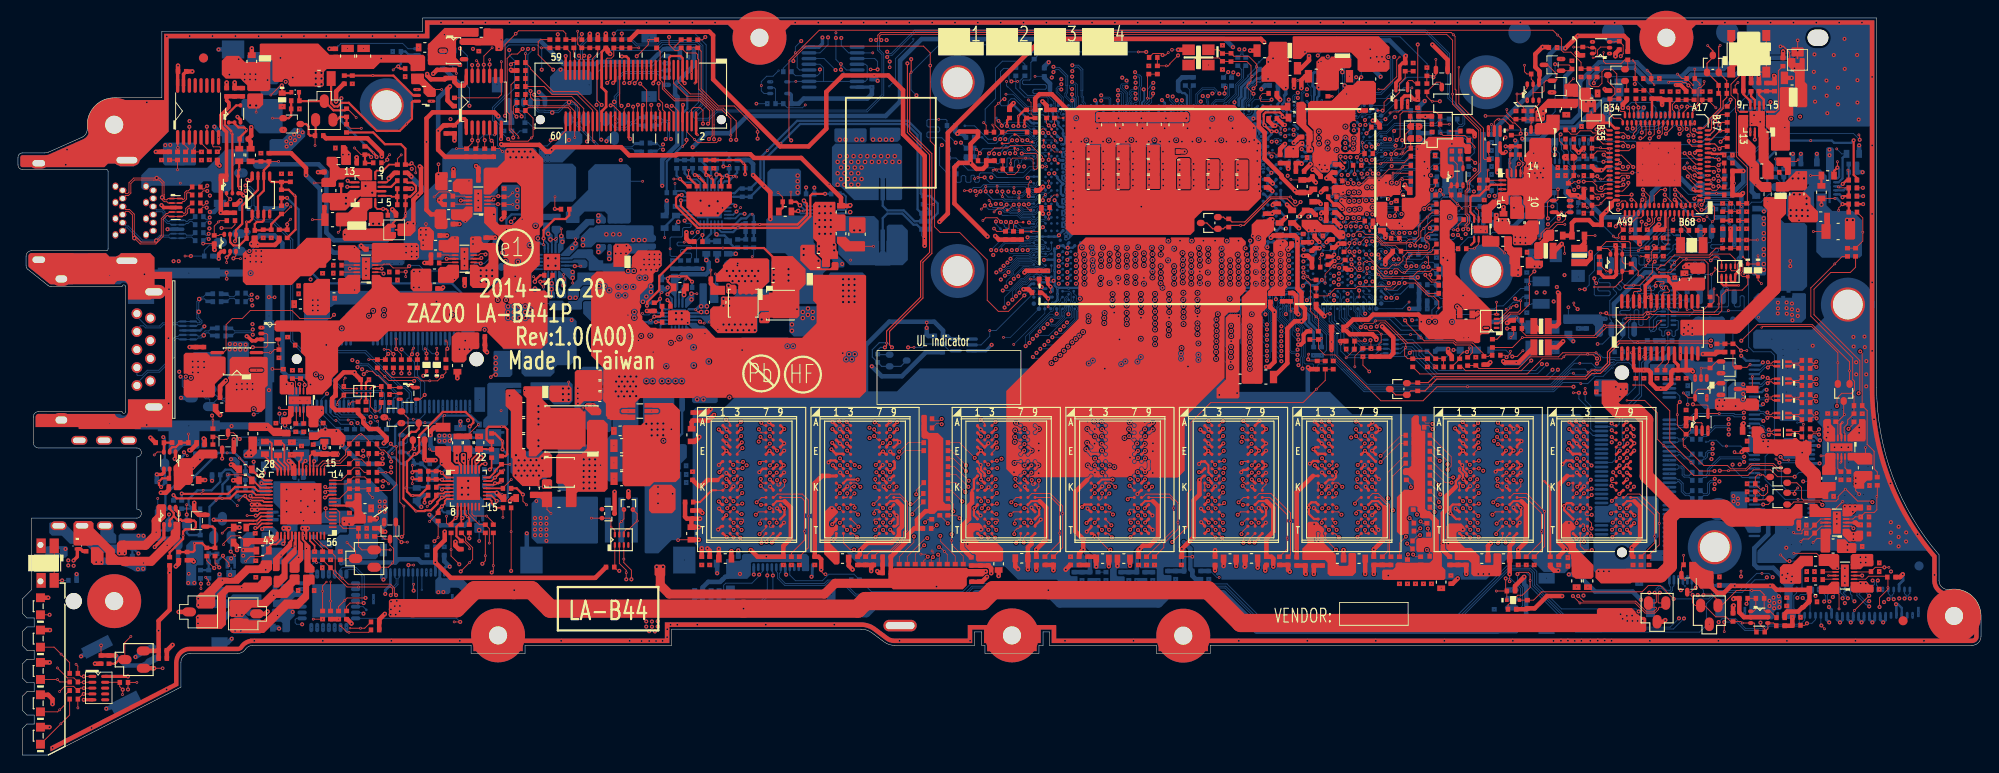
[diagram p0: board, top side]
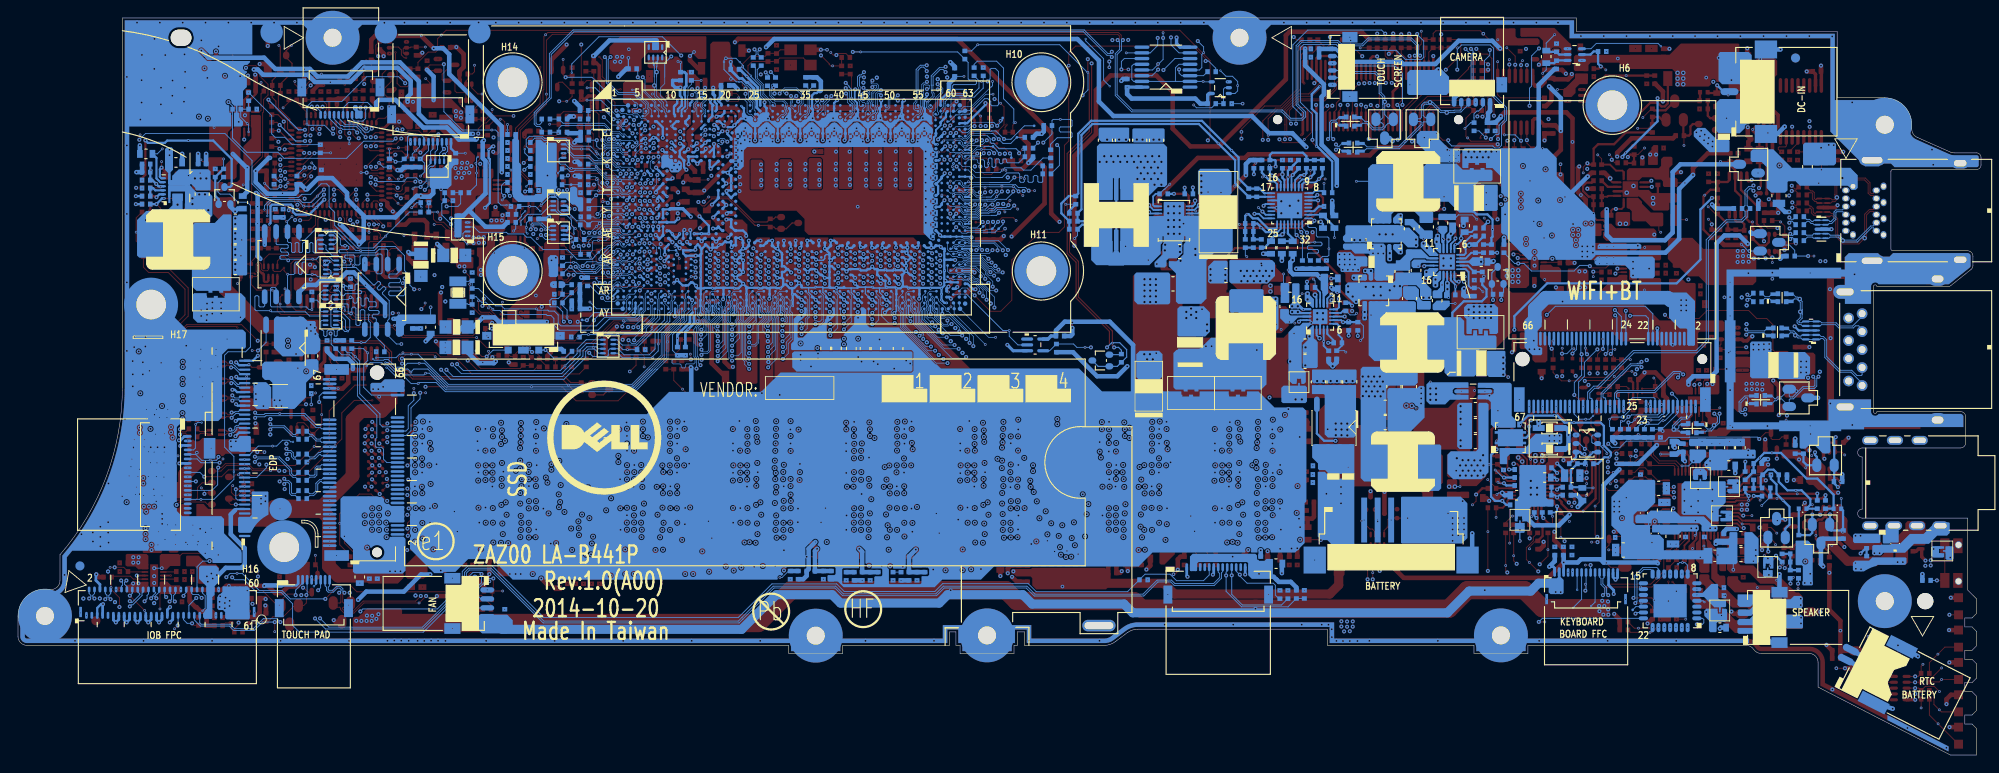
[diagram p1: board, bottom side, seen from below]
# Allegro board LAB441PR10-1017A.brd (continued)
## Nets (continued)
+1.05V_M: C219.1 CH1222.1 CH1223.1 PR319.2 R307.2 R309.2 RH39.1 RH40.1 RH445.1 UCPU1.AE9 UCPU1.AF9 UCPU1.AG8 UCPU1.AG13 UCPU1.AG14
+1.05V_PCH: C1224.1 C1228.1 C1243.1 L63.2 PJP500.2 Q360.5 R309.1 R1332.1 RH405.1 RH407.2 RH408.1 U34.1 U34.2 U673.4 U673.5 U673.9 U673.10 U673.11 U673.12 U673.13 U673.14 U673.18 U673.19
+1.05VDX_MODPHY: C1209.1 LH10.1 LH11.1 R300.1 R1240.1 R1330.2
+1.05VDX_MODPHY_D: Q39.1 R300.2
+1.05VS: C1240.1 CE50.1 CH1.1 CH39.1 CH1215.1 CH1216.1 CH1217.1 CH1233.1 CH1234.1 CH1235.1 JXDP.43 JXDP.44 LH12.1 R1331.1 R1332.2 RE70.1 RH340.1 RH355.1 RH356.1 UCPU1.AE8 UCPU1.AF22 UCPU1.AG16 UCPU1.AG17 UCPU1.H11 UCPU1.H15 UCPU1.J11 UCPU1.J17 UCPU1.N8 UCPU1.P9 UCPU1.R21 UCPU1.T21 UE5.B51
+1.5VS: PJP400.2 UCPU1.J15
+1.05VS_VCCST: CH1204.1 CH1205.1 PC717.1 PR723.1 PR726.1 PR727.1 R1132.1 R1179.1 R1371.1 RC43.1 RC48.1 RC93.2 RC149.2 RH4.1 RH340.2 UCPU1.AC22 UCPU1.AE22 UCPU1.AE23
+1.5VSP: PC402.1 PC403.1 PJP400.1 PL401.2 PR401.1 PR412.2 PU400.14
+1.05VSP: PC509.1 PC510.1 PC511.1 PC512.1 PC515.1 PJP500.1 PL501.2 PR505.1
+1.8VS: C1169.1 PJP401.2 RH350.2 U664.6 U664.7
+1.8VS_AUDIO: C1217.1 R1125.2 RA83.1
+1.8VSP: PC410.1 PC411.1 PJP401.1 PL403.2 PR406.1 PR413.2 PU401.14
+1.35V_DDR: CC160.1 CC161.1 CC162.1 CC163.1 CC164.1 CC165.1 CC233.1 CC234.1 CC238.1 CC239.1 CC240.1 CD40.1 CD41.1 CD42.1 CD44.1 CD45.1 CD46.1 CD47.1 CD50.1 CD54.1 CD55.1 CD56.1 CD57.1 CD58.1 CD59.1 CD60.1 CD61.1 CD66.1 CD67.1 CD68.1 CD69.1 CD70.1 CD71.1 CD72.1 CD73.1 CD79.1 CD80.1 CD81.1 CD82.1 CD83.1 CD84.1 CD86.1 CD92.1 PC609.1 PJP600.2 PJP601.2 RD13.1 RD14.1 RD24.2 RD34.1 RD92.2 RD95.2 UC1.5 UCPU1.AH26 UCPU1.AJ31 UCPU1.AJ33 UCPU1.AJ37 UCPU1.AN33 UCPU1.AP43 UCPU1.AR48 UCPU1.AY35 UCPU1.AY40 UCPU1.AY44 UCPU1.AY50 UD1.A1 UD1.A8 UD1.B2 UD1.C1 UD1.C9 UD1.D2 UD1.D9 UD1.E9 UD1.F1 UD1.G7 UD1.H2 UD1.H9 UD1.K2 UD1.K8 UD1.N1 UD1.N9 UD1.R1 UD1.R9 UD3.A1 UD3.A8 UD3.B2 UD3.C1 UD3.C9 UD3.D2 UD3.D9 UD3.E9 UD3.F1 UD3.G7 UD3.H2 UD3.H9 UD3.K2 UD3.K8 UD3.N1 UD3.N9 UD3.R1 UD3.R9 UD4.A1 UD4.A8 UD4.B2 UD4.C1 UD4.C9 UD4.D2 UD4.D9 UD4.E9 UD4.F1 UD4.G7 UD4.H2 UD4.H9 UD4.K2 UD4.K8 UD4.N1 UD4.N9 UD4.R1 UD4.R9 UD7.A1 UD7.A8 UD7.B2 UD7.C1 UD7.C9 UD7.D2 UD7.D9 UD7.E9 UD7.F1 UD7.G7 UD7.H2 UD7.H9 UD7.K2 UD7.K8 UD7.N1 UD7.N9 UD7.R1 UD7.R9 UD28.A1 UD28.A8 UD28.B2 UD28.C1 UD28.C9 UD28.D2 UD28.D9 UD28.E9 UD28.F1 UD28.G7 UD28.H2 UD28.H9 UD28.K2 UD28.K8 UD28.N1 UD28.N9 UD28.R1 UD28.R9 UD29.A1 UD29.A8 UD29.B2 UD29.C1 UD29.C9 UD29.D2 UD29.D9 UD29.E9 UD29.F1 UD29.G7 UD29.H2 UD29.H9 UD29.K2 UD29.K8 UD29.N1 UD29.N9 UD29.R1 UD29.R9 UD31.A1 UD31.A8 UD31.B2 UD31.C1 UD31.C9 UD31.D2 UD31.D9 UD31.E9 UD31.F1 UD31.G7 UD31.H2 UD31.H9 UD31.K2 UD31.K8 UD31.N1 UD31.N9 UD31.R1 UD31.R9 UD32.A1 UD32.A8 UD32.B2 UD32.C1 UD32.C9 UD32.D2 UD32.D9 UD32.E9 UD32.F1 UD32.G7 UD32.H2 UD32.H9 UD32.K2 UD32.K8 UD32.N1 UD32.N9 UD32.R1 UD32.R9
+1.35VP: PC617.1 PJP600.1 PJP601.1 PL601.2 PR605.2 PU600.5 PU600.19
+3.3V_ALW_DEG: JDEG1.1 RE76.2
+3.3V_M: C1219.1 CH47.1 R1322.2 R1393.1 RH55.1 RH57.1 RH3527.1 UCPU1.Y8
+3.3VDX_SSD: C719.1 C720.1 C721.1 C722.1 C1164.1 C1304.1 JNGFF3.2 JNGFF3.4 JNGFF3.12 JNGFF3.14 JNGFF3.16 JNGFF3.18 JNGFF3.62 JNGFF3.64 JNGFF3.66 R1326.2 R1376.1 R1377.2
+3V_NFC: C1134.1 JNFC1.2 JNFC1.3 JNFC1.15 R973.1 R1242.2
+3V_PCH: C1161.1 CH1220.1 CH1236.1 JAPS.1 PR510.1 R1242.1 R1312.1 R1324.1 R1342.2 RH70.2 RH72.2 RH154.2 RH197.2 RH270.2 RH294.2 RH302.2 RH341.1 RH382.2 RH465.2 RH3533.2 RH3535.2 RH3536.2 RH3537.2 RH3538.2 RH3541.2 RH3542.2 RH3546.2 RP2.5 RP2.6 RP2.7 RP2.8 RP16.5 RP16.6 RP16.7 RP21.5 RP21.6 RP21.7 RP21.8 U663.16 U697.5 UCPU1.AA9 UCPU1.AC9 UCPU1.AE20 UCPU1.AE21
+3V_PCH_DSW: C1.2 CH1224.1 RH12.1 RH146.2 RH348.2 RP20.5 RP20.6 UCPU1.AH10
+3V_ROM: CH6.1 CH7.1 CH1245.1 CH1249.1 RH3527.2 U48.8 U727.8
+3VALW: C375.1 C1158.1 C1160.1 C1162.1 C1165.1 C1166.1 C1203.1 C1204.1 C1213.1 C1231.1 C1254.1 C1256.1 C1289.1 C1322.1 CE4.1 CE42.1 JAPS.3 JAPS.7 JIO1.49 JKB1.3 PC428.1 PC429.1 PC433.1 PC434.1 PC514.1 PJP14.1 PJP15.1 PJP301.2 PR100.1 PR102.2 PR111.1 PR448.1 PR450.1 PR455.1 PR460.1 PR504.1 PR506.1 PU404.8 PU405.5 PU406.5 PU500.7 RC161.1 RE84.1 RH348.1 U664.1 U664.2 U672.5 U699.5 U715.1 U715.2 U715.6 U715.7 U716.1 U716.2 U716.6 U716.7 U717.1 U717.2 U717.6 U717.7 U718.1 U718.2 U718.6 U718.7 U720.1 U720.2 U720.6 U720.7
+3VALW_5085: CE14.1 CE17.1 CE38.1 CE40.1 CE41.1 CE43.1 CE44.1 CE46.1 CE63.1 CE64.1 PJP15.2 RE25.1 RE52.1 RE53.1 RE55.2 RE56.2 RE65.1 RE67.2 RE69.1 RE71.2 RE72.1 RE73.2 RE74.1 RE75.1 RE76.1 RE79.2 RE81.1 RE86.2 RPE5.7 RPE5.8 RPE7.5 RPE7.6 RPE7.7 RPE7.8 UE5.A11 UE5.A22 UE5.A26 UE5.A41 UE5.A52 UE5.A58 UE5.B3 UE5.B35
+3VALW_23017: CE3.1 CE10.1 PJP14.2 RE13.1 RE14.1 RE24.1 RE27.1 UE4.5
+3VALWP: PC307.1 PJP301.1 PL301.2 PR300.1 PR311.1
+3VLP: D122.2 PC300.1 PU300.3 RE57.2 UC6.5
+3VS: C377.1 C1216.1 C1283.1 C1285.1 C1300.1 C1324.1 CH1225.1 CH1226.1 CS44.1 JEDP.40 JIO1.50 JKB1.4 JLPDE1.1 JLPDE1.2 PR404.2 PR409.2 PR604.1 PR713.2 PR715.2 PU700.20 QH6.2 QH6.5 QH7.2 QH7.5 R3.1 R220.1 R884.2 R1103.2 R1141.2 R1178.2 R1185.2 R1311.1 R1329.2 R1396.2 RE83.1 RE87.2 RE88.2 RH3.2 RH5.2 RH29.2 RH35.1 RH37.1 RH91.1 RH95.1 RH100.1 RH103.1 RH107.1 RH110.1 RH180.2 RH196.2 RH198.2 RH199.2 RH200.2 RH248.1 RH271.2 RH303.2 RH354.2 RH367.1 RH383.2 RH392.1 RH393.2 RH397.1 RH424.2 RH425.2 RH440.2 RH441.2 RH457.2 RH458.2 RH459.2 RH460.2 RH466.2 RH467.2 RH3532.1 RH3534.2 RH3539.2 RH3540.2 RH3543.2 RH3545.1 RH3547.1 RH3548.2 RP4.1 RP4.2 RP4.3 RP4.4 RP14.2 RP14.3 RP20.8 RV2.2 U671.14 U675.5 U679.B2 U682.5 U683.5 U726.1 UCPU1.K14 UCPU1.K16 UCPU1.V8 UCPU1.W9 UH5.5
+3VS_AUDIO: C1218.1 CH85.1 LA14.1 R1318.2 RA14.1 RA18.1 RA19.1 RA37.1 RA38.1 RA80.2 RC9.1 RH42.1 UCPU1.AH14
+3VS_CAM: C4.1 C1220.1 C1221.1 JCAM.1 R2670.2
+3VS_CR: C1264.1 C1325.1 JEDP.7 JIO1.45 JIO1.46 JIO1.47 JIO1.48 R1343.2
+3VS_NGFF: C712.1 C713.1 C715.1 C716.1 C1215.1 C1297.1 C1298.1 JNGFF1.2 JNGFF1.4 JNGFF1.64 JNGFF1.66 R1344.2
+3VS_TP: C7.1 C1159.1 C1225.1 JTP1.1 Q40.2 R1104.2 R1105.2 R1299.1 R1323.2 RE6.1 RE7.1
+3VS_TPM: C723.1 C1137.1 C1138.1 C1139.1 C1140.1 C1141.1 C1142.1 R1393.2 U652.3 U652.10 U652.12 U652.19 U652.24
+3VS_TS: C8.1 C1208.1 R2671.2 RH357.1 U728.1 U728.3
+3VS_TSLDO: C5.1 C1222.1 C1223.1 JTS.6 RH357.2 U728.5
+5V_USB_P1: C3.1 C265.1 C303.1 JUSB1.1 US2.6 US2.7 US2.8
+5VALW: C2.1 C376.1 C962.1 C963.1 C1199.1 C1201.1 C1241.1 C1321.1 JIO1.52 JIO1.53 JIO1.54 JIO1.55 JIO1.56 JIO1.57 JIO1.58 JIO1.59 JIO1.60 JIO1.61 JKB1.1 LED10.2 LED11.2 LED12.2 LED13.2 LED14.2 PC607.2 PJP300.2 PR105.2 PR603.1 PR721.1 PU600.12 RA81.1 RP13.5 RP13.10 U34.4 U664.4 U673.2 U715.4 U716.4 U717.4 U718.4 U719.1 U719.2 U719.4 U719.6 U719.7 U720.4 US2.2 US2.3
+5VALWP: PC308.1 PJP300.1 PL304.2 PR301.1 PU300.14
+5VS: C352.1 C1102.2 CV13.1 JFAN1.4 JKB1.2 PC710.2 PU701.2 QC5.2 QV2.2 R886.2 R2669.2 UV1.16
+5VS_AUDIO: C1200.1 CA4.1 CA5.1 CA97.1 CA98.1 LA1.2 LA2.2 LA3.1 R1320.2
+AVDD1: CA101.1 CA102.1 CA103.1 LA3.2 UA2.45
+AVDD2: CA78.1 CA80.1 CA82.1 CA83.1 RA83.2 RA84.2 UA2.23 UA2.24
+DVDD: CA31.1 CA42.1 LA14.2 RA76.1 RA85.1 RA87.1 UA2.7
+DVDDIO: CA104.1 CA105.1 RA80.1 UA2.19
+PVDD1: CA2.1 CA3.1 LA1.1 UA2.46
+PVDD2: CA99.1 CA100.1 LA2.1 UA2.51
+V1.05A_AOSCSUS: CH61.1 CH1232.1 L63.1 UCPU1.AB8
+V1.05A_DCPSUS1: CH1219.1 RH407.1 UCPU1.AD8 UCPU1.AD10
+V1.05A_DCPSUS2: CH1221.1 RH408.2 UCPU1.AH13
+V1.05A_DCPSUS3: CH1214.1 CH1239.1 RH405.2 UCPU1.J13
+V1.05S_APLLOPI: CH36.1 CH1213.1 LH12.2 UCPU1.AA21 UCPU1.W21
+V1.05S_ASATA3PLL: C1314.1 C1315.1 CH1248.1 LH11.2 RH43.2 UCPU1.A12 UCPU1.B11
+V1.05S_AUSB3PLL: C1312.1 C1313.1 CH1247.1 LH10.2 RH338.1 UCPU1.B18 UCPU1.B27
+V1.05S_AXCK_DCB: CH62.1 CH1229.1 L61.2 UCPU1.J18 UCPU1.K19
+V1.05S_AXCK_DCB_L: L61.1 RH355.2
+V1.05S_AXCK_LCPLL: CH65.1 CH1231.1 L62.2 RH113.2 UCPU1.A20
+V1.05S_AXCK_LCPLL_L: L62.1 RH356.2
+V1.05VS_VCCHSIO: CH40.1 CH41.1 R1240.2 UCPU1.K9 UCPU1.L10 UCPU1.M9
+VCC_CORE: PC800.1 PC801.1 PC802.1 PC803.1 PC804.1 PC805.1 PC806.1 PC807.1 PC808.1 PC809.1 PC810.1 PC811.1 PC812.1 PC813.1 PC814.1 PC815.1 PC816.1 PC817.1 PC818.1 PC819.1 PC820.1 PC821.1 PC822.1 PC823.1 PL701.4 RC97.1 UCPU1.AB57 UCPU1.AD57 UCPU1.AG57 UCPU1.C24 UCPU1.C28 UCPU1.C32 UCPU1.C36 UCPU1.C40 UCPU1.C44 UCPU1.C48 UCPU1.C52 UCPU1.C56 UCPU1.E23 UCPU1.E25 UCPU1.E27 UCPU1.E29 UCPU1.E31 UCPU1.E33 UCPU1.E35 UCPU1.E37 UCPU1.E39 UCPU1.E41 UCPU1.E43 UCPU1.E45 UCPU1.E47 UCPU1.E49 UCPU1.E51 UCPU1.E53 UCPU1.E55 UCPU1.E57 UCPU1.F24 UCPU1.F28 UCPU1.F32 UCPU1.F36 UCPU1.F40 UCPU1.F44 UCPU1.F48 UCPU1.F52 UCPU1.F56 UCPU1.F59 UCPU1.G23 UCPU1.G25 UCPU1.G27 UCPU1.G29 UCPU1.G31 UCPU1.G33 UCPU1.G35 UCPU1.G37 UCPU1.G39 UCPU1.G41 UCPU1.G43 UCPU1.G45 UCPU1.G47 UCPU1.G49 UCPU1.G51 UCPU1.G53 UCPU1.G55 UCPU1.G57 UCPU1.H23 UCPU1.J23 UCPU1.K23 UCPU1.K57 UCPU1.L22 UCPU1.M23 UCPU1.M57 UCPU1.P57 UCPU1.U57 UCPU1.W57
+VCCIO_OUT: CH1241.1 UCPU1.A59
+VCCIOA_OUT: RC36.2 UCPU1.E20
AGND: CA40.2 CA74.2 CA78.2 CA80.2 CA82.2 CA83.2 CA84.2 CA85.2 CA86.2 CA87.2 CA88.2 CA90.2 CA91.2 CA92.2 CA93.2 CA94.2 CA101.2 CA102.2 CA103.2 JPA1.1 JPA2.1 JPA3.1 JPA4.1 JPA5.1 QA1.1 QA1.4 QA3.1 QA3.4 QA6.3 QA9.3 RA20.2 RA35.2 RA60.2 RA61.2 UA2.20 UA2.30 UA2.42
GND: C2.2 C3.2 C4.2 C5.2 C6.2 C7.2 C8.2 C218.2 C219.2 C265.2 C303.2 C352.2 C355.2 C375.2 C376.2 C377.2 C612.2 C712.2 C713.2 C715.2 C716.2 C719.2 C720.2 C721.2 C722.2 C723.2 C962.2 C963.2 C1102.1 C1134.2 C1137.2 C1138.2 C1139.2 C1140.2 C1141.2 C1142.2 C1143.2 C1145.2 C1158.2 C1159.2 C1160.2 C1161.2 C1162.2 C1163.2 C1164.2 C1165.2 C1166.2 C1167.2 C1169.2 C1199.2 C1200.2 C1201.2 C1202.2 C1203.2 C1204.2 C1208.2 C1209.2 C1211.2 C1212.2 C1213.2 C1214.2 C1215.2 C1216.2 C1217.2 C1218.2 C1219.2 C1220.2 C1221.2 C1222.2 C1223.2 C1224.2 C1225.2 C1227.2 C1228.2 C1230.2 C1231.2 C1237.2 C1240.2 C1241.2 C1242.2 C1243.2 C1247.2 C1254.2 C1256.2 C1257.2 C1258.2 C1264.2 C1273.2 C1274.2 C1275.2 C1278.2 C1281.2 C1282.2 C1283.2 C1284.2 C1285.2 C1286.2 C1289.2 C1292.2 C1293.2 C1297.2 C1298.2 C1299.2 C1300.2 C1301.2 C1302.2 C1304.2 C1309.2 C1312.2 C1313.2 C1314.2 C1315.2 C1321.2 C1322.2 C1324.2 C1325.2 C2973.2 C2982.2 C2983.2 C2985.2 CA2.2 CA3.2 CA4.2 CA5.2 CA23.1 CA24.1 CA25.1 CA26.1 CA27.1 CA28.2 CA29.1 CA31.2 CA33.2 CA42.2 CA48.2 CA49.2 CA53.1 CA54.1 CA55.1 CA56.1 CA57.2 CA68.1 CA69.2 CA97.2 CA98.2 CA99.2 CA100.2 CA104.2 CA105.2 CA106.2 CC160.2 CC161.2 CC162.2 CC163.2 CC164.2 CC165.2 CC233.2 CC234.2 CC238.2 CC239.2 CC240.2 CC243.2 CD5.2 CD35.2 CD37.2 CD40.2 CD41.2 CD42.2 CD44.2 CD45.2 CD46.2 CD47.2 CD50.2 CD51.2 CD52.2 CD54.2 CD55.2 CD56.2 CD57.2 CD58.2 CD59.2 CD60.2 CD61.2 CD66.2 CD67.2 CD68.2 CD69.2 CD70.2 CD71.2 CD72.2 CD73.2 CD77.2 CD78.2 CD79.2 CD80.2 CD81.2 CD82.2 CD83.2 CD84.2 CD85.2 CD86.2 CD87.2 CD88.2 CD89.2 CD90.2 CD91.2 CD92.2 CD93.2 CD94.2 CD95.2 CD96.2 CD101.2 CD129.2 CD132.2 CD133.2 CD135.2 CD136.2 CD139.2 CD140.2 CD142.2 CD143.2 CD144.2 CE3.2 CE4.2 CE10.2 CE13.2 CE14.2 CE17.2 CE21.2 CE22.2 CE38.2 CE40.2 CE41.2 CE42.2 CE43.2 CE44.2 CE45.2 CE46.2 CE49.2 CE50.2 CE52.2 CE53.2 CE54.2 CE55.2 CE56.2 CE59.2 CE61.2 CE62.2 CE63.2 CE64.2 CE65.2 CE68.2 CH1.2 CH2.2 CH3.2 CH4.2 CH5.2 CH6.2 CH7.2 CH23.2 CH24.2 CH36.2 CH39.2 CH40.2 CH41.2 CH47.2 CH61.2 CH62.2 CH65.2 CH82.2 CH83.2 CH84.2 CH85.2 CH95.2 CH102.1 CH1204.2 CH1205.2 CH1206.2 CH1207.2 CH1213.2 CH1214.2 CH1215.2 CH1216.2 CH1217.2 CH1218.2 CH1219.2 CH1220.2 CH1221.2 CH1222.2 CH1223.2 CH1224.2 CH1225.2 CH1226.2 CH1227.2 CH1229.2 CH1231.2 CH1232.2 CH1233.2 CH1234.2 CH1235.2 CH1236.2 CH1239.2 CH1241.2 CH1242.2 CH1243.2 CH1244.2 CH1245.2 CH1246.2 CH1247.2 CH1248.2 CH1249.2 CLRP1.2 CS44.2 CV1.2 CV2.2 CV13.2 CV14.2 CV15.2 CV798.2 DA1.1 DA2.1 DA3.1 DA4.1 DA5.2 DA7.2 DI1.3 DI1.8 DI2.1 DI3.1 DI4.1 H1.1(TP-1) H4.1(TP-1) H6.1(TP-1) H7.1(TP-1) H9.1(TP-1) H10.1(TP-1) H11.1(TP-1) H12.1(TP-1) H13.1(TP-1) H14.1(TP-1) H15.1(TP-1) H16.1(TP-1) H17.1(TP-1) H18.1(TP-1) H19.1(TP-1) H20.1 H21.1 H22.1 H24.1 H25.1 JAPS.8 JAPS.10 JAPS.12 JAPS.14 JAPS.19 JAPS.20 JBATT1.6 JBATT1.7 JBATT1.8 JBATT1.9 JBATT1.10 JBATT1.11 JCAM.3 JCAM.6 JCAM.7 JCAM.8 JDEG1.10 JDEG1.11 JDEG1.12 JEDP.10 JEDP.11 JEDP.12 JEDP.13 JEDP.15 JEDP.16 JEDP.17 JEDP.18 JEDP.24 JEDP.27 JEDP.30 JEDP.33 JEDP.36 JEDP.39 JEDP.41 JEDP.42 JEDP.43 JEDP.44 JEDP.45 JFAN1.1 JFAN1.5 JFAN1.6 JHP1.7 JIO1.1 JIO1.5 JIO1.6 JIO1.7 JIO1.11 JIO1.12 JIO1.13 JIO1.15 JIO1.17 JIO1.19 JIO1.21 JIO1.23 JIO1.25 JIO1.27 JIO1.29 JIO1.31 JIO1.33 JIO1.62 JIO1.63 JKB1.13 JKB1.14 JKB1.15 JKB1.16 JKB1.17 JLPDE1.9 JLPDE1.11 JLPDE1.12 JMDP.1 JMDP.7 JMDP.8 JMDP.13 JMDP.14 JMDP.19 JMDP.21 JMDP.22 JMDP.23 JMDP.24 JNFC1.1 JNFC1.7 JNFC1.14 JNFC1.16 JNFC1.17 JNGFF1.1 JNGFF1.7 JNGFF1.18 JNGFF1.25 JNGFF1.31 JNGFF1.37 JNGFF1.43 JNGFF1.49 JNGFF1.55 JNGFF1.61 JNGFF1.67 JNGFF1.68 JNGFF1.69 JNGFF3.1 JNGFF3.3 JNGFF3.9 JNGFF3.15 JNGFF3.21 JNGFF3.27 JNGFF3.33 JNGFF3.39 JNGFF3.45 JNGFF3.51 JNGFF3.57 JNGFF3.63 JNGFF3.65 JNGFF3.67 JNGFF3.68 JNGFF3.69 JP100.6 JP100.7 JPA1.2 JPA2.2 JPA3.2 JPA4.2 JPA5.2 JRTC1.2 JRTC1.3 JRTC1.4 JSPK1.5 JSPK1.6 JTAG1.2 JTP1.4 JTP1.9 JTP1.10 JTS.1 JTS.4 JTS.7 JTS.8 JUSB1.4 JUSB1.7 JUSB1.10 JUSB1.11 JUSB1.12 JUSB1.13 JXDP.1 JXDP.2 JXDP.7 JXDP.8 JXDP.13 JXDP.14 JXDP.19 JXDP.20 JXDP.25 JXDP.26 JXDP.31 JXDP.32 JXDP.37 JXDP.38 JXDP.49 JXDP.50 JXDP.59 MC3.2 MC29.1 MC30.2 MC31.2 MC32.2 MC33.2 MD5.3 MD9.1 MD10.1 MD16.3 PC100.2 PC101.2 PC102.1 PC103.2 PC106.2 PC107.2 PC108.2 PC110.2 PC205.2 PC206.2 PC208.2 PC209.2 PC211.2 PC212.2 PC213.2 PC214.2 PC215.2 PC219.2 PC220.2 PC221.2 PC222.2 PC224.2 PC228.2 PC229.2 PC230.2 PC231.2 PC232.2 PC233.2 PC234.2 PC235.2 PC236.2 PC237.2 PC300.2 PC302.2 PC303.2 PC307.2 PC308.2 PC309.2 PC310.2 PC311.2 PC312.2 PC313.2 PC314.2 PC315.2 PC323.2 PC324.1 PC400.2 PC401.2 PC403.2 PC404.2 PC405.2 PC406.2 PC407.2 PC408.2 PC409.2 PC411.2 PC412.2 PC413.2 PC414.2 PC415.2 PC428.2 PC429.2 PC433.2 PC434.2 PC500.2 PC502.2 PC503.2 PC504.2 PC506.2 PC507.2 PC509.2 PC510.2 PC511.2 PC512.2 PC513.2 PC514.2 PC600.2 PC601.2 PC602.2 PC603.2 PC605.2 PC606.2 PC607.1 PC609.2 PC610.2 PC611.2 PC612.2 PC613.2 PC614.2 PC617.2 PC700.2 PC701.2 PC702.2 PC703.2 PC704.2 PC705.2 PC706.2 PC708.2 PC710.1 PC711.2 PC713.2 PC714.2 PC717.2 PC718.2 PC800.2 PC801.2 PC802.2 PC803.2 PC804.2 PC805.2 PC806.2 PC807.2 PC808.2 PC809.2 PC810.2 PC811.2 PC812.2 PC813.2 PC814.2 PC815.2 PC816.2 PC817.2 PC818.2 PC819.2 PC820.2 PC821.2 PC822.2 PC823.2 PD100.1 PD101.1 PD102.2 PJP200.2 PL104.2 PQ101.3 PQ102.1 PQ102.4 PQ103.1 PQ103.4 PQ202.6 PQ205.1 PQ205.2 PQ205.3 PQ300.8 PQ301.8 PQ409.1 PQ500.3 PQ601.1 PQ601.2 PQ601.3 PR106.1 PR107.2 PR112.2 PR113.2 PR116.2 PR302.1 PR303.2 PR304.1 PR305.1 PR306.2 PR403.2 PR408.2 PR451.2 PR452.2 PR456.2 PR458.2 PR501.2 PR507.2 PR508.2 PR607.2 PR705.2 PR706.2 PR707.2 PR708.2 PR709.2 PR710.2 PR731.2 PU200.22 PU300.21 PU400.6 PU400.8 PU400.15 PU400.16 PU400.17 PU401.6 PU401.8 PU401.15 PU401.16 PU401.17 PU404.4 PU405.3 PU406.3 PU500.9 PU600.1 PU600.3 PU600.14 PU600.21 PU700.19 PU700.29 PU700.33 PU701.3 PU701.9 Q39.3 Q71.3 Q305.3 Q361.1 Q362.3 QA8.3 QE12.1 QE12.4 R7.2 R8.1 R9.1 R290.1 R540.2 R545.2 R974.2 R1026.1 R1100.1 R1140.2 R1142.2 R1161.2 R1162.2 R1163.2 R1169.2 R1175.1 R1176.2 R1177.2 R1181.2 R1186.1 R1187.1 R1203.2 R1216.2 R1228.2 R1325.2 R1395.1 RA30.2 RA41.2 RA82.1 RC44.1 RC52.1 RC54.1 RC55.1 RC58.1 RC60.1 RC81.2 RC100.2 RC153.2 RC154.2 RC155.2 RC156.2 RC158.1 RC160.2 RD11.2 RD12.2 RD16.2 RD17.2 RD18.2 RD19.2 RD29.2 RD30.2 RD31.2 RD32.2 RD39.2 RD40.2 RD41.2 RD42.2 RD51.2 RD52.2 RD53.2 RD54.2 RD55.2 RD56.2 RD119.2 RD120.2 RE2.1 RE22.1 RE23.1 RE54.1 RE58.1 RE59.2 RE60.2 RE63.2 RE66.2 RE68.2 RE77.2 RE78.2 RE82.1 RE85.2 RH34.2 RH36.1 RH41.1 RH44.1 RH45.1 RH159.1 RH163.2 RH171.2 RH183.1 RH300.1 RH314.1 RH315.1 RH316.1 RH394.1 RH395.1 RH400.2 RH401.2 RH423.2 RH435.2 RH442.2 RH443.2 RH3530.2 RH3531.2 RH3544.1 RH3549.2 RV3.2 RV4.2 RV9.2 RV10.2 SW2.1 SW2.3 SW3.3 SW3.4 SW4.4 SW4.5 U34.5 U34.9 U48.4 U652.1 U652.2 U652.4 U652.11 U652.17 U652.18 U652.25 U663.8 U664.11 U664.15 U671.7 U672.3 U673.3 U675.3 U679.B1 U682.3 U683.3 U697.3 U699.3 U708.3 U715.11 U715.15 U716.11 U716.15 U717.11 U717.15 U718.11 U718.15 U719.11 U719.15 U720.11 U720.15 U726.2 U727.4 U728.2 UA2.10 UA2.57 UC1.3 UC6.3 UCPU1.A11 UCPU1.A14 UCPU1.A18 UCPU1.A24 UCPU1.A28 UCPU1.A32 UCPU1.A36 UCPU1.A40 UCPU1.A44 UCPU1.A48 UCPU1.A52 UCPU1.A56 UCPU1.AA1 UCPU1.AA58 UCPU1.AB7 UCPU1.AB10 UCPU1.AB20 UCPU1.AB22 UCPU1.AC61 UCPU1.AD3 UCPU1.AD21 UCPU1.AD63 UCPU1.AE5 UCPU1.AE10 UCPU1.AE58 UCPU1.AF11 UCPU1.AF12 UCPU1.AF14 UCPU1.AF15 UCPU1.AF17 UCPU1.AF18 UCPU1.AG1 UCPU1.AG11 UCPU1.AG21 UCPU1.AG23 UCPU1.AG60 UCPU1.AG61 UCPU1.AG62 UCPU1.AG63 UCPU1.AH16 UCPU1.AH17 UCPU1.AH19 UCPU1.AH20 UCPU1.AH22 UCPU1.AH24 UCPU1.AH28 UCPU1.AH30 UCPU1.AH32 UCPU1.AH34 UCPU1.AH36 UCPU1.AH38 UCPU1.AH40 UCPU1.AH42 UCPU1.AH44 UCPU1.AH46 UCPU1.AH49 UCPU1.AH51 UCPU1.AH53 UCPU1.AH55 UCPU1.AH57 UCPU1.AJ13 UCPU1.AJ14 UCPU1.AJ23 UCPU1.AJ25 UCPU1.AJ27 UCPU1.AJ29 UCPU1.AJ35 UCPU1.AJ39 UCPU1.AJ41 UCPU1.AJ43 UCPU1.AJ45 UCPU1.AJ47 UCPU1.AJ50 UCPU1.AJ52 UCPU1.AJ54 UCPU1.AJ56 UCPU1.AJ58 UCPU1.AJ60 UCPU1.AJ63 UCPU1.AK3 UCPU1.AK23 UCPU1.AK52 UCPU1.AL10 UCPU1.AL13 UCPU1.AL17 UCPU1.AL20 UCPU1.AL22 UCPU1.AL23 UCPU1.AL26 UCPU1.AL29 UCPU1.AL31 UCPU1.AL33 UCPU1.AL36 UCPU1.AL39 UCPU1.AL40 UCPU1.AL45 UCPU1.AL46 UCPU1.AL51 UCPU1.AL52 UCPU1.AL54 UCPU1.AL57 UCPU1.AL60 UCPU1.AL61 UCPU1.AM1 UCPU1.AM17 UCPU1.AM23 UCPU1.AM31 UCPU1.AM52 UCPU1.AN7 UCPU1.AN17 UCPU1.AN23 UCPU1.AN31 UCPU1.AN32 UCPU1.AN35 UCPU1.AN36 UCPU1.AN39 UCPU1.AN40 UCPU1.AN42 UCPU1.AN43 UCPU1.AN45 UCPU1.AN46 UCPU1.AN48 UCPU1.AN49 UCPU1.AN51 UCPU1.AN52 UCPU1.AN60 UCPU1.AN63 UCPU1.AP3 UCPU1.AP10 UCPU1.AP17 UCPU1.AP20 UCPU1.AP22 UCPU1.AP23 UCPU1.AP26 UCPU1.AP29 UCPU1.AP31 UCPU1.AP38 UCPU1.AP39 UCPU1.AP48 UCPU1.AP52 UCPU1.AP54 UCPU1.AP57 UCPU1.AR5 UCPU1.AR11 UCPU1.AR15 UCPU1.AR17 UCPU1.AR23 UCPU1.AR31 UCPU1.AR33 UCPU1.AR39 UCPU1.AR43 UCPU1.AR49 UCPU1.AR52 UCPU1.AT13 UCPU1.AT35 UCPU1.AT37 UCPU1.AT40 UCPU1.AT42 UCPU1.AT43 UCPU1.AT46 UCPU1.AT49 UCPU1.AT61 UCPU1.AT62 UCPU1.AT63 UCPU1.AU1 UCPU1.AU16 UCPU1.AU18 UCPU1.AU20 UCPU1.AU22 UCPU1.AU24 UCPU1.AU26 UCPU1.AU28 UCPU1.AU30 UCPU1.AU33 UCPU1.AU51 UCPU1.AU53 UCPU1.AU55 UCPU1.AU57 UCPU1.AU59 UCPU1.AV8 UCPU1.AV14 UCPU1.AV16 UCPU1.AV20 UCPU1.AV24 UCPU1.AV28 UCPU1.AV33 UCPU1.AV34 UCPU1.AV36 UCPU1.AV39 UCPU1.AV41 UCPU1.AV43 UCPU1.AV46 UCPU1.AV49 UCPU1.AV51 UCPU1.AV55 UCPU1.AV59 UCPU1.AW4 UCPU1.AW16 UCPU1.AW24 UCPU1.AW33 UCPU1.AW35 UCPU1.AW37 UCPU1.AW40 UCPU1.AW42 UCPU1.AW44 UCPU1.AW47 UCPU1.AW50 UCPU1.AW51 UCPU1.AW59 UCPU1.AW60 UCPU1.AY4 UCPU1.AY6 UCPU1.AY11 UCPU1.AY16 UCPU1.AY18 UCPU1.AY22 UCPU1.AY24 UCPU1.AY26 UCPU1.AY30 UCPU1.AY33 UCPU1.AY51 UCPU1.AY53 UCPU1.AY57 UCPU1.AY59 UCPU1.B4 UCPU1.B20 UCPU1.B24 UCPU1.B26 UCPU1.B28 UCPU1.B32 UCPU1.B36 UCPU1.B40 UCPU1.B44 UCPU1.B48 UCPU1.B52 UCPU1.B56 UCPU1.B60 UCPU1.C11 UCPU1.C14 UCPU1.C18 UCPU1.C20 UCPU1.C25 UCPU1.C27 UCPU1.C38 UCPU1.C39 UCPU1.C57 UCPU1.D2 UCPU1.D5 UCPU1.D8 UCPU1.D12 UCPU1.D14 UCPU1.D18 UCPU1.D21 UCPU1.D23 UCPU1.D25 UCPU1.D26 UCPU1.D27 UCPU1.D29 UCPU1.D30 UCPU1.D31 UCPU1.D33 UCPU1.D34 UCPU1.D35 UCPU1.D37 UCPU1.D38 UCPU1.D39 UCPU1.D41 UCPU1.D42 UCPU1.D43 UCPU1.D45 UCPU1.D46 UCPU1.D47 UCPU1.D49 UCPU1.D50 UCPU1.D51 UCPU1.D53 UCPU1.D54 UCPU1.D55 UCPU1.D57 UCPU1.D59 UCPU1.D62 UCPU1.D63 UCPU1.E11 UCPU1.E17 UCPU1.F20 UCPU1.F26 UCPU1.F30 UCPU1.F34 UCPU1.F38 UCPU1.F42 UCPU1.F46 UCPU1.F50 UCPU1.F54 UCPU1.F58 UCPU1.F61 UCPU1.G3 UCPU1.G5 UCPU1.G6 UCPU1.G8 UCPU1.G18 UCPU1.G22 UCPU1.H13 UCPU1.H17 UCPU1.H57 UCPU1.J10 UCPU1.J22 UCPU1.J59 UCPU1.J63 UCPU1.K1 UCPU1.K12 UCPU1.L7 UCPU1.L13 UCPU1.L15 UCPU1.L17 UCPU1.L18 UCPU1.L20 UCPU1.L58 UCPU1.L61 UCPU1.M22 UCPU1.N3 UCPU1.N10 UCPU1.N21 UCPU1.P22 UCPU1.P59 UCPU1.P62 UCPU1.P63 UCPU1.R8 UCPU1.R10 UCPU1.R22 UCPU1.T1 UCPU1.T58 UCPU1.U9 UCPU1.U20 UCPU1.U22 UCPU1.U61 UCPU1.V3 UCPU1.V7 UCPU1.V10 UCPU1.V23 UCPU1.V58 UCPU1.W20 UCPU1.W22 UCPU1.Y10 UCPU1.Y59 UCPU1.Y63 UD1.A9 UD1.B1 UD1.B3 UD1.B9 UD1.D1 UD1.D3 UD1.D8 UD1.E1 UD1.E2 UD1.E7 UD1.E8 UD1.F9 UD1.G1 UD1.G8 UD1.G9 UD1.J2 UD1.J8 UD1.M1 UD1.M9 UD1.P1 UD1.P9 UD1.T1 UD1.T9 UD3.A9 UD3.B1 UD3.B3 UD3.B9 UD3.D1 UD3.D3 UD3.D8 UD3.E1 UD3.E2 UD3.E7 UD3.E8 UD3.F9 UD3.G1 UD3.G8 UD3.G9 UD3.J2 UD3.J8 UD3.M1 UD3.M9 UD3.P1 UD3.P9 UD3.T1 UD3.T9 UD4.A9 UD4.B1 UD4.B3 UD4.B9 UD4.D1 UD4.D3 UD4.D8 UD4.E1 UD4.E2 UD4.E7 UD4.E8 UD4.F9 UD4.G1 UD4.G8 UD4.G9 UD4.J2 UD4.J8 UD4.M1 UD4.M9 UD4.P1 UD4.P9 UD4.T1 UD4.T9 UD7.A9 UD7.B1 UD7.B3 UD7.B9 UD7.D1 UD7.D3 UD7.D8 UD7.E1 UD7.E2 UD7.E7 UD7.E8 UD7.F9 UD7.G1 UD7.G8 UD7.G9 UD7.J2 UD7.J8 UD7.M1 UD7.M9 UD7.P1 UD7.P9 UD7.T1 UD7.T9 UD28.A9 UD28.B1 UD28.B3 UD28.B9 UD28.D1 UD28.D3 UD28.D8 UD28.E1 UD28.E2 UD28.E7 UD28.E8 UD28.F9 UD28.G1 UD28.G8 UD28.G9 UD28.J2 UD28.J8 UD28.M1 UD28.M9 UD28.P1 UD28.P9 UD28.T1 UD28.T9 UD29.A9 UD29.B1 UD29.B3 UD29.B9 UD29.D1 UD29.D3 UD29.D8 UD29.E1 UD29.E2 UD29.E7 UD29.E8 UD29.F9 UD29.G1 UD29.G8 UD29.G9 UD29.J2 UD29.J8 UD29.M1 UD29.M9 UD29.P1 UD29.P9 UD29.T1 UD29.T9 UD31.A9 UD31.B1 UD31.B3 UD31.B9 UD31.D1 UD31.D3 UD31.D8 UD31.E1 UD31.E2 UD31.E7 UD31.E8 UD31.F9 UD31.G1 UD31.G8 UD31.G9 UD31.J2 UD31.J8 UD31.M1 UD31.M9 UD31.P1 UD31.P9 UD31.T1 UD31.T9 UD32.A9 UD32.B1 UD32.B3 UD32.B9 UD32.D1 UD32.D3 UD32.D8 UD32.E1 UD32.E2 UD32.E7 UD32.E8 UD32.F9 UD32.G1 UD32.G8 UD32.G9 UD32.J2 UD32.J8 UD32.M1 UD32.M9 UD32.P1 UD32.P9 UD32.T1 UD32.T9 UE4.6 UE5.B11 UE5.B18 UE5.B54 UE5.B60 UE5.B66 UE5.C1 UH5.3 US2.1 UV1.8 UV1.15 YH2.2 YH2.4
GNDA_CHG: PC202.1 PC204.2 PC207.1 PC216.1 PC217.1 PC218.1 PC223.2 PC225.1 PC227.2 PJP200.1 PQ206.3 PR210.2 PR215.2 PR225.2 PR229.2 PU200.29
VCCSENSE: PU700.24 RC98.1
VCCSENSE_R: RC97.2 RC98.2 UCPU1.E63
VDD_1.35V: PC611.1 PR601.1 PR603.2 PU600.11
VSSSENSE: PU700.23 RC100.1 UCPU1.E62
+DC_IN: PC106.1 PC107.1 PC108.1 PC200.1 PD201.2 PL103.2 PQ201.1 PR107.1 PR108.1 PR109.1 PR110.1 PR114.1 PR209.2
+DCIN: PC206.1 PR207.2 PU200.28
+DCIN_JACK: JP100.4 JP100.5 PC103.1 PC104.1 PC105.1 PL103.1
+DP_PWR: CV1.1 CV2.1 CV14.1 CV15.1 JMDP.20 U726.3
+INV_PWR_SRC: C612.1 C2982.1 C2985.1 JEDP.2 JEDP.3 JEDP.4 JEDP.5 Q70.5 Q70.6 Q70.7 Q70.8 R531.2 R541.1
+LCDVDD: C6.1 C1143.1 C1145.1 C1211.1 JEDP.20 JEDP.21 JEDP.22 JEDP.23 R1321.2 U708.5
+LDO2: CA88.1 CA90.1 RA84.1 UA2.22
+MD_VREF_CA: CD85.1 CD87.1 CD88.1 CD89.1 CD90.1 CD91.1 CD95.1 CD96.1 RD13.2 RD15.1 RD16.1 UD1.M8 UD3.M8 UD4.M8 UD7.M8 UD28.M8 UD29.M8 UD31.M8 UD32.M8
+MD_VREF_DQA: CD77.1 CD78.1 CD93.1 CD94.1 RD34.2 RD119.1 RD121.1 UD28.H1 UD29.H1 UD31.H1 UD32.H1
+MD_VREF_DQB: CD35.1 CD37.1 CD51.1 CD52.1 RD14.2 RD18.1 RD20.1 UD1.H1 UD3.H1 UD4.H1 UD7.H1
+PBATT: PC100.1 PD200.2 PL100.1 PL101.1 PQ204.5 PQ204.6 PQ204.7 PQ204.8 PR222.2
+PCH_VCCDSW: C1.1 RH346.1 UCPU1.AG19 UCPU1.AG20
+PWR_SRC_AC: PL200.1 PR202.1
+RTC_CELL_VBAT: CE65.1 RE32.2 UE5.B64
+RTC_VCCSUS: CH1207.1 RH341.2 UCPU1.AH11
+RTCBATT: C2973.1 JRTC1.1 RTCR1.2
+RTCVCC: C1309.1 CH82.1 CH83.1 CH84.1 CH95.1 D122.3 RA16.1 RE31.1 RE32.1 RE36.1 RH11.1 RH23.1 RH25.1 RH31.1 RH147.1 RPE5.5 RPE5.6 UCPU1.AG10
+SDC_IN: PQ201.3 PR202.4
+VCHGR: PC219.1 PC220.1 PC221.1 PC222.1 PC235.1 PC236.1 PC237.1 PQ204.1 PQ204.2 PQ204.3 PR219.1
+VR_CAP: CE45.1 UE5.B12
+VS_LPSS_SDIO: C1284.1 C1286.1 C1299.1 CH1227.1 R1131.2 R1188.2 R1327.1 R1328.1 R1360.1 R1361.1 R1362.1 R1363.1 R1364.1 R1365.1 R1372.1 R1373.1 R1374.1 R1375.1 RH350.1 RH354.1 RH434.1 U671.1 U679.C1 UCPU1.T9 UCPU1.U8
-DCIN_JACK: JP100.1 JP100.2 PC104.2 PC105.2 PL104.1
A_ON: R270.1 UE5.A4
AC_DIS: PQ202.5 PQ206.2 UE5.A10
AC_PRESENT: RH12.2 RH137.2 UE5.A54
AC_PRESENT_R: RH137.1 UCPU1.AJ8
ACAV_IN: PR213.1 R268.1 UE5.A64
ACAV_IN_NB: R268.2 UE5.B20
ALS_INT#: JIO1.37 R3.2 UE5.B48
ALS_SMLCLK: JIO1.40 QH6.1 RE87.1 RH453.2
ALS_SMLDATA: JIO1.43 QH6.4 RE88.1 RH454.2
ALW_PWRGD_3V_5V: PR312.1 UE5.A1
ALWON: PR314.1 UE5.A60
AUD_HP_NB_SENSE: RA29.2 UE5.B2
AUDIO_VREF: CA86.1 CA87.1 UA2.43
AUX_EN_WOWL: D116.3 UE5.B53
B+: C613.1 C1273.1 C1274.1 C1275.1 PC214.1 PC215.1 PC228.1 PC229.1 PC230.1 PC233.1 PC234.1 PL201.2 PL300.1 PL303.1 PL400.1 PL402.1 PL500.1 PL600.1 PR219.4 PR732.1 Q70.1 Q70.2 Q70.3 Q361.4 R531.1 R535.1 R1381.1
B+_1.05V: PC503.1 PC504.1 PC506.1 PC507.1 PL500.2 PU500.8
B-RAMP: PR702.2 PR707.1 PU700.11
BAT1_LED#: JKB1.10 UE5.B1
BAT2_LED#: JKB1.9 UE5.A55
BAT_LED#_LV1: LED12.1 R910.2
BAT_LED#_LV2: LED14.1 R911.2
BAT_LED#_LV3: LED10.1 R912.2
BAT_LED#_LV4: LED11.1 R913.2
BAT_LED#_LV5: LED13.1 R916.2
BATBTN#: C2983.1 RPE5.4 SW3.1 SW3.2 UE5.A63
BATDRV#: PQ204.4 PR220.2
BATT_LED#_LV1: R910.1 RP13.9 UE4.25
BATT_LED#_LV2: R911.1 RP13.1 UE4.26
BATT_LED#_LV3: R912.1 RP13.2 UE4.27
BATT_LED#_LV4: R913.1 RP13.3 UE4.28
BATT_LED#_LV5: R916.1 RP13.4 UE4.1
BATT_PRS: JBATT1.5 PD100.3 PRP100.8
BATT_VREF: PC324.2 PR458.1 PR460.2 PU404.2 PU404.6
BBS_BIT: T284.1(TP-1) UCPU1.L8
BC_CLK_ECE1117: JKB1.8 UE5.A20
BC_DAT_ECE1117: JKB1.7 RPE5.1 UE5.B21
BC_INT#_ECE1117: JKB1.6 UE5.A19
BEEP: RA24.1 UE5.B24
BIA_PWM_EC: D73.3 UE5.B25
BOARD_ID: CE54.1 RE79.1 UE5.B10
BOOT_1.35V: PR600.2 PU600.18
BQ24777_REGN: PC205.1 PR212.1 PR223.1 PR228.2 PU200.24
BST_1.05V: PR503.1 PU500.6
BST_1.35V: PC604.1 PR600.1
BST_3V: PR307.2 PU300.9
BST_5V: PR308.1 PU300.17
BT_CS_NOTICE: R1208.2 R1209.2 UCPU1.AD5
BT_RADIO_DIS#: DZ2.1 RE13.2 UE4.23
BT_RADIO_DIS#_R: DZ2.2 JNGFF1.46
CAB_DET_SINK: JMDP.4 RV8.2 RV9.1
CAM_CBL_DET#: RH438.1 RH3541.1 UCPU1.AK4
CAM_CBL_DET#_R: JCAM.2 RH438.2
CFG0: JXDP.9 UCPU1.AC60
CFG1: JXDP.11 UCPU1.AC62
CFG2: JXDP.15 UCPU1.AC63
CFG3: JXDP.17 R1198.2 T293.1(TP-1) UCPU1.AA63
CFG4: JXDP.27 RC81.1 UCPU1.AA60
CFG5: JXDP.29 UCPU1.Y62
CFG6: JXDP.33 UCPU1.Y61
CFG7: JXDP.35 UCPU1.Y60
CFG8: JXDP.10 UCPU1.V62
CFG9: JXDP.12 UCPU1.V61
CFG10: JXDP.16 UCPU1.V60
CFG11: JXDP.18 UCPU1.U60
CFG12: JXDP.28 UCPU1.T63
CFG13: JXDP.30 UCPU1.T62
CFG14: JXDP.34 UCPU1.T61
CFG15: JXDP.36 UCPU1.T60
CFG16: JXDP.6 UCPU1.AA62
CFG17: JXDP.4 UCPU1.AA61
CFG18: JXDP.24 UCPU1.U63
CFG19: JXDP.22 UCPU1.U62
CFG_RCOMP: RC153.1 UCPU1.V63
CHAGER_SRC: PC208.1 PC209.1 PC211.1 PC212.1 PC213.1 PC231.1 PC232.1 PL200.2 PQ203.5
CHARGER_SMBCLK: PR227.1 QH6.6 RE56.1 RH453.1 UE5.B50
CHARGER_SMBDAT: PR226.1 QH6.3 RE55.1 RH454.1 UE5.A47
CHG_BTS: PR211.1 PU200.25
CHG_BTS_C: PC210.1 PR211.2
CHG_LGATE: PQ205.4 PU200.23
CHG_SW: PC210.2 PL201.1 PQ203.1 PQ203.2 PQ203.3 PQ205.5 PR221.1 PU200.27
CHG_UGATE: PQ203.4 PU200.26
CL_CK: R1212.2 UCPU1.AF2
CL_DAT: R1210.2 UCPU1.AD2
CL_RST#: R1200.2 UCPU1.AF4
CLK_LPC_DEBUG: CH1244.1 JLPDE1.10 RH428.2
CLK_PCI_MEC: CH1243.1 RE80.1 RH360.2 UE5.A29
CLK_PCIE_MMI: JIO1.20 UCPU1.C42
CLK_PCIE_MMI#: JIO1.22 UCPU1.C43
CLK_PCIE_MSATA: JNGFF3.55 UCPU1.A37
CLK_PCIE_MSATA#: JNGFF3.53 UCPU1.B37
CLK_PCIE_WLAN: C1302.1 JNGFF1.39 UCPU1.C37
CLK_PCIE_WLAN#: C1301.1 JNGFF1.41 UCPU1.B38
CLK_SMB: JBATT1.3 PD101.3 PRP100.6
CLK_TP_SIO: JTP1.8 MD9.3 RE6.2 UE5.A37
CLKOUT_LPC0: RH360.1 UCPU1.AN15
CLKOUT_LPC1: RH428.1 UCPU1.AP15
CLKRUN#: RH248.2 UCPU1.V5 UE5.A32
CODEC_GPIO6: RA32.1 UA2.3
CODEC_IRQ: RA86.1 RH3532.2 UCPU1.L4
CONFIG_BID: RH3542.1 RH3549.1 UCPU1.AG3
CPU_B+: PC702.1 PC703.1 PC704.1 PC705.1 PC706.1 PR711.1 PR729.1 PR732.2 PU701.5
CPU_EDP_HPD: QC5.3 RC148.2 RC160.1 UCPU1.D6
CPU_PATH_EN: U663.2 U663.5 U663.12 U663.15 U697.4
CPU_XDP_TCK: RC52.2 RH446.2 T265.1(TP-1) UCPU1.E60
CPU_XDP_TDI: T268.1(TP-1) U663.11 UCPU1.F63
CPU_XDP_TDO: RC48.2 T269.1(TP-1) U663.14 UCPU1.F62
CPU_XDP_TMS: T266.1(TP-1) U663.6 UCPU1.E61
CPU_XDP_TRST#: RC54.2 RH370.1 T267.1(TP-1) U663.3 UCPU1.E59
CS1: PR305.2 PU300.1
CS2: PR304.2 PU300.5
CS_1.35V: PR601.2 PU600.13
CSN1: PC715.2 PC716.2 PL701.3 PR724.2 PR725.2 PU700.18
CSP: PL701.2 PR722.1
CSP1: PC715.1 PC716.1 PH701.1 PR722.2 PR724.1 PU700.17
CSSN_1: PR202.2 PR206.2
CSSP_1: PR202.3 PR205.2
DAT_SMB: JBATT1.4 PD101.2 PRP100.7
DAT_TP_SIO: JTP1.7 MD9.2 RE7.2 UE5.B40
DC_TEST_A3_B3: UCPU1.A3 UCPU1.B3
DC_TEST_A61_B61: UCPU1.A61 UCPU1.B61
DC_TEST_AY2_AW2: UCPU1.AW2 UCPU1.AY2
DC_TEST_AY3_AW3: UCPU1.AW3 UCPU1.AY3
DC_TEST_AY61_AW61: UCPU1.AW61 UCPU1.AY61
DC_TEST_AY62_AW62: UCPU1.AW62 UCPU1.AY62
DC_TEST_B62_B63: UCPU1.B62 UCPU1.B63
DC_TEST_C1_C2: UCPU1.C1 UCPU1.C2
DDR3_DRAMRST#: CD5.1 RD28.2 UD1.T2 UD3.T2 UD4.T2 UD7.T2 UD28.T2 UD29.T2 UD31.T2 UD32.T2
DDR_A_BA0: RD67.1 UCPU1.AU35 UD28.M2 UD29.M2 UD31.M2 UD32.M2
DDR_A_BA1: RD99.1 UCPU1.AV35 UD28.N8 UD29.N8 UD31.N8 UD32.N8
DDR_A_BA2: RD82.1 UCPU1.AY41 UD28.M3 UD29.M3 UD31.M3 UD32.M3
DDR_A_CAS#: RD97.1 UCPU1.AU34 UD28.K3 UD29.K3 UD31.K3 UD32.K3
DDR_A_CKE0: RD69.1 UCPU1.AU43 UD28.K9 UD29.K9 UD31.K9 UD32.K9
DDR_A_CKE1: RD87.1 UCPU1.AW43 UD28.J9 UD29.J9 UD31.J9 UD32.J9
DDR_A_CS0#: RD61.1 UCPU1.AP33 UD28.L2 UD29.L2 UD31.L2 UD32.L2
DDR_A_CS1#: RD88.1 UCPU1.AR32 UD28.L1 UD29.L1 UD31.L1 UD32.L1
DDR_A_D0: UCPU1.AH63 UD28.G2
DDR_A_D1: UCPU1.AH62 UD28.F2
DDR_A_D2: UCPU1.AK63 UD28.F8
DDR_A_D3: UCPU1.AK62 UD28.H7
DDR_A_D4: UCPU1.AH61 UD28.E3
DDR_A_D5: UCPU1.AH60 UD28.H3
DDR_A_D6: UCPU1.AK61 UD28.H8
DDR_A_D7: UCPU1.AK60 UD28.F7
DDR_A_D8: UCPU1.AM63 UD28.A3
DDR_A_D9: UCPU1.AM62 UD28.C2
DDR_A_D10: UCPU1.AP63 UD28.D7
DDR_A_D11: UCPU1.AP62 UD28.B8
DDR_A_D12: UCPU1.AM61 UD28.A2
DDR_A_D13: UCPU1.AM60 UD28.C3
DDR_A_D14: UCPU1.AP61 UD28.A7
DDR_A_D15: UCPU1.AP60 UD28.C8
DDR_A_D16: UCPU1.AP58 UD29.H7
DDR_A_D17: UCPU1.AR58 UD29.H8
DDR_A_D18: UCPU1.AM57 UD29.F2
DDR_A_D19: UCPU1.AK57 UD29.G2
DDR_A_D20: UCPU1.AL58 UD29.E3
DDR_A_D21: UCPU1.AK58 UD29.H3
DDR_A_D22: UCPU1.AR57 UD29.F8
DDR_A_D23: UCPU1.AN57 UD29.F7
DDR_A_D24: UCPU1.AP55 UD29.A3
DDR_A_D25: UCPU1.AR55 UD29.C3
DDR_A_D26: UCPU1.AM54 UD29.C8
DDR_A_D27: UCPU1.AK54 UD29.B8
DDR_A_D28: UCPU1.AL55 UD29.C2
DDR_A_D29: UCPU1.AK55 UD29.A2
DDR_A_D30: UCPU1.AR54 UD29.A7
DDR_A_D31: UCPU1.AN54 UD29.D7
DDR_A_D32: UCPU1.AY58 UD31.H3
DDR_A_D33: UCPU1.AW58 UD31.E3
DDR_A_D34: UCPU1.AY56 UD31.F8
DDR_A_D35: UCPU1.AW56 UD31.H7
DDR_A_D36: UCPU1.AV58 UD31.F2
DDR_A_D37: UCPU1.AU58 UD31.G2
DDR_A_D38: UCPU1.AV56 UD31.H8
DDR_A_D39: UCPU1.AU56 UD31.F7
DDR_A_D40: UCPU1.AY54 UD31.A2
DDR_A_D41: UCPU1.AW54 UD31.C2
DDR_A_D42: UCPU1.AY52 UD31.B8
DDR_A_D43: UCPU1.AW52 UD31.D7
DDR_A_D44: UCPU1.AV54 UD31.C3
DDR_A_D45: UCPU1.AU54 UD31.A3
DDR_A_D46: UCPU1.AV52 UD31.C8
DDR_A_D47: UCPU1.AU52 UD31.A7
DDR_A_D48: UCPU1.AK40 UD32.G2
DDR_A_D49: UCPU1.AK42 UD32.H3
DDR_A_D50: UCPU1.AM43 UD32.F2
DDR_A_D51: UCPU1.AM45 UD32.F7
DDR_A_D52: UCPU1.AK45 UD32.E3
DDR_A_D53: UCPU1.AK43 UD32.F8
DDR_A_D54: UCPU1.AM40 UD32.H7
DDR_A_D55: UCPU1.AM42 UD32.H8
DDR_A_D56: UCPU1.AM46 UD32.B8
DDR_A_D57: UCPU1.AK46 UD32.C8
DDR_A_D58: UCPU1.AM49 UD32.A3
DDR_A_D59: UCPU1.AK49 UD32.A2
DDR_A_D60: UCPU1.AM48 UD32.A7
DDR_A_D61: UCPU1.AK48 UD32.D7
DDR_A_D62: UCPU1.AM51 UD32.C3
DDR_A_D63: UCPU1.AK51 UD32.C2
DDR_A_DQS0: UCPU1.AJ62 UD28.F3
DDR_A_DQS1: UCPU1.AN61 UD28.C7
DDR_A_DQS2: UCPU1.AN58 UD29.F3
DDR_A_DQS3: UCPU1.AN55 UD29.C7
DDR_A_DQS4: UCPU1.AW57 UD31.F3
DDR_A_DQS5: UCPU1.AW53 UD31.C7
DDR_A_DQS6: UCPU1.AL42 UD32.F3
DDR_A_DQS7: UCPU1.AL49 UD32.C7
DDR_A_DQS#0: UCPU1.AJ61 UD28.G3
DDR_A_DQS#1: UCPU1.AN62 UD28.B7
DDR_A_DQS#2: UCPU1.AM58 UD29.G3
DDR_A_DQS#3: UCPU1.AM55 UD29.B7
DDR_A_DQS#4: UCPU1.AV57 UD31.G3
DDR_A_DQS#5: UCPU1.AV53 UD31.B7
DDR_A_DQS#6: UCPU1.AL43 UD32.G3
DDR_A_DQS#7: UCPU1.AL48 UD32.B7
DDR_A_MA0: RD63.1 UCPU1.AU36 UD28.N3 UD29.N3 UD31.N3 UD32.N3
DDR_A_MA1: RD37.1 UCPU1.AY37 UD28.P7 UD29.P7 UD31.P7 UD32.P7
DDR_A_MA2: RD66.1 UCPU1.AR38 UD28.P3 UD29.P3 UD31.P3 UD32.P3
DDR_A_MA3: RD45.1 UCPU1.AP36 UD28.N2 UD29.N2 UD31.N2 UD32.N2
DDR_A_MA4: RD33.1 UCPU1.AU39 UD28.P8 UD29.P8 UD31.P8 UD32.P8
DDR_A_MA5: RD47.1 UCPU1.AR36 UD28.P2 UD29.P2 UD31.P2 UD32.P2
DDR_A_MA6: RD86.1 UCPU1.AV40 UD28.R8 UD29.R8 UD31.R8 UD32.R8
DDR_A_MA7: RD85.1 UCPU1.AW39 UD28.R2 UD29.R2 UD31.R2 UD32.R2
DDR_A_MA8: RD98.1 UCPU1.AY39 UD28.T8 UD29.T8 UD31.T8 UD32.T8
DDR_A_MA9: RD83.1 UCPU1.AU40 UD28.R3 UD29.R3 UD31.R3 UD32.R3
DDR_A_MA10: RD36.1 UCPU1.AP35 UD28.L7 UD29.L7 UD31.L7 UD32.L7
DDR_A_MA11: RD59.1 UCPU1.AW41 UD28.R7 UD29.R7 UD31.R7 UD32.R7
DDR_A_MA12: RD25.1 UCPU1.AU41 UD28.N7 UD29.N7 UD31.N7 UD32.N7
DDR_A_MA13: RD72.1 UCPU1.AR35 UD28.T3 UD29.T3 UD31.T3 UD32.T3
DDR_A_MA14: RD50.1 UCPU1.AV42 UD28.T7 UD29.T7 UD31.T7 UD32.T7
DDR_A_MA15: RD27.1 UCPU1.AU42 UD28.M7 UD29.M7 UD31.M7 UD32.M7
DDR_A_RAS#: RD79.1 UCPU1.AY34 UD28.J3 UD29.J3 UD31.J3 UD32.J3
DDR_A_WE#: RD65.1 UCPU1.AW34 UD28.L3 UD29.L3 UD31.L3 UD32.L3
DDR_B_BA0: RD70.1 UCPU1.AL35 UD1.M2 UD3.M2 UD4.M2 UD7.M2
DDR_B_BA1: RD80.1 UCPU1.AM36 UD1.N8 UD3.N8 UD4.N8 UD7.N8
DDR_B_BA2: RD68.1 UCPU1.AU49 UD1.M3 UD3.M3 UD4.M3 UD7.M3
DDR_B_CAS#: RD62.1 UCPU1.AM33 UD1.K3 UD3.K3 UD4.K3 UD7.K3
DDR_B_CKE0: RD58.1 UCPU1.AY49 UD1.K9 UD3.K9 UD4.K9 UD7.K9
DDR_B_CKE1: RD89.1 UCPU1.AU50 UD1.J9 UD3.J9 UD4.J9 UD7.J9
DDR_B_CS0#: RD60.1 UCPU1.AM32 UD1.L2 UD3.L2 UD4.L2 UD7.L2
DDR_B_CS1#: RD90.1 UCPU1.AK32 UD1.L1 UD3.L1 UD4.L1 UD7.L1
DDR_B_D0: UCPU1.AY31 UD7.F2
DDR_B_D1: UCPU1.AW31 UD7.G2
DDR_B_D2: UCPU1.AY29 UD7.H7
DDR_B_D3: UCPU1.AW29 UD7.F8
DDR_B_D4: UCPU1.AV31 UD7.H3
DDR_B_D5: UCPU1.AU31 UD7.E3
DDR_B_D6: UCPU1.AV29 UD7.F7
DDR_B_D7: UCPU1.AU29 UD7.H8
DDR_B_D8: UCPU1.AY27 UD7.A2
DDR_B_D9: UCPU1.AW27 UD7.C2
DDR_B_D10: UCPU1.AY25 UD7.B8
DDR_B_D11: UCPU1.AW25 UD7.A7
DDR_B_D12: UCPU1.AV27 UD7.C3
DDR_B_D13: UCPU1.AU27 UD7.D7
DDR_B_D14: UCPU1.AV25 UD7.A3
DDR_B_D15: UCPU1.AU25 UD7.C8
DDR_B_D16: UCPU1.AM29 UD1.G2
DDR_B_D17: UCPU1.AK29 UD1.H3
DDR_B_D18: UCPU1.AL28 UD1.F8
DDR_B_D19: UCPU1.AK28 UD1.H8
DDR_B_D20: UCPU1.AR29 UD1.E3
DDR_B_D21: UCPU1.AN29 UD1.F2
DDR_B_D22: UCPU1.AR28 UD1.F7
DDR_B_D23: UCPU1.AP28 UD1.H7
DDR_B_D24: UCPU1.AN26 UD1.A3
DDR_B_D25: UCPU1.AR26 UD1.A2
DDR_B_D26: UCPU1.AR25 UD1.A7
DDR_B_D27: UCPU1.AP25 UD1.D7
DDR_B_D28: UCPU1.AK26 UD1.C3
DDR_B_D29: UCPU1.AM26 UD1.C2
DDR_B_D30: UCPU1.AK25 UD1.C8
DDR_B_D31: UCPU1.AL25 UD1.B8
DDR_B_D32: UCPU1.AY23 UD3.E3
DDR_B_D33: UCPU1.AW23 UD3.F2
DDR_B_D34: UCPU1.AY21 UD3.H8
DDR_B_D35: UCPU1.AW21 UD3.F7
DDR_B_D36: UCPU1.AV23 UD3.G2
DDR_B_D37: UCPU1.AU23 UD3.H3
DDR_B_D38: UCPU1.AV21 UD3.H7
DDR_B_D39: UCPU1.AU21 UD3.F8
DDR_B_D40: UCPU1.AY19 UD3.C2
DDR_B_D41: UCPU1.AW19 UD3.C3
DDR_B_D42: UCPU1.AY17 UD3.B8
DDR_B_D43: UCPU1.AW17 UD3.D7
DDR_B_D44: UCPU1.AV19 UD3.A2
DDR_B_D45: UCPU1.AU19 UD3.A3
DDR_B_D46: UCPU1.AV17 UD3.C8
DDR_B_D47: UCPU1.AU17 UD3.A7
DDR_B_D48: UCPU1.AR21 UD4.E3
DDR_B_D49: UCPU1.AR22 UD4.G2
DDR_B_D50: UCPU1.AL21 UD4.H7
DDR_B_D51: UCPU1.AM22 UD4.F7
DDR_B_D52: UCPU1.AN22 UD4.H3
DDR_B_D53: UCPU1.AP21 UD4.F2
DDR_B_D54: UCPU1.AK21 UD4.H8
DDR_B_D55: UCPU1.AK22 UD4.F8
DDR_B_D56: UCPU1.AN20 UD4.A3
DDR_B_D57: UCPU1.AR20 UD4.A2
DDR_B_D58: UCPU1.AK18 UD4.B8
DDR_B_D59: UCPU1.AL18 UD4.C8
DDR_B_D60: UCPU1.AK20 UD4.C3
DDR_B_D61: UCPU1.AM20 UD4.C2
DDR_B_D62: UCPU1.AR18 UD4.A7
DDR_B_D63: UCPU1.AP18 UD4.D7
DDR_B_DQS0: UCPU1.AV30 UD7.F3
DDR_B_DQS1: UCPU1.AW26 UD7.C7
DDR_B_DQS2: UCPU1.AM28 UD1.F3
DDR_B_DQS3: UCPU1.AM25 UD1.C7
DDR_B_DQS4: UCPU1.AV22 UD3.F3
DDR_B_DQS5: UCPU1.AW18 UD3.C7
DDR_B_DQS6: UCPU1.AM21 UD4.F3
DDR_B_DQS7: UCPU1.AM18 UD4.C7
DDR_B_DQS#0: UCPU1.AW30 UD7.G3
DDR_B_DQS#1: UCPU1.AV26 UD7.B7
DDR_B_DQS#2: UCPU1.AN28 UD1.G3
DDR_B_DQS#3: UCPU1.AN25 UD1.B7
DDR_B_DQS#4: UCPU1.AW22 UD3.G3
DDR_B_DQS#5: UCPU1.AV18 UD3.B7
DDR_B_DQS#6: UCPU1.AN21 UD4.G3
DDR_B_DQS#7: UCPU1.AN18 UD4.B7
DDR_B_MA0: RD94.1 UCPU1.AP40 UD1.N3 UD3.N3 UD4.N3 UD7.N3
DDR_B_MA1: RD91.1 UCPU1.AR40 UD1.P7 UD3.P7 UD4.P7 UD7.P7
DDR_B_MA2: RD49.1 UCPU1.AP42 UD1.P3 UD3.P3 UD4.P3 UD7.P3
DDR_B_MA3: RD96.1 UCPU1.AR42 UD1.N2 UD3.N2 UD4.N2 UD7.N2
DDR_B_MA4: RD38.1 UCPU1.AR45 UD1.P8 UD3.P8 UD4.P8 UD7.P8
DDR_B_MA5: RD93.1 UCPU1.AP45 UD1.P2 UD3.P2 UD4.P2 UD7.P2
DDR_B_MA6: RD73.1 UCPU1.AW46 UD1.R8 UD3.R8 UD4.R8 UD7.R8
DDR_B_MA7: RD48.1 UCPU1.AY46 UD1.R2 UD3.R2 UD4.R2 UD7.R2
DDR_B_MA8: RD84.1 UCPU1.AY47 UD1.T8 UD3.T8 UD4.T8 UD7.T8
DDR_B_MA9: RD57.1 UCPU1.AU46 UD1.R3 UD3.R3 UD4.R3 UD7.R3
DDR_B_MA10: RD100.1 UCPU1.AK36 UD1.L7 UD3.L7 UD4.L7 UD7.L7
DDR_B_MA11: RD71.1 UCPU1.AV47 UD1.R7 UD3.R7 UD4.R7 UD7.R7
DDR_B_MA12: RD26.1 UCPU1.AU47 UD1.N7 UD3.N7 UD4.N7 UD7.N7
DDR_B_MA13: RD46.1 UCPU1.AK33 UD1.T3 UD3.T3 UD4.T3 UD7.T3
DDR_B_MA14: RD35.1 UCPU1.AR46 UD1.T7 UD3.T7 UD4.T7 UD7.T7
DDR_B_MA15: RD74.1 UCPU1.AP46 UD1.M7 UD3.M7 UD4.M7 UD7.M7
DDR_B_RAS#: RD64.1 UCPU1.AM35 UD1.J3 UD3.J3 UD4.J3 UD7.J3
DDR_B_WE#: RD81.1 UCPU1.AK35 UD1.L3 UD3.L3 UD4.L3 UD7.L3
DDR_CHA_EN: RH440.1 RH442.1 UCPU1.J1
DDR_CHB_EN: RH441.1 RH443.1 UCPU1.K3
DH_1.35V: PQ600.4 PU600.17
DISP_CEC: JMDP.6 RV4.1
DISP_CLK_AUXP_CONN: CV798.1 JMDP.16 RV3.1 UV1.4
DISP_DAT_AUXN_CONN: JMDP.18 RV2.1 UV1.7
DISP_HPD_SINK: JMDP.2 QV2.1 RV10.1
DISPOFF#: D72.1 JEDP.9 R540.1
DL_1.35V: PQ601.4 PU600.15
DMIC_CLK_CODEC: CA23.2 JKB1.12 RA45.2
DMIC_DAT_CODEC: CA25.2 JKB1.11 UA2.54
DP_CBL_DET: RV8.1 UV1.1
DSWODVREN: RH147.2 UCPU1.AW7
EC_WAKE#: RP20.3 UCPU1.AN5 UE5.B27
EDP_AUXN: C1065.1 UCPU1.A45
EDP_AUXN_C: C1065.2 L58.1
EDP_AUXN_CONN: JEDP.25 L58.2
EDP_AUXP: C1064.1 UCPU1.B45
EDP_AUXP_C: C1064.2 L58.4
EDP_AUXP_CONN: JEDP.26 L58.3
EDP_BIA_PWM: D73.2 RC146.2 RC147.1
EDP_BKLCTL: RC147.2 UCPU1.B8
EDP_COM: RC36.1 UCPU1.D20
EDP_DISP: RC146.1 RC158.2 UCPU1.A43
EDP_HPD: JEDP.14 QC5.1 RC148.1
EDP_TXN_P0: C1062.1 UCPU1.C45
EDP_TXN_P0_C: C1062.2 L57.4
EDP_TXN_P0_CONN: JEDP.29 L57.3
EDP_TXN_P1: C1063.1 UCPU1.A47
EDP_TXN_P1_C: C1063.2 L56.4
EDP_TXN_P1_CONN: JEDP.32 L56.3
EDP_TXN_P2: C1066.1 UCPU1.C47
EDP_TXN_P2_C: C1066.2 L59.4
EDP_TXN_P2_CONN: JEDP.35 L59.3
EDP_TXN_P3: C1068.1 UCPU1.A49
EDP_TXN_P3_C: C1068.2 L60.4
EDP_TXN_P3_CONN: JEDP.38 L60.3
EDP_TXP_P0: C1060.1 UCPU1.B46
EDP_TXP_P0_C: C1060.2 L57.1
EDP_TXP_P0_CONN: JEDP.28 L57.2
EDP_TXP_P1: C1061.1 UCPU1.B47
EDP_TXP_P1_C: C1061.2 L56.1
EDP_TXP_P1_CONN: JEDP.31 L56.2
EDP_TXP_P2: C1067.1 UCPU1.C46
EDP_TXP_P2_C: C1067.2 L59.1
EDP_TXP_P2_CONN: JEDP.34 L59.2
EDP_TXP_P3: C1069.1 UCPU1.B49
EDP_TXP_P3_C: C1069.2 L60.1
EDP_TXP_P3_CONN: JEDP.37 L60.2
EN_0.675VSP: PC614.1 PR609.2 PR610.1 PU600.7
EN_1.5V: PC400.1 PR400.2 PR410.2 PU400.13
EN_1.8V: PC408.1 PR405.2 PR411.2 PU401.13
EN_1.35V: PC613.1 PR608.2 PU600.8
EN_+1.05SP: PR500.2 R271.2 R272.2
EN_CAM: R1177.1 U718.3 UCPU1.AM4
EN_INVPWR: Q71.2 R1161.1 U708.2 UE5.A25
EN_MPOWER: R269.2 R270.2 R272.1 R1163.1 U34.3 U715.3
ENVDD: D93.1 R1026.2 U715.5
ENVDD_PCH: D93.3 UCPU1.C6 UE5.A7
F-IMAX: PR703.2 PR708.1 PU700.10
FAN1_PWM: JFAN1.3 R1103.1 UE5.A24
FAN1_TACH: D81.2 R884.1 UE5.B22
FB_1.5V: PC402.2 PR401.2 PR403.1 PU400.5
FB_1.8V: PC410.2 PR406.2 PR408.1 PU401.5
FB_1.35V: PR605.1 PR607.1 PU600.6
FB_3V: PR300.2 PR302.2 PU300.4
FB_5V: PR301.2 PR303.1 PU300.2
FWP#: RE81.2 RE82.2 UE5.B65
GPIO88_SLP_S0#: R253.2 RH198.1 UCPU1.L5
H_CATERR#: T2.1(TP-1) UCPU1.K61
H_CPU_SVIDALRT#: RC94.2 UCPU1.L62
H_CPU_SVIDCLK: CC243.1 RC92.2 UCPU1.N63
H_CPU_SVIDDAT: R1371.2 RC96.2 UCPU1.L63
H_CPUPWRGD_R: RC44.2 UCPU1.C61
H_DRAMRST#: RD24.1 RD28.1 UCPU1.AV15
H_PROCHOT#: PC718.1 PQ102.3 PR216.1 PR461.2 PR723.2 PU700.30 RC41.1 RC43.2 UE5.A46
H_PROCHOT#_R: RC41.2 UCPU1.K63
H_THERMTRIP#: QE9.3 RC149.1 UCPU1.D60
H_VR_READY: PR713.1 PU700.3 RC152.1 RC201.1 RH4.2
HD_SOC_SEL: QA7.3 RA82.2 RA86.2 UA2.6
HDA#_I2S_SEL: QA8.2 UE5.B41
HDD_DET#: RH466.1 UCPU1.U1
HOST_ALERT1_R_N: RH270.1 UCPU1.AD6
HOST_DEBUG_TX: JDEG1.8 RE74.2 UE5.B44
HP2_D_L: RA17.1 UA2.32
HP2_D_L_C: CA29.2 DA2.3 JHP1.1 LA7.2
HP2_D_L_R1: LA7.1 RA17.2 RA48.2 RA50.2 RA61.1
HP2_D_R: RA15.1 UA2.33
HP2_D_R_C: CA69.1 DA2.2 JHP1.2 LA6.2
HP2_D_R_R2: LA6.1 RA15.2 RA49.2 RA51.2 RA60.1
I2C0_SCK: RA8.2 RH425.1 UCPU1.F3
I2C0_SCK_DSP: RA8.1 UA2.12
I2C0_SDA: RA7.2 RH424.1 UCPU1.F2
I2C0_SDA_DSP: RA7.1 UA2.11
I2C1_SCK: QH7.4 RH5.1 RH456.1 UCPU1.F1
I2C1_SCK_TP: JTP1.3 MD10.3 QH7.3 R1105.1 RH456.2
I2C1_SDA: QH7.1 RH3.1 RH461.1 UCPU1.G4
I2C1_SDA_TP: JTP1.2 MD10.2 QH7.6 R1104.1 RH461.2
I2S_BIT_CLK: CH1242.1 RP15.7 UCPU1.AW8
I2S_BITCLK_AUDIO: RA52.1 RP15.2
I2S_BITCLK_AUDIO_R: CA57.1 RA52.2 UA2.13
I2S_RST#: RP15.8 UCPU1.AU8
I2S_RST_AUDIO#: RA54.1 RP15.1
I2S_RST_AUDIO#_R: CA26.2 RA14.2 RA54.2 UA2.15
I2S_SDIN0: RA62.1 UCPU1.AY10
I2S_SDIN0_AUDIO: RA62.2 UA2.16
I2S_SDOUT: MC31.1 RH24.2 RH42.2 RP15.6 UCPU1.AU11
I2S_SDOUT_AUDIO: RA36.2 RP15.3
I2S_SDOUT_AUDIO_R: CA27.2 RA36.1 UA2.17
I2S_SYNC: RP15.5 UCPU1.AV11
I2S_SYNC_AUDIO: RA53.1 RP15.4
I2S_SYNC_AUDIO_R: CA24.2 RA53.2 UA2.14
I_ADP: PR214.1 UE5.A12
I_BATT: PR217.1 RE64.2
I_SYS: PR218.1 UE5.A57
ILMT_1.05V: PR504.2 PR507.1 PU500.3
IMON: PC700.1 PR701.1 PU700.13
INV_PWM_R: D73.1 JEDP.8 MC3.1 R545.1
IRQ_SERIRQ: RH29.1 UCPU1.T4 UE5.A28
JACK_PLUG: DA1.3 JHP1.6 QA3.5 RA26.1 RA35.1
JACK_PLUG_DL: CA74.1 QA3.6 QA6.2 RA20.1 RA26.2 RA31.1 RA38.2
JACK_PLUG_DL#: QA6.1 RA29.1 RA31.2 RA75.1
JTAG_CLK: JDEG1.4 RPE7.3 UE5.B56
JTAG_RST#: CE59.1 JTAG1.1 RE65.2 RE66.1 UE5.B47
JTAG_TDI: JDEG1.2 RPE7.1 UE5.A51
JTAG_TDO: JDEG1.5 RPE7.4 UE5.B55
JTAG_TMS: JDEG1.3 RPE7.2 UE5.A53
KB_DET#: JKB1.5 RH302.1 T282.1(TP-1) UCPU1.AT3
LANCLK_REQ#: RH91.2 UCPU1.AD1
LCD_TST: JEDP.19 RE58.2 UE5.A38
LCD_VCC_TEST_EN: D93.2 UE5.A39
LG_3V: PQ300.4 PU300.11
LG_5V: PQ301.4 PU300.15
LID_CL_SIO#: CE13.1 RE25.2 RE26.2 UE5.A21
LID_SW_IN#: JIO1.44 RE26.1
LINE1-VREFO: DA6.1 UA2.39
LINE1_L: CA70.1 UA2.35
LINE1_L_C: CA71.2 RA51.1
LINE1_R: CA71.1 UA2.34
LINE1_R_C: CA70.2 RA50.1
LPC_AD0: JLPDE1.3 UCPU1.AU14 UE5.A30
LPC_AD1: JLPDE1.4 UCPU1.AW12 UE5.B32
LPC_AD2: JLPDE1.5 UCPU1.AY12 UE5.A31
LPC_AD3: JLPDE1.6 UCPU1.AW11 UE5.B33
LPC_FRAME#: JLPDE1.7 UCPU1.AV12 UE5.B31
LX_1.05V: PC505.2 PL501.1 PR502.1 PU500.10
LX_3V: PC305.1 PQ300.3 PU300.8
LX_5V: PC306.2 PQ301.3 PU300.18
LX_CORE: PL701.1 PR717.1 PU701.4
M_CLK_A_DDR0: RD75.1 UCPU1.AV37 UD28.J7 UD29.J7 UD31.J7 UD32.J7
M_CLK_A_DDR#0: RD77.1 UCPU1.AU37 UD28.K7 UD29.K7 UD31.K7 UD32.K7
M_CLK_B_DDR0: RD76.1 UCPU1.AN38 UD1.J7 UD3.J7 UD4.J7 UD7.J7
M_CLK_B_DDR#0: RD78.1 UCPU1.AM38 UD1.K7 UD3.K7 UD4.K7 UD7.K7
M_ODT0: RD92.1 UD28.J1 UD28.K1 UD29.J1 UD29.K1 UD31.J1 UD31.K1 UD32.J1 UD32.K1
M_ODT2: RD95.1 UD1.J1 UD1.K1 UD3.J1 UD3.K1 UD4.J1 UD4.K1 UD7.J1 UD7.K1
MCARD_PCIE#_SATA: R1020.2 R1021.2 U683.4
MCARD_PCIE#_SATA_R: R1020.1 RH392.2 RH395.2 UCPU1.AC1
MCARD_PCIE_SATA#: JNGFF3.61 R220.2 U683.2
MCP23017_I2CCLK: RE73.1 UE4.8 UE5.B4
MCP23017_I2CDATA: RE71.1 UE4.9 UE5.A3
ME_EN: R1191.1 RH24.1 SW4.2
ME_FWP_EC: R1191.2 SW4.3 UE5.B46
ME_SUS_PWR_ACK: RH297.2 UE5.A8
MEC_XTAL1: CE62.1 UE5.A61 YE1.1
MEC_XTAL2: CE53.1 RE62.2 YE1.2
MEC_XTAL2_R: RE62.1 UE5.A62
MEDIACARD_IRQ#: JIO1.42 RH3533.1 UCPU1.AB6
MEDIACARD_PWREN: R1176.1 R1178.1 U716.5 UCPU1.AP1
MEDIACARD_RST#: RH3535.1 UCPU1.AG6
MEM_CONFIG0: RH303.1 RH316.2 T286.1(TP-1) UCPU1.C4
MEM_CONFIG1: RH180.1 RH315.2 T287.1(TP-1) UCPU1.J2
MEM_CONFIG2: RH271.1 RH314.2 UCPU1.G1
MIC1-VREFO: RA27.1 RA28.1 UA2.38
MIC1_L: LA4.1 RA28.2 UA2.36
MIC1_L_L: CA68.2 DA7.1 JHP1.4 LA4.2 QA1.6
MIC1_R: LA5.1 RA27.2 UA2.37
MIC1_R_L: CA28.1 DA5.1 JHP1.3 LA5.2 QA1.3
MMICLK_REQ#: JIO1.30 RH100.2 UCPU1.U2
MONO_IN: CA34.2 UA2.41
MPCIE_RST#: R1314.1 RH393.1 U675.1 UCPU1.V1
MPHY_PWREN#: Q39.2 Q361.2 Q361.5 Q362.1 R1381.2
MPHYP_PWR_EN: Q362.2 R1169.1 R1185.1 UCPU1.Y2
MSATA_DEVSLP: JNGFF3.38 R1376.2 UCPU1.P2
MSATACLK_REQ#: JNGFF3.52 RH110.2 UCPU1.T2
MSCLK: JDEG1.6 RE72.2 UE5.B43
MSDATA: JDEG1.7 RE75.2 RE85.1 UE5.A40
NB_MUTE#: RA57.1 RA85.2 UA2.52 UE4.20
NB_PSID: JP100.3 PD102.1 PL102.2
NC: U728.4
NFC_DET#: JNFC1.12 R1228.1 RH465.1 UCPU1.AT5
NFC_IRQ: JNFC1.11 R1100.2 RH294.1 UCPU1.AN3
NFC_VDD_SIM: JNFC1.10 R973.2 R974.1
NGFF_ON: D116.1 R1186.2 U720.3
NGFF_PWREN: D116.2 R1396.1 UCPU1.R6
NGFF_RST#: JNGFF1.44 JNGFF3.50 R1203.1 U675.4
O-USR: PR704.2 PR709.1 PU700.9
OCP-I: PR701.2 PR706.1 PR730.2 PU700.12
PANEL_BKEN_EC: D72.3 UE4.4
PANEL_BKLEN: D72.2 UCPU1.A9
PBAT_PRES#: PR100.2 PR224.1 PRP100.1 UE5.A49
PBAT_SMBCLK: PRP100.3 RE53.2 UE5.A56
PBAT_SMBDAT: PRP100.2 RE52.2 UE5.B59
PBATT+_C: JBATT1.1 JBATT1.2 PC101.1 PC102.2 PL100.2 PL101.2
PBTN_SW#: CE21.1 JAPS.11 JIO1.35 RE33.2 RH21.2 SW2.2 SW2.4
PCH_ALW_ON: R271.1 R1187.2 U717.3 UE5.A34
PCH_AUDIO_PWR: R1140.1 R1141.1 T279.1(TP-1) U664.3 U664.5 U719.5 UCPU1.P1
PCH_BATLOW#: RP20.4 UCPU1.AN4
PCH_DP_AUXN: CV10.2 UCPU1.C5
PCH_DP_AUXN_C: CV10.1 UV1.5
PCH_DP_AUXP: CV8.2 UCPU1.B5
PCH_DP_AUXP_C: CV8.1 UV1.2
PCH_DP_CLK: RP14.7 UCPU1.B9 UV1.3
PCH_DP_DAT: RP14.6 UCPU1.C9 UV1.6
PCH_DP_HPD: QV2.3 RH300.2 UCPU1.C8
PCH_DP_N0: CV4.2 UCPU1.C54
PCH_DP_N0_C: CV4.1 JMDP.5 MD16.4 MD16.7
PCH_DP_N1: CV7.2 UCPU1.B58
PCH_DP_N1_C: CV7.1 JMDP.11 MD5.4 MD5.7
PCH_DP_N2: CV12.2 UCPU1.B55
PCH_DP_N2_C: CV12.1 JMDP.17 MD5.1 MD5.9
PCH_DP_N3: CV9.2 UCPU1.A57
PCH_DP_N3_C: CV9.1 JMDP.12 MD16.1 MD16.9
PCH_DP_P0: CV3.2 UCPU1.C55
PCH_DP_P0_C: CV3.1 JMDP.3 MD16.5 MD16.6
PCH_DP_P1: CV5.2 UCPU1.C58
PCH_DP_P1_C: CV5.1 JMDP.9 MD5.5 MD5.6
PCH_DP_P2: CV11.2 UCPU1.A55
PCH_DP_P2_C: CV11.1 JMDP.15 MD5.2 MD5.8
PCH_DP_P3: CV6.2 UCPU1.B57
PCH_DP_P3_C: CV6.1 JMDP.10 MD16.2 MD16.8
PCH_DPWROK: RH309.1 UE5.A36
PCH_DPWROK_R: RH309.2 RH401.1 UCPU1.AV5
PCH_GPIO12: RH3538.1 UCPU1.AM7
PCH_GPIO14: T288.1(TP-1) UCPU1.AH4
PCH_GPIO16: RH3539.1 UCPU1.Y1
PCH_GPIO38: RH3540.1 UCPU1.L2
PCH_GPIO48: RH3530.1 UCPU1.U4
PCH_GPIO49: RH3543.1 UCPU1.Y3
PCH_GPIO51: RH3544.2 UCPU1.R5
PCH_GPIO58: RH3546.1 UCPU1.AL4
PCH_GPIO73: RP16.4 UCPU1.AU4
PCH_GPIO77: RH3547.2 UCPU1.U6
PCH_GPIO78: RP4.5 UCPU1.P4
PCH_GPIO79: RP4.8 UCPU1.N4
PCH_GPIO80: RP4.7 UCPU1.N2
PCH_GPIO84: RH199.1 UCPU1.L6
PCH_GPIO87: RH3531.1 UCPU1.R7
PCH_GPIO90: RH200.1 UCPU1.K2
PCH_INTVRMEN: RH31.2 RH34.1 UCPU1.AV7
PCH_JTAG_JTAGX: RH374.2 RH412.2 T273.1(TP-1) UCPU1.AE63
PCH_JTAG_TCK: RH373.2 RH411.2 T277.1(TP-1) UCPU1.AE62
PCH_JTAG_TDI: RH40.2 RH371.2 T278.1(TP-1) UCPU1.AD61
PCH_JTAG_TDO: RH369.2 RH413.2 RH445.2 T275.1(TP-1) UCPU1.AE61
PCH_JTAG_TMS: RH39.2 RH372.2 T276.1(TP-1) UCPU1.AD62
PCH_JTAG_TRST#: RH370.2 UCPU1.AU62
PCH_NFC_RST#: JNFC1.6 R1142.1 UCPU1.AD7
PCH_OPIRCOMP: RC156.1 UCPU1.AW15
PCH_PCIE_WAKE#: RH146.1 UCPU1.AJ5 UE5.A44
PCH_PLTRST#: RH168.2 RH183.2 UCPU1.AG7 UH5.1 UH5.2
PCH_PLTRST#_EC: JIO1.38 JLPDE1.8 R1313.1 RE54.2 RH168.1 RH171.1 RH363.1 RH474.2 U675.2 UE5.B30 UH5.4
PCH_RSMRST#: RH133.2 RH159.2 UE5.A45
PCH_RSMRST#_R: RH133.1 UCPU1.AW6
PCH_RTCRST#: CH4.1 CLRP1.1 JAPS.9 RH25.2 UCPU1.AU7
PCH_RTCX1: CH2.1 RH2.1 UCPU1.AW5 YH1.1
PCH_RTCX2: CH3.1 RH2.2 UCPU1.AY5 YH1.2
PCH_SATALED#: RH35.2 UCPU1.U3
PCH_SMB_ALERT#: RP16.2 UCPU1.AN2
PCH_SMBCLK: JXDP.53 RP2.1 UCPU1.AP2
PCH_SMBDATA: JXDP.51 RP2.2 UCPU1.AH1
PCH_SML0ALERT: RP16.3 UCPU1.AL2
PCH_SPI_CLK: MC29.2 RP5.6 RP5.7 RP5.8 UCPU1.AA3
PCH_SPI_CLK_TPM: MC33.1 RP5.3 U652.21
PCH_SPI_CS0#: U48.1 UCPU1.Y7
PCH_SPI_CS1#: U727.1 UCPU1.Y4
PCH_SPI_CS2#: U652.22 UCPU1.AC2
PCH_SPI_IO2: RH57.2 RP8.5 RP8.6 UCPU1.Y6
PCH_SPI_IO3: RH55.2 RP8.7 RP8.8 UCPU1.AF1
PCH_SPI_SI: RP6.6 RP6.7 RP6.8 UCPU1.AA2
PCH_SPI_SI_TPM: RP6.3 U652.23
PCH_SPI_SO: RP7.6 RP7.7 RP7.8 UCPU1.AA4
PCH_SPI_SO_TPM: RP7.3 U652.26
PCH_SRTCRST#: CH5.1 RH23.2 UCPU1.AV6
PCH_SYS_PWROK_XDP: C1282.1 JXDP.47 R1309.1 R1311.2
PCIE_PRX_CARDTX_N1: JIO1.28 UCPU1.G17
PCIE_PRX_CARDTX_P1: JIO1.26 UCPU1.F17
PCIE_PRX_WLANTX_N4: JNGFF1.35 UCPU1.F13
PCIE_PRX_WLANTX_P4: JNGFF1.33 UCPU1.G13
PCIE_PTX_C_CARDRX_N1: CH25.2 UCPU1.C30
PCIE_PTX_C_CARDRX_P1: CH26.2 UCPU1.C31
PCIE_PTX_CARDRX_N1: CH25.1 JIO1.16
PCIE_PTX_CARDRX_P1: CH26.1 JIO1.14
PCIE_PTX_WLANRX_N4: CH11.1 JNGFF1.29
PCIE_PTX_WLANRX_N4_C: CH11.2 UCPU1.B29
PCIE_PTX_WLANRX_P4: CH16.1 JNGFF1.27
PCIE_PTX_WLANRX_P4_C: CH16.2 UCPU1.A29
PCIE_RCOMP: RH338.2 UCPU1.A27
PCIE_WAKE#: JNGFF1.47 RE86.1 UE5.B8
PECI_EC: RE61.2 UCPU1.N62
PECI_EC_R: CE68.1 RE61.1 UE5.A48
PEG_WIGIGCLK_REQ#: RH107.2 UCPU1.U5
PLTRST#_XDP: JXDP.46 RH363.2
PM_APWROK: RH134.2 UE5.A9
PM_APWROK_R: UC6.4 UCPU1.AB5
PM_SLP_S0#: JAPS.15 PR511.1 RH463.2
PM_SYS_RESET#: JAPS.13 RH450.2 RH451.2
POWER_SW_IN#: CE49.1 RE31.2 RE33.1 UE5.B67
PROC_OPI_COMP: RC154.1 UCPU1.AY15
PS_ID: PR102.1 PR103.2 UE5.B19
PTP_DIS#: JTP1.6 UE4.21
PTP_INT#: DZ3.1 DZ4.1 Q40.1
PTP_INT#_EC: DZ4.2 RPE5.2 UE5.B37
PTP_INT#_R: JTP1.5 Q40.3 R1299.2
PWM1: PU700.6 PU701.8
PWR_DEBUG#_XDP: JXDP.45 R1179.2 UCPU1.H59
PWR_SRC_ON: C613.2 Q70.4 R535.2 R536.1
PWRBTN#_XDP: JXDP.41 R1312.2 RH21.1 RH444.1
PWRBTN_LED#: JIO1.41 UE5.B57
REM_DIODE1_N: CE47.1 CE58.1 QE3.3 UE5.B13
REM_DIODE1_P: CE47.2 CE58.2 QE3.1 QE3.2 UE5.A13
REM_DIODE2_N: CE48.2 CE57.2 CE67.1 QE4.3 QE11.1 QE11.2 UE5.B14
REM_DIODE2_P: CE48.1 CE57.1 CE67.2 QE4.1 QE4.2 QE11.3 UE5.A14
REM_DIODE3_N: CE39.1 CE66.2 QE10.3 UE5.A15
REM_DIODE3_P: CE39.2 CE66.1 QE10.1 QE10.2 UE5.B16
REM_DIODE4_N: CE51.1 CE60.1 QE8.3 UE5.A16
REM_DIODE4_P: CE51.2 CE60.2 QE8.1 QE8.2 UE5.B17
RESET_OUT#: R1353.1 RE2.2 RH452.2 UE5.B39
RESET_OUT#_L: R1353.2 U672.2
RESET_OUT#_R: RH394.2 RH452.1 UCPU1.AY7
RUN_ON: R250.2 UE5.B9
RUN_ON#: QE12.5 QE12.6 RE84.2
RUN_ON_EC: PR410.1 PR411.1 QE12.2 R249.1 R250.1 R269.1 R290.2 R1189.2 U673.16 U719.3 U720.5
RUNPWROK: QE12.3 RE83.2 U697.1 UE5.B26
SATA2_PCIE6_L1: R1021.1 RH467.1 UCPU1.V6
SATA_RCOMP: RH43.1 UCPU1.C12
SATA_RN2/PERN6_L1: CS60.1 UCPU1.J6
SATA_RN2/PERN6_L1_C: CS60.2 JNGFF3.29
SATA_RN3/PERN6_L0: CS61.1 UCPU1.F5
SATA_RN3/PERN6_L0_C: CS61.2 JNGFF3.43
SATA_RP2/PERP6_L1: CS59.1 UCPU1.H6
SATA_RP2/PERP6_L1_C: CS59.2 JNGFF3.31
SATA_RP3/PERP6_L0: CS62.1 UCPU1.E5
SATA_RP3/PERP6_L0_C: CS62.2 JNGFF3.41
SATA_TN2/PETN6_L1: CS58.1 UCPU1.B14
SATA_TN2/PETN6_L1_C: CS58.2 JNGFF3.35
SATA_TN3/PETN6_L0: CS43.1 UCPU1.C17
SATA_TN3/PETN6_L0_C: CS43.2 JNGFF3.47
SATA_TP2/PETP6_L1: CS57.1 UCPU1.C15
SATA_TP2/PETP6_L1_C: CS57.2 JNGFF3.37
SATA_TP3/PETP6_L0: CS42.1 UCPU1.D17
SATA_TP3/PETP6_L0_C: CS42.2 JNGFF3.49
SDIO_CLK: CH1246.1 JNGFF1.9 R1360.2 R1395.2 UCPU1.E3
SDIO_CMD: JNGFF1.11 R1361.2 UCPU1.F4
SDIO_D0: JNGFF1.13 R1362.2 RH434.2 RH435.1 UCPU1.D3
SDIO_D1: JNGFF1.15 R1363.2 UCPU1.E4
SDIO_D2: JNGFF1.17 R1364.2 UCPU1.C3
SDIO_D3: JNGFF1.19 R1365.2 UCPU1.E2
SDIO_RST#: JNGFF1.23 R1328.2 U679.D1
SDIO_RST#_R: R1313.2 R1314.2 U679.A1
SDIO_WAKE#: R1199.1 RH397.2 UCPU1.L3
SDIO_WAKE#_Q: JNGFF1.21 R1327.2 U679.D2
SDIO_WAKE#_R: R1199.2 U679.A2
SIO_EXT_SCI#: RH383.1 UCPU1.N5 UE5.A33
SIO_EXT_SMI#: RH3536.1 UCPU1.AG5 UE5.A6
SIO_EXT_WAKE#: RH3537.1 UCPU1.AU2 UE5.B5
SIO_PWRBTN#: RH444.2 T281.1(TP-1) UCPU1.AL7 UE5.B58
SIO_RCIN#: RH196.1 UCPU1.V4 UE5.A27
SIO_SLP_A#: JAPS.6 UC6.1 UCPU1.AL5 UE5.B28
SIO_SLP_S3#: JAPS.2 PR400.1 PR405.1 PR610.2 R249.2 UCPU1.AT4 UE5.A35
SIO_SLP_S4#: JAPS.5 R252.2 UCPU1.AJ6 UE5.B36
SIO_SLP_S5#: JAPS.4 UCPU1.AP5 UE5.A18
SIO_SLP_SUS#: UCPU1.AP4 UE5.B52
SIO_SLP_WLAN#: UCPU1.AM5 UE5.B45
SKIP#: PR728.2 PU700.7
SKIP#-1: PR728.1 PU701.1
SLEWA: PR700.2 PR710.1 PU700.15
SLP_S0#: RH463.1 UCPU1.AF3
SM_INTRUDER#: RH11.2 UCPU1.AU6
SM_PG_CTRL: PR609.1 RC161.2 UC1.4
SM_RCOMP0: RC55.2 UCPU1.AU60
SM_RCOMP1: RC58.2 UCPU1.AV60
SM_RCOMP2: RC60.2 UCPU1.AU61
SML0CLK: JNFC1.8 RH70.1 UCPU1.AN1
SML0DATA: JNFC1.9 RH72.1 UCPU1.AK1
SML1_SMBCLK: RP2.3 UCPU1.AU3 UE5.B6
SML1_SMBDAT: RP2.4 UCPU1.AH3 UE5.A5
SNB_1.05V: PC502.1 PR502.2
SNUB_1.5V: PC407.1 PR402.2
SNUB_1.8V: PC415.1 PR407.2
SPI_CLK_ROM: MC30.1 RP5.1 U48.6
SPI_CLK_VROM: MC32.1 RP5.2 U727.6
SPI_IO2_ROM: RP8.3 U48.3
SPI_IO2_VROM: RP8.4 U727.3
SPI_IO3_ROM: RP8.2 U48.7
SPI_IO3_VROM: RP8.1 U727.7
SPI_SI_ROM: RP6.1 U48.5
SPI_SI_VROM: RP6.2 U727.5
SPI_SO_ROM: RP7.1 U48.2
SPI_SO_VROM: RP7.2 U727.2
SPK_L+_C: CA55.2 DA3.3 JSPK1.4 L2.2
SPK_L-_C: CA53.2 DA3.2 JSPK1.3 L3.2
SPK_OUT_L+: L2.1 UA2.47
SPK_OUT_L-: L3.1 UA2.48
SPK_OUT_R+: L5.1 UA2.50
SPK_OUT_R-: L4.1 UA2.49
SPK_R+_C: CA56.2 DA4.3 JSPK1.1 L5.2
SPK_R-_C: CA54.2 DA4.2 JSPK1.2 L4.2
SPKR: RA25.1 RH37.2 UCPU1.V2
SS_1.5V: PC406.1 PU400.9
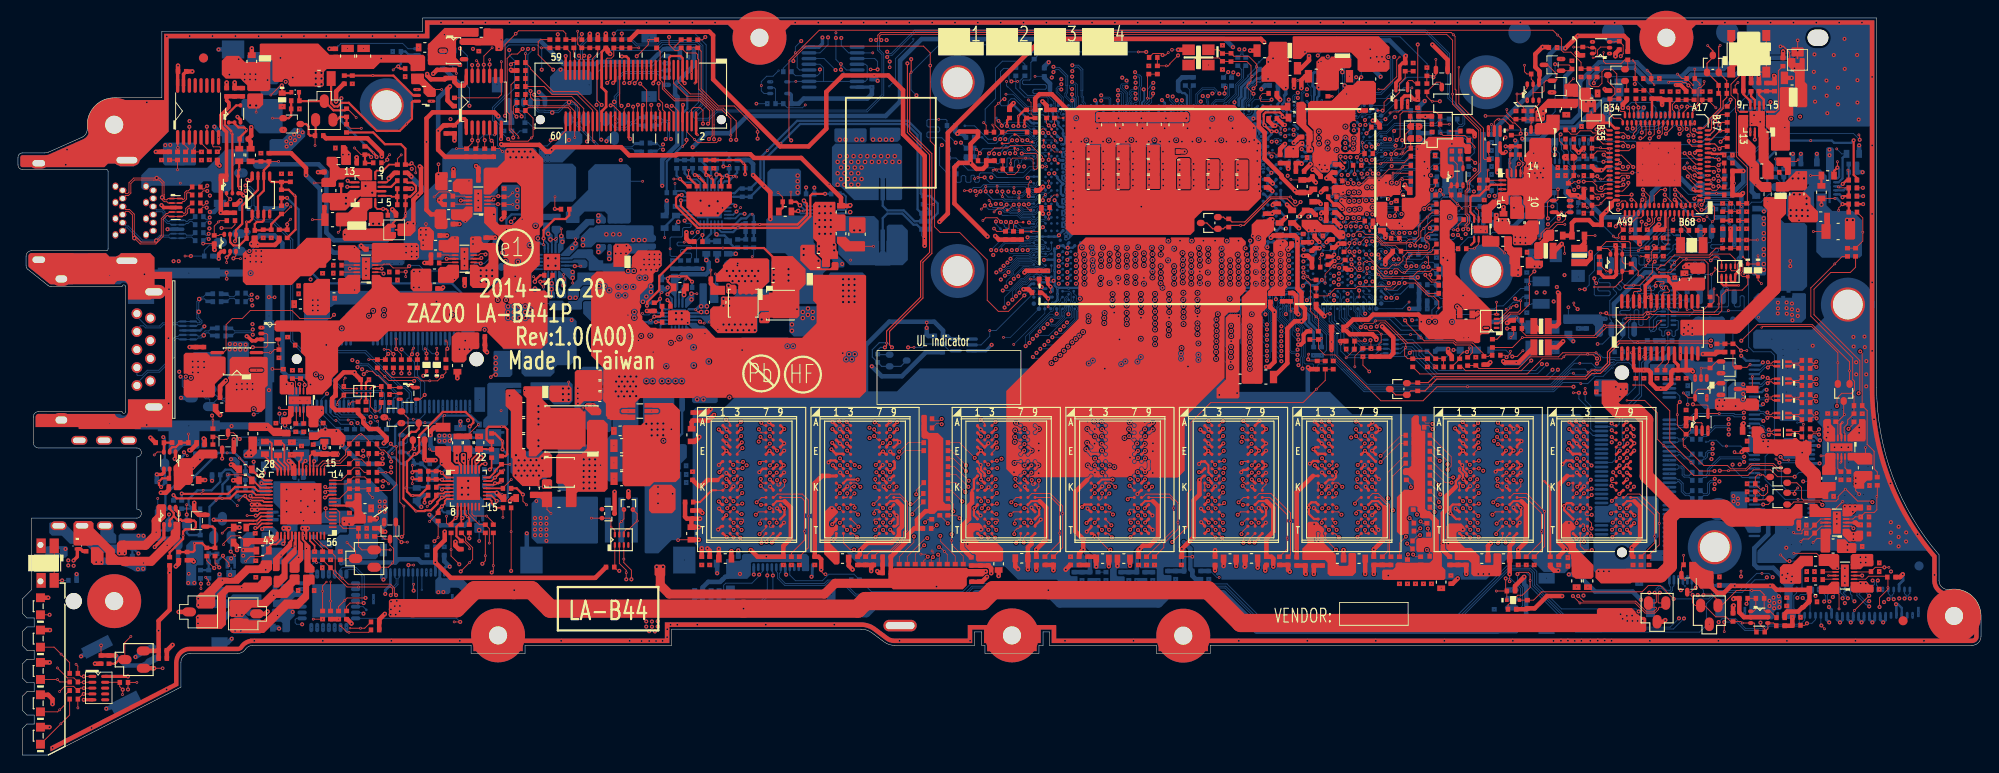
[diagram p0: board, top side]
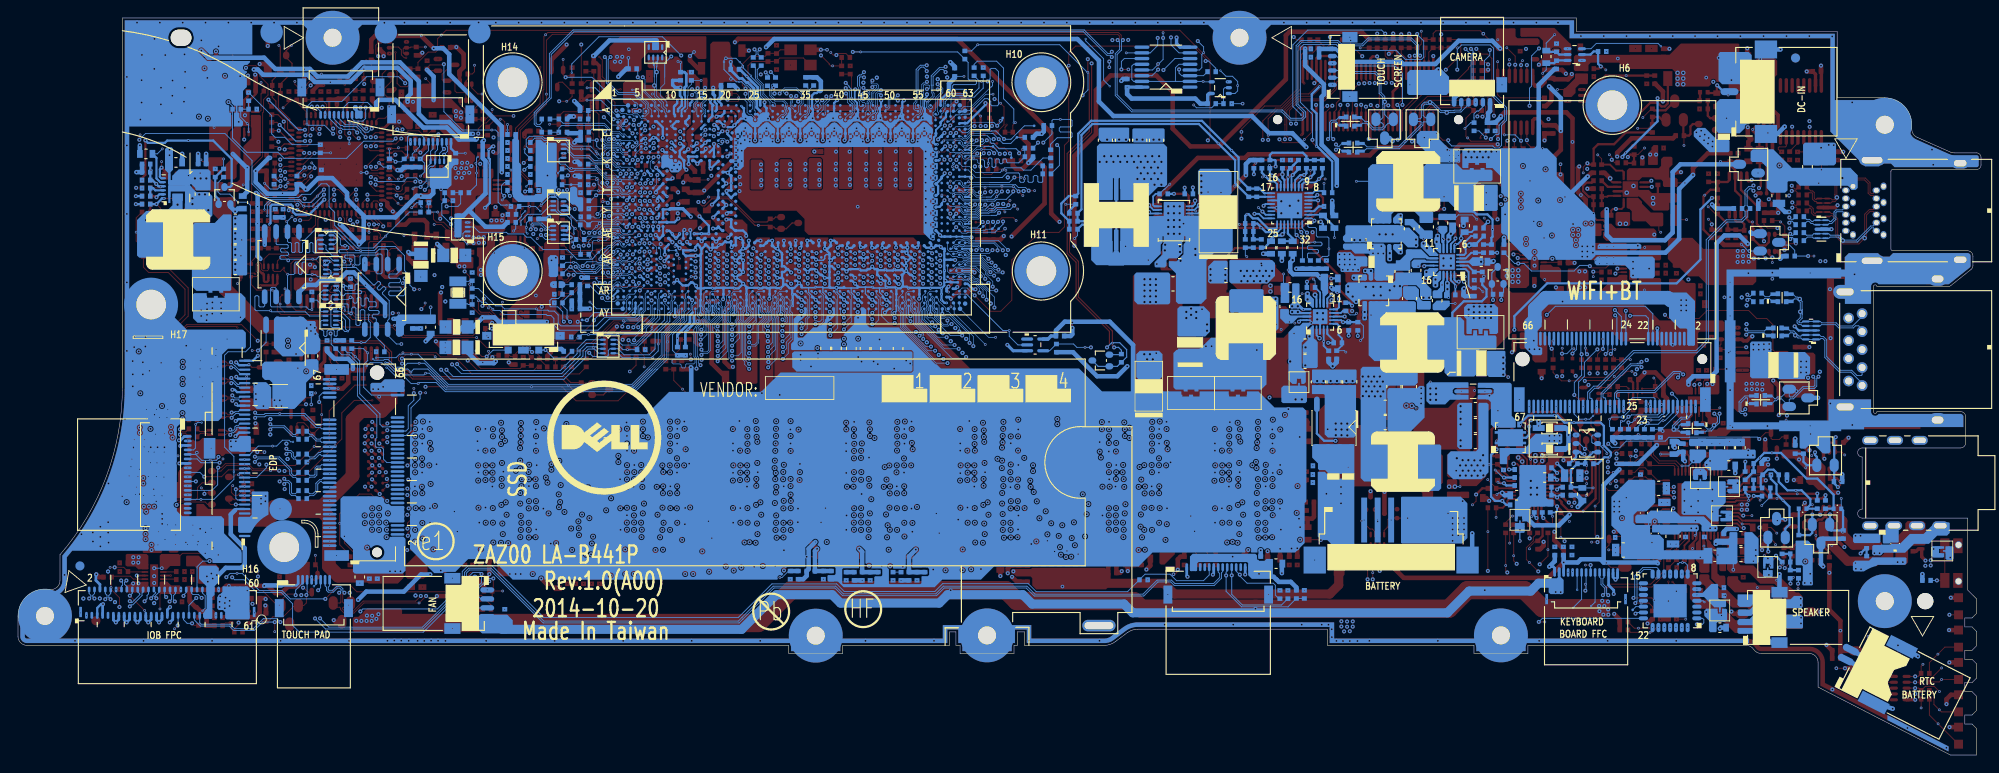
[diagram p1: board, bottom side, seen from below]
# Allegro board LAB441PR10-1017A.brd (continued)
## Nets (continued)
SS_1.8V: PC414.1 PU401.9
SSD_PCIE_WAKE#: JNGFF3.54 R1377.1
SSD_PWREN: R1181.1 R1189.1 RH431.1 U682.4 U717.5
SUS_ON: R251.2 UE5.B23
SUS_ON_EC: PR608.1 R251.1 R252.1 RE68.1
SUS_PWR_DN: RH154.1 RH297.1 UCPU1.AV4
SUS_STAT#/LPCPD#: RH197.1 UCPU1.AG4
SUSACK#: RH430.2 UE5.A23
SUSACK#_R: RH430.1 UCPU1.AK2
SUSCLK: CH102.2 RH132.2 UCPU1.AE6
SUSCLK_R: R1255.2 R2662.2 RH132.1
SW_1.5V: PL401.1 PR402.1 PU400.1 PU400.2 PU400.3
SW_1.8V: PL403.1 PR407.1 PU401.1 PU401.2 PU401.3
SW_1.35V: PC604.2 PL601.1 PQ600.1 PQ600.2 PQ600.3 PQ601.5 PR602.1 PU600.16
SYS_PWROK: R1309.2 RH455.2 UE5.B7
SYS_RESET#: RH450.1 RP20.1 UCPU1.AC3
SYS_RESET#_XDP: C1237.1 JXDP.48 RH367.2 RH451.1
TD_IREF: RC155.1 UCPU1.B12
TESTLOW1: RH36.2 UCPU1.C35
TESTLOW2: RH41.2 UCPU1.C34
TESTLOW3: RH44.2 UCPU1.AK8
TESTLOW4: RH45.2 UCPU1.AL8
THERMATRIP2#: CE61.1 QE9.1 RE69.2 UE5.B34
THERMATRIP3#: RE67.1 UE5.A2
THSEL_STRAP: RE78.1 UE5.B29
TON_1.35V: PR606.2 PU600.9
TOUCH_PANEL_INTR#: JTS.5 RH3548.1 UCPU1.P3
TOUCH_RST_N_GYRO_INT1: RH3545.2 UCPU1.L1
TOUCHPAD_INTR#: DZ3.2 RP4.6 UCPU1.U7
TP_PW_EN: R1175.2 U716.3 UE4.24
TPM_PIRQ#: RH3534.1 U652.20 UCPU1.T3
TPM_RESET#_TPM: RH474.1 U652.16
UART1_CTS#: RH460.1 U671.10 UCPU1.J4
UART1_CTS#_NGFF: JNGFF1.26 R1372.2 U671.5
UART1_RTS#: RH459.1 U671.11 UCPU1.J3
UART1_RTS#_NGFF: JNGFF1.28 R1375.2 U671.4
UART1_RXD: RH457.1 U671.12 UCPU1.K4
UART1_RXD_NGFF: JNGFF1.22 R1374.2 U671.3
UART1_TXD: RH458.1 U671.13 UCPU1.G2
UART1_TXD_NGFF: JNGFF1.24 R1373.2 U671.2
UART_WAKE#: JNGFF1.20 RH382.1 UCPU1.AM3
UG_3V: PQ300.2 PU300.10
UG_5V: PQ301.2 PU300.16
USB0_DET#: CE22.1 JIO1.36 RE34.2
USB0_DET_EC#: CE56.1 RE34.1 RE36.2 UE5.B63
USB0_PWR_EN: RH400.1 UCPU1.AM2
USB0_PWR_EN_EC: JIO1.39 RE60.1 UE5.A50
USB1_EN: R1216.1 U699.4 US2.4
USB1_PWR_EN: RH95.2 U699.1 UCPU1.Y5
USB1_PWR_EN_EC: RE59.1 U699.2 UE5.A43
USB3RN0: JIO1.2 UCPU1.G20
USB3RN1: ML13.1 R560.1 UCPU1.E18
USB3RN1_RC_CON: DI1.1 DI1.10 JUSB1.5 ML13.2 R560.2
USB3RP0: JIO1.4 UCPU1.H20
USB3RP1: ML13.4 R565.1 UCPU1.F18
USB3RP1_RC_CON: DI1.2 DI1.9 JUSB1.6 ML13.3 R565.2
USB3TN0: JIO1.8 UCPU1.C33
USB3TN1: C621.1 UCPU1.B33
USB3TN1_C: C621.2 ML12.1 R555.1
USB3TN1_RC_CON: DI1.4 DI1.7 JUSB1.8 ML12.2 R555.2
USB3TP0: JIO1.10 UCPU1.B34
USB3TP1: C623.1 UCPU1.A33
USB3TP1_C: C623.2 ML12.4 R556.1
USB3TP1_RC_CON: DI1.5 DI1.6 JUSB1.9 ML12.3 R556.2
USB20_N0: JIO1.34 UCPU1.AN8
USB20_N1: ML11.4 R222.1 UCPU1.AR7
USB20_N1_CONN: DI2.2 JUSB1.2 ML11.3 R222.2
USB20_N2: ML10.4 R742.1 UCPU1.AR8
USB20_N2_R: JNGFF1.5 ML10.3 R742.2
USB20_N3: ML9.1 R1012.1 UCPU1.AR10
USB20_N3_CONN: DI4.2 JTS.3 ML9.2 R1012.2
USB20_N4: L55.1 R1005.1 UCPU1.AM15
USB20_N4_CONN: DI3.2 JCAM.4 L55.2 R1005.2
USB20_P0: JIO1.32 UCPU1.AM8
USB20_P1: ML11.1 R262.1 UCPU1.AT7
USB20_P1_CONN: DI2.3 JUSB1.3 ML11.2 R262.2
USB20_P2: ML10.1 R741.1 UCPU1.AP8
USB20_P2_R: JNGFF1.3 ML10.2 R741.2
USB20_P3: ML9.4 R1013.1 UCPU1.AT10
USB20_P3_CONN: DI4.3 JTS.2 ML9.3 R1013.2
USB20_P4: L55.4 R1004.1 UCPU1.AL15
USB20_P4_CONN: DI3.3 JCAM.5 L55.3 R1004.2
USB_OC0#: JIO1.24 RP21.1 T289.1(TP-1) UCPU1.AL3
USB_OC1#: RP21.2 T290.1(TP-1) UCPU1.AT1 US2.5
USB_OC2#: RP21.3 T291.1(TP-1) UCPU1.AH2
USB_OC3#: RP21.4 T292.1(TP-1) UCPU1.AV3
USB_PWR_SHR_EN#: JIO1.18 UE5.B38
USBRBIAS: RH163.1 UCPU1.AJ10 UCPU1.AJ11
V_DDR_REF_CA: CD43.1 RD15.2 UCPU1.AP49
V_DDR_REF_DQA: CD76.1 RD121.2 UCPU1.AR51
V_DDR_REF_DQB: CD39.1 RD20.2 UCPU1.AP51
VCI_IN3#: RPE5.3 UE5.B68
VR_ON: PR716.2 RC151.1 RC201.2
VR_ON_MCP: RC151.2 UCPU1.F60
VR_SVID_ALRT#: PU700.32 RC93.1 RC94.1
VR_SVID_CLK: PR726.2 PU700.31 RC92.1
VR_SVID_DAT: PR727.2 PU700.1 RC96.1
VREF: PC713.1 PH700.1 PR700.1 PR702.1 PR703.1 PR704.1 PR718.2 PU700.27
VRPG_MCP: RC152.2 UCPU1.C59
VSET_5085: CE55.1 RE77.1 UE5.A17
VTTREF_1.35V: PC610.1 PU600.4
WLAN_WIGIG60GHZ_DIS#: DZ1.1 RE14.2 UE4.22
WLAN_WIGIG60GHZ_DIS#_R: DZ1.2 JNGFF1.48
WLANCLK_REQ#: JNGFF1.45 RH103.2 UCPU1.N1
XCLK_BIASREF: RH113.1 UCPU1.C26
XDP_BPM0#: JXDP.21 UCPU1.J60
XDP_BPM1#: JXDP.23 UCPU1.H60
XDP_PIN60: JXDP.60 R1198.1
XDP_PRDY#: JXDP.5 T263.1(TP-1) UCPU1.J62
XDP_PREQ#: JXDP.3 T264.1(TP-1) UCPU1.K62
XDP_PWRGD: JXDP.39 R1180.1
XDP_TCK0: JXDP.57 RH374.1 RH411.1 RH446.1
XDP_TCK1: JXDP.55 RH373.1
XDP_TDI: JXDP.56 RH371.1 RH414.1
XDP_TDI_SWITCH: RH413.1 RH414.2 U663.10
XDP_TDO: JXDP.52 RH369.1 RH412.1 U663.13
XDP_TMS: JXDP.58 RH372.1 U663.7
XDP_TRST#: JXDP.54 U663.4
XTAL24_IN: CH23.1 RH117.2 UCPU1.A25 YH2.3
XTAL24_OUT: CH24.1 RH117.1 UCPU1.B25 YH2.1
N15438178: PD200.1 PD201.1 PR207.1
N15438615: PR208.2 PU200.3
N15438635: PC207.2 PQ206.1 PR209.1 PR210.1 PU200.6
N15438982: PR212.2 PR213.2 PR215.1 PU200.5
N15439291: PC216.2 PR214.2 PU200.7
N15439295: PC217.2 PR217.2 PU200.8
N15439512: PC218.2 PR218.2 PR229.1 PU200.9
N15440461: PR216.2 PU200.10
N15440728: PR223.2 PR225.1 PU200.16
N15440949: PR224.2 PU200.15
N15441413: PR220.1 PU200.18
N15442134: PC225.2 PC226.1 PR219.3 PU200.20
N15442185: PC226.2 PC227.1 PR219.2 PU200.19
N17209367: PR204.2 PU200.4
N17617073: PC201.1 PQ201.4 PQ202.4 PR208.1
N17617210: PQ201.2 PR203.1
N17617229: PC200.2 PC201.2 PQ202.3 PR203.2 PR204.1
N17617792: PQ202.1 PQ202.2
N18244124: PC224.1 PR221.2
N18292747: PQ100.2 PQ101.1 PR105.1
N20931556: PC223.1 PR222.1 PU200.17
N22878624: PL102.1 PQ100.1 PR101.1 PR104.2
N22878630: PQ100.3 PR101.2 PR103.1
N22878645: PQ101.2 PR104.1 PR106.2
N35032609: CH1206.1 UCPU1.AE7
N36180324: CH1218.1 RH346.2
N40621945: Q71.1 R536.2
N41482702: R1188.1 U671.8
N42993790: R1131.1 U679.C2
N45882743: CD76.2 RD120.1
N45903736: CD39.2 RD39.1
N45904045: CD43.2 RD40.1
N45914047: RD29.1 UD28.L8
N45914636: RD31.1 UD28.L9
N45918085: RD30.1 UD29.L8
N45918691: RD32.1 UD29.L9
N45921974: RD51.1 UD31.L8
N45922752: RD53.1 UD31.L9
N45924822: RD52.1 UD32.L8
N45925462: RD55.1 UD32.L9
N45927684: RD11.1 UD1.L8
N45928611: RD17.1 UD1.L9
N45930311: RD12.1 UD7.L8
N45931155: RD19.1 UD7.L9
N45933314: RD41.1 UD3.L8
N45934478: RD42.1 UD3.L9
N45936647: RD54.1 UD4.L8
N45937458: RD56.1 UD4.L9
N48029100: PC612.1 PR602.2
N48038074: PC409.1 PC412.1 PC413.1 PL402.2 PU401.10 PU401.11 PU401.12
N48057312: PC701.1 PH700.2 PR705.1 PU700.14
N48058030: PC709.2 PC712.2 PR718.1 PR719.2 PU700.26
N48058050: PC711.1 PR717.2
N48058064: PC707.1 PR714.1
N48058078: PC709.1 PR719.1 PR720.1 PU700.25
N48058128: PC708.1 PR715.1 PU700.2
N48058201: PR714.2 PU701.6
N48058203: PC707.2 PU701.7
N48058249: PC714.1 PR721.2 PU700.28
N48058265: PH701.2 PR725.1
N48058354: PR711.2 PU700.16
N48095930: PL301.1 PQ300.5 PQ300.6 PQ300.7 PR309.1
N48096052: PR306.1 PU300.19
N48096170: PL304.1 PQ301.5 PQ301.6 PQ301.7 PR310.1
N48096331: PC305.2 PR307.1
N48096357: PC309.1 PR309.2
N48096365: PC310.1 PR310.2
N48096405: PC311.1 PU300.13
N48096452: PC306.1 PR308.2
N48756972: D122.1 RTCR1.1
N49522242: PC203.2 PC204.1 PR206.1 PU200.1
N49522275: PC202.2 PC203.1 PR205.1 PU200.2
N49570867: PC500.1 PR500.1 PR501.1 PU500.1
N49570895: PC515.2 PR505.2 PR508.1 PR509.1 PU500.4
N49571010: PC513.1 PU500.5
N49571039: PC505.1 PR503.2
N49753304: QA1.2 QA1.5 QA9.1 RA16.2
N49753333: QA9.2 RA18.2 RA32.2 RA41.1 RA57.2
N49753452: QA3.3 RA37.2 RA39.1
N49753456: CA40.1 QA3.2 RA39.2
N49755927: CA33.1 CA34.1 R7.1 RA24.2 RA25.2
N49756069: CA91.1 CA92.1 UA2.21
N49756116: CA93.1 UA2.44
N49756130: CA94.1 UA2.40
N49756142: CA95.1 UA2.25
N49756144: CA95.2 UA2.26
N49756158: CA96.2 UA2.28
N49756160: CA96.1 UA2.27
N49756189: RA45.1 UA2.53
N49756342: CA106.1 RA75.2 RA76.2 UA2.9
N49757206: CA48.1 CA49.1 UA2.18
N49757319: CA84.1 UA2.29
N49757329: CA85.1 UA2.31
N49981925: DA6.3 RA48.1
N49981929: DA6.2 RA49.1
N49981946: DA1.2 JHP1.5 RA19.2 RA30.1
N50106861: PR311.2 PR312.2 PU300.7
N50165058: PQ409.4 PR447.2 PR448.2 PU404.7
N50165456: PC323.1 PR449.1 PR456.1 PR457.2 PU404.3
N50165462: PQ409.5 PR449.2 PR455.2 PU404.1
N50170477: PC51.1 PQ409.2 PU405.4
N50170488: PC51.2 PR452.1 PU406.1 PU406.2
N50183034: PC109.2 PQ102.5 PR113.1
N50183040: PC109.1 PQ102.6 PR111.2
N50183045: PQ102.2 PR110.2 PR112.1
N50183053: PQ103.6 PR109.2
N50183055: PQ103.2 PQ103.3 PR108.2 PR116.1
N50183068: PC110.1 PQ103.5 PR114.2
N50196545: PU405.2 PU406.4
N50196918: PQ409.3 PR450.2 PU405.1
N50197891: PC302.1 PR445.2 PR447.1 PR451.1 PU404.5
N50203343: PQ409.6 PR319.1 PR461.1
N50357872: PR716.1 PU700.8
N51562919: QA7.2 QA8.1 RA81.2
N51667837: UC1.2 UCPU1.AV61
N51667853: T226.1(TP-1) UCPU1.H61
N51667855: T227.1(TP-1) UCPU1.H62
N51667857: T228.1(TP-1) UCPU1.K59
N51667859: T229.1(TP-1) UCPU1.H63
N51667861: T231.1(TP-1) UCPU1.J61
N51667863: T230.1(TP-1) UCPU1.K60
N51669561: T123.1(TP-1) UCPU1.AD4
N51988520: R1324.2 R1325.1 U697.2
N52012553: RE57.1 RE63.1 UE5.A59
N52091760: QE9.2 RE70.2
N52092863: CE52.1 RE80.2
N52116668: RE64.1 UE5.B61
N52142235: C1242.1 U673.1
N52142257: C1244.2 R1190.2 R1331.2 U673.6 U673.7 U673.8
N52142406: C1244.1 U673.17
N52362332: T124.1(TP-1) UE5.A42
N52475187: JNGFF1.30 R1200.1 R1208.1
N52475198: JNGFF1.32 R1210.1
N52475202: JNGFF1.34 R1212.1
N52475209: JNGFF1.58 R1209.1
N52475257: JNGFF1.42 R1255.1
N52558730: RE22.2 UE4.13
N52558748: RE23.2 UE4.12
N52558768: RE27.2 UE4.11
N52571191: RE24.2 UE4.14
N52708219: D81.1 JFAN1.2 R886.1
N52717341: RH134.1 RH135.1 UC6.2
N52717591: RH455.1 UCPU1.AG2
N52759096: QA7.1 RA87.2
N52893126: T125.1(TP-1) UE4.19
N52893865: R1343.1 U716.8 U716.9
N52893895: R1323.1 U716.13 U716.14
N52893916: C1258.1 U716.10
N52894141: C1257.1 U716.12
N52895521: C1202.1 U718.12
N52895617: R2671.1 U718.8 U718.9
N52895619: C1281.1 U718.10
N52895657: R2670.1 U718.13 U718.14
N52922903: R1326.1 U717.8 U717.9
N52922958: R1342.1 U717.13 U717.14
N52922960: C1292.1 U717.10
N52923110: C1163.1 U717.12
N52925836: R1320.1 U719.8 U719.9
N52925896: R2669.1 U719.13 U719.14
N52925901: C1278.1 U719.10
N52926051: C355.1 U719.12
N52930519: R1329.1 U720.8 U720.9
N52930575: R1344.1 U720.13 U720.14
N52930580: C1293.1 U720.10
N52930730: C1167.1 U720.12
N52934489: R1125.1 U664.8 U664.9
N52934545: R1318.1 U664.13 U664.14
N52934547: C1214.1 U664.10
N52934693: C1212.1 U664.12
N52950077: C1227.1 Q360.4 R1379.2 R1380.2
N52950154: Q361.6 R1380.1
N52950156: Q361.3 R1379.1
N52950610: R1190.1 U673.15
N53211236: PR729.2 PR730.1 PR731.1
N53261040: R8.2 U652.9
N53261043: R9.2 U652.8
N53262018: PC712.1 PR720.2
N53314393: PR226.2 PU200.11
N53314401: PR227.2 PU200.12
N53579675: R1321.1 U715.8 U715.9
N53579693: R1322.1 U715.13 U715.14
N53579718: C1247.1 U715.10
N53579746: C1230.1 U715.12
N54037762: PR228.1 PU200.21
N54037942: Q360.1 Q360.2 Q360.3 R1330.1
N54049002: PQ500.2 PR510.2 PR511.2
N54049152: PQ500.1 PR509.2
N54084321: PR315.1 PU300.20
N54220793: R253.1 UE5.B49
N54285564: C218.1 U34.6
N54285570: R307.1 U34.7 U34.8
N54529025: JNGFF3.60 R2662.1
N55276904: RC9.2 SW4.1
N55667469: PR413.1 PU401.7
N55667799: PR412.1 PU400.7
N93297419: Q305.2 U708.4
N93297423: Q305.1 R541.2

Pads without a net: FD1 1; FD2 1; FD3 1; FD4 1; H26 1; JAPS 16 17 18; JDEG1 9; JEDP 1 6; JIO1 3 9 51; JNFC1 4 5 13; JNGFF1 6 8 10 12 14 16 36 38 40 50 51 52 53 54 56 57 59 60 62 63 65; JNGFF3 5 6 7 8 10 11 13 17 19 20 22 23 24 25 26 28 30 32 34 36 40 42 44 46 48 56 58 59; JXDP 40 42; PD100 2; PRP100 4 5; PU200 13 14; PU700 4 5 21 22; RP5 4 5; RP6 4 5; RP7 4 5; RP13 6 7 8; RP14 1 4 5 8; RP16 1 8; RP20 2 7; U652 5 6 7 13 14 15 27 28; U663 1 9; U671 6 9; U672 1; U682 1; U683 1; U708 1; UA2 1 2 4 5 8 55 56; UC1 1; UCPU1 A4 A5 A6 A8 A15 A17 A21 A23 A31 A35 A39 A41 A51 A53 A60 A62 AA23 AA59 AB21 AB23 AC4 AC20 AC58 AC59 AD23 AD59 AD60 AE59 AE60 AF20 AG58 AJ7 AK38 AL1 AL11 AL32 AL38 AM10 AM11 AM13 AN10 AN11 AN13 AP7 AP11 AP13 AP32 AR13 AT2 AU10 AU12 AU15 AU44 AU63 AV1 AV2 AV10 AV44 AV50 AV62 AV63 AW1 AW10 AW14 AW36 AW49 AW63 AY8 AY14 AY36 AY42 AY43 AY60 B2 B6 B15 B17 B21 B22 B23 B30 B31 B35 B39 B41 B42 B43 B50 B51 B53 B54 C21 C22 C23 C29 C41 C49 C50 C51 C53 C62 C63 D1 D9 D11 D15 D58 D61 E1 E6 E8 E10 E13 E15 F6 F8 F10 F11 F15 F22 G10 G11 G15 H5 H8 H10 H18 H22 J5 J8 J20 J21 J58 K10 K18 K21 L11 L59 L60 M20 M21 N23 N58 N59 N60 N61 P20 P60 P61 R20 R23 T23 T59 U10 U59 V21 V59 W23 Y20 Y22; UE4 2 3 7 10 15 16 17 18 29; UE5 B15 B42 B62; UV1 9 10 11 12 13 14

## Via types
v1: diameter 0.457, hole 0.203, TOP to BOTTOM, 3118 vias
v2: diameter 0.305, hole 0.152, TOP to BOTTOM, 635 vias
v3: diameter 0.254, hole 0.102, TOP to GND1, 418 vias
v4: diameter 0.406, hole 0.203, GND1 to GND3, 723 vias
v5: diameter 0.254, hole 0.102, GND3 to BOTTOM, 446 vias
v6: diameter 0.406, hole 0.203, TOP to BOTTOM, 112 vias
v7: diameter 0.508, hole 0.254, TOP to BOTTOM, 436 vias

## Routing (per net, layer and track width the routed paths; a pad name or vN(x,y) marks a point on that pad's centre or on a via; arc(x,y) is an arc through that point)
1.2V_DDR_PWROK: length 3.2
  TOP w0.102: v1(71.4,50.75) 71.4,51.27 v2(71.59,51.46)
  TOP w0.203: PR604.2 70.97,50.32 v1(71.4,50.75)
  BOTTOM w0.203: PU600.10 72.01,49.58 71.62,49.58 71.4,49.8 v1(71.4,50.75)
1.05V_M_PWRGD: length 50.6
  TOP w0.102: PR512.1 v1(205.17,63.1) ; v1(204.82,68.45) 204.82,68.91 v2(204.73,69)
  IN4 w0.102: v1(204.82,68.45) 204.31,67.94 204.31,64.16 205.17,63.29 v1(205.17,63.1)
  BOTTOM w0.102: RH135.2 174.78,60.41 178.78,56.41 180.56,56.41 183.09,58.94 183.09,60.38 183.71,61 183.71,63.28 183.97,63.55 184.6,63.55 185.77,62.38 186.75,62.38 187.1,62.02 190.75,62.02 192.28,63.56 192.28,66.14 195.29,69.15 204.12,69.15 v1(204.82,68.45)
1.05VA_PG: length 3.8
  TOP w0.102: PR512.2 202.54,63.1 v2(202.44,63.2)
  TOP w0.254: v1(202.91,62.05) 203.04,62.18 PR506.2 203.6,62.18 PR512.2
  BOTTOM w0.254: v1(202.91,62.05) 202.59,62.38 PU500.2
1.5VS_PWROK: length 6
  TOP w0.102: PU400.4 195.1,71.56 195.1,71.56 195.47,71.56 195.78,71.87 195.78,76.13 PR404.1
1.05VS_VCCST_PG: length 79.7
  TOP w0.102: v3(160.24,76.52) 160.24,72.47 162.97,69.74 162.97,66.4 163.12,66.24 R1132.2 163.59,66.83 163.53,66.89 163.53,67.52 163.53,67.52 U672.4 ; v1(125.47,78.22) v2(124.6,78.22)
  GND1 w0.102: v3(160.24,76.52) 160.24,76.82 v4(160.35,76.94)
  IN2 w0.076: 135.98,75.43 135.86,75.31 128.6,75.31 128.48,75.43
  IN2 w0.086: v4(160.35,76.94) 159.57,77.72 155.34,77.72 154.39,78.67 153.26,78.67 153.16,78.57 150.95,78.57 148.44,76.06 136.61,76.06 135.98,75.43 ; 128.48,75.43 127.72,76.2 127.72,78.09 127.36,78.45 125.7,78.45 v1(125.47,78.22)
  BOTTOM w0.076: UCPU1.B59 115.7,71.81 115.37,72.14 115.37,72.83 115.21,72.99
  BOTTOM w0.102: v1(125.47,78.22) 113.81,78.22 R1180.2 112.64,77.05 112.64,75.22 112.51,75.1 111.84,75.1 111.71,74.97 111.71,74.72 111.84,74.59 114.24,74.59 114.37,74.46 114.37,74.19 114.24,74.07 113,74.07 112.87,73.94 112.87,73.7 113,73.57 114.63,73.57 115.21,72.99
1.8VS_PWROK: length 2.6
  TOP w0.203: PR409.1 41.12,60.57 40.95,60.75 v1(40.61,60.75) 39.97,60.75 39.74,60.98 PU401.4
1.35V_B+: length 19.2
  TOP w0.254: 84.04,55.32 82.96,56.4 v2(78.4,56.4) 74.45,56.4 71.32,53.27 71.32,51.74 69.98,50.41 69.98,50.23 69.94,50.19 v1(69.94,49.99)
  BOTTOM w0.254: PR606.1 70.27,50.32 v1(69.94,49.99)
  vias: v7(84.04,54.05) v7(84.04,53.42) v7(84.04,52.78) v7(85.69,54.05) v7(85.69,53.42) v7(85.69,52.78)
3.3V_MSATA_EN: length 21
  TOP w0.076: 153.27,71.55 152.7,71.55 v2(152.58,71.43)
  TOP w0.102: U682.2 153.89,71.9 153.54,71.55 153.27,71.55
  TOP w0.381: U682.2 153.89,73.02 154.2,73.33 154.87,73.33 155.27,72.92 v3(155.67,72.92)
  TOP w0.508: RH431.2 v3(155.67,72.92)
  GND1 w0.254: v4(155.11,72.81) 155.23,72.92 v3(155.67,72.92)
  IN2 w0.508: 145.89,66.84 145.89,66.12 146.62,65.39 146.62,64.2 146.87,63.95 147.43,63.95 147.91,64.43 v1(147.91,64.53)
  IN3 w0.508: v4(155.11,72.81) 154.58,72.28 148.52,72.28 147.63,71.39 v1(147.63,69.92)
  BOTTOM w0.254: UCPU1.N6 148.32,64.94 v1(147.91,64.53)
3.3V_TS_EN: length 122.6
  TOP w0.102: U718.5 52.56,62.09 52.65,62.18 v1(53.41,62.18) 53.99,62.18 R1162.1 54.57,62.1 v2(55.02,62.56)
  IN1 w0.071: v4(48.73,62.84) 52.75,62.84 v1(53.41,62.18)
  IN3 w0.086: v1(147.63,66.51) 147.63,66.73 147.03,67.33 147.03,69.16 146.65,69.54 146.65,70.34 145.8,71.19 141.64,71.19 141.41,71.41 132.48,71.41 131.98,70.92 130.48,70.92 130.18,71.22 108.11,71.22 106.67,69.78 102.13,69.78 100.23,71.69 80.7,71.69 78.98,73.41 59.13,73.41 58.23,72.51 54,72.51 52.51,71.02 51.56,71.02 51.07,70.52 50.59,70.52 48.92,68.86 48.92,63.03 v4(48.73,62.84)
  BOTTOM w0.076: UCPU1.N7 148,65.32 148,66 147.63,66.37 v1(147.63,66.51)
3/5V_B+: length 73.4
  TOP w0.254: PR457.1 PR445.1 v1(29.93,61.98)
  IN4 w0.254: v1(67.67,56.66) 67.71,56.7 71.66,56.7 72.18,56.19 72.18,53.65 71.72,53.19 71.72,51.74 70.93,50.95 70.93,49.63 69.83,48.53 69.83,44.59 68.75,43.51 66.23,43.51 65.65,42.93 58.64,42.93 58.31,43.26 58.31,46.54 57.92,46.94 52.27,46.94 v1(51.9,47.31)
  BOTTOM w0.254: v1(29.93,61.98) 31.21,60.69 31.21,55.12 33.85,52.48 48.25,52.48 51.9,48.83 v1(51.9,47.31)
  vias: v1(66.47,55.79) v1(67.05,55.81) v1(67.62,55.81) v1(67.62,55.21) v1(68.02,56.21) v6(66.69,56.61)
3V/5VALW_EN: length 10.8
  TOP w0.102: v2(57.33,53.22) 57.49,53.07 57.49,52.79
  TOP w0.254: PR315.2 58.07,53.37 57.49,52.79 v7(57.49,52.66)
  IN3 w0.254: v7(57.49,52.66) 57.5,52.68 57.5,53.22 57.88,53.6 57.88,57.42 v7(57.81,57.48)
  BOTTOM w0.203: PR314.2 56.24,58.6 56.66,58.18 56.68,58.18 56.68,58.18 PC312.1 57.81,57.8 v7(57.81,57.48) 57.81,57.23 58.2,56.85 58.45,56.85 58.57,56.73 58.57,56.34 PU300.6
+0.675VS: length 102.7
  TOP w0.508: 99.98,25.21 99.67,25.21 99.04,24.58 99.04,24 97.08,22.05 CD139.1 CD136.1 CD140.1 ; 99.98,25.21 RD86.2 ; 99.98,25.21 99.98,26.18 100.93,27.13 101.6,27.13
  TOP w1.016: 71.43,20.09 71.43,18.91 72.43,17.91 89.68,17.91 90.87,19.1 97.27,19.1
  IN2 w0.508: v1(152.39,19.97) 151.6,19.17 125.77,19.17 125.66,19.06 114.72,19.06 113.84,19.95 110.41,19.95 109.53,20.82 108,20.82 v1(107.61,20.44)
  IN4 w1.016: 71.48,21.85 74.86,25.22 74.86,35.89 75.89,36.92 75.89,38.74
  vias: v6(102.15,18.74) v7(71.04,20.93) v7(71.73,20.93) v7(75.53,39.56) v7(76.23,39.56)
+0.675VSP: length 6.1
  IN2 w0.254: v7(76.83,43.79) 76.82,43.79 76.82,44.95 75.68,46.09 73.84,46.09 v7(73.56,46.37)
  BOTTOM w0.203: v7(73.56,46.37) 73.89,46.7 73.89,47.29 PU600.2
  vias: v2(76.4,46.9)
+1.5V_B+:
  vias: v2(193.26,63.43)
+1.05V_M: length 181.2
  TOP w0.102: v6(20.59,56.9) 20.59,56.89 PR319.2
  TOP w0.508: v1(108.68,57.74) 109.08,57.34 RH39.1 RH40.1 RH445.1 ; v1(21.86,56.21) 21.82,56.24 PR319.2
  IN1 w0.508: v4(75.65,55.01) 75.65,55.13 76.26,55.74 v4(78.22,55.74)
  IN2 w0.508: v1(71.65,63.34) 71.51,63.2 71.51,58.74 75.23,55.01 v4(75.65,55.01) ; v1(143.55,58.4) 143.55,58.24 143.18,57.88 140.42,57.88 139.91,58.38 136.99,58.38 136.47,57.86 127.61,57.86 126.92,57.16 114.9,57.16 114.64,56.89 110.05,56.89 109.2,57.74 v1(108.68,57.74) 107.71,58.71 102.03,58.71 97.08,53.77 88.02,53.77 86.64,55.14 78.82,55.14 v4(78.22,55.74)
  IN3 w0.508: v4(74.7,79.07) 74.2,79.07 72.81,80.46 69.37,80.46 68.48,79.57 47.13,79.57 43.43,75.87 37.58,75.87 31.86,70.14 27.4,70.14 25.53,68.28 24.08,68.28 v4(21.65,65.85)
  IN4 w0.508: v4(21.65,65.85) 21.65,65.41 20.14,63.91 20.14,57.33 21.27,56.21 v1(21.86,56.21)
  GND3 w0.508: v5(75.16,78.61) v4(74.7,79.07)
  BOTTOM w0.203: UCPU1.AG14 143.51,58.36 v1(143.55,58.4) ; UCPU1.AE9 UCPU1.AF9 ; UCPU1.AG13 144.33,58.29 v1(144.2,58.42)
  BOTTOM w0.254: v1(147.39,57.87) 147.39,57.88 147.02,57.51 UCPU1.AG8 146.57,57.81 UCPU1.AF9
  BOTTOM w0.508: v1(71.65,63.34) 71.65,66.22 73.33,67.91 73.33,73.23 73.08,73.48 73.08,74.62 75.16,76.7 v5(75.16,78.61)
  vias: v1(166.83,53.97) v1(166.82,53.4)
+1.05V_PCH: length 52.1
  TOP w0.508: v1(171.26,51.46) 171.37,51.35 171.37,48.01 171.06,47.71 L63.2 ; RH405.1 141.09,72.02 138.51,72.02 137.99,71.5 137.99,69.91 138.64,69.26 138.64,66.34 140.52,64.46 140.52,64.28 v1(141.99,62.81) 142.22,62.58 RH407.2 143.68,62.58 RH408.1
  IN1 w0.508: v1(141.99,62.81) 144.3,62.81 144.96,63.47 145.98,63.47 146.32,63.81 146.32,65.24 147.02,65.93 147.74,65.93 148.04,65.64 v4(148.04,65.39)
  IN2 w0.508: v1(168.34,65.89) 168.34,65.96 167.82,66.48 165.04,66.48 163.85,67.67 163.2,67.67 162.4,66.87 162.15,66.87 161.8,66.53 159.36,66.53 159.12,66.77 155.77,66.77 153.89,64.89 152.31,64.89 151.95,65.26 148.66,65.26 148.53,65.39 v4(148.04,65.39)
  vias: v1(167.89,65.52) v1(168.13,64.78) v1(168.44,65.29) v1(168.7,64.75) v1(168.66,54.36) v1(168.93,65.88) v1(169.02,65.29) v1(168.95,64.21) v1(169.22,54.36) v1(169.33,64.78) v1(169.59,64.24) v1(169.65,65.29) v1(195.72,50.33) v1(195.72,49.7) v1(195.71,49.13) v1(196.69,50.36) v1(196.69,49.72) v1(196.7,49.1) v1(197.29,50.23) v1(197.29,49.6) v1(197.29,48.97) v1(197.34,48.38) v1(197.93,49.48) v1(197.93,48.85) v2(193.57,48.7)
+1.05VDX_MODPHY:
  vias: v1(151.11,77.68) v1(151.33,77.12) v1(151.69,77.68) v1(151.92,77.13) v1(169.04,71.5) v1(169.05,70.89) v1(169.61,71.64) v1(169.61,71.08) v6(150.37,78.52)
+1.05VDX_MODPHY_D: length 1.1
  TOP w0.102: Q39.1 172.49,74.77 v2(172.97,75.24)
+1.05VS: length 209.4
  TOP w0.279: JXDP.43 64.91,78.22 CH1.1
  TOP w0.305: UE5.B51 177.54,61.74 177.23,61.43 ; JXDP.44 64.91,71.62 65.41,72.11 65.41,73.79 64.91,74.28 JXDP.43
  TOP w0.508: RH340.1 141.16,43.59 141.16,47.44 141.99,48.26 v6(142.73,48.26) 142.8,48.26 143.12,48.58 143.12,49.65 142.74,50.03 142.74,51.44 142.3,51.88 142.3,57.15 v1(142.28,57.16) 142.28,57.52 141.99,57.81 CH1233.1 141.62,57.8 CH1217.1 139.59,57.8 v1(139.34,57.55) ; v1(65.85,78) 65.59,78.27 65.59,78.46 CH1.1 ; v1(171.84,46.03) 171.16,45.35 LH12.1 ; v1(178.48,72.01) 178.48,72.4 178.91,72.83 RE70.1 ; v1(139.54,63.59) 139.07,64.06 CH1235.1 ; v1(147.35,65.36) 146.99,65.72 CH39.1 ; RH356.1 RH355.1 172.81,59.18 173.14,59.51 174.72,59.51 175.23,59.01 CE50.1 176.1,59.96 v1(176.62,60.48) 177.23,61.09 177.23,61.43 ; CH1216.1 146.44,59.46 v1(147.11,58.79)
  IN2 w0.508: v1(167.29,68.57) 167.29,68 167.03,67.75 166.26,67.75 165.42,68.59 v1(165.42,68.71)
  IN3 w0.508: v1(167.06,56.99) 167.06,55.97 167.58,55.44 167.58,55.01 168.05,54.54 168.05,47.66 167.04,46.64 167.04,45.55 167.67,44.91 170.94,44.91 171.84,45.8 v1(171.84,46.03) ; v1(178.48,72.01) 178.48,70.04 177.63,69.19 177.63,62.16 176.62,61.14 v1(176.62,60.48) ; v1(165.42,68.71) 165.38,68.67 164.15,68.67 159.77,73.05 159.77,75.27 158.67,76.37 152.42,76.37 152.24,76.2 151.12,76.2 149.95,77.36 148.06,77.36 147.53,76.83 143.01,76.83 142.07,77.77 135.06,77.77 133.46,79.36 102.5,79.36 99.37,76.23 96.75,76.23 96.14,75.63 92.92,75.63 92.67,75.38 81.64,75.38 79.41,77.61 70.55,77.61 70.22,77.29 69.46,77.29 69.31,77.14 66.72,77.14 v1(65.85,78)
  BOTTOM w0.254: v1(147.35,65.36) 147.35,65.32 UCPU1.N8 146.57,64.54 UCPU1.P9 ; v1(147.11,58.79) 147.02,58.7 UCPU1.AE8 ; v1(141.83,67.45) 141.83,67.32 142.09,67.06 UCPU1.J17 ; UCPU1.T21 139.9,63.23 v1(139.54,63.59) 139.92,63.97 UCPU1.R21 ; UCPU1.H15 143.16,67.71 142.82,68.05 v1(142.82,68.07) ; v1(139.34,57.55) 139,57.88 UCPU1.AF22 ; UCPU1.H11 v1(145.64,68.15) ; v1(145.64,67.48) 145.22,67.06 UCPU1.J11 ; UCPU1.AG16 142.6,57.49 v1(142.28,57.16) 141.96,57.49 UCPU1.AG17
  BOTTOM w0.508: v1(167.29,68.57) 167.38,68.48 169.28,68.48 170.61,69.81 173.24,69.81 176.32,72.89 178.17,72.89 178.48,72.58 v1(178.48,72.01)
  vias: v1(164.43,60.05) v1(164.5,59.47) v1(165.08,59.47) v1(165.66,59.47) v1(166.51,57.62) v1(166.48,56.98) v1(167.07,57.59) v1(167.65,57.57) v1(167.65,56.96)
+1.5VS: length 69
  TOP w0.102: v1(197.92,78.37) v6(197.92,79.51)
  IN4 w0.508: v1(142.77,67.41) 143.35,66.82 146,66.82 146.9,65.92 148.86,65.92 149.16,65.62 151.5,65.62 152.16,66.28 154.05,66.28 155.14,67.38 159.07,67.38 159.35,67.1 162.63,67.1 163.17,67.64 163.94,67.64 165.09,66.49 167.21,66.49 167.94,67.22 167.94,68.89 v1(167.72,69.1)
  BOTTOM w0.254: UCPU1.J15 143.12,67.06 v1(142.77,67.41)
  BOTTOM w0.508: v1(197.92,78.37) 197.13,77.58 190.94,77.58 189.68,76.33 185.86,76.33 185.02,75.49 181.62,75.49 180.04,77.07 175.84,77.07 173.73,74.96 173.73,71.32 172.83,70.42 170.36,70.42 169.04,69.1 v1(167.72,69.1)
+1.05VS_VCCST: length 190.5
  TOP w0.508: v1(105.94,65.88) 105.94,67.98 106.76,68.8 RH4.1 106.68,69.37 104.72,69.37 v1(104.48,69.12) ; v1(105.94,65.88) 106.6,65.21 107.32,65.21 107.67,65.57 R1179.1 RC43.1 ; v1(105.94,65.88) 104.64,65.88 104.14,65.38 104.14,61.36 v1(107.81,57.68) ; v1(172.08,78.63) v2(173.46,80.01) 178.58,80.01 179.02,79.57 RC149.2 ; R1132.1 v1(164.51,64.85)
  IN1 w0.508: v1(137.33,57.76) 137.24,57.85 120.55,57.85 119.78,57.09 115.33,57.09 115.22,56.98 108.24,56.98 107.81,57.41 v1(107.81,57.68) 107.6,57.9 101.15,57.9 97.05,53.79 88.02,53.79 86.68,55.13 78.99,55.13 77.96,54.1 v1(76.15,54.1)
  IN3 w0.508: v1(164.51,64.85) 164.51,64.01 162.93,62.44 162.93,61.17 163.24,60.87 163.24,59.81 164.76,58.29 164.76,57.3 166.96,55.1 166.96,54.72 167.44,54.24 167.44,49.65 166.95,49.16 165.75,49.16 165.48,49.43 162.76,49.43 162.24,48.91 162.24,47.76 161.11,46.63 160.22,46.63 159.52,45.93 158.39,45.93 157.97,45.51 157.97,42.3 157.68,42.01 146.44,42.01 143.02,45.42 143.02,49.45 142.12,50.35 142.12,56.35 141.37,57.1 141.37,57.32 140.33,58.36 137.93,58.36 v1(137.33,57.76)
  BOTTOM w0.254: v1(137.33,57.76) 137.33,58 137.67,58.35 138.49,58.35 UCPU1.AE23 138.59,58.35 UCPU1.AE22 UCPU1.AC22 v1(139.53,59.57)
  BOTTOM w0.508: v1(76.15,54.1) PR723.1 PR726.1 PR727.1 PC717.1 ; RC48.1 105.02,69.12 v1(104.48,69.12) 104.23,69.37 RC93.2 ; v1(172.08,78.63) 171.02,78.63 170.35,77.95 170.35,75.77 164.51,69.93 v1(164.51,64.85) ; R1371.1 105.43,66.38 v1(105.94,65.88)
+1.5VSP: length 19.5
  TOP w0.127: v6(196,78.84) 196.35,78.84 197.03,78.15 197.03,77.22
  TOP w0.254: v1(193.15,68.47) 193.15,69.02 PU400.14
  TOP w0.508: PR401.1 PC402.1 195.34,75.51 v1(195.29,75.56) ; PR412.2 v1(192.74,75.59)
  IN3 w0.508: v1(197.57,76.4) 196.12,76.4 195.29,75.57 v1(195.29,75.56) 195.29,73.1 195.48,72.91 195.48,70.81 193.15,68.48 v1(193.15,68.47)
  IN4 w0.508: v1(195.29,75.56) 194.59,74.86 193.44,74.86 192.74,75.56 v1(192.74,75.59)
+1.05VSP: length 21.8
  TOP w0.102: v1(197.1,54.39) v6(197.1,54.96)
  IN1 w0.254: v1(205.13,64.85) 204.61,64.33 204.61,60.59 205.3,59.91 205.3,54.6 204.31,53.61 197.89,53.61 197.11,54.39 v1(197.1,54.39)
  BOTTOM w0.508: v1(205.13,64.85) PR505.1 204.51,64.85 PC515.1
+1.8VS: length 211.7
  TOP w0.508: RH350.2 154.25,63.28 v1(154.25,63.45) ; v1(43.97,59.13) 43.97,61.77 v6(44.5,62.3) 44.82,62.63 44.82,65.34 v1(44.68,65.48)
  IN1 w1.016: 43.69,59.94 43.69,61.39 45.61,63.31 45.61,64.98 46.55,65.92 ; 18.64,54.43 18.48,54.28 18.48,47.3 22.99,42.8 28.15,42.8 29.11,41.83
  IN3 w0.508: v1(48.1,70.75) 47.2,71.65 47.2,74.43 48.12,75.36 64.22,75.36 64.94,76.07 72.24,76.07 73.18,77 79.16,77 81.74,74.42 96.13,74.42 97.17,75.46 99.46,75.46 102.49,78.49 123.72,78.49 125.8,76.41 127.81,76.41 128.91,75.31 132.95,75.31 134.42,76.78 137.18,76.78 137.84,76.12 147.72,76.12 148.33,76.73 149.73,76.73 150.92,75.54 150.92,75.28 151.34,74.86 151.82,74.86 152.72,75.77 155.6,75.77 157.17,74.2 157.17,72.13 158.69,70.61 158.69,66.9 158.84,66.75 158.84,64.71 v4(158.82,64.68)
  IN3 w1.016: 17.62,55.83 17.71,55.92 17.71,62.78 19.59,64.66 22.69,64.66 24.66,66.63 33.49,66.63 34.83,65.29 41.75,65.29 42.42,64.63 42.42,62.29 43.4,61.31 43.4,59.96
  IN4 w0.508: v1(154.25,63.45) 154.3,63.5 157.37,63.5 158.55,64.68 v4(158.82,64.68)
  vias: v1(17.3,54.94) v1(17.87,54.94) v1(29.86,41.26) v1(30.45,41.29) v1(43.34,59.13)
+1.8VS_AUDIO:
  vias: v2(27.63,36.46)
+1.8VSP: length 16.2
  TOP w0.203: 41.67,58.93 41.67,59.16 42.02,59.52 42.73,59.52 43.1,59.88 v2(43.1,60.26) PR406.1 PC410.1 ; PU401.14 v1(36.61,63.21)
  TOP w0.254: PC410.1 43.63,62.12 44.26,62.75 44.26,63.29 43.87,63.69 43.3,63.69 PR413.2
  IN3 w0.508: v1(36.61,63.21) 35.79,63.21 34.79,62.21 34.79,58.61 35.5,57.9 v1(36.34,57.9)
+1.35V_DDR: length 148.1
  TOP w0.076: UD31.N1 106.71,27.05 ; UD29.D2 91.8,34.27 ; UD29.C1 91.01,35.05
  TOP w0.229: UD31.F1 106.71,32.62 v1(107.06,32.27) 107.1,32.23 107.1,31.71 107.13,31.69 107.51,31.3 UD31.H2 ; UD7.F1 132.38,32.25 132.38,31.45 UD7.H2 ; 160.3,32.56 v1(160.62,32.24) 160.72,32.15 160.72,31.69 161.1,31.3 161.1,31.05
  TOP w0.254: v1(111.96,29.87) 111.96,29.78 112.29,29.45 112.29,29.45 UD31.K8 ; v1(178.91,37.07) 178.54,36.69 UD4.A8 ; v1(84.42,27.45) 84.79,27.08 UD28.N9 ; UD1.D2 161.1,34.28 v1(160.72,34.66) 160.33,35.05 UD1.C1 ; UD31.K2 107.6,29.45 107.6,29.45 v1(107.94,29.79) ; UD4.C9 179.38,35.05 v1(179.75,34.68) 179.34,34.27 UD4.D9 ; v1(131.58,25.9) 131.98,25.51 UD7.R1 ; UD29.F1 91,32.66 90.88,32.77 90.35,32.77 v1(90.14,32.56) ; UD7.D9 138.38,34.25 v1(138.79,34.66) 138.41,35.05 UD7.C9 ; v1(171.76,32.35) 172.18,32.77 172.82,32.77 172.94,32.66 UD4.F1 ; v1(143.67,32.42) 143.75,32.42 144.05,32.72 144.53,32.72 UD3.F1 ; UD4.G7 v1(178.11,32.23) ; UD7.B2 v1(132.41,36.22) UD7.A1 ; 106.71,27.05 106.71,26.99 v1(107.05,26.65) ; 125.86,33.45 125.86,33.45 UD32.E9 ; 125.86,33.45 v1(126.21,33.8) ; 125.86,33.45 125.75,33.45 ; v1(167.15,33.9) 166.89,33.64 UD1.E9 ; 144.59,25.45 UD3.R1 144.59,25.45 ; 144.59,25.45 144.37,25.45 v1(144.14,25.68) ; UD7.N1 131.93,27.05 131.93,27.05 v1(131.56,27.42) ; UD3.E9 150.98,33.45 v1(150.58,33.85) 150.98,34.25 UD3.D9 ; UD28.H2 78.86,31.38 v1(78.77,31.38) ; UD1.C9 167.08,35.05 v1(167.21,34.92) 166.7,34.41 UD1.D9 ; v1(149.86,29.85) 150.19,29.52 UD3.K8 ; UD31.D9 v1(113.52,34.66) 113.13,35.05 UD31.C9 ; UD1.N1 160.3,27.05 160.14,27.22 160.08,27.22 v1(159.88,27.42) ; UD3.A1 144.59,36.71 v1(144.21,37.1) ; v1(133.15,29.89) 132.96,29.7 132.96,29.63 132.78,29.45 UD7.K2 ; UD32.K2 120.15,29.46 v1(120.58,29.89) ; UD32.C1 119.35,35.03 v1(119.73,34.65) 120.12,34.25 UD32.D2 ; v1(77.86,25.08) 78.24,25.45 UD28.R1 ; UD28.C9 84.81,35.05 v1(85.2,34.66) 84.79,34.25 UD28.D9 ; 125.75,31.05 125.87,31.05 ; 125.87,31.05 v1(126.2,31.38) ; 125.87,31.05 125.87,31.05 UD32.H9 ; v1(91.4,36.27) 91.8,35.87 UD29.B2 ; UD1.R1 160.33,25.45 v1(160.68,25.1) ; UD1.H2 161.1,31.05 ; UD1.B2 v1(160.74,36.22) UD1.A1 ; UD1.R9 166.7,25.55 167.01,25.86 v1(167.01,25.86) ; UD3.H2 v1(145.02,31.43) ; v1(79.56,29.89) 79.37,29.7 79.37,29.63 79.19,29.45 UD28.K2 ; UD31.G7 111.38,31.73 110.98,31.73 110.76,31.5 v1(110.76,31.46) ; v1(125.32,37.07) 124.95,36.69 ; 124.95,36.69 UD32.A8 124.95,36.69 124.95,36.69 ; UD1.A8 165.96,36.65 v1(166.33,36.29) ; UD29.N9 97.4,26.96 v1(97.71,26.65) 97.83,26.53 97.83,25.68 97.61,25.45 UD29.R9 ; UD28.R9 v1(85.18,25.85) ; v1(178.08,29.04) 178.5,29.45 UD4.K8 ; UD29.D9 97.45,34.25 v1(98.02,34.82) 97.78,35.05 UD29.C9 ; UD4.K2 173.74,29.45 173.91,29.62 173.91,29.63 174.17,29.89 v1(174.17,29.89) ; UD3.B2 145.39,35.89 v1(144.99,36.29) ; v1(119.77,31.43) 119.98,31.22 120.04,31.16 120.04,31.15 UD32.H2 120.15,31.05 ; v1(179.74,33.86) 179.54,33.67 179.54,33.66 179.34,33.45 UD4.E9 ; UD31.R9 113.11,25.55 v1(113.75,26.19) ; v1(96.17,32.26) 95.8,31.89 UD29.G7 ; UD4.B2 173.74,35.87 v1(173.34,36.27) ; v1(90.52,27.45) 90.92,27.06 91,27.06 91,27.05 ; UD29.A1 90.99,36.65 v1(90.58,37.07) ; UD32.F1 119.23,32.77 118.71,32.77 118.21,32.27 ; v1(126.19,25.05) 125.79,25.45 UD32.R9 ; UD7.G7 136.78,31.85 136.66,31.73 136.26,31.73 136.04,31.5 v1(136.04,31.46) ; v1(167.11,31.43) 167.09,31.43 166.7,31.05 UD1.H9 ; UD1.F1 160.3,32.56 ; 125.85,35.05 125.75,35.05 ; 125.85,35.05 v1(126.22,34.68) 125.79,34.25 ; 125.85,35.05 125.85,35.05 125.95,34.95 ; v1(164.33,31.52) 164.34,31.54 164.36,31.54 164.54,31.73 164.98,31.73 UD1.G7 ; UD31.A1 106.71,36.58 v1(107.07,36.22) 107.44,35.85 UD31.B2 ; v1(118.94,37.1) 118.94,37.06 119.34,36.65 UD32.A1 ; v1(96.96,30.67) 97.34,31.05 UD29.H9 ; 91.01,35.05 v1(91.41,34.65) 91.8,34.27 ; v1(77.94,32.27) 78.33,32.65 UD28.F1 ; UD7.A8 137.58,36.67 v1(138.08,37.16) ; v1(137.98,27.47) 138.38,27.07 138.38,27.07 UD7.N9 ; v1(118.94,27.41) 119.3,27.05 UD32.N1 ; UD31.C1 UD31.D2 107.9,34.65 v1(107.9,34.69) ; UD4.N1 172.89,27.05 v1(172.5,27.45) ; v1(179.73,25.8) 179.39,25.45 UD4.R9 ; v1(82.44,31.46) 82.83,31.85 UD28.G7 ; UD7.D2 132.78,34.27 v1(132.39,34.66) 132,35.05 UD7.C1 ; UD3.A8 150.28,36.65 v1(150.63,37) ; UD28.K8 83.99,29.52 v1(83.64,29.87) ; UD32.B2 120.15,35.87 v1(119.74,36.27) ; v1(161.49,29.92) 161.1,29.53 UD1.K2 ; UD7.K8 137.56,29.45 137.56,29.45 137.24,29.78 v1(137.24,29.87) ; v1(96.97,37.07) 96.6,36.69 UD29.A8 ; UD4.H9 179.13,31.27 179.08,31.27 v1(178.93,31.42) ; UD4.A1 172.94,36.65 v1(172.52,37.07) ; UD28.N1 78.33,27.05 v1(77.97,27.42) ; v1(85.19,31.43) 84.81,31.05 UD28.H9 ; UD3.C9 150.99,35.09 150.99,35.09 v1(150.59,35.5) ; UD28.E9 84.79,33.45 v1(85.2,33.86) ; UD32.K8 124.9,29.45 v1(124.49,29.04) ; v1(112.52,37.16) 112.31,36.95 UD31.A8 ; UD3.D2 145.39,34.27 v1(145.01,34.65) 144.61,35.05 UD3.C1 ; 125.75,34.25 125.79,34.25 ; 125.79,34.25 125.84,34.25 125.93,34.34 ; v1(118.85,24.84) 119.35,25.34 UD32.R1 ; UD32.N9 125.77,27.05 v1(126.17,26.65) ; v1(96.26,29.87) 96.26,29.8 UD29.K8 ; UD3.H9 150.99,31.04 v1(151.35,30.68) ; v1(96.99,33.77) 97.31,33.45 UD29.E9 ; UD3.G7 149.39,31.89 v1(149.77,32.26) ; UD32.G7 123.66,32.34 v1(123.66,33.1) ; v1(83.53,37.03) 83.91,36.65 UD28.A8 ; v1(112.72,27.54) 112.72,27.44 112.91,27.25 UD31.N9 ; v1(150.59,26.68) 150.96,27.05 UD3.N9 ; UD7.R9 v1(138.78,25.85) ; UD1.N9 166.32,27.44 v1(166.32,27.54) ; UD4.C1 172.95,35.05 v1(173.35,34.65) 173.74,34.27 UD4.D2 ; UD29.H2 v1(91.43,31.43) ; v1(138.79,33.86) 138.57,33.64 138.57,33.64 138.38,33.45 UD7.E9 ; v1(107.09,25.1) 106.73,25.45 UD31.R1 ; UD4.R1 172.85,25.45 v1(172.49,25.82) ; v1(131.35,32.39) 131.61,32.65 UD7.F1 ; v1(113.51,31.36) 113.43,31.36 113.12,31.05 113.11,31.05 ; v1(145.76,29.89) 145.76,29.89 145.39,29.52 UD3.K2 ; UD31.E9 113.29,33.64 113.29,33.64 v1(113.52,33.86) ; v1(151.3,25.05) 150.99,25.36 UD3.R9 ; UD4.H2 173.64,31.15 173.64,31.16 173.58,31.22 v1(173.37,31.43) ; UD28.B2 v1(78.82,36.22) UD28.A1 ; UD29.K2 91.8,29.46 v1(92.23,29.89) ; v1(165.56,29.87) 165.56,29.78 165.88,29.45 165.88,29.45 UD1.K8 ; v1(138.79,31.4) 138.76,31.4 138.42,31.05 138.42,31.05 UD7.H9 ; UD3.N1 144.55,27.05 v1(144.11,27.49) ; UD4.N9 179.36,27.05 v1(179.76,26.65) ; UD28.D2 79.05,34.39 79.05,34.41 v1(78.8,34.66) 78.56,34.9 78.55,34.9 UD28.C1
  TOP w0.508: v1(77.03,38.48) 76.65,38.1 CD68.1 ; CD66.1 v1(75.85,26.29) ; CD66.1 74.9,26.16 CD67.1 v1(75.72,25.35) ; CD66.1 75.01,26.3 74.39,26.3 74.19,26.51 RD92.2 ; CD83.1 v1(122.27,21.03) ; CD47.1 136.47,21 v1(136.43,20.96) ; v1(116.53,20.64) 116.53,20.65 117.02,21.15 CD92.1 ; CD69.1 75.29,34.9 v1(75.77,35.38) ; v1(119.92,20.97) CD86.1 119.71,22.06 CD84.1 ; CD50.1 v1(134.08,21.03) ; CD73.1 v1(77.94,22.94) ; v1(143.48,43.13) 143.68,42.93 RD24.2 ; CD72.1 v1(76.04,23) ; CD46.1 v1(133.13,22.79) ; v1(171.29,20.52) 170.83,20.52 170.4,20.95 RD95.2 ; v1(111.22,20.69) 110.91,20.99 CD80.1 ; v1(76.67,22.98) 76.93,22.72 CD70.1
  IN2 w0.508: v1(179.75,34.68) 180.27,35.2 180.27,36.59 179.79,37.07 v1(178.91,37.07)
  BOTTOM w0.178: UCPU1.AN33 131.7,54.06 v1(131.44,53.8)
  BOTTOM w0.203: v1(124.88,48.65) 124.65,48.65 124.46,48.84 UCPU1.AY44 ; UCPU1.AY35 130.73,49.62 130.73,49.25 v1(131.17,48.8) ; UCPU1.AR48 122.42,52.43 v1(122.36,52.43) ; UCPU1.AY40 127.57,49.61 127.57,49.11 v1(128.02,48.66)
  BOTTOM w0.229: v1(121.9,49.22) 121.47,49.65 UCPU1.AY50
  BOTTOM w0.254: UCPU1.AH26 136.15,57.22 v1(135.73,57.22) ; v1(125.22,53.08) 125.54,53.41 UCPU1.AP43 ; UCPU1.AJ33 v1(131.83,57.22) ; UCPU1.AJ31 v1(133.13,57.22) ; UCPU1.AJ37 v1(129.23,57.22)
  BOTTOM w0.381: UC1.5 103.76,46.28 103.42,46.62 CC240.1
  BOTTOM w0.508: 143.44,40.11 143.44,43.09 v1(143.48,43.13) ; CC240.1 102.88,47.23 101.89,48.21 96.89,48.21 94.3,45.62 94.3,40.16
  vias: v1(105.62,23.47) v1(159.06,23.52) v1(162.4,20.14) v1(162.97,20.14) v1(163.61,20.14) v6(122.5,46.24)
+1.35VP: length 36.4
  TOP w0.102: v1(75.85,48.21) 76.01,48.05 v2(76.32,48.05)
  IN4 w0.254: v1(86.2,45.48) 86.2,43.45 85.18,42.43 79.02,42.43 75.57,45.89 72.64,45.89 v1(72.61,45.86)
  IN4 w0.508: v1(85.56,45.48) 85.56,43.64 84.88,42.95 79.27,42.95 75.85,46.37 v1(75.85,48.21)
  BOTTOM w0.203: PU600.5 72.7,46.84 71.99,46.13 PR605.2 v1(72.61,45.86) ; PU600.19 74.99,48.38 75.68,48.38 v1(75.85,48.21)
+3.3V_ALW_DEG: length 2.6
  BOTTOM w0.102: RE76.2 v2(168.57,66.96)
  BOTTOM w0.254: RE76.2 170.16,67.47 JDEG1.1
+3.3V_M: length 93.6
  TOP w0.102: v6(204.75,29.03) 204.38,29.41 v1(204.38,30.21)
  TOP w0.305: RH57.1 145.71,61.93 CH47.1
  TOP w0.508: v1(147.26,60.77) 146.8,61.24 CH47.1
  GND1 w0.508: v4(152.44,56.85) 152.71,57.12 v3(152.71,57.49)
  IN1 w0.508: v1(185.3,54.28) 185.13,54.12 185.13,51.42 184.9,51.19 182.85,51.19 182.57,51.47 180.37,51.47 179.92,51.02 178.48,51.02 178.25,50.79 176.5,50.79 175.98,50.27 175.98,49.62 175.64,49.28 174.78,49.28 173.42,47.92 v4(173.37,47.92)
  IN2 w0.508: v4(173.37,47.92) 173.37,48 172.41,48.95 166.27,48.95 165.81,49.4 161.66,49.4 158.53,52.54 155.16,52.54 154.58,53.12 151.07,53.12 v1(150.64,52.68)
  IN2 w1.016: 203.51,30.55 203.46,30.6 203.37,30.51 199.98,30.51 197.85,32.65 197.85,36.37 196.84,37.37 196.84,44.64 195.23,46.25 193.58,46.25 189.63,50.2 188.08,50.2 187.39,50.9 187.39,54.03 187.28,54.14 187.28,54.14
  IN3 w0.508: 150.35,59.48 150.75,59.48 151.2,59.02 151.2,57.63 151.97,56.85 v4(152.44,56.85) 152.75,56.55 152.75,55.75 152.23,55.22 151.74,55.22 151.34,54.81 151.34,53.38 v1(150.64,52.68) ; v1(172.97,46.03) 173.37,46.43 v4(173.37,47.92)
  BOTTOM w0.254: UCPU1.Y8 147.02,61.04 147.26,60.79 v1(147.26,60.77)
  BOTTOM w0.508: v1(172.97,46.03) 172.42,46.58 RH3527.1
  vias: v1(185.83,54.55) v1(204.38,30.81)
+3.3VDX_SSD: length 46.2
  TOP w1.524: 178.91,19.95 182.68,19.95 183.74,21 183.74,26.37 184.75,27.39 181.11,31.04 181.11,37.3 180.15,38.26 177.89,38.26 176.99,39.16
  TOP w2.032: 193.53,26.44 193.51,26.42 190.67,26.42 189.7,27.39 184.75,27.39
  IN1 w0.508: v1(178.82,40.71) 179.65,40.71 180.26,41.32 180.26,43.71 182.19,45.64 182.33,45.64 v4(182.43,45.74)
  GND3 w0.508: v5(182.97,46.13) 182.81,46.13 v4(182.43,45.74)
  BOTTOM w0.508: v5(182.97,46.13) R1377.2
  vias: v1(175.77,20.44) v1(176.36,20.44) v1(176.94,20.44) v1(177.7,40.96) v1(178.24,40.71) v6(178.15,39.86)
+3V_NFC: length 3.6
  BOTTOM w0.508: R973.1 76.14,18.65 76.76,19.26 78.09,19.26 78.34,19.51 78.35,19.51 78.66,19.83 78.9,19.83
  vias: v1(80.29,20.15)
+3V_PCH: length 385
  TOP w0.508: RH154.2 163.48,43.44 v1(163.73,43.69) ; R1312.1 68.91,80.47 76.9,80.47 77.31,80.06 77.31,75.17 84.77,67.71 87.92,67.71 89.89,69.69 89.89,73.78 91.72,75.6 v3(95.22,75.6) 96.79,75.6 98.43,73.97 98.43,69.07 100.83,66.67 v1(100.83,56.66) ; v1(156.06,48.2) 156.06,48.67 155.74,49 150.69,49 150.14,48.45 148.47,48.45 RH341.1 148.11,46.81 150.63,46.81 151.06,46.38 v1(151.06,46.2) ; v3(161.99,68.82) 161.99,69.15 161.73,69.42 RH465.2 ; CH1220.1 141.88,59.2 v1(142.46,58.61)
  GND1 w0.254: v3(161.99,68.82) 161.14,68.82 161.07,68.74 v4(161.07,68.74)
  GND1 w0.508: v4(94.95,75.06) 94.95,75.34 v3(95.22,75.6)
  IN1 w0.381: v1(143.49,59.89) 142.79,59.2 141.27,59.2 141.01,58.94 v1(141.01,58.57)
  IN1 w1.016: 195.36,23.34 194.95,23.75 194.95,31.84 192.8,33.98 192.8,41.52 192.2,42.12 190.67,42.12 189.19,43.6 189.19,46.63 186.63,49.2 182.8,49.2 179.93,46.32 178.67,46.32 177.55,45.2 177,45.2 176.5,44.69 176.5,43.12 175.39,42.01 165.32,42.01 164.39,42.94 164.38,42.94
  IN2 w0.508: v4(195.14,65.21) 195.14,68.08 191.41,71.81 189.64,71.81 188.94,72.51 188.94,74.73 188.33,75.34 181.38,75.34 180.48,76.24 v4(173.45,76.24) ; v1(166.5,68.38) 166.5,68.86 165.97,69.39 ; v4(171.46,72.86) 171.46,71.33 169.88,69.76 166.34,69.76 165.97,69.39 ; 165.97,69.39 165.18,69.39 164.54,68.74 161.07,68.74 v4(161.07,68.74)
  IN3 w0.508: v1(157,58.62) 156.59,59.03 156.42,59.03 155.8,59.65 155.8,61.08 156.53,61.81 158.63,61.81 v4(159.64,62.82) 160.25,63.44 160.25,65.58 160.53,65.86 160.53,68.37 160.91,68.74 161.06,68.74 v4(161.07,68.74) ; v1(151.06,46.2) 151.06,45.37 149.23,43.54 145.73,43.54 143.93,45.34 143.93,51.18 143.73,51.38 143.73,56.28 143.13,56.89 143.13,57.67 142.46,58.33 v1(142.46,58.61) 141.05,58.61 v1(141.01,58.57) 140.63,58.95 136.95,58.95 135.83,57.84 127.5,57.84 126.75,57.09 113.15,57.09 113.03,56.97 105.6,56.97 105.55,57.02 101.19,57.02 v1(100.83,56.66)
  IN4 w0.508: v1(200.4,35.02) 200.47,35.02 201.13,34.35 201.13,29.15 200.08,28.1 200.08,25.05 201.74,23.39 v1(203.46,23.39) ; v1(100.83,56.66) 101.29,56.21 101.29,50.7 101.68,50.31 101.68,46.5 93.65,38.47 79.04,38.47 77.26,36.69 77.26,20.73 v1(77.75,20.23)
  GND3 w0.254: v5(160.42,62.82) 159.64,62.82 v4(159.64,62.82)
  GND3 w0.508: v4(94.95,75.06) 94.95,74.31 v5(94.96,74.3) ; v4(173.45,76.24) v5(172.83,76.24) ; v4(171.46,72.86) v5(172.09,72.86) ; v5(196.37,65.21) v4(195.14,65.21)
  BOTTOM w0.254: RP2.7 157.26,58.37 157.26,58.37 v1(157,58.62) 157.24,58.87 RP2.8 ; UCPU1.AC9 UCPU1.AA9 146.56,60.71 145.83,60.71 ; RP2.6 157.12,57.87 v1(156.84,57.58) 157.05,57.37 157.63,57.37 RP2.5 ; v1(141.01,58.57) 140.61,58.57 UCPU1.AE20 140.02,58.35 UCPU1.AE21
  BOTTOM w0.305: v1(200.4,35.02) 200.24,35.02 199.81,35.44 JAPS.1
  BOTTOM w0.381: v5(94.96,74.3) 94.95,74.31 U663.16 ; U697.5 85.84,73.6 86,73.44 86,72.49 R1324.1 ; v1(143.49,59.89) 144.37,60.78 145.77,60.78 145.83,60.71
  BOTTOM w0.508: 168.17,60.62 166.32,58.77 164.36,58.77 RH270.2 ; 168.17,60.62 166.32,62.47 166.32,66.1 166.63,66.4 166.63,68.25 v1(166.5,68.38) ; 168.17,60.62 168.79,60.01 169.4,60.01 ; RH3537.2 155.62,53.11 v1(155.66,53.15) ; v5(172.83,76.24) 172.09,75.5 v5(172.09,72.86) ; R1242.1 77.75,21.23 v1(77.75,20.23) ; v5(94.96,74.3) 94.96,73.53 94.46,73.03 87.39,73.03 86.82,72.47 R1324.1
  vias: v1(158.5,55.33) v1(158.98,55.04) v1(203.46,22.81) v3(160.8,46.41) v3(161.31,46.44) v4(160.8,46.01) v4(161.33,46.03) v4(195.13,23.06) v4(195.66,23.06) v6(160.71,51.13)
+3V_PCH_DSW: length 83.5
  TOP w0.381: v1(146.38,55.68) 146.16,55.46 CH1224.1
  TOP w0.508: v1(160.06,49.87) 160.34,49.6 RH348.2 ; v1(165.59,48.08) 165.65,48.08 165.94,48.37 RH12.1 ; v1(138.8,43.18) 139.16,43.18 139.73,43.75 v6(139.73,49.27) 139.73,49.35 139.29,49.8 C1.2
  IN2 w0.508: v4(163.83,48.24) 163.6,48.01 161.93,48.01 v1(160.06,49.87) 158.26,51.68 150.61,51.68 150.04,51.11 148.91,51.11 147.68,52.34 147.68,55.41 147.22,55.87 146.59,55.87 146.4,55.68 v1(146.38,55.68)
  IN3 w0.508: v1(156.98,60.78) 158.31,60.78 v1(159.25,59.84) 159.25,59.12 159.01,58.89 159.01,57.4 159.85,56.56 159.85,50.48 160.06,50.27 v1(160.06,49.87) ; v1(138.8,43.18) 138.96,43.18 141.62,40.52 158.03,40.52 163.83,46.33 v4(163.83,48.24) 164.09,48.5 165.17,48.5 v1(165.59,48.08)
  BOTTOM w0.254: v1(146.38,55.68) 146.38,56.37 UCPU1.AH10 ; RP20.6 157.3,61.1 v1(156.98,60.78) 157.15,60.61 157.63,60.61 RP20.5
  BOTTOM w0.508: RH146.2 159.45,59.64 v1(159.25,59.84)
+3V_ROM: length 31.4
  IN2 w0.508: v4(188.31,59.32) 188.53,59.1 188.53,55.82 187.95,55.24 185.06,55.24 184.64,54.83 184.64,52.92 185.39,52.17 185.97,52.17 186.43,52.62 v4(186.43,52.82)
  GND3 w0.508: v5(186.43,52.12) v4(186.43,52.82) ; v5(177.49,48.84) 177.18,48.54 v5(176.56,48.54) ; v5(188.82,59.82) 188.81,59.82 v4(188.31,59.32)
  BOTTOM w0.102: RH3527.2 v6(172.42,49.82)
  BOTTOM w0.508: 176.13,48.54 v5(176.56,48.54) ; v5(177.49,48.84) 177.49,50.21 180.97,53.69 181.75,53.69 182.69,52.75 184.69,52.75 185.15,52.29 186.25,52.29 v5(186.43,52.12) 187.06,51.48 U727.8 ; CH7.1 v5(188.82,59.82)
+3VALW: length 727.7
  TOP w0.356: U672.5 164.83,67.15 165.05,66.93 165.28,66.93 v1(165.46,67.11) ; v1(25.51,63.99) 25.61,63.89 25.86,63.89 26.04,64.07 PU404.8
  TOP w0.406: PC429.1 23.21,72.82 23.45,72.58 PU406.5 23.45,72.06 22.57,71.19 22.57,69.94 23.19,69.32 PU405.5
  TOP w0.508: v1(47.45,24.84) 47.45,23.9 46.41,22.86 v1(46.41,21.43) 46.42,21.43 48.13,19.71 64.21,19.71 PR100.1 ; 26.55,56.74 28.58,56.74 29.05,57.22 PR448.1 ; PR102.2 43.33,64.77 v1(43.74,64.36) ; 22.56,64.16 v1(22.56,60.33) PR450.1 PC428.1 ; PC434.1 PC433.1 PC429.1 ; v1(173.35,78.13) 173.63,77.85 RE84.1 ; v1(32.03,64.53) 32.03,65.29 30.37,66.96 PR460.1 ; v3(162.39,49.23) 162.18,49.03 RH348.1
  GND1 w0.508: v3(162.39,49.23) 162.77,48.85 v4(162.97,48.85) ; v4(197.24,16.07) 196.88,16.43 196.87,16.43 v3(196.7,16.6) ; v3(204.51,62.18) 204.51,62.61 204.13,62.99 v4(204.13,63.01)
  IN1 w0.508: v4(35.37,21.32) 35.97,20.73 35.97,18.28 33.61,15.91 v1(30.55,15.91) ; v4(172.18,48.33) 172.18,47.81 171.85,47.48 171.01,47.48 170.74,47.75 170.1,47.75 169.33,48.52 166.07,48.52 165.73,48.85 v4(162.97,48.85) ; v1(71.14,14.88) 71.14,15.02 71.49,15.38 94.33,15.38 95.27,16.32 103.45,16.32 104.39,15.38 109.08,15.38 109.34,15.55 109.8,15.74 110.4,15.86 110.68,15.86 111.28,15.74 111.74,15.55 112,15.38 128.17,15.38 128.62,15.82 130.69,15.82 132.85,13.66 167.42,13.66 167.59,13.48 175.05,13.48
  IN2 w0.508: v1(25.94,56.87) 25.94,59.68 25.29,60.33 v1(22.56,60.33) 22.75,60.52 22.75,63.59 23.15,63.99 v1(25.51,63.99) ; v1(71.14,14.88) 72.88,16.63 104.27,16.63 105,15.9 113.21,15.9 113.48,15.64 127.59,15.64 127.77,15.81 170.77,15.81 172.66,13.92 174.82,13.92
  IN3 w0.508: v1(32.53,41.22) 34.26,39.49 34.27,39.49 36.25,37.52 38,37.52 38.35,37.17 38.35,34.82 39.63,33.54 v4(39.63,32.36) ; 195.07,61.06 195.07,53.74 194.02,52.68 193.29,53.4 193.29,60.85 193.57,61.12 195.01,61.12 195.07,61.06 ; 195.07,61.06 196,62 ; v1(165.46,67.11) 167.49,67.11 168.46,68.07 168.46,72.05 167.11,73.39 167.11,76.67 168.44,77.99 173.21,77.99 v1(173.35,78.13) 174.38,77.1 v1(174.38,72.67) 174.38,71.31 172.65,69.59 172.65,67.72 171.99,67.06 171.99,62.72 172.29,62.42 172.29,59.75 172.99,59.05 172.99,52.7 172.26,51.96 172.26,48.41 v4(172.18,48.33) ; v1(32.03,64.53) 26.05,64.53 v1(25.51,63.99) ; v1(47.45,24.84) 50.41,24.84 52.74,22.51 71.62,22.51 75.11,26 75.11,37.5 76.74,39.13 90.83,39.13 v1(94.95,43.25)
  IN3 w1.016: 201.08,37.76 201.08,45.62 199.23,47.47 195.75,47.47 194.02,49.2 194.02,52.68 ; 196,62 196,67.38 196.81,68.18 201,68.18
  IN4 w0.508: v1(71.14,14.88) 71.14,15.19 71.95,16 95.57,16 95.94,16.37 100.61,16.37 100.98,16 168.6,16 170.6,13.99 174.88,13.99 ; v1(192.08,76.27) 192.08,76.4 192.71,77.03 194.68,77.03 196.35,75.37 196.35,74.85 201.46,69.74 v1(201.46,67.35) ; v1(201.46,66.73) 202.83,66.73 203.55,66.01 203.55,63.57 204.11,63.01 v4(204.13,63.01)
  GND3 w0.508: v4(204.13,63.01) 204.19,63.07 v5(204.51,63.07) ; v4(197.24,16.07) 196.72,16.07 196.3,15.66 v5(196.3,15.54) ; v4(39.63,32.36) 40.2,31.79 v5(40.21,31.79) ; v5(35.95,21.32) v4(35.37,21.32)
  BOTTOM w0.305: v1(200.26,34.39) 200.2,34.44 JAPS.3 ; v1(46.41,21.43) 46.42,21.42 JKB1.3 ; JAPS.7 v1(200.36,32.44)
  BOTTOM w0.508: 41.97,21.42 42.32,21.78 44.5,21.78 44.85,21.43 v1(46.41,21.43) 46.41,22.21 C375.1 ; 41.97,21.42 41.97,30.03 v5(40.21,31.79) ; 41.97,21.42 36.04,21.42 v5(35.95,21.32) ; v1(43.16,55.89) 35.09,55.89 33.57,57.42 33.57,62.99 32.03,64.53 v1(32.03,64.53) ; RC161.1 100.97,44.81 98.3,42.14 96.05,42.14 v1(94.95,43.25) ; v1(32.53,41.22) 32.53,41.61 32.01,42.13 29.98,42.13 29.41,42.71 29.41,56.93 28.53,57.81 26.87,57.81 v1(25.94,56.87) ; v1(174.98,72.68) 174.98,73.22 174.64,73.56 174.64,75.01 176.09,76.46 179.79,76.46 181.36,74.88 185.28,74.88 186.08,75.68 191.06,75.68 191.65,76.27 v1(192.08,76.27) ; 49.7,67.12 49.71,67.13 49.19,67.65 49.19,74.56 47.42,76.33 PR111.1 ; v1(43.74,64.36) 45.75,62.35 45.75,61.92
  vias: v1(43.16,56.58) v1(43.78,56.59) v1(43.78,56.02) v1(43.78,55.45) v1(44.35,56.59) v1(44.35,56.02) v1(44.35,55.45) v1(52.93,60.15) v1(69.87,14.87) v1(69.87,14.28) v1(70.2,13.78) v1(70.5,14.86) v1(70.5,14.27) v1(70.83,13.75) v1(71.14,14.3) v1(201.12,35.31) v1(201.29,36.49) v1(201.29,35.89) v1(203.17,27.64) v1(203.74,27.64) v1(204.06,27.07) v1(204.12,24.59) v1(204.12,24.02) v1(204.31,27.64) v1(204.77,36.44) v1(204.75,35.84) v1(204.89,22.01) v1(204.93,21.41) v1(204.92,19.1) v1(205.49,22.01) v1(205.49,21.41) v1(205.5,19.08) v4(175.42,13.97) v4(175.75,13.61) v4(175.94,14.17) v4(176.23,13.7) v4(176.47,14.16) v4(176.75,13.7) v4(176.95,14.16) v4(177.26,13.69) v6(34.28,45.63) v6(46.54,50.45) v6(55.29,53.25) v7(54.45,67.13) v7(54.77,66.5) v7(55.08,67.13) v7(55.4,66.5) v7(55.72,67.13) v7(56.04,66.5) v7(56.35,67.13) v7(56.67,66.5) v7(56.99,67.13) v7(57.31,66.5)
+3VALW_5085: length 109.9
  TOP w0.254: UE5.A11 187.92,66.99 ; v3(191.54,54.48) 191.54,54.49 191.52,54.47 191.52,53.92 191.19,53.6 191.09,53.6 190.96,53.47 190.96,53.37 RPE5.8 190.96,52.74 190.86,52.64 190.61,52.64 190.46,52.78 RPE5.7
  TOP w0.279: UE5.A26 181.72,73.01 CE46.1 ; CE14.1 183.71,72.88 183.71,71.19 UE5.A22 ; CE64.1 183.22,58.69 183.22,60.29 UE5.A58 ; 187.92,66.99 188.29,66.99 188.4,66.88 189.63,66.88 v3(189.76,66.75) ; v1(176.1,65.08) 176.27,65.08 176.68,65.49 UE5.A41
  TOP w0.305: UE5.B35 177.59,69.74 176.99,70.33 176.37,70.33 ; UE5.B3 186.54,62.74 v1(186.32,62.95)
  TOP w0.457: v3(184.36,74.54) 184.9,74.54 185.51,73.93 RE25.1
  TOP w0.508: RE52.1 180.31,56.9 v1(180.38,56.83) ; RE52.1 RE53.1 ; RE52.1 CE40.1 ; RE69.1 176.62,73.92 v3(176.45,74.09) ; v1(182.5,59.03) 182.5,59.02 182.08,58.6 CE17.1 CE64.1 ; CE63.1 182.72,73.03 CE46.1 ; CE63.1 v3(182.85,72.33) ; CE63.1 CE14.1 ; v1(191.88,64.97) RE79.2 RE73.2 RE71.2 RE67.2 191.63,62.31 v1(191.83,62.51) ; CE41.1 175.45,65.08 v1(176.1,65.08) ; RE55.2 RE56.2 173.66,62.05 v1(173.51,62.21) 173.44,62.28 172.7,62.28 172.42,62.56 RE65.1
  GND1 w0.254: v3(189.76,66.75) 189.98,66.75 v4(190.21,66.98) ; v4(191.83,58.78) 191.83,58.75 192.03,58.55 v3(192.24,58.55) ; v4(191.28,54.69) 191.34,54.69 v3(191.54,54.48) ; v4(180.26,60.84) 180.21,60.8 v3(180.21,60.29) ; v3(182.85,72.33) 183.2,72.33 v4(183.27,72.26)
  GND1 w0.508: v4(176.55,74.6) 176.45,74.5 v3(176.45,74.09) ; v4(184.88,74.55) 184.87,74.54 v3(184.36,74.54)
  IN2 w0.508: v4(190.21,66.98) 190.21,68.21 189.59,68.83 188.16,68.83 187.29,69.69 187.29,71.99 186.52,72.76 183.58,72.76 183.27,72.45 v4(183.27,72.26)
  IN3 w0.508: v4(183.27,72.26) 183.27,72.95 184.87,74.55 v4(184.88,74.55) ; v4(176.55,74.6) 176.55,71.1 v1(175.92,70.47)
  IN4 w0.508: v1(175.92,70.47) 176.36,70.47 177.07,69.76 177.07,65.74 176.4,65.08 v1(176.1,65.08)
  GND3 w0.254: v4(191.28,54.69) 191.28,55.04 191.36,55.12 v5(191.36,55.2) ; v5(191.66,59.12) 191.83,58.95 v4(191.83,58.78) ; v5(190.28,66.44) 190.28,66.92 v4(190.21,66.98) ; v5(180.69,60.84) v4(180.26,60.84)
  BOTTOM w0.508: v1(176.1,65.08) 175.68,65.08 RE75.1 RE74.1 RE72.1 ; 179.86,59.82 179.86,57.34 v1(180.38,56.83) 180.38,56.96 182.45,59.03 v1(182.5,59.03) ; 179.86,59.82 179.86,60.01 v5(180.69,60.84) 181.72,61.87 181.72,62.54 183.36,64.18 CE44.1 184.91,64.18 186.15,62.95 v1(186.32,62.95) 186.88,63.5 RE86.2 187.29,62.67 187.52,62.44 190.59,62.44 191.88,63.73 v1(191.88,64.97) 190.41,66.44 v5(190.28,66.44) ; 179.86,59.82 176.35,59.82 173.96,62.21 173.54,62.21 ; 172.13,63.18 172.13,62.5 172.51,62.12 173.45,62.12 173.54,62.21 ; v5(191.36,55.2) 191.66,55.5 v5(191.66,59.12) v2(191.66,61.02) 191.66,62.35 191.83,62.52 v1(191.83,62.51) ; 173.54,62.21 v1(173.51,62.21)
+3VALW_23017: length 16
  TOP w0.102: v3(33.88,15.11) v2(32.84,15.11)
  TOP w0.508: v1(40.8,15.7) 40.17,15.08 RE14.1 RE13.1 ; v1(37.09,14.63) 36.61,15.11 RE24.1
  GND1 w0.508: v3(33.88,15.11) 34.14,15.11 34.51,14.75 v4(34.51,14.68)
  IN3 w0.508: v1(40.8,15.7) 39.73,14.63 v1(37.09,14.63) 34.56,14.63 v4(34.51,14.68) 34.51,15.13 32.43,17.21 v4(31.92,17.21)
  GND3 w0.508: v4(31.92,17.21) 31.6,17.53 v5(31.6,17.81)
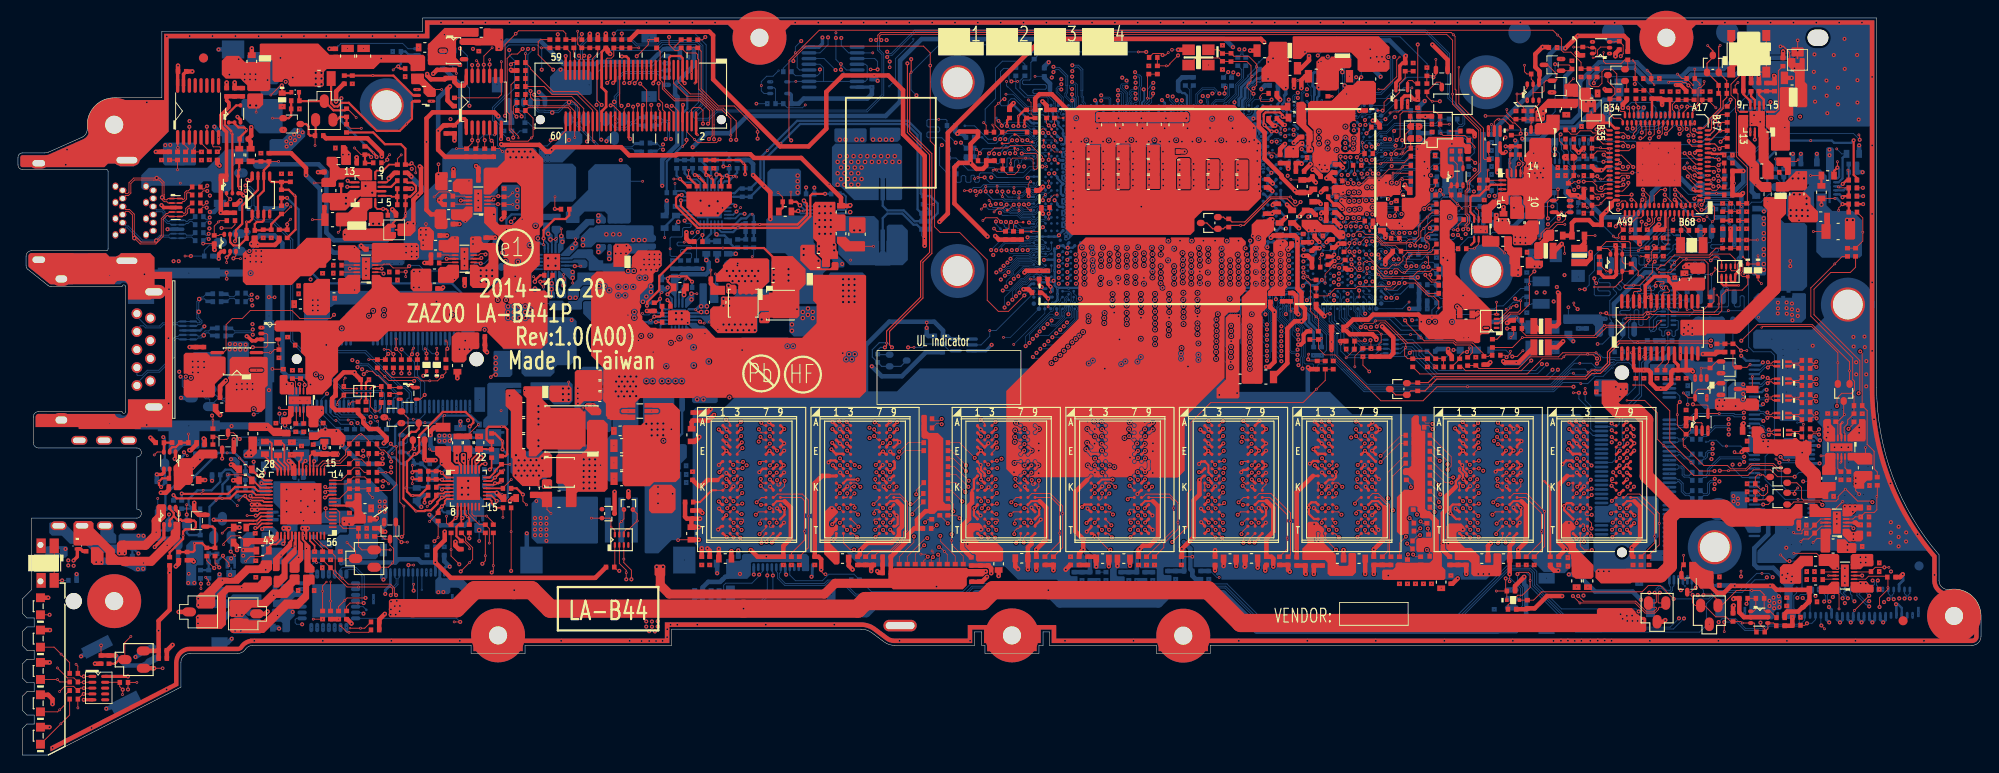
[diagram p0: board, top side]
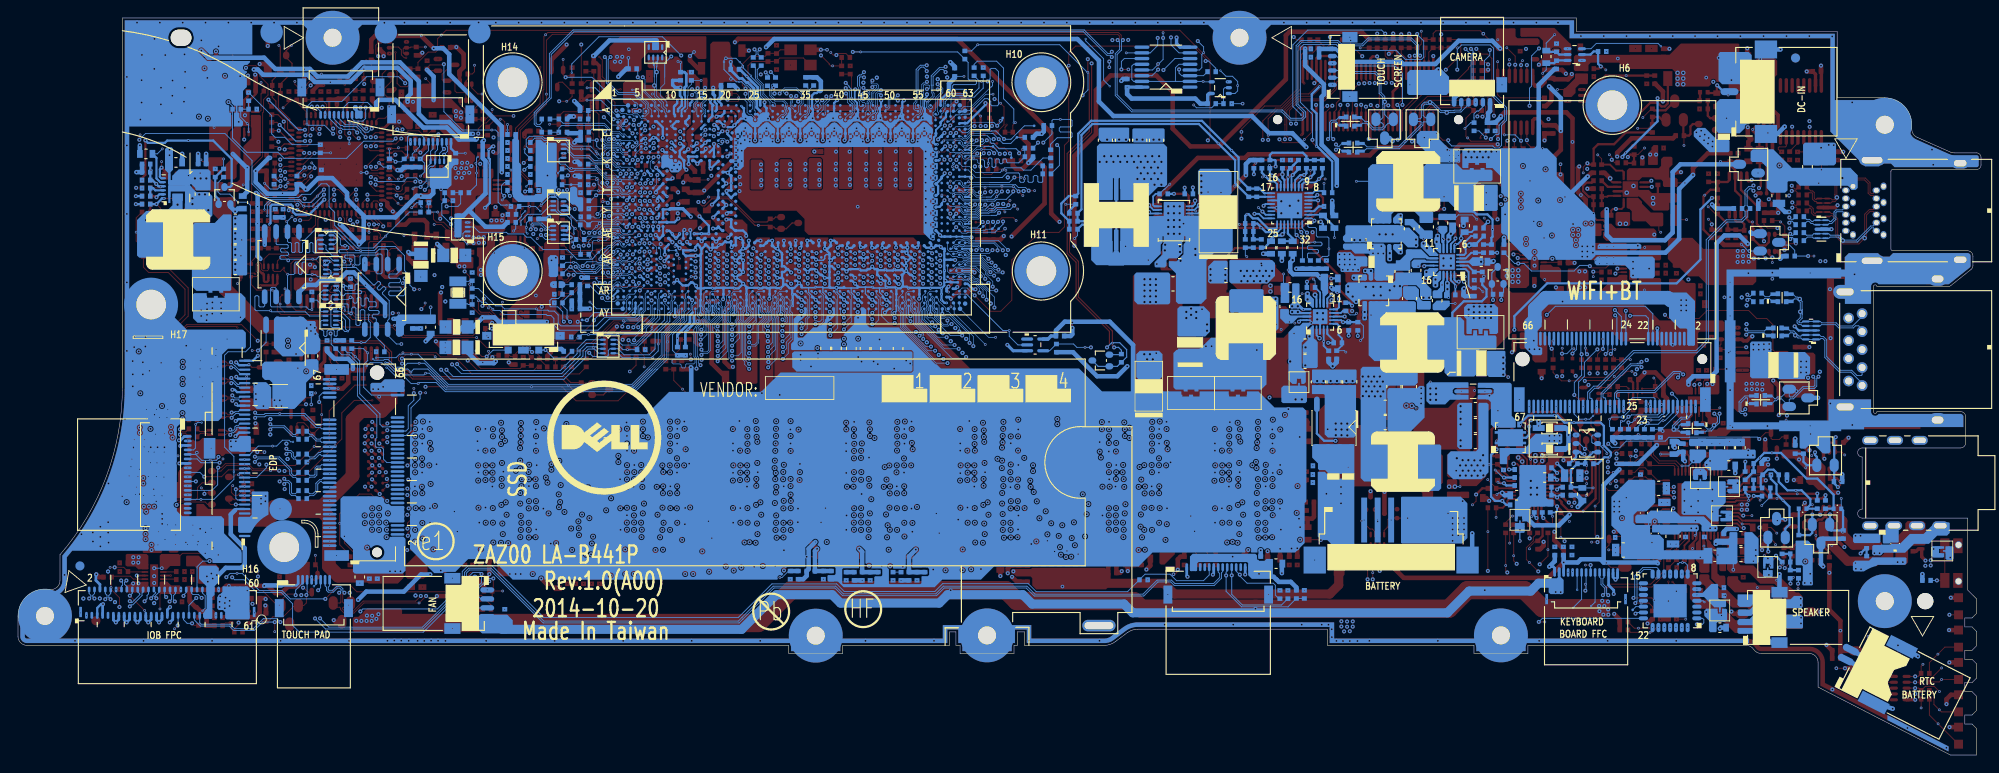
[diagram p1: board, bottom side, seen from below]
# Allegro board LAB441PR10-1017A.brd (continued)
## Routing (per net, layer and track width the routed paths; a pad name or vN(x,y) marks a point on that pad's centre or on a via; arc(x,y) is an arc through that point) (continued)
+3VALWP: length 6.3
  BOTTOM w0.254: PR300.1 PR311.1 54.45,57.55 54.32,57.67 v2(54.32,58.47) 54.32,59.58 54.89,60.15 56.1,60.15 56.48,60.53
+3VLP: length 241.6
  TOP w0.102: v1(15.13,9.65) v6(16.09,9.65)
  TOP w0.406: v1(171.35,59.66) 171.35,60.15 171.11,60.39 UC6.5
  TOP w0.508: v1(15.13,9.65) D122.2
  GND1 w0.254: v4(181.55,56) 181.55,55.99 182.04,55.5 v3(182.08,55.5)
  IN1 w0.508: v4(173.9,56.58) 173.93,56.54 176.38,56.54 176.85,56.06 181.49,56.06 v4(181.55,56) ; v1(15.13,9.65) 15.13,12.33 18.7,15.9 22.55,15.9 23.26,16.61 28.49,16.61 32.87,20.99 34.18,20.99 35.63,22.44 40.72,22.44 41.61,23.33 41.61,25.42 v4(42.6,26.41)
  IN2 w0.508: v4(45.69,42.69) 46.02,43.02 46.02,47.51 46.87,48.36 49.07,48.36 v7(55.59,54.88) 56.27,55.55 56.27,64.13 59.76,67.62 66.87,67.62 67.94,66.56 73.96,66.56 v1(75.04,67.63) ; v4(168.03,76.43) 167.95,76.43 165.24,79.14 158.97,79.14 v4(158.82,79)
  IN3 w0.508: v1(171.35,59.66) 171.35,61.2 170.24,62.32 170.24,74.22 168.03,76.42 v4(168.03,76.43) ; v4(42.6,26.41) 42.6,36.47 45.84,39.71 45.84,42.53 v4(45.69,42.69)
  IN4 w0.508: v1(135.12,78.75) 135.12,78.19 135.65,77.66 138.3,77.66 139.21,78.57 153.18,78.57 153.64,79.03 154.46,79.03 155.33,78.16 157.99,78.16 158.82,78.99 v4(158.82,79) ; v1(171.35,59.66) 171.35,59.12 v4(173.9,56.58)
  BOTTOM w0.508: v1(135.12,78.75) 134.22,79.66 100.49,79.66 98.1,77.27 98.1,72.7 96.49,71.1 81.08,71.1 79.16,69.18 76.59,69.18 v1(75.04,67.63)
+3VS: length 265.4
  TOP w0.254: v3(38.7,39.29) 38.69,39.3 U679.B2
  TOP w0.381: U671.14 49.85,74.74 49.58,74.47 ; CS44.1 186.06,37.47 186.15,37.38 186.41,37.38 186.64,37.61 U683.5 ; U675.5 43.94,40.88 v1(43.65,41.17) ; RH303.2 153.98,76.99 153.67,76.68 153.67,75.24 153.24,74.8 U682.5
  TOP w0.406: 177.75,55.72 QH6.2 177.75,53.45 177.46,53.16 176.38,53.16 RE87.2 ; 177.75,55.72 QH6.5 ; 177.75,55.72 177.75,56.59 v3(177.67,56.68)
  TOP w0.508: R1103.2 167.76,16.21 R884.2 168.67,16.32 170.05,17.69 v1(171.72,17.69) ; v1(22.41,65.59) 22.17,65.83 RV2.2 ; QH7.5 QH7.2 191.95,15.34 191.43,15.86 RH3.2 190.85,17.43 v1(190.77,17.36) ; RH5.2 197.27,14.39 R3.1 v3(197.32,15.33) ; RH271.2 156.53,71.07 v1(156.51,71.05) 156.48,71.07 RH441.2 ; v1(177.65,77.75) 177.66,77.76 177.66,78.07 RE83.1 ; v1(54.82,76.24) 54.9,76.15 RH367.1 ; v3(185.51,36.6) CS44.1 ; v1(154.34,77.78) 154.27,77.72 RH303.2 ; v1(45.51,75.76) 45.51,75.59 45.93,75.17 47.45,75.17 C1285.1 C1300.1 48.54,74.87 48.94,74.47 49.58,74.47 ; v1(196.3,78.28) 196.3,77.57 PR404.2 ; v1(143.73,65.75) 143.73,65.72 143.03,65.02 CH1226.1 ; R1311.1 v1(64.48,80.18) ; PR604.1 v1(69.94,49.4) ; v1(41.62,60.71) 42.04,60.29 PR409.2
  GND1 w0.381: v4(177.03,57.18) 177.06,57.16 177.03,57.13 177.03,56.98 177.37,56.64 177.63,56.64 v3(177.67,56.68)
  GND1 w0.508: v3(185.51,36.6) 186.52,36.6 v4(186.71,36.79) ; v3(197.32,15.33) 197.05,15.33 v4(196.91,15.46) ; v4(30.09,43.14) 30.43,42.8 v3(30.52,42.8) ; v3(38.7,39.29) 38.41,39.59 v4(38.41,39.71)
  IN1 w0.508: v1(196.3,78.28) 197.32,77.25 201,77.25 203.56,74.68 203.56,62.5 v4(203.52,62.46) ; v4(186.71,36.79) 186.71,36.3 184.31,33.9 184.31,30.82 184.92,30.21 186.38,30.21 186.88,29.71 186.88,28.13 185.36,26.61 185.36,21.68 189.53,17.51 190.62,17.51 v1(190.77,17.36)
  IN2 w0.508: v1(190.77,17.36) 189.9,17.36 188.55,16.01 183.72,16.01 183.14,16.6 172.6,16.6 171.72,17.47 v1(171.72,17.69)
  IN3 w0.508: v1(190.77,17.36) 190.78,17.36 191.6,18.17 v4(195.38,18.17) 195.48,18.27 196.09,18.27 196.61,17.75 196.61,15.76 v4(196.91,15.46) ; v1(41.62,60.71) 41.62,58.24 39.46,56.08 v1(27.06,56.08) ; v1(143.73,65.75) 143.73,66.06 144.15,66.47 145.31,66.47 146.27,65.51 146.27,64.52 146.79,64 146.79,62.06 v1(147.19,61.65) ; v1(43.65,41.17) 42.71,40.23 41.25,40.23 40.73,39.71 v4(38.41,39.71) 38.41,40.02 34.74,43.68 32.43,43.68 31.7,42.96 30.27,42.96 v4(30.09,43.14)
  IN4 w0.381: v1(180.81,72.02) 180.81,71.55
  IN4 w0.508: v4(30.09,43.14) 29.75,43.48 29.75,52.17 v1(27.07,54.85) ; v1(43.65,41.17) 43.49,41.01 43.49,34.62 43.18,34.31 43.18,27.27 43.39,27.06 43.39,24.8 44.84,23.35 44.84,22.4 v4(44.8,22.36) 44.84,22.32 44.84,22.13 45.92,21.05 v4(45.92,20.76) ; 180.81,71.55 180.12,70.85 178.95,70.85 177.72,69.62 177.72,65.26 177.3,64.84 177.3,60.11 177.03,59.84 v4(177.03,57.18)
  GND3 w0.254: v4(45.92,20.76) 45.92,20.76 v5(45.92,20.31)
  GND3 w0.508: v5(196,18.41) 195.63,18.41 v4(195.38,18.17) ; v4(44.8,22.36) 45.38,22.36 v5(45.5,22.25)
  BOTTOM w0.203: PU700.20 79.58,61.3 v1(79.79,61.1)
  BOTTOM w0.254: v1(191.64,44.42) 192.19,43.87 JEDP.40 ; UCPU1.W9 146.57,61.69 UCPU1.V8 147.19,61.95 v1(147.19,61.65) ; UCPU1.K16 UCPU1.K14 143.73,66.54 v1(143.73,65.75)
  BOTTOM w0.508: U726.1 33.43,65.72 34.3,64.86 34.3,58.12 35.15,57.27 41.03,57.27 41.62,57.87 v1(41.62,60.71) ; v1(156.42,66) 156.07,66 RH103.1 ; RH107.1 RH3532.1 ; v1(72.15,61.67) PR713.2 72.15,60.26 PR715.2 ; v1(156.39,64.44) 155.91,64.44 RH466.2 ; RH425.2 156.95,71.05 v1(156.51,71.05) ; RH424.2 157.13,69.18 155.86,69.18 RH458.2 RH459.2 156.18,68.4 v1(156.43,68.15) ; 147.45,79.5 152.53,79.5 154.25,77.78 v1(154.34,77.78) ; RH457.2 RH460.2 RH200.2
  vias: v1(25.27,55.24) v1(25.84,55.51) v1(25.84,54.88) v1(26.47,56.08) v1(26.47,55.51) v1(26.47,54.88) v1(27.06,55.48) v1(159.43,64.47) v1(159.47,67.98) v4(153.98,73.71) v4(154.58,73.72) v4(155.15,73.72) v6(153.62,59.15)
+3VS_AUDIO: length 248.9
  TOP w0.508: v1(159.05,45.17) 159.05,44.8 159.45,44.4 RH42.1 ; LA14.1 39.8,26.24 v1(39.92,26.36) ; RA37.1 15.29,34.75 v1(14.73,35.3) ; RA18.1 19.39,21.67 v1(19.54,21.53) ; RA38.1 20.76,35.1 v1(20.66,35.2) ; RA14.1 v1(40.54,32.4) ; CH85.1 143.87,57.05 v1(143.91,57.09)
  IN1 w0.508: 158.5,46.24 157.12,47.62 154.16,47.62 153.45,48.33 152.77,48.33 152.23,48.88 150.91,48.88 150.11,49.68 148.85,49.68 148.35,49.18 146.94,49.18 144.16,51.96 144.16,56.83 v1(143.91,57.09)
  IN2 w0.508: v1(19.54,21.53) 19.65,21.53 21.75,19.44 29.68,19.44 34.14,23.9 37.46,23.9 v1(39.92,26.36)
  IN3 w0.508: v1(159.05,45.17) 159.05,44.4 159.11,44.33 159.11,42.58 157.87,41.34 141.91,41.34 139.6,43.65 139.6,49.12 139.03,49.69 138.28,49.69 137.9,49.31 137.9,40.74 134.84,37.68 134.84,23.18 132.2,20.54 126.04,20.54 124.63,19.12 119.85,19.12 117.55,21.43 110.3,21.43 109.59,22.14 103.13,22.14 102.29,21.3 98.89,21.3 98.52,21.67 88.54,21.67 88.52,21.64 88.07,21.64 88.05,21.67 73.17,21.67 72.95,21.89 52.5,21.89 51.29,23.1 46.04,23.1 43.41,25.73 40.54,25.73 39.92,26.35 v1(39.92,26.36) 39.21,27.06 39.21,31.07 v1(40.54,32.4) ; v1(36.05,34.48) 34.73,35.79 21.26,35.79 v1(20.66,35.2) 20.19,34.73 15.31,34.73 v1(14.73,35.3)
  BOTTOM w0.254: v1(143.91,57.09) 143.62,56.8 UCPU1.AH14
  BOTTOM w0.508: v1(159.05,45.17) 157.87,45.17 RC9.1 ; v1(40.54,32.4) 38.13,32.4 v1(36.05,34.48) ; RA19.1 v1(20.66,35.2)
  vias: v6(35.4,36.04)
+3VS_CAM: length 24.9
  TOP w0.508: R2670.2 45.94,60.15 45.43,60.66 v6(45.43,68.21) 45.43,70.82 46.11,71.5 52.98,71.5 v1(53.41,71.07)
  BOTTOM w0.508: JCAM.1 54.6,71.64 54.82,71.42 54.82,70.81 54.92,70.71 C1221.1 C4.1 54.03,70.35 53.41,70.96 v1(53.41,71.07)
+3VS_CR: length 11.8
  BOTTOM w0.254: 194.18,27.23 194.03,27.37 JEDP.7
  BOTTOM w0.508: 194.18,27.23 194.65,26.76 194.65,24.56 193.1,23.01 193.1,21.19 193.46,20.82 195.21,20.82 196.32,19.71
  vias: v1(196.19,20.02) v1(196.65,19.63) v1(197.2,19.29) v1(197.3,19.87) v6(196.8,20.19)
+3VS_NGFF: length 17.1
  BOTTOM w1.524: 34.51,50.55 34.84,50.88 48.42,50.88 49.62,49.67 49.62,48.33
  vias: v1(32.78,50.61) v1(32.78,50.03) v1(32.78,49.46) v1(33.35,50.61) v1(33.35,50.03) v1(33.35,49.46) v1(49.1,45.15) v1(49.66,45.15) v1(50.22,45.15) v6(49.74,46.1)
+3VS_TP: length 107.7
  TOP w0.381: RE6.1 174.06,67.51 v1(173.56,67.01) 173.02,67.56 RE7.1
  TOP w0.508: R1105.2 190.73,16.57 v1(190.8,16.63) ; C7.1 188.31,18.7 188.99,18.02 189.71,18.02 190.51,18.82 v1(190.92,18.82) v6(194.85,18.82) 195.13,18.82 195.57,18.38 R1323.2 199.23,17.12 C1159.1 198.55,16.44 198.45,16.44 197.97,15.96 196.74,15.96 196.47,15.69 R1104.2
  IN2 w0.508: v1(180.48,17.27) 180.48,18.26 181.04,18.82 182.76,18.82 183.46,18.12 183.46,17.19 183.98,16.67 188.27,16.67 190.42,18.82 v1(190.92,18.82) 191.42,18.32 191.42,17.1 190.95,16.63 v1(190.8,16.63)
  IN3 w0.508: v1(173.56,67.01) 173,66.45 173,65.67 173.95,64.73 174.02,64.73 174.74,64 174.74,56.63 173.61,55.5 173.61,52.41 172.86,51.66 172.86,49.28 174.07,48.08 174.07,43.1 177.86,39.32 178.72,39.32 180.73,37.31 180.73,29.18 179.67,28.13 177.91,28.13 177.44,27.66 177,27.66 176.1,26.76 176.1,22.23 173.96,20.09 v1(172.47,20.09)
  BOTTOM w0.254: 187.78,18.87 187.33,18.87 187.15,19.04 JTP1.1
  BOTTOM w0.305: 187.78,18.87 188.99,18.87
  BOTTOM w0.508: 188.99,18.87 190.87,18.87 v1(190.92,18.82) ; v1(180.48,17.27) 179.57,18.18 175.39,18.18 173.49,20.09 v1(172.47,20.09)
+3VS_TPM: length 39.4
  TOP w0.356: U652.24 180.97,50.48
  TOP w0.381: U652.19 184.22,52.17 ; C1139.1 179.67,43.08 U652.3 ; C1142.1 184.62,43.38 184.22,43.79 U652.10 ; 184.1,52.23 183.6,52.74 183.6,53.11 183.47,53.23 181.97,53.23 180.97,52.23 180.97,50.48 ; C1137.1 185.52,42.83 U652.12
  TOP w0.508: C1139.1 v3(180.81,42.83) 181.31,42.83 181.58,42.56 181.58,41.42 182.23,40.76 v2(182.71,40.76) 183.27,40.76 183.86,41.36 183.86,42.62 184.07,42.83 C1142.1 C1137.1 186.12,42.83 v1(186.26,42.69)
  GND1 w0.254: v3(180.81,42.83) 180.81,42.62 v4(181.03,42.41)
  IN4 w0.508: v1(186.26,42.69) 186.26,45.79 187.04,46.57 187.04,48.32 185.75,49.6 v1(185.75,52.9)
  GND3 w0.305: v5(181.07,42.94) 181.07,42.45 v4(181.03,42.41)
  BOTTOM w0.508: v5(181.07,42.94) 181.07,43.57 181.58,44.08 183.1,44.08 183.94,44.92 C1141.1
+3VS_TS: length 15.3
  TOP w0.102: v1(46.77,64.59) v6(46.77,65.73)
  IN3 w0.508: v1(46.77,64.59) 46.77,68.39 45.98,69.17 45.98,74.09 48.7,76.81 v1(49.17,76.81)
+3VS_TSLDO: length 23.2
  BOTTOM w0.381: 71.18,77.97 71.77,78.56 JTS.6
  BOTTOM w0.508: v1(53.48,78.6) 54.35,79.46 58.09,79.46 60.67,76.88 64.28,76.88 64.51,77.11 70.32,77.11 71.18,77.97 ; C1222.1 C5.1 72.14,78.56 JTS.6
  vias: v2(53.74,79.57)
+5V_USB_P1:
  vias: v1(19.42,43.79) v1(19.44,43.16) v1(19.44,42.56) v1(20.02,43.79) v1(20.03,43.16) v1(20.03,42.56) v1(20.69,43.75) v1(20.69,43.13) v6(20.53,40.48)
+5VALW: length 316.7
  TOP w0.203: U718.4 52.2,61.69 52.79,61.69 v1(52.9,61.8) ; v1(31.29,41.26) 31.29,41.2 31.36,41.13 31.36,40.7 31.35,40.7 U664.4 ; v1(40.44,54.12) 40.15,54.12 40.15,54.12 U720.4 ; v1(51.53,55.3) 51.44,55.21 U719.4 ; U715.4 202.79,35.27 202.79,35.63 202.68,35.73 202.68,36.8 202.89,37 v3(202.9,37) ; v1(205.09,19.97) 204.19,19.97 U716.4 ; U717.4 203.3,25.86 204.25,25.86
  TOP w0.254: U34.4 161.94,59.99 161.52,60.41 161.52,62.02 161.74,62.24 162.53,62.24 163.36,63.07 v3(163.42,63.07) 163.79,63.45 U673.2
  TOP w0.356: v1(12.22,8.74) RP13.10 ; RP13.5 v1(7.32,6.14)
  TOP w0.508: v1(3.52,10.3) LED10.2 ; PR105.2 34.25,68.61 38.85,68.61 40.47,67 v1(40.47,66.58) ; v1(3.5,3.1) LED13.2 ; LED11.2 3.35,6.7 3.84,6.21 v1(3.84,5.67) ; v1(3.55,13.9) LED14.2 ; 204.25,25.86 204.37,25.86 204.63,25.6 v3(204.93,25.6) ; RA81.1 40.16,25.24 40.55,24.84 v1(40.83,24.84) ; LED12.2 v1(3.36,17.5)
  TOP w2.032: 176.05,14.69 135.98,14.69 132.33,18.34 v6(114.58,18.34) 108.44,18.34 107.23,17.13 94.24,17.13 93.4,16.29 v6(80.69,16.29) 59.17,16.29 57.11,18.34 v6(55.19,18.34) 50.78,18.34 48.77,16.33 43.89,16.33 43.88,16.33
  GND1 w0.254: v3(163.42,63.07) 163.34,63.07 v4(163,63.41)
  GND1 w0.508: v3(202.9,37) 202.9,37.38 v4(203.04,37.52) ; v3(204.93,25.6) v4(204.93,25.05)
  IN1 w0.508: v1(26.09,41.3) 28.18,41.3 28.99,40.5 30.55,40.5 31.29,41.23 v1(31.29,41.26) ; 179.33,16.05 179.33,16.96 181.18,18.82 182.17,18.82 184.75,21.4 184.75,28.55 185.67,29.47 v4(186.19,29.47) ; v1(48.01,20.96) 48.01,18 47.2,17.18 42.17,17.18 42.14,17.15 v1(42.13,17.15)
  IN2 w0.508: v1(51.53,55.3) 51.35,55.3 51.02,55.63 51.02,56.06 52.32,57.35 52.32,61.22 v1(52.9,61.8) ; v4(204.93,25.05) 204.93,23.86 204.28,23.21 204.28,20.79 205.09,19.98 v1(205.09,19.97) 204.87,19.97 203.26,18.35 196.51,18.35 v1(195.83,17.66) ; v7(76.55,55.07) 72.76,58.85 72.76,65.41 72.23,65.93 67.29,65.93 v1(67.04,66.19)
  IN3 w0.508: v4(203.04,37.52) 203.3,37.52 204.17,36.65 204.17,35.52 205.24,34.45 205.24,25.36 v4(204.93,25.05)
  IN4 w0.508: v4(163,63.41) 164.73,63.41 165.76,62.39 167.9,62.39 169.41,60.87 169.41,58.92 169.86,58.47 170.9,58.47 172.27,57.1 172.27,55.93 173.27,54.92 178.21,54.92 180.27,52.86 180.27,49.05 180.54,48.78 180.94,48.78 182.67,47.06 182.67,46.54 184.69,44.52 184.69,41.81 185.68,40.82 185.68,38.79 186.11,38.35 186.11,29.54 v4(186.19,29.47)
  BOTTOM w0.305: JKB1.1 47.42,20.79 47.58,20.96 v1(48.01,20.96)
  BOTTOM w0.508: v1(48.01,20.96) 47.4,21.57 C376.1 ; PR721.1 v7(76.55,55.07) 76.81,54.8 76.81,53.81 76.49,53.49 73.87,53.49 73.42,53.04 PR603.1
  vias: v1(24.32,41.25) v1(24.33,40.65) v1(24.9,41.29) v1(24.91,40.69) v1(25.48,41.31) v1(25.49,40.7) v1(26.09,40.68) v1(41.45,15.62) v1(41.48,17.08) v1(41.47,16.2) v1(41.9,16.57) v1(42,15.62) v1(42.44,16) v1(42.47,16.58) v1(50.6,57.41) v1(50.6,56.85) v1(178.22,15.67) v1(178.45,15.15) v1(178.92,15.49) v1(178.97,14.92) v1(179.51,15.52) v1(179.54,14.92) v1(180.12,14.92) v1(180.69,14.93) v1(194.77,17.15) v1(194.78,16.58) v1(195.23,17.51) v1(195.31,16.91) v1(195.31,16.33) v1(195.89,17.05) v1(195.89,16.47) v7(51.46,53.93) v7(51.46,53.29) v7(51.46,52.66) v7(52.1,53.93) v7(52.1,53.29) v7(52.1,52.66) v7(52.73,53.93) v7(52.73,53.29) v7(54.5,49.9) v7(54.5,49.26) v7(54.5,48.63) v7(55.14,49.9) v7(55.14,49.26) v7(55.14,48.63) v7(55.77,49.9) v7(55.77,49.26) v7(55.77,48.63) v7(56.41,49.9) v7(56.41,49.26) v7(56.42,48.61) v7(56.98,49.56) v7(56.99,48.9)
+5VALWP: length 16.5
  TOP w0.102: v1(61.93,54.39) v2(62.6,54.39)
  IN1 w0.508: v1(61.93,54.39) 61.93,54.38 62.17,54.38 62.55,54 62.55,52.94 60.72,51.11 60.72,49.24 v1(61.57,48.39)
  BOTTOM w0.203: v1(61.93,54.39) 61.86,54.45 60.85,54.45 PU300.14
  BOTTOM w0.254: PR301.1 55.47,52.29 55,51.82 55,51 55.52,50.48 57.52,50.48 58.79,49.21 58.79,48.56
+5VS: length 365.5
  TOP w0.381: UV1.16 17.76,76.01 CV13.1
  TOP w0.508: v1(167.51,19.82) 166.49,18.8 R886.2 ; v1(17.8,76.7) CV13.1 ; v1(53.75,67.95) 53.81,67.88 57.98,67.88 58.73,67.13 59.15,67.13 v6(59.35,67.33) 59.64,67.62 67.07,67.62 67.98,66.72 73.16,66.72 73.27,66.84 81.45,66.84 81.86,66.43 87.11,66.43 91.53,62 PC710.2 92.49,61.1 v7(92.55,61.16) ; v1(138.58,79.3) 138.2,79.68 113.87,79.68 103.41,69.22 103.41,60.24 v1(102.48,59.32) ; v1(157.3,79.03) 158.99,77.35 QC5.2
  IN1 w0.508: v1(53.75,67.95) 53.65,67.84 53.65,65.71 52.48,64.54 47.73,64.54 v4(47.15,63.96) ; v1(157.3,79.03) 156.69,79.64 138.92,79.64 v1(138.58,79.3)
  IN2 w0.508: v4(25.05,58) 25.03,58 23.59,59.44 22.55,59.44 21.94,60.05 21.94,63.98 23.13,65.17 23.13,72.35 21.67,73.81 19.77,73.81 17.8,75.78 v1(17.8,76.7)
  IN3 w0.508: v4(47.15,63.96) 46.19,63.01 46.19,54.5 45.5,53.8 v1(44.67,53.8) ; v4(25.05,58) 25.05,56.09 24.66,55.7 24.66,52.18 24.56,52.08
  IN3 w1.016: 26.32,52.08 24.56,52.08 22.08,49.6 22.08,41.2 23.47,39.81 27.02,39.81 27.95,38.88 33.11,38.88 33.99,38.01 34,38.01 37.1,34.91 37.1,26.52 37.36,26.26 37.36,23.52 40.35,20.52 41.92,20.52 42.99,19.44 44.8,19.44 45.53,18.7 46.11,18.7
  IN4 w0.508: v7(92.55,61.16) 97.22,61.16 99.07,59.32 v1(102.48,59.32)
  GND3 w0.508: v5(25.65,58.18) 25.47,58 v4(25.05,58)
  BOTTOM w0.203: PU701.2 92.03,60.65 v7(92.55,61.16)
  BOTTOM w0.508: QV2.2 25.47,58 v5(25.65,58.18) ; 166.71,14.59 167.72,15.6 167.72,18.78 167.51,18.99 v1(167.51,19.82)
  BOTTOM w1.016: 47.86,19.11 49.21,19.11 50.08,18.24 56.93,18.24 59.34,15.83 94.33,15.83 95.31,16.8 105.52,16.8 106.56,17.83 114.93,17.83 115.86,16.91 126.84,16.91 127.77,17.83 133.98,17.83 137.83,13.98 164.48,13.98
  vias: v1(44.04,53.8) v1(44.01,52.02) v1(44.61,52.02) v1(46.74,18.12) v1(47.3,18.13)
+5VS_AUDIO: length 6.1
  TOP w0.102: v1(45.37,58.43) v6(45.37,59.08)
  BOTTOM w1.016: 35.83,22.28 30.47,22.28 LA3.1
  vias: v1(40.23,28.21) v1(40.23,27.64) v1(40.23,27.07) v1(40.8,28.21) v1(40.8,27.64) v1(40.8,27.07) v1(44.8,58.43) v1(44.8,57.86) v1(45.05,57.29) v1(45.05,56.72) v1(45.37,57.86)
+AVDD1: length 2.7
  TOP w0.203: v1(29.49,23.51) 29.66,23.68 UA2.45
  BOTTOM w0.102: CA102.1 v6(27.55,20.61)
+AVDD2:
  vias: v1(25.37,33.35) v1(25.94,33.35) v1(30.13,32.72) v1(30.51,32.3) v6(25.89,33.91)
+DVDD: length 8.9
  TOP w0.203: UA2.7 35.35,27.75 35.35,27.75 35.58,27.75
  TOP w0.254: 35.58,27.75 36.77,27.75 CA31.1
  GND1 w0.508: v4(33.98,21.72) v3(32.99,21.72) ; v4(35.97,23.03) 35.84,22.9 v3(35.84,22.63)
  IN4 w0.508: v4(33.98,21.72) 34.66,21.72 v4(35.97,23.03) 36.29,23.34 v1(36.29,25.99)
  vias: v6(36.82,25.7)
+DVDDIO: length 4.8
  TOP w0.203: CA104.1 32.46,33.25 32.46,31.5 UA2.19
  TOP w0.508: CA104.1 32.98,33.48 CA105.1 RA80.1
+PVDD1:
  vias: v1(29.56,25.23) v1(30.13,25.22) v2(31.76,26.07)
+PVDD2: length 0.8
  BOTTOM w0.102: v2(31.79,24.44) 31.65,24.58 v1(31.65,25.22)
  vias: v1(32.22,25.22)
+V1.05A_AOSCSUS: length 35.4
  TOP w0.508: L63.1 168.75,47.71 v1(169.33,47.13) ; v1(147.22,59.78) 146.65,60.35 CH1232.1
  IN1 w0.508: v1(147.22,59.78) 147.13,59.78 146.42,59.06 146.42,58 146.89,57.53 146.93,57.53 147.15,57.31 147.18,57.31 147.49,56.99 147.49,52.51 148.91,51.09 150.61,51.09 151.62,50.08 153.9,50.08 154.13,50.32 155.15,50.32 156.06,49.41 158.27,49.41 v1(159.49,48.19)
  BOTTOM w0.254: UCPU1.AB8 147.02,59.98 v1(147.22,59.78)
  BOTTOM w0.508: v1(169.33,47.13) 168.84,47.62 CH61.1 167.68,47.62 v2(166.67,48.64) 166.62,48.69 165.32,48.69 164.83,48.19 v1(159.49,48.19)
+V1.05A_DCPSUS1: length 10.1
  TOP w0.076: v2(141.56,64.05) 141.64,63.98 RH407.1
  TOP w0.508: RH407.1 143.58,63.98 CH1219.1 143.95,64.08 v1(144.33,63.7)
  IN3 w0.508: v1(144.33,63.7) 144.33,60 144.65,59.69 v1(144.87,59.69)
  BOTTOM w0.254: v1(144.87,59.69) 145.29,59.27 UCPU1.AD10 UCPU1.AD8
+V1.05A_DCPSUS2: length 8
  TOP w0.076: v2(145.24,56.57) 144.73,57.08 v1(144.72,57.08)
  TOP w0.457: v1(144.72,57.08) 144.2,57.6 CH1221.1
  TOP w0.508: RH408.2 144.65,61.55 v1(144.89,61.31)
  IN1 w0.508: v1(144.89,61.31) 144.15,60.58 144.15,59.32 144.95,58.52 144.95,57.31 v1(144.72,57.08)
  BOTTOM w0.254: UCPU1.AH13 144.44,56.8 v1(144.72,57.08)
+V1.05A_DCPSUS3: length 0.6
  BOTTOM w0.254: v1(143.77,67.4) 144.11,67.06 UCPU1.J13
  vias: v2(143.44,67.78)
+V1.05S_APLLOPI: length 50.6
  TOP w0.508: CH1213.1 139.68,61.33 v1(139.54,61.19) ; LH12.2 168.55,45.35 166.88,43.68 v2(166.62,43.68) 165.31,43.68 v1(165.18,43.81)
  IN1 w0.508: v1(139.54,61.19) 140.12,61.19 141.06,62.14 144.52,62.14 144.65,62 145.43,62 145.68,61.75 145.68,57.72 146.26,57.14 146.26,56.84 145.78,56.36 145.78,52.32 146.18,51.91 146.44,51.91 147.03,51.32 147.03,50.26 147.36,49.93 148.05,49.93 148.4,50.29 150.43,50.29 151.23,49.49 152.66,49.49 153.18,48.97 155.32,48.97 155.48,48.8 157.92,48.8 160.01,46.71 162.07,46.71 164.97,43.81 v1(165.18,43.81)
  BOTTOM w0.254: UCPU1.AA21 139.92,60.82 v1(139.54,61.19) 139.92,61.57 UCPU1.W21
  BOTTOM w0.508: v1(165.18,43.81) 165.39,43.6 167.1,43.6 168.32,44.81 CH36.1
+V1.05S_ASATA3PLL: length 5.3
  BOTTOM w0.254: 144.68,73.35 144.49,73.15 UCPU1.A12 144.91,71.86 UCPU1.B11
  BOTTOM w0.305: 144.68,73.35 144.68,74.26
  BOTTOM w0.381: RH43.2 145.51,75.06 145.51,74.55 145.22,74.26 v1(144.64,74.26)
  vias: v2(144.91,77.16)
+V1.05S_AUSB3PLL: length 10
  BOTTOM w0.254: UCPU1.B18 140.61,71.76 140.61,72.43 140.83,72.66 140.83,73.37
  BOTTOM w0.305: v1(139.04,77.11) RH338.1 139.04,76.21 138.1,75.27 137.76,75.27 137.32,74.82 137.14,74.82 136.52,74.21 136.47,74.15 136.47,73.11 136.15,72.8 136.15,72.12 136.15,72.11 136.15,72.01 UCPU1.B27
  BOTTOM w0.381: v1(141,74.25) 141,73.53 140.83,73.37
  vias: v6(139.02,75.22)
+V1.05S_AXCK_DCB: length 44.1
  TOP w0.076: v2(139.12,66.99) 139.71,66.99 139.93,66.77 CH1229.1
  TOP w0.508: L61.2 174.45,54.78 174.9,55.23 v1(174.9,55.96) ; CH1229.1 140.36,67.44 v1(140.91,67.98)
  IN4 w0.508: v1(140.91,67.98) 140.91,67.4 141.99,66.32 141.99,65.57 143.02,64.55 144.58,64.55 ; 151.99,64.85 153.52,64.85 155.44,66.77 158.82,66.77 159.1,66.49 162.32,66.49 162.59,66.22 164.07,66.22 165.44,64.86 167.11,64.86 168.35,63.62 169.8,63.62 170.54,62.89 170.54,62.24 172.01,60.77 172.01,59.32 174.9,56.44 v1(174.9,55.96)
  BOTTOM w0.254: UCPU1.J18 140.91,67.54 ; 140.91,67.54 UCPU1.K19 ; 140.91,67.54 v1(140.91,67.98)
  BOTTOM w0.508: v1(174.9,55.96) 174.69,55.76 CH62.1
+V1.05S_AXCK_DCB_L: length 2.8
  TOP w0.102: v2(175.39,57.79) RH355.2
  TOP w0.508: RH355.2 174.21,56.95 L61.1
+V1.05S_AXCK_LCPLL: length 50.3
  TOP w0.102: v1(171.68,56.86) 172,56.54 v2(172,55.8)
  TOP w0.508: v1(140.36,72.91) 140,73.28 RH113.2 ; v1(171.68,56.86) 170.91,56.09 L62.2
  IN3 w0.508: v4(158.27,74.88) 158.27,73.69 164.46,67.5 164.46,66.37 170.73,60.09 170.73,57.81 v1(171.68,56.86) ; v1(140.36,72.91) 140.94,72.34 141.8,72.34 142.03,72.11 147.45,72.11 148.23,72.89 152.37,72.89 154.02,74.55 v4(154.88,74.55)
  IN4 w0.508: v4(158.27,74.88) 158.27,74.88 157.99,74.59 154.94,74.59 154.9,74.55 v4(154.88,74.55)
  BOTTOM w0.254: UCPU1.A20 140.08,72.43 140.36,72.71 v1(140.36,72.91)
  BOTTOM w0.508: v1(140.36,72.91) 140.12,73.15 CH1231.1 ; v1(171.68,56.86) 171.02,56.19 CH65.1
+V1.05S_AXCK_LCPLL_L: length 2.4
  TOP w0.102: RH356.2 170.4,58.21 171.21,59.03 v2(172.03,59.03)
+V1.05VS_VCCHSIO:
  vias: v1(144.74,65.67) v1(144.99,65.15) v1(145.35,65.61) v1(145.58,65.12) v2(147.76,73.54)
+VCC_CORE: length 71.4
  TOP w0.508: RC97.1 113.12,73.04 113.61,73.52 114.98,73.52 116.86,71.64 116.86,69.32
  BOTTOM w0.102: 133.35,68.44 133.35,68.73 UCPU1.G31 ; 116.77,61.3 116.77,61.38 UCPU1.W57 ; 125.53,69.17 125.53,69.03 UCPU1.G43 ; 118.37,68.49 118.37,68.67 UCPU1.G55 ; 116.33,65.78 116.33,65.71 UCPU1.M57 ; UCPU1.G27 135.93,68.99 135.93,69.14 ; UCPU1.G27 135.91,68.68 135.91,68.44 ; UCPU1.G27 135.64,68.95 135.64,69.18 ; UCPU1.G27 135.56,68.62 135.56,68.51 ; UCPU1.G53 119.18,68.98 119.18,69.17 ; UCPU1.G53 119.22,68.71 119.22,68.45 ; UCPU1.G53 119.54,69.02 119.54,69.14 ; UCPU1.G53 119.55,68.61 119.55,68.52 ; 134.56,69.19 134.56,69 UCPU1.G29 ; 124.79,69.43 124.79,69.4 UCPU1.F44 ; UCPU1.F52 119.78,69.4 119.78,69.42 ; UCPU1.F52 119.77,68.89 119.77,68.87 ; UCPU1.F52 120.25,68.93 120.25,68.85 ; UCPU1.F52 120.29,69.41 120.3,69.41 ; 116.73,64.52 116.73,64.38 UCPU1.P57 ; 138.6,67.77 138.6,67.99 UCPU1.H23 ; UCPU1.G49 122.1,68.57 122.13,68.57 ; UCPU1.G49 121.72,68.95 121.72,69.2 ; UCPU1.G49 122.01,68.99 122.01,69.18 ; UCPU1.G49 121.76,68.74 121.76,68.44 ; UCPU1.AD57 116.35,59.2 116.35,59.3 ; UCPU1.AD57 116.8,59.26 ; UCPU1.AD57 116.28,58.73 ; UCPU1.AD57 116.74,58.8 116.74,58.68 ; UCPU1.G23 138.47,69.03 138.47,69.18 ; UCPU1.G23 138.49,68.61 138.55,68.61 ; UCPU1.G23 138.03,68.58 138.03,68.53 ; UCPU1.G23 138.07,69.03 138.07,69.15 ; UCPU1.K23 138.23,66.74 138.23,66.78 ; UCPU1.K23 138.22,66.21 138.18,66.21 ; UCPU1.K23 138.71,66.25 138.71,66.18 ; UCPU1.K23 138.65,66.64 138.65,66.83 ; 137.34,68.91 UCPU1.F24 ; UCPU1.F24 137.39,69.34 137.39,69.46 ; UCPU1.F24 137.76,69.33 137.76,69.46 ; UCPU1.F24 137.75,68.98 137.75,68.84 ; 129.25,68.44 129.25,68.71 UCPU1.G37 ; 131.79,68.44 131.79,68.74 UCPU1.G33 ; 122.31,69.46 122.31,69.38 UCPU1.F48 ; 124.79,68.86 124.79,68.9 UCPU1.F44 ; UCPU1.G45 124.55,68.62 124.55,68.49 ; UCPU1.G45 124.3,68.77 124.3,68.44 ; UCPU1.G45 124.52,68.99 124.52,69.18 ; UCPU1.G45 124.18,68.99 124.18,69.18 ; 120.86,68.48 120.86,68.69 UCPU1.G51 ; 131.7,69.18 131.7,69 UCPU1.G33 ; 130.26,68.84 130.26,68.95 UCPU1.F36 ; UCPU1.G43 125.92,69.02 125.92,69.19 ; UCPU1.G43 125.86,68.7 125.86,68.49 ; UCPU1.G43 125.48,68.57 125.48,68.54 ; 126.84,68.44 126.84,68.81 UCPU1.G41 ; 117.29,69.42 117.29,69.38 UCPU1.F56 ; UCPU1.G35 130.89,68.68 130.89,68.48 ; UCPU1.G35 130.94,69.02 130.94,69.15 ; UCPU1.G35 130.59,68.99 130.59,69.17 ; UCPU1.G35 130.48,68.56 130.48,68.53 ; 120.5,68.52 120.5,68.61 UCPU1.G51 ; UCPU1.G57 117.05,68.61 117.05,68.54 ; UCPU1.G57 116.7,68.95 116.7,69.15 ; UCPU1.G57 117.02,69.02 117.02,69.15 ; UCPU1.G57 116.83,68.82 116.72,68.71 116.72,68.54 116.83,68.43 ; UCPU1.F40 127.36,69.34 127.36,69.43 ; UCPU1.F40 127.78,69.38 127.78,69.45 ; UCPU1.F40 127.72,68.99 127.72,68.82 ; UCPU1.F40 127.35,68.95 127.35,68.81 ; UCPU1.U57 116.39,62.74 116.39,62.57 ; UCPU1.U57 116.82,62.63 ; UCPU1.U57 116.44,63.01 116.44,63.24 ; UCPU1.U57 116.69,63.04 116.69,63.25 ; 123.38,68.49 123.38,68.67 UCPU1.G47 ; UCPU1.J23 138.28,67.08 138.19,67.08 ; UCPU1.J23 138.61,67.17 138.61,66.98 ; UCPU1.J23 138.64,67.44 138.64,67.62 ; UCPU1.J23 138.28,67.5 138.28,67.6 ; UCPU1.G47 123.42,69.02 123.42,69.18 ; UCPU1.G47 123.03,69.02 123.03,69.15 ; UCPU1.G47 122.97,68.56 122.97,68.49 ; UCPU1.AG57 116.78,57.46 ; UCPU1.AG57 116.54,57.7 116.33,57.91 116.33,58.03 ; UCPU1.AG57 116.7,57.85 116.7,58.08 ; UCPU1.AG57 116.41,57.56 116.41,57.35 ; UCPU1.F44 125.3,69.41 125.3,69.42 ; UCPU1.F44 125.23,68.97 125.23,68.86 ; UCPU1.F36 129.83,69.38 129.79,69.38 ; UCPU1.F36 129.84,68.93 129.84,68.86 ; UCPU1.F36 130.06,69.15 130.32,69.41 ; 137.09,68.52 137.09,68.63 UCPU1.G25 ; 126.67,69.17 126.67,69.01 UCPU1.G41 ; 117.77,69.42 117.77,69.4 UCPU1.F56 ; UCPU1.G39 128.03,68.62 128.03,68.52 ; UCPU1.G39 128.4,68.67 128.4,68.48 ; UCPU1.G39 128.43,69.01 128.43,69.17 ; UCPU1.G39 128.06,69.01 128.06,69.15 ; UCPU1.M57 116.77,65.72 116.77,65.77 ; UCPU1.M57 116.77,65.28 116.77,65.2 ; UCPU1.M57 116.35,65.3 116.35,65.18 ; UCPU1.G25 136.72,69 136.72,69.17 ; UCPU1.G25 137.06,69 137.06,69.17 ; UCPU1.G25 136.75,68.68 136.75,68.45 ; UCPU1.W57 116.35,61.8 116.35,61.93 ; UCPU1.W57 116.3,61.35 ; UCPU1.W57 116.77,61.82 116.77,61.89 ; 138.15,65.3 138.15,65.33 UCPU1.M23 ; UCPU1.G55 118.43,69.05 118.43,69.19 ; UCPU1.G55 117.99,68.6 117.99,68.48 ; UCPU1.G55 118.03,69.01 118.03,69.19 ; 129.53,69.15 129.53,68.99 UCPU1.G37 ; UCPU1.F48 122.79,69.4 122.79,69.45 ; UCPU1.F48 122.71,68.98 122.71,68.82 ; UCPU1.F48 122.29,68.91 122.29,68.85 ; 132.34,68.85 132.34,68.92 UCPU1.F32 ; 132.12,68.58 132.12,68.58 UCPU1.G33 ; UCPU1.H23 138.22,68.38 138.22,68.39 ; UCPU1.H23 138.6,68.21 138.6,68.47 ; UCPU1.H23 138.24,67.86 138.23,67.86 ; UCPU1.G51 120.54,69 120.54,69.18 ; UCPU1.G51 120.87,68.98 120.87,69.17 ; UCPU1.F28 135.27,69.35 135.27,69.45 ; UCPU1.F28 134.83,68.9 134.83,68.89 ; UCPU1.F28 135.28,68.94 135.28,68.87 ; UCPU1.F28 134.9,69.32 134.9,69.45 ; 138.71,65.97 138.71,65.89 UCPU1.M23 ; 117.26,68.87 117.26,68.89 UCPU1.F56 ; UCPU1.K57 116.77,67.02 116.77,67.1 ; UCPU1.K57 116.3,66.55 ; UCPU1.K57 116.7,66.65 116.7,66.5 ; UCPU1.K57 116.36,66.99 116.36,67.11 ; UCPU1.G31 133,68.57 133,68.54 ; UCPU1.G31 133.13,68.95 133.13,69.19 ; UCPU1.G31 133.44,69.01 133.44,69.14 ; UCPU1.G37 129.24,68.95 129.24,69.17 ; UCPU1.G37 129.58,68.61 129.58,68.54 ; UCPU1.G33 132.01,68.96 132.01,69.19 ; 127.04,68.52 127.04,68.64 UCPU1.G41 ; UCPU1.F32 132.78,68.93 132.78,68.86 ; UCPU1.F32 132.77,69.35 132.77,69.45 ; UCPU1.F32 132.38,69.34 132.38,69.46 ; UCPU1.AB57 116.36,60.49 116.36,60.65 ; UCPU1.AB57 116.73,60.12 116.73,59.99 ; UCPU1.AB57 116.77,60.52 116.77,60.62 ; UCPU1.AB57 116.32,60.07 ; UCPU1.M23 138.22,65.94 138.22,65.98 ; UCPU1.M23 138.68,65.48 138.68,65.32 ; UCPU1.G29 134.57,68.63 134.57,68.51 ; UCPU1.G29 134.22,68.99 134.22,69.18 ; UCPU1.G29 134.22,68.66 134.22,68.45 ; UCPU1.F56 117.75,68.92 117.75,68.87 ; UCPU1.G41 127.03,69 127.03,69.15 ; 116.37,64.54 116.37,64.37 UCPU1.P57 ; UCPU1.P57 116.31,63.96 ; UCPU1.P57 116.78,63.97
  BOTTOM w0.254: UCPU1.F59 115.58,68.81 ; 115.58,68.81 115.58,68.92 v1(115.28,69.22) ; 115.58,68.81 115.69,68.81 115.99,68.51 v1(115.99,68.48)
  vias: v1(110.14,62.69) v1(114.65,64.69) v1(117.11,68.2) v1(117.37,67.15) v1(117.37,66.34) v1(117.37,65.45) v1(117.37,64.57) v1(117.37,63.68) v1(117.35,62.76) v1(117.35,61.88) v1(117.35,60.99) v1(117.35,60.1) v1(117.35,59.21) v1(117.52,69.75) v1(118.26,68.25) v1(119.4,68.25) v1(120.02,69.72) v1(120.67,68.25) v1(120.68,67.15) v1(120.69,65.79) v1(120.71,65.15) v1(120.71,64.01) v1(120.7,63.36) v1(121.94,68.25) v1(122.54,69.72) v1(123.21,68.25) v1(123.97,67.12) v1(123.98,65.77) v1(124,65.13) v1(124,64) v1(123.99,63.35) v1(124.36,68.25) v1(125.05,69.73) v1(125.75,68.25) v1(127.02,68.25) v1(127.34,67.13) v1(127.35,65.79) v1(127.36,65.15) v1(127.37,64.01) v1(127.36,63.36) v1(127.52,69.73) v1(128.04,68.25) v1(129.44,68.25) v1(130.06,69.73) v1(130.61,68.25) v1(130.74,65.76) v1(130.75,63.34) v1(130.75,65.12) v1(130.76,63.99) v1(132.01,68.26) v1(132.57,69.76) v1(133.18,68.26) v1(133.94,65.76) v1(133.96,65.1) v1(133.96,63.98) v1(133.95,63.35) v1(134.39,68.25) v1(135.07,69.74) v1(135.66,68.25) v1(136.93,68.25) v1(137.43,69.76) v1(137.48,68.42) v1(137.82,67.23) v1(137.82,66.09) v1(137.93,68.04) v1(137.99,63.5) v1(138.05,64.32) v1(138.07,62.74) v6(124.92,61.01) v7(91.15,65.99) v7(91.15,64.72) v7(91.15,63.45) v7(91.41,66.63) v7(91.53,65.36) v7(91.53,64.09) v7(91.91,65.99) v7(91.91,64.72) v7(91.91,63.45) v7(92.17,66.63) v7(92.3,65.36) v7(92.3,64.09) v7(92.68,65.99) v7(92.68,64.72) v7(92.68,63.45) v7(92.93,66.63) v7(93.06,65.36) v7(93.06,64.09) v7(93.44,65.99) v7(93.44,64.72) v7(93.44,63.45) v7(93.69,66.63) v7(93.82,65.36) v7(93.82,64.09) v7(94.2,65.99) v7(94.45,66.63) v7(94.96,65.99) v7(95.22,66.63) v7(95.72,65.99) v7(95.98,66.63) v7(96.49,65.99) v7(96.74,66.63) v7(97.25,65.99) v7(97.5,66.63) v7(98.01,65.99)
+VCCIO_OUT: length 4.9
  BOTTOM w0.102: CH1241.1 v2(113.1,75.5)
  BOTTOM w0.254: UCPU1.A59 115.7,72.87 114.77,73.8 114.77,73.98
  BOTTOM w0.508: CH1241.1 114.14,75.34 114.77,74.7 114.77,73.98
+VCCIOA_OUT: length 1.9
  TOP w0.457: v1(140.89,70.11) 140.72,70.11 140.01,70.82 RC36.2
  BOTTOM w0.254: v1(140.89,70.11) 140.75,70.11 140.43,69.79 UCPU1.E20
AGND: length 25.8
  TOP w0.102: v2(22.71,24.68) 23.33,25.31 CA94.2
  TOP w0.203: v1(27.08,30.24) 27.17,30.15 UA2.30 ; v1(27.16,25.15) 27.36,25.35 27.84,25.35 27.85,25.35 UA2.42 ; UA2.20 32.06,32.14 v3(32.06,32.15)
  TOP w0.381: QA3.4 16.22,31.42 16.01,31.22 v1(15.44,31.22) ; QA1.4 17.53,27.54 17.53,27.32 17.89,26.97 v1(17.89,26.73) ; v1(17.41,32.96) 17.52,33.06 QA3.1 ; v1(15.2,23.14) 15.2,23.13 16.23,24.16 QA1.1
  TOP w0.508: CA84.2 24.39,31.78 23.86,32.31 v1(23.68,32.31) ; RA20.2 16.78,29.51 16.45,29.19 v1(15.89,29.19) ; CA85.2 24.6,30.56 v1(23.94,30.56) ; CA87.2 24.35,23.25 v1(24.35,22.8) ; v1(19.6,28.06) 19.6,27.22 20.1,26.72 QA9.3 ; v1(25.05,22.81) 26.45,22.81 CA93.2 ; CA74.2 v1(20.81,30.59) ; CA40.2 19.87,34.57 19.22,33.92 v1(19.07,33.92) ; QA6.3 v1(24.01,35.12) ; v1(24.64,25.31) CA94.2
  BOTTOM w0.508: CA103.2 28.6,24.84 28.3,25.15 v1(27.16,25.15) ; RA60.2 24.38,32.61 24.07,32.91 v1(23.69,32.91) ; RA35.2 v1(15.44,31.22) ; RA61.2 v1(21.58,30.51)
  vias: v1(5.28,22.92) v1(23.7,21.87) v1(25.05,22.18) v3(26.38,24.66) v3(30.46,34.8) v3(31.53,34.38) v4(27.4,34.88) v4(29.49,34.62) v4(30.76,34.62) v4(31.91,34.3) v5(26.76,34.88) v5(27.91,26.68) v5(27.97,34.88) v5(29.05,34.63) v5(29.94,34.63) v5(31.02,34.88) v5(31.21,31.66)
GND: length 1700.3
  TOP w0.076: 97.4,24.66 UD29.T9 ; UD29.D3 92.59,34.25 ; v6(117.23,72.82) 117.22,72.82 v1(117.22,73.5) ; v1(134.18,73.6) 134.18,74.14 v6(134.28,74.24) ; 97.38,27.85 97.38,27.85 UD29.M9
  TOP w0.102: v3(149.57,44.32) 149.57,43.37 v6(150.27,42.67) ; v6(73.41,23.91) 73.45,23.95 CD67.2 ; v1(165.89,20.12) 165.89,19.34 v6(165.88,19.33) ; v6(101.06,48.13) 101.06,47.51 v1(101.06,47.51) ; v6(52.58,42.05) 52.86,42.32 v7(53.13,42.32) ; v1(23.21,53.67) v6(23.21,52.98) ; v3(29.51,42.93) 28.32,42.93 v6(28.29,42.96) ; v1(27.91,50.95) 27.93,50.92 v6(28.54,50.92) ; v6(145.9,49.09) 145.55,49.09 v1(145.28,48.82) ; v1(191.7,33.71) 191.56,33.57 191.03,33.57 v6(190.9,33.7)
  TOP w0.203: U664.11 31.36,38.44 v3(31.36,37.76) ; U718.11 50.15,61.69 v1(49.24,61.69) ; v1(47.67,55.21) 48.63,55.21 U719.11 ; UA2.10 35.01,28.95 34.56,28.95 34.26,28.65 v1(34.13,28.65) ; PU200.22 51.29,32.09 51.59,32.4 v7(51.97,32.4) ; U720.11 37.52,54.12 37.52,54.12 v1(36.91,54.12) ; v7(41.24,64.15) 41.24,63.96 40.99,63.71 PU401.8 ; v3(201.33,19.97) 202.14,19.97 U716.11 ; U717.11 201.25,25.86 v3(200.51,25.86) ; v3(202.7,32.54) 202.78,32.63 U715.11
  TOP w0.229: v1(121.72,30.65) 121.72,30.64 120.53,30.64 UD32.J2 ; UD31.G1 106.79,31.77 106.79,31.53 107.12,31.21 107.12,30.69 v1(107.08,30.65) ; UD3.J2 145.78,30.64 146.31,30.64 146.59,30.92 146.59,31.45 v1(146.55,31.48) ; v1(93.39,30.65) 93.38,30.64 92.19,30.64 UD29.J2 ; 173.74,30.19 v1(173.4,29.85)
  TOP w0.254: v1(166.3,32.23) 166.28,32.23 UD1.G8 ; v1(80.42,36.29) 79.99,35.86 UD28.B3 ; UD29.E7 96.12,33.77 v1(96.21,33.77) 96.52,33.45 UD29.E8 ; UD1.G9 166.77,31.85 v1(167.14,32.23) 166.71,32.65 UD1.F9 ; UD7.E7 136.8,33.45 v1(137.17,33.83) ; UD3.P1 144.13,26.25 143.56,26.83 v1(143.56,27.54) 143.56,27.82 143.85,28.11 144.33,28.11 144.59,27.85 UD3.M1 ; v1(78.8,30.72) 79.06,30.46 79.06,30.39 UD28.J2 ; v1(132.39,30.72) 132.65,30.46 132.65,30.39 UD7.J2 ; v1(119.73,24.31) 119.73,24.46 119.53,24.65 UD32.T1 ; UD7.E8 137.6,33.45 v1(138.01,33.86) 138.01,33.88 137.63,34.25 UD7.D8 ; UD31.B3 108.31,35.86 v1(108.74,36.29) ; UD32.M9 125.72,27.85 v1(125.32,27.45) ; UD32.D1 119.35,34.28 v1(118.9,34.73) ; UD29.B3 92.6,35.87 v1(92.22,36.26) ; UD32.B1 119.34,35.85 v1(118.92,36.27) ; v1(162.4,36.21) 162.04,35.85 UD1.B3 ; v1(178.91,27.45) 179.32,27.85 UD4.M9 ; UD7.T1 131.98,24.65 v1(132.36,25.03) ; UD32.E2 120.08,33.52 119.41,33.52 UD32.E1 119.07,33.73 119.07,33.75 v1(118.81,34.02) ; UD29.J8 96.6,30.3 v1(96.21,30.69) ; 97.38,27.85 v1(96.99,27.46) ; UD4.P1 171.95,27.25 v1(171.95,27.71) 172.26,28.03 172.77,28.03 UD4.M1 ; v1(78.79,33.85) 78.39,33.45 UD28.E1 ; v1(78.79,33.85) UD28.D1 ; v1(78.79,33.85) UD28.E2 ; UD29.G9 97.5,31.95 97.5,31.96 ; UD29.G9 97.5,31.96 ; UD29.G9 97.38,31.85 v1(96.99,31.46) 96.6,31.85 UD29.G8 ; UD4.A9 179.34,36.65 179.66,36.34 v1(179.66,36.27) ; UD3.B1 144.59,35.87 v1(144.17,36.29) ; UD1.D8 165.95,34.25 166.33,33.88 v1(166.33,33.86) 165.92,33.45 UD1.E8 ; UD31.D3 108.31,34.27 v1(108.82,34.78) ; JXDP.13 72.41,77.59 72.6,77.77 73.68,77.77 73.91,77.53 JXDP.7 ; v1(160.71,33.85) 160.31,33.45 UD1.E1 ; v1(160.71,33.85) UD1.E2 ; v1(160.71,33.85) UD1.D1 ; v1(96.99,34.71) 96.96,34.71 96.6,34.35 UD29.D8 ; UD28.A9 84.83,36.65 v1(85.21,36.27) 84.8,35.85 UD28.B9 ; v1(107.08,30.65) 107.49,30.25 107.49,30.25 UD31.J2 ; UD1.A9 166.77,36.65 v1(167.16,36.27) 166.75,35.85 UD1.B9 ; UD31.G8 112.68,32.23 v1(112.7,32.23) ; UD32.E7 124.38,33.68 124.39,33.68 v1(124.55,33.84) ; UD29.P9 97.4,26.25 v1(97,25.86) ; v1(173.32,24.08) 173.32,24.27 UD4.T1 ; v1(125.34,30.67) 125.19,30.51 125.19,30.49 124.95,30.25 UD32.J8 ; UD7.P1 132.03,26.25 v1(132.43,25.86) ; UD32.G8 124.97,31.85 v1(125.34,31.48) 125.71,31.85 UD32.G9 125.75,31.85 125.75,32.65 UD32.F9 ; UD29.A9 97.4,36.67 v1(97.77,37.04) ; UD32.T9 125.75,24.66 v1(125.34,25.07) ; UD3.T1 144.59,24.08 v1(144.45,23.94) ; UD4.T9 179.34,24.66 v1(178.93,25.07) ; UD4.B1 172.93,35.85 v1(172.52,36.27) ; JXDP.19 70.91,75.13 70.64,74.86 v1(70.64,74.73) ; UD28.E8 83.99,33.45 v1(83.58,33.86) 83.19,33.48 UD28.E7 ; v1(131.5,36.21) 131.86,35.85 UD7.B1 ; UD3.T9 150.99,24.66 v1(150.59,25.07) ; v1(178.99,34.66) 178.99,34.66 178.99,34.66 178.58,34.25 UD4.D8 ; v1(132.38,33.83) 132.01,33.45 UD7.E1 ; v1(132.38,33.83) 132.76,33.45 UD7.E2 ; v1(132.38,33.83) 131.98,34.23 UD7.D1 ; UD28.J8 83.99,30.29 v1(83.62,30.65) ; UD29.B1 90.99,35.85 v1(90.58,36.27) ; v1(131.35,31.47) 131.6,31.47 UD7.G1 ; UD1.J8 165.55,30.61 v1(165.55,30.65) ; UD4.E7 177.97,33.68 177.97,33.69 v1(178.14,33.86) ; v1(159.82,36.34) UD1.B1 ; UD3.B3 146.19,35.91 v1(145.81,36.29) ; UD31.E2 v1(107.09,33.87) ; v1(107.09,33.87) UD31.D1 ; v1(107.09,33.87) 106.71,33.49 UD31.E1 ; v1(126.21,36.98) 125.89,36.65 UD32.A9 ; v1(107.09,35.45) 106.71,35.83 UD31.B1 ; UD4.F9 179.34,32.65 v1(178.91,32.23) ; v1(132.36,28.27) 131.98,27.89 UD7.M1 ; UD3.D8 150.19,34.28 150.58,34.67 150.58,34.66 v1(150.58,34.66) ; UD7.G9 138.38,31.85 v1(138.76,32.23) 138.38,32.6 UD7.F9 ; v1(165.49,33.86) 165.36,33.73 165.36,33.71 UD1.E7 ; v1(178.99,33.85) 178.59,33.45 UD4.E8 ; UD32.P9 125.75,26.25 125.75,26.25 v1(125.35,25.86) ; 97.5,31.96 97.5,32.55 UD29.F9 ; UD7.D3 133.64,34.25 v1(134.05,34.67) ; UD3.A9 151.02,36.65 v1(151.44,36.23) 151.07,35.85 UD3.B9 ; UD31.T1 106.74,24.65 107.15,24.24 v1(107.15,24.23) ; v1(84.41,33.86) 84.02,34.25 UD28.D8 ; UD28.D3 79.99,34.27 v1(80.5,34.78) ; U679.B1 38.69,41.42 v3(39.03,41.76) ; v1(160.75,24.23) 160.75,24.24 160.33,24.65 UD1.T1 ; 97.4,24.66 v1(96.99,25.07) ; v1(178.93,30.67) 178.78,30.51 178.78,30.49 178.54,30.25 UD4.J8 ; PC413.2 35.94,62.45 35.7,62.21 ; v1(139.97,69.4) 139.95,69.38 v1(139.41,69.38) 139.33,69.38 v1(138.64,70.07) 138.54,70.17 138.54,71.29 138.75,71.5 140.34,71.5 140.63,71.21 v1(140.63,71.01) 140.74,70.91 CH1239.2 ; UD3.J8 150.19,30.3 v1(149.8,30.69) ; v1(134.01,36.29) 133.58,35.86 UD7.B3 ; v1(174.13,34.65) 174.53,34.25 UD4.D3 ; v1(178.91,32.23) UD4.G8 ; v1(178.91,32.23) 179.29,31.85 UD4.G9 ; v1(90.55,34.73) 91,34.28 UD29.D1 ; v1(145.78,34.65) 146.18,34.25 UD3.D3 ; UD29.G1 v1(90.63,32.23) ; v1(83.84,23.64) 84.4,24.2 84.4,24.26 UD28.T9 ; UD32.M1 119.33,27.87 118.6,27.87 v1(118.33,27.6) ; v1(78.83,24.23) 78.83,24.24 78.42,24.65 UD28.T1 ; UD31.T9 112.72,24.26 112.72,23.68 ; v1(172.4,34.02) 172.67,33.75 172.67,33.73 UD4.E1 173,33.52 173.68,33.52 UD4.E2 ; UD31.E8 112.32,33.45 v1(112.73,33.86) 112.73,33.88 112.36,34.25 UD31.D8 ; UD3.G8 150.19,31.84 v1(150.57,31.46) 150.66,31.46 150.99,31.8 150.99,31.8 UD3.G9 ; v1(111.9,33.86) 111.76,33.73 111.76,33.71 UD31.E7 ; UD32.P1 119.27,26.25 119.27,26.25 v1(118.84,25.82) ; UD1.D3 161.9,34.27 v1(162.41,34.78) ; UD7.T9 137.99,24.26 137.99,24.12 v1(137.51,23.64) ; v1(125.33,33.83) 124.96,33.45 UD32.E8 ; v1(150.6,25.86) 150.99,26.25 UD3.P9 ; UD28.G8 84.01,31.85 v1(84.38,32.23) ; UD4.P9 179.34,26.25 179.34,26.25 v1(178.94,25.86) ; UD4.B3 174.54,35.88 174.17,36.26 v1(174.16,36.26) ; UD4.D1 172.94,34.28 v1(172.49,34.73) ; 92.59,34.25 v1(92.19,34.65) ; UD28.P1 78.39,26.3 v1(78.77,26.68) ; UD4.B9 179.34,35.85 179.7,35.5 v1(179.7,35.46) ; UD1.P9 167.16,26.71 167.16,27.45 v1(167.1,27.51) 166.75,27.85 UD1.M9 ; UD28.B1 78.3,35.85 v1(77.93,36.22) ; UD31.A9 113.15,36.65 v1(113.53,36.27) 113.13,35.85 UD31.B9 ; PU400.8 192.65,72.75 191.88,73.52 PC406.2 ; UD31.M9 113.16,27.85 v1(113.5,27.51) 113.57,27.45 113.57,26.71 UD31.P9 ; v1(126.2,36.23) 125.83,35.85 UD32.B9 ; UD7.B9 138.4,35.85 v1(138.81,36.27) 138.42,36.65 UD7.A9 ; UD1.M1 160.28,27.87 159.57,27.87 159.3,27.61 v1(159.3,26.88) 159.93,26.25 UD1.P1 ; UD3.D1 144.29,34.25 v1(144.06,34.02) 144.32,33.75 144.32,33.73 UD3.E1 144.66,33.52 145.33,33.52 UD3.E2 ; UD7.J8 137.22,30.62 v1(137.22,30.65) ; UD3.M9 151.32,27.52 v1(151.32,27.45) ; UD28.M9 84.79,27.84 v1(85.18,27.45) 85.25,27.38 85.25,26.71 UD28.P9 ; UD31.M1 106.71,27.81 v1(106.37,27.47) 106.31,27.41 106.31,26.66 UD31.P1 ; UD29.E2 91.74,33.52 91.06,33.52 UD29.E1 90.73,33.73 90.73,33.75 v1(90.46,34.02) ; UD32.G1 v1(118.97,32.23) ; UD4.G1 v1(172.57,32.23) ; UD4.J2 173.74,30.19 ; UD3.E7 v1(149.79,33.85) 149.8,33.85 UD3.E8 UD3.F9 ; v1(90.69,23.94) 91,24.24 UD29.T1 ; v3(160.3,31.85) 160.3,31.6 160.69,31.21 160.69,30.74 v1(160.75,30.68) 161.1,30.33 161.1,30.33 UD1.J2 ; v1(97.77,36.25) 97.4,35.88 UD29.B9 ; v1(111.94,30.65) 111.94,30.62 UD31.J8 ; UD28.G9 84.79,31.85 v1(85.16,32.23) 84.79,32.6 UD28.F9 ; v1(120.51,34.63) 120.51,34.67 120.93,34.25 UD32.D3 ; UD32.D8 124.95,34.27 125.31,34.63 125.31,34.62 v1(125.31,34.62) ; v1(90.55,25.68) 91,26.13 UD29.P1 ; UD31.G9 v1(113.48,32.23) 113.11,32.6 UD31.F9 ; 166.31,23.68 166.31,24.26 UD1.T9 ; UD28.M1 78.3,27.85 78.3,27.85 v1(77.94,28.21) ; v3(161.6,56.74) 161.94,57.08 U34.5 ; UD7.G8 137.58,31.85 137.96,32.23 v1(137.98,32.23) ; UD7.M9 138.42,27.85 v1(138.79,27.48) 138.79,26.66 UD7.P9 ; CH1248.2 v3(146.18,73.28) ; v1(120.56,36.26) 120.57,36.26 120.95,35.88 UD32.B3 ; v1(205.2,61.29) PC500.2 ; UD28.G1 v1(78.01,31.47) ; JXDP.37 66.42,76.22 ; UD3.G1 v1(144.22,32.23)
  TOP w0.279: JXDP.49 63.42,76.22 63.42,77.64 v1(63.56,77.78) ; JXDP.32 67.91,68.71 v1(68.09,68.54) ; JXDP.50 63.42,70.49 63.42,68.4 v1(63.28,68.26) ; v1(69.5,72.31) 69.41,72.22 JXDP.26 ; JXDP.7 73.91,74.98 v1(74.15,74.75) ; JXDP.59 v1(60.91,77.76) ; v3(75.57,68.99) 75.41,69.14 JXDP.2 ; v1(66.19,74.77) 66.42,75 66.42,76.22 ; v3(75.28,74.74) 75.41,74.88 JXDP.1 ; JXDP.31 67.91,77.46 67.66,77.72 v1(67.16,77.72) ; JXDP.8 73.91,70.5 73.91,72.29 v1(73.95,72.33)
  TOP w0.381: v1(24.41,71) 24.75,70.66 PU406.3 ; UV1.15 18.41,74.49 18.41,75.74 CV13.2 ; CH1224.2 145.87,54.55 146.28,54.96 v1(146.42,54.96) ; U671.7 53.75,69.78 53.75,68.57 v1(53.71,68.53) ; v1(6.18,21.64) 6.6,22.06 DA5.2 6.95,22.94 7.22,22.67 CA28.2
  TOP w0.406: U699.3 26.58,46.25 26.42,46.08 26.03,46.08 25.53,46.58 v1(25.43,46.58) ; MD5.3 17.54,60.91 16.22,60.91 v1(15.96,61.17) ; v1(25.07,62.24) 24.82,62.5 PU405.3 ; PQ409.1 22.6,56.02 22.33,55.75 v1(22.33,55.22)
  TOP w0.457: CH1244.2 143.35,47.14 142.97,46.76 142.97,45.95 142.68,45.66 v1(142.38,45.66) ; RH45.1 147.78,53.99 v1(148.28,53.99)
  TOP w0.508: C1300.2 C1285.2 46.6,76.23 v1(46.17,75.8) ; RD53.2 RD51.2 v1(115.16,20.55) ; CH1226.2 142.12,65.83 CH1215.2 142.67,65.85 v1(142.75,65.77) ; RD19.2 RD12.2 141.25,20.59 v1(141.44,20.4) ; v1(49.67,52.19) C1201.2 ; RH44.1 146.88,56.9 v1(146.83,56.85) 146.43,56.45 CH82.2 ; v1(191.9,36.9) 191.8,36.79 C1143.2 ; v1(108.23,20.23) 108.23,20.77 CD79.2 CD82.2 CD93.2 ; RC54.1 RC52.1 114.39,72.26 v1(113.94,72.72) ; CD86.2 v1(121.31,21.01) ; C1240.2 v1(165.21,60.96) ; RV9.2 RV4.2 v1(15.33,67.11) ; RD41.2 RD42.2 CD95.2 v1(150.78,20.14) ; C962.2 21.98,38.32 v1(22.48,37.82) ; v1(191.93,75.69) 191.88,75.64 PC406.2 ; CD50.2 v1(135.48,21.03) ; v1(48.54,68.38) C1286.2 C1299.2 ; v1(209.61,20.1) 209.3,19.8 R1175.1 ; C1204.2 C1203.2 51.2,65.27 v1(50.94,65.53) ; v1(24.73,61.69) 24.29,61.24 PC428.2 ; v1(129.02,78.46) YH2.2 ; v1(8.56,10.16) C2973.2 ; v1(183.19,15.01) 183.01,14.83 MD9.1 ; CH1227.2 145.27,62.99 v1(144.9,62.61) ; C1282.2 v1(63.59,80.24) ; v1(113.98,60.22) 113.81,60.39 RC81.2 ; RE23.1 v3(35.65,15.11) ; PC103.2 v1(26,78.62) ; RC100.2 110.27,72.08 v1(110.72,72.53) ; CD91.2 138.71,21.02 v1(138.71,20.52) ; CH39.2 146.15,64.8 v1(145.52,64.17) 146.08,64.17 RH3531.2 ; PC434.2 PC433.2 v1(24.1,74.82) ; v1(143.98,65.12) 144.19,65.12 144.86,64.45 CH1219.2 ; v1(144.11,20.14) CD44.2 CD54.2 ; CD69.2 74.92,37.05 CD68.2 75.09,37.21 76.79,37.21 v1(77.41,37.83) ; v1(43.78,63.01) PR408.2 ; C1313.2 142.7,76.4 143.58,77.28 v1(143.58,77.76) ; v1(142.94,55.55) 143.44,55.55 143.48,55.51 143.48,55.51 143.8,55.18 CH1207.2 143.9,54.29 RH163.2 ; CD84.2 v3(118.01,21.15) ; v1(163.8,23.57) 163.48,23.26 CD45.2 ; v1(144.94,60.27) 145.01,60.35 CH1232.2 ; v1(94.89,20.47) 94.89,20.88 RD30.2 RD32.2 CD87.2 ; C1220.2 v1(49.09,59.07) ; PD100.1 v1(66.34,29.28) ; DA3.1 v1(17.87,15.92) ; DA4.1 27.5,15.71 v1(27.75,15.96) ; v1(92.82,20.64) 92.38,21.07 CD71.2 ; PC823.2 v1(129.75,67.14) ; CD47.2 v1(137.87,20.85) ; C963.2 C2.2 22.47,41.03 v1(23.11,41.66) ; v1(17.19,12.25) 16.57,11.63 C1309.2 CH95.2 ; v1(141.9,74.25) CH1247.2 ; v1(17.56,20.99) 17.88,21.31 RA41.2 ; v1(143.22,20.14) 143.16,20.21 CD56.2 CD51.2 ; PC403.2 v1(197.25,75.33) ; v1(142.39,49.03) 142.14,49.28 142.14,51.09 141.84,51.4 CH1218.2 ; C1166.2 38.56,56.28 v1(38.17,56.67) ; PR403.2 v1(193.61,75.52) ; PC408.2 37.67,66.47 v1(37.66,66.48) ; v1(111.93,53.69) 112.11,53.87 v3(113.57,53.87) v3(114.52,53.87) ; PC412.2 34.07,64.86 34.05,64.85 v1(33.37,64.85) ; 112.72,23.68 112.72,23.5 112.31,23.1 CD80.2 v1(112.31,20.66) ; v1(141.88,68.11) 142.52,68.75 CH1214.2 ; v1(53.78,59.6) 54.07,59.89 R1177.2 ; v1(95.56,20.46) 95.74,20.28 96.15,20.28 CD140.2 CD136.2 CD139.2 ; v1(150.61,58.74) 150.69,58.82 CH1206.2 ; v1(107.76,19.82) 107.22,19.28 CD142.2 CD144.2 ; v1(141.27,65.23) 141.25,65.24 CH1234.2 CH1229.2 ; CH1232.2 145.5,59.48 CH1216.2 ; CH1232.2 CH47.2 ; v1(25.94,69.85) 25.94,68.9 PR452.2 25.87,68.23 PC324.1 ; CD73.2 v1(79.34,22.67) ; v1(141.27,56.25) 141.63,56.62 CH1233.2 ; v1(52.16,44.81) 51.94,45.04 C1298.2 51.92,45.62 C713.2 ; v7(74.07,51.2) 74.07,51.8 PC611.2 ; SW2.3 v1(190.53,78.89) ; C1164.2 v1(198.05,25.17) ; PC414.2 41.86,64.77 v7(41.24,64.15) ; 166.31,23.68 165.89,23.26 CD41.2 v1(165.89,20.12) ; C1278.2 C355.2 v1(45.2,54.75) ; C1314.2 143.15,75.52 142.73,75.09 v1(142.73,74.19) ; v1(19.09,45.39) C3.2 C265.2 ; v1(191.43,76.88) 190.92,76.88 190.53,76.49 SW2.1 ; v1(75.72,23.95) CD67.2 ; v1(152.07,57.56) 152.07,57.96 CH1225.2 ; CD35.2 CD42.2 CD40.2 v1(161.07,20.14) ; v1(139.5,62.75) 139.11,63.14 CH1235.2 ; C716.2 v1(48.86,41.92) ; v1(191.7,33.71) 191.96,33.97 C6.2 ; v1(142.52,59.93) 143.18,60.59 CH1223.2 143.81,60.59 CH1222.2 ; C1281.2 47.27,62.18 v1(46.83,61.74) 46.83,61.67 47.27,61.23 C1202.2 ; v1(53.05,57.56) C1199.2 ; v1(150.67,70.58) 150.98,70.58 151.43,70.13 CH1246.2 ; v1(145.28,48.82) 144.37,49.73 CH1243.2 ; CD66.2 75.84,27.2 v1(76.1,26.94) ; PC429.2 v1(23.21,74.82) ; v1(48.43,65.17) C1208.2 ; CD88.2 v1(113.25,20.56) ; RC58.1 112.38,51.82 v1(111.83,51.82) ; CH1.2 v1(65.37,80.27) ; v1(19.38,76.05) CV13.2 ; v1(113.98,63.22) 113.57,62.82 RC153.2 ; v1(47.72,57.8) C1200.2 ; RH394.1 v3(147.02,46.05) ; RH3549.2 152.89,55.94 152.07,55.12 v1(152.07,54.59) ; CD46.2 v1(133.13,20.54) ; CH1220.2 141.7,60.66 v1(141.13,61.23) ; v1(149.18,71.67) 149.22,71.71 CH41.2 ; CD81.2 v1(109.06,19.92) ; CH1213.2 139.66,60.41 v1(139.48,60.24) 139.47,60.22 CH1205.2 ; C352.2 47.15,51.89 v1(47.27,52.02) ; CD55.2 v1(149.83,20.14) ; PC718.2 74.66,57.12 74.34,57.44 v1(74.34,58.16) ; v1(141,59.81) 140.39,59.2 CH1217.2 ; C1312.2 v1(137.02,78.37) ; PD101.1 v1(67.89,29.35) ; CD57.2 v1(147.41,22.81) ; CD83.2 v1(123.66,21.06) ; CA105.2 v1(34.07,34.2) ; PC107.2 v1(34.65,78.57)
  GND1 w0.203: JUSB1.11 16.6,37.8 ; JUSB1.11 13.63,38.73 ; JUSB1.11 13.63,37.8 ; JUSB1.11 15.11,39.66 ; JUSB1.11 16.6,38.73 ; JUSB1.11 13.63,39.66 ; JUSB1.11 16.6,39.66 ; JUSB1.11 15.11,37.8 ; 104.5,51.79 H11.1 ; H11.1 102.99,55.36 ; H11.1 106.01,55.36 ; H11.1 106.56,53.85 ; H11.1 102.99,52.34 ; H11.1 106.01,52.34 ; H11.1 104.5,55.91 ; H11.1 102.44,53.85 ; 39.49,70.79 H6.1 ; H6.1 41,74.36 ; H6.1 38.94,72.3 ; H6.1 42.51,70.79 ; H6.1 39.49,73.81 ; H6.1 41,70.24 ; H6.1 43.06,72.3 ; H6.1 42.51,73.81 ; JMDP.23 3.42,55.1 ; JMDP.23 2.31,54.35 ; JMDP.23 3.42,54.35 ; 201.99,51.63 H17.1 ; H17.1 205.56,50.12 ; H17.1 203.5,48.06 ; H17.1 205.01,51.63 ; H17.1 201.44,50.12 ; H17.1 201.99,48.61 ; H17.1 205.01,48.61 ; H17.1 203.5,52.18 ; H19.1 184.73,79.8 ; H19.1 182.27,80.85 ; H19.1 184.37,80.85 ; H19.1 182.27,78.75 ; H19.1 183.32,78.39 ; H19.1 181.91,79.8 ; H19.1 184.37,78.75 ; H19.1 183.32,81.21 ; JMDP.1 10.84,58.45 ; JMDP.1 10.84,57.3 ; JMDP.1 11.32,57.3 ; 1.97,19.85 SW3.4 ; SW3.4 1.97,18.8 ; SW3.4 2.5,20 ; SW3.4 3.03,18.8 ; SW3.4 2.5,18.65 ; SW3.4 3.17,19.33 ; SW3.4 3.03,19.85 ; 104.5,72.79 H10.1 ; H10.1 106.01,73.34 ; H10.1 104.5,76.91 ; H10.1 102.44,74.85 ; H10.1 106.56,74.85 ; H10.1 106.01,76.36 ; H10.1 102.99,76.36 ; H10.1 102.99,73.34 ; 161.79,73.34 H14.1 ; H14.1 161.24,74.85 ; H14.1 164.8,73.34 ; H14.1 164.8,76.36 ; H14.1 161.79,76.36 ; H14.1 165.36,74.85 ; H14.1 163.3,72.79 ; H14.1 163.3,76.91 ; H15.1 164.8,55.36 ; H15.1 163.3,55.91 ; H15.1 165.36,53.85 ; H15.1 161.24,53.85 ; H15.1 161.79,52.34 ; H15.1 164.8,52.34 ; H15.1 161.79,55.36 ; H15.1 163.3,51.79 ; JMDP.19 11.32,63.85 ; JMDP.19 10.84,63.85 ; JMDP.19 10.84,62.7 ; JUSB1.10 16.6,52.46 ; JUSB1.10 15.11,50.6 ; JUSB1.10 15.11,52.46 ; JUSB1.10 16.6,51.53 ; JUSB1.10 13.63,52.46 ; JUSB1.10 16.6,50.6 ; JUSB1.10 13.63,50.6 ; JUSB1.10 13.63,51.53 ; 9.29,70.12 H1.1 ; H1.1 10.7,68.71 ; H1.1 11.75,71.17 ; H1.1 11.75,69.07 ; H1.1 10.7,71.53 ; H1.1 9.65,69.07 ; H1.1 9.65,71.17 ; H1.1 12.11,70.12 ; JUSB1.4 15.47,41.61 ; JUSB1.4 14.72,40.86 ; JUSB1.4 14.14,41.03 ; JUSB1.4 15.31,42.19 ; JUSB1.4 14.72,42.36 ; JUSB1.4 15.31,41.03 ; JUSB1.4 13.98,41.61 ; JUSB1.4 14.14,42.19 ; JMDP.21 13.69,65.43 ; JMDP.21 10.54,66.18 ; JMDP.21 10.54,66.93 ; JMDP.21 10.54,65.43 ; JMDP.21 12.12,66.93 ; JMDP.21 13.69,66.93 ; JMDP.21 13.69,66.18 ; JMDP.21 12.12,65.43 ; 9.29,17.12 H4.1 ; H4.1 11.75,18.17 ; H4.1 10.7,15.71 ; H4.1 12.11,17.12 ; H4.1 9.65,18.17 ; H4.1 9.65,16.07 ; H4.1 10.7,18.53 ; H4.1 11.75,16.07 ; 13.76,59.1 JMDP.8 ; JMDP.8 13.76,60.25 ; JMDP.8 13.76,59.67 ; JMDP.8 14.24,60.25 ; JMDP.8 14.24,59.1 ; 12.12,54.23 JMDP.22 ; JMDP.22 13.69,54.98 ; JMDP.22 10.54,55.73 ; JMDP.22 10.54,54.23 ; JMDP.22 12.12,55.73 ; JMDP.22 13.69,54.23 ; JMDP.22 10.54,54.98 ; JMDP.22 13.69,55.73 ; 10.84,62.18 10.84,62.17 JMDP.13 10.84,61.44 ; H9.1 83.87,79.8 ; H9.1 82.46,78.39 ; H9.1 81.05,79.8 ; H9.1 83.51,78.75 ; H9.1 82.46,81.21 ; H9.1 83.51,80.85 ; H9.1 81.41,80.85 ; H9.1 81.41,78.75 ; SW3.3 3.17,23.38 ; SW3.3 2.5,22.7 ; SW3.3 3.03,22.85 ; SW3.3 1.97,22.85 ; SW3.3 1.97,23.9 ; JMDP.24 3.42,65.84 ; JMDP.24 3.42,66.59 ; JMDP.24 1.21,65.84 ; JMDP.24 1.21,66.59 ; JMDP.24 2.31,66.59 ; 13.76,62.05 JMDP.14 ; JMDP.14 13.76,60.9 ; JMDP.14 14.24,60.9 ; JMDP.14 14.24,62.05 ; JMDP.14 13.76,61.47 ; JUSB1.7 13.81,44.53 ; JUSB1.7 12.47,45.11 ; JUSB1.7 13.81,45.69 ; JUSB1.7 13.22,45.86 ; JUSB1.7 12.64,45.69 ; JUSB1.7 13.97,45.11 ; JUSB1.7 12.64,44.53 ; JUSB1.7 13.22,44.36 ; 10.84,60.79 10.84,61.44 ; 10.84,61.44 10.39,60.99 ; 186.64,23.12 H16.1 ; H16.1 190.21,24.63 ; H16.1 188.7,25.18 ; H16.1 187.19,24.63 ; H16.1 190.76,23.12 ; H16.1 190.21,21.61 ; H16.1 187.19,21.61 ; H16.1 188.7,21.06 ; 10.84,58.99 10.84,58.99 10.84,59.66 ; 10.84,59.66 JMDP.7 10.84,60.29 ; 10.84,59.66 10.41,59.23 ; 214.26,14.42 H18.1 ; H18.1 216.72,15.47 ; H18.1 214.26,16.52 ; H18.1 216.36,16.52 ; H18.1 216.36,14.42 ; H18.1 215.31,14.06 ; H18.1 213.9,15.47 ; H18.1 215.31,16.88 ; JUSB1.12 6.01,53.9 ; JUSB1.12 3.64,52.97 ; JUSB1.12 6.01,52.97 ; JUSB1.12 3.64,53.9 ; JUSB1.12 4.82,53.9
  GND1 w0.254: 6.46,37.26 6.44,37.27 JUSB1.13 3.17,37.27 3.15,37.28
  GND2 w0.203: H6.1 43.06,72.3 ; H6.1 38.94,72.3 ; H6.1 42.51,73.81 ; H6.1 39.49,70.79 ; H6.1 41,70.24 ; H6.1 41,74.36 ; H6.1 39.49,73.81 ; H6.1 42.51,70.79 ; JMDP.19 10.84,63.85 ; JMDP.19 11.32,63.85 ; JMDP.19 10.84,62.7 ; SW3.4 3.17,19.33 ; SW3.4 1.97,18.8 ; SW3.4 3.03,18.8 ; SW3.4 2.5,20 ; SW3.4 2.5,18.65 ; SW3.4 3.03,19.85 ; SW3.4 1.97,19.85 ; H14.1 164.8,73.34 ; H14.1 161.24,74.85 ; H14.1 161.79,76.36 ; H14.1 164.8,76.36 ; H14.1 161.79,73.34 ; H14.1 165.36,74.85 ; H14.1 163.3,72.79 ; H14.1 163.3,76.91 ; H19.1 184.37,78.75 ; H19.1 182.27,80.85 ; H19.1 184.37,80.85 ; H19.1 183.32,78.39 ; H19.1 182.27,78.75 ; H19.1 184.73,79.8 ; H19.1 181.91,79.8 ; H19.1 183.32,81.21 ; JMDP.1 11.32,57.3 ; JMDP.1 10.84,57.3 ; JMDP.1 10.84,58.45 ; H18.1 216.36,14.42 ; H18.1 213.9,15.47 ; H18.1 215.31,16.88 ; H18.1 214.26,16.52 ; H18.1 214.26,14.42 ; H18.1 216.72,15.47 ; H18.1 216.36,16.52 ; H18.1 215.31,14.06 ; 12.64,44.53 JUSB1.7 ; JUSB1.7 12.47,45.11 ; JUSB1.7 13.81,45.69 ; JUSB1.7 13.81,44.53 ; JUSB1.7 13.22,44.36 ; JUSB1.7 13.22,45.86 ; JUSB1.7 12.64,45.69 ; JUSB1.7 13.97,45.11 ; H16.1 190.76,23.12 ; H16.1 190.21,21.61 ; H16.1 186.64,23.12 ; H16.1 188.7,25.18 ; H16.1 188.7,21.06 ; H16.1 187.19,21.61 ; H16.1 190.21,24.63 ; H16.1 187.19,24.63 ; JUSB1.11 15.11,39.66 ; JUSB1.11 13.63,38.73 ; JUSB1.11 16.6,37.8 ; JUSB1.11 13.63,37.8 ; JUSB1.11 15.11,37.8 ; JUSB1.11 13.63,39.66 ; JUSB1.11 16.6,38.73 ; JUSB1.11 16.6,39.66 ; JUSB1.12 6.01,53.9 ; JUSB1.12 3.64,52.97 ; JUSB1.12 3.64,53.9 ; JUSB1.12 6.01,52.97 ; JUSB1.12 4.82,53.9 ; H15.1 165.36,53.85 ; H15.1 164.8,55.36 ; H15.1 163.3,55.91 ; H15.1 161.79,55.36 ; H15.1 161.79,52.34 ; H15.1 163.3,51.79 ; H15.1 164.8,52.34 ; H15.1 161.24,53.85 ; 9.65,69.07 H1.1 ; H1.1 12.11,70.12 ; H1.1 11.75,69.07 ; H1.1 11.75,71.17 ; H1.1 10.7,68.71 ; H1.1 9.65,71.17 ; H1.1 10.7,71.53 ; H1.1 9.29,70.12 ; 10.54,65.43 JMDP.21 ; JMDP.21 12.12,65.43 ; JMDP.21 13.69,66.18 ; JMDP.21 12.12,66.93 ; JMDP.21 10.54,66.18 ; JMDP.21 13.69,66.93 ; JMDP.21 13.69,65.43 ; JMDP.21 10.54,66.93 ; 2.5,22.7 SW3.3 ; SW3.3 1.97,22.85 ; SW3.3 1.97,23.9 ; SW3.3 3.03,22.85 ; SW3.3 3.17,23.38 ; H10.1 106.56,74.85 ; H10.1 106.01,73.34 ; H10.1 106.01,76.36 ; H10.1 104.5,76.91 ; H10.1 102.44,74.85 ; H10.1 104.5,72.79 ; H10.1 102.99,73.34 ; H10.1 102.99,76.36 ; 3.22,37.28 3.23,37.27 JUSB1.13 6.25,37.27 6.25,37.27 ; H12.1 111.59,14.36 ; H12.1 110.54,11.9 ; H12.1 111.95,13.31 ; H12.1 109.49,12.26 ; H12.1 111.59,12.26 ; H12.1 109.49,14.36 ; H12.1 109.13,13.31 ; H12.1 110.54,14.72 ; H7.1 54.8,13.31 ; H7.1 54.44,14.36 ; H7.1 52.34,12.26 ; H7.1 53.39,14.72 ; H7.1 52.34,14.36 ; H7.1 53.39,11.9 ; H7.1 54.44,12.26 ; H7.1 51.98,13.31 ; 14.14,42.19 JUSB1.4 ; JUSB1.4 14.72,42.36 ; JUSB1.4 15.47,41.61 ; JUSB1.4 13.98,41.61 ; JUSB1.4 15.31,42.19 ; JUSB1.4 14.72,40.86 ; JUSB1.4 15.31,41.03 ; JUSB1.4 14.14,41.03 ; 13.63,51.53 JUSB1.10 ; JUSB1.10 16.6,52.46 ; JUSB1.10 15.11,50.6 ; JUSB1.10 16.6,50.6 ; JUSB1.10 13.63,52.46 ; JUSB1.10 15.11,52.46 ; JUSB1.10 13.63,50.6 ; JUSB1.10 16.6,51.53 ; 9.29,17.12 H4.1 ; H4.1 9.65,18.17 ; H4.1 9.65,16.07 ; H4.1 11.75,16.07 ; H4.1 10.7,15.71 ; H4.1 11.75,18.17 ; H4.1 10.7,18.53 ; H4.1 12.11,17.12 ; JMDP.23 3.42,54.35 ; JMDP.23 3.42,55.1 ; JMDP.23 2.31,54.35 ; 203.5,48.06 H17.1 ; H17.1 201.99,51.63 ; H17.1 205.01,48.61 ; H17.1 203.5,52.18 ; H17.1 201.99,48.61 ; H17.1 205.01,51.63 ; H17.1 205.56,50.12 ; H17.1 201.44,50.12 ; 14.24,60.9 JMDP.14 ; JMDP.14 14.24,62.05 ; JMDP.14 13.76,61.47 ; JMDP.14 13.76,62.05 ; JMDP.14 13.76,60.9 ; 81.05,79.8 H9.1 ; H9.1 81.41,78.75 ; H9.1 82.46,78.39 ; H9.1 81.41,80.85 ; H9.1 83.51,80.85 ; H9.1 83.51,78.75 ; H9.1 82.46,81.21 ; H9.1 83.87,79.8 ; JMDP.22 13.69,54.98 ; JMDP.22 10.54,55.73 ; JMDP.22 10.54,54.23 ; JMDP.22 13.69,55.73 ; JMDP.22 13.69,54.23 ; JMDP.22 10.54,54.98 ; JMDP.22 12.12,55.73 ; JMDP.22 12.12,54.23 ; 14.24,59.1 JMDP.8 ; JMDP.8 13.76,60.25 ; JMDP.8 13.76,59.1 ; JMDP.8 13.76,59.67 ; JMDP.8 14.24,60.25 ; H11.1 104.5,55.91 ; H11.1 102.99,55.36 ; H11.1 106.56,53.85 ; H11.1 102.44,53.85 ; H11.1 102.99,52.34 ; H11.1 106.01,52.34 ; H11.1 106.01,55.36 ; H11.1 104.5,51.79 ; JMDP.24 3.42,66.59 ; JMDP.24 2.31,66.59 ; JMDP.24 1.21,66.59 ; JMDP.24 1.21,65.84 ; JMDP.24 3.42,65.84 ; H13.1 130.64,14.33 ; H13.1 129.59,14.69 ; H13.1 128.18,13.28 ; H13.1 128.54,12.23 ; H13.1 130.64,12.23 ; H13.1 131,13.28 ; H13.1 129.59,11.87 ; H13.1 128.54,14.33 ; 10.84,61.47 JMDP.13 10.84,62.12 ; 10.84,61.47 10.84,60.8 ; 10.84,61.47 10.41,61.03 ; 10.84,59 10.84,59.65 ; 10.84,59.65 10.39,59.2 ; 10.84,59.65 JMDP.7 10.84,60.34
  GND3 w0.102: 184.93,37.75 184.93,38.1 185.06,38.22
  GND3 w0.203: 14.24,60.9 JMDP.14 ; JMDP.14 13.76,61.47 ; JMDP.14 13.76,62.05 ; JMDP.14 13.76,60.9 ; JMDP.14 14.24,62.05 ; H17.1 203.5,52.18 ; H17.1 205.56,50.12 ; H17.1 201.44,50.12 ; H17.1 205.01,51.63 ; H17.1 205.01,48.61 ; H17.1 201.99,51.63 ; H17.1 201.99,48.61 ; H17.1 203.5,48.06 ; 9.65,16.07 H4.1 ; H4.1 9.65,18.17 ; H4.1 10.7,15.71 ; H4.1 9.29,17.12 ; H4.1 11.75,18.17 ; H4.1 10.7,18.53 ; H4.1 12.11,17.12 ; H4.1 11.75,16.07 ; 10.84,61.38 10.42,60.96 ; 10.84,61.38 10.84,60.79 ; 10.84,61.38 JMDP.13 10.84,62.11 ; H14.1 164.8,76.36 ; H14.1 164.8,73.34 ; H14.1 165.36,74.85 ; H14.1 163.3,76.91 ; H14.1 161.79,76.36 ; H14.1 163.3,72.79 ; H14.1 161.24,74.85 ; H14.1 161.79,73.34 ; 1.97,18.8 SW3.4 ; SW3.4 1.97,19.85 ; SW3.4 3.03,18.8 ; SW3.4 2.5,20 ; SW3.4 3.17,19.33 ; SW3.4 2.5,18.65 ; SW3.4 3.03,19.85 ; 10.84,60.36 JMDP.7 10.84,59.6 ; JMDP.23 3.42,54.35 ; JMDP.23 2.31,54.35 ; JMDP.23 3.42,55.1 ; 161.79,52.34 H15.1 ; H15.1 164.8,55.36 ; H15.1 163.3,51.79 ; H15.1 163.3,55.91 ; H15.1 161.24,53.85 ; H15.1 165.36,53.85 ; H15.1 164.8,52.34 ; H15.1 161.79,55.36 ; JUSB1.7 13.97,45.11 ; JUSB1.7 13.81,44.53 ; JUSB1.7 12.47,45.11 ; JUSB1.7 13.22,44.36 ; JUSB1.7 13.81,45.69 ; JUSB1.7 12.64,45.69 ; JUSB1.7 12.64,44.53 ; JUSB1.7 13.22,45.86 ; 102.99,73.34 H10.1 ; H10.1 104.5,76.91 ; H10.1 106.01,76.36 ; H10.1 106.56,74.85 ; H10.1 102.99,76.36 ; H10.1 106.01,73.34 ; H10.1 104.5,72.79 ; H10.1 102.44,74.85 ; 183.32,78.39 H19.1 ; H19.1 182.27,78.75 ; H19.1 184.37,80.85 ; H19.1 183.32,81.21 ; H19.1 182.27,80.85 ; H19.1 184.37,78.75 ; H19.1 181.91,79.8 ; H19.1 184.73,79.8 ; 14.72,40.86 JUSB1.4 ; JUSB1.4 14.14,42.19 ; JUSB1.4 14.14,41.03 ; JUSB1.4 15.47,41.61 ; JUSB1.4 13.98,41.61 ; JUSB1.4 14.72,42.36 ; JUSB1.4 15.31,42.19 ; JUSB1.4 15.31,41.03 ; 14.24,59.1 JMDP.8 ; JMDP.8 13.76,59.1 ; JMDP.8 13.76,60.25 ; JMDP.8 14.24,60.25 ; JMDP.8 13.76,59.67 ; 13.63,51.53 JUSB1.10 ; JUSB1.10 13.63,52.46 ; JUSB1.10 15.11,50.6 ; JUSB1.10 16.6,52.46 ; JUSB1.10 16.6,51.53 ; JUSB1.10 15.11,52.46 ; JUSB1.10 13.63,50.6 ; JUSB1.10 16.6,50.6 ; JMDP.22 13.69,54.23 ; JMDP.22 12.12,55.73 ; JMDP.22 12.12,54.23 ; JMDP.22 10.54,54.23 ; JMDP.22 13.69,55.73 ; JMDP.22 10.54,55.73 ; JMDP.22 10.54,54.98 ; JMDP.22 13.69,54.98 ; 39.49,70.79 H6.1 ; H6.1 41,70.24 ; H6.1 43.06,72.3 ; H6.1 42.51,70.79 ; H6.1 38.94,72.3 ; H6.1 42.51,73.81 ; H6.1 41,74.36 ; H6.1 39.49,73.81 ; 1.97,22.85 SW3.3 ; SW3.3 1.97,23.9 ; SW3.3 3.17,23.38 ; SW3.3 3.03,22.85 ; SW3.3 2.5,22.7 ; 10.84,59.6 10.43,59.19 ; 10.84,59.6 10.84,59.01 ; 102.99,52.34 H11.1 ; H11.1 102.44,53.85 ; H11.1 106.01,55.36 ; H11.1 106.01,52.34 ; H11.1 106.56,53.85 ; H11.1 104.5,55.91 ; H11.1 102.99,55.36 ; H11.1 104.5,51.79 ; H12.1 110.54,14.72 ; H12.1 111.59,14.36 ; H12.1 111.95,13.31 ; H12.1 109.13,13.31 ; H12.1 110.54,11.9 ; H12.1 109.49,12.26 ; H12.1 111.59,12.26 ; H12.1 109.49,14.36 ; 81.05,79.8 H9.1 ; H9.1 82.46,81.21 ; H9.1 83.51,78.75 ; H9.1 81.41,78.75 ; H9.1 83.51,80.85 ; H9.1 83.87,79.8 ; H9.1 82.46,78.39 ; H9.1 81.41,80.85 ; JUSB1.11 15.11,39.66 ; JUSB1.11 13.63,37.8 ; JUSB1.11 16.6,38.73 ; JUSB1.11 16.6,37.8 ; JUSB1.11 16.6,39.66 ; JUSB1.11 13.63,39.66 ; JUSB1.11 15.11,37.8 ; JUSB1.11 13.63,38.73 ; 52.34,12.26 H7.1 ; H7.1 54.44,12.26 ; H7.1 54.8,13.31 ; H7.1 54.44,14.36 ; H7.1 52.34,14.36 ; H7.1 53.39,14.72 ; H7.1 51.98,13.31 ; H7.1 53.39,11.9 ; 12.12,65.43 JMDP.21 ; JMDP.21 10.54,66.93 ; JMDP.21 12.12,66.93 ; JMDP.21 10.54,66.18 ; JMDP.21 13.69,66.18 ; JMDP.21 13.69,66.93 ; JMDP.21 10.54,65.43 ; JMDP.21 13.69,65.43 ; JUSB1.12 6.01,52.97 ; JUSB1.12 3.64,53.9 ; JUSB1.12 6.01,53.9 ; JUSB1.12 3.64,52.97 ; JUSB1.12 4.82,53.9 ; 214.26,16.52 H18.1 ; H18.1 216.36,14.42 ; H18.1 213.9,15.47 ; H18.1 216.36,16.52 ; H18.1 215.31,14.06 ; H18.1 216.72,15.47 ; H18.1 215.31,16.88 ; H18.1 214.26,14.42 ; JMDP.24 3.42,66.59 ; JMDP.24 1.21,65.84 ; JMDP.24 2.31,66.59 ; JMDP.24 3.42,65.84 ; JMDP.24 1.21,66.59 ; 3.31,37.27 JUSB1.13 6.27,37.27 ; H1.1 11.75,71.17 ; H1.1 11.75,69.07 ; H1.1 9.29,70.12 ; H1.1 9.65,69.07 ; H1.1 10.7,71.53 ; H1.1 9.65,71.17 ; H1.1 10.7,68.71 ; H1.1 12.11,70.12 ; 187.19,24.63 H16.1 ; H16.1 186.64,23.12 ; H16.1 190.76,23.12 ; H16.1 190.21,21.61 ; H16.1 188.7,21.06 ; H16.1 188.7,25.18 ; H16.1 190.21,24.63 ; H16.1 187.19,21.61 ; H13.1 130.64,14.33 ; H13.1 129.59,11.87 ; H13.1 128.54,14.33 ; H13.1 131,13.28 ; H13.1 129.59,14.69 ; H13.1 128.18,13.28 ; H13.1 130.64,12.23 ; H13.1 128.54,12.23 ; JMDP.1 11.32,57.3 ; JMDP.1 10.84,58.45 ; JMDP.1 10.84,57.3 ; JMDP.19 11.32,63.85 ; JMDP.19 10.84,63.85 ; JMDP.19 10.84,62.7
  GND3 w0.254: 55.78,38.98 55.78,38.62 ; 55.78,36.36 55.78,36.72
  BOTTOM w0.076: UCPU1.B26 136.33,71.65 136.44,71.76 136.44,72.67 136.81,73.03
  BOTTOM w0.089: 143.93,48.34 143.93,49.05 143.45,49.53 143.45,50.17 143.34,50.28 v1(143.34,50.61)
  BOTTOM w0.102: v5(144.97,44.47) 145.51,45.01 145.51,46.76 143.93,48.34 ; v5(83.33,72.47) v6(82.12,72.47) ; v6(178.16,65.88) 177.68,65.41 v5(177,65.41) ; v5(185.69,40.21) v6(185.69,39) ; v1(135.28,72.62) 135.28,72.92 135.74,73.38 135.74,74.43 136.8,75.48 v5(136.8,75.57) 136.8,75.59 137.65,76.44 137.65,76.7 v5(138.04,77.09) 138.46,77.52 v6(139.58,77.52) 139.79,77.3 v5(139.79,77.1) 139.79,76.26 138.44,74.9 v5(138.1,74.9) 137.84,74.9 137.47,74.53 137.25,74.53 136.81,74.09 136.81,73.03 ; v1(129.02,78.46) v6(128.33,78.46) ; v1(203.17,20.79) v6(202.32,20.79) ; v1(96.94,77.15) v6(96.94,76.51)
  BOTTOM w0.127: UCPU1.AV36 130.01,51.1 130.37,51.47 130.37,52 ; UCPU1.AV46 124.07,51.31 124.07,52.04 124.06,52.06 ; 125.65,51.96 125.65,51.47 125.28,51.1 UCPU1.AV43 ; UCPU1.AV41 126.86,51.1 127.22,51.47 127.22,51.92 v1(127.28,51.98) ; UCPU1.AV49 122.13,51.1 122.5,51.47 122.5,51.96 ; UCPU1.AV39 128.43,51.11 128.8,51.48 128.8,52.02 ; v6(143.13,78.22) v1(143.58,77.76) ; v7(51.29,25.02) v6(51.29,23.81) ; v6(150.42,77.56) RH300.1
  BOTTOM w0.152: UCPU1.AY53 119.27,49.03 v1(119.05,48.81) ; UCPU1.AL39 128.42,55.69 128.59,55.51 128.59,55.22 128.77,55.04 129.48,55.04 v1(129.56,55.12) ; UCPU1.AY24 137.29,49.11 v1(137.21,49.04)
  BOTTOM w0.178: UCPU1.AT40 128.09,51.99 128.76,51.99 128.83,52.06 v5(129.59,52.06) 129.66,52 131.1,52 UCPU1.AT35 ; UCPU1.AY18 141.07,49.12 v1(141,49.05) ; v1(112.43,59.24) 112.57,59.1 UCPU1.AD63 ; v1(120.84,49.17) 120.62,49.39 UCPU1.AY51 UCPU1.AW51 UCPU1.AV51 ; UCPU1.P63 112.43,64.35 v1(112.3,64.21) ; v1(112.41,61.29) 112.47,61.35 UCPU1.Y63 ; UCPU1.AT42 126.34,51.96 124.97,51.96 UCPU1.AT43 124.87,52.06 123.3,52.06 v5(123.29,52.06) 123.19,51.96 121.76,51.96 v5(121.69,52.03) ; UCPU1.AN63 113.3,53.89 112.13,53.89 v1(111.93,53.69) ; v1(116.82,49.04) 116.84,49.06 UCPU1.AY57 ; UCPU1.AY16 142.39,49.95 142.39,49.89 142.42,49.87 142.42,49.06 v1(142.39,49.03) ; v1(135.74,48.81) 135.93,49.01 UCPU1.AY26 ; 115.58,61.31 115.58,61.42 v1(115.28,61.72) ; UCPU1.AY30 133.5,49.12 v1(133.43,49.05) ; v1(112.27,57.59) 112.35,57.67 UCPU1.AG63 UCPU1.AG62 UCPU1.AG61 ; v1(117.22,73.5) 117.22,73.29 117.52,72.99 UCPU1.A56 ; UCPU1.AY22 138.64,49.13 v1(138.74,49.03) ; UCPU1.AJ63 112.45,56.32 v1(112.3,56.17)
  BOTTOM w0.203: v1(115.52,49.09) 115.52,49.65 UCPU1.AY59 ; v7(77.82,61.61) 77.91,61.7 PU700.19 ; UCPU1.P62 UCPU1.P63 ; v1(125.19,74.06) 125.25,73.99 125.25,72.84 124.99,72.57 124.99,72.01 UCPU1.A44 ; v1(152.07,66.88) 152.07,66.87 151.76,66.55 UCPU1.K1 ; v1(149.32,58.76) 149.32,58.67 UCPU1.AE5 ; UCPU1.AG1 v1(152.07,57.56) ; 116.23,69.15 116.23,69.54 115.7,70.06 UCPU1.D59 ; v1(113.98,63.22) 114.28,62.92 UCPU1.U61 ; UCPU1.AU1 151.6,51.59 152.18,51.01 152.18,50.9 152.17,50.89 v1(152.17,50.87) ; PU700.29 76.68,60.9 PU700.33 ; UCPU1.AV16 UCPU1.AW16 ; v1(112.4,67.42) 112.47,67.34 UCPU1.J63 ; PU701.3 92.4,60.25 v7(92.55,60.4) ; v1(113.98,60.22) 114.28,59.93 UCPU1.AC61 ; UCPU1.AR49 121.85,52.18 v5(121.69,52.03) ; v1(113.98,69.22) 114.28,68.92 UCPU1.F61
  BOTTOM w0.254: 119.97,52.11 119.91,52.17 119.91,52.64 UCPU1.AR52 119.97,52.81 119.97,53.36 UCPU1.AP52 119.97,53.41 v1(119.53,53.85) ; 119.97,52.11 119.45,52.11 v5(119.27,51.92) 119.21,51.98 118.12,51.98 UCPU1.AU55 ; 119.97,52.11 120.15,51.92 v5(120.62,51.92) ; v1(150.61,58.74) 150.61,58.79 UCPU1.AD3 ; UCPU1.AJ41 126.92,56.66 v1(127.14,56.44) ; UCPU1.AH36 130.12,57.22 v1(130.53,57.22) UCPU1.AJ35 ; 133.21,52.35 133.21,52.95 UCPU1.AR31 ; 133.21,52.35 132.9,52.35 132.49,51.95 UCPU1.AU33 ; 133.21,52.35 133.21,52.22 v5(133.5,51.92) 133.52,51.94 133.94,51.94 133.99,52 134.65,52 UCPU1.AU28 ; UCPU1.AM31 v1(133.85,55.04) 134.18,55.36 UCPU1.AL29 ; UCPU1.AM31 UCPU1.AL31 133.34,55.83 v1(133.85,56.34) ; UCPU1.AM31 UCPU1.AN31 133.11,54.39 UCPU1.AN32 ; UCPU1.AN48 123.04,54.06 v1(123.31,54.33) 123.59,54.06 UCPU1.AN46 123.95,53.91 124.58,53.91 v5(124.73,54.06) UCPU1.AN43 125.89,54.06 v1(126.17,53.79) 126.44,54.06 UCPU1.AN42 ; UCPU1.AN48 UCPU1.AP48 122.68,53.41 v1(122.36,53.08) 122.03,52.76 UCPU1.AR49 ; UCPU1.AN48 122.63,53.94 121.97,53.94 v5(121.85,54.06) 121.69,53.9 121,53.9 v5(120.84,54.06) 120.72,53.94 120.14,53.94 UCPU1.AN52 119.81,53.85 v1(119.53,53.85) ; v5(144.73,57.99) 144.73,57.89 v5(145.14,57.49) 145.55,57.89 v5(145.55,57.99) 145.87,58.32 v5(146.13,58.32) ; v1(127.9,55.04) 128.06,54.88 UCPU1.AN39 ; v1(127.9,55.04) 128.06,55.2 UCPU1.AL39 128.06,55.82 v1(128.58,56.34) ; v1(127.9,55.04) 127.58,55.36 UCPU1.AL40 ; UCPU1.AJ47 122.96,56.43 v1(123.31,56.43) 123.38,56.5 UCPU1.AH46 ; UCPU1.D42 UCPU1.F42 126.3,68.49 v1(126.39,68.4) ; v1(114.09,55.07) 114.13,55.11 UCPU1.AL61 UCPU1.AL60 ; v1(141.13,61.23) 140.43,61.93 UCPU1.W20 UCPU1.U20 ; UCPU1.AU33 131.99,51.95 v1(131.44,52.5) ; UCPU1.AU33 132.2,51.92 v5(132.2,51.27) ; UCPU1.AU16 v5(142.38,53.09) UCPU1.AP17 v5(142.38,54.39) UCPU1.AM17 UCPU1.AL17 ; UCPU1.AU16 142,51.92 141.96,51.97 141.11,51.97 v5(141.07,51.92) 140.75,51.92 140.69,51.98 139.91,51.98 UCPU1.AU20 ; UCPU1.AU16 142.76,51.92 142.9,52.07 v1(142.9,52.21) 143.27,52.57 UCPU1.AR15 143.79,52.25 UCPU1.AT13 144.4,52.25 v1(145.01,52.86) 145.29,52.57 UCPU1.AR11 ; UCPU1.AU16 UCPU1.AV16 ; v5(121.69,52.03) 120.73,52.03 v5(120.62,51.92) ; v5(132.2,51.27) 131.91,51.27 UCPU1.AV34 131.47,50.95 v1(131.17,50.65) 131.11,50.65 UCPU1.AW35 ; v5(132.2,51.27) 132.15,51.22 v5(132.15,50.62) v5(132.15,49.97) ; UCPU1.AR39 UCPU1.AP39 UCPU1.AN39 ; UCPU1.AR39 128.06,52.1 UCPU1.AT40 127.94,51.98 v1(127.28,51.98) 126.52,51.98 UCPU1.AT42 ; UCPU1.AR39 v1(128.58,53.08) 128.9,53.41 UCPU1.AP38 129.05,53.41 v1(129.53,53.89) 129.7,54.06 UCPU1.AN36 130.16,54.06 v1(130.48,53.74) 130.81,54.06 UCPU1.AN35 ; UCPU1.A56 117.45,71.89 117.45,71.37 UCPU1.B56 ; UCPU1.AL60 115.29,55.06 115.29,53.94 v5(115.25,53.89) 115.29,53.85 115.29,52.9 v1(115.17,52.77) ; UCPU1.AL60 115.29,55.15 115.29,56.03 115.25,56.07 UCPU1.AJ60 115.49,56.32 v1(115.68,56.52) 115.83,56.66 UCPU1.AJ58 116.45,56.44 v1(116.74,56.44) ; v5(115.6,51.92) 115.66,51.98 116.78,51.98 v5(116.84,51.92) 116.89,51.97 118.01,51.97 UCPU1.AU55 ; v5(115.6,51.92) v5(115.6,51.27) v5(115.6,50.62) 115.28,50.3 v5(115.04,50.3) ; v5(115.6,51.92) 115.29,52.23 115.29,52.64 v1(115.17,52.77) ; v1(135.28,72.62) 135.28,72.19 135.07,71.98 UCPU1.A28 UCPU1.B28 ; v1(138.51,55.04) 138.4,55.04 UCPU1.AL23 ; v1(138.51,55.04) 138.18,54.71 UCPU1.AM23 ; v1(138.51,55.04) 138.83,55.36 UCPU1.AL22 ; JEDP.27 193.82,37.37 194.02,37.17 v1(194.1,37.17) ; 142.31,56.26 142.31,56.32 142.47,56.49 142.47,56.57 UCPU1.AH16 142.98,56.52 v1(142.98,56.22) 143.05,56.15 UCPU1.AJ14 UCPU1.AJ13 144.33,55.8 UCPU1.AL13 143.98,55.55 v1(142.94,55.55) 142.52,55.55 UCPU1.AL17 ; 142.31,56.26 141.89,56.68 UCPU1.AH17 141.82,56.8 v1(141.27,56.25) 141.08,56.45 ; 142.31,56.26 142.31,55.76 UCPU1.AL17 ; UCPU1.AN23 137.75,53.74 v1(137.66,53.74) ; UCPU1.AU55 UCPU1.AV55 118.06,50.8 v1(118.09,50.77) ; UCPU1.AW4 149.63,49.7 UCPU1.AY4 149.68,49.25 v1(149.83,49.1) ; UCPU1.AL51 120.78,55.36 v1(120.45,55.04) ; UCPU1.AV41 126.75,50.95 v1(126.45,50.65) 126.09,50.3 UCPU1.AW42 ; UCPU1.AR5 148.7,52.9 149.06,53.26 v1(149.15,53.26) ; v1(141,59.81) 141,59.81 UCPU1.AB20 ; UCPU1.V58 116.18,62.25 115.98,62.45 115.98,63.3 UCPU1.T58 116.22,63.56 116.19,63.56 115.58,64.17 UCPU1.P59 115.58,64.32 115.26,64.64 v1(115.26,64.73) ; v1(119.53,53.85) 119.09,53.41 UCPU1.AP54 118.93,53.41 v1(118.6,53.08) ; v1(119.53,53.85) 119.53,54.42 v1(119.54,54.44) ; UCPU1.B20 139.75,71.42 UCPU1.C20 140.57,71.08 v1(140.63,71.01) ; v1(118.82,68.38) 118.77,68.42 UCPU1.F54 UCPU1.D54 ; 137.75,55.69 UCPU1.AL23 ; 137.75,55.69 UCPU1.AK23 137.75,56.34 v1(137.66,56.34) ; 137.75,55.69 v1(137.66,55.69) ; UCPU1.AL23 137.99,55.36 v1(137.66,55.04) v1(137.66,53.74) ; UCPU1.AG61 UCPU1.AG60 115.61,57.67 v1(115.76,57.82) 115.76,57.89 UCPU1.AE58 ; v1(119.54,54.44) 119.75,54.44 UCPU1.AM52 ; v1(119.54,54.44) 119.54,55 v1(119.5,55.04) ; UCPU1.AP26 136.08,53.41 v1(135.76,53.08) ; UCPU1.B4 149.21,71.63 v1(149.18,71.67) ; UCPU1.AH44 124.68,56.61 v1(124.57,56.49) 124.2,56.49 UCPU1.AJ45 ; v1(137.66,56.34) 137.69,56.36 UCPU1.AH24 137.69,57.23 v1(137.95,57.5) 137.99,57.54 UCPU1.AG23 UCPU1.AJ23 138.71,56.72 v1(138.94,56.49) 139,56.55 UCPU1.AH22 139.09,57.04 139.53,57.04 UCPU1.AG21 140,56.8 v5(140.26,56.8) 140.62,56.45 141.08,56.45 ; v1(137.66,56.34) 137.36,56.34 UCPU1.AJ25 v1(137.03,57.22) ; UCPU1.AH53 119.4,56.91 v1(119.4,56.47) ; UCPU1.AV46 123.41,50.65 v1(123.3,50.65) 123.23,50.65 UCPU1.AW47 ; UCPU1.G22 139,68.66 139.41,69.08 v1(139.41,69.38) ; v1(194.47,40.63) 194.2,40.63 193.94,40.37 JEDP.33 ; v1(129.56,55.12) 129.8,55.36 UCPU1.AL36 ; v1(133.85,56.34) 133.78,56.4 UCPU1.AH30 ; v1(133.85,56.34) 134.04,56.34 134.37,56.66 UCPU1.AJ29 v1(134.43,57.22) 134.85,57.22 UCPU1.AH28 135.41,56.66 UCPU1.AJ27 ; UCPU1.AL46 124,55.36 v1(124.26,55.09) 124.53,55.36 UCPU1.AL45 ; UCPU1.J10 146.39,67.06 v1(146.64,67.31) ; UCPU1.B32 132.45,71.42 132.45,71.84 UCPU1.A32 ; v1(115.17,52.77) 115.04,52.64 UCPU1.AT61 114.55,52.59 UCPU1.AT62 ; UCPU1.AV51 v5(120.62,51.92) ; UCPU1.AW40 127.96,50.65 v1(128.02,50.65) 128.13,50.65 UCPU1.AV39 ; UCPU1.D8 147.27,70.49 146.6,69.82 v1(146.6,68.67) ; UCPU1.AV8 146.74,50.95 146.51,51.17 v1(146.36,51.17) ; UCPU1.V23 138.59,62.41 UCPU1.W22 139.5,62.51 v1(139.5,62.75) 139.43,62.82 UCPU1.U22 v5(139,63.63) UCPU1.P22 139.06,64.45 v1(139.39,64.78) ; v1(150.59,61.72) 150.58,61.72 150.3,62 UCPU1.V3 ; UCPU1.A44 124.88,71.79 124.88,71.46 UCPU1.B44 ; UCPU1.B26 136.09,71.3 UCPU1.C27 ; UCPU1.G18 141.63,68.36 v1(141.88,68.11) 142.28,67.71 UCPU1.H17 ; UCPU1.AL33 131.7,55.36 v1(131.44,55.1) ; UCPU1.L20 140.43,66.07 v1(141.27,65.23) 141.38,65.35 UCPU1.L18 ; 115.58,61.31 UCPU1.Y59 115.58,61.22 115.81,60.99 116.18,60.99 UCPU1.AA58 ; v1(150.55,67.68) 150.49,67.74 150.49,67.91 UCPU1.G3 ; UCPU1.D5 148.93,70.4 149.22,70.11 v1(149.26,70.11) ; v1(119.4,56.47) 119.4,55.95 v1(119.5,55.85) ; v1(119.4,56.47) 119.93,56.47 UCPU1.AJ52 ; v5(141.88,70.11) 141.96,70.11 142.34,69.73 UCPU1.E17 ; UCPU1.AP20 140.74,53.41 v1(140.41,53.08) ; UCPU1.AH49 122.19,56.88 v1(122.19,56.43) 121.66,56.43 UCPU1.AJ50 ; UCPU1.AB7 147.67,60.28 v1(148.05,60.66) ; 141.08,56.45 UCPU1.AH19 ; v1(137.39,70.81) 137.91,70.81 UCPU1.D23 138.23,70.48 v1(138.64,70.07) 138.85,69.85 UCPU1.D21 ; v1(141.32,72.91) 141.32,72.6 UCPU1.A18 141.1,72.18 UCPU1.C18 141.51,70.67 UCPU1.D18 ; UCPU1.AP29 134.19,53.41 v1(133.86,53.08) UCPU1.AR31 ; UCPU1.AL54 119.32,55.04 v1(119.5,55.04) ; UCPU1.AL54 118.93,55.36 v1(118.6,55.04) ; UCPU1.AL54 119.01,55.36 v1(119.5,55.85) ; UCPU1.AH51 120.65,56.86 v1(120.65,56.47) ; UCPU1.AL52 119.83,55.36 v1(119.5,55.04) ; v1(131.34,56.4) 131.18,56.56 UCPU1.AH34 ; v1(137.66,52.43) 138.17,51.92 v5(138.64,51.92) 138.7,51.98 139.8,51.98 UCPU1.AU20 ; v1(137.66,52.43) 137.29,52.06 UCPU1.AU24 ; v1(137.66,52.43) 137.99,52.76 UCPU1.AR23 138.4,53.08 v1(138.51,53.08) ; v5(116.04,67.94) 116.31,67.94 UCPU1.H57 116.54,68.18 116.44,68.28 116.44,68.71 116.23,68.93 UCPU1.F58 116.23,69.15 ; UCPU1.J59 115.58,67.34 v1(115.2,67.72) ; UCPU1.L17 142.39,66.13 v1(142.75,65.77) 143.11,66.13 UCPU1.L15 ; PR302.1 55.31,57.71 PR304.1 ; v1(122.32,72.83) 122.32,72.17 UCPU1.A48 122.46,71.87 122.46,71.38 UCPU1.B48 ; v1(116.74,56.44) 117.3,56.44 UCPU1.AJ56 ; v1(116.74,56.44) 116.74,56.85 UCPU1.AH57 ; v1(116.7,53.08) 117.02,53.41 UCPU1.AP57 ; v1(119.5,55.85) 119.66,56.01 UCPU1.AK52 ; UCPU1.AH55 118.18,56.63 v1(118.33,56.48) 118.64,56.48 UCPU1.AJ54 ; UCPU1.AN7 147.92,54.2 148.13,53.98 148.26,53.98 148.27,53.98 v1(148.28,53.99) ; v1(148.55,68.58) 148.78,68.58 UCPU1.G5 ; UCPU1.AL20 140.8,55.36 v1(140.42,54.98) ; v1(131.44,52.5) 131.7,52.76 UCPU1.AR33 ; v1(131.44,52.5) 131.17,52.23 UCPU1.AT35 ; UCPU1.N21 139.46,64.85 v1(139.39,64.78) ; UCPU1.AY11 145.23,48.87 145.27,48.83 v1(145.28,48.82) ; UCPU1.AW16 142.42,50.59 UCPU1.AY16 ; PC708.2 73.18,59.07 v7(73.44,59.32) ; v1(128.58,56.34) 128.26,56.34 UCPU1.AJ39 v1(127.93,57.22) 127.51,57.22 UCPU1.AH40 ; v1(128.58,56.34) 128.58,56.34 UCPU1.AH38 ; UCPU1.B24 UCPU1.A24 137.58,71.95 137.62,71.95 v5(137.87,72.21) ; UCPU1.G8 147.1,68.42 147.36,68.68 v1(147.63,68.68) 147.73,68.68 UCPU1.G6 ; v1(139.39,64.78) 139,65.17 UCPU1.M22 ; DI1.3 DI1.8 20.27,47.24 v1(20.73,47.69) ; JEDP.39 193.73,43.37 v1(194.05,43.69) ; UCPU1.A14 143.57,72.49 v5(143.32,72.74) ; UCPU1.AL57 116.96,55.36 v1(116.7,55.1) ; UCPU1.AM1 151.62,54.55 152.04,54.55 v1(152.07,54.59) ; UCPU1.D30 UCPU1.F30 v1(133.82,68.4) ; v1(144.7,68.02) 144.56,68.02 UCPU1.H13 144.72,67.23 UCPU1.K12 144.69,66.58 UCPU1.L13 144.24,65.38 143.98,65.13 v1(143.98,65.12) ; UCPU1.AW50 121.66,50.65 v1(121.72,50.65) 121.83,50.65 UCPU1.AV49 ; UCPU1.AV14 143.68,50.95 v1(143.34,50.61) ; UCPU1.AU28 134.99,51.92 135.08,52.01 135.48,52.01 135.56,51.92 v5(135.93,51.92) 135.99,51.98 137.23,51.98 UCPU1.AU24 ; UCPU1.AU28 UCPU1.AV28 134.72,50.8 v1(134.75,50.77) ; 129.11,73.86 129.25,73.86 129.47,73.65 129.73,73.65 130,73.38 130,72.01 UCPU1.A36 130.04,71.95 129.91,71.83 129.91,71.43 130.04,71.3 UCPU1.B36 ; v1(137.66,53.74) 137.99,53.41 UCPU1.AP23 138.18,53.41 v1(138.51,53.08) ; UCPU1.AU20 UCPU1.AV20 139.85,50.75 v1(139.89,50.71) ; v1(139.41,66.59) 139.12,66.88 UCPU1.J22 ; v1(138.51,53.08) 138.83,53.41 UCPU1.AP22 ; v1(123.82,68.44) 123.79,68.47 UCPU1.F46 UCPU1.D46 ; UCPU1.F20 140.43,69.02 140.05,69.4 v1(139.97,69.4) ; UCPU1.AV43 124.98,50.65 v1(124.87,50.65) 124.81,50.65 UCPU1.AW44 ; v1(194.12,35.47) 193.72,35.87 JEDP.24 ; JEDP.36 193.83,41.87 v1(194.04,42.07) ; v1(205.2,61.29) PC500.2 ; UCPU1.AT43 124.87,52.09 v1(125.22,52.43) 125.54,52.76 UCPU1.AR43 ; UCPU1.AN32 133.11,53.74 UCPU1.AP31 UCPU1.AR31 ; UCPU1.AN32 132.7,54.06 v1(132.33,53.68) ; UCPU1.AU24 v5(137.29,51.27) UCPU1.AW24 UCPU1.AY24 ; UCPU1.D2 150.95,70.29 v1(150.67,70.58) ; v1(146.42,54.96) 145.95,55.43 UCPU1.AL10 ; v1(136.33,68.38) 136.33,68.39 UCPU1.F26 UCPU1.D26 ; UCPU1.B52 UCPU1.A52 119.96,72.02 119.96,72.66 v1(119.78,72.84) ; v5(146.13,62.13) 146.57,62.57 UCPU1.U9 ; v5(145,72.85) 145,72.52 UCPU1.A11 145.36,72.16 145.36,71.32 145.25,71.22 UCPU1.C11 ; v1(139.48,60.24) 139.34,60.38 UCPU1.AB22 ; UCPU1.R10 145.66,64.03 v1(145.52,64.17) ; UCPU1.D12 145.1,70.49 v5(145.62,69.97) 145.31,69.66 UCPU1.E11 ; JEDP.30 193.9,38.87 v1(194.06,39.04) ; UCPU1.C14 143.67,70.9 UCPU1.D14 144.08,70.28 v5(143.82,70.02) ; v1(121.31,68.38) 121.28,68.41 UCPU1.F50 UCPU1.D50 ; UCPU1.D57 UCPU1.C57 ; JIO1.5 209.5,16.36 209.07,16.79 v1(208.86,16.79) ; v1(128.8,68.4) 128.81,68.4 UCPU1.F38 UCPU1.D38 ; UCPU1.AN39 127.81,54.39 127.48,54.06 UCPU1.AN40 ; UCPU1.D62 113.57,70.3 UCPU1.D63 112.75,70.3 110.72,72.34 v1(110.72,72.53) ; UCPU1.B60 114.98,71.58 114.98,71.56 115.1,71.44 115.1,71 115.7,70.4 UCPU1.D59 ; UCPU1.AT63 112.71,52.43 112.1,51.82 v1(111.83,51.82) ; v1(127.22,72.86) 127.55,72.53 v5(127.55,72.34) UCPU1.A40 UCPU1.B40 ; v1(142.52,59.93) 141.48,58.89 v5(141.48,57.99) v5(142.3,57.99) v5(143.11,57.99) ; v1(132.37,56.34) 132.37,56.87 UCPU1.AH32 ; UCPU1.AL26 136.08,55.36 v1(135.73,55.01) ; v1(205.2,62.18) PR507.2 ; UCPU1.AJ43 125.57,56.43 v1(126.1,56.43) 126.1,56.87 UCPU1.AH42 ; UCPU1.AV36 129.89,50.95 v1(129.6,50.65) 129.24,50.3 UCPU1.AW37 ; v1(131.31,68.43) UCPU1.F34 UCPU1.D34 ; UCPU1.L58 115.91,66.15 v5(115.78,66.27)
  BOTTOM w0.305: JKB1.15 40.42,19.74 v1(40.65,19.52) 40.92,19.79 JKB1.14 ; JIO1.21 204.7,15.08 v1(205.03,14.75) 205.3,15.02 JIO1.19 ; JIO1.15 206.5,15.02 v1(206.23,14.75) 205.9,15.08 JIO1.17 ; JIO1.11 207.7,15.02 v1(207.43,14.75) 207.1,15.08 JIO1.13 ; JIO1.6 209.2,18.98 209.64,19.43 209.64,20.06 v1(209.61,20.1) ; v1(36,47.47) 36,46.32 JNGFF1.18 ; v1(201.43,14.75) 201.1,15.08 JIO1.33 ; JKB1.13 41.42,18.91 40.85,18.33 v1(40.85,17.92) ; v1(85.42,20.07) 85.33,20.16 JNFC1.7 ; JIO1.23 204.1,15.02 v1(203.83,14.75) 203.5,15.08 JIO1.25 ; v1(81.83,20.08) 81.83,20.9 JNFC1.14 ; JIO1.7 208.9,16.74 v1(208.86,16.79) ; v1(201.4,16.47) 201.4,16.46 201.7,16.16 JIO1.31 ; JIO1.29 202.3,15.08 v1(202.63,14.75) 202.9,15.02 JIO1.27 ; JNFC1.1 88.33,19.92 v1(88.24,19.83)
  BOTTOM w0.356: v1(108.28,45.63) 107.63,44.98 UC1.3
  BOTTOM w0.381: v1(89.46,79.83) 89.46,79.14 89.08,78.75 U663.8
  BOTTOM w0.406: v1(16.63,58.5) 17.74,58.5 MD16.3
  BOTTOM w0.508: v1(200.05,66.88) PC514.2 ; v5(156.72,49.64) CH83.2 ; PQ500.3 194.69,61.02 v1(194.16,60.49) 193.86,60.79 CE45.2 ; DI4.1 65.79,68.64 v1(65.45,68.3) ; v1(24.73,61.69) 24.77,61.65 C1302.2 ; 129.11,73.86 129.02,73.95 129.02,74.96 129.47,75.4 RH36.1 RH41.1 ; PC312.2 57.56,59.47 v7(57.56,58.88) ; JRTC1.3 v1(9.82,5.15) ; v1(60.34,76.25) 60.34,76.23 59.9,75.79 JCAM.7 ; v1(22.33,55.22) 22.04,55.51 RV10.2 ; DI3.1 61.49,68.64 v1(61.27,68.42) ; v1(196.65,23.06) 195.56,21.97 JEDP.41 ; v5(144.09,44.47) v5(144.97,44.47) ; JSPK1.6 23.34,12.51 v1(23.77,12.94) ; PR305.1 57.41,51.06 PR306.2 57.55,51.84 v7(57.5,51.89) ; JBATT1.10 56.58,22.21 v1(56.58,24.66) ; CH1241.2 114.14,76.6 v1(114.62,77.08) ; JRTC1.2 v1(13.07,10.91) ; v1(197.39,66.88) PC503.2 ; PC610.2 72.55,43.7 v7(72.1,43.26) 71.66,43.7 PR607.2 ; PR302.1 56.85,56.8 v7(56.93,56.72) ; C1301.2 29.47,60.8 v1(29.91,61.25) ; CH1236.2 95.41,75.21 v1(95.61,75.01) ; PC300.2 54.3,54.88 v7(54.22,54.95) ; PC713.2 v7(79.82,55.77) ; DI2.1 v1(18.13,39.73) ; R290.1 v1(53.05,57.56) ; CH6.2 v5(173.53,47.46) ; JCAM.6 58.6,73.09 v1(57.93,73.76) ; v1(151.54,75.46) 150.66,76.35 RH300.1 ; PC714.2 v7(77.75,55.01) ; v5(195.05,46.27) 198.87,46.27 v1(199.6,45.54) ; CE4.2 28.93,14.17 v1(29.04,14.07) ; v1(17.56,20.99) 17.8,21.23 DA2.1 17.8,23.82 17.56,24.07 CA69.2 ; v1(21.34,60.42) 21.8,60.42 22.47,61.1 CV15.2 ; JP100.6 v1(22.31,78.5) ; v1(22.41,20.11) 22.41,18.11 JSPK1.5 ; JRTC1.4 v1(7.02,10.98) ; CA49.2 33.48,34.63 33.72,34.88 CA48.2 34.19,34.32 v1(34.07,34.2) ; C1134.2 v1(80.1,22.77) ; CC240.2 101.25,46.62 101.06,46.81 v1(101.06,47.51) ; v1(21.84,69.9) 21.85,69.9 22.65,69.1 JP100.7 ; v1(138.27,74.08) 138.69,74.5 CH1231.2 ; U727.4 v5(190.87,56.77) ; v1(198.28,66.88) PC504.2 ; PC607.1 72.06,51.83 v1(72.25,52.02) ; C2983.2 v1(6.52,20.13) ; v1(204.75,67.83) PC513.2
  vias: v1(3.42,21.97) v1(3.85,0.8) v1(5.31,65.67) v1(5.45,67.36) v1(5.59,21.66) v1(5.59,21.09) v1(6.19,21.05) v1(8.18,3.01) v1(14.06,53.48) v1(14.33,72.61) v1(14.32,36.72) v1(16.38,67.85) v1(16.53,7.29) v1(16.55,79.95) v1(16.73,46.38) v1(16.79,51.83) v1(16.76,39.11) v1(16.93,67.88) v1(17.92,42.64) v1(18.93,19.14) v1(19.09,79.99) v1(19.08,70.52) v1(19.23,41.97) v1(19.6,19.14) v1(21.34,62.24) v1(21.29,58.58) v1(21.63,79.99) v1(23.54,45.12) v1(23.56,45.73) v1(23.59,20.04) v1(23.75,36.6) v1(24.15,45.71) v1(24.15,45.11) v1(24.19,79.99) v1(24.72,45.67) v1(24.72,45.09) v1(25.32,45.67) v1(25.32,45.09) v1(25.87,53.61) v1(26.07,50.02) v1(26.08,47.94) v1(26.28,12.7) v1(26.61,50.91) v1(26.76,79.97) v1(27.91,40.6) v1(29.3,79.97) v1(29.77,74.9) v1(29.85,68.26) v1(29.87,67.69) v1(29.87,29.54) v1(29.87,28.27) v1(29.87,27.07) v1(30.29,68.65) v1(30.36,68.03) v1(30.73,69.02) v1(30.8,68.4) v1(31.12,69.46) v1(31.26,68.84) v1(31.46,29.54) v1(31.46,28.27) v1(31.46,27) v1(31.66,69.28) v1(31.81,79.99) v1(32.54,52.91) v1(32.99,29.54) v1(32.99,28.27) v1(32.99,27) v1(33.9,12.7) v1(34.28,79.99) v1(36.82,79.99) v1(37.18,43.94) v1(38.27,42.92) v1(38.38,33.86) v1(38.7,54.88) v1(38.7,54.12) v1(38.7,53.35) v1(39.43,79.99) v1(40.54,32.98) v1(40.56,29.88) v1(41.5,32.02) v1(41.52,12.7) v1(41.95,79.99) v1(43.79,65.21) v1(44.49,79.99) v1(47.05,81.48) v1(49.14,12.7) v1(49.45,81.48) v1(49.65,55.98) v1(49.65,55.21) v1(49.65,54.45) v1(50.06,37.25) v1(51.18,62.45) v1(51.18,61.69) v1(51.18,60.93) v1(51.99,81.48) v1(54.67,81.48) v1(57.28,81.48) v1(57.5,26.37) v1(57.5,25.73) v1(57.5,25.1) v1(57.5,24.46) v1(58.13,26.37) v1(58.13,25.73) v1(58.13,25.1) v1(58.13,24.46) v1(58.77,26.37) v1(58.77,25.73) v1(58.77,25.1) v1(58.77,24.46) v1(58.77,23.83) v1(59.82,81.48) v1(60.41,12.7) v1(62.29,81.48) v1(62.26,40.8) v1(62.26,40.23) v1(62.26,39.67) v1(62.27,39.11) v1(64.91,81.5) v1(67.45,81.5) v1(68.03,12.7) v1(69.35,12.68) v1(69.91,81.48) v1(70.2,12.68) v1(70.96,12.68) v1(71.68,12.7) v1(72.2,13.99) v1(72.19,13.12) v1(72.46,81.48) v1(72.57,14.5) v1(73.32,14.5) v1(75,81.48) v1(75.54,14.5) v1(77.53,81.48) v1(79.13,39.78) v1(81.03,32.23) v1(82.38,34.88) v1(83.16,14.5) v1(86.43,81.48) v1(89.01,81.48) v1(90.78,14.5) v1(91.55,81.48) v1(91.66,54.62) v1(93.58,32.04) v1(94.05,81.48) v1(94.7,36.41) v1(94.71,35.27) v1(94.85,79.55) v1(96.59,81.48) v1(96.6,79.54) v1(98.04,12.71) v1(99.13,81.48) v1(101.67,81.48) v1(104.21,81.48) v1(105.88,12.71) v1(106.47,62.74) v1(106.75,81.48) v1(108.23,64.26) v1(108.23,62.7) v1(108.45,55.63) v1(108.56,66.91) v1(108.74,61.31) v1(109.29,81.48) v1(109.31,52.9) v1(109.38,32.96) v1(109.61,54.42) v1(109.8,68.52) v1(109.88,59.31) v1(110.13,50.23) v1(110.32,66.93) v1(110.39,52.52) v1(110.52,56.18) v1(110.69,69.98) v1(110.85,34.84) v1(111.11,68.39) v1(111.83,81.48) v1(111.89,65.48) v1(112.86,46.3) v1(113.27,44.75) v1(114.07,47.5) v1(114.37,81.48) v1(114.58,46.04) v1(114.97,75.38) v1(115.91,47.31) v1(115.91,44.52) v1(116.03,75.19) v1(116.44,12.7) v1(116.91,81.48) v1(117.23,75.48) v1(117.24,45.91) v1(117.68,70.85) v1(118.45,47.06) v1(119.09,67.12) v1(119.12,65.74) v1(119.12,65.13) v1(119.1,64.04) v1(119.12,63.4) v1(119.08,43.56) v1(119.45,81.48) v1(119.54,43.89) v1(120.21,70.84) v1(121.92,32.03) v1(121.99,81.48) v1(122.39,70.84) v1(122.44,67.13) v1(122.43,64.04) v1(122.47,65.78) v1(122.47,65.14) v1(122.46,63.44) v1(122.69,43.48) v1(122.8,75.36) v1(123.05,35.27) v1(123.16,43.79) v1(124.06,12.7) v1(124.29,74.81) v1(124.29,73.03) v1(124.53,81.48) v1(124.49,43.77) v1(124.93,70.84) v1(124.93,49.28) v1(124.87,46.32) v1(124.87,44.28) v1(125.83,67.12) v1(125.82,65.77) v1(125.82,65.13) v1(125.8,64.07) v1(125.78,63.43) v1(126.45,49.34) v1(126.46,46.32) v1(126.46,45.69) v1(127.07,81.48) v1(127.66,70.84) v1(127.97,47.95) v1(129.2,65.73) v1(129.2,65.09) v1(129.18,63.99) v1(129.18,63.41) v1(129.34,44.67) v1(129.34,44.1) v1(129.4,45.28) v1(129.61,81.48) v1(129.63,49.28) v1(129.94,70.84) v1(131.17,48.02) v1(131.28,45.79) v1(131.28,44.53) v1(131.28,43.96) v1(131.54,72.71) v1(132.15,81.48) v1(132.44,64.01) v1(132.43,63.43) v1(132.45,65.74) v1(132.45,65.1) v1(132.8,70.79) v1(133.25,45.41) v1(133.31,47.18) v1(134.04,31.38) v1(134.69,81.48) v1(134.9,70.81) v1(134.92,46.04) v1(134.87,43.73) v1(135.7,75.72) v1(135.68,65.7) v1(135.68,65.06) v1(135.66,63.97) v1(135.66,63.39) v1(135.77,12.7) v1(136.08,34.85) v1(136.99,46.49) v1(136.99,44.71) v1(137.23,81.48) v1(138.9,46.74) v1(138.9,44.96) v1(139.77,81.48) v1(140.48,46.04) v1(142.31,81.48) v1(142.29,43.97) v1(143.39,12.7) v1(144.85,81.48) v1(147.39,81.48) v1(148.26,35.33) v1(149.93,81.48) v1(150.46,47.61) v1(151.01,12.7) v1(152.47,81.48) v1(155.01,81.48) v1(157.55,81.48) v1(158.63,12.7) v1(160.09,81.48) v1(161,57.96) v1(162.63,81.48) v1(162.95,31.62) v1(164.15,34.95) v1(165.17,81.48) v1(166.25,12.7) v1(167.09,81.5) v1(168.89,51.45) v1(169.78,51.47) v1(170.25,81.48) v1(170.78,50.46) v1(170.77,12.7) v1(171.14,52.07) v1(171.59,12.71) v1(172.37,12.72) v1(172.79,81.48) v1(173.13,12.7) v1(173.87,12.7) v1(174.13,32.95) v1(174.1,17.74) v1(174.86,12.71) v1(175.33,81.48) v1(175.68,12.72) v1(176.46,12.73) v1(177.25,34.8) v1(177.22,12.71) v1(177.56,81.47) v1(181.42,18.05) v1(181.49,12.7) v1(185.78,68.93) v1(186.81,17.79) v1(187.29,81.48) v1(188.33,32.93) v1(188.46,34.64) v1(188.65,29.59) v1(189.11,12.7) v1(189.21,30.44) v1(189.83,81.48) v1(190.24,37.37) v1(190.25,35.66) v1(191.47,32.33) v1(191.84,39.57) v1(191.86,41.24) v1(191.86,40.17) v1(192.37,81.48) v1(193.07,71.18) v1(193.76,70.44) v1(194.91,81.48) v1(196.73,12.7) v1(197.45,81.48) v1(199.73,76.01) v1(199.79,77.95) v1(199.75,74.24) v1(199.85,72.69) v1(199.99,81.48) v1(201.12,75.04) v1(201.15,73.35) v1(201.21,71.41) v1(201.94,77.87) v1(202.02,34.24) v1(202.28,26.83) v1(202.28,26.27) v1(202.28,25.71) v1(202.4,74.24) v1(202.42,72.39) v1(202.53,81.48) v1(202.79,34.24) v1(203.13,79.68) v1(203.15,76.34) v1(203.17,19.9) v1(203.17,19.14) v1(203.17,16.9) v1(203.55,34.24) v1(204.12,46.52) v1(204.14,45.45) v1(204.35,12.7) v1(204.42,43.7) v1(204.42,42.35) v1(204.53,77.89) v1(204.56,75.08) v1(204.56,72.59) v1(204.7,70.7) v1(205.07,81.48) v1(205.35,46.55) v1(205.39,45.39) v1(205.54,42.35) v1(205.54,41.02) v1(205.55,43.82) v1(206.2,75.44) v1(206.2,67.82) v1(206.2,60.2) v1(206.2,52.58) v1(206.2,44.96) v1(206.42,37.35) v1(207.52,17.01) v1(208.25,30.21) v1(208.23,23.63) v1(208.29,25.9) v1(208.29,24.75) v1(208.3,20.42) v1(209.15,25.4) v1(209.15,24.27) v1(209.15,23.21) v1(209.21,17.42) v1(209.99,24.76) v1(209.97,23.76) v1(211.04,17.41) v1(211.26,24.56) v1(211.97,12.7) v1(213.14,20.04) v3(10.2,53.36) v3(10.2,36.86) v3(19.52,66.19) v3(20.4,66.19) v3(22.31,68.72) v3(26.45,21.62) v3(26.45,19.78) v3(26.52,42.82) v3(27.02,66.96) v3(27.27,57.53) v3(27.99,60.19) v3(28.16,57.53) v3(28.68,36.92) v3(29.02,44.19) v3(29.3,64.67) v3(29.38,72.14) v3(29.5,69.55) v3(29.99,46.49) v3(30.29,64.68) v3(30.57,39.47) v3(30.71,50.17) v3(30.83,45.6) v3(30.89,35.97) v3(31.21,52.2) v3(31.21,51.31) v3(31.16,18.3) v3(31.3,71.88) v3(31.41,42.8) v3(31.36,39.46) v3(31.78,35.97) v3(32.16,39.47) v3(32.83,34.54) v3(32.94,18.3) v3(33.84,20.84) v3(33.88,53.6) v3(33.94,36.93) v3(34.76,21.72) v3(35.07,54.5) v3(35.07,53.61) v3(35.22,50.81) v3(35.3,67.53) v3(36.66,78.61) v3(36.86,28.7) v3(36.86,26.93) v3(37.18,74.68) v3(37.76,34.62) v3(37.76,32.4) v3(37.76,31.45) v3(37.76,30.49) v3(38.44,78.61) v3(38.7,38.38) v3(38.78,25.22) v3(39.27,27.45) v3(40.72,25.92) v3(41.29,53.74) v3(42.21,52.85) v3(42.45,39.58) v3(43.06,75.47) v3(44.38,74.04) v3(44.42,43.08) v3(44.56,78.72) v3(45.98,72.74) v3(47.26,78.36) v3(51.25,78.3) v3(51.27,35.45) v3(54.07,63.02) v3(55.52,74.37) v3(66.27,36.06) v3(66.27,34.41) v3(66.27,32.51) v3(66.29,30.74) v3(66.42,70.49) v3(69.41,76.22) v3(70.91,70.49) v3(72.41,70.49) v3(75.02,31.52) v3(76.04,21.15) v3(76.93,21.15) v3(77.37,65.28) v3(85.12,21.15) v3(86.01,21.15) v3(86.9,21.15) v3(88.61,21.15) v3(91,27.85) v3(117.06,22.06) v3(124.62,21.15) v3(125.51,21.15) v3(125.76,76.67) v3(126.39,21.15) v3(129.38,21.15) v3(132.38,76.76) v3(133.95,78.96) v3(133.95,76.27) v3(142.93,57.96) v3(143.36,66.47) v3(145.12,57.76) v3(146.27,43.84) v3(148.07,75.52) v3(149.39,65.61) v3(153.64,19.05) v3(154.54,72.41) v3(154.53,19.05) v3(155.16,76.99) v3(155.41,19.05) v3(155.67,72.01) v3(155.83,69.93) v3(155.83,68.59) v3(156.3,19.05) v3(156.68,76.48) v3(156.75,43.18) v3(157.24,70.18) v3(157.19,19.05) v3(157.66,43.18) v3(158.27,18.56) v3(159.35,19.97) v3(159.47,67.2) v3(160.15,56.27) v3(160.32,62.31) v3(160.7,63.38) v3(162.12,44.26) v3(162.51,63.96) v3(162.5,63.07) v3(162.69,58.48) v3(163.06,61.74) v3(163.53,69.42) v3(165.07,62.95) v3(166.59,71.65) v3(166.84,21.15) v3(167.73,21.15) v3(167.84,72.84) v3(167.82,55.94) v3(168.62,21.15) v3(170.59,73.72) v3(171.16,78.71) v3(171.24,65.36) v3(171.24,64.47) v3(171.35,21.15) v3(171.6,77.44) v3(172.1,68.53) v3(172.08,66.5) v3(172.1,65.36) v3(172.1,64.47) v3(172.19,71.23) v3(172.36,21.96) v3(172.36,21) v3(172.62,61.69) v3(172.81,77.24) v3(173.02,69.55) v3(173.33,18.68) v3(173.83,75.44) v3(173.88,69.93) v3(174.13,66.63) v3(174.13,65.48) v3(174.13,64.47) v3(174.13,61.16) v3(174.6,18.68) v3(175.1,79.34) v3(175.53,41.35) v3(175.53,40.4) v3(175.67,73.61) v3(177,78.04) v3(177.02,59.01) v3(178.02,73.94) v3(178.37,44.87) v3(178.53,57.53) v3(179.02,44.87) v3(179.42,58.45) v3(179.47,61.14) v3(179.61,21.15) v3(179.93,41.91) v3(180.32,50.48) v3(180.32,44.68) v3(180.5,21.15) v3(180.69,67.51) v3(180.69,65.74) v3(180.69,63.96) v3(180.76,75.26) v3(180.81,73.03) v3(180.81,41.91) v3(181.39,21.15) v3(181.7,73.94) v3(182.08,57.53) v3(182.27,41.91) v3(182.54,75.26) v3(182.47,67.51) v3(182.47,65.74) v3(182.47,63.96) v3(182.47,61.14) v3(182.85,73.81) v3(182.97,57.53) v3(182.97,55.5) v3(183.16,41.91) v3(183.74,73.81) v3(184.04,58.37) v3(184.24,67.51) v3(184.24,65.74) v3(184.24,63.96) v3(184.24,53.11) v3(184.62,73.81) v3(184.62,41.91) v3(184.87,50.48) v3(184.87,44.68) v3(185.32,53.61) v3(185.46,61.14) v3(185.52,50.48) v3(185.51,41.91) v3(185.51,38.38) v3(186.47,70.34) v3(186.51,41.94) v3(187.07,66.74) v3(187.29,73.81) v3(187.94,36.08) v3(188.09,14.55) v3(188.18,73.81) v3(188.18,43.97) v3(188.51,58.37) v3(189.22,19.82) v3(189.22,18.88) v3(189.39,42.48) v3(189.39,40.07) v3(189.58,61.37) v3(189.58,58.55) v3(189.58,57.3) v3(190.67,66.75) v3(190.67,65.86) v3(191.36,58.55) v3(192.24,60.45) v3(192.24,56.39) v3(192.3,34.93) v3(192.3,30.18) v3(192.3,29.29) v3(192.3,28.4) v3(195.88,64.83) v3(196.7,17.51) v3(198.24,15.33) v3(198.89,25.58) v3(198.89,24.69) v3(198.93,20.41) v3(198.93,19.52) v3(199.79,20.41) v3(199.79,19.52) v3(200.07,17.05) v3(201.26,38) v3(201.91,28.78) v3(202.15,38) v3(202.72,30.61) v3(203.61,30.61) v3(205.1,37.97) v3(205.1,23.2) v3(205.85,27.51) v3(205.85,26.49) v3(205.85,25.6) v3(205.85,24.59) v3(205.91,29.99) v3(207,21.38) v3(206.99,20.41) v3(207,18.44) v4(51.3,78.72) v4(51.41,72.48) v4(51.43,71.94) v4(51.96,78.72) v4(51.97,72.45) v4(51.97,71.93) v4(54.23,76.87) v4(55.4,76.87) v4(60.6,80.2) v4(63.78,72.32) v4(69.51,77.86) v4(72.64,74.72) v4(85.23,29.24) v4(86.01,24.23) v4(86.11,25.71) v4(86.62,31.19) v4(86.63,22.93) v4(86.77,27.31) v4(87.05,78.32) v4(87.39,76.32) v4(87.64,79.5) v4(87.62,31.31) v4(87.61,22.32) v4(87.75,28.42) v4(87.82,29.71) v4(87.84,25.19) v4(88.41,76.34) v4(88.59,34.76) v4(88.66,32.64) v4(88.82,33.77) v4(88.76,26.67) v4(88.82,24.16) v4(88.87,79.84) v4(89.2,22.76) v4(89.63,28.79) v4(89.84,33.05) v4(92.23,76.27) v4(94.12,79.56) v4(94.12,78.39) v4(97.38,77.76) v4(98.48,33.17) v4(99.09,26.39) v4(99.1,24.44) v4(99.89,28.46) v4(100.19,23.37) v4(100.41,25.6) v4(100.64,21.96) v4(101.54,23.79) v4(101.79,22.76) v4(101.97,25.06) v4(103.03,24.66) v4(103.1,36.4) v4(103.81,26.61) v4(104.97,31.93) v4(105.26,30.18) v4(105.26,26.33) v4(105.53,28.36) v4(105.83,33.17) v4(114.05,29.47) v4(115.28,29.15) v4(115.31,24.94) v4(115.26,22.09) v4(115.49,24.04) v4(115.6,27.15) v4(115.82,29.62) v4(115.94,31.32) v4(116.25,22.95) v4(116.84,28.03) v4(116.95,34.61) v4(116.95,24.77) v4(117.09,33.69) v4(117.2,26.7) v4(117.35,32.41) v4(117.49,25.64) v4(117.52,22.51) v4(117.76,28.91) v4(138.03,72.72) v4(138.5,29.28) v4(139.04,73.9) v4(139.68,29.08) v4(139.67,27.78) v4(139.89,25.6) v4(140.16,24.49) v4(140.57,77.1) v4(140.67,32.16) v4(140.68,27.14) v4(141,22.19) v4(141.2,33.83) v4(141.44,70.07) v4(141.55,29.55) v4(141.71,77.1) v4(141.84,30.98) v4(142,25.13) v4(142.33,23.47) v4(142.74,70.04) v4(142.83,69.01) v4(142.75,28.78) v4(142.84,26.18) v4(143.12,33.12) v4(143.44,70.09) v4(143.77,69.01) v4(144.99,73.25) v4(145.31,73.88) v4(145.59,73.31) v4(145.65,69.44) v4(146.11,73.71) v4(147.66,61.22) v4(149.26,68.87) v4(149.71,51.67) v4(149.75,55.09) v4(149.98,62.59) v4(150.06,60.92) v4(150.36,68.73) v4(151.11,66.34) v4(151.53,61.43) v4(151.58,56.13) v4(151.83,52.49) v4(151.96,32.95) v4(152.28,68.02) v4(152.3,28.03) v4(152.49,26.84) v4(153.32,65.52) v4(153.37,61.4) v4(153.46,62.48) v4(153.9,66.94) v4(153.89,23.93) v4(154.23,56.63) v4(154.6,61.45) v4(154.59,25.85) v4(154.95,68.39) v4(154.98,21.78) v4(155.15,29.31) v4(155.45,25.95) v4(155.83,65.96) v4(155.83,64.44) v4(155.76,23.94) v4(155.92,57.96) v4(156.61,62.89) v4(156.56,23.36) v4(157.31,25.05) v4(157.54,26.49) v4(157.83,37.01) v4(158.4,29.73) v4(158.51,31.5) v4(158.54,27.95) v4(158.58,33.07) v4(159.94,29.92) v4(167.06,80.08) v4(167.43,29.44) v4(167.87,80.1) v4(168.15,32.02) v4(168.74,27.14) v4(168.71,24.42) v4(168.89,43.47) v4(169.09,42.91) v4(169.6,34.74) v4(169.57,22.79) v4(170.03,25.08) v4(170.13,23.28) v4(170.16,27.84) v4(170.26,30.85) v4(170.82,29.59) v4(170.97,22.57) v4(171.18,40.88) v4(171.16,26.56) v4(171.25,46.06) v4(171.65,40.05) v4(171.81,33.35) v4(172.19,40.92) v4(172.56,40.14) v4(176.81,80.82) v4(176.75,47.27) v4(178.06,80.81) v4(179.25,74.65) v4(180.92,74.59) v4(181.03,43.42) v4(181.09,66.16) v4(181.09,65.24) v4(181.12,63.93) v4(181.35,72.28) v4(181.4,19.59) v4(181.92,19.76) v4(182.36,43.81) v4(182.53,74.54) v4(183,21.26) v4(183.42,65.99) v4(183.43,65.37) v4(183.74,74.5) v4(183.9,72.12) v4(184.84,40.84) v4(184.83,40.32) v4(184.94,35.71) v4(184.97,37.35) v4(185.03,30.97) v4(185.06,33.04) v4(185.77,41.55) v4(187.93,28.14) v4(187.94,27.53) v4(188.26,74.54) v4(188.69,26.62) v4(188.8,27.75) v4(189.48,79.96) v4(189.7,80.86) v4(191.31,27.26) v4(192.3,29.75) v4(192.28,28.88) v4(192.3,27.95) v4(192.33,27.31) v4(192.36,26.72) v4(194.04,30.3) v4(194.09,28.66) v4(195.79,30.08) v4(195.79,29.43) v4(195.78,28.74) v4(195.83,27.31) v4(196.74,80.48) v4(198.29,80.5) v4(198.43,38.52) v4(198.65,39.92) v4(199.22,36.01) v4(199.32,43.02) v4(199.41,41.58) v4(199.36,37.75) v4(199.46,39.67) v4(199.51,28.43) v4(199.51,27.67) v4(200,44.51) v4(200.04,16.54) v4(200.12,36.86) v4(200.07,29.57) v4(200.07,29) v4(200.23,31.92) v4(200.26,31.39) v4(201.68,26.79) v4(201.69,26.18) v4(202.04,35.12) v4(202.04,33.19) v4(202.01,31.86) v4(202.66,29.69) v4(202.72,29.12) v4(202.82,33.19) v4(202.89,31.85) v4(202.86,26.59) v4(203.08,35.07) v4(203.59,33.21) v4(203.69,31.89) v4(203.76,29.41) v4(204.34,33.69) v4(204.34,32.52) v4(206.18,29.36) v4(206.39,27.5) v4(206.44,26.44) v4(206.44,25.59) v4(206.43,24.58) v4(207.55,20.34) v4(207.59,21.42) v5(19,53.62) v5(19,36.62) v5(24.8,64.75) v5(27.91,52.59) v5(27.91,48.85) v5(27.9,44.92) v5(27.91,36.65) v5(28.59,18.62) v5(28.59,17.73) v5(30.65,39.55) v5(30.76,24.26) v5(31.6,18.46) v5(31.75,38.77) v5(32.86,24.26) v5(33.25,38.77) v5(33.91,23.46) v5(34.52,23.47) v5(34.89,28.08) v5(34.95,29.99) v5(34.95,29.41) v5(35.53,28.08) v5(35.65,35.33) v5(37.88,31.21) v5(39.54,17.31) v5(39.75,38.77) v5(40.64,23.08) v5(40.63,22.51) v5(40.68,24.21) v5(40.85,56.56) v5(40.85,55.36) v5(40.85,54.66) v5(41.25,38.77) v5(41.6,56.55) v5(41.61,55.36) v5(41.6,54.68) v5(41.67,78.27) v5(42.42,56.56) v5(42.41,55.36) v5(42.44,54.66) v5(42.75,38.77) v5(42.84,55.05) v5(44.25,38.77) v5(44.38,77.28) v5(44.61,31.09) v5(45.03,35.6) v5(45.5,23.16) v5(45.75,38.77) v5(45.98,78.58) v5(46.45,23.16) v5(47.21,79.15) v5(47.25,38.77) v5(47.4,23.16) v5(48.3,17.35) v5(48.75,38.77) v5(50.25,38.77) v5(51.35,39.55) v5(53.1,31.72) v5(53.27,74.57) v5(54.03,69.43) v5(54.92,69.43) v5(56.2,72.62) v5(56.35,52.83) v5(58.11,67.27) v5(58.11,66.71) v5(58.11,66.05) v5(58.4,66.35) v5(58.64,67.26) v5(58.67,66.71) v5(58.67,66.05) v5(59.11,67.27) v5(59.11,66.71) v5(59.11,66.05) v5(60.57,69.13) v5(63.52,74.57) v5(70.19,79.86) v5(70.19,73.26) v5(72.14,76.96) v5(72.14,74.56) v5(72.8,55.02) v5(74.1,21.69) v5(74.3,32.18) v5(74.31,31.21) v5(74.31,30.32) v5(74.53,78.56) v5(74.53,77.64) v5(75.25,18.33) v5(76.8,66.19) v5(77.08,18.31) v5(77.69,66.19) v5(77.97,18.31) v5(79.23,17.85) v5(83.8,74.9) v5(90.43,17.85) v5(92.68,19.5) v5(103.43,65.55) v5(110.96,76.48) v5(114.28,65.81) v5(118.33,19.43) v5(120.03,71.95) v5(120.03,71.3) v5(121,19.43) v5(123.54,19.43) v5(126.2,19.43) v5(128.74,19.56) v5(132.43,19.56) v5(139.92,59.16) v5(143.41,75.97) v5(143.92,57.99) v5(145.95,53.55) v5(146.13,64.99) v5(146.13,61.18) v5(146.13,60.22) v5(147.02,64.03) v5(147.67,65.94) v5(147.67,62.13) v5(148.23,49.65) v5(148.54,45.1) v5(149.45,69.17) v5(150.3,65.09) v5(150.3,56.1) v5(150.3,53.11) v5(151.6,63.56) v5(151.6,60.56) v5(154.89,63.45) v5(155.74,62.56) v5(155.73,59.88) v5(155.81,70.75) v5(157.75,55.35) v5(158.02,46.64) v5(158.67,51.26) v5(158.67,50.31) v5(158.77,52.34) v5(163.83,60.15) v5(164.18,16.21) v5(166.12,18.37) v5(166.17,46.64) v5(167.8,53.68) v5(167.8,49.21) v5(168.06,71.27) v5(168.52,55.61) v5(169.94,61.67) v5(170,19.67) v5(170,14.07) v5(170.77,47.62) v5(170.79,45.86) v5(170.8,45.35) v5(170.79,44.82) v5(173.53,53.18) v5(174.66,68.22) v5(176.76,71.27) v5(178.05,74.31) v5(178.35,19.62) v5(178.48,44.87) v5(179.24,19.62) v5(179.74,54.74) v5(180.29,19.13) v5(181.34,53.01) v5(181.55,16.67) v5(182.88,42.89) v5(182.88,22.19) v5(183.65,41.8) v5(183.65,41.3) v5(183.65,40.8) v5(183.65,37.29) v5(183.65,35.79) v5(183.65,34.29) v5(183.65,32.79) v5(183.65,31.29) v5(183.65,29.79) v5(183.65,28.29) v5(183.65,26.79) v5(183.65,25.29) v5(183.65,23.79) v5(183.65,23.29) v5(183.94,46.12) v5(184.15,71.26) v5(184.57,65.1) v5(185.63,51.52) v5(185.65,19.72) v5(185.69,41.1) v5(186.75,74.31) v5(188.82,60.73) v5(189.17,27.39) v5(189.25,16.67) v5(189.7,60.73) v5(189.83,63.5) v5(191.76,71.85) v5(192,15.82) v5(193.1,32.87) v5(193.1,32.37) v5(193.1,31.87) v5(193.1,31.37) v5(193.1,30.37) v5(193.1,29.87) v5(193.1,29.37) v5(193.1,28.87) v5(196.09,43.19) v5(196.28,45.11) v5(196.31,44.46) v5(196.63,41.54) v5(196.66,40.38) v5(196.68,39.38) v5(196.82,43.02) v5(196.82,34.12) v5(196.82,25.22) v5(197.25,23.4) v5(197.81,40.99) v5(197.77,39.85) v5(197.97,45.14) v5(198.04,43.86) v5(198.06,42.96) v5(198.09,42.05) v5(198.37,23.39) v5(198.85,24.46) v5(198.86,25.57) v5(199.43,31.94) v5(199.43,30.94) v5(199.43,29.94) v5(199.43,28.94) v5(199.45,23.43) v5(200.77,25.6) v5(200.77,24.49) v5(200.79,23.43) v5(201.66,38.43) v5(201.74,37.54) v5(201.69,25.61) v5(202.02,35.75) v5(202.05,33.7) v5(201.96,23.99) v5(202.07,32.48) v5(202.07,30.92) v5(202.29,28.84) v5(202.58,37.54) v5(202.68,24.84) v5(202.75,23.38) v5(202.85,32.51) v5(202.9,38.45) v5(202.93,30.97) v5(203.03,35.7) v5(203.17,33.7) v5(203.17,28.86) v5(203.57,32.52) v5(203.79,33.74) v5(203.81,30.98) v5(204.02,38.44) v5(204.02,37.45) v5(204.22,35.09) v5(204.28,34.29) v5(204.36,28.89) v5(204.51,63.96) v5(204.81,31.8) v5(204.97,31) v5(205.12,29.8) v5(205.24,28.98) v5(205.38,35.09) v5(205.48,34.27) v5(205.64,32.91) v5(205.75,32.08) v5(205.95,31.05) v5(207.4,18.41) v5(210.7,15.54) v5(211.4,15.82) v6(17.79,67.56) v6(18.99,20.16) v6(32.24,27.66) v6(54.67,39.98) v6(57.65,28.25) v6(58.36,31.63) v6(74.48,48.08) v6(78.35,60.87) v6(80.04,54.7) v6(80,54.47) v6(86.63,49.6) v6(88.69,59.11) v6(91.72,44.71) v6(120.87,42.99) v6(130.12,43.23) v6(133.6,40.06) v6(135.58,40.27) v6(198.07,59.48) v7(36.48,61.98) v7(36.47,61.35) v7(38.65,63.31) v7(39.4,62.56) v7(39.5,59.11) v7(40.16,59.11) v7(53.13,44.22) v7(53.13,43.59) v7(53.13,42.95) v7(55.34,32.21) v7(55.34,31.11) v7(55.38,33.36) v7(55.53,62.88) v7(55.53,62.24) v7(55.53,61.61) v7(55.53,60.97) v7(55.68,32.78) v7(55.67,31.64) v7(56,32.22) v7(55.99,31.08) v7(56.34,32.78) v7(56.33,31.64) v7(56.65,31.08) v7(56.66,32.22) v7(57.01,32.81) v7(57,31.64) v7(57.29,32.22) v7(57.31,31.09) v7(57.65,32.81) v7(57.64,31.64) v7(57.93,32.22) v7(57.94,31.09) v7(58.3,33.02) v7(58.96,55.26) v7(58.96,54.43) v7(59.78,55.26) v7(59.78,54.43) v7(61.37,50.88) v7(62.01,50.88) v7(62.83,57.35) v7(62.83,56.72) v7(64.62,52.17) v7(65.24,52.16) v7(65.43,57.93) v7(65.75,51.7) v7(66.2,57.93) v7(66.77,52.08) v7(66.76,51.13) v7(66.9,57.93) v7(67.53,51.13) v7(67.59,52.08) v7(68.42,57.29) v7(68.42,52.08) v7(69.05,57.29) v7(69.5,50.43) v7(69.69,57.29) v7(69.88,51) v7(69.88,41.61) v7(70.39,52.15) v7(70.39,51.51) v7(70.58,41.61) v7(71.63,41.61) v7(72.33,41.61) v7(73.13,41.61) v7(73.18,49.16) v7(73.18,48.46) v7(73.82,49.16) v7(73.82,48.46) v7(73.83,41.61) v7(74.68,46.57) v7(75.12,45.35) v7(75.15,43.35) v7(75.91,61.67) v7(75.98,60.28) v7(76.87,61.1) v7(77.82,60.28) v7(78.83,53.86) v7(79.15,53.29) v7(79.53,53.86) v7(79.47,52.72) v7(79.85,53.29) v7(80.23,53.86) v7(80.17,52.72) v7(80.55,53.29) v7(80.93,53.86) v7(80.87,52.72) v7(81.25,53.29) v7(81.63,53.86) v7(81.56,52.72) v7(81.94,53.29) v7(82.33,53.86) v7(82.26,52.72) v7(86.07,47.9) v7(86.07,47.2) v7(86.71,64.47) v7(86.71,63.83) v7(86.71,63.2) v7(86.71,62.56) v7(87.28,49.29) v7(87.28,48.62) v7(87.85,49.67) v7(87.85,48.97) v7(88.38,49.3) v7(88.38,48.62) v7(89.12,61.04) v7(89.12,60.28) v7(89.12,59.51) v7(89.12,58.75) v7(89.12,57.99) v7(89.08,56.61) v7(89.08,55.97) v7(89.76,61.04) v7(89.76,60.28) v7(89.76,59.51) v7(89.76,58.75) v7(89.76,57.99) v7(90.39,61.04) v7(90.39,60.28) v7(90.39,59.51) v7(90.39,58.75) v7(90.39,57.99) v7(90.73,56.77) v7(90.77,56.14) v7(91.39,68.46) v7(92.02,68.46) v7(92.1,44.02) v7(92.42,44.59) v7(92.74,44.02) v7(93.06,44.59) v7(93.25,68.47) v7(93.88,68.47) v7(95.09,68.47) v7(95.85,68.47) v7(96.52,68.47) v7(97.19,68.46) v7(194.15,59.7) v7(194.15,59.07) v7(194.15,58.05) v7(194.15,57.42) v7(194.15,56.28) v7(194.15,55.64) v7(194.15,54.62) v7(194.15,53.99) v7(197.15,60.62) v7(197.15,59.98) v7(197.51,62.37) v7(197.78,60.62) v7(197.78,59.98) v7(198.15,62.37) v7(198.42,60.62) v7(198.42,59.98) v7(198.91,61.93) v7(198.91,61.29) v7(199.04,60.59) v7(199.04,59.96)
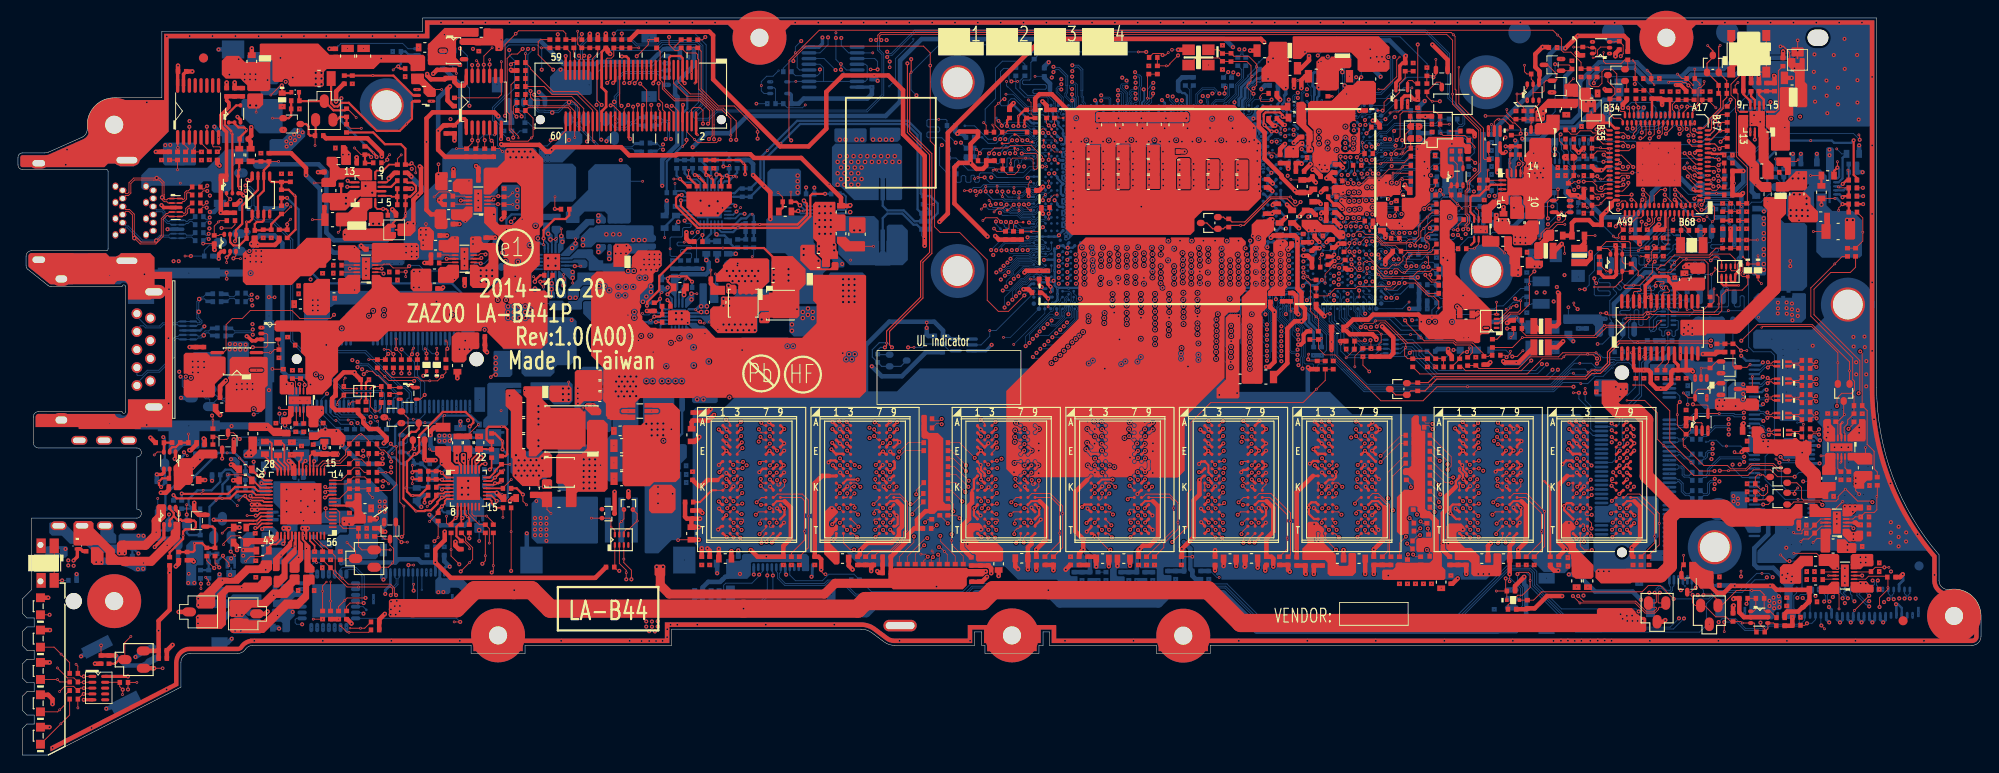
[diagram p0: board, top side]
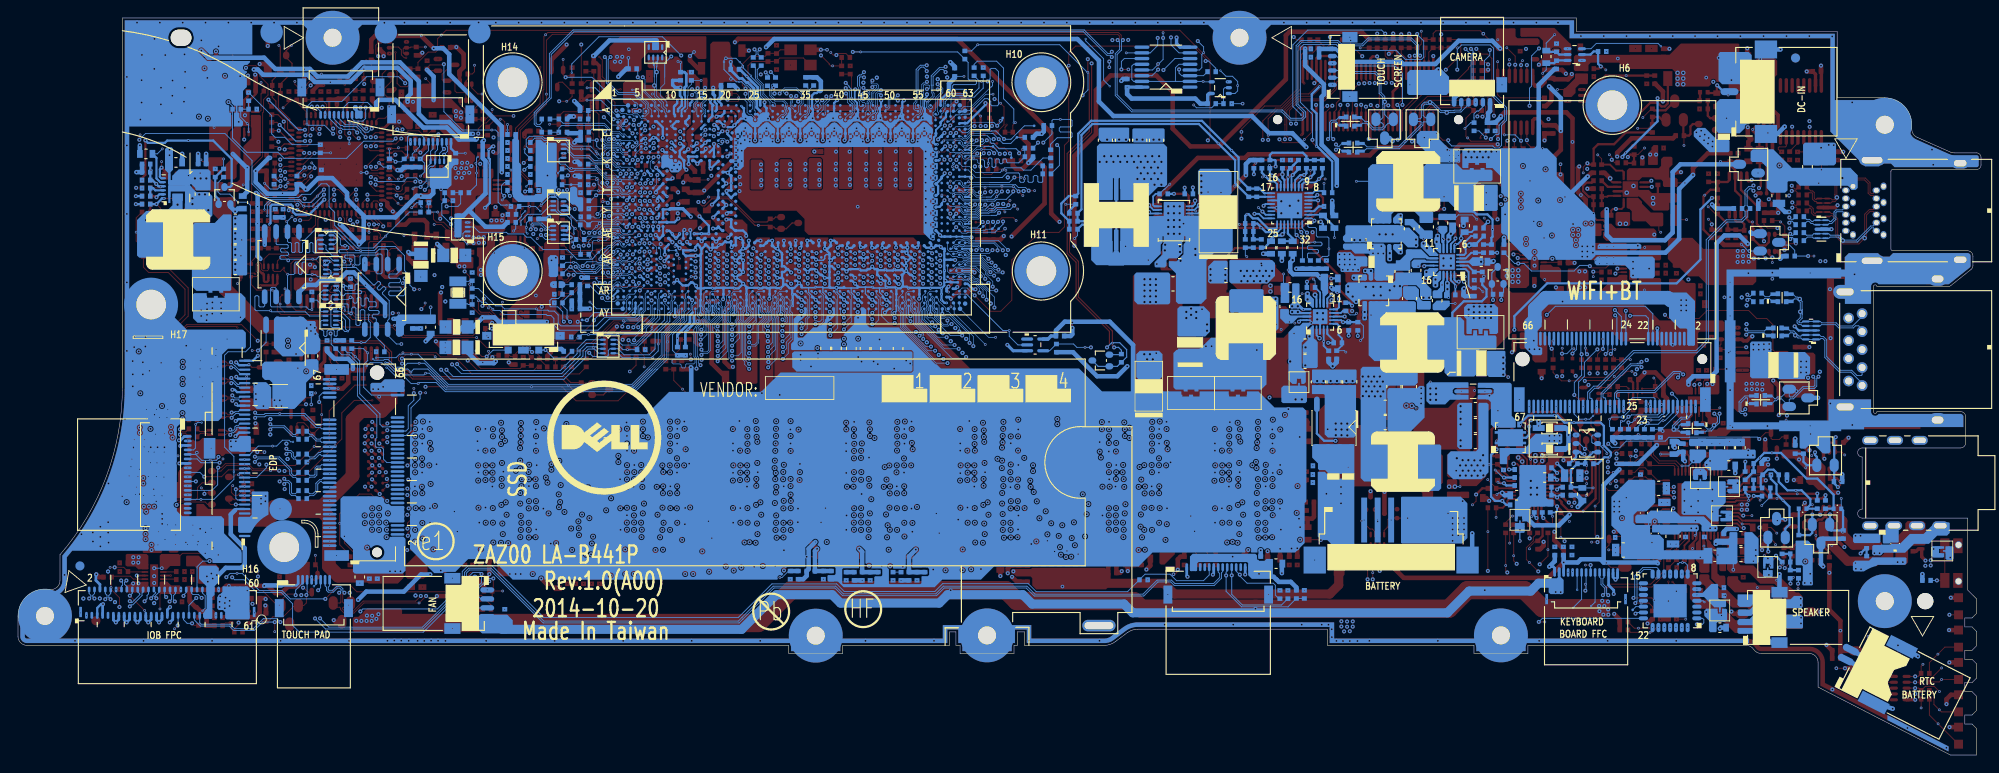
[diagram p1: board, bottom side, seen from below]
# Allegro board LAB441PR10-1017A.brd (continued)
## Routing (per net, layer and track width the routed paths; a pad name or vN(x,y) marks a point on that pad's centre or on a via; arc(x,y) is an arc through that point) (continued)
GNDA_CHG: length 21.4
  TOP w0.508: PR229.2 49.03,22.91 48.65,23.29 v1(48.65,23.72) ; v1(46.44,32.81) v2(45.32,32.81) 45.21,32.91 PQ206.3
  IN3 w0.508: v1(45.76,26.73) 45.76,25.46 47.5,23.72 v1(48.65,23.72)
  IN4 w0.508: v1(45.76,26.73) 46.52,27.49 46.52,32.72 v1(46.44,32.81)
  BOTTOM w0.508: 50.31,26.37 50.31,26.19 49.67,25.55 46.94,25.55 v1(45.76,26.73)
  vias: v7(49.37,29.73) v7(49.37,28.97) v7(50.07,30.49) v7(50.07,29.73) v7(50.07,28.97)
VCCSENSE: length 39.6
  TOP w0.254: RC98.1 111.95,71.78 v2(111.26,71.08) v1(111.26,69.98)
  IN2 w0.254: v1(80.8,60.21) 80.8,61.01 86.9,67.11 98.44,67.11 98.69,66.85 105.36,66.85 107.17,68.67 108.09,68.67 108.42,68.99 110.34,68.99 111.26,69.9 v1(111.26,69.98)
  BOTTOM w0.203: v1(80.8,60.21) 80.29,60.21 79.79,59.7 PU700.24
VCCSENSE_R: length 5.5
  TOP w0.076: v2(112.37,72.88) 112.67,72.59 112.67,71.33 113.12,70.88 RC97.2
  TOP w0.254: RC97.2 RC98.2 111.93,70.63 v1(111.93,69.97)
  BOTTOM w0.102: v1(111.93,69.97) 112.25,69.97 112.59,69.63 UCPU1.E63
VDD_1.35V: length 7.9
  TOP w0.254: v1(74.96,52.66) 74.37,53.25 v2(73.53,53.25) 72.5,53.25 v1(72.26,53.01) 72.26,52.67 PC611.1 72.9,51.93 v1(72.23,51.26)
  BOTTOM w0.203: PU600.11 72.7,50.27 72.7,50.79 v1(72.23,51.26)
  BOTTOM w0.254: PR601.1 74.97,52.64 v1(74.96,52.66) ; PR603.2 72.24,53.04 v1(72.26,53.01)
VSSSENSE: length 41.2
  TOP w0.254: RC100.1 110.26,70.87 109.99,70.6 v1(109.99,69.99)
  IN2 w0.254: v1(109.99,69.99) 109.99,69.94 109.4,69.34 108.27,69.34 107.95,69.02 107.02,69.02 105.21,67.21 98.84,67.21 98.56,67.49 86.78,67.49 80.45,61.16 80.45,61 v1(79.91,60.47)
  BOTTOM w0.102: UCPU1.E62 113.27,69.24 112.72,69.24 112.35,69.6 110.38,69.6 v1(109.99,69.99) ; v2(80.36,60.91) 79.92,60.47 v1(79.91,60.47)
  BOTTOM w0.203: v1(79.91,60.47) 79.55,60.1 PU700.23
+DC_IN: length 32.8
  TOP w0.508: PR114.1 36.23,74.68 35.37,73.82 v1(35.37,72.72)
  IN1 w0.508: v1(46.87,34.95) 46.18,34.95 45.76,34.53 45.76,31.29 44.62,30.15 44.62,27.83 v1(44.85,27.6)
  IN2 w3.048: 31.78,73.17 27.97,69.35 27.97,57.99 29.67,56.28
  BOTTOM w0.508: v1(44.85,27.6) 44.34,28.11 PC200.1 44.93,28.91 PR209.2
  vias: v1(46.86,35.53) v1(47.44,35.54) v1(47.45,34.96) v1(48,35.52) v1(48.01,34.95) v6(29.19,77.56) v6(30.56,75.37) v6(40.39,77.49) v7(33.11,75.9) v7(33.11,75.26) v7(33.11,74.63) v7(33.75,75.9) v7(33.75,75.26) v7(33.75,74.63)
+DCIN: length 3.3
  TOP w0.102: PR207.2 46.01,33.8 v2(45.76,34.04)
  BOTTOM w0.254: PC206.1 46.31,31.61 v1(47.13,32.43)
+DCIN_JACK:
  vias: v1(25.23,75.75) v1(25.2,75.14) v1(25.81,75.76) v1(25.8,75.15) v1(26.42,75.75) v1(26.41,75.14) v6(23.51,75.7) v6(24.54,77.42) v6(27.75,75.09)
+DP_PWR:
  vias: v2(18.05,63.62)
+INV_PWR_SRC:
  vias: v1(189.01,38.81) v1(189.2,39.46) v1(189.59,38.81) v1(189.78,39.47) v1(190.77,28.81) v1(190.8,28.23) v1(191.28,28.53) v1(191.28,27.94) v6(191.01,38.82)
+LCDVDD: length 16.5
  TOP w1.524: 199.74,29.72 199.74,31.22 198.42,32.54 v6(198.42,33.64)
  GND1 w0.508: v3(187.81,39.74) v4(188.17,39.74)
  IN3 w0.508: v4(188.17,39.74) 188.17,39.91 188.77,40.51 189.83,40.51 191.47,38.87 192.94,38.87 193.22,38.59 193.22,34.77 193.68,34.31 v1(194.61,34.31)
  vias: v1(194.09,34.91) v1(194.65,34.92)
+LDO2: length 9
  TOP w0.203: CA88.1 31.53,32.91 31.26,32.64 UA2.22
  TOP w0.508: CA88.1 30.52,33.47 v3(30.46,33.4)
  GND1 w0.508: v4(30.45,34.05) 30.46,34.04 v3(30.46,33.4)
  IN1 w0.508: v4(30.45,34.05) 29.87,34.05 27.33,31.51 v1(27.33,31.37)
  BOTTOM w0.508: RA84.1 v1(27.33,31.37)
+MD_VREF_CA: length 193.1
  TOP w0.229: UD7.M8 137.98,28.25 138.86,28.25 ; UD3.M8 150.59,28.25 151.28,28.25 151.97,27.56 ; UD4.M8 178.94,28.25 179.74,28.25 ; 126.22,28.25 125.34,28.25 UD32.M8 ; UD31.M8 112.71,28.25 113.61,28.25 ; 85.25,28.24 84.38,28.24 UD28.M8 ; 97.76,28.24 96.99,28.24 UD29.M8 ; 167.18,28.25 166.3,28.25 UD1.M8
  TOP w0.508: v1(81.5,22.81) 82.25,22.06 83.24,22.06 ; 179.74,28.25 180.4,27.6 180.4,23.99 v1(179.48,23.08) 179.48,22.19 CD96.1 ; v1(139.6,20.97) 139.6,21.86 139.4,22.06 CD91.1 138.84,24.08 139.6,24.84 139.6,27.51 138.86,28.25 ; 167.18,28.25 167.7,27.74 167.7,23.73 v1(166.84,22.87) CD90.1 ; 97.76,28.24 98.3,27.7 98.3,25.41 97.97,25.08 97.97,24.42 97.15,23.6 94.48,23.6 v1(93.69,22.81) 93.63,22.75 93.63,22.32 CD87.1 ; 113.61,28.25 114.34,27.52 114.34,23.97 v1(113.25,22.87) CD88.1 ; 85.25,28.24 85.94,27.54 85.95,27.54 85.95,24.08 85.12,23.26 CD85.1 83.24,22.06 ; CD95.1 v1(150.78,22.87) 151.97,24.07 151.97,27.56 ; 83.24,22.06 v6(83.23,22.07) ; CD89.1 124.62,22.81 v1(124.74,22.94) 125.1,23.29 125.85,23.29 126.78,24.21 126.78,27.7 126.22,28.25
  IN2 w0.508: v1(81.5,22.81) 82.18,22.13 85.22,22.13 86.92,20.42 88.58,20.42 89.03,19.98 91.65,19.98 92.07,20.4 92.07,21.1 93.69,22.72 v1(93.69,22.81) 96.07,22.81 98.51,20.37 106.24,20.37 108.18,22.32 112.69,22.32 v1(113.25,22.87) 113.48,22.87 113.89,22.47 113.89,20.8 114.83,19.85 117.97,19.85 119.97,21.85 122.17,21.85 123.26,22.94 v1(124.74,22.94) 125.48,22.2 133.41,22.2 134.01,22.81 135.16,22.81 136.36,21.6 138.97,21.6 v1(139.6,20.97) 148.87,20.97 v1(150.78,22.87) 152.3,22.87 154.3,20.88 164.85,20.88 v1(166.84,22.87) 168.86,20.85 170.37,20.85 170.69,21.17 172.93,21.17 173.61,21.86 176.89,21.86 177.35,21.4 178.73,21.4 179.48,22.15 v1(179.48,23.08)
  BOTTOM w0.508: RD13.2 RD16.1 RD15.1 124.43,22.62 v1(124.74,22.94)
+MD_VREF_DQA: length 99.7
  TOP w0.102: v1(89.32,20.63) 89.32,20.43 89.64,20.11 v6(89.81,20.11)
  TOP w0.254: 77.8,30.59 78.26,31.05 78.39,31.05 UD28.H1 ; 106.1,29.14 106.1,29.45 106.3,29.66 106.3,30.65 UD31.H1 ; UD32.H1 119.35,31.05 118.9,30.61
  TOP w0.356: UD29.H1 91,31.05 90.21,31.05
  TOP w0.508: CD77.1 75.71,29.92 v1(76.01,29.92) 76.67,30.59 77.8,30.59 ; CD93.1 105.01,23 105.01,23.71 v1(105.06,23.76) 105.06,25.55 105.77,26.27 105.77,27.75 106.1,28.08 106.1,29.14 ; 90.21,31.05 89.41,31.05 88.61,30.25 CD78.1 89.03,22.06 89.32,21.77 v1(89.32,20.63) ; 118.9,30.61 117.59,29.3 117.59,24.88 118.46,24.01 v1(118.46,22.85) 118.01,22.4 CD94.1
  IN2 w0.508: v1(76.01,29.92) 76.01,28.3 77.28,27.03 77.28,24.56 78.39,23.45 81.94,23.45 82.65,22.74 85.49,22.74 87.15,21.08 88.87,21.08 v1(89.32,20.63) 90.57,20.63 92.12,22.18 92.12,22.91 92.71,23.51 96.19,23.51 98.72,20.98 104.2,20.98 104.92,21.71 104.92,23.62 v1(105.06,23.76) 105.39,24.09 106.4,24.09 107.57,22.93 112.29,22.93 112.84,23.48 113.85,23.48 114.49,22.84 114.49,21.87 114.98,21.39 117.52,21.39 118.46,22.33 v1(118.46,22.85)
  BOTTOM w0.508: RD34.2 RD119.1 RD121.1 119.22,22.1 v1(118.46,22.85)
+MD_VREF_DQB: length 94.6
  TOP w0.102: 129.44,22.06 v6(130.6,22.06)
  TOP w0.254: UD3.H1 144.59,31.05 144.02,31.05 ; 159.9,29.86 159.9,30.47 160.3,30.88 UD1.H1 ; 172.29,31.05 172.94,31.05 UD4.H1 ; UD7.H1 131.85,31.05 v1(131.39,30.59)
  TOP w0.508: CD51.1 v1(142.21,22.66) 142.21,29.24 144.02,31.05 ; 172.29,31.05 171.29,30.05 171.29,23.71 v1(172.11,22.89) 171.35,22.12 CD52.1 ; 159.9,29.86 158.84,28.81 158.84,27.28 158.46,26.9 v1(158.46,23.57) 158.46,22.81 159.21,22.06 CD35.1 ; CD37.1 129.44,22.06 v1(129.44,22.94) 130.75,24.25 130.75,28.33 131.39,28.97 v1(131.39,30.59)
  IN2 w0.508: v1(158.46,23.57) 158.46,23.23 ; 158.46,23.23 157.47,22.24 156.11,22.24 155.4,22.95 153.43,22.95 152.81,23.57 146.48,23.57 146.26,23.35 143.65,23.35 142.96,22.66 v1(142.21,22.66) 142.21,22.8 141.42,23.59 140.61,23.59 139.98,22.96 136.08,22.96 135.54,23.51 131.67,23.51 131.09,22.94 v1(129.44,22.94) ; 158.46,23.23 158.46,23.13 158.97,22.62 165.57,22.62 166.46,23.51 167.04,23.51 169.07,21.48 170.17,21.48 170.45,21.76 170.98,21.76 v1(172.11,22.89)
  BOTTOM w0.508: RD14.2 RD18.1 129.67,20.47 RD20.1 129.68,22.7 v1(129.44,22.94)
+PBATT: length 35.9
  TOP w0.102: v1(49.2,37.12) v2(49.2,36.61)
  TOP w0.508: PR222.2 55.02,28.59 v1(54.7,28.27)
  IN3 w0.508: v4(70.86,30.95) 68.18,28.27 v1(54.7,28.27) 54.7,36.84 53.66,37.89 51.25,37.89 50.74,38.39 50.38,38.39 49.2,37.22 v1(49.2,37.12)
  GND3 w0.508: v5(70.38,32.01) 70.38,31.42 70.84,30.95 v4(70.86,30.95)
  BOTTOM w0.508: v1(49.2,37.12) 49.19,37.1 PD200.2
+PCH_VCCDSW: length 1.1
  BOTTOM w0.254: UCPU1.AG19 141.04,57.49 v1(140.67,57.11) 140.3,57.49 UCPU1.AG20
  vias: v2(140.38,56.7)
+PWR_SRC_AC: length 0.7
  TOP w0.102: v7(61.24,40.78) v2(61.24,41.5)
  vias: v7(60.61,40.78) v7(60.61,40.15) v7(60.61,39.51) v7(61.24,40.15) v7(61.24,39.51)
+RTC_CELL_VBAT: length 12.4
  TOP w0.254: v3(190.47,59.46) CE65.1 ; UE5.B64 184.47,61.14 184.47,61.56 v1(184.24,61.79)
  GND1 w0.254: v3(190.47,59.46) 190.47,59.34 v4(190.85,58.95)
  GND3 w0.254: v4(190.85,58.95) 190.45,58.95 v5(190.36,59.04)
  BOTTOM w0.254: v1(184.24,61.79) 184.26,61.79 v2(185.15,60.89) 185.92,60.12 187.41,60.12 187.74,60.45 187.74,61.04 187.93,61.24 190.06,61.24 190.23,61.07 190.23,59.18 v5(190.36,59.04)
+RTC_VCCSUS: length 17.1
  TOP w0.508: v1(144.73,56.39) 144.19,56.39 CH1207.1 ; v3(146.08,45.05) v2(146.08,45.96) RH341.2
  GND1 w0.508: v3(146.08,45.05) 146.08,44.85 v4(145.76,44.53)
  IN3 w0.508: v1(144.73,56.39) 144.44,56.09 144.44,51.51 144.58,51.36 144.58,45.71 v4(145.76,44.53)
  BOTTOM w0.254: UCPU1.AH11 145.14,56.8 v1(144.73,56.39)
+RTCBATT: length 7.5
  TOP w0.102: v6(9.24,12.2) C2973.1
  TOP w0.508: C2973.1 RTCR1.2 v1(10.83,11.08)
  BOTTOM w0.508: JRTC1.1 13.8,9.97 11.94,9.97 v1(10.83,11.08)
+RTCVCC: length 343.8
  TOP w0.254: 189.96,52.25 189.96,53.22 RPE5.6 ; 189.96,52.25 v3(191.37,52.25) ; 189.96,52.25 189.65,52.25 189.46,52.44 RPE5.5
  TOP w0.508: v1(151.71,47.66) 151.74,47.66 152.95,46.45 152.95,44.7 152.58,44.32 RH11.1 RH31.1 ; RE36.1 v3(190.47,58.55) ; CH82.1 145.83,57.36 v1(145.53,57.06) ; C1309.1 15.59,11.58 D122.3 ; C1309.1 v6(15.64,13.84) 15.64,14.93 16.87,16.16 v1(16.87,20.28) RA16.1 ; C1309.1 CH95.1
  GND1 w0.254: v4(191.69,52.08) 191.52,52.25 v3(191.37,52.25) ; v4(190.86,61.13) 190.62,61.37 v3(190.47,61.37) ; v3(190.47,58.55) 190.47,58.27 190.69,58.05 v4(190.79,58.05)
  IN1 w0.508: v4(172.65,47.03) 173.39,47.03 174.94,48.58 177.17,48.58 178.83,50.23 180.24,50.23 180.68,50.67 182.25,50.67 182.51,50.41 187.62,50.41 188.34,49.68 188.34,49.13 191,46.47 191,43.19 v4(191.19,43)
  IN2 w0.508: v1(145.53,57.06) 145.58,57.01 145.58,52.22 146.06,51.75 146.59,51.75 146.96,51.38 146.96,50.48 147.43,50 148.37,50 148.62,50.26 154.11,50.26 v1(154.72,49.65) 155.65,50.59 157.58,50.59 158.37,49.8 158.37,48.46 159.39,47.44 160.73,47.44 v4(160.89,47.28) 161.31,46.86 168.03,46.86 168.49,46.39 170.32,46.39 170.95,47.03 172.63,47.03 172.63,47.03 v4(172.65,47.03) ; v4(191.19,43) 192.56,41.63 192.56,34.71 193.31,33.96 193.31,21.84 192.88,21.41 192.88,16.39 192.23,15.74 189.2,15.74 187.76,14.31 178.41,14.31 176.78,15.95 172.37,15.95 171.51,16.81 171.33,16.98 127.28,16.98 127.23,16.94 113.84,16.94 113.7,17.07 105.49,17.07 104.76,17.8 72.19,17.8 69.5,20.49 67.72,20.49 65.87,18.63 49.36,18.63 45.37,14.64 37.99,14.64 37.39,15.24 26.41,15.24 25.17,16.48 22.09,16.48 20.51,18.07 19.05,18.07 16.87,20.26 v1(16.87,20.28)
  IN3 w0.508: v4(190.86,61.13) 190.29,60.56 190.29,58.45 190.69,58.05 v4(190.79,58.05) 190.79,57.38 190.5,57.1 190.5,53.27 v4(191.69,52.08) 191.69,47.05 192.24,46.49 192.24,44.05 v4(191.19,43) ; v4(157.37,46.57) 159.28,46.57 159.98,47.28 v4(160.89,47.28) ; v1(145.53,57.06) 145.53,56.47 145.58,56.41 145.58,49.44 146.69,48.33 151.44,48.33 151.71,48.07 v1(151.71,47.66)
  GND3 w0.508: v5(156.77,46.5) 156.84,46.57 v4(157.37,46.57)
  BOTTOM w0.254: v1(145.53,57.06) 145.95,57.48 UCPU1.AG10
  BOTTOM w0.508: RH25.1 RH23.1 155.81,51.42 CH83.1 CH84.1 154.73,49.64 v1(154.72,49.65)
+SDC_IN:
  vias: v2(53.73,38.31)
+VCHGR:
  vias: v6(72.66,36.24) v7(69.88,36.85) v7(70.49,36.87) v7(70.47,36.2) v7(70.47,35.56) v7(71.13,36.88) v7(71.12,36.22) v7(71.12,35.58) v7(71.77,36.88) v7(71.76,36.22) v7(71.76,35.58)
+VR_CAP: length 15.6
  TOP w0.305: v1(186.49,66.99) 186.49,67 186.73,67.24 UE5.B12
  IN2 w0.508: v1(186.49,66.99) 186.75,66.73 188.8,66.73 188.92,66.85 189.43,66.85 189.93,66.34 193.31,66.34 v4(194.4,67.43)
  GND3 w0.508: v4(194.4,67.43) 194.42,67.42 v5(194.42,66.87)
  BOTTOM w0.508: CE45.1 192.82,62.68 v2(192.82,65.35) 192.89,65.35 v5(194.42,66.87)
+VS_LPSS_SDIO: length 232.2
  TOP w0.254: U679.C1 38.19,41.68 C1284.1
  TOP w0.381: U671.1 49.85,70.59 49.65,70.8 49.27,70.8 C1286.1
  TOP w0.508: v1(40.68,34.69) 40.99,35 40.99,35.29 40,36.28 39.07,36.28 38.41,36.94 38.41,37.45 37.81,38.05 R1131.2 35.35,38.38 34.93,38.79 34.93,39.65 R1327.1 R1328.1 35.32,41.66 36.22,42.56 v1(37.42,42.56) 37.42,42.46 C1284.1 ; v1(48.04,74.38) 47.77,74.11 47.77,72.82 48.39,72.2 R1188.2 ; C1286.1 C1299.1 47.36,70.07 v1(46.73,69.44) 46.73,67.33 47.51,66.55 R1373.1 R1374.1 R1375.1 52.88,66.55 R1372.1
  IN3 w0.254: v1(152.14,63.67) 152.14,66.17 151.56,66.75 151.56,70.86 152.35,71.65 155.34,71.65 v1(156.44,72.76)
  IN3 w0.508: v4(28.72,43.65) 28.72,43.76 30.43,45.47 34.49,45.47 37.4,42.56 v1(37.42,42.56) ; v1(48.04,74.38) 48.4,74.75 64.47,74.75 65.11,75.38 72.74,75.38 73.05,75.7 74.58,75.7 75.24,75.04 79.94,75.04 81.17,73.8 97.62,73.8 98.23,74.41 99.95,74.41 102.84,71.52 105.86,71.52 108.42,74.08 114.14,74.08 115.5,72.72 118.5,72.72 122.48,76.7 124.37,76.7 125.71,75.36 127.48,75.36 128.5,74.35 135.91,74.35 136.96,75.39 147.89,75.39 148.61,76.11 149.48,76.11 150.24,75.35 150.24,75.11 151.14,74.21 152.04,74.21 152.98,75.16 155.35,75.16 156.44,74.06 v1(156.44,72.76)
  IN4 w0.508: v4(28.72,43.65) 28.69,43.65 28.12,44.22 28.12,49.06 27.27,49.91 27.27,51.18 24.55,53.89 24.55,56.64 25.96,58.05 25.96,60.33 33.31,67.68 44.97,67.68 v1(46.73,69.44)
  BOTTOM w0.254: UCPU1.T9 147.02,63.11 UCPU1.U8 147.36,62.74 v1(147.36,62.59)
  BOTTOM w0.508: R1360.1 R1361.1 R1362.1 R1363.1 R1364.1 R1365.1 40.99,35 v1(40.68,34.69) ; RH434.1 155.8,71.72 155.8,72.11 v1(156.44,72.76) ; v1(46.73,69.44) 46.73,73.07 v1(48.04,74.38)
  vias: v6(151.36,63.94)
-DCIN_JACK: length 0.7
  TOP w0.102: v7(26.49,72.25) v2(26.49,71.51)
  vias: v7(25.81,72.28)
A_ON: length 37.7
  TOP w0.102: v1(188.55,63.25) 188.32,63.49 UE5.A4 ; R270.1 204.18,36.9 v1(203.57,36.29)
  IN2 w0.086: v1(188.55,63.25) 189.34,62.47 189.34,61.29 189.54,61.08 189.54,54.7 189.69,54.55 189.69,51.6 193.67,47.62 195.19,47.62 197.97,44.83 197.97,39.61 198.97,38.62 201.24,38.62 v1(203.57,36.29)
  BOTTOM w0.102: v1(188.55,63.25) 188.55,63.42 v2(188.28,63.69)
AC_DIS: length 214.9
  TOP w0.102: UE5.A10 188.54,66.49 188.68,66.36 189.05,66.36 v1(189.15,66.26) ; v1(44.05,34.06) 43.83,34.06 v2(43.39,33.61)
  TOP w0.254: v1(44.05,34.06) 43.91,34.2 PQ206.2
  IN1 w0.071: v1(44.05,34.06) 43.47,33.48 43.47,27.63 43.72,27.38 43.72,25.18 44.49,24.41 46.58,24.41 48.12,22.87 49.27,22.87 50.22,21.92 50.22,20.48 55.43,15.27 v4(55.88,15.27)
  IN3 w0.086: v1(189.15,66.26) 189.25,66.26 189.69,65.82 189.69,62.86 189.58,62.76 189.58,58.21 189.91,57.89 189.91,52.82 190.45,52.27 190.45,43.52 186.88,39.95 186.88,38.52 186.24,37.88 186.24,30.02 185.54,29.32 185.54,20.46 183.51,18.43 181.09,18.43 179.09,16.43 176.85,16.43 174.17,13.75 140.92,13.75 138.68,15.99 128.24,15.99 126.65,14.4 117.88,14.4 116.24,16.04 103.44,16.04 103,16.49 94.93,16.49 94.48,16.04 69.61,16.04 68.52,14.96 56.19,14.96 v4(55.88,15.27)
  BOTTOM w0.102: PQ202.5 44.65,34.65 v1(44.05,34.06)
AC_PRESENT: length 29.2
  TOP w0.102: UE5.A54 181.22,59.86 181.35,59.72 v1(181.35,59.52) ; RH12.2 RH137.2 167.25,47.13 167.73,46.65 175.27,46.65 v2(176.43,47.81) 178.54,47.81 179.18,48.45 181.12,48.45 v3(181.43,48.76)
  GND1 w0.102: v4(181.62,49.17) 181.44,48.99 181.44,48.77 v3(181.43,48.76)
  IN4 w0.071: v4(181.62,49.17) 181.23,49.56 181.23,51.19 181.46,51.42 181.46,55.05 181.91,55.5 181.91,56.56 182.02,56.67 182.02,57.19 182.35,57.52 182.35,58.53 v1(181.35,59.52)
AC_PRESENT_R: length 28.3
  TOP w0.102: v2(166.02,46.45) 166.34,46.77 RH137.1 165.61,47.46 v1(165.6,47.44)
  IN2 w0.102: v1(146.85,55.3) 147.07,55.3 147.29,55.08 147.29,52.18 147.51,51.96 147.51,51.16 147.7,50.97 148.45,50.97 148.71,50.71 150.27,50.71 150.81,51.25 154.21,51.25 154.21,51.25 157.86,51.25 161.53,47.58 163.8,47.58 164.48,48.26 164.88,48.26 165.11,48.03 165.11,47.94 v1(165.6,47.44)
  BOTTOM w0.076: UCPU1.AJ8 146.85,56.24 v1(146.85,55.3)
ACAV_IN: length 218.4
  TOP w0.102: v1(187.5,59.52) 187.1,59.91 186.27,59.91 186.22,59.97 UE5.A64 ; v3(187.02,74.58) 187.02,74.72 R268.1 v2(186.48,76.31)
  TOP w0.254: v1(45.22,28.08) 45.22,28.51 PR213.1
  GND1 w0.102: v4(187.53,74.65) 187.1,74.65 v3(187.02,74.58)
  IN1 w0.071: v4(56.63,15.56) 56.33,15.86 55.08,15.86 52.16,18.78 52.16,26.54 51.45,27.26 46.04,27.26 v1(45.22,28.08)
  IN3 w0.086: v4(187.53,74.65) 187.61,74.57 187.61,60.29 187.42,60.09 187.42,59.6 v1(187.5,59.52) 187.5,59.49 188.83,58.15 188.83,57.9 189.16,57.57 189.16,54.66 188.44,53.94 188.44,53.36 189.68,52.12 189.68,49.14 189.23,48.69 189.23,42.83 185.86,39.46 185.86,30.18 185.16,29.48 185.16,20.63 183.34,18.81 180.92,18.81 178.91,16.8 176.68,16.8 174,14.12 141.08,14.12 138.84,16.37 128.08,16.37 126.49,14.78 118.04,14.78 116.4,16.42 103.6,16.42 103.15,16.86 94.77,16.86 94.33,16.42 69.45,16.42 68.37,15.34 56.86,15.34 v4(56.63,15.56)
ACAV_IN_NB: length 8.9
  TOP w0.102: v1(185.58,69.65) 185.46,69.76 185.46,70.34 UE5.B20 ; v2(184.56,75.75) 185.05,75.26 R268.2 v3(186.28,74.55)
  GND1 w0.102: v3(186.28,74.55) 186.41,74.55 v4(186.61,74.74)
  IN3 w0.086: v4(186.61,74.74) 186.61,70.92 185.58,69.89 v1(185.58,69.65)
ALS_INT#: length 66.4
  TOP w0.102: v1(178.54,63.46) 178.54,63.41 178.37,63.24 UE5.B48 ; v1(198.95,14.65) 198.73,14.43 198.24,14.43 R3.2 ; v1(191.62,19.86) v2(191.62,20.46)
  IN1 w0.071: v1(191.62,19.86) 191.66,19.89 191.66,25.49 188.38,28.77 v4(188.04,28.77)
  IN2 w0.086: v4(188.04,28.77) 187.51,29.3 187.51,35.17 186.27,36.41 186.27,37.57 185.19,38.64 184.03,38.64 180.48,42.19 180.48,46.76 179.46,47.79 179.46,48.97 179.72,49.23 179.72,49.72 178.66,50.78 178.66,53.6 177.98,54.27 177.98,57.83 177.29,58.53 177.29,59.17 178.6,60.49 178.6,63.4 v1(178.54,63.46)
  IN3 w0.086: v1(198.95,14.65) 198.95,17.9 197.95,18.9 194.67,18.9 193.72,19.86 v1(191.62,19.86)
  BOTTOM w0.102: JIO1.37 199.9,15.05 199.5,14.65 v1(198.95,14.65)
ALS_SMLCLK: length 60.5
  TOP w0.102: RH453.2 RE87.1 175.87,54.59 v3(176.66,53.81) 176.68,53.82 QH6.1
  GND1 w0.102: v4(177,53.43) 177,53.45 176.66,53.79 v3(176.66,53.81)
  IN2 w0.086: v4(177,53.43) 177,53.43 177.51,52.92 177.51,49.78 177.53,49.76 177.53,49.12 177.26,48.85 177.26,46.97 176.81,46.52 176.81,43.92 177.08,43.65 178.83,43.65 179.73,42.75 179.73,42.39 184.02,38.1 184.83,38.1 185.77,37.17 185.77,36.36 187.05,35.08 187.05,26.58 185.08,24.61 185.08,19.98 185.71,19.35 v4(185.98,19.35)
  IN3 w0.086: v1(197.88,17.48) 196.65,18.72 194.59,18.72 193.92,19.39 190.76,19.39 189.59,18.22 186.28,18.22 185.98,18.51 v4(185.98,19.35)
  BOTTOM w0.102: JIO1.40 199,18 198.85,17.85 198.25,17.85 v1(197.88,17.48)
ALS_SMLDATA: length 68.1
  TOP w0.102: v2(180.7,53.17) 180.5,53.37 v3(180.19,53.37) 180.19,53.86 RH454.2 178.66,54.64 178.4,54.9 QH6.4 178.4,56.5 RE88.1
  GND1 w0.102: v3(180.19,53.37) 180.88,53.37 v4(180.92,53.41)
  IN2 w0.086: v4(180.92,53.41) 180.92,53.1 181.38,52.63 181.38,51.88 184.21,49.05 185.46,49.05 187.12,47.39 187.12,45.56 189.1,43.59 192.14,43.59 193.15,42.57 193.15,34.96 194.66,33.45 194.66,26.95 193.97,26.26 193.97,21.48 193.74,21.26 193.74,15.93 192.16,14.35 189.58,14.35 v1(189.13,14.79)
  BOTTOM w0.102: JIO1.43 198.1,14.71 197.93,14.55 194.71,14.55 194.22,14.06 192.14,14.06 191.02,15.17 189.51,15.17 v1(189.13,14.79)
ALW_PWRGD_3V_5V: length 245.6
  TOP w0.102: v2(59.72,62.11) 59.71,62.1 v1(59.71,60.76) ; UE5.A1 187.7,61.99 187.56,61.85 187.56,61.54 v1(187.24,61.22)
  TOP w0.254: PR312.1 59.74,60.73 v1(59.71,60.76)
  IN1 w0.071: v1(59.71,60.76) 58.84,60.76 55.49,57.41 55.49,55.6 53.81,53.93 53.81,45.64 52.71,44.53 52.71,43.5 51.88,42.67 48.51,42.67 47.31,41.47 45.81,41.47 43.3,38.96 43.3,27.55 43.53,27.32 43.53,25.13 44.42,24.23 46.51,24.23 48.05,22.7 49.19,22.7 50.04,21.85 50.04,20.41 55.54,14.91 56.53,14.91 57.43,15.81 v4(57.43,16.07)
  IN3 w0.086: v4(57.43,16.07) 57.6,15.9 68.13,15.9 69.22,16.98 94.09,16.98 94.54,17.43 103.39,17.43 103.83,16.98 116.63,16.98 118.27,15.34 126.23,15.34 127.82,16.93 139.11,16.93 141.33,14.72 173.79,14.72 176.47,17.4 178.71,17.4 181.42,20.11 183.8,20.11 184.6,20.91 184.6,34.48 185.3,35.18 185.3,35.91 184.61,36.6 184.61,38.46 185.22,39.08 185.22,43.7 187.02,45.51 187.02,53.37 188.26,54.6 188.26,57.89 188.01,58.14 187.31,58.14 186.33,59.13 186.33,60.31 v1(187.24,61.22)
ALWON: length 184.2
  TOP w0.102: v1(184.09,59.55) 184.09,59.65 184.22,59.78 UE5.A60 ; v2(55.25,59.74) 54.84,59.32 v7(54.83,59.32)
  IN1 w0.071: v7(54.83,59.32) 54.83,65.34 54.04,66.13 54.04,67.65 54.15,67.76 54.15,68.62 53.83,68.93 52.46,68.93 50.21,71.18 v1(50.21,72.23)
  IN2 w0.086: v4(179.6,77.73) 179.18,78.14 174,78.14 173.45,77.6 168.43,77.6 165.7,80.33 100.4,80.33 99.02,78.95 86.69,78.95 84.3,76.57 77.57,76.57 76.05,78.08 71.57,78.08 70.67,78.98 59.6,78.98 58.86,79.72 50.26,79.72 v1(49.15,78.61)
  IN3 w0.086: v4(179.6,77.73) 182.14,75.19 185.21,75.19 185.39,75.01 185.39,74.07 186.02,73.44 186.02,71.99 184.92,70.89 184.92,70.61 184.21,69.9 184.21,68.76 184.21,68.76 184.21,68.61 184.57,68.24 184.57,63.72 185.05,63.25 185.05,60.51 v1(184.09,59.55)
  BOTTOM w0.102: v1(49.15,78.61) 49.98,77.78 49.98,74.42 50.21,74.19 v1(50.21,72.23)
  BOTTOM w0.254: v7(54.83,59.32) 55.33,58.83 PR314.1
AUD_HP_NB_SENSE: length 233.6
  TOP w0.102: v1(21.58,37.77) 21.68,37.67 v2(21.68,37.26) RA29.2 ; v1(186.43,61.9) 186.76,62.24 187.07,62.24 UE5.B2
  IN1 w0.071: v4(36.58,18.68) 36.58,21.81 v4(36.58,21.81)
  IN3 w0.086: v1(21.58,37.77) 22.01,37.33 33.75,37.33 36.45,34.64 36.45,27.56 35.91,27.03 35.91,24.65 36.58,23.99 v4(36.58,21.81) ; v4(36.58,18.68) 42.26,18.68 45.45,15.49 48.42,15.49 49.69,16.76 68.7,16.76 69.11,17.17 94.01,17.17 94.46,17.62 103.47,17.62 103.91,17.17 116.71,17.17 118.35,15.53 126.15,15.53 127.75,17.12 139.19,17.12 141.4,14.91 173.71,14.91 176.39,17.59 178.63,17.59 181.35,20.3 183.72,20.3 184.41,20.99 184.41,43.16 186.84,45.58 186.84,53.45 188.07,54.68 188.07,57.81 187.93,57.95 187.23,57.95 186.14,59.05 186.14,60.38 186.43,60.67 v1(186.43,61.9)
AUDIO_VREF: length 3.3
  TOP w0.102: v2(22.85,23.4) 22.85,23.54 23.69,24.38 24.66,24.38 25.37,23.67 CA87.1
AUX_EN_WOWL: length 203
  TOP w0.102: v1(42.68,24.27) 42.92,24.51 v2(42.92,27.69) 42.46,28.15 42.46,35.7 43.38,36.61 43.38,37.49 D116.3 ; v1(177.94,61.22) 178.37,61.65 178.74,61.65 178.97,61.43 178.97,61.14 UE5.B53
  IN3 w0.086: v1(42.68,24.27) 43.38,24.27 45.38,22.27 49.71,22.27 51.1,20.89 69.81,20.89 71.01,19.69 73.7,19.69 74.64,20.63 88.24,20.63 89.22,19.64 92.98,19.64 93.4,20.06 102.58,20.06 103.72,21.2 108.84,21.2 110.27,19.76 117.61,19.76 119.24,18.13 125.05,18.13 126.49,19.57 140.84,19.57 141.72,18.7 171.03,18.7 171.63,19.3 174.35,19.3 175.09,20.04 177.63,20.04 181.56,23.97 181.56,38.79 180.11,40.24 180.11,44.52 178.41,46.22 178.41,50.05 176.65,51.81 176.65,58.97 177.57,59.89 177.57,60.85 v1(177.94,61.22)
B+: length 259.6
  TOP w0.406: R1381.1 169.21,75.18 169.14,75.12 Q361.4
  TOP w0.508: R1381.1 169.21,76.07 168.75,76.53 168.75,77.99 169.52,78.76 v1(169.56,78.76) 170.2,78.76 C1275.1 ; v1(160.11,19.64) 159.53,19.06 C1274.1 ; v1(187.39,44.61) 188.72,44.61 C613.1 R535.1
  TOP w1.524: 187.5,47.61 187.53,47.65 191.04,47.65 195.29,51.89 195.29,60.12 195.33,60.12
  GND1 w0.508: v4(194.43,62.23) 194.58,62.07 v3(194.58,61.57)
  IN1 w0.508: 160.1,16 160.1,19.63 v1(160.11,19.64)
  IN1 w1.016: 53.52,70.01 55.91,70.01 56.55,69.38 60.18,69.38 60.39,69.59 65.7,69.59 70.22,65.07 70.22,58.12 71.24,57.1 71.24,56.61
  IN1 w3.048: 170.36,16.02 170.34,16 133.77,16 131.63,18.14 127.65,18.14 127.27,17.76 113.37,17.76 112.98,18.14 109.88,18.14 109.14,18 109.14,17.94 108.71,17.76 105.24,17.76 104.4,18.6 94.1,18.6 93.26,17.76 77.23,17.76 73.7,21.29 73.7,37.87 ; 181.92,37.41 181.92,22.8 179.64,20.52 179.64,20.52 176.89,17.76 175.96,17.76
  IN2 w0.508: v1(198.19,71.03) 198.19,71.07 194.52,74.74 194.52,76.3 193.26,77.56 189.52,77.56 189.24,77.27 182.27,77.27 180.21,79.33 178.27,79.33 177.37,80.23 171.04,80.23 v1(169.56,78.76)
  IN2 w1.016: 51.53,70.07 51.52,70.06 49.69,70.06 49.28,69.66 48.52,69.66 46.31,67.45 37.36,67.45
  IN3 w0.508: v1(198.19,71.03) 198.19,70.65 197.49,69.95 196.12,69.95 193.67,67.5 193.67,62.99 v4(194.43,62.23)
  vias: v1(36.14,66.8) v1(36.8,66.8) v1(69.27,53.98) v1(69.63,55.13) v1(69.63,54.56) v1(69.84,53.98) v1(70.21,55.7) v1(70.2,55.13) v1(70.2,54.56) v1(70.41,53.98) v1(70.78,55.7) v1(70.77,55.13) v1(70.77,54.56) v1(70.98,53.98) v1(71.34,55.13) v1(71.34,54.56) v1(71.35,55.7) v1(185.25,46.85) v1(185.3,47.53) v1(185.73,47.18) v1(185.77,47.86) v1(186.2,47.5) v1(186.19,46.84) v4(52.25,70.47) v4(52.72,70.2) v6(80.54,45.06) v7(66.52,41.55) v7(66.47,40.45) v7(66.82,41.01) v7(66.77,39.9) v7(66.86,42.11) v7(67.11,40.45) v7(67.15,41.55) v7(67.41,39.9) v7(67.49,42.11) v7(67.46,41.01) v7(67.74,40.45) v7(67.79,41.55) v7(68.13,42.11) v7(68.09,41.01) v7(68.06,39.92) v7(68.42,41.55) v7(68.38,40.45) v7(68.73,41.01) v7(68.76,42.11) v7(68.75,39.93) v7(91.76,52.94) v7(91.76,52.3) v7(91.76,51.67) v7(91.76,51.03) v7(91.76,50.4) v7(92.4,52.94) v7(92.4,52.3) v7(92.4,51.67) v7(92.4,51.03) v7(92.4,50.4) v7(93.03,52.94) v7(93.03,52.3) v7(93.03,51.67) v7(93.03,51.03) v7(93.03,50.4)
B+_1.05V:
  vias: v2(198.05,64.74) v7(197.36,64.15) v7(198,64.15) v7(198.63,64.15)
B-RAMP: length 4.8
  TOP w0.254: v1(75.28,64.53) 75.48,64.53 v2(75.77,64.23) 76.42,63.59 PR707.1
  BOTTOM w0.203: PU700.11 76.28,63.97 75.72,64.53 v1(75.28,64.53)
  BOTTOM w0.254: PR702.2 75.02,64.72 75.21,64.53 v1(75.28,64.53)
BAT1_LED#: length 200.5
  TOP w0.102: UE5.B1 186.94,61.74 186.83,61.63 186.83,61.06 v1(187.24,60.66) 187.53,60.66 187.95,61.08 188.55,61.08 188.66,60.97 188.66,59.57 v2(188.42,59.33)
  IN3 w0.086: v4(43.77,16.38) 44.84,15.3 48.5,15.3 49.77,16.57 56.43,16.57 57.29,15.71 68.21,15.71 69.3,16.79 94.17,16.79 94.62,17.24 103.31,17.24 103.76,16.79 116.55,16.79 118.19,15.15 126.31,15.15 127.9,16.74 139.03,16.74 141.25,14.53 173.87,14.53 176.55,17.21 178.79,17.21 180.79,19.21 183.21,19.21 184.79,20.79 184.79,29.64 185.49,30.33 185.49,39.62 187.78,41.92 187.78,46.61 188.2,47.03 188.2,50.42 187.67,50.95 187.67,53.75 188.45,54.53 188.45,57.97 188.07,58.34 187.38,58.34 186.54,59.18 186.54,59.96 v1(187.24,60.66)
  GND3 w0.102: v4(43.77,16.38) 43.57,16.58 v5(43.36,16.58)
  BOTTOM w0.102: v5(43.36,16.58) 42.92,17.02 JKB1.10
BAT2_LED#: length 187.8
  TOP w0.102: v1(181.06,59.04) 181.5,59.04 181.79,59.33 181.79,59.7 181.72,59.77 UE5.A55 ; v1(43.42,21.14) v2(44,21.14)
  IN3 w0.086: v1(43.42,21.14) 44.56,21.14 45.32,21.89 47.67,21.89 48.75,20.81 49.98,20.81 52.52,18.27 67.98,18.27 68.38,18.67 93.39,18.67 93.84,19.12 104.09,19.12 104.54,18.67 117.33,18.67 118.97,17.03 125.53,17.03 127.12,18.62 140.08,18.62 142.27,16.43 171.1,16.43 173,18.33 174.76,18.33 175.52,19.1 178.02,19.1 182.71,23.79 182.71,44.01 181.35,45.38 181.35,48.19 181.99,48.84 181.99,49.89 181.44,50.44 181.44,52.45 181.16,52.73 180.65,52.73 180.29,53.09 180.29,54.54 181.06,55.31 181.06,57.31 181.31,57.57 181.31,58.79 v1(181.06,59.04)
  BOTTOM w0.102: JKB1.9 v1(43.42,21.14)
BAT_LED#_LV1: length 15.3
  TOP w0.102: v2(13.22,8.08) R910.2 v1(12.23,7.29) ; v1(3.51,15.6) LED12.1
  IN1 w0.071: v1(12.23,7.29) 12.23,7.96 4.6,15.6 v1(3.51,15.6)
BAT_LED#_LV2: length 5.2
  TOP w0.102: LED14.1 4.02,12 v2(4.8,11.23) 5.74,10.28 R911.2
BAT_LED#_LV3: length 3.4
  TOP w0.102: R912.2 4.66,8.13 v2(4.39,8.4) LED10.1
BAT_LED#_LV4: length 4.8
  TOP w0.102: R913.2 5.24,6.67 5.24,5.63 v2(4.64,5.03) 4.41,4.8 LED11.1
BAT_LED#_LV5: length 6.4
  TOP w0.102: LED13.1 v2(4.77,3.47) 5.74,4.45 R916.2
BATBTN#: length 243
  TOP w0.102: v1(186.94,59.5) 185.96,59.5 185.72,59.74 UE5.A63 ; SW3.1 SW3.2 v1(4.91,19.43) ; RPE5.4 189.46,54.95 189,55.41 v3(188.8,55.41) 188.64,55.41 v6(188.26,55.03)
  GND1 w0.102: v4(188.8,54.98) v3(188.8,55.41)
  IN3 w0.086: v1(186.94,59.5) 186.94,59.25 187.14,59.05 187.67,59.05 188.63,58.08 188.63,55.15 v4(188.8,54.98) 188.8,54.57 188.23,54 188.23,53.3 189.46,52.07 189.46,49.18 189.04,48.76 189.04,42.91 185.67,39.54 185.67,30.26 184.98,29.56 184.98,20.71 183.29,19.02 180.87,19.02 178.87,17.02 176.63,17.02 173.95,14.34 141.17,14.34 138.96,16.56 128.01,16.56 126.41,14.96 118.12,14.96 116.47,16.61 103.68,16.61 103.23,17.05 94.69,17.05 94.25,16.61 69.37,16.61 68.29,15.52 57.21,15.52 56.35,16.38 49.85,16.38 48.58,15.11 43.84,15.11 43.11,15.85 43.11,17.56 42.18,18.49 37.31,18.49 37.1,18.28 34.9,18.28 33.67,19.52 32.56,19.52 31.4,18.36 16.86,18.36 15.64,19.58 5.06,19.58 v1(4.91,19.43)
  BOTTOM w0.102: C2983.1 v1(4.91,19.43)
BATDRV#: length 28.3
  TOP w0.102: v1(56.15,28.98) 56.15,28.24 v2(56.56,27.83)
  TOP w0.254: PR220.2 55.47,29.67 v1(56.15,28.98)
  IN3 w0.254: v1(71.79,34.96) 71.29,34.46 71.29,32.09 67.96,28.75 56.38,28.75 v1(56.15,28.98)
  BOTTOM w0.254: v1(71.79,34.96) 73.05,34.96 73.86,35.77 PQ204.4
BATT_LED#_LV1: length 32.1
  TOP w0.102: RP13.9 11.3,8.09 R910.1 11.32,7.6 v1(11.65,7.27) 11.65,6.77 v2(11.61,6.73)
  IN4 w0.071: v4(34.57,13.79) 34.31,13.53 31.78,13.53 30.84,14.47 24.17,14.47 23.23,13.53 17.84,13.53 16.72,12.4 16.72,9.15 15.09,7.52 13.03,7.52 12.42,6.91 12.02,6.91 v1(11.65,7.27)
  GND3 w0.102: v4(34.57,13.79) v5(34.57,14.18)
BATT_LED#_LV2: length 35.1
  TOP w0.102: RP13.1 v1(7.32,8.74) 7,8.74 R911.1 6.66,9.89 v2(6.46,10.09)
  IN4 w0.071: v1(7.32,8.74) 7.75,8.31 14.9,8.31 16.03,9.44 16.03,12.69 17.55,14.22 22.94,14.22 23.89,15.16 31.12,15.16 31.24,15.29 33.17,15.29 v4(33.92,14.53)
  GND3 w0.102: v4(33.92,14.53) v5(33.92,14.18)
BATT_LED#_LV3: length 35.9
  TOP w0.102: v2(4.39,9.69) 5.49,8.58 6.22,8.58 6.66,8.14 R912.1 6.69,8.09 v1(7.33,8.09) RP13.2
  IN4 w0.071: v1(7.33,8.09) 14.93,8.09 16.2,9.37 16.2,12.62 17.63,14.05 23.01,14.05 23.96,14.99 31.19,14.99 31.29,15.1 32.72,15.1 v4(33.27,14.54)
  GND3 w0.102: v4(33.27,14.54) v5(33.27,14.18)
BATT_LED#_LV4: length 35
  TOP w0.102: v2(4.63,7.07) 5.2,7.64 6.19,7.64 6.65,7.18 R913.1 6.93,7.44 v1(7.33,7.44) RP13.3
  IN4 w0.071: v1(7.33,7.44) 7.76,7.88 14.95,7.88 16.37,9.3 16.37,12.55 17.7,13.87 23.09,13.87 24.03,14.82 31.26,14.82 31.36,14.92 32.24,14.92 v4(32.63,14.53)
  GND3 w0.102: v4(32.63,14.53) v5(32.63,14.18)
BATT_LED#_LV5: length 34.3
  TOP w0.102: v2(6.66,5.24) R916.1 7.23,6.79 v1(7.32,6.79) RP13.4
  IN4 w0.071: v1(7.32,6.79) 8.22,7.69 15.02,7.69 16.55,9.22 16.55,12.47 17.77,13.7 23.16,13.7 24.1,14.64 31.5,14.64 v1(31.6,14.54)
  BOTTOM w0.102: UE4.1 30.96,15.21 30.83,15.08 30.83,14.71 30.99,14.54 v1(31.6,14.54)
BATT_PRS: length 5.1
  TOP w0.102: PRP100.8 66.38,24.98 v3(65.97,25.38) 65.94,25.41 65.94,26.22 65.81,26.36 PD100.3 v2(63.77,26.36)
  GND1 w0.102: v4(65.6,25.62) 65.84,25.38 v3(65.97,25.38)
  GND3 w0.102: v5(65.6,26.14) v4(65.6,25.62)
BATT_VREF: length 9.5
  TOP w0.102: v2(28.98,66.04) PR460.2
  TOP w0.254: PC324.2 25.89,66.04 PR458.1 PR460.2 27.91,65.62 27.34,65.05 PU404.6 27.34,62.79 26.69,62.14 PU404.2
BBS_BIT: length 1.6
  TOP w0.089: T284.1 147.47,65.89 147.08,66.28 v1(147.08,66.57)
  BOTTOM w0.076: UCPU1.L8 147.02,66.47 147.08,66.53 v1(147.08,66.57)
BC_CLK_ECE1117: length 200.4
  TOP w0.102: v1(184.43,72.12) 184.72,71.84 UE5.A20 ; v1(44,18.28) v2(44,19)
  IN3 w0.086: v1(184.43,72.12) 184.43,70.74 183.83,70.14 183.83,68.45 184.2,68.08 184.2,63.62 183.87,63.29 183.87,60.14 183.29,59.56 183.29,55.78 182.72,55.21 182.72,52.61 183.29,52.04 183.29,49.1 182.72,48.53 182.72,46.81 183.92,45.62 183.92,44.3 183.28,43.67 183.28,23.57 178.25,18.53 176.01,18.53 173.32,15.85 141.79,15.85 139.58,18.06 127.36,18.06 125.76,16.47 118.74,16.47 117.1,18.11 104.3,18.11 103.86,18.56 94.07,18.56 93.62,18.11 68.65,18.11 68.25,17.71 48.71,17.71 48.44,17.45 45.52,17.45 44.65,18.32 44.04,18.32 v1(44,18.28)
  BOTTOM w0.102: JKB1.8 43.92,18.37 v1(44,18.28)
BC_DAT_ECE1117: length 208.8
  TOP w0.102: v3(183.84,54.25) 183.84,54.4 v2(184.23,54.8) 184.81,55.38 188.12,55.38 188.47,55.73 190.39,55.73 190.96,55.16 RPE5.1 ; v1(184.79,69.1) 185.17,69.48 185.17,69.83 184.97,70.03 184.97,70.34 UE5.B21
  GND1 w0.102: v3(183.84,54.25) 183.72,54.25 v4(183.48,54.01)
  IN3 w0.086: v4(45.75,16.37) 47.96,16.37 48.9,17.32 68.43,17.32 68.84,17.73 93.78,17.73 94.23,18.18 103.7,18.18 104.15,17.73 116.94,17.73 118.58,16.09 125.92,16.09 127.51,17.68 139.42,17.68 141.64,15.47 173.48,15.47 176.16,18.15 178.4,18.15 181.11,20.86 183.49,20.86 183.85,21.22 183.85,43.44 184.48,44.07 184.48,48.61 183.86,49.24 183.86,53.64 v4(183.48,54.01) 183.86,54.39 183.86,58.09 185.43,59.66 185.43,63.42 184.95,63.9 184.95,68.95 v1(184.79,69.1)
  GND3 w0.102: v4(45.75,16.37) v5(45.37,16.37)
  BOTTOM w0.102: v5(45.37,16.37) 44.42,17.32 JKB1.7
BC_INT#_ECE1117: length 204.6
  TOP w0.102: UE5.A19 185.22,71.5 185.64,71.92 v1(185.64,72.14) 186.42,72.14 186.83,72.55 186.83,74.15 186.95,74.27 187.15,74.27 187.52,74.63 v2(187.52,74.94)
  IN3 w0.086: v4(44.44,17.97) 45.18,17.23 48.49,17.23 48.79,17.52 68.36,17.52 68.76,17.92 93.7,17.92 94.15,18.37 103.78,18.37 104.22,17.92 117.02,17.92 118.66,16.28 125.84,16.28 127.43,17.87 139.5,17.87 141.72,15.66 173.4,15.66 176.08,18.34 178.32,18.34 183.47,23.49 183.47,43.59 184.1,44.23 184.1,48.46 183.48,49.08 183.48,52.12 182.91,52.69 182.91,55.13 183.48,55.7 183.48,59.49 184.86,60.87 184.86,63.17 184.39,63.65 184.39,68.16 184.02,68.53 184.02,70.06 184.62,70.66 184.62,71.12 v1(185.64,72.14)
  GND3 w0.102: v5(44.91,18.37) 44.9,18.37 44.51,17.97 v4(44.44,17.97)
  BOTTOM w0.102: JKB1.6 44.92,18.39 v5(44.91,18.37)
BEEP: length 222.4
  TOP w0.102: v1(183.27,69.7) 183.27,69.71 183.47,69.91 UE5.B24 ; v1(20.35,19.06) v2(20.35,18.51)
  IN3 w0.086: v1(183.27,69.7) 183.64,69.32 183.64,68.37 184.01,68.01 184.01,63.7 183.68,63.37 183.68,60.22 183.1,59.64 183.1,55.86 182.56,55.32 181.82,55.32 181.48,54.97 181.48,52.94 181.8,52.61 182.26,52.61 182.62,52.25 182.62,48.7 182.52,48.59 182.52,46.72 183.73,45.51 183.73,44.38 183.1,43.75 183.1,23.64 178.17,18.72 175.93,18.72 173.25,16.03 141.96,16.03 139.75,18.25 127.28,18.25 125.69,16.66 118.82,16.66 117.18,18.3 104.38,18.3 103.93,18.74 93.99,18.74 93.55,18.3 68.57,18.3 68.17,17.9 48.58,17.9 48.33,17.65 45.63,17.65 44.63,18.66 42.81,18.66 42.41,19.05 37.3,19.05 35.64,20.72 32.9,20.72 30.78,18.59 20.82,18.59 v1(20.35,19.06)
  BOTTOM w0.102: v1(20.35,19.06) 20.3,19.11 RA24.1
BIA_PWM_EC: length 52.4
  TOP w0.102: v1(182.48,68.75) 182.86,69.13 182.86,69.88 182.97,69.98 182.97,70.34 UE5.B25 ; D73.3 197.46,29.18 v1(197.58,29.06) 197.58,29.37 v2(197.92,29.71)
  IN2 w0.086: v1(182.48,68.75) 182.96,68.26 182.96,65.13 183.55,64.54 183.55,55.74 183.84,55.45 183.84,51.32 184.77,50.38 186.07,50.38 189.52,46.93 191.71,46.93 193.23,45.41 194.86,45.41 195.93,44.35 195.93,37.09 196.79,36.22 196.79,29.84 v1(197.58,29.06)
BOARD_ID: length 6.8
  TOP w0.102: v1(189.13,65.63) 189.36,65.86 CE54.1 RE79.1 ; v1(185.91,66.97) 186.64,66.24 187,66.24 UE5.B10
  IN1 w0.071: v1(189.13,65.63) 188.68,66.08 188.55,66.08 188,66.63 186.25,66.63 v1(185.91,66.97)
BOOT_1.35V:
  vias: v2(76.9,48.18)
BQ24777_REGN: length 12.8
  TOP w0.203: PU200.24 50.49,32.88 51.27,33.67 PC205.1 52.04,34.05 52.09,34 PR212.1 PR223.1
  TOP w0.254: PR223.1 52.39,34.86 52.11,35.14 52.11,36.28 52.35,36.52 v2(53.79,36.52) 54.12,36.52 54.42,36.22 54.42,33.46 54.22,33.26 PR228.2
BST_1.05V: length 3.2
  TOP w0.102: v1(202.34,65.36) v2(202.34,66.01)
  TOP w0.254: PR503.1 201.96,64.97 v1(202.34,65.36)
  BOTTOM w0.102: PU500.6 202.15,64.18
  BOTTOM w0.254: v1(202.34,65.36) 202.53,65.17 202.53,64.34 202.37,64.18 202.15,64.18
BST_1.35V: length 1.5
  BOTTOM w0.102: PC604.1 v2(77.56,53.53)
BST_3V:
  vias: v2(59.86,57.48)
BST_5V:
  vias: v2(59.94,52.29)
BT_CS_NOTICE: length 152.2
  TOP w0.102: R1209.2 47.59,42.56 v1(47.17,42.13) 46.66,41.63 v2(45.8,41.63) 44.85,41.63 44.45,42.02 41.53,42.02 40.86,42.7 R1208.2
  IN3 w0.086: v1(47.17,42.13) 47,42.3 47,49.46 48.29,50.76 51.62,50.76 53.55,52.68 53.55,55.1 53,55.65 53,56.33 50.48,58.85 50.48,62.31 50.31,62.47 50.31,66.57 49.92,66.96 49.92,68.79 50.75,69.62 65.63,69.62 67.39,71.38 76.22,71.38 76.8,71.95 79.1,71.95 80.82,70.24 99.03,70.24 101.92,67.35 105.64,67.35 107.57,69.28 109.79,69.28 109.91,69.39 110.07,69.39
  IN3 w0.089: 110.07,69.39 112.83,69.39 113.39,68.84 115.41,68.84 115.7,69.13 137.76,69.13 139.22,67.67 140.33,67.67 143.91,64.09 143.91,59.89 144.49,59.31 146.02,59.31 146.93,58.39 148.35,58.39 v1(148.77,58.82)
  BOTTOM w0.076: UCPU1.AD5 148.97,59.01 v1(148.77,58.82)
BT_RADIO_DIS#: length 39.1
  TOP w0.102: v1(45.08,42.19) 45.43,42.54 DZ2.1 ; RE13.2 38.99,13.65 v2(36.81,13.65) 36.59,13.65 v3(35.87,14.38)
  GND1 w0.102: v3(35.87,14.38) 35.87,13.82 v4(35.87,13.81)
  IN1 w0.071: v1(45.08,42.19) 45.08,42.02 43.78,40.73 42.53,40.73 42,40.2 42,38.1 42.78,37.32 42.78,27.34 42.99,27.13 42.99,26.25 42,25.26 42,22.77 35.87,16.64 v4(35.87,13.81)
  GND3 w0.102: v4(35.87,13.81) v5(35.87,14.18)
BT_RADIO_DIS#_R: length 3
  TOP w0.102: v2(45.28,45.2) 45.43,45.04 v1(45.43,44.67) DZ2.2
  BOTTOM w0.102: JNGFF1.46 45,46.32 45,45.1 v1(45.43,44.67)
CAB_DET_SINK: length 10.6
  TOP w0.102: v3(16.86,66.19) RV8.2 v2(17.75,65.11)
  GND1 w0.102: v3(16.86,66.19) v4(16.86,65.65)
  IN4 w0.071: JMDP.4 16.63,59.91 16.63,65.42 v4(16.86,65.65)
CAM_CBL_DET#: length 179.4
  TOP w0.089: v1(149.92,55.7) 149.92,55.69 151.51,54.1 152.42,54.1 152.86,54.54 v2(153.22,54.54) 153.54,54.54
  TOP w0.102: v1(55.07,68.69) 55.07,69.1 54.63,69.54 54.63,71.33 54.4,71.56 54.4,77.5 54.88,77.99 55.55,77.99 v1(56.13,78.56) ; 153.54,54.54 154.02,55.03 154.02,55.42 154.53,55.93 157.12,55.93 157.34,56.15 157.34,56.44 RH3541.1
  IN2 w0.086: 155.46,55.68 156.46,55.68 156.99,56.21 161.51,56.21 162.2,56.9 165.09,56.9 165.62,56.37 v4(169.17,56.37) ; v1(144.56,77.83) 142.63,79.75 100.82,79.75 99.34,78.27 98.78,78.27 97.22,76.72 94.68,76.72 93.03,75.07 75.37,75.07 73.4,77.05 69.52,77.05 68.85,76.38 60.79,76.38 60.08,77.09 57.59,77.09 v1(56.13,78.56)
  IN2 w0.089: 155.46,55.68 155.46,55.68 153.93,55.68 153.44,56.17 152.46,56.17 152.29,56.33 151.88,56.33 151.75,56.47 151.2,56.47 150.98,56.25 150.48,56.25 149.93,55.7 v1(149.92,55.7)
  IN3 w0.086: v4(156.72,75.49) 156.72,75.42 157.61,74.53 157.61,72.52 160.6,69.53 161.5,69.53 162.83,68.2 162.83,66.69 163.48,66.04 163.91,66.04 165.65,64.3 165.65,60.58 166.18,60.04 168.68,60.04 168.89,59.84 168.89,57.16 169.17,56.88 v4(169.17,56.37)
  GND3 w0.102: v4(156.72,75.49) v5(156.72,75.91)
  BOTTOM w0.076: UCPU1.AK4 149.65,55.97 v1(149.92,55.7)
  BOTTOM w0.102: RH438.1 55.82,69.44 v1(55.07,68.69) ; v5(156.72,75.91) 156.72,76.89 153.7,79.91 146.64,79.91 v1(144.56,77.83)
CAM_CBL_DET#_R: length 4.1
  BOTTOM w0.102: JCAM.2 55.4,72.12 55.87,71.65 56.06,71.65 56.39,71.32 56.39,70.89 56.38,70.88 RH438.2 56.75,70.35 v2(57.4,69.71)
CFG0: length 53.4
  TOP w0.102: v1(79.28,68.44) v2(79.28,68.96) 79.28,70.79 78.29,71.78 77.71,71.78 75.94,73.55 74.76,73.55 73.42,74.9 73.42,76.22 JXDP.9
  IN4 w0.071: v1(109.2,60.33) 109.02,60.5 107.3,60.5 106.81,60.99 105.47,60.99 102.8,63.66 102.8,65.32 98.73,69.39 98.26,69.39 97.32,70.34 90.75,70.34 90.16,69.74 80.59,69.74 v1(79.28,68.44)
  BOTTOM w0.076: UCPU1.AC60 114.63,59.52 114.15,59.52 114.12,59.56 113.33,59.56 113.17,59.39 112.79,59.39 112.55,59.63 111.51,59.63 111.1,60.03 110.07,60.03
  BOTTOM w0.102: v1(109.2,60.33) 109.49,60.03 110.07,60.03
CFG1: length 53.8
  TOP w0.102: v1(77.41,68.51) 77.41,70.11 77.41,70.11 77.41,71.79 75.91,73.29 74.38,73.29 72.92,74.76 72.92,76.22 JXDP.11 ; v1(107.52,61.13) v2(107.13,60.74)
  IN4 w0.071: v1(77.41,68.51) 77.84,68.94 79.01,68.94 80.2,70.13 89.98,70.13 90.52,70.68 97.46,70.68 98.4,69.74 98.88,69.74 103.15,65.47 103.15,64.41 104.61,62.94 104.61,62.34 105.61,61.34 107.32,61.34 v1(107.52,61.13)
  BOTTOM w0.076: 110.07,60.4 110.18,60.4 110.36,60.22 111.17,60.22 111.6,59.8 112.62,59.8 112.85,59.56 113.1,59.56 113.39,59.85 UCPU1.AC62
  BOTTOM w0.102: 110.07,60.4 109.67,60.4 109.36,60.71 107.95,60.71 v1(107.52,61.13)
CFG2: length 55
  TOP w0.102: v2(107.99,61.71) 108.16,61.54 v1(108.16,61.18) ; v1(76.84,68.53) 77.21,68.89 77.21,71.7 75.92,72.99 73.08,72.99 71.86,74.21 71.86,74.87 71.91,74.92 JXDP.15
  IN4 w0.071: v1(108.16,61.18) 107.83,61.51 105.68,61.51 104.79,62.41 104.79,63.01 103.32,64.48 103.32,65.54 98.95,69.91 98.47,69.91 97.53,70.85 90.45,70.85 89.9,70.31 80.13,70.31 78.95,69.12 77.44,69.12 v1(76.84,68.53)
  BOTTOM w0.076: UCPU1.AC63 112.86,59.96 111.67,59.96 111.24,60.39 110.43,60.39 110.21,60.61 110.07,60.61
  BOTTOM w0.102: 110.07,60.61 109.75,60.61 109.45,60.91 108.43,60.91 v1(108.16,61.18)
CFG3: length 56.4
  TOP w0.076: v1(110.74,61.23) 110.11,60.6 110.07,60.6
  TOP w0.102: v1(76.74,70.24) 76.93,70.43 76.93,71.69 75.84,72.79 72.99,72.79 71.66,74.12 71.66,74.87 71.41,75.11 JXDP.17 71.41,78.29 R1198.2 ; T293.1 110.07,60.6
  IN4 w0.071: v1(110.74,61.23) 110.58,61.23 109.9,61.91 105.77,61.91 105.13,62.55 105.13,63.16 103.67,64.62 103.67,65.68 99.09,70.26 98.62,70.26 97.68,71.2 90.31,71.2 89.76,70.65 79.99,70.65 78.81,69.48 77.5,69.48 v1(76.74,70.24)
  BOTTOM w0.076: v1(110.74,61.23) 111.07,60.9 111.44,60.9 111.88,60.46 112.7,60.46 112.72,60.47 112.85,60.47 UCPU1.AA63
CFG4: length 59.1
  TOP w0.076: v1(114.63,60.22) v2(114.63,59.64)
  TOP w0.089: RC81.1 114.72,60.32 v1(114.63,60.22)
  TOP w0.102: JXDP.27 68.91,75.08 68.59,74.75 v1(68.59,74.74)
  IN4 w0.071: v1(114.63,60.22) 114.63,60.55 112.23,62.94 111.46,62.94 109.2,65.21 105.77,65.21 105.57,65.42 105.57,66.1 105.92,66.46 105.92,68.71 104.9,69.73 102.3,69.73 99.88,72.16 99.41,72.16 98.39,73.17 96.74,73.17 96.49,73.43 89.85,73.43 89,72.58 79.64,72.58 78.07,74.16 70.43,74.16 69.52,75.07 68.92,75.07 v1(68.59,74.74)
  BOTTOM w0.076: UCPU1.AA60 114.93,60.52 v1(114.63,60.22)
CFG5: length 59
  TOP w0.076: v2(112.64,60.63) 112.49,60.63 111.87,61.25 v1(111.86,61.25)
  TOP w0.102: JXDP.29 68.41,75.16 68.01,74.76 v1(68,74.76)
  IN4 w0.071: v1(111.86,61.25) 111.14,61.98 110.53,61.98 110.19,62.32 105.86,62.32 105.48,62.7 105.48,63.3 104.01,64.76 104.01,65.83 99.24,70.6 98.76,70.6 97.82,71.54 90.17,71.54 89.62,71 79.84,71 78.67,69.82 77.94,69.82 76.36,71.41 67.98,71.41 67.49,71.89 67.49,74.25 v1(68,74.76)
  BOTTOM w0.076: v1(111.86,61.25) 111.88,61.25 112.23,60.9 112.63,60.9 112.79,61.06 113.1,61.06 113.39,61.35 UCPU1.Y62
CFG6: length 57.3
  TOP w0.076: v1(113.98,61.72) 113.98,62.08 v2(114.27,62.37)
  TOP w0.102: JXDP.33 v1(67.41,74.76)
  IN4 w0.071: v1(113.98,61.72) 112.44,63.26 111.41,63.26 109.26,65.41 107.03,65.41 106.09,66.35 106.09,68.78 104.97,69.91 102.37,69.91 99.95,72.33 99.48,72.33 98.46,73.35 96.81,73.35 96.56,73.6 89.78,73.6 88.93,72.75 79.72,72.75 78.14,74.33 70.51,74.33 69.56,75.27 67.92,75.27 v1(67.41,74.76)
  BOTTOM w0.076: v1(113.98,61.72) 114.28,61.42 UCPU1.Y61
CFG7: length 60.2
  TOP w0.076: v1(111.32,61.25) v2(111.32,60.58)
  TOP w0.102: JXDP.35 66.92,76.22 66.92,72.43 v1(67.12,72.22)
  IN4 w0.071: v1(67.12,72.22) 67.12,71.93 67.82,71.23 76.29,71.23 77.87,69.65 78.74,69.65 79.92,70.82 89.69,70.82 90.24,71.37 97.75,71.37 98.69,70.43 99.16,70.43 103.84,65.75 103.84,64.69 105.31,63.23 105.31,62.62 105.82,62.11 110.1,62.11 110.47,61.74 110.83,61.74 v1(111.32,61.25)
  BOTTOM w0.076: UCPU1.Y60 114.63,61.02 114.15,61.02 114.12,61.06 113.33,61.06 113.17,60.89 112.85,60.89 112.68,60.72 111.85,60.72 v1(111.32,61.25)
CFG8: length 51
  TOP w0.102: JXDP.10 73.42,70.49 73.42,71.66 72.86,72.22 v1(72.7,72.22) ; v1(107.62,62.71) v2(107.62,63.25)
  IN4 w0.071: v1(72.7,72.22) 72.7,72.54 73.28,73.12 77.64,73.12 79.21,71.55 89.43,71.55 90.28,72.39 96.06,72.39 96.31,72.14 97.96,72.14 98.98,71.12 99.45,71.12 101.91,68.66 102.72,68.66 104.53,66.85 104.53,64.98 106.02,63.49 106.84,63.49 v1(107.62,62.71)
  BOTTOM w0.076: 110.47,61.62 110.49,61.64 113.17,61.64 UCPU1.V62
  BOTTOM w0.102: v1(107.62,62.71) 107.62,62.6 108.4,61.82 109.48,61.82 109.68,61.62 110.47,61.62
CFG9: length 52.2
  TOP w0.102: JXDP.12 72.92,70.49 72.92,71.47 v1(72.14,72.24) ; v1(108.89,62.7) v2(108.89,63.3)
  IN4 w0.071: v1(72.14,72.24) 73.2,73.29 77.71,73.29 79.29,71.72 89.36,71.72 90.21,72.56 96.13,72.56 96.38,72.31 98.03,72.31 99.05,71.29 99.52,71.29 101.99,68.83 102.8,68.83 104.7,66.92 104.7,65.05 106.08,63.68 107.91,63.68 v1(108.89,62.7)
  BOTTOM w0.076: 110.61,61.82 113.11,61.82 113.27,61.98 113.27,62.16 113.5,62.39 114.02,62.39 UCPU1.V61
  BOTTOM w0.102: v1(108.89,62.7) 109.77,61.82 110.61,61.82
CFG10: length 57.5
  TOP w0.076: v2(115.56,62.3) 115.21,62.3 114.63,61.72 v1(114.63,61.72)
  TOP w0.102: v1(71.25,74.73) 71.28,74.7 71.28,72.95 71.7,72.53 71.7,71.79 71.91,71.58 JXDP.16
  IN4 w0.071: v1(71.25,74.73) 71.67,75.14 74.3,75.14 74.94,74.5 78.21,74.5 79.79,72.93 88.86,72.93 89.7,73.77 96.63,73.77 96.88,73.52 98.53,73.52 99.55,72.5 100.02,72.5 102.45,70.08 105.04,70.08 106.26,68.86 106.26,66.42 107.07,65.61 109.32,65.61 111.36,63.58 112.77,63.58 v1(114.63,61.72)
  BOTTOM w0.076: v1(114.63,61.72) 114.93,62.02 UCPU1.V60
CFG11: length 53.7
  TOP w0.102: JXDP.18 71.41,71.63 71.25,71.79 v1(71.25,72.33) ; v1(109.48,62.7) v2(109.48,62.12)
  IN4 w0.071: v1(71.25,72.33) 72.39,73.47 77.78,73.47 79.36,71.89 89.29,71.89 90.13,72.73 96.2,72.73 96.45,72.48 98.1,72.48 99.12,71.47 99.59,71.47 102.06,69 102.87,69 104.88,66.99 104.88,65.12 105.51,64.49 106.75,64.49 107.36,63.88 108.3,63.88 v1(109.48,62.7)
  BOTTOM w0.076: 110.62,62.08 111.73,62.08 112.25,62.6 112.57,62.6 112.79,62.39 113.17,62.39 113.33,62.56 114.12,62.56 114.15,62.52 114.63,62.52 UCPU1.U60
  BOTTOM w0.102: 110.62,62.08 110.1,62.08 v1(109.48,62.7)
CFG12: length 54.8
  TOP w0.102: JXDP.28 68.91,72.31 v1(68.94,72.34) ; v1(107.5,64.26) v2(106.75,64.26)
  IN4 w0.071: v1(107.5,64.26) 107.09,64.67 105.58,64.67 105.05,65.19 105.05,66.32 105.4,66.67 105.4,68.18 105.06,68.52 103.6,68.52 102.95,69.18 102.13,69.18 99.67,71.64 99.19,71.64 98.17,72.66 96.52,72.66 96.27,72.91 90.06,72.91 89.22,72.06 79.43,72.06 77.85,73.64 71.99,73.64 70.84,72.5 70.84,72.21 70.57,71.94 69.33,71.94 v1(68.94,72.34)
  BOTTOM w0.076: UCPU1.T63 112.88,63.69 110.24,63.69
  BOTTOM w0.102: v1(107.5,64.26) 108.07,63.69 110.24,63.69
CFG13: length 54.9
  TOP w0.102: v1(68.41,72.13) 68.41,72.13 JXDP.30 ; v1(107.03,62.71) 107.03,62.71 v2(106.56,62.24)
  IN4 w0.071: v1(68.41,72.13) 68.79,71.75 72.78,71.75 73.14,72.12 73.14,72.49 73.6,72.95 77.57,72.95 79.14,71.37 89.51,71.37 90.35,72.22 95.99,72.22 96.24,71.96 97.89,71.96 98.9,70.95 99.38,70.95 101.84,68.49 102.65,68.49 104.36,66.78 104.36,64.91 105.95,63.31 106.43,63.31 v1(107.03,62.71)
  BOTTOM w0.076: 110.24,63.22 112.01,63.22 112.08,63.14 113.17,63.14 113.18,63.15 113.18,63.15 UCPU1.T62
  BOTTOM w0.102: 110.24,63.22 107.55,63.22 v1(107.03,62.71)
CFG14: length 56.8
  TOP w0.102: v1(105.91,62.79) v2(105.25,62.79) ; JXDP.34 67.41,71.86 v1(67.86,72.31)
  IN4 w0.071: v1(67.86,72.31) 67.86,71.84 68.12,71.58 72.85,71.58 73.32,72.05 73.32,72.42 73.68,72.77 77.5,72.77 79.07,71.2 89.58,71.2 90.42,72.04 95.91,72.04 96.17,71.79 97.82,71.79 98.83,70.78 99.31,70.78 104.19,65.9 104.19,64.84 105.91,63.11 v1(105.91,62.79)
  BOTTOM w0.076: UCPU1.T61 114.02,63.89 113.5,63.89 113.27,63.65 113.27,63.48 113.1,63.31 112.59,63.31 112.44,63.46 110.24,63.46
  BOTTOM w0.102: 110.24,63.46 107.37,63.46 107.05,63.13 106.26,63.13 v1(105.91,62.79)
CFG15: length 61.6
  TOP w0.076: v1(114.63,63.22) v2(114.63,63.86)
  TOP w0.102: v1(65.92,72.27) 66.2,72.27 66.92,71.55 66.92,70.49 JXDP.36
  IN4 w0.071: v1(65.92,72.27) 66.62,72.97 66.62,74.49 67.57,75.44 74.24,75.44 75.01,74.67 78.28,74.67 79.86,73.1 88.79,73.1 89.63,73.94 96.7,73.94 96.95,73.69 98.6,73.69 99.62,72.68 100.1,72.68 102.52,70.25 105.11,70.25 106.44,68.93 106.44,66.5 107.12,65.81 109.39,65.81 110.45,64.75 113.1,64.75 v1(114.63,63.22)
  BOTTOM w0.076: v1(114.63,63.22) 114.93,63.52 UCPU1.T60
CFG16: length 47.8
  TOP w0.102: JXDP.6 74.41,69.32 v2(75.25,68.48) 75.6,68.13 77.65,68.13 v1(78.02,68.5)
  IN4 w0.071: v1(78.02,68.5) 78.29,68.77 79.08,68.77 80.28,69.96 90.05,69.96 90.6,70.51 97.39,70.51 98.33,69.57 98.81,69.57 102.98,65.4 102.98,64.33 104.44,62.87 104.44,62.27 105.54,61.17 106.88,61.17 107.29,60.75 108.76,60.75 v1(109.32,61.31)
  BOTTOM w0.076: UCPU1.AA62 113.57,60.54 113.57,60.54 113.17,60.14 112.85,60.14 112.84,60.13 111.74,60.13 111.31,60.55 110.56,60.55 110.3,60.81 110.07,60.81
  BOTTOM w0.102: v1(109.32,61.31) 109.33,61.31 109.84,60.81 110.07,60.81
CFG17: length 51.1
  TOP w0.102: JXDP.4 74.91,71.83 75.11,72.03 75.85,72.03 76.18,71.7 v1(76.18,70.24) ; v2(108.55,60.42) 108.97,60.84 109.54,60.84 109.94,61.24 v1(109.95,61.24)
  IN4 w0.071: v1(109.95,61.24) 109.47,61.71 105.73,61.71 104.96,62.48 104.96,63.08 103.49,64.55 103.49,65.61 99.02,70.08 98.55,70.08 97.6,71.03 90.38,71.03 89.83,70.48 80.06,70.48 78.88,69.3 77.38,69.3 76.84,69.85 76.57,69.85 v1(76.18,70.24)
  BOTTOM w0.076: 110.71,60.73 111.36,60.73 111.8,60.29 112.77,60.29 112.79,60.31 113.1,60.31 113.33,60.54 113.33,60.72 113.5,60.89 114.02,60.89 UCPU1.AA61
  BOTTOM w0.102: v1(109.95,61.24) 110.2,61.24 110.71,60.73
CFG18: length 57.4
  TOP w0.076: v2(111.31,61.97) 111.33,62 v1(111.33,62.6)
  TOP w0.102: v1(69.19,74.7) 69.92,73.98 69.92,70.49 JXDP.24
  IN4 w0.071: v1(69.19,74.7) 69.65,74.7 70.36,73.98 78,73.98 79.57,72.41 89.08,72.41 89.92,73.25 96.42,73.25 96.67,73 98.32,73 99.33,71.98 99.81,71.98 102.27,69.52 104.86,69.52 105.75,68.64 105.75,66.53 105.39,66.18 105.39,65.34 105.72,65.01 109.13,65.01 111.33,62.81 v1(111.33,62.6)
  BOTTOM w0.076: UCPU1.U63 112.89,62.93 112.12,62.93 111.78,62.6 v1(111.33,62.6)
CFG19: length 54.7
  TOP w0.076: v1(110.76,62.6) v2(110.76,63.14)
  TOP w0.102: v1(70.43,72.33) 70.42,72.31 70.42,70.5 JXDP.22
  IN4 w0.071: v1(70.43,72.33) 71.91,73.81 77.93,73.81 79.5,72.24 89.15,72.24 89.99,73.08 96.34,73.08 96.6,72.83 98.25,72.83 99.26,71.81 99.74,71.81 102.2,69.35 103.02,69.35 103.67,68.7 105.13,68.7 105.57,68.26 105.57,66.6 105.22,66.25 105.22,65.27 105.65,64.84 109.04,64.84 110.76,63.12 v1(110.76,62.6)
  BOTTOM w0.076: v1(110.76,62.6) 111.12,62.24 111.66,62.24 112.19,62.77 112.64,62.77 112.85,62.56 113.1,62.56 113.39,62.85 UCPU1.U62
CFG_RCOMP: length 2.3
  TOP w0.076: v2(112.62,63.78) 112.35,63.51 RC153.1
  TOP w0.381: RC153.1 112.4,62.76 v1(112.4,62.18)
  BOTTOM w0.254: UCPU1.V63 112.48,62.1 v1(112.4,62.18)
CHAGER_SRC:
  vias: v2(56.33,40.56) v7(57.88,38.81) v7(57.88,38.18) v7(57.88,37.42) v7(57.88,36.78) v7(57.88,35) v7(57.88,34.37)
CHARGER_SMBCLK: length 194.2
  TOP w0.102: v1(52.68,20.31) 52.86,20.49 v2(52.86,21.08) PR227.1 ; v1(179.46,62.35) 179.35,62.24 177.87,62.24 UE5.B50 ; v1(175.73,61.94) 175.62,62.05 RE56.1 ; v3(179.37,55.48) 179.3,55.55 179.3,56.97 179.15,57.12 176.63,57.12 RH453.1 176.81,56.35 177.1,56.06 QH6.6
  GND1 w0.102: v3(179.37,55.48) v4(178.71,55.48)
  IN1 w0.071: v1(179.46,62.35) 176.97,62.35 176.39,61.76 175.92,61.76 v1(175.73,61.94)
  IN3 w0.086: v1(52.68,20.31) 53.08,19.92 65.9,19.92 66.76,19.06 93.24,19.06 93.68,19.5 104.25,19.5 104.54,19.2 117.38,19.2 119.01,17.57 125.28,17.57 126.72,19.01 140.6,19.01 141.48,18.12 171.3,18.12 171.89,18.72 174.59,18.72 175.35,19.48 177.86,19.48 182.14,23.75 182.14,39.02 180.68,40.47 180.68,44.76 178.98,46.46 178.98,51.25 178.26,51.97 178.26,55.03 v4(178.71,55.48) 179.13,55.9 179.13,57.21 178.26,58.08 178.26,59.18 179.01,59.93 179.01,61.9 v1(179.46,62.35)
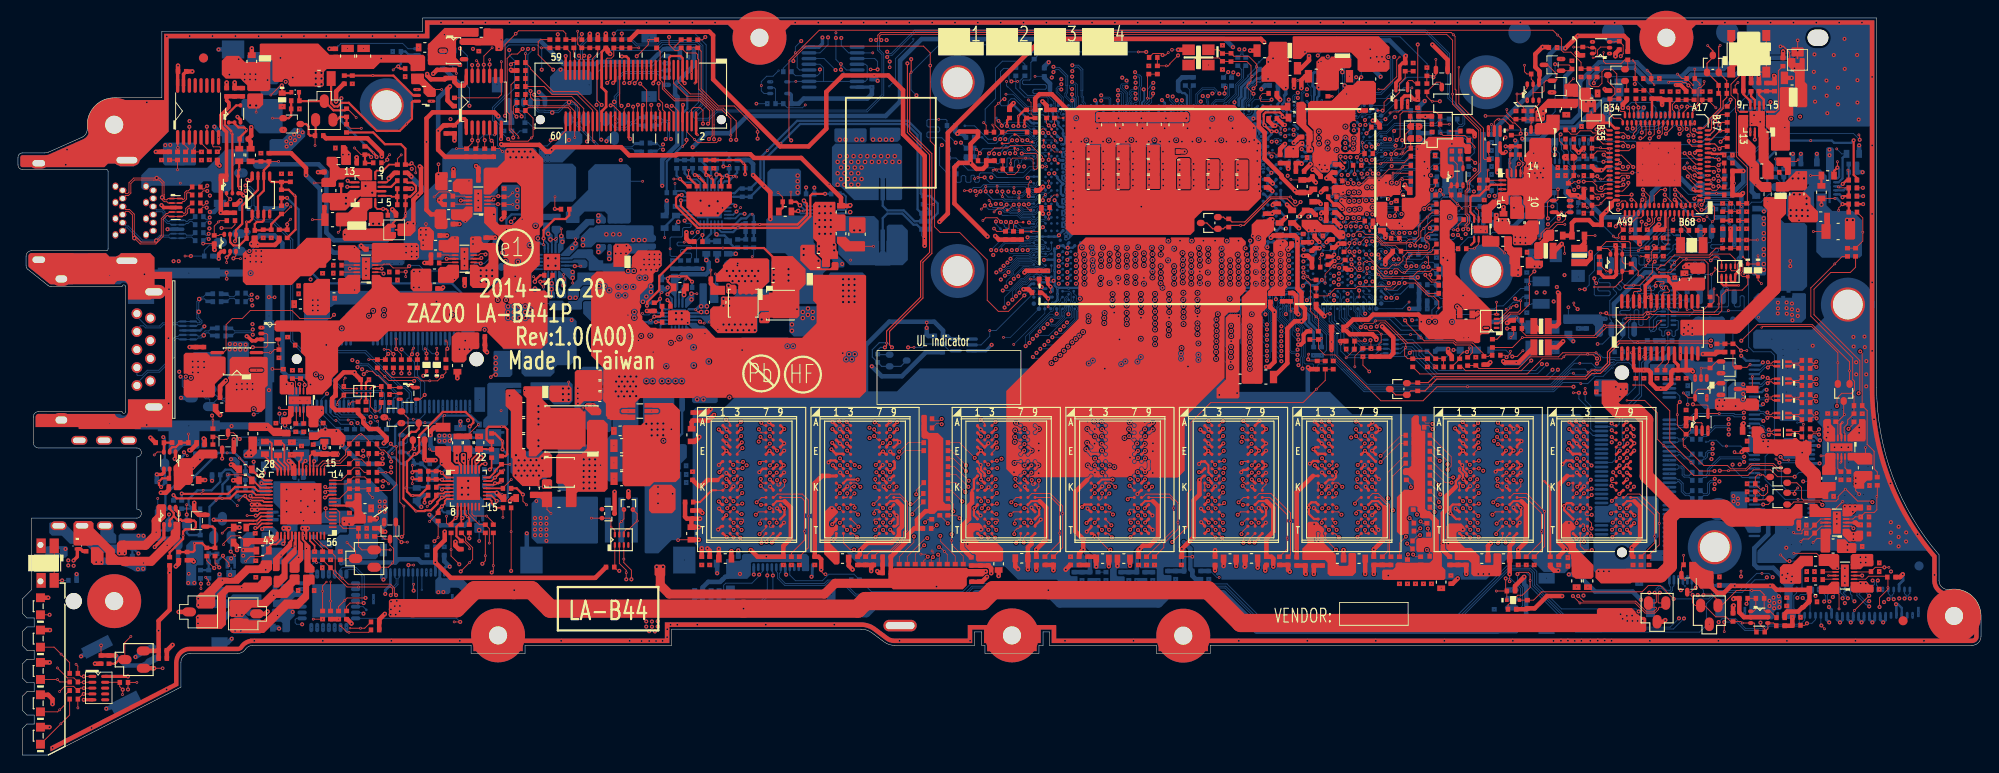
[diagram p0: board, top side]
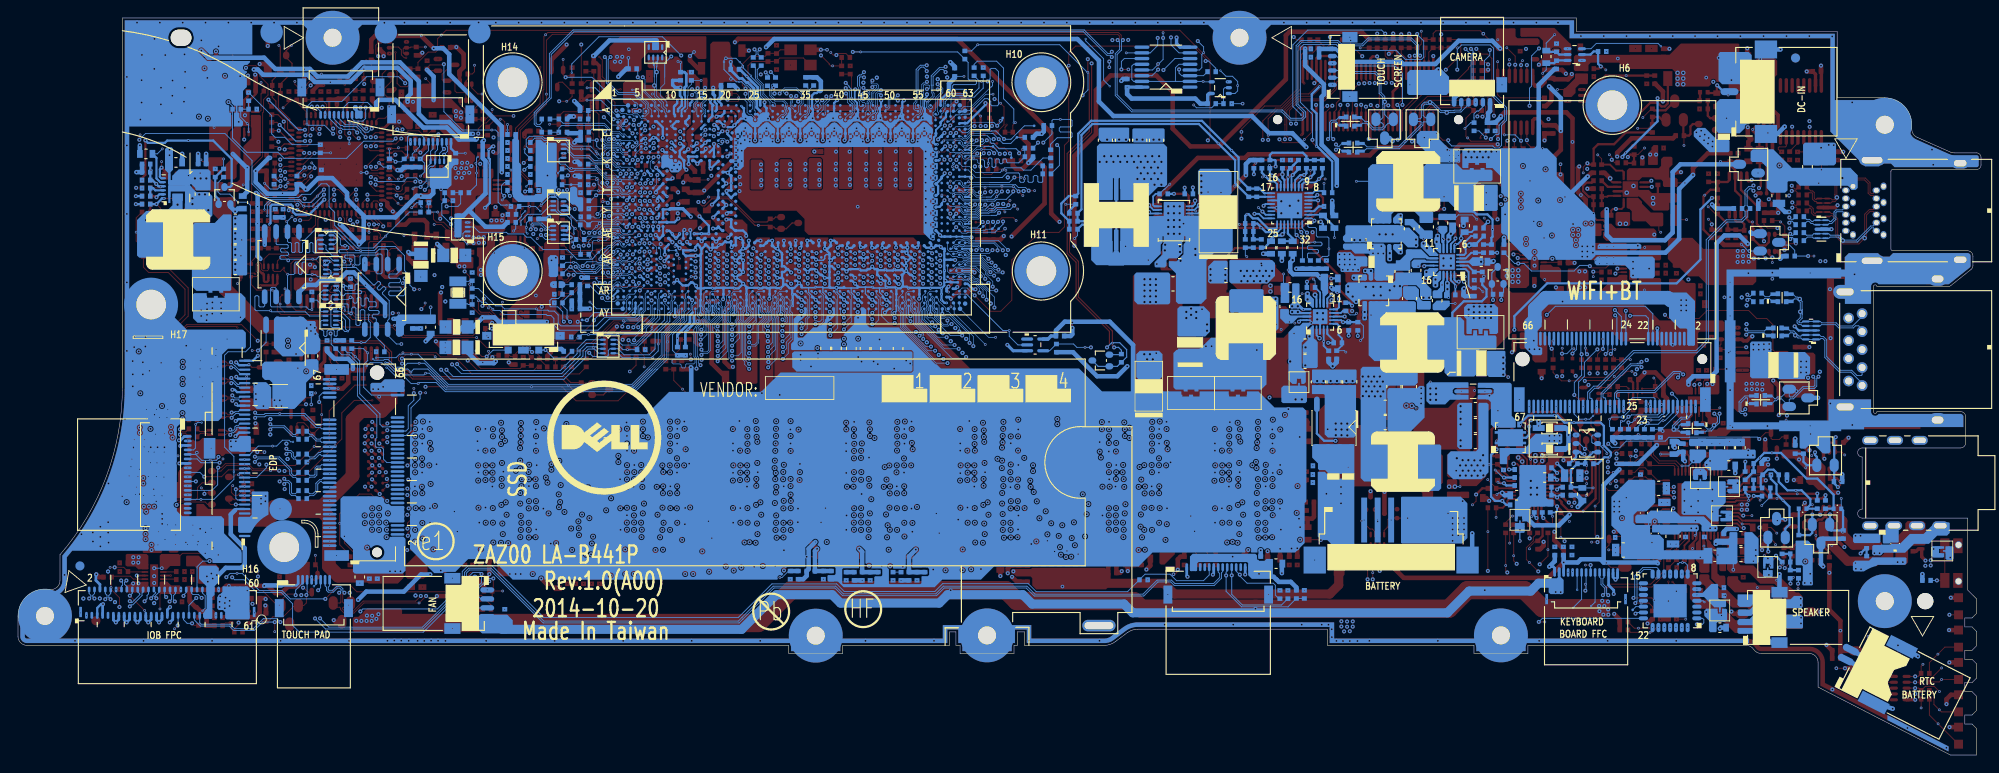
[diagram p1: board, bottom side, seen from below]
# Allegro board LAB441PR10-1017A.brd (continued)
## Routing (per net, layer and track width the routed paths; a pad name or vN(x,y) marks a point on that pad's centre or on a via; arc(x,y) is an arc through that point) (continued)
CHARGER_SMBDAT: length 189.9
  TOP w0.102: QH6.3 179.32,53.82 RH454.1 ; QH6.3 178.4,53.82 ; QH6.3 178.4,53.82 ; 178.4,53.82 178.4,52.87 177.6,52.07 v3(175.29,52.07) ; RE55.1 175.05,62.8 175.45,62.4 176.06,62.4 v1(176.2,62.26) 176.44,62.49 UE5.A47 ; v1(51.64,21.27) 51.97,21.6 v2(51.97,22.17) PR226.1
  GND1 w0.102: v3(175.29,52.07) v4(175.29,52.5)
  IN3 w0.086: v1(176.2,62.26) 176.2,61.83 175.97,61.59 175.97,53.17 175.3,52.5 v4(175.29,52.5) 175.29,52.49 175.97,51.8 175.97,44.92 176.25,44.64 176.25,41.82 178.14,39.94 178.95,39.94 181.35,37.54 181.35,24.03 178.24,20.92 175.64,20.92 174.21,19.49 171.56,19.49 170.95,18.88 141.79,18.88 140.92,19.76 126.41,19.76 124.97,18.32 119.32,18.32 117.69,19.95 110.35,19.95 108.91,21.39 103.56,21.39 102.7,20.53 98.6,20.53 98.21,20.92 93.99,20.92 92.9,19.83 89.3,19.83 88.31,20.82 74.56,20.82 73.62,19.88 71.09,19.88 69.89,21.08 51.83,21.08 v1(51.64,21.27)
CHG_BTS:
  vias: v2(50.11,32.9)
CHG_BTS_C: length 3
  TOP w0.102: v2(51.2,36.76) 50.07,35.63 PR211.2
  TOP w0.635: PC210.1 PR211.2
CHG_LGATE: length 7.5
  IN1 w1.016: 57.62,30.11 54.86,30.11 53.88,31.1 53.88,31.75 52.42,33.21 52.42,33.29
  BOTTOM w0.102: v7(58.51,29.86) v2(57.95,29.86)
  vias: v7(51.02,32.65) v7(51.46,33.1) v7(59.15,29.86)
CHG_SW: length 15.2
  IN1 w1.016: 48.54,34.18 48.71,34.34 50.87,34.34 52.42,35.89 59.02,35.89 61.88,33.03
  vias: v2(64.79,32.25) v7(48.8,33.35) v7(48.8,32.72) v7(62.92,32.89) v7(62.92,32.23) v7(62.92,31.6) v7(62.9,30.95) v7(62.9,30.31) v7(62.9,29.66) v7(63.54,30.95) v7(63.54,30.31) v7(63.54,29.66) v7(63.55,33.53) v7(63.55,32.89) v7(63.55,32.23) v7(63.55,31.6) v7(64.19,33.53) v7(64.19,32.89) v7(64.19,32.23) v7(64.19,31.6) v7(64.17,30.95) v7(64.17,30.31) v7(64.19,29.68)
CHG_UGATE: length 15.7
  IN4 w1.016: 63.37,37.99 61.27,35.89 52.54,35.89 50.89,34.24 49.81,34.24
  BOTTOM w0.102: v2(62.82,38.59) 63.08,38.85 v7(63.3,38.85)
  vias: v7(49.56,33.35) v7(49.56,32.72) v7(63.91,38.88)
CL_CK: length 147.7
  TOP w0.102: R1212.2 v1(42.64,42.47)
  IN2 w0.086: 113.7,71.16 116.86,71.16 117.55,70.48 131.94,70.48 132.76,71.3 138.12,71.3 139.04,70.37 139.04,69.15 139.18,69.01 140.19,69.01 140.53,68.67 140.53,67.77 141.58,66.71 142.64,66.71 143.36,66 143.36,64.88 143.7,64.54 145.66,64.54 145.95,64.25 145.95,63.55 146.8,62.7 146.8,59.62 147.04,59.37 148.47,59.37 148.63,59.21 150.65,59.21 151.2,58.66 153.25,58.66 153.61,58.29 v1(153.61,58.09) ; 113.14,71.72 113.12,71.74 107.79,71.74 106.54,70.49 100.87,70.49 99.61,71.74 81.75,71.74 79.5,69.5 58.59,69.5 58.18,69.08 53.71,69.08 53.33,68.71 53.33,65.71 50.78,63.16 50.78,59.15 48.44,56.81 48.44,51.33 43.06,45.94 43.06,42.89 v1(42.64,42.47)
  IN2 w0.089: 113.7,71.16 113.14,71.72
  BOTTOM w0.076: v1(153.61,58.09) 153.61,58.29 153.14,58.77 151.41,58.77 151.4,58.76 151.4,58.76 UCPU1.AF2
CL_DAT: length 149.2
  TOP w0.102: R1210.2 v1(41.75,42.48)
  IN2 w0.086: 113.62,70.98 116.79,70.98 117.47,70.31 137.85,70.31 138.56,69.6 138.56,69.39 139.11,68.84 140.11,68.84 140.35,68.6 140.35,67.42 143.4,64.38 144.56,64.38 146.44,62.5 146.44,58.81 146.85,58.39 149.56,58.39 149.67,58.28 152.52,58.28 152.72,58.49 153.1,58.49 153.24,58.35 153.24,57.94 153.45,57.73 154.43,57.73 v1(154.79,58.09) ; 110.07,71.55 107.87,71.55 106.62,70.3 100.79,70.3 99.54,71.55 81.83,71.55 79.58,69.31 58.67,69.31 58.12,68.76 55.69,68.76 54.81,67.88 54.3,67.88 53.84,67.41 53.84,65.95 51.69,63.81 51.69,59.79 48.64,56.73 48.64,51.25 43.27,45.89 43.27,42.84 43.06,42.62 43.06,42.33 42.8,42.07 42.16,42.07 v1(41.75,42.48)
  IN2 w0.089: 110.07,71.55 113.05,71.55 113.62,70.98
  BOTTOM w0.076: UCPU1.AD2 151.19,59.06 151.47,59.34 151.75,59.34 151.92,59.17 153.61,59.17 153.95,58.83 v2(153.95,58.82) 153.96,58.82 154.69,58.09 v1(154.79,58.09)
CL_RST#: length 152.8
  TOP w0.102: v1(44.06,41.62) 44.01,41.67 41.25,41.67 v2(40.79,42.12) 39.97,42.94 R1200.2
  IN2 w0.086: v1(154.83,56.68) 154.31,57.2 151.68,57.2 151.33,57.55 149.67,57.55 149.43,57.3 147.4,57.3 146.08,58.62 146.08,62.36 145.25,63.18 144.09,63.18 139.94,67.33 139.56,67.33 137.58,69.32 117.36,69.32 116.04,70.63 112.05,70.63 111.52,71.16 108.01,71.16 106.77,69.92 100.63,69.92 99.4,71.16 81.99,71.16 79.74,68.91 58.81,68.91 58.21,68.31 56.46,68.31 55.8,67.64 54.33,67.64 54.03,67.34 54.03,65.88 51.9,63.74 51.9,59.73 48.82,56.66 48.82,51.17 44.8,47.14 44.8,43.86 44.06,43.12 v1(44.06,41.62)
  BOTTOM w0.076: UCPU1.AF4 149.98,57.95 150.37,57.95 150.46,57.86 151.25,57.86 151.41,58.02 151.73,58.02 151.85,58.15 152.26,58.15 152.84,57.57 154.42,57.57 154.83,57.16 v1(154.83,56.68)
CLK_LPC_DEBUG: length 75.1
  TOP w0.089: CH1244.1 RH428.2 144.62,45.23 145.33,44.52 146.47,44.52 148.03,42.96
  TOP w0.102: 148.03,42.96 151.57,39.41 156.25,39.41 157.81,40.97 v2(161.21,40.97) v1(172.99,40.97)
  IN1 w0.071: v1(172.99,40.97) 176.51,40.97 176.99,41.45 178.97,41.45 179.51,41.99 179.51,42.96 179.13,43.34 179.13,43.93 181.6,46.4 182.02,46.4 182.26,46.64 182.26,46.91 183.54,48.19 v4(183.66,48.19)
  IN4 w0.086: v4(183.66,48.19) 183.9,48.43 183.9,53.76 183.99,53.85 183.99,57.81 185.37,59.19 185.37,63.84 184.72,64.49 184.72,67.49 185.2,67.96 185.2,71.97 v1(185.03,72.14)
  BOTTOM w0.102: JLPDE1.10 184.65,71.59 185.03,71.97 v1(185.03,72.14)
CLK_PCI_MEC: length 88.4
  TOP w0.102: RE80.1 179.93,72.48 180.22,72.18 v1(180.22,72.04) 180.18,72 180.18,71.23 UE5.A29 ; v1(153.03,52.52) 153.03,52.52 152.65,52.15 148.99,52.15 148.73,51.89 146.46,51.89 v2(145.83,51.26) 145.65,51.08 CH1243.1 RH360.2
  IN1 w0.071: v4(176.75,47.83) 175.89,47.83 173.72,45.66 168.9,45.66 168.14,46.41 163.94,46.41 161.19,49.17 161.19,49.5 159.08,51.61 155.01,51.61
  IN1 w0.086: 155.01,51.61 153.94,51.61 v1(153.03,52.52)
  IN2 w0.086: v4(184.83,39.82) 181.46,43.18 181.46,43.6 181.22,43.84 181.22,50.05 179.94,51.33 179.94,53.62 179.09,54.47 179.09,58.15 179.65,58.7 179.65,60.99 179.96,61.3 179.96,62.78 180.55,63.37 180.55,67.45 180.03,67.97 180.03,70 179.91,70.12 179.91,71.26 180.22,71.57 v1(180.22,72.04)
  IN4 w0.071: v4(184.83,39.82) 183.34,41.3 183.34,44.15 180.03,47.46 177.44,47.46 177.06,47.83 v4(176.75,47.83)
CLK_PCIE_MMI: length 153.2
  IN4 w0.071: v1(205.87,17.12) 205.87,17.06 206.13,16.81 206.24,16.81 206.44,17.01 206.44,18.11 206.2,18.35 201.53,18.35 200.08,16.9 199.78,16.9 198.76,17.92 196.7,17.92 196.04,18.58 193.49,18.58 191.67,20.39 191.67,30.68 196.58,35.58 196.58,44.51 196.13,44.95 196.13,50.84 195.5,51.48 195.5,71.27 189.59,77.18 173.98,77.18 173.83,77.33 172.53,77.33 171.89,77.96 167.15,77.96 166.6,78.51 160.37,78.51 158.48,76.62 154.8,76.62 153.09,74.91 146.73,74.91 146.31,75.33 139.09,75.33 138.98,75.22 127.83,75.22 127.23,74.63 126.61,74.63 126.26,74.27 v1(126.26,74.2)
  BOTTOM w0.076: v1(126.26,74.2) 125.86,73.8 125.86,72.77 125.78,72.69 125.62,72.55 125.61,72.54 arc(125.59,72.53) 125.58,72.52 125.57,72.51 arc(125.55,72.5) 125.54,72.49 125.54,72.49 arc(125.49,72.45) 125.46,72.39 125.46,72.34 125.46,72.21 arc(125.47,72.16) 125.5,72.12 125.51,72.11 arc(125.53,72.08) 125.53,72.05 125.53,71.83 125.46,71.74 125.46,71.55 125.53,71.44 125.66,71.31 125.86,71.31 126.3,70.87 UCPU1.C42
  BOTTOM w0.102: JIO1.20 205,18.16 204.75,17.92 204.75,17.84 205.64,16.95 205.7,16.95 v1(205.87,17.12)
CLK_PCIE_MMI#: length 153.8
  IN4 w0.071: v1(205.87,16.54) 205.99,16.66 206.3,16.66 206.6,16.95 206.6,18.17 206.27,18.5 201.47,18.5 200.02,17.05 199.84,17.05 198.82,18.07 196.77,18.07 196.11,18.73 193.55,18.73 191.83,20.46 191.83,30.62 196.73,35.52 196.73,44.57 196.28,45.02 196.28,50.9 195.65,51.54 195.65,71.34 189.65,77.33 174.04,77.33 173.89,77.48 172.59,77.48 171.95,78.11 167.21,78.11 166.67,78.66 160.3,78.66 158.41,76.77 154.74,76.77 153.07,75.1 153.07,75.1 153.03,75.06 146.79,75.06 146.37,75.48 139.02,75.48 138.92,75.38 127.77,75.38 127.17,74.78 126.26,74.78 v1(126.26,74.78)
  BOTTOM w0.076: 125.61,72.86 125.29,72.54 125.22,72.34 125.22,72.24 arc(125.23,72.17) 125.27,72.11 arc(125.31,72.05) 125.33,71.98 125.33,71.89 125.24,71.74 125.27,71.47 125.4,71.31 125.73,70.98 UCPU1.C43
  BOTTOM w0.102: JIO1.22 204.4,18.15 204.51,18.03 204.51,17.74 205.54,16.71 205.7,16.71 v1(205.87,16.54) ; 125.61,72.86 125.61,74.06 125.89,74.33 125.89,74.41 126.14,74.66 v1(126.26,74.78)
CLK_PCIE_MSATA: length 119.2
  IN4 w0.071: v1(129.44,72.85) 129.38,72.85 129.15,73.08 129.15,73.93 129.75,74.53 140.69,74.53 140.85,74.69 146.05,74.69 147.08,73.65 149.25,73.65 149.83,74.22 153.5,74.22 155.15,75.88 158.73,75.88 160.67,77.82 166.18,77.82 166.74,77.26 171.54,77.26 172.16,76.64 173.55,76.64 173.69,76.5 189.31,76.5 194.81,70.99 194.81,66.75 194.57,66.51 194.57,64.11 194.81,63.86 194.81,50.56 195.08,50.29 195.08,38.82 194.89,38.63 193.62,38.63 192.75,37.76 192.22,37.76 191.94,38.04 v1(191.94,38.1)
  BOTTOM w0.076: UCPU1.A37 129.32,72.28 129.25,72.21 129.25,72.09 129.38,71.96 129.63,71.96 129.7,72.02 129.7,72.4 129.44,72.66 v1(129.44,72.85)
  BOTTOM w0.102: JNGFF3.55 184.55,36.79 184.68,36.67 185.05,36.67 186.38,37.99 190.84,37.99 190.96,37.87 191.72,37.87 v1(191.94,38.1)
CLK_PCIE_MSATA#: length 119.5
  IN4 w0.071: v1(128.87,72.85) 129,72.98 129,73.99 129.68,74.68 140.63,74.68 140.79,74.84 146.11,74.84 147.15,73.8 149.19,73.8 149.76,74.37 153.43,74.37 155.09,76.03 158.67,76.03 160.61,77.97 166.24,77.97 166.8,77.42 171.6,77.42 172.22,76.79 173.61,76.79 173.76,76.65 189.37,76.65 194.97,71.05 194.97,66.69 194.72,66.44 194.72,64.17 194.97,63.93 194.97,50.62 195.23,50.36 195.23,38.76 194.95,38.48 193.68,38.48 192.81,37.61 192.03,37.61 v1(191.94,37.51)
  BOTTOM w0.076: UCPU1.B37 129,72 129,72.28 129.06,72.34 129.06,72.4 129.16,72.5 129.16,72.56 v1(128.87,72.85)
  BOTTOM w0.102: JNGFF3.53 184.55,36.29 184.68,36.42 185.15,36.42 186.48,37.75 190.74,37.75 190.86,37.63 191.82,37.63 v1(191.94,37.51)
CLK_PCIE_WLAN: length 165
  IN4 w0.071: v1(128.42,73.26) 128.08,72.92 127.7,72.92 127.4,73.23 126.94,73.23 126.81,73.1 125.89,73.1 125.53,73.46 125.53,75.92 124.91,76.54 122.17,76.54 118.61,72.98 115.07,72.98 114.55,73.5 111.09,73.5 109.96,74.63 109.7,74.89 109.7,78.59 108.5,79.79 101.6,79.79 100.68,78.86 98.54,78.86 97.4,80.01 93.27,80.01 92.02,78.75 86.86,78.75 84.03,75.92 80.9,75.92 78.36,78.46 74.11,78.46 73.77,78.11 71.91,78.11 71.14,78.89 68.32,78.89 67.73,78.3 67.1,78.3 65.97,77.17 62.24,77.17 61.21,78.2 58.22,78.2 55.64,75.62 51.25,75.62 44.05,68.42 33,68.42 27.58,62.99 25.52,62.99 v1(25.31,62.78)
  BOTTOM w0.076: v1(128.42,73.26) 128.3,73.15 128.3,72.92 128.77,72.45 128.77,71.78 129.37,71.19 UCPU1.C37
  BOTTOM w0.102: v1(25.31,62.78) 25.52,62.99 25.74,62.99 26.01,62.72 26.01,61.13 C1302.1 26,60.49 26,59.86 26.56,59.31 28.24,59.31 30.32,57.22 30.32,46.02 31.59,44.75 38.59,44.75 42.54,40.8 42.97,40.8 43.51,40.27 43.51,39.73 43.46,39.68 43.34,39.68 43.25,39.6 JNGFF1.39
CLK_PCIE_WLAN#: length 165.2
  IN4 w0.071: v1(25.31,63.36) 25.52,63.15 27.51,63.15 32.94,68.58 43.99,68.58 51.19,75.78 55.58,75.78 58.16,78.36 61.27,78.36 62.3,77.33 65.91,77.33 67.04,78.46 67.67,78.46 68.25,79.04 71.2,79.04 71.98,78.27 73.7,78.27 74.05,78.61 78.42,78.61 80.96,76.07 83.97,76.07 86.8,78.9 91.95,78.9 93.21,80.16 97.46,80.16 98.61,79.02 100.61,79.02 101.54,79.94 108.57,79.94 109.85,78.65 109.85,74.95 111.15,73.66 114.61,73.66 115.13,73.14 118.55,73.14 120.95,75.54 122.1,76.69 124.97,76.69 125.68,75.98 125.68,73.52 125.96,73.25 126.74,73.25 126.88,73.38 127.33,73.38 127.65,73.7 127.96,73.7 128.08,73.57 128.08,73.43 127.97,73.32 v1(127.86,73.32)
  BOTTOM w0.076: v1(127.86,73.32) 128.09,73.09 128.09,72.83 128.55,72.36 128.55,71.56 128.5,71.51 128.5,71.3 128.63,71.17 128.74,71.17 128.81,71.23 UCPU1.B38
  BOTTOM w0.102: v1(25.31,63.36) 25.43,63.23 25.84,63.23 26.25,62.82 26.25,61.13 C1301.1 26.24,60.47 26.24,59.96 26.66,59.55 28.34,59.55 30.56,57.32 30.56,46.12 31.69,44.99 38.69,44.99 42.64,41.04 43.07,41.04 43.75,40.37 43.75,38.77 JNGFF1.41
CLK_SMB: length 5
  TOP w0.102: PRP100.6 67.38,24.52 67.38,24.83 67.69,25.14 67.96,25.14 v2(68.86,26.04) 68.86,26.83 v3(68.39,27.31)
  GND1 w0.102: v4(68.6,26.67) 68.39,26.88 v3(68.39,27.31)
  GND3 w0.102: v5(68.6,26.14) v4(68.6,26.67)
CLK_TP_SIO: length 84.9
  TOP w0.102: UE5.A37 177.02,67.49 176.08,67.49 v2(176,67.56) 175.09,67.56 v3(175.05,67.51) ; v1(182.01,18.05) 182.2,17.86 182.2,17.03 182.08,16.91 MD9.3 181.79,16.44 182.14,16.44 182.24,16.34 182.24,16.28 181.96,16 181.04,16 179.92,17.12 174.08,17.12 v1(173.51,17.69)
  GND1 w0.102: v4(174.54,66.88) 175.05,67.39 v3(175.05,67.51)
  IN2 w0.086: v4(174.54,66.88) 174.18,66.52 174.18,65.36 174.75,64.79 174.75,60.61 175.12,60.24 175.12,58.53 174.52,57.93 174.52,54.09 174.81,53.8 174.81,52.36 175.03,52.14 175.03,49.38 175.58,48.82 175.58,46.86 174.95,46.24 174.95,43.05 177.71,40.29 181.14,40.29 185.5,35.93 185.5,34.71 186.78,33.43 186.78,26.68 178.33,18.22 174.04,18.22 v1(173.51,17.69)
  BOTTOM w0.102: v1(182.01,18.05) 182.17,18.22 182.17,18.5 182.44,18.77 182.88,18.77 183.33,18.32 183.72,18.32 183.8,18.41 183.8,18.68 183.65,18.82 JTP1.8
CLKOUT_LPC0: length 2.3
  TOP w0.102: v1(142.95,53.69) v2(143.43,53.21) 143.78,52.86 RH360.1
  BOTTOM w0.076: v1(142.95,53.69) 143.14,53.87 UCPU1.AN15
CLKOUT_LPC1: length 7.2
  TOP w0.089: RH428.1 144.62,48.52 v2(144.38,48.75) 143.73,49.4 143.73,52.37 142.96,53.14 v1(142.95,53.14)
  BOTTOM w0.076: UCPU1.AP15 143.03,53.22 v1(142.95,53.14)
CLKRUN#: length 43.3
  TOP w0.102: v1(177.86,72.01) 177.86,72.01 178.26,71.6 178.68,71.6 178.72,71.57 UE5.A32
  IN2 w0.086: 154.53,63.1 155.1,63.67 157.95,63.67 158.38,64.09 160.65,64.09 v4(160.81,63.93) 164.08,63.93 165.92,62.09 170.75,62.09 171.42,61.42 172.99,61.42 v4(173.14,61.27)
  IN2 w0.089: v1(148.58,62.6) 148.94,62.23 150.17,62.23 150.26,62.32 151.11,62.32 151.81,63.02 154.45,63.02 154.53,63.1
  IN4 w0.071: v4(173.14,61.27) 173.14,61.25 174.88,62.99 174.88,70.59 175.83,71.53 177.38,71.53 v1(177.86,72.01)
  GND3 w0.102: v4(160.81,63.93) 160.81,64.23 161.18,64.59 v5(161.33,64.59)
  BOTTOM w0.076: v1(148.58,62.6) 148.97,62.21 UCPU1.V5
CODEC_GPIO6: length 20.1
  TOP w0.102: UA2.3 34.59,26.15 34.22,26.53 v1(34.22,27.44) ; RA32.1 21.91,21.36 v2(22.04,21.23) 22.38,20.89 v1(22.38,20.87)
  IN1 w0.102: v1(22.38,20.87) 22.52,20.74 31.15,20.74 34.22,23.81 v1(34.22,27.44)
CODEC_IRQ: length 179.2
  GND1 w0.102: v4(38.78,23.53) v3(38.78,24.33)
  IN1 w0.071: v4(163.19,65.14) 162.82,65.51 161.58,65.51 160.99,66.1 159.14,66.1 158.3,66.93 154.54,66.93 153.94,66.33 152.07,66.33 151.58,65.84 149.75,65.84 v1(149.38,66.21)
  IN3 w0.086: v1(149.38,66.21) 149.38,66.56 149,66.93 147.68,66.93 147.21,67.4 147.21,69.23 146.83,69.61 146.83,70.41 145.88,71.36 141.71,71.36 141.48,71.59 132.41,71.59 131.91,71.09 130.59,71.09 130.27,71.41 108.03,71.41 106.58,69.97 102.21,69.97 100.31,71.87 80.78,71.87 79.06,73.6 59.05,73.6 58.15,72.7 53.92,72.7 52.43,71.2 51.48,71.2 50.99,70.71 50.31,70.71 47.98,68.38 47.98,59.45 49.17,58.26 49.17,52.52 44.96,48.31 44.96,44.12 44.79,43.94 42.39,43.94 40.23,41.78 v4(40.23,41.17)
  IN4 w0.071: v4(40.23,41.17) 38.77,39.71 38.77,36.8 37.81,35.85 37.81,29.22 38.78,28.26 v4(38.78,23.53)
  GND3 w0.102: v4(163.19,65.14) 163.3,65.25 163.64,65.25 v5(163.87,65.48)
  BOTTOM w0.076: v1(149.38,66.21) 149.65,65.93 UCPU1.L4
CONFIG_BID: length 10.7
  TOP w0.076: v1(150.6,57.15) 151.25,57.15 151.7,56.71 153.15,56.71 RH3549.1
  TOP w0.102: RH3542.1 157.28,58.15 156.87,58.15 156.46,57.74 156.46,57.33 v2(156.7,57.08) 156.94,56.85 156.94,56.34 156.74,56.14 153.89,56.14 RH3549.1
  BOTTOM w0.076: v1(150.6,57.15) 150.3,57.45 UCPU1.AG3
CPU_B+: length 8.9
  TOP w0.508: v1(83.67,59.63) 83.67,62.6 v2(82.99,63.28) v1(81.75,64.52)
  BOTTOM w0.508: PR711.1 PR729.1 81.31,66.19 81.75,65.75 v1(81.75,64.52)
  vias: v7(87.38,56.31) v7(87.37,55.63) v7(89.02,54.99)
CPU_EDP_HPD: length 16.6
  TOP w0.102: v2(157.68,77.39) 157.69,77.39 QC5.3 157.69,75.68 v1(157.41,75.4) 157.24,75.57 RC160.1 RC148.2
  BOTTOM w0.076: UCPU1.D6 148.53,70.79 148.95,70.79 149.13,70.96 149.13,71.06 149.4,71.33 149.85,71.33 149.99,71.47 149.99,71.79 149.86,71.92 149.55,71.92 149.38,72.09 149.38,72.41 149.58,72.62 149.73,72.62 150.18,73.06 152.14,73.06
  BOTTOM w0.102: v1(157.41,75.4) 154.48,75.4 152.14,73.06
CPU_PATH_EN: length 15
  BOTTOM w0.102: 89.59,74.94 89.59,76.46 89.2,76.85 U663.5 ; 89.59,74.94 U663.2 v2(86.5,74.94) 86.46,74.9 U697.4 ; 89.59,74.94 U663.15 94.23,74.94 94.44,75.16 94.44,76.66 94.25,76.85 U663.12
CPU_XDP_TCK: length 73.6
  TOP w0.076: v1(114.63,70.04) 114.97,69.7 T265.1
  TOP w0.089: RC52.2 114.39,70.28 v1(114.63,70.04)
  TOP w0.102: v1(59.52,76.25) 57.85,77.91 57.85,79.35 58.1,79.59 RH446.2
  IN4 w0.071: 110.07,70.71 109.2,70.71 108.08,71.83 108.08,76.89 106.58,78.4 102.3,78.4 100.26,76.37 96.88,76.37 96.07,77.18 90.72,77.18 88.26,74.72 80.39,74.72 77.86,77.25 74.65,77.25 74.02,76.61 71.46,76.61 70.75,77.32 68.71,77.32 66.95,75.56 60.2,75.56 v1(59.52,76.25)
  IN4 w0.076: 110.07,70.71 113.96,70.71 v1(114.63,70.04)
  BOTTOM w0.076: v1(114.63,70.04) 114.93,69.74 UCPU1.E60
CPU_XDP_TDI: length 35
  TOP w0.102: v1(95.6,76.27) v6(94.82,76.27)
  IN4 w0.071: v1(95.6,76.27) 96.13,76.27 96.63,75.77 100.51,75.77 102.55,77.81 106.33,77.81 107.49,76.65 107.49,71.48 108.45,70.52 108.45,68.73 v1(108.65,68.53)
  BOTTOM w0.076: UCPU1.F63 112.86,68.84 112.32,69.38 110.12,69.38 110.07,69.43
  BOTTOM w0.102: 110.07,69.43 110.06,69.43 109.55,69.43 v1(108.65,68.53) 108.63,68.51 107.88,68.51 106.38,70 T268.1 ; U663.11 95.28,77.48 95.6,77.17 v1(95.6,76.27)
CPU_XDP_TDO: length 38
  TOP w0.102: v1(91.52,76.25) v6(91.52,76.88)
  IN4 w0.071: v1(91.52,76.25) 92.05,76.78 95.9,76.78 96.71,75.97 100.43,75.97 102.46,78 106.41,78 107.68,76.73 107.68,71.57 108.65,70.6 108.65,69.11 v1(109.24,68.52)
  BOTTOM w0.076: 110.07,69.14 112.28,69.14 112.87,68.55 113.1,68.55 113.39,68.84 UCPU1.F62
  BOTTOM w0.102: 110.07,69.14 109.86,69.14 v1(109.24,68.52) 108.77,68.05 107.89,68.05 T269.1 RC48.2 ; v1(91.52,76.25) 92.19,75.58 U663.14
CPU_XDP_TMS: length 37.1
  TOP w0.102: v1(109.41,70.01) 109.41,70.19 v6(109.05,70.56)
  IN4 w0.071: v1(90.92,76.21) 91.69,76.98 95.99,76.98 96.8,76.17 100.35,76.17 102.38,78.2 106.49,78.2 107.88,76.81 107.88,71.67 109.41,70.14 v1(109.41,70.01)
  BOTTOM w0.076: 110.07,70.39 110.07,70.4 112.12,70.4 112.54,69.97 113.11,69.97 113.18,69.9 114,69.9 UCPU1.E61
  BOTTOM w0.102: 110.07,70.39 110.06,70.38 109.79,70.38 v1(109.41,70.01) 108.81,70.61 T266.1 ; v1(90.92,76.21) 89.65,77.48 U663.6
CPU_XDP_TRST#: length 40.4
  TOP w0.076: T267.1 116.24,70.87 RC54.2
  TOP w0.089: RC54.2 115.28,70.09 v1(115.23,70.04)
  IN4 w0.071: 110.07,71.03 109.2,71.03 108.28,71.95 108.28,76.98 106.66,78.6 102.22,78.6 100.18,76.56 96.96,76.56 96.15,77.37 90.64,77.37 89.54,76.27 v1(89.18,76.27)
  IN4 w0.076: v1(115.23,70.04) 115.12,70.04 114.13,71.03 110.07,71.03
  BOTTOM w0.076: v1(115.23,70.04) 115.58,69.69 UCPU1.E59
  BOTTOM w0.102: v1(89.18,76.27) 89.18,75.87 88.9,75.58 U663.3 86.47,75.58 RH370.1
CS1: length 4.4
  BOTTOM w0.102: v2(55.39,51.53) 55.83,51.97 PR305.2
  BOTTOM w0.203: PU300.1 57.31,54.05 56.99,53.74 56.99,52.21 56.75,51.97 PR305.2
CS2: length 3.4
  BOTTOM w0.203: PR304.2 56.72,57.74 57.43,57.02 57.43,56.41 57.31,56.28 57.31,55.82 57.47,55.65 PU300.5
CS_1.35V: length 3
  BOTTOM w0.102: v2(74.26,52.96) 74.06,52.75 PR601.2
  BOTTOM w0.203: PR601.2 73.5,51.46 PU600.13
CSN1: length 43.1
  BOTTOM w0.203: 79.61,62.1 78.93,62.1 PU700.18
  BOTTOM w0.254: 79.61,62.1 PC716.2 PC715.2 82.95,63.62 82.95,66.17 v2(84.84,68.07) 86.98,70.21 98.82,70.21 100.04,68.98 100.04,60.71 PR725.2 PR724.2 99.71,59.39 98.5,60.59 96.68,60.59 96.17,61.1 PL701.3
CSP: length 8.9
  BOTTOM w0.102: PR722.1 100.47,57.79 v2(100.8,57.46)
  BOTTOM w0.254: PL701.2 96.17,59.73 96.68,60.24 98.35,60.24 99.59,59.01 99.97,59.01 PR722.1
CSP1: length 39
  BOTTOM w0.203: 79.6,62.5 PU700.17
  BOTTOM w0.254: 79.6,62.5 79.7,62.5 80.22,63.02 PC716.1 PC715.1 82.57,64.15 82.57,66.48 v2(83.34,67.25) 86.65,70.56 98.96,70.56 100.4,69.13 100.4,62.47 PH701.1 101.45,62.19 102.28,61.36 102.28,60.28 PR724.1 PR722.2
CSSN_1: length 25
  TOP w0.102: v1(43.86,31.45) v2(43.86,32.23)
  TOP w0.254: PR206.2 43.98,31.57 v1(43.86,31.45)
  IN1 w0.254: v4(57.43,40.46) 56.99,40.46 56.74,40.72 56.74,41.23 56.42,41.54 49.37,41.54 48.95,41.12 46.99,41.12 44.92,39.05 44.92,31.64 44.61,31.32 43.98,31.32 v1(43.86,31.45)
  GND3 w0.254: v5(57.79,40.46) v4(57.43,40.46)
CSSP_1: length 24.2
  TOP w0.102: v1(43.86,30.81) v2(43.86,30.2)
  TOP w0.254: PR205.2 43.98,30.68 v1(43.86,30.81)
  IN1 w0.254: v1(43.86,30.81) 44.01,30.96 44.75,30.96 45.28,31.49 45.28,38.91 47.14,40.77 49.13,40.77 49.53,41.16 56.14,41.16 56.29,41.01 56.29,40.65 56.1,40.46 v4(55.53,40.46)
  GND3 w0.254: v5(55.17,40.46) v4(55.53,40.46)
DAT_SMB: length 4.3
  TOP w0.102: v3(67.39,27.31) 67.39,26.26 v2(67.1,25.97) 66.88,25.75 66.88,24.52 PRP100.7
  GND1 w0.102: v4(67.1,26.65) 67.39,26.94 v3(67.39,27.31)
  GND3 w0.102: v5(67.1,26.14) v4(67.1,26.65)
DAT_TP_SIO: length 99
  TOP w0.102: v1(171.56,69.05) 171.41,68.91 171.41,68.33 RE7.2 ; UE5.B40 179.14,67.24 v1(179.62,67.72) ; v1(182.59,18.05) 182.4,17.86 182.4,17 182.49,16.91 MD9.2 182.78,16.44 182.54,16.44 182.44,16.34 182.44,16.19 182.04,15.79 180.95,15.79 179.83,16.92 v2(173.7,16.92) v1(172.93,17.69)
  IN1 w0.071: v1(179.62,67.72) 179.21,68.14 178.45,68.14 177.63,68.96 175.26,68.96 175.12,69.09 171.59,69.09 v1(171.56,69.05)
  IN2 w0.086: v1(171.56,69.05) 172.99,67.62 173.59,67.62 174,67.21 174,65.28 174.57,64.71 174.57,60.53 174.93,60.16 174.93,58.61 174.33,58 174.33,54.01 174.62,53.72 174.62,52.28 174.84,52.07 174.84,49.3 175.39,48.74 175.39,46.94 174.77,46.32 174.77,42.97 177.63,40.11 181.06,40.11 185.31,35.85 185.31,34.63 186.59,33.35 186.59,26.75 178.25,18.41 173.65,18.41 v1(172.93,17.69)
  BOTTOM w0.102: v1(182.59,18.05) 182.38,18.27 182.38,18.42 182.52,18.56 182.8,18.56 183.24,18.12 183.8,18.12 184.01,18.33 184.01,18.68 184.15,18.82 JTP1.7
DC_TEST_A3_B3: length 6.1
  BOTTOM w0.076: UCPU1.B3 150.47,71.75 UCPU1.A3 152.16,72.28 153.27,73.39
  BOTTOM w0.102: 153.27,73.39 154.11,74.23 v2(155.02,74.23)
DC_TEST_A61_B61: length 6.7
  BOTTOM w0.076: UCPU1.A61 114.22,71.69 UCPU1.B61 114.06,71.62 113.8,71.88 113.39,71.88 113.11,72.16 112.27,72.16 110.11,74.32 110.07,74.32
  BOTTOM w0.102: v2(109.94,74.94) 109.94,74.46 110.07,74.32
DC_TEST_AY2_AW2: length 4.7
  BOTTOM w0.076: 153.27,49.65 UCPU1.AY2 150.94,49.77 UCPU1.AW2
  BOTTOM w0.102: v2(154.7,50.4) 153.95,49.65 153.27,49.65
DC_TEST_AY3_AW3: length 0.7
  BOTTOM w0.076: UCPU1.AW3 150.28,49.7 UCPU1.AY3
DC_TEST_AY61_AW61: length 6.1
  BOTTOM w0.076: v2(110.74,45.68) 114.2,49.14 UCPU1.AY61 114.2,50.22 UCPU1.AW61
DC_TEST_AY62_AW62: length 6
  BOTTOM w0.076: UCPU1.AW62 113.63,49.73 UCPU1.AY62 110.36,46.47 v2(109.59,46.47)
DC_TEST_B62_B63: length 4.6
  BOTTOM w0.076: UCPU1.B63 112.49,71.69 110.66,73.52 110.07,73.52
  BOTTOM w0.102: v2(109.87,73.52) 110.07,73.52
  BOTTOM w0.254: UCPU1.B63 113.06,71.6 113.58,71.6 UCPU1.B62
DC_TEST_C1_C2: length 4.8
  BOTTOM w0.076: 153.27,72.64 151.77,71.14 UCPU1.C1 151.48,71.02 UCPU1.C2
  BOTTOM w0.102: v2(155.03,72.86) 153.48,72.86 153.27,72.64
DDR3_DRAMRST#: length 153.7
  TOP w0.102: v1(92.99,22.84) 92.56,22.84 91.8,23.61 UD29.T2 ; v1(128.36,23.7) 130.04,25.38 130.04,29.12 130.46,29.54 130.46,37.03 132.64,39.21 142.91,39.21 v2(144.4,40.7) 145.38,41.68 RD28.2 CD5.1 ; v1(133.18,24.2) 132.78,24.6 UD7.T2 ; UD32.T2 120.15,24.01 121.31,22.84 v1(121.48,22.84) ; UD28.T2 79.19,24.6 v1(79.58,24.2) ; v1(107.9,24.2) 107.51,24.6 UD31.T2 ; v1(161.5,24.2) 161.1,24.6 UD1.T2 ; UD4.T2 173.74,23.27 174.2,22.81 v1(175.04,22.81) ; UD3.T2 145.39,24.56 145.39,24.03 v1(146.58,22.84)
  IN1 w0.071: v1(175.04,22.81) 173.94,21.71 163.99,21.71 v1(161.5,24.2) 160.56,23.27 160.56,21.09 160.15,20.68 148.75,20.68 v1(146.58,22.84) 145.83,22.84 144.43,21.44 135.94,21.44 v1(133.18,24.2) 132.67,23.7 v1(128.36,23.7)
  IN4 w0.071: v1(128.36,23.7) 124.03,23.7 123.18,22.84 v1(121.48,22.84) 120.01,21.37 110.72,21.37 107.9,24.18 v1(107.9,24.2) 105.21,21.51 94.33,21.51 93,22.84 v1(92.99,22.84) 92.94,22.84 91.77,21.68 82.08,21.68 79.58,24.18 v1(79.58,24.2)
DDR_A_BA0: length 127.3
  TOP w0.076: UD32.M2 120.17,27.85 v1(120.56,27.46) ; v1(104.72,26.34) 104.38,26.67 RD67.1
  TOP w0.102: v1(92.24,27.5) 91.89,27.85 UD29.M2 ; v1(78.88,27.46) 79.19,27.77 UD28.M2 ; UD31.M2 107.51,27.77 v1(107.2,27.46)
  IN1 w0.076: v4(87.25,27.13) 87.44,27.13 87.9,27.59 89.38,27.59 90.11,26.86 92.75,26.86 93.23,26.38 93.59,26.38 94.47,27.26 95.72,27.26 95.9,27.08 97.15,27.08 97.25,27.18 102.73,27.18 103.66,26.25 104.63,26.25 v1(104.72,26.34) 104.75,26.38 104.75,26.96 104.88,27.09 105.47,27.09 105.6,26.96 105.6,26.39 105.7,26.29 105.87,26.29 105.94,26.35 105.94,26.54 106.06,26.67 106.35,26.67 106.47,26.55 106.47,26.38 106.35,26.27 106.28,26.27 106.23,26.21 106.23,26 106.34,25.88 106.51,25.88 106.68,26.06 107.32,26.06 107.85,26.6 108.19,26.6 108.29,26.69 108.38,26.69 108.65,26.43 108.99,26.43 109.17,26.24 109.57,26.24 109.67,26.34 109.67,26.49 109.57,26.6 109.29,26.6 109.19,26.7 109.19,26.89 109.28,26.98 109.9,26.98 110,26.88 110,26.34 110.1,26.24 110.39,26.24 110.51,26.35 110.78,26.35 110.85,26.43 110.85,26.58 110.76,26.67 110.76,26.77 110.83,26.84 111.35,26.84 111.54,26.64 113.02,26.64 113.22,26.44 113.41,26.44 113.65,26.68 113.89,26.68 114.17,26.4 114.32,26.4 114.43,26.51 114.43,26.66 114.17,26.91 114.17,27.06 114.49,27.37 114.66,27.37 114.75,27.28 114.75,26.65 114.83,26.57 115.22,26.57 115.29,26.65 115.29,26.79 v4(115.12,26.96)
  IN4 w0.076: v1(107.2,27.46) 107.46,27.2 107.46,26.62 107.57,26.51 107.98,26.51 108.64,27.17 110.48,27.17 110.97,26.68 112.06,26.68 112.22,26.85 114.83,26.85 114.94,26.96 v4(115.12,26.96) 115.41,26.67 115.63,26.67 116.28,27.33 116.67,27.33 116.87,27.52 117.31,27.52 117.38,27.46 117.38,27.24 117.76,26.86 120.25,26.86 120.32,26.94 120.32,27 120.4,27.08 120.55,27.08 120.63,27 120.63,26.94 120.7,26.86 121.12,26.86 121.29,27.03 121.29,27.12 121.04,27.37 121.04,27.67 120.97,27.74 120.65,27.74 120.56,27.65 v1(120.56,27.46) ; 128.61,42.96 129.27,43.62 129.8,43.62 130.39,44.2 130.39,45.67 131.17,46.45 v1(131.17,46.82) ; v1(92.24,27.5) 92.24,27.9 92.32,27.98 92.57,27.98 92.65,27.9 92.65,27.12 92.47,26.94 90.53,26.94 89.91,27.56 89.75,27.56 89.67,27.48 89.67,27.42 89.6,27.34 89.44,27.34 89.37,27.42 89.37,27.48 89.29,27.56 88.54,27.56 88.46,27.48 88.46,27.43 88.39,27.36 88.23,27.36 88.16,27.43 88.16,27.48 88.08,27.56 87.93,27.56 87.85,27.48 87.85,27.3 87.8,27.24 87.63,27.24 87.55,27.33 87.55,27.48 87.47,27.56 87.34,27.56 87.25,27.47 v4(87.25,27.13) 87.08,26.95 85.64,26.95 85.48,26.79 83.34,26.79 82.99,27.14 82.19,27.14 82.16,27.17 79.98,27.17 79.89,27.08 79.26,27.08 v1(78.88,27.46)
  IN4 w0.145: v1(104.72,26.34) 104.85,26.47 104.85,27.4 104.55,27.7 104.55,29.02 104.36,29.21 104.36,32.97 105.87,34.47 105.87,37.73 107.34,39.21 116.74,39.21 118.58,41.05 124.29,41.05 124.43,40.91 124.43,40.47 124.58,40.32 124.87,40.32 125.01,40.47 125.01,40.91 125.16,41.05 125.45,41.05 125.59,40.91 125.59,40.47 125.74,40.32 126.02,40.32 126.17,40.47 126.17,40.91 126.31,41.05 126.7,41.05 127.62,41.97 128.61,42.96
  BOTTOM w0.076: v1(131.17,46.82) 130.54,47.45 130.54,48.49 130.33,48.71 130.32,48.71 130.32,49.38 130.3,49.41 130.3,51.12 130.56,51.39 130.56,51.46 UCPU1.AU35
DDR_A_BA1: length 122.4
  TOP w0.076: v1(105.01,28.22) 103.81,29.41 RD99.1
  TOP w0.102: v1(111.91,27.47) 112.21,27.47 112.31,27.37 112.31,27.05 UD31.N8 ; v1(97,26.67) 96.62,27.05 UD29.N8 ; v1(125.35,26.67) 125.11,26.91 125.09,26.91 UD32.N8 ; v1(83.59,27.47) 83.89,27.47 83.99,27.37 83.99,27.05 UD28.N8
  IN1 w0.076: v4(90.14,28.72) 90.37,28.72 90.98,28.11 93.5,28.11 94.02,28.63 98.46,28.63 98.47,28.63 99.19,28.63 99.7,28.12 100.08,28.12 100.59,28.63 104.6,28.63 v1(105.01,28.22) 105.38,27.85 108.44,27.85 108.7,27.59 110.65,27.59 110.79,27.45 111.13,27.45 111.54,27.85 112.49,27.85 112.57,27.93 115.26,27.93 115.63,28.3 115.63,28.41 115.97,28.75 117.28,28.75 117.47,28.56 117.91,28.56 118.1,28.75 118.1,29.28 118.25,29.44 118.46,29.44 118.6,29.3 118.6,28.86 v4(118.46,28.72)
  IN4 w0.076: 131.28,46.31 131.54,46.56 131.54,47.11 ; 131.28,46.3 130.56,45.58 130.56,44.13 129.82,43.38 129.57,43.38 129.14,42.96 ; v1(97,26.67) 96.61,27.09 95.67,27.09 95.5,27.26 94.93,27.26 93.77,28.42 93.21,28.42 93.07,28.28 90.83,28.28 90.4,28.72 v4(90.14,28.72) 89.86,28.44 89.49,28.44 88.98,28.94 87.56,28.94 86.58,27.96 84.66,27.96 84.63,27.93 83.46,27.93 83.37,27.84 83.37,27.69 83.58,27.47 v1(83.59,27.47) ; v1(111.91,27.47) 112.33,27.89 113.94,27.89 114.02,27.81 114.02,27.51 114.09,27.43 114.25,27.43 114.32,27.51 114.32,27.81 114.4,27.89 115.42,27.89 116.25,28.72 117.39,28.72 117.54,28.56 117.97,28.56 118.13,28.72 v4(118.46,28.72) 119.13,28.04 123.09,28.04 124.12,27.01 125.01,27.01 v1(125.35,26.67)
  IN4 w0.086: v1(131.17,47.47) 131.54,47.11 ; 131.28,46.31 131.28,46.3
  IN4 w0.145: 129.14,42.96 126.16,39.98 124.2,39.98 124.05,40.13 124.05,40.53 123.91,40.68 123.62,40.68 123.47,40.53 123.47,40.13 123.33,39.98 123.04,39.98 122.89,40.13 122.89,40.53 122.75,40.68 122.46,40.68 122.31,40.53 122.31,40.13 122.17,39.98 121.88,39.98 121.74,40.13 121.74,40.53 121.59,40.68 121.3,40.68 121.16,40.53 121.16,40.13 121.01,39.98 120.72,39.98 120.58,40.13 120.58,40.53 120.43,40.68 120.14,40.68 120,40.53 120,40.13 119.85,39.98 119.56,39.98 119.42,40.13 119.42,40.53 119.27,40.68 118.98,40.68 118.84,40.53 118.84,40.13 118.69,39.98 117.99,39.98 116.87,38.86 107.53,38.86 106.28,37.62 106.28,34.51 104.58,32.81 104.58,29.47 104.91,29.15 104.91,29 105.05,28.86 105.63,28.86 105.92,28.56 105.92,27.05 105.77,26.9 105.47,26.9 105.31,27.05 105.31,27.92 v1(105.01,28.22)
  BOTTOM w0.076: v1(131.17,47.47) 130.71,47.94 130.71,48.56 130.5,48.77 130.5,49.44 130.46,49.48 130.46,50.66 UCPU1.AV35
DDR_A_BA2: length 124.3
  TOP w0.076: RD82.1 99.51,27.92 v1(99.27,27.92)
  TOP w0.102: UD29.M3 92.98,27.85 93.04,27.79 v1(93.04,27.52) ; UD31.M3 108.31,27.85 108.74,27.85 v1(108.86,27.97) ; UD28.M3 79.99,27.85 80.42,27.85 v1(80.54,27.97) ; UD32.M3 120.95,27.85 121.21,27.85 121.39,27.68 v1(121.39,27.52)
  IN1 w0.076: v4(88.31,28.32) 88.31,28.34 88.43,28.46 88.92,28.46 89.04,28.34 89.04,28.22 89.15,28.12 89.32,28.12 89.42,28.22 89.42,28.32 89.51,28.41 89.71,28.41 89.82,28.3 89.82,27.83 89.94,27.72 90.12,27.72 90.23,27.82 90.23,28.2 90.33,28.3 90.5,28.3 90.61,28.2 90.61,28.01 90.71,27.91 93.33,27.91 93.43,27.81 93.43,27.48 93.53,27.38 93.74,27.38 93.84,27.48 93.84,28.16 93.96,28.28 94.13,28.28 94.25,28.16 94.25,27.75 94.33,27.67 94.57,27.67 94.67,27.77 94.67,28.3 94.8,28.42 95.72,28.42 95.85,28.3 95.85,28.16 95.95,28.06 96.14,28.06 96.24,28.16 96.24,28.33 96.34,28.43 96.54,28.43 96.65,28.33 96.65,28.17 96.77,28.06 96.93,28.06 97.05,28.17 97.05,28.33 97.15,28.43 97.36,28.43 97.46,28.33 97.46,27.95 97.58,27.83 97.75,27.83 97.87,27.95 97.87,28.33 97.97,28.43 98.17,28.43 98.27,28.33 98.27,27.88 98.38,27.76 98.54,27.76 98.66,27.88 98.66,28.27 98.76,28.37 98.94,28.37 99.06,28.25 99.06,28.04 99.19,27.92 v1(99.27,27.92) 99.6,27.92 99.62,27.89 104.8,27.89 105.15,27.55 105.73,27.55 106.2,27.08 107.52,27.08 107.56,27.04 108.06,27.04 108.41,27.39 110.56,27.39 110.71,27.24 111.52,27.24 111.67,27.09 113.63,27.09 114.27,27.73 115.44,27.73 116.07,28.36 v4(116.45,28.36)
  IN4 w0.076: v1(93.04,27.52) 93.16,27.64 93.78,27.64 94.19,27.22 94.33,27.22 94.43,27.32 94.43,27.47 93.77,28.13 92.02,28.13 91.84,27.95 91.36,27.95 91.18,28.13 89.45,28.13 89.27,28.32 89.08,28.32 89.01,28.39 89.01,28.61 88.93,28.69 88.78,28.69 88.7,28.61 88.7,28.39 88.62,28.32 v4(88.31,28.32) 88.11,28.51 88.11,28.65 87.99,28.77 87.6,28.77 86.64,27.81 86.05,27.81 85.34,27.09 83.47,27.09 83.11,27.45 82.47,27.45 82.18,27.73 80.78,27.73 v1(80.54,27.97) ; 114.69,48.73 115.74,48.73 116.41,49.4 119.54,49.4 119.79,49.15 119.79,47.66 ; v1(121.39,27.52) 121.58,27.33 122.76,27.33 122.89,27.46 122.89,27.76 122.76,27.89 118.61,27.89 118.13,28.37 116.47,28.37 v4(116.45,28.36) 116.1,28.36 115.46,27.71 115.1,27.71 114.55,27.15 112.09,27.15 112.06,27.12 111.12,27.12 110.76,27.47 109.37,27.47 v1(108.86,27.97) ; 126.45,48.64 125.92,48.64 125.3,48.02 124.24,48.02 123.62,47.41 120.05,47.41
  IN4 w0.086: 114.69,48.73 114.65,48.69 ; v1(126.46,48.65) 126.45,48.64 ; 120.05,47.41 119.79,47.66
  IN4 w0.145: v1(99.27,27.92) 99.2,27.98 99.2,31.08 99.51,31.38 99.51,39.82 106.11,46.41 106.61,46.41 106.76,46.27 106.76,45.59 106.9,45.44 107.19,45.44 107.34,45.59 107.34,46.27 107.48,46.41 112.37,46.41 114.65,48.69
  BOTTOM w0.076: UCPU1.AY41 126.86,49.04 v1(126.46,48.65)
DDR_A_CAS#: length 128
  TOP w0.076: RD97.1 104.04,32.97 v1(105.43,31.59)
  TOP w0.102: v1(92.97,29.88) 92.7,29.88 92.6,29.78 UD29.K3 ; UD28.K3 80.19,29.65 80.19,29.69 v1(80.41,29.91) ; v1(108.73,29.91) 108.31,29.5 UD31.K3 ; UD32.K3 120.95,29.45 120.95,29.51 v1(121.32,29.88)
  IN1 w0.076: v4(87.66,31.83) 87.96,31.83 88.37,31.42 89.4,31.42 90.35,30.48 92.68,30.48 93.27,31.07 97.15,31.07 97.63,31.55 105.39,31.55 v1(105.43,31.59) 105.95,31.59 106.18,31.36 106.18,31.29 106.57,30.9 106.71,30.9 106.77,30.96 106.77,31.23 106.84,31.29 106.96,31.29 107.17,31.09 109.63,31.09 109.76,31.22 109.76,31.76 109.88,31.89 110.11,31.89 110.24,31.76 110.24,31.45 110.55,31.14 110.55,29.7 110.69,29.55 111.47,29.55 111.57,29.66 111.57,29.87 111.18,30.26 111.18,30.43 111.3,30.55 111.47,30.55 111.75,30.27 112.27,30.27 112.42,30.11 113.68,30.11 114.11,30.55 114.11,31.15 114.24,31.28 114.98,31.28 115.31,30.95 116.1,30.95 116.49,31.35 116.49,31.71 116.37,31.83 v4(115.98,31.83)
  IN4 w0.076: v1(92.97,29.88) 93.13,30.04 93.36,30.04 93.84,30.52 93.84,31.01 93.58,31.28 93.06,31.28 92.96,31.18 92.96,30.72 92.8,30.57 91.44,30.57 90.58,31.43 90.08,31.43 89.85,31.66 88.36,31.66 88.19,31.83 v4(87.66,31.83) 86.47,31.83 85.98,31.35 85.98,30.42 85.49,29.92 84.52,29.92 84.09,29.49 82.99,29.49 82.88,29.37 81.71,29.37 81.17,29.91 v1(80.41,29.91) ; 130.73,42.96 131.37,43.6 131.63,43.6 132.24,44.21 132.24,50.37 v1(131.18,51.42) ; v1(108.73,29.91) 109.49,29.91 109.96,29.44 111.27,29.44 111.31,29.49 112.41,29.49 112.84,29.92 113.74,29.92 114.52,30.7 114.52,31.38 114.96,31.83 v4(115.98,31.83) 117.64,31.83 118.08,31.39 118.98,31.39 119.74,30.62 121.18,30.62 121.28,30.72 121.28,31.18 121.38,31.28 121.83,31.28 122.15,30.96 122.15,30.53 121.81,30.19 121.62,30.19 v1(121.32,29.88)
  IN4 w0.145: v1(105.43,31.59) 105.67,31.83 107.34,31.83 107.5,31.99 107.5,32.65 108.64,33.79 109.15,33.79 109.33,33.97 109.33,35.7 109.14,35.89 107.97,35.89 107.85,36.01 107.85,36.35 107.95,36.44 108.19,36.44 108.43,36.68 108.9,36.68 108.9,36.68 109.07,36.68 109.2,36.81 109.2,37.16 108.81,37.56 108.81,37.72 108.93,37.84 109.71,37.84 109.86,37.7 109.86,37.12 110,36.98 110,36.98 110.29,36.98 110.44,37.13 110.44,37.74 110.54,37.84 112.79,37.84 112.93,37.7 112.93,37.26 113.13,37.07 113.34,37.07 113.48,37.21 113.48,37.21 113.48,37.71 113.61,37.83 113.9,37.83 114.06,37.68 114.06,37.21 114.21,37.07 114.5,37.07 114.64,37.21 114.64,37.7 114.77,37.83 116.84,37.83 117.09,37.59 117.53,37.59 117.61,37.51 121.55,37.51 122.24,38.2 122.24,38.69 122.4,38.86 126.63,38.86 130.73,42.96
  BOTTOM w0.076: UCPU1.AU34 131.45,51.42 v1(131.18,51.42)
DDR_A_CKE0: length 130.3
  TOP w0.076: v1(97.88,33.1) 98.65,33.86 RD69.1 ; UD29.K9 97.4,29.45
  TOP w0.102: UD32.K9 125.75,29.45 125.94,29.64 125.94,29.67 v1(126.12,29.85) ; 97.4,29.45 97.59,29.64 97.59,29.74 v1(97.71,29.85) ; UD31.K9 113.11,29.45 113.53,29.88 v1(113.53,30.53) ; v1(85.25,30.51) 85.25,29.92 UD28.K9
  IN1 w0.076: v4(89.41,32.77) 89.41,32.88 89.32,32.97 89.14,32.97 89.02,32.85 89.02,32.5 89.12,32.4 89.16,32.4 89.39,32.16 89.72,32.16 89.79,32.23 89.99,32.23 90.1,32.12 90.1,31.96 89.96,31.82 89.96,31.7 90.12,31.54 90.26,31.54 90.33,31.6 90.33,31.71 90.47,31.85 90.64,31.85 90.72,31.78 90.72,31.61 90.61,31.5 90.61,31.15 90.71,31.05 90.91,31.05 91.01,31.15 91.01,31.75 91.11,31.85 91.72,31.85 91.81,31.76 91.81,31.29 92.02,31.09 92.42,31.09 92.61,31.28 92.61,31.46 92.69,31.54 92.84,31.54 92.96,31.65 92.96,31.81 92.84,31.92 92.74,31.92 92.61,32.04 92.61,32.74 92.71,32.84 93.34,32.84 93.44,32.74 93.44,32.48 93.51,32.41 93.8,32.41 93.88,32.49 93.88,32.79 93.98,32.89 94.16,32.89 94.26,32.79 94.26,32.35 93.93,32.02 93.93,31.71 94.01,31.63 94.48,31.63 94.59,31.74 94.59,31.88 94.48,31.99 94.48,32.09 94.64,32.26 94.64,32.79 94.75,32.89 97.19,32.89 97.65,32.42 98.46,32.42 98.58,32.54 98.58,32.71 98.46,32.83 97.95,32.83 97.88,32.89 v1(97.88,33.1) 98.34,33.55 98.62,33.55 98.89,33.29 105.4,33.29 105.86,33.75 106.49,33.75 106.75,33.49 108.21,33.49 108.36,33.34 111.02,33.34 111.5,32.86 113.89,32.86 114.04,33.01 116.96,33.01 117.19,32.77 v4(117.76,32.77)
  IN4 w0.076: v1(97.71,29.85) 97.08,29.22 95.04,29.22 94.62,29.65 94.62,29.82 94.21,30.22 94.21,31.16 93.7,31.66 93.06,31.66 92.88,31.84 90.16,31.84 89.68,32.32 89.68,32.51 v4(89.41,32.77) 89.15,32.77 88.94,32.98 88.15,32.98 88.08,32.91 88.08,32.44 88,32.36 87.85,32.36 87.77,32.44 87.77,32.91 87.7,32.98 87.54,32.98 87.47,32.91 87.47,32.44 87.39,32.36 87.24,32.36 87.16,32.44 87.16,32.91 87.09,32.98 86.93,32.98 86.86,32.91 86.86,32.44 86.78,32.36 86.63,32.36 86.55,32.44 86.55,32.91 86.48,32.98 86.12,32.98 85.98,32.84 85.98,32.73 86.17,32.54 86.17,32.43 86.06,32.33 85.95,32.33 85.76,32.52 85.66,32.52 85.57,32.43 85.57,31.14 85.44,31 85.06,31 84.99,30.94 84.99,30.77 v1(85.25,30.51) ; 114.55,50.08 114.84,50.37 119.92,50.37 121.21,51.66 124.53,51.66 v1(124.88,51.3) ; v1(113.53,30.53) 113.79,30.53 113.92,30.67 113.92,31.98 114,32.06 114.05,32.06 114.13,32.14 114.13,32.29 114.05,32.36 114,32.36 113.92,32.44 113.92,32.56 114.34,32.98 114.77,32.98 114.85,32.9 114.85,32.45 114.93,32.37 115.08,32.37 115.15,32.45 115.15,32.9 115.23,32.98 115.38,32.98 115.46,32.9 115.46,32.44 115.54,32.36 115.69,32.36 115.76,32.44 115.76,32.9 115.84,32.98 115.99,32.98 116.07,32.9 116.07,32.44 116.15,32.36 116.3,32.36 116.37,32.44 116.37,32.9 116.45,32.98 116.6,32.98 116.68,32.9 116.68,32.63 116.76,32.55 116.91,32.55 116.98,32.63 116.98,32.9 117.06,32.98 117.21,32.98 117.42,32.77 v4(117.76,32.77) 118.69,31.84 121.49,31.84 121.7,31.64 122.05,31.64 122.55,31.13 122.55,30.18 123.29,29.44 125.71,29.44 v1(126.12,29.85)
  IN4 w0.145: v1(97.88,33.1) 97.62,33.36 97.62,35.51 98.16,36.05 98.16,40.33 105.7,47.87 112.34,47.87 114.55,50.08
  BOTTOM w0.076: UCPU1.AU43 125.03,51.3 v1(124.88,51.3)
DDR_A_CKE1: length 127.6
  TOP w0.076: RD87.1 99,34.75 v1(98.01,33.76) ; UD29.J9 97.4,30.25
  TOP w0.102: v1(125.4,29.85) 125.75,30.2 125.75,30.21 UD32.J9 ; v1(96.91,29.85) 97.3,30.25 97.4,30.25 ; UD28.J9 84.79,30.25 84.79,30.02 84.69,29.92 84.51,29.92 84.42,30.02 v1(84.42,30.59) ; v1(112.74,30.59) 112.74,30.09 112.84,29.99 113.01,29.99 113.11,30.09 113.11,30.25 UD31.J9
  IN1 w0.076: v4(89.05,33.31) 89.18,33.44 89.95,33.44 90.19,33.2 90.26,33.2 90.34,33.12 90.34,32.91 90.47,32.78 90.63,32.78 90.7,32.84 90.7,33.08 90.78,33.17 90.91,33.17 91,33.08 91,32.75 91.13,32.63 91.69,32.63 91.81,32.75 91.81,32.97 91.91,33.07 92.16,33.07 92.29,32.93 92.51,32.93 92.63,33.05 92.71,33.05 92.87,33.2 92.87,33.45 92.99,33.58 92.99,34.26 93.1,34.36 93.64,34.36 93.74,34.26 93.74,33.55 93.64,33.45 93.39,33.45 93.29,33.35 93.29,33.19 93.39,33.09 94.09,33.09 94.19,33.19 94.19,34.26 94.29,34.36 94.49,34.36 94.6,34.26 94.6,33.19 94.7,33.09 94.9,33.09 95,33.19 95,34.26 95.1,34.36 95.31,34.36 95.41,34.26 95.41,33.19 95.51,33.09 95.73,33.09 95.83,33.19 95.83,33.26 95.95,33.38 96.12,33.38 96.23,33.26 96.23,33.19 96.34,33.09 96.54,33.09 96.64,33.19 96.64,33.27 96.76,33.39 96.93,33.39 97.05,33.27 97.05,33.21 97.16,33.1 97.32,33.1 97.43,33.21 97.43,34.05 97.62,34.24 97.9,34.24 98.01,34.13 v1(98.01,33.76) 98.56,33.76 98.72,33.92 106.4,33.92 106.73,34.25 107.25,34.25 107.58,33.93 108.06,33.93 108.49,33.5 111.16,33.5 111.6,33.06 113.8,33.06 114.05,33.31 v4(117.44,33.31)
  IN4 w0.076: 123.66,49.65 124.02,50 v1(124.87,50) ; 114.77,49.82 115.13,50.18 120.81,50.18 ; v1(96.91,29.85) 96.52,29.47 95.14,29.47 94.82,29.78 94.82,29.9 94.41,30.31 94.41,31.76 93.51,32.65 90.73,32.65 89.98,33.4 89.14,33.4 v4(89.05,33.31) 88.73,33.31 88.65,33.39 88.65,33.44 88.58,33.52 88.43,33.52 88.35,33.44 88.35,33.39 88.27,33.31 88.12,33.31 88.04,33.39 88.04,33.44 87.97,33.52 87.82,33.52 87.74,33.44 87.74,33.39 87.66,33.31 87.51,33.31 87.43,33.39 87.43,33.44 87.36,33.52 87.21,33.52 87.13,33.44 87.13,33.39 87.05,33.31 86.06,33.31 85.72,32.97 84.93,32.97 84.83,32.87 84.83,32.71 84.73,32.61 84.52,32.61 84.42,32.71 84.42,32.87 84.32,32.97 84.12,32.97 84,32.86 84,31.92 84.1,31.82 84.68,31.82 84.78,31.71 84.78,31.13 84.68,31.03 84.1,31.03 84,30.93 84,30.68 84.1,30.59 v1(84.42,30.59) ; v1(125.4,29.85) 125.13,29.59 123.45,29.59 123.25,29.8 123.25,29.8 122.76,30.29 122.76,31.71 121.85,32.62 119.19,32.62 118.84,32.97 118.16,32.97 117.82,33.31 v4(117.44,33.31) 116.97,33.31 116.89,33.23 116.89,33.22 116.81,33.15 116.66,33.15 116.58,33.22 116.58,33.23 116.51,33.31 116.36,33.31 116.28,33.23 116.28,33.22 116.2,33.15 116.05,33.15 115.98,33.22 115.98,33.23 115.9,33.31 115.75,33.31 115.67,33.23 115.67,33.22 115.59,33.15 115.44,33.15 115.37,33.22 115.37,33.23 115.29,33.31 115.14,33.31 115.06,33.23 115.06,33.22 114.98,33.15 114.83,33.15 114.76,33.22 114.76,33.23 114.68,33.31 114.38,33.31 114.04,32.97 113.25,32.97 113.15,32.87 113.15,32.71 113.05,32.61 112.84,32.61 112.74,32.71 112.74,32.87 112.64,32.97 112.44,32.97 112.32,32.86 112.32,31.92 112.42,31.82 113,31.82 113.1,31.71 113.1,31.13 113,31.03 112.42,31.03 112.32,30.93 112.32,30.68 112.42,30.59 v1(112.74,30.59)
  IN4 w0.086: 123.66,49.65 121.34,49.65 120.81,50.18
  IN4 w0.145: 114.77,49.82 112.3,47.35 105.66,47.35 98.53,40.22 98.53,37.58 98.53,37.58 98.53,34.74 98.29,34.49 98.29,34.23 98.53,33.99 98.53,33.67 98.43,33.57 98.2,33.57 v1(98.01,33.76)
  BOTTOM w0.076: UCPU1.AW43 125.18,50.3 124.88,50 v1(124.87,50)
DDR_A_CS0#: length 125.6
  TOP w0.076: v1(105.69,29.83) 104.33,31.19 RD61.1
  TOP w0.102: UD32.L2 120.15,28.65 120.15,28.45 120.22,28.37 120.34,28.37 120.56,28.6 v1(120.56,29.12) ; v1(107.89,28.24) 107.51,28.62 UD31.L2 ; UD29.L2 91.8,28.65 92.16,28.65 92.22,28.71 v1(92.22,29.12) ; v1(79.57,28.24) 79.19,28.62 UD28.L2
  IN1 w0.076: v4(115.99,30.1) 117.14,30.1 118.02,30.98 118.02,31.34 118.36,31.68 118.98,31.68 119.09,31.56 119.09,31.4 118.98,31.29 118.55,31.29 118.43,31.17 118.43,30.87 118.01,30.45 117.5,29.95 116.83,29.28 115.66,29.28 115.45,29.49 115.07,29.49 114.15,28.57 113.19,28.57 112.82,28.94 109.2,28.94 109.02,28.76 108.7,28.76 108.29,29.17 107.74,29.17 107.65,29.26 106.93,29.26 106.56,29.63 105.92,29.63 105.72,29.83 v1(105.69,29.83) 104.93,29.83 104.8,29.96 98.73,29.96 98.01,29.24 93.71,29.24 93.19,28.72 91.27,28.72 90.34,29.65 90.08,29.65 89.59,30.14 87.71,30.14 87.53,29.96 v4(87.35,29.96)
  IN4 w0.076: v1(92.22,29.12) 92.36,29.26 92.59,29.26 92.66,29.19 92.66,28.82 92.59,28.74 91.25,28.74 90.03,29.96 89.91,29.96 89.84,30.04 89.84,30.11 89.76,30.19 89.61,30.19 89.53,30.11 89.53,30.04 89.45,29.96 89.3,29.96 89.23,30.04 89.23,30.24 89.15,30.32 89,30.32 88.92,30.24 88.92,30.04 88.85,29.96 88.69,29.96 88.62,30.04 88.62,30.24 88.54,30.32 88.39,30.32 88.31,30.24 88.31,30.04 88.24,29.96 88.08,29.96 88.01,30.04 88.01,30.24 87.93,30.32 87.71,30.32 v4(87.35,29.96) 87.18,29.96 85.82,28.6 85.23,28.6 85.2,28.63 83.29,28.63 83.21,28.55 83.21,28.54 82.06,28.54 81.88,28.36 79.68,28.36 v1(79.57,28.24) ; v1(131.44,53.15) 132.12,53.15 132.8,52.47 132.8,44.39 ; v1(107.89,28.24) 108.62,28.24 108.72,28.34 109.29,28.34 109.63,28.68 112.62,28.68 112.73,28.56 114.2,28.56 115.74,30.1 v4(115.99,30.1) 116.34,30.1 116.42,30.02 116.42,29.25 116.49,29.17 116.65,29.17 116.72,29.25 116.72,30.02 116.8,30.1 116.95,30.1 117.03,30.02 117.03,29.78 117.1,29.71 117.26,29.71 117.33,29.78 117.33,30.02 117.41,30.1 118,30.1 119.54,28.56 120.86,28.56 120.98,28.69 120.98,29.16 120.9,29.25 120.74,29.25 120.61,29.12 v1(120.56,29.12)
  IN4 w0.145: 132.8,44.39 132.8,43 127.32,37.51 123.47,37.51 121,35.04 119.3,35.04 119.21,35.13 112.95,35.13 112.79,34.98 111.75,34.98 111.54,34.76 111.54,34.41 110.29,33.16 110.29,32.36 109.07,31.14 108.6,31.14 108.31,30.85 108.31,30.48 108.07,30.24 106.1,30.24 v1(105.69,29.83)
  BOTTOM w0.076: v1(131.44,53.15) 131.7,53.41 UCPU1.AP33
DDR_A_CS1#: length 123
  TOP w0.076: v1(105.73,30.52) 104.17,32.08 RD88.1
  TOP w0.102: v1(91.41,29.13) 91,28.72 UD29.L1 ; UD31.L1 106.71,28.65 106.99,28.65 107.12,28.53 v1(107.12,28.25) ; v1(78.8,28.25) 78.8,28.53 78.67,28.65 UD28.L1 ; UD32.L1 119.35,28.72 v1(119.75,29.13)
  IN1 w0.076: v4(113.99,28.95) 114.25,28.95 114.56,29.27 114.56,29.41 114.39,29.58 114.39,29.73 114.54,29.87 114.68,29.87 114.83,29.72 115.01,29.72 115.07,29.79 115.07,29.8 115.1,29.82 115.49,29.82 115.61,29.94 115.61,30.11 115.49,30.23 114.32,30.23 113.8,29.71 113.68,29.71 113.58,29.61 113.58,28.88 113.48,28.77 113.28,28.77 113.18,28.88 113.18,29.61 113.07,29.71 112.89,29.71 112.79,29.61 112.79,29.25 112.69,29.15 109.44,29.15 109.34,29.25 109.34,29.44 109.44,29.54 110.04,29.54 110.14,29.64 110.14,29.78 110.04,29.88 109.61,29.88 109.5,29.99 109.5,30.13 109.61,30.23 110.03,30.23 110.14,30.34 110.14,30.5 110.03,30.61 109.49,30.61 109.12,30.24 109.12,29.76 108.89,29.53 108.26,29.53 108.11,29.38 107.83,29.38 107.74,29.47 107.01,29.47 106.65,29.83 106.15,29.83 106.09,29.9 106.09,30.09 106.16,30.16 106.48,30.16 106.56,30.24 106.56,30.33 106.37,30.52 v1(105.73,30.52) 98.94,30.52 97.87,29.45 93.34,29.45 93.3,29.49 92.7,29.49 92.68,29.51 90.8,29.51 90.45,29.85 90.16,29.85 89.55,30.47 88.02,30.47 87.91,30.57 87.29,30.57 v4(85.67,28.95)
  IN4 w0.076: v4(85.67,28.95) 87.07,30.35 87.38,30.35 87.51,30.48 90.45,30.48 90.75,30.19 90.75,29.79 v1(91.41,29.13) ; v1(132.33,52.43) 132.6,52.16 132.6,43.45 132.11,42.96 ; v1(107.12,28.25) 107.47,28.6 108.3,28.6 108.42,28.49 109.22,28.49 109.57,28.83 112.68,28.83 112.8,28.72 113.76,28.72 v4(113.99,28.95) 114.3,28.95 115.79,30.44 117.87,30.44 119.51,28.81 119.64,28.81 119.75,28.92 v1(119.75,29.13)
  IN4 w0.102: v4(85.67,28.95) 85.59,28.88 83.26,28.88 83.13,28.74 80.97,28.74 80.84,28.61 79.16,28.61 v1(78.8,28.25)
  IN4 w0.145: 132.11,42.96 127.03,37.89 123.31,37.89 121.27,35.84 120.71,35.84 120.7,35.85 119.94,35.85 119.93,35.86 119.46,35.86 119.31,35.71 118.31,35.71 118.18,35.84 118.18,36.42 118.04,36.56 117.75,36.56 117.6,36.42 117.6,35.84 117.59,35.84 117.46,35.71 117.04,35.71 116.8,35.47 116.46,35.47 116.22,35.71 115.88,35.71 115.64,35.47 115.3,35.47 115.06,35.71 114.72,35.71 114.48,35.47 114.14,35.47 113.9,35.71 113.56,35.71 113.32,35.47 112.98,35.47 112.74,35.71 112.23,35.71 112.12,35.83 111.47,35.83 111.29,35.65 111.29,34.7 109.96,33.36 109.96,32.38 108.97,31.39 108.51,31.39 108.19,31.07 107.76,31.07 107.69,31.14 106.46,31.14 105.85,30.52 v1(105.73,30.52)
  BOTTOM w0.076: UCPU1.AR32 132.65,52.76 v1(132.33,52.43)
DDR_A_D0: length 49.1
  TOP w0.102: UD28.G2 79.25,31.85 v1(79.61,31.49)
  IN2 w0.152: v1(109.38,56.15) 108.6,56.92 106.92,56.92 106.65,57.19 103.11,57.19 97.51,51.59 96.23,51.59 83.43,38.8 81.57,38.8 79.76,36.99 79.76,33.84 79.14,33.21 79.14,32.1 79.61,31.62 v1(79.61,31.49)
  BOTTOM w0.076: UCPU1.AH63 112.66,57 112.56,56.91 109.77,56.91 109.38,56.52 v1(109.38,56.15)
DDR_A_D1: length 48.1
  TOP w0.102: v1(79.54,32.29) 79.19,32.64 UD28.F2
  IN2 w0.152: v1(108.78,56.16) 108.78,56.17 108.38,56.58 106.72,56.58 106.46,56.85 103.25,56.85 97.65,51.25 96.37,51.25 83.58,38.45 81.85,38.45 80.97,37.57 80.97,36.28 80.58,35.89 80.26,35.89 79.99,35.62 79.99,33.68 79.54,33.23 v1(79.54,32.29)
  BOTTOM w0.076: v1(108.78,56.16) 109.7,57.07 112.49,57.07 112.71,57.29 113.04,57.29 113.19,57.22 113.22,57.2 113.43,57.2 UCPU1.AH62
DDR_A_D2: length 49.1
  TOP w0.102: v1(83.62,32.23) 83.99,32.59 UD28.F8
  IN2 w0.076: v1(110.03,54.79) 110.03,54.16 108.94,53.07 108.94,50.42
  IN2 w0.152: v1(83.62,32.23) 84.01,32.62 85.53,32.62 87.07,34.16 87.07,37.14 93.83,43.91 93.83,45.4 94.04,45.61 94.26,45.61 94.75,45.12 94.97,45.12 95.19,45.34 95.19,45.55 94.69,46.05 94.69,46.26 94.91,46.48 95.12,46.48 95.62,45.98 95.83,45.98 96.05,46.2 96.05,46.41 95.55,46.91 95.55,47.12 95.77,47.34 95.99,47.34 96.48,46.84 96.7,46.84 96.91,47.06 96.91,47.28 96.42,47.77 96.42,47.99 96.89,48.46 106.98,48.46 108.94,50.42
  BOTTOM w0.076: UCPU1.AK63 112.85,55.52 112.59,55.52 112.47,55.4 111.08,55.4 110.47,54.79 v1(110.03,54.79)
DDR_A_D3: length 46
  TOP w0.102: v1(83.62,31.42) 83.26,31.05 UD28.H7
  IN2 w0.076: 108.73,50.87 108.73,53.11 109.27,53.65 v1(109.27,53.99)
  IN2 w0.152: 108.73,50.87 106.79,48.92 96.87,48.92 93.49,45.54 93.49,44.16 86.6,37.27 86.6,34.2 85.45,33.05 83.79,33.05 83.16,32.42 83.16,31.87 v1(83.62,31.42)
  BOTTOM w0.076: UCPU1.AK62 113.39,55.65 113.1,55.36 112.66,55.36 112.54,55.24 111.18,55.24 110.3,54.37 110.05,54.37 109.68,53.99 v1(109.27,53.99)
DDR_A_D4: length 47.9
  TOP w0.102: v1(80.56,34.15) 79.99,33.57 UD28.E3
  IN2 w0.152: v1(108.21,56.19) 107.75,56.19 107.5,55.93 107.5,52.6 105.72,50.83 96.43,50.83 83.72,38.11 81.99,38.11 81.31,37.43 81.31,34.9 v1(80.56,34.15)
  BOTTOM w0.076: UCPU1.AH61 113.89,57.38 113.23,57.38 113.13,57.44 113.09,57.46 112.64,57.46 112.42,57.24 109.26,57.24
  BOTTOM w0.089: v1(108.21,56.19) 109.26,57.24
DDR_A_D5: length 53.2
  TOP w0.102: v1(79.62,30.68) 79.99,31.05 UD28.H3
  IN2 w0.152: v1(109.94,56.17) 108.84,57.27 107.06,57.27 106.8,57.53 102.96,57.53 97.36,51.93 96.08,51.93 83.29,39.14 81.43,39.14 79.42,37.13 79.42,33.87 78.91,33.36 78.91,31.96 79.2,31.67 79.2,31.1 v1(79.62,30.68)
  BOTTOM w0.076: v1(109.94,56.17) 110.29,55.82 112.42,55.82 112.45,55.85 112.53,55.85 112.79,56.11 113.08,56.11 113.21,56.04 113.23,56.03 113.36,56.03 113.45,56.07 113.52,56.11 113.73,56.11 113.82,56.06 113.84,56.05 113.87,56.04 113.89,56.03 114.07,56.03 114.09,56.05 114.46,56.05 114.48,56.03 114.72,56.03 114.93,56.23 UCPU1.AH60
DDR_A_D6: length 45.9
  TOP w0.102: v1(84.38,31.42) 84.02,31.05 UD28.H8
  IN2 w0.076: v1(110.38,55.21) 110.52,55.07 110.52,53.58 109.16,52.22 109.16,49.97
  IN2 w0.152: v1(84.38,31.42) 84.8,31 85.46,31 87.53,33.07 87.53,37.07 98.46,47.99 107.18,47.99 109.16,49.97
  BOTTOM w0.076: UCPU1.AK61 113.93,55.75 113.8,55.89 113.74,55.91 113.69,55.94 113.56,55.94 113.54,55.93 113.54,55.93 113.46,55.89 113.46,55.89 113.4,55.87 113.2,55.87 113.15,55.89 113.04,55.94 112.85,55.94 112.6,55.69 112.52,55.69 112.41,55.58 110.75,55.58 v1(110.38,55.21)
DDR_A_D7: length 46.9
  TOP w0.102: UD28.F7 82.65,32.65 v1(82.5,32.5)
  IN2 w0.076: 108.52,51.32 108.52,53.42 v1(108.8,53.69)
  IN2 w0.152: v1(82.5,32.5) 83.47,33.47 85.44,33.47 86.14,34.17 86.14,38.92 96.61,49.39 106.6,49.39 108.52,51.32
  BOTTOM w0.076: v1(108.8,53.69) 108.86,53.63 109.56,53.63 110.06,54.14 110.32,54.14 111.26,55.07 112.61,55.07 112.73,55.19 113.17,55.19 113.33,55.36 113.75,55.36 113.87,55.48 114.14,55.48 114.15,55.46 114.4,55.46 114.69,55.75 UCPU1.AK60
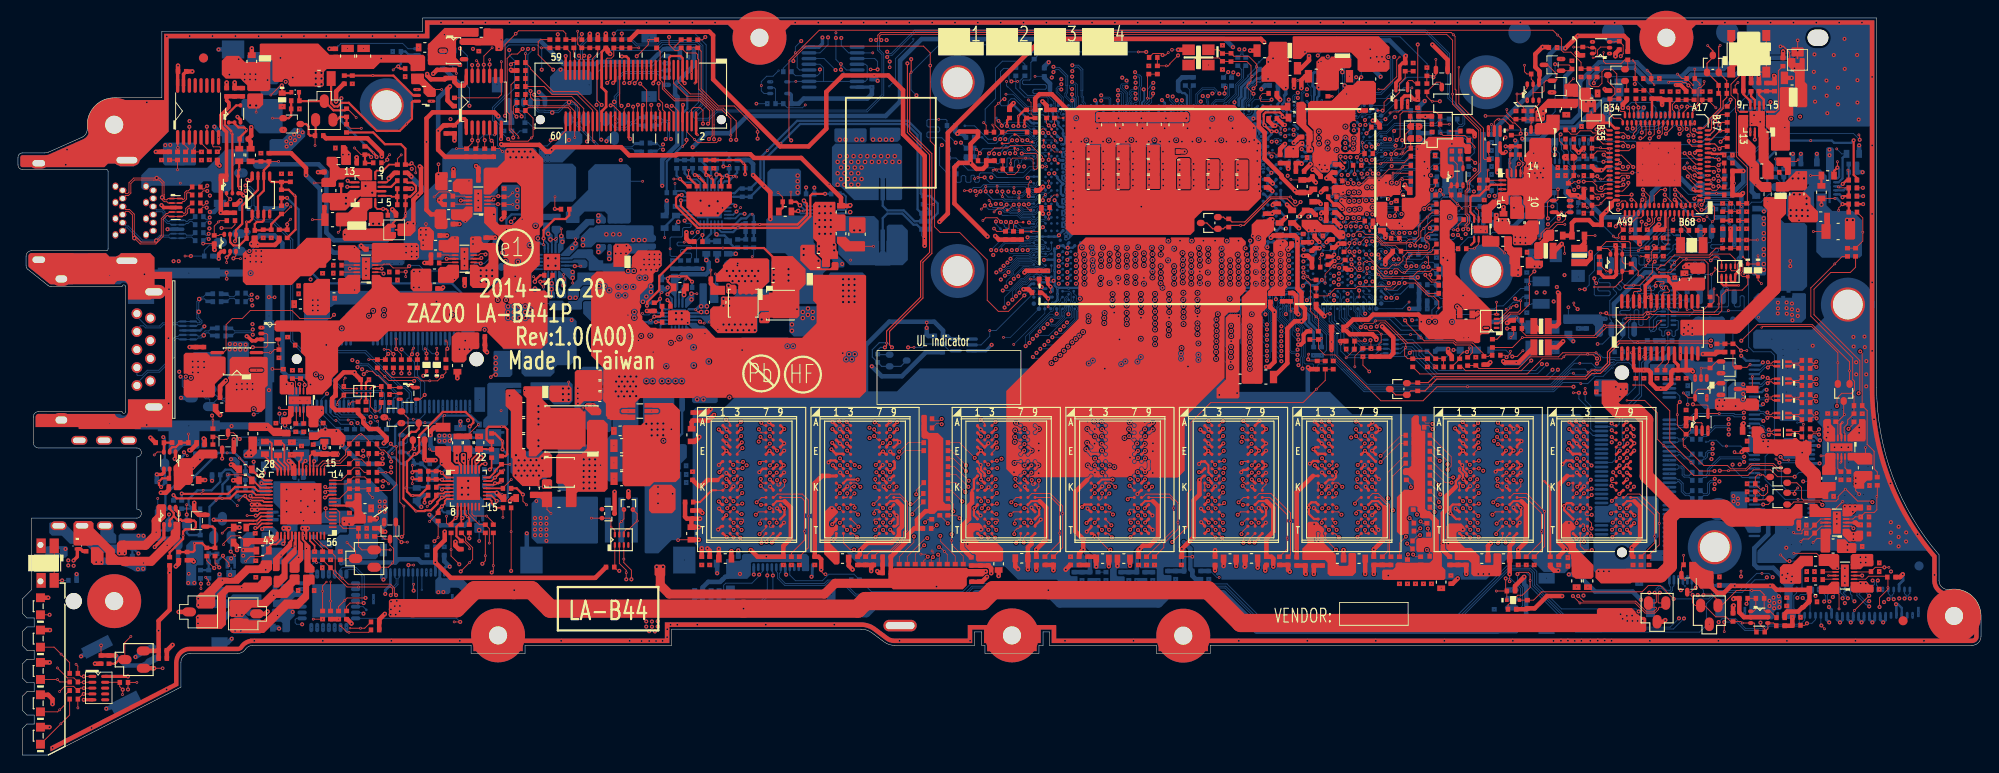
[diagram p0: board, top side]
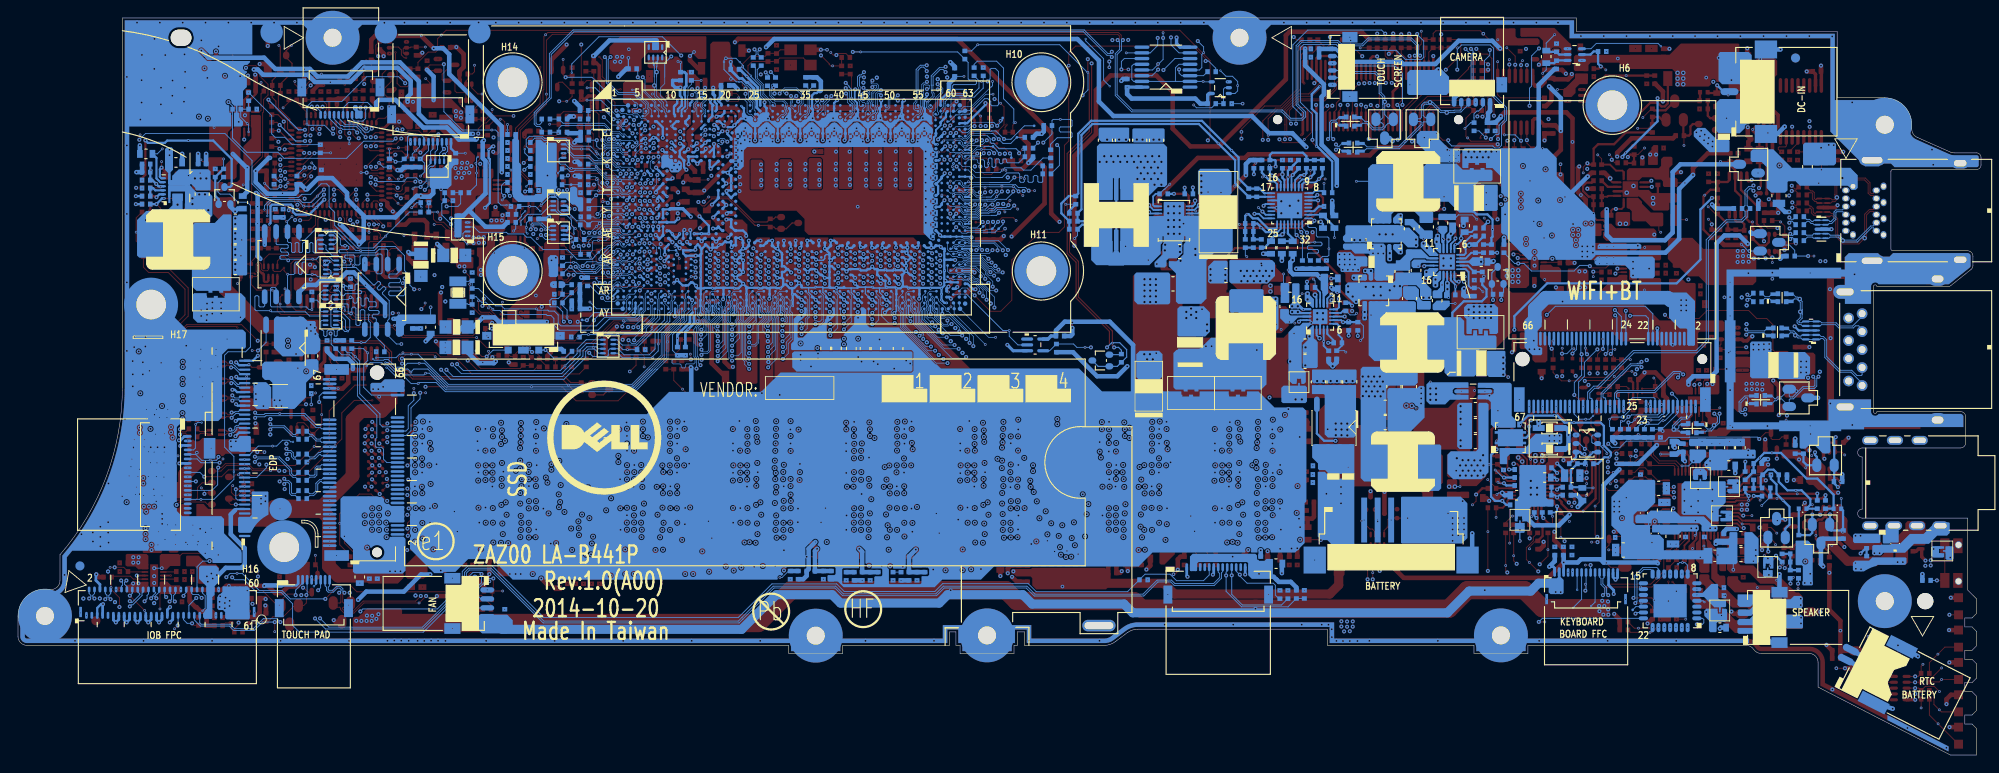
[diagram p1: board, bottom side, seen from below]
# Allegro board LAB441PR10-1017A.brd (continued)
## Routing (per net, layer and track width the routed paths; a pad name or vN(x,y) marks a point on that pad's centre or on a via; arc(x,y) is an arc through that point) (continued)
DDR_A_D8: length 42.3
  TOP w0.076: UD28.A3 79.99,36.66
  TOP w0.102: 79.99,36.66 v1(80.4,37.07)
  IN1 w0.119: v1(109.91,52.11) 109.91,51.41 104.9,46.4 92.72,46.4 85.27,38.95 80.74,38.95 80.4,38.61 v1(80.4,37.07)
  BOTTOM w0.076: UCPU1.AM63 112.91,54.5 111.39,54.5 110.71,53.82 110.71,53.51 109.91,52.7 v1(109.91,52.11)
DDR_A_D9: length 46
  TOP w0.102: UD28.C2 79.19,35.06 v1(78.79,35.47)
  IN1 w0.119: v1(78.79,35.47) 78.33,35.93 78.33,38.15 80.27,40.09 84.8,40.09 92.67,47.97 103.84,47.97 109.17,53.29 109.19,53.29 109.23,53.33 v1(109.76,53.33)
  BOTTOM w0.076: v1(109.76,53.33) 110.3,53.33 110.55,53.58 110.55,53.89 111.39,54.73 112.74,54.73 112.87,54.86 113.1,54.86 113.39,54.57 UCPU1.AM62
DDR_A_D10: length 41.3
  TOP w0.102: UD28.D7 83.21,34.25 v1(83.61,34.65)
  IN1 w0.119: v1(83.61,34.65) 83.23,35.03 83.23,36.5 83.06,36.67 83.06,37.28 83.3,37.52 87.55,37.52 94.68,44.65 105.16,44.65 107.88,47.38 108.61,47.38 110.59,49.36 v1(110.59,50.65)
  BOTTOM w0.076: UCPU1.AP63 112.54,53.22 112.01,52.69 111.69,52.69 110.59,51.58 v1(110.59,50.65)
DDR_A_D11: length 39.1
  TOP w0.102: v1(83.61,36.26) 83.99,35.87 UD28.B8
  IN1 w0.119: v1(83.61,36.26) 84.52,37.18 87.64,37.18 94.8,44.34 105.28,44.34 107.92,46.98 108.72,46.98 110.98,49.25 v1(110.98,51.05)
  BOTTOM w0.076: v1(110.98,51.05) 110.98,51.75 111.76,52.52 112.08,52.52 112.48,52.92 113.1,52.92 113.39,53.22 UCPU1.AP62
DDR_A_D12: length 44.8
  TOP w0.102: v1(78.76,37.31) 79.19,36.88 UD28.A2
  IN1 w0.119: v1(110.16,53.73) 110.16,53.06 104.12,47.02 92.22,47.02 84.94,39.74 80.41,39.74 78.76,38.09 v1(78.76,37.31)
  BOTTOM w0.076: UCPU1.AM61 114.15,54.46 113.75,54.86 113.33,54.86 113.17,55.03 112.8,55.03 112.67,54.9 111.31,54.9 110.33,53.91 110.33,53.9 v1(110.16,53.73)
DDR_A_D13: length 46.1
  TOP w0.102: v1(80.42,35.49) 79.99,35.06 UD28.C3
  IN1 w0.119: v1(109.52,51.68) 109.52,51.46 104.77,46.71 92.47,46.71 85.1,39.35 80.57,39.35 80.01,38.78 80.01,35.91 v1(80.42,35.49)
  BOTTOM w0.076: UCPU1.AM60 114.93,53.8 114.72,53.6 113.89,53.6 113.87,53.61 113.84,53.62 113.82,53.63 113.73,53.67 113.52,53.67 113.45,53.64 113.36,53.6 113.28,53.6 113.25,53.61 113.21,53.61 113.08,53.67 112.51,53.67 111.85,53.02 111.56,53.02 110.22,51.68 v1(109.52,51.68)
DDR_A_D14: length 40.6
  TOP w0.102: UD28.A7 82.98,36.65 v1(82.67,36.97)
  IN1 w0.119: v1(109.72,49.79) 109.72,49.09 108.37,47.75 107.81,47.75 105.03,44.96 94.55,44.96 87.46,37.87 83.09,37.87 82.67,37.45 v1(82.67,36.97)
  BOTTOM w0.076: UCPU1.AP61 114.04,53.22 113.8,53.46 113.74,53.48 113.69,53.51 113.56,53.51 113.54,53.5 113.54,53.5 113.46,53.46 113.46,53.46 113.4,53.44 113.2,53.44 113.15,53.46 113.04,53.51 112.58,53.51 111.92,52.85 111.62,52.85 109.72,50.95 v1(109.72,49.79)
DDR_A_D15: length 40.8
  TOP w0.102: UD28.C8 83.99,35.07 v1(83.61,35.45)
  IN1 w0.119: v1(111.38,51.44) 111.38,49.2 108.77,46.59 107.97,46.59 105.41,44.03 94.93,44.03 87.68,36.78 84.93,36.78 v1(83.61,35.45)
  BOTTOM w0.076: UCPU1.AP60 114.7,52.99 114.46,52.99 114.4,52.92 114.15,52.92 114.14,52.94 113.76,52.94 113.75,52.92 113.33,52.92 113.17,52.76 112.59,52.76 112.19,52.36 111.83,52.36 111.38,51.91 v1(111.38,51.44)
DDR_A_D16: length 37
  TOP w0.102: v1(95.47,31.45) 95.8,31.12 95.8,31.05 UD29.H7
  IN2 w0.076: 109.55,45.34 109.55,45.55 114.14,50.14 114.14,51 114.41,51.27 114.41,52.72 114.82,53.13 115.7,53.13 v1(115.75,53.08)
  IN2 w0.152: v1(95.47,31.45) 94.73,31.45 94.26,31.92 94.26,36.59 102.13,44.46 108.67,44.46 109.55,45.34
  BOTTOM w0.076: v1(115.75,53.08) 116.07,53.41 UCPU1.AP58
DDR_A_D17: length 35.6
  TOP w0.102: UD29.H8 96.58,31.05 96.58,31.05 v1(96.17,31.45)
  IN2 w0.076: 109.77,44.92 109.77,45.46 115.75,51.44 v1(115.75,52.43)
  IN2 w0.152: v1(96.17,31.45) 95.76,31.87 94.98,31.87 94.71,32.14 94.71,34.39 95.93,35.61 95.93,37.31 102.73,44.12 108.97,44.12 109.77,44.92
  BOTTOM w0.076: v1(115.75,52.43) 116.07,52.76 UCPU1.AR58
DDR_A_D18: length 42.6
  TOP w0.102: UD29.F2 91.77,32.65 v1(91.41,33.01)
  IN2 w0.076: v1(116.64,54.5) 116.18,54.95 116.18,55.69 115.89,55.98 115.58,55.98 112.48,52.87 112.48,50.93 110.27,48.72 109.76,48.72
  IN2 w0.152: 109.76,48.72 107.69,46.65 99.61,46.65 90.07,37.11 90.07,33.85 90.91,33.01 v1(91.41,33.01)
  BOTTOM w0.076: v1(116.64,54.5) 116.85,54.71 UCPU1.AM57
DDR_A_D19: length 43.4
  TOP w0.102: UD29.G2 91.66,31.99 91.66,32 v1(91.41,32.24)
  IN2 w0.076: 109.57,49.16 110.46,49.16 112.3,51 112.3,54.04 114.41,56.16 116.32,56.16 v1(116.65,55.83)
  IN2 w0.152: 109.57,49.16 107.4,46.99 99.46,46.99 89.84,37.37 89.84,33.67 91.27,32.24 v1(91.41,32.24)
  BOTTOM w0.076: v1(116.65,55.83) 116.83,56.01 UCPU1.AK57
DDR_A_D20: length 36.9
  TOP w0.076: UD29.E3 92.6,33.47
  TOP w0.102: 92.6,33.47 v1(92.21,33.87)
  IN2 w0.076: 115.4,55 112.83,52.43 112.83,50.33 108.84,46.34 108.48,46.34 108.11,45.97 107.6,45.97
  IN2 w0.089: 115.4,55 v1(115.76,55)
  IN2 w0.152: 107.6,45.97 100.8,45.97 92.63,37.79 92.63,34.29 v1(92.21,33.87)
  BOTTOM w0.076: v1(115.76,55) 116.07,55 116.2,55.12 UCPU1.AL58
DDR_A_D21: length 41
  TOP w0.076: UD29.H3 92.6,31.05
  TOP w0.102: 92.6,31.05 92.6,31.07 92.2,31.47 v1(92.2,31.47)
  IN2 w0.076: 107.6,46.31 108.2,46.31 108.45,46.56 108.74,46.56 112.65,50.47 112.65,52.71 115.55,55.61
  IN2 w0.089: v1(115.75,55.61) 115.55,55.61
  IN2 w0.152: 107.6,46.31 100.61,46.31 91.76,37.46 91.76,36.46 91.79,36.43 91.79,36.06 91.58,35.85 91.26,35.85 91.01,35.61 91.01,34.24 91.83,33.42 91.83,31.84 v1(92.2,31.47)
  BOTTOM w0.076: UCPU1.AK58 116.15,56.01 v1(115.75,55.61)
DDR_A_D22: length 36.9
  TOP w0.102: v1(96.99,32.25) 96.99,32.27 UD29.F8
  IN2 w0.076: 110.33,44.56 110.33,45.52 116.7,51.89 v1(116.7,52.43)
  IN2 w0.152: 110.33,44.56 108.04,42.27 107.77,42.27 107.61,42.42 107.61,43.27 107.46,43.42 107.16,43.42 107.01,43.27 107.01,42.42 106.85,42.27 106.55,42.27 106.4,42.42 106.4,43.27 106.24,43.42 105.94,43.42 105.79,43.27 105.79,42.42 105.63,42.27 102,42.27 98.16,38.43 98.16,35.52 97.47,34.83 97.47,33.49 96.99,33 v1(96.99,32.25)
  BOTTOM w0.076: UCPU1.AR57 117.02,52.76 v1(116.7,52.43)
DDR_A_D23: length 38.8
  TOP w0.102: UD29.F7 95.78,32.65 v1(95.4,32.27)
  IN2 w0.076: 110.08,44.85 110.08,45.51 116.11,51.55 116.11,53.15 v1(116.7,53.74)
  IN2 w0.152: 110.08,44.85 109,43.77 105.52,43.77 105.36,43.62 105.36,42.78 105.21,42.62 104.91,42.62 104.75,42.78 104.75,43.62 104.6,43.77 104.3,43.77 104.15,43.62 104.15,42.78 103.99,42.62 103.69,42.62 103.54,42.78 103.54,43.62 103.38,43.77 102.96,43.77 96.44,37.25 96.44,35.75 95.4,34.72 v1(95.4,32.27)
  BOTTOM w0.076: v1(116.7,53.74) 117.02,54.06 UCPU1.AN57
DDR_A_D24: length 35
  TOP w0.102: UD29.A3 92.58,36.65 v1(92.17,37.07)
  IN1 w0.076: 109,44.91 113.69,49.61 113.69,50.5 114.52,51.32 116.5,51.32 117.29,52.11 117.29,52.73 v1(117.65,53.08)
  IN1 w0.119: 109,44.91 108.68,44.91 106.76,42.99 96.54,42.99 92.21,38.66 92.21,37.11 v1(92.17,37.07)
  BOTTOM w0.076: UCPU1.AP55 117.98,53.41 v1(117.65,53.08)
DDR_A_D25: length 35.3
  TOP w0.102: UD29.C3 92.57,35.05 92.18,35.44 92.18,35.45 v1(92.19,35.45)
  IN1 w0.076: 109.03,44.56 115.6,51.13 116.56,51.13 117.65,52.23 v1(117.65,52.43)
  IN1 w0.119: 109.03,44.56 108.77,44.56 106.89,42.68 96.72,42.68 92.61,38.57 92.61,35.87 v1(92.19,35.45)
  BOTTOM w0.076: UCPU1.AR55 117.98,52.76 v1(117.65,52.43)
DDR_A_D26: length 36.2
  TOP w0.102: UD29.C8 96.6,35.06 v1(96.99,35.45)
  IN1 w0.076: v1(118.6,54.39) 118.96,54.03 118.96,53.62 119.14,53.45 119.14,50.81 117.98,49.66 116.68,49.66 116.09,49.06 116.09,48.51 112.39,44.81 111.54,44.81 110.13,43.4
  IN1 w0.119: 110.13,43.4 107.63,40.9 99.06,40.9 96.37,38.22 96.37,36.08 v1(96.99,35.45)
  BOTTOM w0.076: v1(118.6,54.39) 118.93,54.71 UCPU1.AM54
DDR_A_D27: length 36.3
  TOP w0.102: UD29.B8 96.6,35.87 v1(96.97,36.24)
  IN1 w0.076: v1(118.55,55.69) 119.03,55.21 119.03,54.21 119.14,54.1 119.14,53.7 119.31,53.52 119.31,50.73 118.06,49.48 116.75,49.48 116.26,48.99 116.26,48.44 112.26,44.44 111.65,44.44 110.52,43.3
  IN1 w0.119: 110.52,43.3 107.77,40.56 99.2,40.56 97.37,38.72 97.37,36.64 v1(96.97,36.24)
  BOTTOM w0.076: v1(118.55,55.69) 118.88,56.01 UCPU1.AK54
DDR_A_D28: length 39.1
  TOP w0.076: UD29.C2 91.8,35.07
  TOP w0.102: 91.8,35.07 v1(91.42,35.45)
  IN1 w0.076: 108.96,45.26 113.31,49.61 113.31,50.53 114.3,51.51 116.45,51.51 117.12,52.19 117.12,54.5 v1(117.65,55.04)
  IN1 w0.119: v1(91.42,35.45) 91.8,35.84 91.8,36.58 91.76,36.62 91.76,38.85 96.21,43.3 106.51,43.3 108.47,45.26 108.96,45.26
  BOTTOM w0.076: UCPU1.AL55 117.98,55.36 v1(117.65,55.04)
DDR_A_D29: length 38.6
  TOP w0.102: UD29.A2 91.79,36.65 v1(91.33,37.11)
  IN1 w0.076: 109.75,46.43 113.01,49.68 113.01,50.64 114.12,51.75 115.65,51.75 116.25,52.35 116.25,55.23 116.48,55.46 117.01,55.46 117.23,55.69 v1(117.6,55.69)
  IN1 w0.119: 109.75,46.43 109.47,46.14 108.12,46.14 105.59,43.61 95.87,43.61 91.3,39.04 91.3,37.14 v1(91.33,37.11)
  BOTTOM w0.076: UCPU1.AK55 117.93,56.01 v1(117.6,55.69)
DDR_A_D30: length 32.6
  TOP w0.102: v1(95.28,37) 95.45,37 UD29.A7
  IN1 w0.076: 115.74,50 117.83,50 118.6,50.77 v1(118.6,52.43)
  IN1 w0.086: 111.84,46.1 115.74,50
  IN1 w0.119: 111.84,46.1 107.34,41.6 98.64,41.6 95.58,38.54 95.58,37.31 v1(95.28,37)
  BOTTOM w0.076: v1(118.6,52.43) 118.93,52.76 UCPU1.AR54
DDR_A_D31: length 36.4
  TOP w0.102: v1(96.18,34.72) 95.8,34.34 UD29.D7
  IN1 w0.076: 109.73,43.5 111.36,45.13 112.46,45.13 115.91,48.59 115.91,49.14 116.61,49.83 117.91,49.83 118.96,50.88 118.96,53.38 v1(118.6,53.74)
  IN1 w0.119: 109.73,43.5 107.48,41.25 98.87,41.25 95.98,38.36 95.98,34.92 v1(96.18,34.72)
  BOTTOM w0.076: UCPU1.AN54 118.93,54.06 v1(118.6,53.74)
DDR_A_D32: length 25.8
  TOP w0.102: UD31.H3 108.3,31.05 v1(107.9,30.66)
  IN2 w0.076: v1(113.62,47.12) 112.19,47.12 110.91,45.85 110.91,43.62
  IN2 w0.152: 110.91,43.62 110.91,41.73 106.68,37.49 106.68,33.63 106.8,33.51 106.8,32.73 106.66,32.59 106.66,31.9 v1(107.9,30.66)
  BOTTOM w0.076: UCPU1.AY58 116.05,49.53 116.05,48.84 115.78,48.57 115.3,48.57 115.15,48.72 114.76,48.72 113.62,47.59 v1(113.62,47.12)
DDR_A_D33: length 21.1
  TOP w0.102: v1(108.88,34.2) 108.31,33.63 UD31.E3
  IN2 w0.152: v1(108.88,34.2) 109.25,34.57 109.25,36.75 111.94,39.44 111.94,44.81 112.48,45.35 v1(112.48,45.85)
  BOTTOM w0.076: UCPU1.AW58 115.87,50.01 115.87,48.9 115.71,48.74 115.37,48.74 115.07,49.04 114.76,49.04 112.48,46.76 v1(112.48,45.85)
DDR_A_D34: length 21.6
  TOP w0.102: UD31.F8 112.31,32.61 111.94,32.24 v1(111.94,32.23)
  IN2 w0.076: v1(116.3,47.7) 116.3,46.24 114.39,44.34 114.39,43.36 114.72,43.03 114.72,42.96
  IN2 w0.152: v1(111.94,32.23) 112.43,32.72 113.57,32.72 114.72,33.87 114.72,42.96
  BOTTOM w0.076: UCPU1.AY56 117.53,49.64 117.53,48.5 116.66,47.63 116.37,47.63 v1(116.3,47.7)
DDR_A_D35: length 23
  TOP w0.102: v1(111.94,31.42) 111.7,31.18 111.63,31.18 111.51,31.05 UD31.H7
  IN2 w0.076: v1(115.47,46.92) 115.47,45.92 114.08,44.53 114.08,43.38 114.26,43.19
  IN2 w0.152: v1(111.94,31.42) 111.87,31.42 111.46,31.83 111.46,32.46 112.31,33.31 112.31,34.34 112.5,34.53 112.5,36.39 114.26,38.14 114.26,43.19
  BOTTOM w0.076: UCPU1.AW56 117.52,50.06 117.81,49.77 117.81,49.53 117.7,49.41 117.7,48.43 117.66,48.39 116.19,46.92 v1(115.47,46.92)
DDR_A_D36: length 22.7
  TOP w0.102: UD31.F2 107.57,32.65 v1(107.9,32.32)
  IN2 w0.152: v1(107.9,32.32) 108.31,32.73 108.31,37.22 111.6,40.51 111.6,45.03 v1(112.07,45.49)
  BOTTOM w0.076: v1(112.07,45.49) 112.07,46.58 114.81,49.32 114.98,49.32 115.19,49.53 115.19,49.79 115.94,50.54 115.94,50.73 UCPU1.AV58
DDR_A_D37: length 27.7
  TOP w0.102: UD31.G2 107.57,31.85 v1(107.95,31.47)
  IN2 w0.076: v1(113.31,46.68) 111.99,46.68 111.26,45.94 111.26,43.27
  IN2 w0.152: v1(107.95,31.47) 107.5,31.93 107.5,36.89 111.26,40.65 111.26,43.27
  BOTTOM w0.076: UCPU1.AU58 116.92,51.6 117.12,51.39 117.12,50.54 117.1,50.49 117.07,50.44 117.07,50.16 117.09,50.12 117.12,50.05 117.12,49.89 117.06,49.76 117.06,49.46 117.17,49.34 117.17,48.77 117.04,48.64
  BOTTOM w0.089: v1(113.31,46.68) 114.63,46.68 116.6,48.64 117.04,48.64
DDR_A_D38: length 23.4
  TOP w0.102: v1(112.7,31.42) 112.67,31.42 112.31,31.05 UD31.H8
  IN2 w0.076: v1(116.66,48.13) 116.66,46.22 114.57,44.14 114.57,43.43 114.77,43.24 115.06,43.24 115.19,43.11 115.19,42.96
  IN2 w0.152: v1(112.7,31.42) 113.05,31.76 113.85,31.76 115.19,33.11 115.19,42.96
  BOTTOM w0.076: UCPU1.AV56 117.41,50.61 117.28,50.47 117.27,50.46 117.24,50.39 117.24,50.2 117.27,50.13 117.29,50.1 117.29,49.83 117.27,49.82 117.23,49.71 117.23,49.53 117.34,49.41 117.34,48.69 116.78,48.13 v1(116.66,48.13)
DDR_A_D39: length 23.7
  TOP w0.102: UD31.F7 110.97,32.65 v1(110.82,32.5)
  IN2 w0.152: v1(115.04,46.48) 115.04,45.93 113.38,44.27 113.38,38.58 111.47,36.67 111.47,33.15 v1(110.82,32.5)
  BOTTOM w0.076: UCPU1.AU56 117.41,51.36 117.7,51.07 117.7,50.83 117.7,50.82 117.7,50.53 117.97,50.26 117.97,49.46 117.86,49.34 117.86,48.26 116.08,46.48 v1(115.04,46.48)
DDR_A_D40: length 19.1
  TOP w0.102: UD31.A2 107.51,36.87 v1(107.07,37.31)
  IN1 w0.119: v1(112.87,44.28) 112.87,44.27 112.17,43.57 112.17,42.37 107.51,37.71 107.47,37.71 v1(107.07,37.31)
  BOTTOM w0.076: UCPU1.AY54 118.47,49.52 118.47,49.25 118.36,49.14 118.36,48.05 114.44,44.14 113.02,44.14 v1(112.87,44.28)
DDR_A_D41: length 20.8
  TOP w0.102: UD31.C2 v1(107.9,35.45)
  IN1 w0.076: 112.58,43.42 113.69,44.53
  IN1 w0.086: 113.69,44.53 v1(113.69,45.19) ; 112.58,43.27 112.58,43.42
  IN1 w0.119: 112.58,43.27 112.58,42.29 107.91,37.62 107.91,35.45 v1(107.9,35.45)
  BOTTOM w0.076: UCPU1.AW54 118.6,50.06 118.3,49.77 118.3,49.32 118.19,49.21 118.19,48.12 115.26,45.19 v1(113.69,45.19)
DDR_A_D42: length 18.2
  TOP w0.102: UD31.B8 112.31,35.88 111.93,36.26 111.93,36.26 v1(111.93,36.26)
  IN1 w0.119: v1(116.32,44.98) 116.32,42.03 113.3,39.01 113.3,36.9 112.66,36.26 v1(111.93,36.26)
  BOTTOM w0.076: v1(116.32,44.98) 117.11,44.98 119.82,47.68 119.82,49.52 UCPU1.AY52
DDR_A_D43: length 21.5
  TOP w0.102: UD31.D7 111.59,34.25 v1(111.93,34.59)
  IN1 w0.119: v1(111.93,34.59) 111.46,35.06 111.46,36.34 111.77,36.65 112.62,36.65 112.99,37.03 112.99,39.14 115.6,41.75 115.6,43.86 v1(115.4,44.06)
  BOTTOM w0.076: UCPU1.AW52 120.18,50.07 120.18,49.85 120.19,49.82 120.2,49.79 120.2,49.79 120.21,49.76 120.23,49.72 120.23,49.72 120.24,49.71 120.24,49.52 119.99,49.27 119.99,47.62 116.43,44.06 v1(115.4,44.06)
DDR_A_D44: length 21.5
  TOP w0.102: UD31.C3 108.31,35.07 108.73,35.49 v1(108.81,35.49)
  IN1 w0.076: 112.93,42.96 112.93,43.51 114.15,44.73
  IN1 w0.086: v1(114.15,45.62) 114.15,44.73
  IN1 w0.119: 112.93,42.96 112.93,42.14 108.26,37.48 108.26,35.98 108.74,35.49 v1(108.81,35.49)
  BOTTOM w0.076: v1(114.15,45.62) 115.45,45.62 118.03,48.19 118.03,49.27 118.14,49.39 118.14,50.26 118.7,50.82 UCPU1.AV54
DDR_A_D45: length 20.9
  TOP w0.102: v1(108.72,37.07) 108.31,36.66 UD31.A3
  IN1 w0.076: v1(119.05,48.27) 118.07,48.27 113.27,43.47 113.27,43.21
  IN1 w0.119: v1(108.72,37.07) 108.72,37.44 113.27,42 113.27,43.21
  BOTTOM w0.076: v1(119.05,48.27) 119.49,48.71 119.49,49.75 119.52,49.8 119.56,49.91 119.56,50.04 119.52,50.14 119.49,50.17 119.49,50.41 119.53,50.49 119.56,50.54 119.56,50.56 119.56,51.4 119.36,51.6 UCPU1.AU54
DDR_A_D46: length 19.8
  TOP w0.102: v1(111.93,35.4) 112.27,35.05 UD31.C8
  IN1 w0.119: v1(111.93,35.4) 112.11,35.4 113.61,36.9 113.61,38.89 116.78,42.05 v1(116.78,45.44)
  BOTTOM w0.076: UCPU1.AV52 119.84,50.61 119.71,50.47 119.68,50.42 119.66,50.36 119.66,50.24 119.73,50.08 119.73,49.87 119.66,49.71 119.66,47.76 117.33,45.44 v1(116.78,45.44)
DDR_A_D47: length 20.8
  TOP w0.102: UD31.A7 111.3,36.65 v1(110.99,36.97)
  IN1 w0.119: v1(114.94,43.6) 115.22,43.32 115.22,41.8 112.68,39.27 112.68,37.88 111.77,36.97 v1(110.99,36.97)
  BOTTOM w0.076: UCPU1.AU52 119.95,51.35 120.34,50.95 120.34,49.88 120.36,49.85 120.36,49.84 120.38,49.8 120.38,49.8 120.38,49.8 120.41,49.75 120.41,49.46 120.15,49.2 120.15,47.54 116.2,43.6 v1(114.94,43.6)
DDR_A_D48: length 38.7
  TOP w0.102: v1(119.76,32.23) 120,31.99 120.01,31.99 UD32.G2
  IN2 w0.076: 130.14,45.93 129.23,46.83 129.23,51.27 128.22,52.28 128.22,54.21 127.08,55.34 v1(127.08,55.69)
  IN2 w0.152: 130.14,45.93 130.14,32.83 126.53,29.22 124.87,29.22 124.65,29.44 124.27,29.44 124.17,29.33 123.24,29.33 122.33,30.24 121.52,30.24 121.21,30.55 120.96,30.55 120.19,31.31 120.19,31.8 v1(119.76,32.23)
  BOTTOM w0.076: v1(127.08,55.69) 127.41,56.01 UCPU1.AK40
DDR_A_D49: length 37.1
  TOP w0.102: v1(120.61,31.45) 120.61,31.45 120.95,31.12 UD32.H3
  IN2 w0.076: 129.8,45.88 129.05,46.62 129.05,51.2 128.04,52.21 128.04,54.14 126.44,55.74 v1(126.17,55.74)
  IN2 w0.152: v1(120.61,31.45) 121.58,31.45 123.46,29.56 124.07,29.56 124.17,29.66 124.75,29.66 124.84,29.57 124.96,29.45 126.27,29.45 129.8,32.97 129.8,45.88
  BOTTOM w0.076: v1(126.17,55.74) 126.44,56.01 UCPU1.AK42
DDR_A_D50: length 32.3
  TOP w0.102: v1(119.78,33) 119.78,33.02 120.14,32.65 UD32.F2
  IN2 w0.076: 125.99,46 124.39,47.61 124.39,51.42 124.85,51.88 124.85,54.14 v1(125.22,54.51)
  IN2 w0.089: 125.99,45.2 125.99,46
  IN2 w0.152: 125.99,45.2 125.99,43.73 127.79,41.93 127.79,34.39 125.99,32.59 123.03,32.59 122.2,33.42 120.19,33.42 v1(119.78,33)
  BOTTOM w0.076: UCPU1.AM43 125.51,54.51 v1(125.22,54.51)
DDR_A_D51: length 31.1
  TOP w0.102: UD32.F7 124.16,32.65 v1(124.57,33.05) ; v1(124.57,33.05) 124.58,33.07 124.58,33.05 v1(124.57,33.05)
  IN2 w0.076: v1(124.26,54.44) 124.26,53.67 123.85,53.27 123.85,46.8 125.27,45.39
  IN2 w0.152: v1(124.57,33.05) 124.93,33.42 125.52,33.42 125.74,33.64 125.74,34.81 126.62,35.69 126.62,37.32 126.39,37.55 125.94,37.55 125.79,37.7 125.79,38.01 125.94,38.16 126.39,38.16 126.54,38.31 126.54,38.62 126.39,38.77 125.94,38.77 125.79,38.92 125.79,39.23 125.94,39.38 126.39,39.38 126.54,39.53 126.54,39.84 126.39,39.99 125.94,39.99 125.79,40.14 125.79,40.44 125.94,40.6 126.39,40.6 126.54,40.75 126.54,42.21 126.11,42.63 125.9,42.63 125.11,41.85 124.9,41.85 124.68,42.06 124.68,42.28 125.47,43.07 125.47,43.28 125.27,43.48 125.27,45.39
  BOTTOM w0.076: v1(124.26,54.44) 124.46,54.44 UCPU1.AM45
DDR_A_D52: length 31.2
  TOP w0.102: v1(120.55,33.87) 120.95,33.47 UD32.E3
  IN2 w0.076: v1(124.28,55.74) 123.9,55.37 123.9,53.63 123.68,53.41 123.68,46.48 123.75,46.41 123.75,42.96
  IN2 w0.152: 123.75,42.96 123.75,42.49 124.9,41.35 125.1,41.35 125.74,41.99 126.06,41.99 126.2,41.85 126.2,41.11 126.03,40.94 125.68,40.94 125.44,40.71 125.44,37.5 125.79,37.16 125.79,35.22 125.62,35.05 125.12,35.05 124.87,34.8 124.87,34.5 124.63,34.26 120.94,34.26 v1(120.55,33.87)
  BOTTOM w0.076: v1(124.28,55.74) 124.54,56.01 UCPU1.AK45
DDR_A_D53: length 31.7
  TOP w0.102: v1(125.34,33) 125.33,33 125.33,33.01 124.98,32.65 124.98,32.65 UD32.F8
  IN2 w0.076: 125.62,46.08 124.03,47.67 124.03,51.46 124.65,52.08 124.65,55.25 v1(125.22,55.81)
  IN2 w0.152: v1(125.34,33) 125.99,33 126.62,33.64 126.62,34.19 126.74,34.3 127.22,34.3 127.45,34.53 127.45,34.84 127.35,34.94 127.06,34.94 126.92,35.08 126.92,35.4 127.08,35.55 127.34,35.55 127.45,35.66 127.45,36.04 127.33,36.16 127.08,36.16 126.92,36.31 126.92,36.62 127.08,36.77 127.33,36.77 127.45,36.9 127.45,37.25 127.32,37.38 127.08,37.38 126.92,37.53 126.92,37.89 127.02,37.99 127.32,37.99 127.45,38.12 127.45,38.47 127.32,38.6 127.04,38.6 126.92,38.72 126.92,39.09 127.05,39.21 127.34,39.21 127.45,39.32 127.45,39.69 127.32,39.82 127.03,39.82 126.92,39.92 126.92,40.32 127.03,40.43 127.35,40.43 127.45,40.53 127.45,40.93 127.34,41.04 127.01,41.04 126.92,41.13 126.92,41.37 127.3,41.75 127.3,41.94 125.62,43.61 125.62,46.08
  BOTTOM w0.076: UCPU1.AK43 125.51,55.81 v1(125.22,55.81)
DDR_A_D54: length 31.2
  TOP w0.102: v1(124.55,30.62) 124.15,31.03 UD32.H7
  IN2 w0.076: 127.68,52.32 128.88,51.12 128.88,43.18 129.09,42.96 ; 127.68,53.79 127.08,54.38
  IN2 w0.089: 127.68,52.32 127.68,53.79 ; 127.08,54.38 v1(127.08,54.39)
  IN2 w0.152: 129.09,42.96 129.41,42.64 129.41,33.25 126.43,30.26 125.02,30.26 124.93,30.17 124.93,29.99 124.83,29.89 124.25,29.89 123.99,30.15 123.99,30.44 124.17,30.62 v1(124.55,30.62)
  BOTTOM w0.076: v1(127.08,54.39) 127.41,54.71 UCPU1.AM40
DDR_A_D55: length 31.5
  TOP w0.102: v1(124.52,31.48) UD32.H8
  IN2 w0.076: 126.53,54.07 126.53,51.81 127.61,50.74 127.61,46.55 128.57,45.59
  IN2 w0.089: v1(126.17,54.44) 126.53,54.07
  IN2 w0.152: 128.57,45.59 128.57,42.77 128.93,42.4 128.93,33.31 127.26,31.64 126.86,31.64 126.75,31.52 126.75,30.9 126.33,30.49 125.96,30.49 125.85,30.6 125.85,30.98 125.75,31.07 124.21,31.07 123.94,31.34 123.94,31.59 124.07,31.71 124.29,31.71 v1(124.52,31.48)
  BOTTOM w0.076: UCPU1.AM42 126.44,54.71 v1(126.17,54.44)
DDR_A_D56: length 24.2
  TOP w0.102: UD32.B8 124.95,35.85 v1(125.34,36.24)
  IN2 w0.076: v1(123.31,54.98) 123.67,54.62 123.67,54.18 123.32,53.82 123.12,53.82 122.9,53.61 122.9,52.16 122.63,51.89 122.63,45.34
  IN2 w0.089: 122.27,44.97 122.63,45.34
  IN2 w0.152: 122.27,44.97 122.27,43.33 124.99,40.62 124.99,40.46 124.83,40.31 124.4,40.31 124.25,40.15 124.25,39.85 124.39,39.7 124.83,39.7 124.99,39.55 124.99,39.24 124.83,39.09 124.4,39.09 124.25,38.93 124.25,38.63 124.39,38.48 124.68,38.48 124.83,38.33 124.83,36.75 v1(125.34,36.24)
  BOTTOM w0.076: v1(123.31,54.98) 123.59,54.71 UCPU1.AM46
DDR_A_D57: length 23.4
  TOP w0.102: UD32.C8 124.95,35.07 v1(125.35,35.48)
  IN2 w0.076: v1(123.31,55.57) 122.9,55.16 122.9,54.04 122.72,53.87 122.72,52.24 122.46,51.97 122.46,47.7 121.95,47.19 121.95,44.56
  IN2 w0.152: v1(125.35,35.48) 124.37,36.47 124.37,38.02 123.88,38.51 123.88,41.18 121.95,43.11 121.95,44.56
  BOTTOM w0.076: v1(123.31,55.57) 123.75,56.01 UCPU1.AK46
DDR_A_D58: length 22.1
  TOP w0.102: v1(120.51,37.07) 120.93,36.65 UD32.A3
  IN2 w0.076: 118.66,45.55 119.98,46.88 119.98,53.28 120.48,53.79 120.69,53.79 v1(121.36,54.45)
  IN2 w0.152: v1(120.51,37.07) 120.18,37.4 120.18,39.07 120.33,39.22 120.96,39.22 121.11,39.38 121.11,39.68 120.96,39.83 120.33,39.83 120.18,39.98 120.18,41.91 118.66,43.43 118.66,45.55
  BOTTOM w0.076: UCPU1.AM49 121.62,54.71 v1(121.36,54.45)
DDR_A_D59: length 22.3
  TOP w0.102: v1(119.68,37.11) 120.13,36.65 UD32.A2
  IN2 w0.076: 118.19,45.47 119.8,47.08 119.8,49.6 119.33,50.06 119.33,52.89 120.41,53.96 120.55,53.96 120.86,54.28 120.86,55.23 v1(121.41,55.77)
  IN2 w0.152: 118.19,45.47 118.19,43.36 119.71,41.83 119.71,37.14 v1(119.68,37.11)
  BOTTOM w0.076: UCPU1.AK49 121.64,56.01 v1(121.41,55.77)
DDR_A_D60: length 23.9
  TOP w0.102: UD32.A7 123.8,37 v1(123.63,37)
  IN2 w0.076: v1(122.36,54.39) 122.36,54 121.8,53.45 121.8,52.28 121.18,51.65 121.18,49.75 121.29,49.64 121.29,47.18 121.1,46.99 121.1,44.48
  IN2 w0.152: v1(123.63,37) 122.23,37 122.08,37.16 122.08,37.54 122.19,37.66 122.98,37.66 123.14,37.81 123.14,38.08 122.98,38.23 122.32,38.23 122.14,38.41 122.14,38.6 122.39,38.84 122.98,38.84 123.14,39 123.14,40.85 121.1,42.88 121.1,44.48
  BOTTOM w0.076: v1(122.36,54.39) 122.68,54.71 UCPU1.AM48
DDR_A_D61: length 24.1
  TOP w0.102: v1(124.46,34.67) 124.15,34.35 UD32.D7
  IN2 w0.076: 121.51,44.59 121.51,47.07 121.47,47.11 121.47,49.71 121.36,49.82 121.36,51.58 122,52.22 122,53.39 122.72,54.12 122.72,55.32 v1(122.36,55.69)
  IN2 w0.152: 121.51,44.59 121.51,43.02 123.54,40.99 123.54,38.34 123.91,37.97 123.91,37.47 124.05,37.33 124.05,35.08 v1(124.46,34.67)
  BOTTOM w0.076: UCPU1.AK48 122.68,56.01 v1(122.36,55.69)
DDR_A_D62: length 23.8
  TOP w0.102: UD32.C3 120.92,35.05 120.53,35.44 120.53,35.45 v1(120.53,35.45)
  IN2 w0.076: 117.73,45.32 119.63,47.22 119.63,49.52 119.16,49.99 119.16,52.96 119.92,53.72 119.92,53.85 v1(120.45,54.39)
  IN2 w0.152: 117.73,45.32 117.73,43.34 118.57,42.49 118.57,37.88 118.41,37.71 118.41,36.2 118.74,35.86 120.12,35.86 v1(120.53,35.45)
  BOTTOM w0.076: UCPU1.AM51 120.84,54.44 120.79,54.39 v1(120.45,54.39)
DDR_A_D63: length 25.5
  TOP w0.102: v1(119.77,35.45) 120.15,35.07 UD32.C2
  IN2 w0.076: v1(120.45,55.69) 120.23,55.46 119.28,55.46 118.98,55.16 118.98,49.92 119.41,49.48 119.41,47.45 117.26,45.29
  IN2 w0.152: 117.26,45.29 117.26,43.31 118.11,42.47 118.11,37.95 117.94,37.78 117.94,35.98 118.46,35.45 v1(119.77,35.45)
  BOTTOM w0.076: UCPU1.AK51 120.78,56.01 v1(120.45,55.69)
DDR_A_DQS0: length 49.7
  TOP w0.102: UD28.F3 80.13,32.51 80.54,32.51 v1(80.63,32.61)
  IN2 w0.089: 108.18,54.03 109.73,55.58 111,55.58 111.4,55.97 111.4,55.98 111.6,56.18 v1(111.73,56.18)
  IN2 w0.152: v1(80.63,32.61) 80.63,32.44 80.54,32.35 80.35,32.35 80.08,32.63 80.08,33.01 80.45,33.38 81.12,33.38 81.98,34.24 81.98,37.13 82.27,37.43 84,37.43 96.72,50.14 106,50.14 108.18,52.32 108.18,54.03
  BOTTOM w0.076: UCPU1.AJ62 114.13,56.32 114.2,56.39 114.2,56.49 114.12,56.57 114.02,56.62 113.88,56.62 113.78,56.57 113.75,56.54 113.52,56.54 113.47,56.56 113.39,56.6 113.37,56.62 113.23,56.62 113.22,56.61 113.17,56.59 113.14,56.57 113.1,56.54 112.11,56.54 112.08,56.57 111.57,56.57 111.43,56.43 111.43,56.3 111.56,56.18 v1(111.73,56.18)
DDR_A_DQS1: length 45.9
  TOP w0.102: v1(82.57,35.39) 82.91,35.05 UD28.C7
  IN1 w0.137: v1(110.75,52.98) 111,52.98 111.32,52.65 111.32,52.3 108.78,49.76 108.78,49.28 107.84,48.34 107.49,48.34 105.11,45.97 92.89,45.97 85.45,38.52 82.05,38.52 81.48,37.95 81.48,36.15 82.04,35.59 82.38,35.59 v1(82.57,35.39)
  BOTTOM w0.076: v1(110.75,52.98) 110.85,53.08 110.85,53.41 111.78,54.34 112.39,54.34 112.45,54.29 113.07,54.29 113.14,54.32 113.19,54.35 113.41,54.35 113.46,54.32 113.49,54.31 113.51,54.3 113.56,54.28 114.05,54.28 114.43,53.89 UCPU1.AN61
DDR_A_DQS2: length 39.6
  TOP w0.102: v1(93.06,32.25) 92.66,32.65 UD29.F3
  IN2 w0.152: v1(93.06,32.25) 92.79,32.25 92.64,32.4 92.64,33.18 93.76,34.3 93.76,37.95 97.47,41.66 97.68,41.66 97.77,41.57 98.19,41.57 98.65,42.03 98.65,42.42 98.54,42.52 98.54,42.74 98.87,43.06 99.08,43.06 99.35,42.79 99.75,42.79 100.21,43.25 100.21,43.65 99.94,43.92 99.94,44.13 100.72,44.92 108.56,44.92 109.12,45.48 109.12,45.92 113.44,50.24 113.44,52.27 115.09,53.93 115.56,53.93 v1(115.75,53.74)
  BOTTOM w0.076: UCPU1.AN58 116.07,54.06 v1(115.75,53.74)
DDR_A_DQS3: length 37.6
  TOP w0.102: v1(95.22,35.49) 95.65,35.05 UD29.C7
  IN1 w0.086: v1(117.64,53.74) 117.89,53.97 117.98,53.97 118.07,53.89 118.07,52.08 117.2,51.22 117.2,51.22 117.16,51.19 117.15,51.19 117.13,51.19 117.12,51.18
  IN1 w0.137: 117.12,51.18 116.68,50.74 115.74,50.74 109.35,44.35 109.17,44.35 107.07,42.25 97.76,42.25 93.67,38.15 93.67,36.14 94.02,35.8 94.91,35.8 v1(95.22,35.49)
  BOTTOM w0.076: UCPU1.AN55 117.97,54.06 v1(117.64,53.74)
DDR_A_DQS4: length 25.1
  TOP w0.102: v1(108.86,32.75) 108.77,32.65 UD31.F3
  IN2 w0.152: v1(108.86,32.75) 108.79,32.68 108.79,32.48 108.93,32.35 109.36,32.35 110.17,33.16 110.17,37.02 112.4,39.25 112.4,43.77 112.24,43.94 112.24,44.72 114.93,47.42 114.93,47.84 114.83,47.95 v1(114.49,47.95)
  BOTTOM w0.076: v1(114.49,47.95) 114.66,47.95 114.88,47.73 115.43,47.73 116.38,48.68 116.38,48.69 116.39,48.7 116.39,49.21 116.62,49.44 116.62,49.77 116.59,49.81 116.58,49.85 116.56,49.89 116.55,49.91 116.55,50.04 116.56,50.06 116.6,50.14 116.62,50.19 116.62,50.42 116.6,50.46 116.55,50.56 116.55,50.69 116.6,50.8 116.68,50.88 116.77,50.88 116.84,50.8 UCPU1.AW57
DDR_A_DQS5: length 21.8
  TOP w0.102: v1(110.89,35.39) 111.23,35.05 UD31.C7
  IN1 w0.137: v1(110.89,35.39) 110.7,35.59 110.35,35.59 109.88,36.05 109.88,37.39 114.14,41.64 114.14,43.94 117.1,46.9 117.6,46.9 117.83,46.66 v1(118.05,46.66)
  BOTTOM w0.076: UCPU1.AW53 119.1,50.62 119.06,50.59 119.06,50.19 119.03,50.12 119.02,50.1 119,50.05 119,50.04 118.99,50.03 118.99,49.91 119,49.89 119.06,49.75 119.06,49.43 118.81,49.18 118.81,49.11 118.7,49 118.7,47.91 117.77,46.98 117.77,46.84 117.95,46.66 v1(118.05,46.66)
DDR_A_DQS6: length 34.6
  TOP w0.102: v1(121.4,32.22) 120.97,32.65 UD32.F3
  IN2 w0.089: v1(126.17,55.09) 125.76,54.68 125.76,47.14 125.97,46.93 126.82,46.93 127.75,45.99 127.75,45.9 127.79,45.87 127.79,45.83 127.82,45.8 127.82,45.79
  IN2 w0.152: 127.82,45.79 127.82,45.28 126.83,44.29 126.83,43.86 128.48,42.21 128.48,33.5 127.04,32.06 122.54,32.06 121.69,32.91 121.19,32.91 121.06,32.78 121.06,32.56 v1(121.4,32.22)
  BOTTOM w0.076: UCPU1.AL42 126.44,55.36 v1(126.17,55.09)
DDR_A_DQS7: length 26
  TOP w0.102: v1(123.56,35.49) 124,35.05 UD32.C7
  IN2 w0.089: 119.99,45.48 119.99,46.04 120.26,46.31 120.26,51.77 120.87,52.38 120.87,53.52 121.16,53.81 121.54,53.81 121.72,53.99 121.72,54.75 v1(121.41,55.06)
  IN2 w0.152: v1(123.56,35.49) 123.36,35.69 121.76,35.69 121.3,36.14 121.3,38.73 122.43,39.86 122.43,40.17 122.28,40.32 121.24,40.32 120.96,40.6 120.96,42.06 119.99,43.03 119.99,45.48
  BOTTOM w0.076: v1(121.41,55.06) 121.63,55.06 121.85,55.28 UCPU1.AL49
DDR_A_DQS#0: length 50
  TOP w0.102: UD28.G3 79.99,31.85 80.5,31.85 v1(80.57,31.92)
  IN2 w0.089: v1(111.09,56.19) 111.09,55.9 110.93,55.74 109.66,55.74 108.14,54.22 108.1,54.22 107.99,54.11 107.99,54.07 107.95,54.04 107.95,54.03
  IN2 w0.152: 107.95,54.03 107.95,52.41 105.91,50.37 96.62,50.37 83.91,37.65 82.18,37.65 81.75,37.23 81.75,34.33 81.03,33.6 80.35,33.6 79.85,33.1 79.85,32.53 80.26,32.12 80.37,32.12 v1(80.57,31.92)
  BOTTOM w0.076: v1(111.09,56.19) 111.26,56.35 111.26,56.5 111.5,56.74 112.15,56.74 112.18,56.72 113.04,56.72 113.05,56.72 113.11,56.75 113.15,56.77 113.19,56.79 113.42,56.79 113.47,56.76 113.56,56.72 113.69,56.72 113.7,56.72 113.7,56.73 113.84,56.79 114.06,56.79 114.23,56.71 114.38,56.56 114.38,56.39 114.45,56.32 UCPU1.AJ61
DDR_A_DQS#1: length 45.9
  TOP w0.102: UD28.B7 82.66,35.85 82.4,36.11 v1(82.4,36.24)
  IN1 w0.137: v1(82.4,36.24) 82.93,36.24 83.03,36.14 83.03,35.9 82.92,35.8 82.12,35.8 81.69,36.23 81.69,37.86 82.13,38.3 85.54,38.3 92.98,45.75 105.2,45.75 107.58,48.12 107.93,48.12 109,49.19 109,49.67 111.54,52.21 111.54,52.74 111.24,53.03 v1(111.24,53.27)
  BOTTOM w0.076: UCPU1.AN62 113.95,54.07 113.92,54.1 113.52,54.1 113.45,54.14 113.43,54.14 113.38,54.16 113.37,54.17 113.36,54.17 113.24,54.17 113.22,54.16 113.11,54.11 112.37,54.11 112.32,54.16 111.85,54.16 111.24,53.55 v1(111.24,53.27)
DDR_A_DQS#2: length 39.7
  TOP w0.102: v1(92.23,32.26) 92.6,31.9 UD29.G3
  IN2 w0.152: v1(92.23,32.26) 92.41,32.44 92.41,33.28 93.53,34.4 93.53,38.04 97.37,41.89 97.78,41.89 97.87,41.8 98.1,41.8 98.42,42.12 98.42,42.32 98.32,42.43 98.32,42.83 98.77,43.29 99.17,43.29 99.44,43.02 99.66,43.02 99.98,43.34 99.98,43.56 99.71,43.83 99.71,44.23 100.63,45.14 108.47,45.14 108.9,45.57 108.9,46.02 113.21,50.34 113.21,52.37 115,54.15 115.51,54.15 v1(115.75,54.39)
  BOTTOM w0.076: v1(115.75,54.39) 116.07,54.71 UCPU1.AM58
DDR_A_DQS#3: length 37.6
  TOP w0.102: UD29.B7 95.47,35.85 95.22,36.11 v1(95.22,36.24)
  IN1 w0.086: 117.27,51.03 117.29,51.05 117.29,51.08 118.23,52.02 118.23,53.96 118.05,54.14 117.74,54.14 117.65,54.22 v1(117.65,54.39)
  IN1 w0.137: 117.27,51.03 116.77,50.52 115.83,50.52 109.44,44.13 109.26,44.13 107.16,42.03 97.85,42.03 93.88,38.06 93.88,36.23 94.1,36.01 94.99,36.01 v1(95.22,36.24)
  BOTTOM w0.076: UCPU1.AM55 117.98,54.71 v1(117.65,54.39)
DDR_A_DQS#4: length 25.1
  TOP w0.102: v1(108.89,31.92) 108.38,31.92 UD31.G3
  IN2 w0.152: v1(114.95,48.34) 114.95,48.14 115.16,47.94 115.16,47.32 112.46,44.63 112.46,44.03 112.63,43.87 112.63,39.16 110.39,36.93 110.39,33.06 109.45,32.12 109.09,32.12 v1(108.89,31.92)
  BOTTOM w0.076: v1(114.95,48.34) 114.9,48.29 114.9,47.96 114.96,47.9 115.35,47.9 116.21,48.75 116.21,48.76 116.22,48.77 116.22,48.91 116.21,48.91 116.21,49.28 116.45,49.52 116.45,49.71 116.44,49.72 116.41,49.78 116.4,49.82 116.37,49.86 116.37,50.09 116.4,50.14 116.44,50.22 116.45,50.23 116.45,50.36 116.44,50.37 116.44,50.38 116.37,50.52 116.37,50.73 116.45,50.9 116.61,51.05 116.78,51.05 116.84,51.12 UCPU1.AV57
DDR_A_DQS#5: length 21.8
  TOP w0.102: v1(110.9,36.12) 111.16,35.85 UD31.B7
  IN1 w0.137: v1(117.64,46.29) 117.64,46.55 117.51,46.68 117.18,46.68 114.35,43.85 114.35,41.55 110.1,37.3 110.1,36.14 110.44,35.8 110.58,35.8 v1(110.9,36.12)
  BOTTOM w0.076: UCPU1.AV53 119,51 119,50.83 118.89,50.72 118.89,50.23 118.86,50.19 118.86,50.17 118.84,50.13 118.82,50.08 118.82,49.87 118.85,49.81 118.89,49.71 118.89,49.5 118.64,49.25 118.64,49.19 118.52,49.07 118.52,47.98 117.6,47.05 117.6,46.77 117.66,46.71 117.66,46.31 v1(117.64,46.29)
DDR_A_DQS#6: length 34.6
  TOP w0.102: UD32.G3 120.95,31.86 v1(120.58,32.23)
  IN2 w0.089: v1(125.22,55.16) 125.52,55.16 125.6,55.08 125.6,47.08 125.91,46.77 126.75,46.77 127.59,45.92 127.59,45.79
  IN2 w0.152: 127.59,45.79 127.59,45.37 126.6,44.38 126.6,43.77 128.25,42.11 128.25,33.59 126.95,32.29 122.63,32.29 121.79,33.13 121.09,33.13 120.83,32.87 120.83,32.4 120.66,32.23 v1(120.58,32.23)
  BOTTOM w0.076: UCPU1.AL43 125.51,55.16 v1(125.22,55.16)
DDR_A_DQS#7: length 26.2
  TOP w0.102: v1(123.56,36.24) 123.56,36.11 123.82,35.85 UD32.B7
  IN2 w0.089: 120.21,45.48 120.21,45.53 120.15,45.59 120.15,45.97 120.43,46.24 120.43,51.7 121.04,52.31 121.04,53.46 121.23,53.65 121.61,53.65 121.88,53.92 121.88,55.12 121.98,55.21 122.19,55.21 v1(122.36,55.04)
  IN2 w0.152: v1(123.56,36.24) 123.23,35.91 121.85,35.91 121.53,36.23 121.53,38.63 122.66,39.77 122.66,40.26 122.38,40.55 121.34,40.55 121.18,40.7 121.18,42.15 120.21,43.12 120.21,45.48
  BOTTOM w0.076: UCPU1.AL48 122.68,55.36 v1(122.36,55.04)
DDR_A_MA0: length 117.5
  TOP w0.076: v1(103.41,25.78) 102.52,26.67 RD63.1
  TOP w0.102: UD32.N3 120.95,27.05 121.48,27.05 v1(121.77,26.76) ; v1(80.48,26.81) 80.24,26.81 80.24,26.81 UD28.N3 ; v1(93.43,26.76) 93.14,27.05 92.6,27.05 UD29.N3 ; UD31.N3 108.31,27.05 108.56,26.81 v1(108.81,26.81)
  IN1 w0.076: v4(88.1,26.74) 88.21,26.74 88.62,26.32 90.12,26.32 90.25,26.45 91.67,26.45 92.14,25.97 94.1,25.97 94.31,25.76 94.6,25.47 97.18,25.47 97.57,25.86 98.32,25.86 98.5,26.04 99.6,26.04 99.92,26.36 102.83,26.36 v1(103.41,25.78) 103.58,25.6 105.99,25.6 106.11,25.48 107.65,25.48 107.69,25.43 108.07,25.43 108.23,25.59 108.42,25.59 108.58,25.43 109.07,25.43 109.18,25.54 109.18,25.72 109.28,25.82 109.48,25.82 109.58,25.72 109.58,25.54 109.68,25.43 109.89,25.43 109.99,25.54 109.99,25.72 110.09,25.82 110.29,25.82 110.4,25.72 110.4,25.48 110.5,25.37 111.22,25.37 111.43,25.59 111.43,25.78 111.23,25.99 111.23,26.14 111.33,26.24 112.85,26.24 113.08,26.01 113.08,25.72 113.21,25.59 114.1,25.59 114.54,26.04 114.96,26.04 115.09,26.16 115.52,26.16 115.65,26.29 116.13,26.29 116.43,26.58 v4(116.43,26.74)
  IN4 w0.076: v1(121.77,26.76) 122.04,27.03 122.29,27.03 122.41,26.91 122.41,26.63 122.17,26.39 120.93,26.39 120.81,26.52 118.58,26.52 118.42,26.35 118.17,26.35 118.1,26.43 118.1,26.46 118.02,26.53 117.87,26.53 117.79,26.46 117.79,26.43 117.72,26.35 117,26.35 116.62,26.74 v4(116.43,26.74) 116.06,26.37 114.11,26.37 113.94,26.54 112.46,26.54 112.3,26.38 110.19,26.38 109.76,26.81 v1(108.81,26.81) ; v1(93.43,26.76) 93.63,26.96 93.97,26.96 94.17,26.76 94.17,26.49 94.06,26.37 93.25,26.37 93.12,26.51 89.13,26.51 88.96,26.33 88.61,26.33 88.21,26.74 v4(88.1,26.74) 87.98,26.61 85.74,26.61 85.61,26.48 82.31,26.48 82.21,26.38 81.91,26.38 81.48,26.81 v1(80.48,26.81) ; 127.96,44.5 126.42,42.96 ; v1(129.61,51.43) 129.61,51.14 129.73,51.02 130.03,51.02 130.16,50.89 130.16,47.17 129.52,46.53 129.2,46.53 127.96,45.29
  IN4 w0.086: 127.96,45.29 127.96,44.5
  IN4 w0.145: v1(103.41,25.78) 103.41,25.79 103.41,26.1 103.01,26.5 103.01,28.45 102.87,28.59 102.87,33.59 103.74,34.46 103.74,34.61 103.6,34.74 103.6,34.97 103.7,35.07 104.25,35.07 104.37,35.19 104.37,38.45 106.5,40.58 116.21,40.58 118.39,42.76 126.22,42.76 126.42,42.96
  BOTTOM w0.076: v1(129.61,51.43) 129.88,51.43 UCPU1.AU36
DDR_A_MA1: length 121.7
  TOP w0.076: RD37.1 104.23,22.14 102.57,23.8 v1(102.57,24.38) ; v1(82.53,25.75) 82.53,26.11 82.67,26.25 UD28.P7
  TOP w0.102: v1(95.42,25.85) 95.2,26.07 95.2,26.18 95.28,26.25 95.8,26.25 UD29.P7 ; v1(123.77,25.85) 123.55,26.07 123.55,26.19 123.62,26.25 UD32.P7 ; v1(110.85,25.75) 110.85,26.13 110.98,26.25 UD31.P7
  IN1 w0.076: v4(88.28,24.9) 90.01,24.9 90.05,24.86 91.27,24.86 91.87,24.26 92.44,24.26 93.06,23.64 94.69,23.64 94.84,23.48 96.04,23.48 96.4,23.84 97.78,23.84 98.77,24.83 101.32,24.83 101.6,24.55 102.4,24.55 v1(102.57,24.38) 102.79,24.16 105.47,24.16 106.24,23.39 109.48,23.39 110.08,23.99 111.35,23.99 111.38,24.02 112.66,24.02 113.04,24.4 114.1,24.4 114.48,24.78 114.86,24.78 115.07,24.58 116.03,24.58 v4(116.55,25.1)
  IN4 w0.076: v1(123.77,25.85) 123.7,25.92 120.65,25.92 119.93,25.2 118.7,25.2 118.64,25.13 116.59,25.13 v4(116.55,25.1) 116.01,24.55 115.15,24.55 114.94,24.75 114.42,24.75 114.22,24.55 114.22,24.37 114.06,24.22 113.9,24.22 113.83,24.3 113.83,24.51 113.75,24.59 113.6,24.59 113.52,24.51 113.52,24.3 113.45,24.22 113.31,24.22 112.47,25.06 111.63,25.06 110.94,25.75 v1(110.85,25.75) ; 125.07,43.1 125.89,43.91 126.85,43.91 127.79,44.85 ; 129.98,47.56 127.79,45.37 ; v1(82.53,25.75) 82.89,25.75 83.56,25.08 84.67,25.08 84.75,25.01 84.75,24.89 84.82,24.82 84.98,24.82 85.05,24.89 85.05,25.01 85.13,25.08 85.28,25.08 85.36,25.01 85.36,24.89 85.43,24.82 85.59,24.82 85.66,24.89 85.66,25.01 85.74,25.08 85.89,25.08 85.97,25.01 85.97,24.89 86.04,24.82 86.2,24.82 86.27,24.89 86.27,25.01 86.35,25.08 86.85,25.08 87.14,24.79 88.17,24.79 v4(88.28,24.9) 88.55,25.17 91.24,25.17 91.92,25.85 v1(95.42,25.85)
  IN4 w0.086: 127.79,45.37 127.79,44.85 ; v1(129.62,49.92) 129.98,49.56 129.98,47.56
  IN4 w0.145: v1(102.57,24.38) 102.57,24.14 103.05,23.66 103.22,23.66 103.6,24.04 103.6,24.18 103.42,24.36 103.42,25.16 103,25.58 103,26.15 102.63,26.52 102.63,28.3 102.5,28.44 102.5,33.75 103.2,34.45 103.2,35.29 103.32,35.41 103.89,35.41 104,35.52 104,35.83 103.85,35.97 103.71,35.97 103.51,36.17 103.51,36.39 103.67,36.55 103.86,36.55 104,36.69 104,38.6 106.32,40.92 116.08,40.92 118.26,43.1 120,43.1 120.15,43.24 120.15,43.51 120.28,43.64 120.6,43.64 120.73,43.51 120.73,43.24 120.87,43.1 121.16,43.1 121.31,43.24 121.31,43.52 121.43,43.65 121.76,43.65 121.89,43.52 121.89,43.24 122.03,43.1 125.07,43.1
  BOTTOM w0.076: UCPU1.AY37 129.46,49.93 129.62,49.93 v1(129.62,49.92)
DDR_A_MA2: length 125.4
  TOP w0.076: v1(99.64,24.32) 99.64,23.67 98.01,22.05 RD66.1
  TOP w0.102: v1(80.41,25.84) 80.58,25.84 80.67,25.93 80.67,26.15 80.57,26.25 79.99,26.25 UD28.P3 ; v1(108.73,25.84) 108.85,25.84 109.02,26.01 109.02,26.15 108.92,26.25 UD31.P3 ; v1(93.46,25.41) 92.62,26.25 UD29.P3 ; UD32.P3 120.95,26.21 v1(121.59,25.56)
  IN1 w0.076: v4(114.64,24.4) 114.44,24.2 113.12,24.2 112.48,23.55 112.3,23.55 111.97,23.22 109.72,23.22 109.61,23.1 105.17,23.1 104.45,23.83 102.58,23.83 102.06,24.35 101.57,24.35 101.39,24.53 99.84,24.53 v1(99.64,24.32) 99.36,24.04 98.44,24.04 97.9,23.5 96.46,23.5 96.18,23.22 94.62,23.22 94.4,23.43 92.82,23.43 92.72,23.53 92.72,23.62 92.62,23.73 92.42,23.73 92.32,23.62 92.32,23.53 92.21,23.43 92.03,23.43 91.9,23.56 91.9,23.68 92.02,23.79 92.02,23.93 91.89,24.06 91.75,24.06 91.47,23.79 91.36,23.68 91.22,23.68 91.07,23.83 91.07,23.97 91.2,24.1 91.38,24.27 91.39,24.42 91.19,24.62 91.05,24.62 90.87,24.44 90.73,24.44 90.65,24.52 89.55,24.52 89.32,24.75 88.64,24.75 88.41,24.52 86.63,24.52 v4(86.52,24.64)
  IN4 w0.076: v1(108.73,25.84) 109.14,25.84 109.63,25.35 109.88,25.35 109.96,25.43 109.96,25.63 110.06,25.73 110.27,25.73 110.37,25.63 110.37,25.47 110.47,25.37 111.1,25.37 111.61,24.86 112.39,24.86 113.18,24.07 114.13,24.07 114.46,24.4 v4(114.64,24.4) 119.3,24.4 119.54,24.64 119.6,24.64 120.52,25.56 v1(121.59,25.56) ; v1(93.46,25.41) 93.45,25.43 91.71,25.43 91.3,25.02 88.89,25.02 88.42,24.55 86.95,24.55 86.86,24.64 v4(86.52,24.64) 86.47,24.59 84.69,24.59 84.35,24.93 83.48,24.93 83.02,25.39 82.39,25.39 82.17,25.6 82.17,25.87 82.01,26.04 81.8,26.04 81.73,25.96 81.73,25.9 81.65,25.82 81.5,25.82 81.42,25.9 81.42,25.96 81.35,26.04 81.19,26.04 81.12,25.96 81.12,25.9 81.04,25.82 80.43,25.82 v1(80.41,25.84) ; v1(128.58,52.43) 127.76,51.61 126.93,51.61 126.49,52.06 120.78,52.06 120.17,51.45 113.96,51.45 113.75,51.23
  IN4 w0.145: 113.75,51.23 111.36,48.85 105.39,48.85 96.58,40.03 96.58,35.21 96.6,35.18 96.6,33.21 98.13,31.68 98.13,26.42 99.51,25.05 99.51,24.45 v1(99.64,24.32)
  BOTTOM w0.076: v1(128.58,52.43) 128.9,52.76 UCPU1.AR38
DDR_A_MA3: length 124.2
  TOP w0.076: RD45.1 104.02,27.93 v1(104.02,27.12) ; UD32.N2 120.1,27.05 120.1,27.05 v1(119.69,27.47)
  TOP w0.102: UD29.N2 91.76,27.05 v1(91.34,27.47) ; UD28.N2 79.21,27.05 v1(79.6,27.44) ; v1(107.92,27.44) 107.53,27.05 107.53,27.05 UD31.N2
  IN1 w0.076: v4(116.17,27.92) 116.44,27.92 116.68,27.67 116.68,27.48 116.55,27.36 116.21,27.36 115.84,27.72 115.65,27.72 115.46,27.52 114.35,27.52 113.72,26.89 111.59,26.89 111.43,27.04 110.62,27.04 110.47,27.19 108.5,27.19 108.11,26.8 107.76,26.8 107.23,26.27 106.8,26.27 106.67,26.39 106.67,26.75 106.54,26.87 105.99,26.87 105.6,27.26 104.8,27.26 104.72,27.33 104.72,27.66 104.65,27.74 104.5,27.74 104.42,27.66 104.42,26.87 104.32,26.77 104.18,26.77 104.02,26.94 v1(104.02,27.12) 103.62,27.51 97.6,27.51 97.26,27.85 95.65,27.85 95.26,27.47 94.39,27.47 94.09,27.17 93.27,27.17 93.16,27.06 90.31,27.06 89.45,27.92 v4(87.71,27.92)
  IN4 w0.076: v1(129.53,53.24) 129.94,53.24 130.03,53.15 130.03,51.96 130.5,51.49 130.5,46.92 129.63,46.05 129.25,46.05 128.68,45.48 128.68,44.18 127.46,42.96 ; v1(107.92,27.44) 108.04,27.32 110.62,27.32 110.98,26.96 112.12,26.96 112.16,27 114.65,27 115.21,27.56 115.52,27.56 115.88,27.92 v4(116.17,27.92) 116.38,27.7 116.38,27.61 116.51,27.48 116.61,27.48 116.82,27.69 117.17,27.69 117.26,27.78 117.26,28.09 117.33,28.17 118.11,28.17 118.19,28.09 118.19,27.98 118.11,27.9 118,27.9 117.92,27.83 117.92,27.68 117.85,27.6 117.61,27.6 117.53,27.52 117.53,27.37 117.61,27.3 117.9,27.3 117.97,27.22 117.97,27.09 118.05,27.01 118.27,27.01 118.34,27.09 118.34,27.18 118.41,27.24 118.48,27.24 118.5,27.26 118.57,27.26 118.65,27.18 118.65,27.09 118.72,27.01 119.11,27.01 119.19,27.09 119.19,27.13 119.27,27.2 119.42,27.2 119.49,27.13 119.49,27.09 119.57,27.01 120.1,27.01 120.21,27.13 120.21,27.64 120.13,27.71 119.77,27.71 119.69,27.64 v1(119.69,27.47) ; v1(79.6,27.44) 79.73,27.58 82.11,27.58 82.4,27.29 83.05,27.29 83.41,26.94 85.4,26.94 86.11,27.65 86.7,27.65 86.97,27.92 v4(87.71,27.92) 87.96,27.92 88.04,27.84 88.04,27.79 88.11,27.71 88.27,27.71 88.34,27.79 88.34,27.92 88.42,27.99 88.57,27.99 88.65,27.92 88.65,27.79 88.72,27.71 88.96,27.71 89.03,27.79 89.03,28.03 89.11,28.11 89.26,28.11 89.34,28.03 89.34,27.8 89.41,27.73 89.59,27.73 89.64,27.78 89.64,27.9 89.7,27.97 89.91,27.97 89.99,27.89 89.99,27.74 90.07,27.66 90.22,27.66 90.3,27.74 90.3,27.89 90.37,27.97 91.04,27.97 91.1,27.9 91.1,27.76 90.9,27.56 90.9,27.23 91.04,27.09 91.86,27.09 91.95,27.18 91.95,27.28 91.86,27.37 91.86,27.67 91.75,27.79 91.51,27.79 91.34,27.62 v1(91.34,27.47)
  IN4 w0.145: v1(104.02,27.12) 103.8,27.33 103.8,28.67 103.62,28.85 103.62,33.28 105.12,34.78 105.12,38.14 106.08,39.1 106.88,39.89 116.47,39.89 118.67,42.09 119.54,42.09 119.69,41.95 119.69,41.87 119.83,41.72 120.12,41.72 120.26,41.87 120.26,41.95 120.41,42.09 120.75,42.09 120.89,41.95 120.89,41.87 121.03,41.72 121.32,41.72 121.47,41.87 121.47,41.95 121.61,42.09 121.9,42.09 122.05,41.95 122.05,41.87 122.19,41.72 122.48,41.72 122.63,41.87 122.63,41.95 122.77,42.09 123.06,42.09 123.21,41.95 123.21,41.87 123.35,41.72 123.64,41.72 123.79,41.87 123.79,41.95 123.93,42.09 124.22,42.09 124.36,41.95 124.36,41.87 124.51,41.72 124.8,41.72 124.94,41.87 124.94,41.95 125.09,42.09 125.38,42.09 125.52,41.95 125.52,41.87 125.67,41.72 125.96,41.72 126.1,41.87 126.1,41.95 126.25,42.09 126.59,42.09 126.66,42.15 127.46,42.96
  BOTTOM w0.076: v1(129.53,53.24) 129.7,53.41 UCPU1.AP36
DDR_A_MA4: length 121.7
  TOP w0.076: RD33.1 101.22,26.23 v1(100.88,25.89) ; v1(84.38,25.85) 84.38,26.21 84.33,26.25 83.99,26.25 UD28.P8
  TOP w0.102: v1(96.22,26.65) 96.6,26.27 UD29.P8 ; v1(112.7,25.85) 112.7,26.18 112.63,26.25 UD31.P8 ; UD32.P8 124.95,26.27 v1(124.57,26.65)
  IN1 w0.076: v4(116.58,26.2) 116.34,25.96 115.18,25.96 115.05,25.83 114.63,25.83 114.18,25.39 111.53,25.39 111.31,25.17 109.46,25.17 108.91,24.62 107.48,24.62 107.47,24.63 107.02,24.63 106.37,25.27 103.4,25.27 102.64,26.03 101.73,26.03 101.59,25.89 v1(100.88,25.89) 100.71,26.05 99.82,26.05 99.66,25.89 98.66,25.89 98.15,25.38 98.01,25.38 97.81,25.57 97.64,25.57 97.53,25.45 97.53,25.28 97.72,25.09 97.72,24.94 97.43,24.66 95.06,24.66 94.96,24.76 94.96,25.17 94.86,25.27 94.7,25.27 94.59,25.17 94.59,24.79 94.48,24.68 94.32,24.68 94.2,24.79 94.2,25.31 93.75,25.76 92.37,25.76 91.88,25.27 91.74,25.27 91.62,25.38 91.62,25.52 91.78,25.68 91.78,26.04 91.61,26.22 90.4,26.22 90.18,26 89.06,26 88.9,26.16 88.29,26.16 v4(88.26,26.2)
  IN4 w0.076: v1(96.22,26.65) 96.08,26.52 94.42,26.52 94.11,26.21 93.18,26.21 93.04,26.35 89.2,26.35 89.01,26.17 88.28,26.17 v4(88.26,26.2) 88.16,26.1 87.84,26.1 87.77,26.16 87.77,26.37 87.69,26.46 87.46,26.46 87.38,26.38 87.38,26.18 87.31,26.1 87.16,26.1 87.08,26.18 87.08,26.38 87,26.46 86.85,26.46 86.78,26.38 86.78,26.18 86.7,26.1 86.55,26.1 86.47,26.18 86.47,26.38 86.39,26.46 85.87,26.46 85.79,26.38 85.79,26.15 85.64,26 85.54,26 85.48,26.06 85.48,26.24 85.39,26.33 85.02,26.33 84.94,26.25 84.94,26.11 84.87,26.04 84.71,26.04 84.64,26.11 84.64,26.25 84.56,26.33 84,26.33 83.94,26.27 83.94,25.71 84,25.64 84.31,25.64 84.38,25.71 v1(84.38,25.85) ; v1(128.03,51.3) 127.36,51.3 126.82,50.75 126.82,47.12 126.61,46.92 124.04,46.92 123.46,46.34 119.93,46.34 118.67,47.6 117.95,47.6 117.75,47.4 ; v1(124.57,26.65) 124.28,26.37 122.36,26.37 122.23,26.24 120.83,26.24 120.71,26.37 118.65,26.37 118.48,26.2 v4(116.58,26.2) 116.39,26.2 115.85,25.66 115.24,25.66 115.15,25.75 115.15,26.14 115.08,26.21 114.93,26.21 114.85,26.14 114.85,25.83 114.77,25.76 114.56,25.76 114.49,25.82 114.49,26.09 114.42,26.16 114.21,26.16 114.14,26.09 114.14,25.63 114.06,25.55 113.91,25.55 113.83,25.63 113.83,25.76 113.75,25.83 113.6,25.83 113.53,25.76 113.53,25.6 113.45,25.53 113.16,25.53 113.09,25.6 113.09,26.16 113.01,26.24 112.36,26.24 112.29,26.16 112.29,25.92 112.36,25.85 v1(112.7,25.85)
  IN4 w0.145: v1(100.88,25.89) 100.55,26.21 100.55,27.22 100.29,27.49 100.29,27.56 100.36,27.64 100.55,27.64 100.66,27.75 100.66,27.93 100.45,28.15 100.45,28.63 100.63,28.81 100.63,29.04 100.34,29.33 100.34,29.73 100.63,30.02 100.63,39.35 105.06,43.79 107.71,43.79 108.28,44.36 110.4,44.36 110.54,44.22 110.54,43.95 110.69,43.8 110.98,43.8 111.12,43.95 111.12,44.22 111.27,44.36 112.07,44.36 112.64,43.79 114.14,43.79 117.75,47.4
  BOTTOM w0.076: v1(128.03,51.3) 128.18,51.3 UCPU1.AU39
DDR_A_MA5: length 125.9
  TOP w0.076: UD29.P2 91.8,26.24 ; RD47.1 105.12,22.12 103.83,23.42 v2(103.83,23.83) v1(103.83,24.55) ; UD28.P2 79.19,26.24
  TOP w0.102: UD31.P2 107.52,26.25 107.52,26.25 v1(107.94,25.84) ; 91.8,26.24 v1(91.4,25.84) ; v1(119.74,25.84) 119.74,25.85 120.15,26.25 UD32.P2 ; 79.19,26.24 v1(79.59,25.84)
  IN1 w0.076: v4(86.54,25.43) 86.82,25.71 87.89,25.71 88.31,25.28 89.92,25.28 90.14,25.07 91.35,25.07 91.96,24.46 92.53,24.46 93.15,23.84 94.77,23.84 94.95,23.66 95.74,23.66 96.24,24.15 97.6,24.15 98.48,25.03 101.38,25.03 101.69,24.72 102.18,24.72 102.52,25.06 103.13,25.06 103.64,24.55 v1(103.83,24.55) 103.93,24.65 105.44,24.65 105.92,24.18 106.06,24.18 106.13,24.25 106.27,24.25 106.42,24.1 106.42,23.96 106.35,23.89 106.35,23.75 106.5,23.59 106.56,23.59 106.71,23.73 106.81,23.73 106.95,23.59 109.39,23.59 109.5,23.7 109.5,23.82 109.29,24.03 109.29,24.42 109.56,24.69 109.69,24.69 109.79,24.59 109.79,24.46 109.61,24.27 109.61,24.14 109.7,24.05 109.83,24.05 110.08,24.3 110.08,24.67 110.18,24.76 110.31,24.76 110.41,24.67 110.41,24.3 110.51,24.2 111.08,24.2 111.18,24.3 111.18,24.68 111.26,24.76 111.43,24.76 111.54,24.66 111.54,24.33 111.64,24.23 111.81,24.23 111.91,24.33 111.91,24.88 112.01,24.98 112.2,24.98 112.3,24.88 112.3,24.33 112.4,24.23 112.56,24.23 112.67,24.33 112.67,24.88 112.77,24.98 112.95,24.98 113.05,24.88 113.05,24.7 113.15,24.6 113.33,24.6 113.43,24.7 113.43,24.88 113.53,24.98 113.68,24.98 113.78,24.88 113.78,24.71 113.89,24.61 114.02,24.61 114.13,24.71 114.13,24.88 114.23,24.98 114.79,24.98 114.89,25.08 v4(114.89,25.25)
  IN4 w0.076: v1(91.4,25.84) 90.89,25.33 90.29,25.33 90.15,25.47 90.15,25.97 90.08,26.05 89.92,26.05 89.85,25.97 89.85,25.47 89.77,25.39 89.62,25.39 89.54,25.47 89.54,25.96 89.47,26.04 89.31,26.04 89.24,25.96 89.24,25.47 89.16,25.39 88.2,25.39 88.02,25.57 87.69,25.57 87.35,25.24 86.73,25.24 v4(86.54,25.43) 86.43,25.31 83.57,25.31 82.65,26.23 79.98,26.23 v1(79.59,25.84) ; v1(107.94,25.84) 108.3,26.2 109.91,26.2 110,26.11 110.99,26.11 111.84,25.26 112.56,25.26 112.92,24.91 114.55,24.91 v4(114.89,25.25) 114.99,25.35 116.16,25.35 116.29,25.49 116.76,25.49 116.95,25.29 117.85,25.29 117.93,25.36 117.93,25.74 118,25.82 118.16,25.82 118.23,25.74 118.23,25.36 118.31,25.29 118.57,25.29 118.64,25.35 119.11,25.35 119.18,25.43 119.18,25.49 119.26,25.57 119.41,25.57 119.49,25.49 119.49,25.43 119.56,25.35 119.87,25.35 120.26,25.74 120.26,25.88 120.18,25.96 119.87,25.96 v1(119.74,25.84) ; v1(129.53,52.59) 129.53,52.01 130.33,51.21 130.33,46.99 129.56,46.22 129.18,46.22 128.29,45.33 128.29,44.31 127.19,43.22
  IN4 w0.145: v1(103.83,24.55) 103.81,24.56 103.81,26.02 103.38,26.46 103.38,28.61 103.24,28.75 103.24,33.43 104.75,34.94 104.75,38.29 105.82,39.36 106.69,40.24 116.34,40.24 118.53,42.43 126.4,42.43 127.19,43.22
  BOTTOM w0.076: v1(129.53,52.59) 129.7,52.76 UCPU1.AR36
DDR_A_MA6: length 120.5
  TOP w0.076: v1(102.18,25.56) 101.82,25.21 RD86.1 ; v1(83.58,25.85) 83.58,25.38 83.65,25.31 83.85,25.31 UD28.R8
  TOP w0.102: v1(124.55,25.87) 124.55,25.87 124.55,25.88 124.95,25.49 124.95,25.48 UD32.R8 ; UD29.R8 96.6,25.45 96.37,25.45 96.21,25.62 96.21,25.87 v1(96.2,25.87) ; v1(111.9,25.85) 112.29,25.45 UD31.R8
  IN1 w0.076: v4(116.99,25.82) 116.81,25.63 114.71,25.63 114.27,25.19 111.61,25.19 111.39,24.96 109.54,24.96 109.08,24.5 109.08,24.06 108.83,23.8 107.03,23.8 105.88,24.94 103.46,24.94 102.84,25.56 v1(102.18,25.56) 102.18,25.55 101.21,25.55 101.21,25.54 100.91,25.25 98.32,25.25 97.47,24.4 95.89,24.4 95.76,24.28 95.76,23.99 95.64,23.86 95.06,23.86 94.94,23.97 94.94,24.43 94.84,24.54 94.66,24.54 94.53,24.41 94.12,24.41 94,24.54 94,24.98 93.91,25.07 93.72,25.07 93.59,24.94 93.59,24.77 93.49,24.66 92.04,24.66 91.22,25.49 90.94,25.49 90.74,25.3 90.26,25.3 90.15,25.41 90.15,25.58 90.06,25.67 88.82,25.67 v4(88.67,25.82)
  IN4 w0.076: 124.62,45.62 125.24,45.62 125.76,45.1 126.72,45.1 126.99,45.37 126.99,46.2 127.33,46.55 127.33,47 ; v1(111.9,25.85) 111.74,25.69 111.74,25.58 111.89,25.43 112.07,25.43 112.15,25.5 112.15,25.57 112.23,25.64 112.38,25.64 112.45,25.57 112.45,25.5 112.53,25.43 112.63,25.43 113,25.06 113.09,25.06 113.14,25.11 113.14,25.3 113.22,25.38 113.37,25.38 113.45,25.3 113.45,25.13 113.52,25.06 113.67,25.06 113.75,25.13 113.75,25.31 113.83,25.39 113.98,25.39 114.06,25.31 114.06,25.13 114.13,25.06 114.37,25.06 114.43,25.12 114.43,25.53 114.51,25.6 115.07,25.6 115.17,25.5 115.92,25.5 116.27,25.86 116.46,25.86 116.68,25.64 116.82,25.64 v4(116.99,25.82) 117.2,26.02 118.52,26.02 118.7,26.2 120.65,26.2 120.77,26.09 122.29,26.09 122.42,26.21 124.21,26.21 v1(124.55,25.87) ; v1(83.58,25.85) 83.49,25.76 83.49,25.61 83.62,25.49 84.54,25.49 84.7,25.66 84.85,25.66 85.02,25.49 85.67,25.49 85.77,25.59 85.77,25.91 85.95,26.09 86.33,26.09 86.47,25.95 86.82,25.95 86.89,25.87 86.89,25.47 86.97,25.39 87.12,25.39 87.2,25.47 87.2,25.87 87.27,25.95 87.42,25.95 87.5,25.87 87.5,25.8 87.58,25.72 87.73,25.72 87.81,25.8 87.81,25.87 87.88,25.95 88.02,25.95 88.15,25.82 88.15,25.66 88.22,25.58 88.57,25.58 88.67,25.68 v4(88.67,25.82) 88.87,25.82 89.26,26.2 92.98,26.2 93.12,26.06 94.17,26.06 94.33,26.21 95.86,26.21 v1(96.2,25.87)
  IN4 w0.086: v1(127.99,47.28) 127.61,47.28 127.33,47
  IN4 w0.145: v1(102.18,25.56) 102.33,25.72 102.33,26.01 101.86,26.48 101.86,28.02 101.75,28.13 101.75,34.34 101.89,34.48 102.19,34.48 102.52,34.82 102.52,34.94 102.4,35.06 101.89,35.06 101.75,35.21 101.75,35.5 101.89,35.64 102.47,35.64 102.58,35.75 102.58,35.86 102.21,36.22 101.89,36.22 101.75,36.37 101.75,37.88 101.86,37.99 102.06,37.99 102.26,38.19 102.26,38.45 102.15,38.56 101.85,38.56 101.75,38.67 101.75,38.89 101.96,39.1 102.12,39.1 102.23,39.21 102.23,39.37 105.53,42.67 115.48,42.67 115.76,42.94 115.76,43.17 116.11,43.52 116.34,43.52 116.58,43.76 116.58,44.03 116.89,44.34 117.16,44.34 117.4,44.58 117.4,44.83 117.73,45.16 117.98,45.16 118.43,45.62 124.62,45.62
  BOTTOM w0.076: v1(127.99,47.28) 127.32,47.96 127.32,50.67 UCPU1.AV40
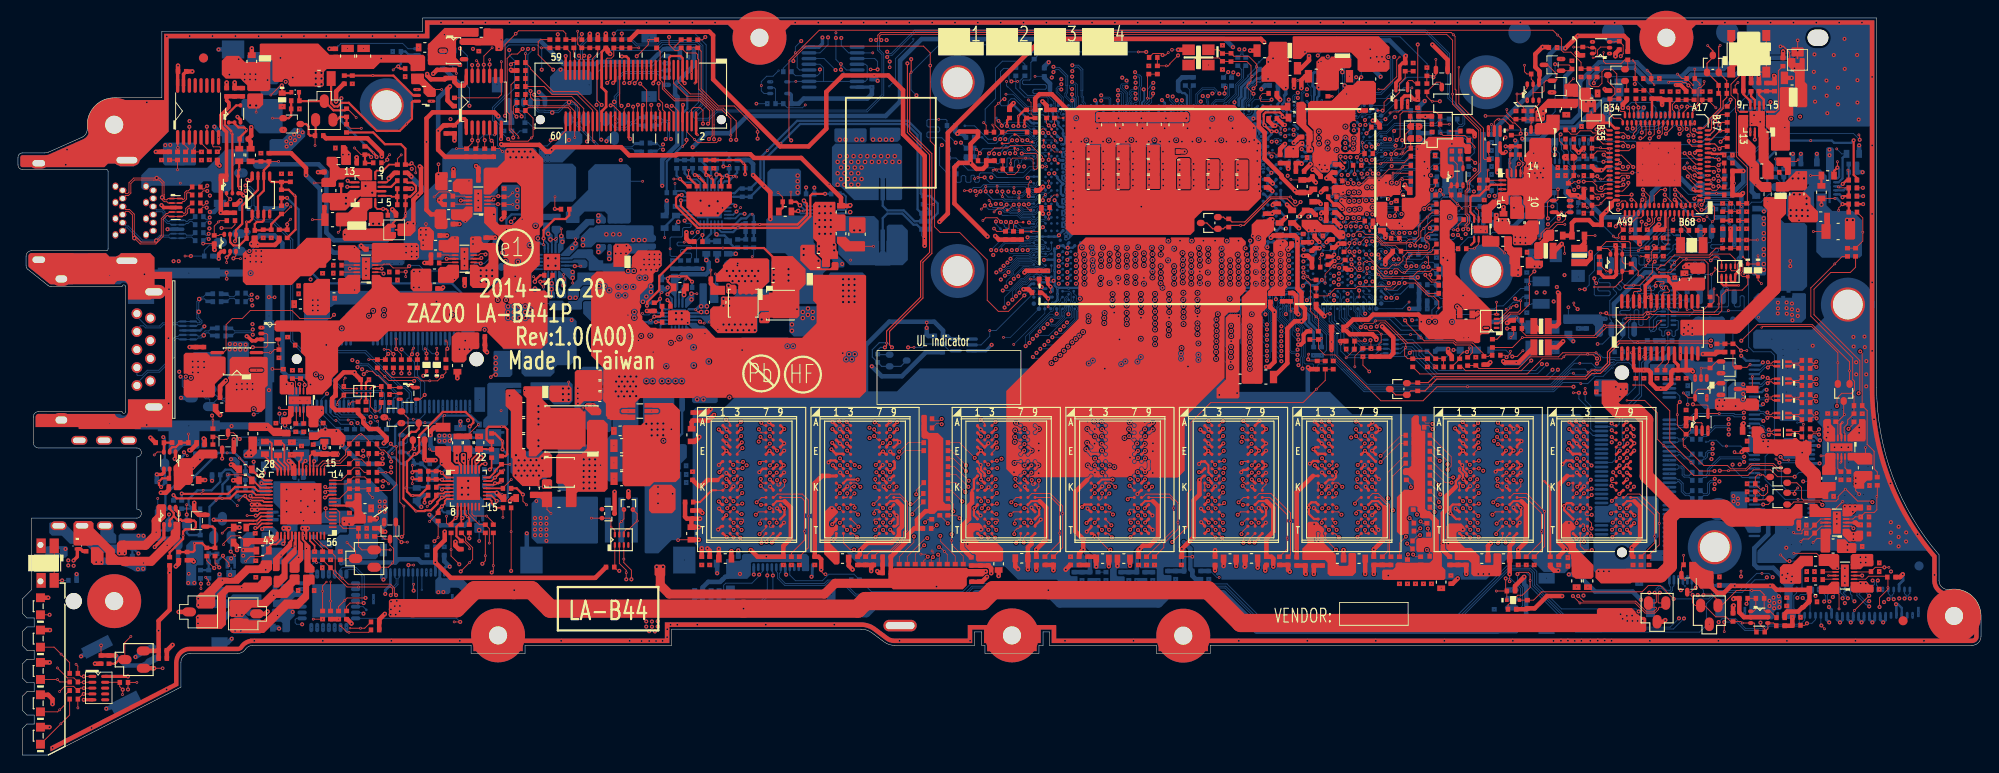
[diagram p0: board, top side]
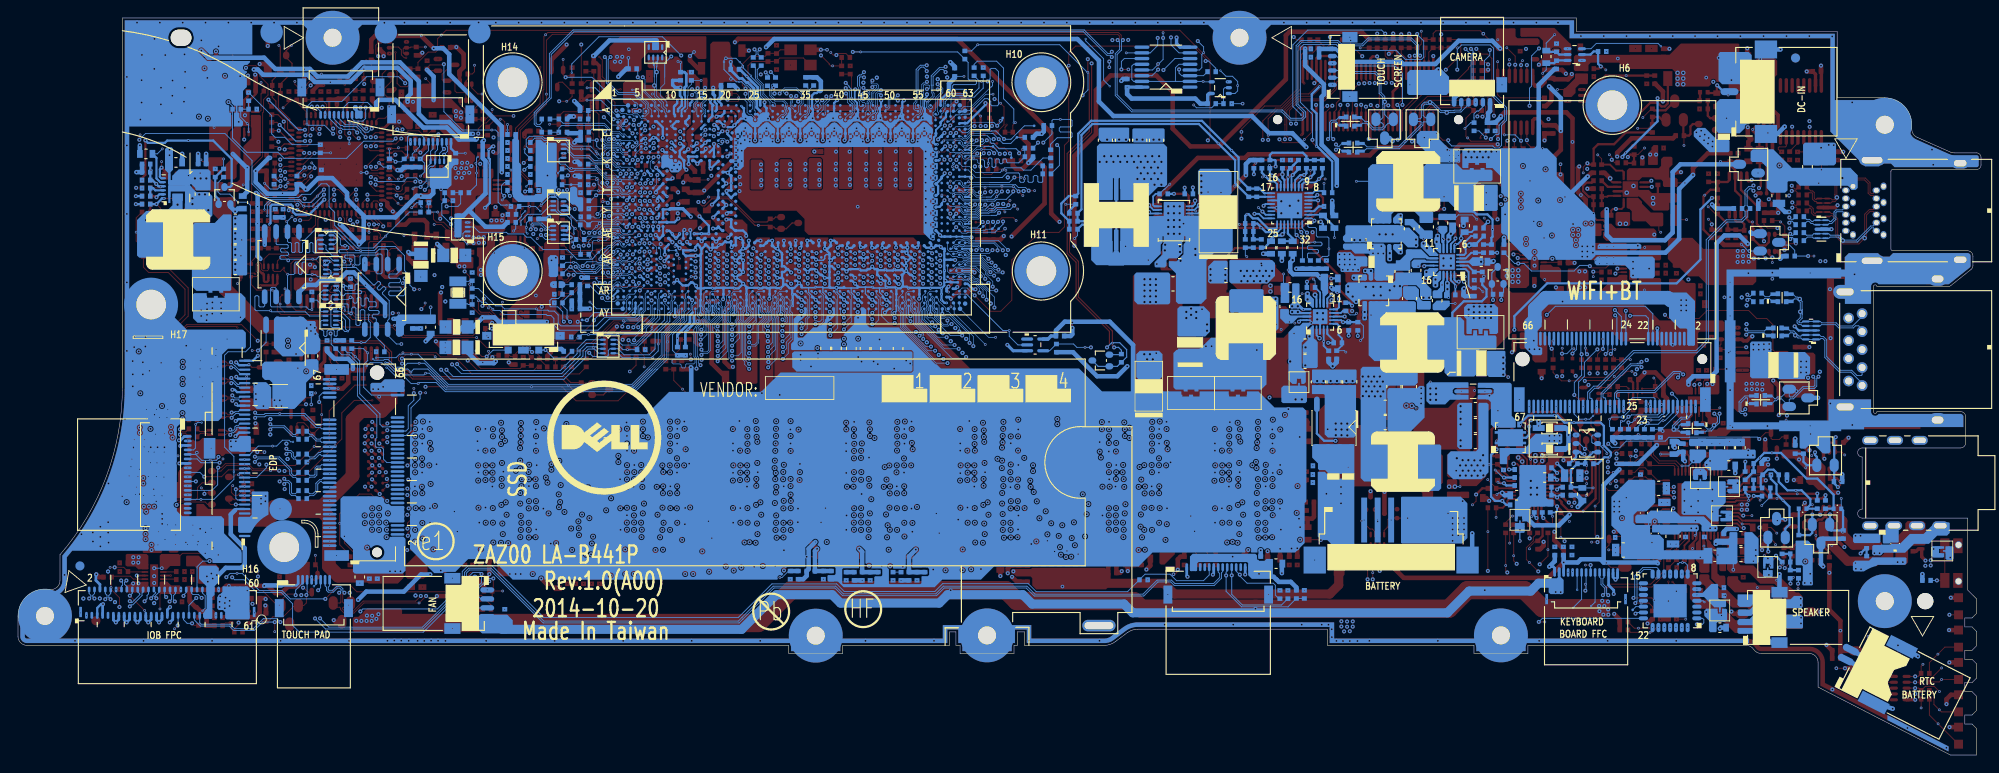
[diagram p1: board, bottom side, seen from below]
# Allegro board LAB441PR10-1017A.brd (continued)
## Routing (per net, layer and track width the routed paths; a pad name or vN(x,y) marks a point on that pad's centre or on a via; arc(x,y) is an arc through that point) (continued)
DDR_A_MA7: length 122.3
  TOP w0.076: v1(101.12,24.13) 100.95,24.13 98.9,22.09 RD85.1
  TOP w0.102: UD29.R2 91.8,25.45 v1(92.2,25.05) ; v1(120.55,25.05) 120.55,25.05 120.15,25.45 UD32.R2 ; UD28.R2 79.2,25.45 v1(79.6,25.05) ; v1(107.92,25.05) 107.51,25.45 UD31.R2
  IN1 w0.076: v4(86.49,24.06) 86.8,24.06 86.89,24.14 88.24,24.14 88.7,24.6 89.26,24.6 89.72,24.14 89.94,24.14 90.86,23.23 94.14,23.23 94.45,22.92 96.28,22.92 96.54,23.18 98.05,23.18 98.75,23.88 99.76,23.88 100.01,24.13 v1(101.12,24.13) 101.79,24.13 102.43,23.5 104.35,23.5 105.11,22.73 109.66,22.73 109.97,23.04 110.13,23.04 110.44,22.73 110.62,22.73 110.93,23.04 111.05,23.04 111.36,22.73 111.7,22.73 112.01,23.04 112.26,23.04 113.23,24.02 114.87,24.02 v4(114.98,23.91)
  IN4 w0.076: v1(128.02,50) 126.99,48.97 126.99,47.05 126.68,46.74 124.11,46.74 123.51,46.14 119.88,46.14 118.6,47.42 118.18,47.42 117.7,46.95 ; v1(107.92,25.05) 108.3,25.44 109.2,25.44 109.47,25.17 111.08,25.17 111.6,24.65 112.3,24.65 113.04,23.91 v4(114.98,23.91) 115.2,23.69 116.08,23.69 116.5,24.11 119.42,24.11 119.52,24 119.52,23.7 119.66,23.56 119.98,23.56 120.46,24.04 120.46,24.14 119.96,24.65 119.96,24.78 120.22,25.05 v1(120.55,25.05) ; v1(92.2,25.05) 91.92,24.77 91.67,24.77 91.59,24.69 91.59,24.54 91.51,24.46 91.36,24.46 91.28,24.54 91.28,24.69 91.21,24.77 88.92,24.77 88.5,24.35 88.13,24.35 88.06,24.28 88.06,24.15 87.96,24.06 87.81,24.06 87.74,24.13 87.74,24.3 87.66,24.37 87.51,24.37 87.43,24.3 87.43,24.13 87.36,24.06 87.2,24.06 87.13,24.13 87.13,24.3 87.05,24.37 86.9,24.37 86.82,24.3 86.82,24.13 86.75,24.06 v4(86.49,24.06) 86.3,23.86 85.04,23.86 84.28,24.63 83.37,24.63 82.82,25.17 82.07,25.17 81.77,25.48 80.02,25.48 v1(79.6,25.05)
  IN4 w0.145: 117.7,46.95 114.17,43.41 110.22,43.41 110.14,43.5 110.14,43.84 110.04,43.94 109.66,43.94 109.56,43.85 109.56,43.5 109.47,43.41 109.08,43.41 108.98,43.51 108.98,43.84 108.88,43.94 108.48,43.94 108.4,43.87 108.4,43.5 108.31,43.41 105.22,43.41 101,39.2 101,28.71 100.75,28.46 100.75,28.32 101,28.07 101,27.74 101.18,27.57 101.18,27.29 101.09,27.2 100.95,27.2 100.89,27.14 100.89,26.66 100.98,26.57 101.05,26.57 101.14,26.48 101.14,26.2 101.43,25.91 101.43,25.47 101.25,25.29 100.66,25.29 100.55,25.18 100.55,24.97 100.8,24.71 101.3,24.71 101.41,24.6 101.41,24.23 101.31,24.13 v1(101.12,24.13)
  BOTTOM w0.076: v1(128.02,50) 128.03,50 128.33,50.3 UCPU1.AW39
DDR_A_MA8: length 125.9
  TOP w0.076: RD98.1 101.57,21.83 v1(101.76,22.02) 101.76,22.6 v2(101.66,22.7) ; 96.59,24.65 UD29.T8
  TOP w0.102: v1(124.55,25.04) 124.94,24.65 UD32.T8 ; v1(83.24,23.72) 83.24,23.91 UD28.T8 ; UD31.T8 111.85,24.2 v1(111.85,23.64) ; 96.59,24.65 v1(96.21,25.04)
  IN1 w0.076: v4(88.02,22.66) 88.41,22.66 88.83,22.24 89.51,22.24 90.38,21.38 98.59,21.38 98.59,21.38 98.7,21.48 98.7,22.15 98.8,22.25 99,22.25 99.1,22.15 99.1,21.67 99.22,21.55 99.39,21.55 99.51,21.67 99.51,22.37 99.61,22.47 101.32,22.47 v1(101.76,22.02) 101.96,21.82 103.78,21.82 104.19,21.41 113.31,21.41 114.34,22.44 116.95,22.44 117.48,22.97 v4(117.75,22.97)
  IN4 w0.076: v1(128.03,49.3) 127.16,48.43 127.16,46.62 126.82,46.28 126.82,45.54 126.61,45.34 125.92,45.34 125.32,45.94 123.59,45.94 ; v1(124.55,25.04) 124.55,24.35 124.45,24.25 124.27,24.25 124.17,24.35 124.17,24.58 124.07,24.69 123.49,24.69 122.28,23.48 121.31,23.48 120.22,22.39 118.34,22.39 v4(117.75,22.97) 117.48,22.97 116.84,22.33 115.7,22.33 115.59,22.44 112.77,22.44 112.67,22.54 112.67,23.01 112.56,23.12 112.36,23.12 112.26,23.01 112.26,22.54 112.16,22.44 111.95,22.44 111.85,22.54 v1(111.85,23.64) ; v1(96.21,25.04) 95.77,24.6 95.22,24.6 93.97,23.36 92.56,23.36 91.77,22.57 90.01,22.57 89.86,22.42 88.55,22.42 88.31,22.66 v4(88.02,22.66) 87.22,22.66 86.89,22.33 85.25,22.33 85.17,22.4 85.17,22.59 85.1,22.67 84.95,22.67 84.87,22.59 84.87,22.4 84.79,22.33 84.64,22.33 84.56,22.4 84.56,23.09 84.49,23.17 84.34,23.17 84.26,23.09 84.26,22.57 84.18,22.49 84.03,22.49 83.96,22.57 83.96,23.15 83.88,23.23 83.73,23.23 83.65,23.15 83.65,22.61 83.56,22.52 83.33,22.52 83.24,22.61 v1(83.24,23.72)
  IN4 w0.145: 123.59,45.94 117.89,45.94 114.99,43.04 105.37,43.04 101.38,39.04 101.38,27.84 101.51,27.71 101.51,26.35 101.76,26.1 101.76,25.49 101.58,25.31 101.58,24.86 101.76,24.68 101.76,24.33 101.93,24.17 101.93,23.6 101.4,23.06 101.4,22.42 101.76,22.06 v1(101.76,22.02)
  BOTTOM w0.076: UCPU1.AY39 128.38,49.65 v1(128.03,49.3)
DDR_A_MA9: length 122.7
  TOP w0.076: v1(102.43,23.13) 102.54,23.13 v2(103.03,22.64) 103.34,22.33 RD83.1
  TOP w0.102: UD29.R3 92.65,25.45 v1(93.05,25.05) ; v1(80.47,25.04) 80.06,25.45 UD28.R3 ; v1(121.35,25.06) 121.35,25.05 UD32.R3 ; v1(108.79,25.04) 108.38,25.45 UD31.R3
  IN1 w0.076: v4(88.46,23.76) 89.85,23.76 90.72,22.9 92.32,22.9 92.82,22.4 93.96,22.4 94.15,22.59 97.88,22.59 98.87,23.59 99.88,23.59 100.01,23.72 100.89,23.72 101.19,23.43 102.13,23.43 v1(102.43,23.13) 103.96,23.13 104.69,22.4 112.08,22.4 113.21,23.53 116.03,23.53 116.16,23.66 116.16,23.83 116.28,23.95 116.45,23.95 116.56,23.83 v4(116.56,23.61)
  IN4 w0.076: v1(80.47,25.04) 80.52,25 82.64,25 83.21,24.43 84.18,24.43 84.9,23.71 86.64,23.71 86.69,23.76 v4(88.46,23.76) 88.65,23.57 89.09,23.57 89.17,23.65 89.17,24.39 89.24,24.46 89.4,24.46 89.47,24.39 89.47,23.65 89.55,23.57 89.7,23.57 89.78,23.65 89.78,24.33 89.85,24.41 90.01,24.41 90.08,24.33 90.08,23.65 90.16,23.57 91.02,23.57 91.1,23.65 91.1,23.95 91.17,24.03 92.04,24.03 v1(93.05,25.05) ; v1(108.79,25.04) 108.87,24.96 111.05,24.96 111.56,24.45 112.21,24.45 113.13,23.53 114.3,23.53 114.31,23.53 116.48,23.53 v4(116.56,23.61) 116.56,23.89 116.63,23.95 116.79,23.95 116.85,23.9 116.85,23.86 116.92,23.79 117.07,23.79 117.15,23.86 117.15,23.9 117.2,23.95 117.38,23.95 117.45,23.88 117.45,23.81 117.53,23.74 117.68,23.74 117.76,23.81 117.76,23.88 117.84,23.95 117.99,23.95 118.06,23.88 118.06,23.81 118.14,23.74 118.29,23.74 118.37,23.81 118.37,23.88 118.45,23.95 118.64,23.95 118.71,23.88 118.71,23.83 118.94,23.6 119,23.6 119.08,23.67 119.08,23.88 119.16,23.95 119.3,23.95 119.37,23.88 119.37,23.5 119.46,23.41 120.04,23.41 120.69,24.06 120.69,24.16 120.4,24.46 120.4,24.57 120.5,24.68 120.61,24.68 120.91,24.38 121.02,24.38 121.35,24.72 v1(121.35,25.06) ; 126.65,44.78 127.16,45.3 127.16,45.89 v1(127.97,46.7)
  IN4 w0.145: v1(102.43,23.13) 102.67,23.13 102.82,23.28 102.82,23.41 102.56,23.67 102.29,23.67 102.15,23.82 102.15,24.64 102.29,24.78 102.54,24.78 102.67,24.9 102.67,26.04 102.26,26.45 102.26,28.14 102.12,28.28 102.12,33.95 102.86,34.69 102.86,35.42 102.91,35.47 102.91,36 102.12,36.79 102.12,37.56 102.6,38.04 102.6,39.21 105.68,42.29 115.58,42.29 118.64,45.35 125.22,45.35 125.79,44.78 126.65,44.78
  BOTTOM w0.076: UCPU1.AU40 127.41,51.46 127.41,51.39 127.15,51.12 127.15,47.52 v1(127.97,46.7)
DDR_A_MA10: length 128.4
  TOP w0.076: v1(105.35,29.26) 104.31,30.3 RD36.1 ; UD29.L7 95.8,28.65
  TOP w0.102: v1(95.15,27.9) 95.8,28.55 95.8,28.65 ; v1(110.47,28.11) 111.01,28.65 111.51,28.65 UD31.L7 ; UD32.L7 124.15,28.65 123.61,28.65 v1(123.42,28.46) ; UD28.L7 82.69,28.65 v1(82.15,28.11)
  IN1 w0.076: v4(114.98,28.74) 115.12,28.74 115.22,28.64 115.22,28.47 115.09,28.35 114.85,28.35 114.61,28.59 114.46,28.59 114.17,28.3 112.98,28.3 112.89,28.39 112.89,28.65 112.81,28.74 112.64,28.74 112.56,28.67 112.56,28.38 112.47,28.29 112.34,28.29 112.25,28.38 112.25,28.67 112.18,28.74 112.03,28.74 111.95,28.67 111.95,28.3 111.86,28.21 111.73,28.21 111.64,28.3 111.64,28.67 111.57,28.74 111.42,28.74 111.34,28.67 111.34,28.53 111.26,28.45 111.11,28.45 111.04,28.53 111.04,28.67 110.96,28.74 110.01,28.74 109.88,28.61 109.88,28.13 109.76,28 109.55,28 109.45,28.1 109.45,28.38 109.57,28.5 109.57,28.61 109.44,28.74 109.28,28.74 109.1,28.56 108.38,28.56 108.27,28.67 108.27,28.89 108.18,28.97 108.04,28.97 107.89,28.82 107.73,28.82 107.65,28.9 107.65,28.98 107.57,29.06 107.43,29.06 107.34,28.97 107.34,28.88 107.25,28.78 107.1,28.78 107,28.88 107,29.03 106.94,29.1 106.71,29.1 106.65,29.03 106.65,28.53 106.45,28.34 106.3,28.34 106.14,28.5 106.14,28.63 106.32,28.81 106.32,29.4 106.24,29.48 106.05,29.48 105.96,29.39 105.96,29 105.86,28.89 105.72,28.89 v1(105.35,29.26) 105.21,29.4 98.46,29.4 98.1,29.04 93.84,29.04 93.32,28.52 91.19,28.52 90.26,29.45 89.99,29.45 89.64,29.8 89.07,29.8 88.82,29.54 v4(88.36,29.54)
  IN4 w0.076: 131.68,43.38 132.42,44.13 132.42,50.69 131.03,52.08 131.03,52.54 v1(130.48,53.08) ; v1(95.15,27.9) 94.3,28.74 92.9,28.74 92.75,28.59 91.18,28.59 90.01,29.76 88.99,29.76 88.65,29.41 88.49,29.41 v4(88.36,29.54) 88.13,29.31 87.21,29.31 87.11,29.42 87,29.42 86.89,29.31 86.89,29.2 87,29.1 87,28.99 86.89,28.88 86.78,28.88 86.66,29 86.55,29 86.44,28.9 86.44,28.79 86.56,28.67 86.56,28.56 86.37,28.37 85.22,28.37 85.12,28.47 83.43,28.47 83.3,28.34 82.37,28.34 v1(82.15,28.11) ; v1(123.42,28.46) 123.42,28.45 123.38,28.41 119.47,28.41 118.13,29.76 117.59,29.76 116.86,29.02 115.66,29.02 115.45,28.81 115.04,28.81 v4(114.98,28.74) 114.98,28.34 114.86,28.22 114.62,28.22 114.54,28.3 114.54,28.34 114.47,28.41 114.31,28.41 114.24,28.34 114.24,28.3 114.16,28.22 114.01,28.22 113.93,28.3 113.93,28.34 113.86,28.41 113.7,28.41 113.63,28.34 113.63,28.3 113.55,28.22 113.4,28.22 113.32,28.3 113.32,28.34 113.25,28.41 113.1,28.41 113.02,28.34 113.02,28.3 112.94,28.22 112.79,28.22 112.71,28.3 112.71,28.34 112.64,28.41 112.49,28.41 112.41,28.34 112.41,28.3 112.33,28.22 112.18,28.22 112.1,28.3 112.1,28.34 112.03,28.41 111.88,28.41 111.8,28.34 111.8,28.3 111.72,28.22 111.05,28.22 110.75,28.53 109.69,28.53 109.36,28.2 109.36,27.81 109.53,27.65 110.32,27.65 110.47,27.8 v1(110.47,28.11)
  IN4 w0.145: 131.68,43.38 126.78,38.49 123.06,38.49 121.24,36.67 120.35,36.67 120.32,36.7 118.77,36.7 118.3,37.16 117.47,37.16 117.39,37.24 117.11,37.24 117.11,37.24 116.97,37.09 116.97,36.41 116.83,36.27 116.51,36.27 116.39,36.4 116.39,37.39 116.28,37.5 115.95,37.5 115.81,37.36 115.81,36.41 115.69,36.29 115.35,36.29 115.23,36.4 115.23,36.78 115.14,36.87 114.78,36.87 114.65,36.75 114.65,36.42 114.52,36.29 114.19,36.29 114.07,36.4 114.07,36.55 113.93,36.7 113.37,36.7 113,36.32 112.59,36.32 112.22,36.7 111.8,36.7 111.63,36.53 110.08,36.53 109.66,36.11 109.66,33.95 109.25,33.54 108.87,33.54 108.37,33.05 108.37,32.18 108.11,31.92 107.78,31.92 107.24,31.38 105.87,31.38 105.67,31.18 105.37,31.18 104.83,30.65 104.83,29.82 105.33,29.32 105.33,29.28 v1(105.35,29.26)
  BOTTOM w0.076: v1(130.48,53.08) 130.81,53.41 UCPU1.AP35
DDR_A_MA11: length 127.3
  TOP w0.076: RD59.1 99.79,22.36 v1(100.77,23.34)
  TOP w0.102: UD29.R7 95.73,25.45 v1(95.34,25.07) ; UD28.R7 83.19,25.45 83.19,25.29 v1(82.48,24.58) ; v1(110.8,24.58) 110.8,24.89 111.13,25.22 111.28,25.22 UD31.R7 ; UD32.R7 124.08,25.45 v1(123.69,25.07)
  IN1 w0.076: v4(117.14,23.45) 116.95,23.26 116.41,23.26 116.34,23.33 115.88,23.33 115.8,23.26 114.17,23.26 113.36,22.44 113.07,22.44 112.89,22.62 112.72,22.62 112.17,22.07 104.56,22.07 103.94,22.68 102.37,22.68 101.77,23.28 100.83,23.28 v1(100.77,23.34) 100.46,23.03 98.73,23.03 97.97,22.26 96.12,22.26 95.93,22.07 95.71,22.07 95.52,22.26 95.31,22.26 95.12,22.07 94.9,22.07 94.71,22.26 94.49,22.26 94.3,22.07 92.38,22.07 92.28,22.17 92.28,22.47 92.18,22.57 91.97,22.57 91.87,22.47 91.87,22.17 91.77,22.07 91.57,22.07 91.46,22.17 91.46,22.47 91.36,22.57 91.13,22.57 91.03,22.47 91.03,22.17 90.92,22.07 90.62,22.07 90.47,22.22 90.47,22.36 90.56,22.44 90.56,22.59 90.41,22.73 90.27,22.73 90.18,22.65 90.04,22.65 89.89,22.8 89.89,22.94 89.98,23.02 89.98,23.16 89.83,23.31 89.69,23.31 89.6,23.23 89.46,23.23 89.31,23.38 87.07,23.38 v4(86.99,23.29)
  IN4 w0.076: v1(110.8,24.58) 110.11,24.58 109.99,24.46 109.99,24.28 110.11,24.16 112.22,24.16 112.99,23.38 113.52,23.38 113.72,23.18 115.79,23.18 115.93,23.32 116.37,23.32 116.51,23.18 116.88,23.18 v4(117.14,23.45) 117.27,23.57 118.75,23.57 119.07,23.25 120.12,23.25 121.47,24.6 121.94,24.6 122.04,24.5 122.04,24.33 122.16,24.21 122.33,24.21 122.45,24.33 122.45,24.5 122.55,24.6 123.05,24.6 123.19,24.74 123.19,25.35 123.32,25.48 123.56,25.48 123.69,25.35 v1(123.69,25.07) ; v1(95.34,25.07) 95.34,25.07 94.04,25.07 93.57,24.6 93.13,24.6 91.83,23.29 v4(86.99,23.29) 85.03,23.29 84.1,24.23 82.65,24.23 82.62,24.2 80.88,24.2 80.76,24.31 80.76,24.47 80.88,24.58 v1(82.48,24.58) ; v1(126.45,50) 126.08,49.64 124.75,49.64 123.95,48.84 121.69,48.84
  IN4 w0.086: 121.69,48.84 120.86,49.67 119.26,49.67
  IN4 w0.145: 119.26,49.67 115.14,49.67 112.22,46.75 105.91,46.75 99.14,39.97 99.14,31.54 98.87,31.27 98.87,27.75 99.41,27.22 99.61,27.22 99.87,26.95 99.87,26.35 99.75,26.23 99.75,24.82 100.34,24.22 100.34,23.77 v1(100.77,23.34)
  BOTTOM w0.076: v1(126.45,50) 126.46,50 126.76,50.3 UCPU1.AW41
DDR_A_MA12: length 123.1
  TOP w0.076: RD25.1 99.46,26.93 v1(99.46,26.79)
  TOP w0.102: UD28.N7 82.38,27.06 v1(82.06,26.74) ; v1(95.23,26.88) 95.23,27.18 95.36,27.31 95.67,27.31 95.8,27.18 UD29.N7 ; UD32.N7 124.15,27.05 124.15,27.24 124.05,27.34 123.68,27.34 123.58,27.24 v1(123.58,26.88) ; v1(110.38,26.74) 110.7,27.06 111.51,27.06 UD31.N7
  IN1 w0.076: v4(117.01,27.17) 116.24,27.17 115.43,26.37 114.61,26.37 114.04,25.8 113.58,25.8 112.94,26.44 111.25,26.44 110.96,26.15 110.71,26.15 110.59,26.04 109.08,26.04 108.9,26.22 107.78,26.22 107.24,25.68 106.23,25.68 105.97,25.93 103.76,25.93 103.01,26.69 99.55,26.69 v1(99.46,26.79) 98.86,26.79 98.81,26.74 98.81,26.65 98.7,26.54 98.55,26.54 98.44,26.65 98.44,26.88 98.34,26.98 98.19,26.98 98.09,26.87 98.09,26.19 97.96,26.06 97.73,26.06 97.51,26.27 95.99,26.27 95.86,26.4 95.86,26.53 95.76,26.63 95.57,26.63 95.47,26.53 95.47,26.33 95.37,26.23 95.22,26.23 95.05,26.39 94.91,26.39 94.8,26.28 94.8,26.14 95.04,25.9 95.04,25.78 94.94,25.68 94.7,25.68 94.3,26.07 94.3,26.23 94.84,26.77 94.84,26.9 94.69,27.05 94.55,27.05 93.67,26.18 92.87,26.18 92.77,26.28 92.77,26.55 92.67,26.65 92.51,26.65 92.41,26.55 92.41,26.36 92.31,26.26 92.14,26.26 92.04,26.36 92.04,26.55 91.94,26.65 90.2,26.65 90.06,26.51 89.93,26.51 89.86,26.58 89.86,26.74 89.74,26.85 89.6,26.85 89.41,26.66 89.21,26.66 89.11,26.76 89.11,26.95 89.31,27.15 89.31,27.31 89.22,27.4 88.91,27.4 v4(88.69,27.17)
  IN4 w0.076: v1(95.23,26.88) 94.31,26.88 93.84,27.34 93.39,27.34 92.83,26.79 90.45,26.79 90.07,27.17 v4(88.69,27.17) 87.96,27.17 87.57,26.79 85.7,26.79 85.55,26.63 83.28,26.63 83.01,26.9 82.22,26.9 v1(82.06,26.74) ; 114.05,50.94 114.39,51.28 120.25,51.28 120.85,51.88 126.01,51.88 126.46,51.44 v1(126.46,51.3) ; v1(123.58,26.88) 122.83,26.88 122.53,27.18 121.67,27.18 121.2,26.71 117.7,26.71 117.23,27.17 v4(117.01,27.17) 116.36,27.17 115.7,26.52 114.51,26.52 114.33,26.7 112.28,26.7 112.12,26.53 110.58,26.53 v1(110.38,26.74)
  IN4 w0.145: v1(99.46,26.79) 99.2,26.79 98.49,27.5 98.49,31.8 97.4,32.9 97.4,35.67 97.38,35.69 97.38,37.85 97.61,38.08 97.61,38.43 97.5,38.54 97.06,38.54 96.91,38.68 96.91,38.97 97.06,39.12 97.5,39.12 97.61,39.22 97.61,39.57 97.36,39.82 97.36,40.34 105.5,48.47 111.58,48.47 114.05,50.94
  BOTTOM w0.076: UCPU1.AU41 126.61,51.3 v1(126.46,51.3)
DDR_A_MA13: length 125.1
  TOP w0.076: v1(102.33,22.29) 102.46,22.16 RD72.1
  TOP w0.102: v1(80.34,24.18) 79.99,24.53 UD28.T3 ; v1(108.67,24.18) 108.31,24.53 UD31.T3 ; v1(93.31,24.22) 92.88,24.65 UD29.T3 ; v1(121.66,24.22) 121.22,24.65 UD32.T3
  IN1 w0.076: v4(88.7,22.92) 88.7,22.61 88.92,22.39 89.88,22.39 90.53,21.74 96.24,21.74 96.34,21.84 96.34,21.85 96.44,21.95 96.65,21.95 96.75,21.85 96.75,21.84 96.85,21.74 97.05,21.74 97.15,21.84 97.15,21.85 97.26,21.95 97.46,21.95 97.56,21.85 97.56,21.84 97.66,21.74 97.87,21.74 99,22.87 101.13,22.87 101.58,22.42 102.2,22.42 v1(102.33,22.29) 103.92,22.29 104.47,21.74 113.08,21.74 114.42,23.08 114.8,23.08 114.9,22.98 114.9,22.91 115,22.81 115.2,22.81 115.31,22.91 115.31,22.98 115.41,23.08 115.61,23.08 115.71,22.98 115.71,22.77 115.88,22.61 116.54,22.61 v4(116.75,22.82)
  IN4 w0.076: v1(121.66,24.22) 121.66,24.13 121.49,23.97 121.39,23.97 121.27,24.08 121.16,24.08 121.06,23.97 121.06,23.87 121.17,23.75 121.17,23.64 121.06,23.54 120.96,23.54 120.84,23.65 120.73,23.65 120.63,23.54 120.63,23.44 120.74,23.32 120.74,23.21 120.63,23.11 120.52,23.11 120.41,23.22 120.3,23.22 120.19,23.11 120.19,23 120.31,22.89 120.31,22.78 120.1,22.57 119.6,22.57 119.52,22.65 119.52,22.89 119.45,22.96 119.3,22.96 119.22,22.89 119.22,22.65 119.14,22.57 118.97,22.57 118.84,22.69 118.84,23.25 118.74,23.35 117.63,23.35 117.09,22.82 v4(116.75,22.82) 116.43,22.49 115.8,22.49 115.48,22.82 113.81,22.82 113.4,23.23 112.77,23.23 111.99,24 108.84,24 v1(108.67,24.18) ; v1(130.48,52.43) 130.73,52.19 130.73,46.76 129.61,45.64 129.12,45.64 128.87,45.39 128.87,43.75 128.08,42.96 ; v1(80.34,24.18) 80.5,24.02 82.66,24.02 82.71,24.08 83.92,24.08 85.51,22.48 86.81,22.48 87.38,23.05 88.57,23.05 v4(88.7,22.92) 88.92,23.14 89.44,23.14 89.66,22.92 91.8,22.92 92.4,23.51 93.9,23.51 95,24.62 95,24.79 94.88,24.91 94.71,24.91 94.02,24.22 v1(93.31,24.22)
  IN4 w0.145: v1(102.33,22.29) 104.23,24.19 104.23,26.42 104.46,26.65 104.46,27.26 104.17,27.54 104.17,28.87 103.99,29.06 103.99,33.12 105.49,34.63 105.49,37.89 107.15,39.55 116.6,39.55 118.44,41.39 126.51,41.39 127.1,41.97 128.08,42.96
  BOTTOM w0.076: v1(130.48,52.43) 130.81,52.76 UCPU1.AR35
DDR_A_MA14: length 123.2
  TOP w0.076: v2(100.41,22.35) 100.92,22.35 101.18,22.09 v1(101.18,22.07) 100.68,21.57 RD50.1 ; UD29.T7 95.79,24.65
  TOP w0.102: v1(111,23.61) 111.51,24.12 UD31.T7 ; v1(82.68,23.61) 82.68,24.15 UD28.T7 ; UD32.T7 124.14,24.65 124.13,24.65 v1(123.72,24.24) ; 95.79,24.65 v1(95.37,24.24)
  IN1 w0.076: v4(115.76,21.98) 115.49,21.71 114.08,21.71 113.54,21.17 104.01,21.17 103.65,21.53 101.71,21.53 v1(101.18,22.07) 100.93,22.32 99.98,22.32 99.85,22.19 99.85,21.62 99.98,21.49 100.44,21.49 100.56,21.36 100.56,21.21 100.44,21.08 90.21,21.08 89.45,21.84 88.64,21.84 v4(88.29,22.18)
  IN4 w0.076: v1(126.46,48) 125.73,48 125.43,47.7 124.26,47.7 123.79,47.23 119.54,47.23 118.82,47.95 118.33,47.95 117.59,48.68 116.16,48.68 115.75,48.27 ; v1(123.72,24.24) 123.53,24.24 122.5,23.2 121.33,23.2 120.1,21.98 v4(115.76,21.98) 115.53,21.74 111.89,21.74 111.52,22.11 111.52,22.58 111.42,22.68 110.37,22.68 110.24,22.81 110.24,22.99 110.37,23.12 111.36,23.12 111.46,23.22 111.46,23.51 111.36,23.61 v1(111,23.61) ; v1(82.68,23.61) 82.68,23.49 82.61,23.42 82.3,23.42 82.22,23.34 82.22,23.19 82.3,23.11 82.61,23.11 82.68,23.04 82.68,22.25 82.97,21.96 88.08,21.96 v4(88.29,22.18) 91.69,22.18 92.71,23.2 94.34,23.2 v1(95.37,24.24)
  IN4 w0.145: v1(101.18,22.07) 101.18,23.51 100.72,23.97 100.72,24.33 100.03,25.01 100.03,26.07 100.12,26.16 100.12,27.18 99.8,27.5 99.8,27.95 99.51,28.24 99.51,30.85 99.88,31.23 99.88,39.66 105.32,45.11 112.58,45.11 115.75,48.27
  BOTTOM w0.076: UCPU1.AV42 125.75,50.67 125.75,48.71 v1(126.46,48)
DDR_A_MA15: length 124.7
  TOP w0.076: UD29.M7 95.8,27.85 ; RD27.1 99.9,29.47 v1(99.9,29.01)
  TOP w0.102: 95.8,27.85 96.18,27.47 v1(96.2,27.47) ; UD32.M7 124.53,27.47 v1(124.55,27.47) ; UD28.M7 83.16,27.83 v1(82.64,27.83) ; UD31.M7 111.51,27.85 110.98,27.85 v1(110.96,27.83)
  IN1 w0.076: v4(89.25,29.41) 88.98,29.15 87.16,29.15 87.09,29.22 87.09,29.67 86.99,29.77 86.78,29.77 86.68,29.67 86.68,29.28 86.55,29.15 86.13,29.15 86.03,29.05 86.03,28.86 86.12,28.77 86.59,28.77 86.72,28.64 86.72,28.32 86.84,28.2 87.02,28.2 87.14,28.32 87.14,28.64 87.27,28.77 89.11,28.77 89.58,29.24 90.16,29.24 91.08,28.32 93.41,28.32 93.93,28.84 98.2,28.84 98.54,29.19 98.95,29.19 99.13,29.01 v1(99.9,29.01) 104.82,29.01 104.94,28.88 105.52,28.88 106.21,28.18 106.51,28.18 106.96,28.63 108.06,28.63 108.34,28.36 109.14,28.36 109.24,28.25 109.24,27.9 109.35,27.8 109.96,27.8 110.09,27.92 110.09,28.41 110.21,28.54 110.8,28.54 111.28,28.06 112.4,28.06 112.48,28.14 113.85,28.14 113.85,28.13 115.18,28.13 115.42,28.38 115.42,28.7 115.8,29.08 117.43,29.08 v4(117.76,29.41)
  IN4 w0.076: v1(96.2,27.47) 96.22,27.47 95.03,27.47 93.91,28.59 93.01,28.59 92.85,28.44 91.1,28.44 90.12,29.41 v4(89.25,29.41) 88.99,29.16 87.56,29.16 87.06,28.66 86.88,28.66 86.76,28.54 86.76,28.36 86.56,28.17 85.13,28.17 85.03,28.27 83.51,28.27 83.38,28.13 82.95,28.13 v1(82.64,27.83) ; v1(124.55,27.47) 123.92,28.09 123.27,28.09 123.17,28.2 119.47,28.2 118.61,29.06 118.3,29.06 117.95,29.41 v4(117.76,29.41) 117.54,29.41 117,28.87 116.17,28.87 115.37,28.07 111.94,28.07 111.45,27.57 111.21,27.57 v1(110.96,27.83) ; 115.83,47.88 116.46,48.51 117.52,48.51 118.25,47.78 118.75,47.78 119.98,46.55 123.42,46.55 124.3,47.43 124.63,47.43 124.88,47.17 125.56,47.17 125.68,47.3 125.68,47.58 125.81,47.71 126.09,47.71 v1(126.46,47.35)
  IN4 w0.145: 115.83,47.88 112.72,44.77 107.81,44.77 107.66,44.63 107.66,44.27 107.51,44.12 107.22,44.12 107.08,44.26 107.08,44.63 106.94,44.77 106.65,44.77 106.5,44.63 106.5,44.27 106.35,44.12 106.06,44.12 105.92,44.26 105.92,44.63 105.78,44.77 105.52,44.77 105.37,44.62 105.37,44.27 105.22,44.12 104.87,44.12 100.26,39.51 100.26,30.12 99.9,29.76 v1(99.9,29.01)
  BOTTOM w0.076: UCPU1.AU42 125.84,51.46 125.84,51.39 125.58,51.13 125.58,48.22 v1(126.46,47.35)
DDR_A_RAS#: length 134.7
  TOP w0.076: v1(106.4,33.06) 104.71,34.75 RD79.1
  TOP w0.102: v1(108.73,30.69) 108.31,30.27 UD31.J3 ; v1(80.41,30.69) 79.99,30.27 UD28.J3 ; UD29.J3 92.62,30.27 93.24,30.27 v1(93.68,29.83) ; v1(122.03,29.83) 121.59,30.27 120.97,30.27 UD32.J3
  IN1 w0.076: v4(88.38,32.21) 88.38,32.2 88.51,32.07 89.1,32.07 89.21,31.97 89.21,31.96 89.47,31.96 90.54,30.88 92.5,30.88 93.1,31.48 94.62,31.48 94.94,31.8 94.94,32.35 95.27,32.69 97.1,32.69 97.57,32.22 98.61,32.22 99.07,32.69 105.83,32.69 106.2,33.06 v1(106.4,33.06) 106.42,33.06 106.54,32.93 106.54,32.84 106.29,32.59 106.29,32.44 106.4,32.33 106.56,32.33 106.91,32.68 106.91,33.19 107.01,33.29 107.16,33.29 107.26,33.19 107.26,32.62 107.37,32.5 107.53,32.5 107.65,32.62 107.65,33.19 107.75,33.29 107.95,33.29 108.07,33.17 108.07,32.82 108.2,32.69 108.4,32.69 108.53,32.56 108.53,32.37 108.45,32.3 108.34,32.3 108.29,32.25 108.29,31.98 108.75,31.52 109.17,31.52 109.28,31.62 109.28,32.34 109.8,32.86 109.8,33.09 109.86,33.15 110.42,33.15 110.55,33.02 110.55,32.81 110.44,32.7 110.44,32.34 110.66,32.11 110.98,32.11 111.21,32.34 111.21,32.55 111.31,32.65 111.46,32.65 111.56,32.55 111.56,32.06 111.81,31.82 113.62,31.82 113.86,32.06 113.86,32.54 114.13,32.81 115.1,32.81 115.23,32.68 115.23,32.16 115.36,32.03 115.61,32.03 115.74,32.16 115.74,32.36 115.87,32.49 116.54,32.49 116.66,32.36 v4(116.66,32.21)
  IN4 w0.076: v1(108.73,30.69) 109.69,30.69 109.86,30.52 109.86,29.92 110.19,29.59 111.13,29.59 111.79,30.25 112.35,30.25 112.48,30.12 113.72,30.12 114.24,30.64 114.24,31.84 114.61,32.21 v4(116.66,32.21) 116.83,32.04 117.72,32.04 118.17,31.59 119.06,31.59 119.83,30.82 120.92,30.82 121.02,30.93 121.02,31.38 121.12,31.48 121.91,31.48 122.35,31.05 122.35,30.09 122.99,29.45 122.99,29.35 122.8,29.16 122.7,29.16 v1(122.03,29.83) ; v1(131.17,49.4) 131.45,49.4 131.79,49.06 131.79,45.73 131.35,45.29 131.18,45.29 130.73,44.84 130.73,44.02 129.76,43.05 ; v1(93.68,29.83) 94.16,29.35 94.27,29.35 94.46,29.55 94.46,29.66 94,30.12 94,31.07 93.59,31.48 92.8,31.48 92.7,31.38 92.7,30.93 92.6,30.82 91.48,30.82 90.67,31.64 90.1,31.64 89.53,32.21 89.28,32.21 89.21,32.13 89.21,31.94 89.13,31.87 88.98,31.87 88.9,31.94 88.9,32.13 88.83,32.21 v4(88.38,32.21) 86.39,32.21 85.78,31.6 85.78,30.5 85.4,30.12 84.16,30.12 84.03,30.25 83.47,30.25 82.79,29.57 81.89,29.57 80.77,30.69 v1(80.41,30.69)
  IN4 w0.145: v1(106.4,33.06) 106.02,32.68 105.44,32.68 105.34,32.77 105.34,33.22 106.61,34.5 106.61,37.48 107.66,38.52 117,38.52 118.09,39.61 118.53,39.61 118.67,39.46 118.67,38.66 118.82,38.51 119.1,38.51 119.25,38.66 119.25,39.46 119.39,39.61 119.68,39.61 119.83,39.46 119.83,38.66 119.97,38.51 120.26,38.51 120.41,38.66 120.41,39.46 120.55,39.61 120.84,39.61 120.99,39.46 120.99,38.66 121.13,38.51 121.42,38.51 121.57,38.66 121.57,39.46 121.71,39.61 126.32,39.61 129.76,43.05 129.76,43.05
  BOTTOM w0.076: UCPU1.AY34 131.42,49.65 v1(131.17,49.4)
DDR_A_WE#: length 128
  TOP w0.076: RD65.1 103.8,33.86 v1(105.43,32.23)
  TOP w0.102: UD32.L3 120.95,28.69 v1(121.37,29.1) ; v1(108.86,29.15) 108.36,28.65 108.36,28.65 UD31.L3 ; UD28.L3 80.04,28.65 v1(80.54,29.15) ; v1(93.02,29.1) 92.6,28.69 UD29.L3
  IN1 w0.076: v4(87.12,31.42) 87.12,31.94 87.38,32.21 87.85,32.21 88.04,32.02 88.04,31.97 88.26,31.75 89.38,31.75 90.45,30.68 92.59,30.68 93.19,31.28 94.71,31.28 95.28,31.85 98.6,31.85 99.05,32.29 105.37,32.29 v1(105.43,32.23) 105.63,32.03 105.78,32.03 106.01,32.26 106.16,32.26 106.29,32.13 106.29,31.49 106.47,31.32 106.6,31.32 106.67,31.39 106.67,31.82 106.75,31.89 107.01,31.89 107.14,31.76 107.14,31.42 107.27,31.29 107.51,31.29 107.57,31.36 107.57,31.88 107.64,31.94 108.02,31.94 108.34,31.63 108.34,31.4 108.42,31.31 109.36,31.31 109.48,31.43 109.48,31.94 109.59,32.04 109.7,32.04 109.82,32.16 109.82,32.33 109.72,32.43 109.72,32.56 109.97,32.82 110.16,32.82 110.23,32.75 110.23,32.11 110.46,31.89 110.86,31.89 110.98,31.78 111.14,31.78 111.26,31.89 111.44,31.89 111.55,31.79 111.55,31.55 111.44,31.45 111.23,31.45 111.13,31.35 111.13,31.07 111.27,30.93 111.64,30.93 111.75,31.04 112.25,31.04 112.32,30.97 112.83,30.97 112.98,31.13 113.23,31.13 113.39,30.97 113.8,30.97 113.91,31.07 113.91,31.68 114.01,31.79 114.16,31.79 114.27,31.68 114.27,31.6 114.38,31.48 114.54,31.48 114.65,31.6 114.65,32.09 114.52,32.22 114.21,32.22 114.1,32.33 114.1,32.49 114.21,32.6 114.91,32.6 115.03,32.49 115.03,31.52 115.13,31.42 v4(115.44,31.42)
  IN4 w0.076: v1(121.37,29.1) 121.56,29.1 121.66,29.21 121.66,29.4 121.56,29.5 120.3,29.5 120.2,29.6 120.2,30.32 120.1,30.42 119.45,30.42 118.68,31.19 116.33,31.19 116.1,30.95 115.75,30.95 115.44,31.27 v4(115.44,31.42) 115.19,31.42 114.93,31.15 114.93,30.62 114.22,29.91 113.99,29.91 113.26,29.19 109.4,29.19 109.21,29 109.01,29 v1(108.86,29.15) ; v1(93.02,29.1) 93.37,29.1 93.46,29.2 93.46,29.38 93.34,29.5 91.98,29.5 91.85,29.63 91.85,30.34 91.77,30.42 91.3,30.42 90.49,31.23 89.98,31.23 89.7,31.51 89.22,31.51 89.13,31.42 88.24,31.42 87.79,30.96 87.46,30.96 87.12,31.3 v4(87.12,31.42) 86.94,31.6 86.53,31.6 86.19,31.26 86.19,30.33 85.59,29.73 84.62,29.73 84.17,29.28 83.08,29.28 82.95,29.15 v1(80.54,29.15) ; v1(131.17,50) 131.96,49.2 131.96,45.58 131.45,45.06 131.29,45.06 130.9,44.67 130.9,43.66 130.2,42.96
  IN4 w0.145: 130.2,42.96 126.47,39.23 122.02,39.23 121.9,39.12 121.9,38.52 121.27,37.88 120.87,37.88 120.76,37.99 120.76,38.1 120.68,38.18 120.26,38.18 120.18,38.1 120.18,37.97 120.09,37.88 119.7,37.88 119.6,37.98 119.6,38.1 119.52,38.18 119.11,38.18 119.02,38.1 119.02,38.01 118.9,37.88 118.48,37.88 118.34,38.03 118.34,39.02 118.24,39.11 118.07,39.11 117.58,38.63 117.58,38.48 117.76,38.31 117.76,38.03 117.68,37.95 117.31,37.95 117.08,38.18 107.8,38.18 107.49,37.87 107.49,37.61 107.63,37.48 107.63,37.48 108.13,37.48 108.27,37.34 108.27,37.05 108.2,36.97 107.47,36.97 107.32,36.82 107.32,36.58 107.49,36.4 107.49,35.1 107.35,34.96 107.03,34.96 106.95,34.87 106.95,34.46 107.13,34.28 108.4,34.28 108.48,34.2 108.48,34.1 107.7,33.33 107.5,33.33 107.36,33.47 107.12,33.47 106.94,33.28 106.94,33.07 107,33.01 107,32.8 106.43,32.23 v1(105.43,32.23)
  BOTTOM w0.076: UCPU1.AW34 131.48,50.3 131.18,50 v1(131.17,50)
DDR_B_BA0: length 140.9
  TOP w0.076: RD70.1 157.9,27.57 v1(158.14,27.57) ; UD3.M2 145.39,27.8 v1(145.04,27.45)
  TOP w0.102: v1(133.19,27.44) 132.78,27.85 UD7.M2 ; UD4.M2 173.73,27.85 173.32,27.45 173.32,27.44 v1(173.33,27.44) ; UD1.M2 161.1,27.85 v1(161.51,27.44)
  IN1 w0.076: v1(145.04,27.45) 145.15,27.33 145.15,27.23 145.03,27.1 144.53,27.1 144.47,27.17 144.47,27.31 144.67,27.51 144.67,27.66 144.54,27.79 144.33,27.79 144.28,27.84 144.28,28.04 144.23,28.09 143.92,28.09 143.86,28.03 143.86,27.96 143.78,27.89 143.63,27.89 143.56,27.96 143.56,28.03 143.49,28.09 143.23,28.09 143.15,28.01 143.15,27.51 143.08,27.44 142.93,27.44 142.85,27.51 142.85,27.84 142.77,27.92 142.62,27.92 142.54,27.84 142.54,27.51 142.47,27.44 142.32,27.44 142.24,27.51 142.24,28.02 142.16,28.09 142.01,28.09 141.93,28.02 141.93,27.73 141.86,27.65 v4(140.94,27.65) 140.7,27.65 140.06,27.01 139.26,27.01 138.98,26.74 136.75,26.74 136.31,27.17 135.96,27.17 135.69,27.44 v1(133.19,27.44) ; v1(130.48,55.04) 130.77,55.04 130.91,54.9 130.91,52.25 131.19,51.97 132.05,51.97 132.15,51.86 132.7,51.86 133.35,51.21 141.08,51.21 141.44,50.85 ; v1(161.51,27.44) 161.82,27.13 164.12,27.13 164.21,27.04 164.92,27.04 165.27,26.68 167.48,26.68 167.72,26.93 168.26,26.93 168.39,26.8 168.99,26.8 169.08,26.89 169.08,27.28 v4(169.61,27.8) 169.61,28.11 169.68,28.18 170.41,28.18 170.5,28.1 170.5,27.88 170.59,27.78 170.78,27.78 170.86,27.7 170.86,27.51 170.95,27.42 171.06,27.42 171.22,27.58 171.22,27.73 171.15,27.8 171.15,27.93 171.3,28.08 171.42,28.08 171.58,27.92 171.58,27.52 171.44,27.38 171.44,27.27 171.68,27.03 171.88,27.03 171.92,27.07 171.92,27.26 171.99,27.33 172.11,27.33 172.24,27.2 172.24,27.07 172.33,26.98 172.55,26.98 172.77,27.2 173.02,27.2 173.08,27.14 173.08,27.04 173.16,26.96 173.68,26.96 173.79,27.06 173.79,27.25 173.71,27.32 173.71,27.62 173.62,27.71 173.41,27.71 173.33,27.63 v1(173.33,27.44)
  IN1 w0.145: v1(158.14,27.57) 158.34,27.38 158.34,24.77 158.21,24.64 156.77,24.64 156.65,24.51 156.65,24.18 156.77,24.06 159.28,24.06 159.4,24.18 159.4,24.51 159.28,24.64 159.03,24.64 158.91,24.77 158.91,27.52 158.97,27.59 158.97,28.33 159.11,28.47 159.6,28.47 159.74,28.62 159.74,28.91 159.6,29.05 159.11,29.05 158.97,29.2 158.97,29.67 158.81,29.83 158.81,30.57 158.12,31.26 158.12,32.04 159.01,32.93 159.01,36.54 159.57,37.11 159.57,41.05 156.62,44.01 153.27,44.01 151.52,45.76 149.63,45.76 148.89,46.51 147.34,46.51 145.95,47.89 144.4,47.89 141.44,50.85
  IN4 w0.076: v4(169.61,27.8) 169.61,28.04 169.75,28.18 170.72,28.18 170.82,28.28 170.82,28.39 170.72,28.49 169.48,28.49 169.2,28.21 169.2,27.41 169.1,27.32 169.1,26.9 168.99,26.79 167.86,26.79 167.52,26.44 164.3,26.44 164.22,26.35 163.85,26.35 163.75,26.25 163.75,25.94 163.64,25.84 163.16,25.84 162.78,26.22 162.78,26.88 162.68,26.98 162.18,26.98 161.93,26.74 161.93,26.51 161.85,26.43 161.56,26.43 161.46,26.53 161.46,26.55 161.36,26.65 161.1,26.65 161,26.55 161,26.17 160.84,26.01 160.14,26.01 160.06,25.93 159.24,25.93 159.12,26.06 159.12,26.47 158.14,27.44 v1(158.14,27.57) 158.05,27.57 157.81,27.81 152.86,27.81 152.59,27.54 151.98,27.54 151.51,27.07 149.51,27.07 149.31,27.26 148.44,27.26 148.23,27.05 148.12,27.05 147.98,27.19 147.88,27.19 147.77,27.08 147.77,26.97 147.9,26.84 147.9,26.73 147.45,26.27 147.1,26.27 146.52,26.86 144.54,26.86 144.29,27.11 143.45,27.11 142.91,27.65 v4(140.94,27.65)
  BOTTOM w0.076: UCPU1.AL35 130.81,55.36 v1(130.48,55.04)
DDR_B_BA1: length 134.7
  TOP w0.076: RD80.1 158.17,29.08 v1(158.17,29)
  TOP w0.102: UD1.N8 165.74,27.22 165.74,27.24 v1(165.51,27.47) ; UD4.N8 178.69,26.91 178.71,26.91 v1(178.94,26.67) ; UD3.N8 150.19,27.12 v1(150.59,27.51) ; v1(137.18,27.47) 137.42,27.24 137.42,27.22 UD7.N8
  IN1 w0.076: 129.73,51.82 129.37,51.82 129.07,52.11 129.07,54.57 129.19,54.69 129.38,54.69 v1(129.53,54.54) ; v1(150.59,27.51) 150.19,27.12 149.09,27.12 148.94,27.26 148.04,27.26 146.99,28.31 144.67,28.31 144.2,28.78 v4(143.6,28.78) 143.27,28.78 142.87,28.37 142.53,28.37 142.35,28.55 142.19,28.55 142.11,28.63 142.11,28.69 142.03,28.77 141.88,28.77 141.8,28.69 141.8,28.63 141.73,28.55 141.58,28.55 141.5,28.63 141.5,28.69 141.42,28.77 141.27,28.77 141.19,28.69 141.19,28.63 141.12,28.55 140.35,28.55 140.31,28.51 140.03,28.51 139.96,28.44 139.58,28.44 138.98,27.84 137.33,27.84 137.18,27.7 v1(137.18,27.47) ; v1(178.94,26.67) 178.52,27.09 177.58,27.09 177.41,27.26 177.12,27.26 176.16,28.23 172.84,28.23 172.35,28.72 v4(172.05,28.72) 171.86,28.91 169.3,28.91 168.32,27.93 165.61,27.93 165.51,27.83 v1(165.51,27.47)
  IN1 w0.086: 131.63,48.58 131.45,48.4 130.41,48.4 130.26,48.55 130.26,51.28 129.73,51.82
  IN1 w0.145: v1(158.17,29) 158.17,29.23 157.55,29.86 157.55,30.51 157.6,30.56 157.6,31.94 157.36,32.17 157.36,33.7 157.51,33.84 157.76,33.84 157.92,34.01 157.92,34.36 157.78,34.51 157.54,34.51 157.4,34.65 157.4,34.94 157.54,35.08 157.78,35.08 157.92,35.23 157.92,36.5 158.23,36.81 158.23,37.15 157.92,37.45 157.92,37.77 153.25,42.44 153.07,42.44 153.04,42.42 152.62,42.42 152.51,42.53 152.51,42.71 152.68,42.88 152.68,43.01 152.07,43.63 151.73,43.63 151.58,43.77 151.58,44.31 151.29,44.6 151.15,44.6 151,44.46 151,43.77 150.86,43.63 150.57,43.63 150.43,43.77 150.43,44.46 150.28,44.6 149.99,44.6 149.85,44.46 149.85,43.77 149.7,43.63 149.41,43.63 149.27,43.77 149.27,44.46 149.12,44.6 148.83,44.6 148.69,44.46 148.69,43.77 148.54,43.63 148.25,43.63 148.11,43.77 148.11,44.46 147.96,44.6 147.67,44.6 147.53,44.46 147.53,43.77 147.39,43.63 147.07,43.63 146.99,43.71 146.99,43.9 146.87,44.02 146.73,44.02 146.23,43.53 146.03,43.53 145.82,43.73 145.82,43.93 146.53,44.64 146.53,44.79 146.06,45.25 145.9,45.25 144.87,44.22 144.67,44.22 144.46,44.43 144.46,44.63 145.5,45.66 145.5,45.82 145.25,46.06 145.08,46.06 144.05,45.04 143.85,45.04 143.65,45.25 143.65,45.45 144.66,46.47 144.66,46.65 144.44,46.88 144.25,46.88 143.68,46.31 143.54,46.31 143.4,46.44 143.4,46.85 143.82,47.27 143.82,47.5 143.12,48.2 141.3,48.2 140.75,48.75 139.82,48.75 139.08,49.48 134.46,49.48 133.94,50 132.01,50 131.63,49.62 131.63,48.58
  IN4 w0.076: v4(172.05,28.72) 171.99,28.65 169.07,28.65 168.35,27.93 165.34,27.93 164.79,27.39 164.45,27.39 164.24,27.59 162.06,27.59 161.8,27.85 160.56,27.85 159.79,28.62 159.08,28.62 158.71,29 v1(158.17,29) 158.06,28.88 154.84,28.88 154.73,29 152.04,29 151.59,28.55 148.26,28.55 147.83,28.13 144.59,28.13 143.94,28.78 v4(143.6,28.78)
  BOTTOM w0.076: UCPU1.AM36 129.93,54.8 129.8,54.8 v1(129.53,54.54)
DDR_B_BA2: length 135
  TOP w0.076: RD68.1 152.35,31.44 v1(152.35,28.56) ; UD1.M3 161.9,27.85
  TOP w0.102: 161.9,27.85 162.34,27.85 v1(162.46,27.97) ; UD3.M3 146.3,27.85 v1(146.64,27.52) ; v1(174.86,27.44) 174.54,27.76 UD4.M3 ; v1(134.14,28.04) 133.95,27.85 133.95,27.85 UD7.M3
  IN1 w0.076: v1(146.64,27.52) 146,28.16 144.61,28.16 144.37,28.4 143.11,28.4 142.93,28.22 142.47,28.22 142.29,28.4 140.41,28.4 v4(140.17,28.16) 139.52,28.16 139.2,27.85 139.2,27.39 138.86,27.04 136.87,27.04 136.44,27.47 136.09,27.47 135.81,27.75 135.49,27.75 135.2,28.04 v1(134.14,28.04) ; v1(174.86,27.44) 174.25,28.05 172.72,28.05 172.46,28.32 171.81,28.32 171.62,28.51 169.24,28.51 168.79,28.06 v4(168.79,27.84) 168.66,27.7 167.86,27.7 167.25,27.09 165.37,27.09 165.01,27.45 164.38,27.45 164.09,27.73 163.91,27.73 163.66,27.97 v1(162.46,27.97)
  IN1 w0.145: v1(121.73,51.27) 122.29,50.72 122.29,48.72 122.08,48.51 122.08,42.14 126.98,37.23 128.27,37.23 128.42,37.09 128.42,35.85 128.56,35.7 128.85,35.7 129,35.85 129,37.09 129.14,37.23 129.43,37.23 129.58,37.09 129.58,35.68 129.7,35.55 130.57,35.55 130.7,35.68 130.7,36.08 130.57,36.21 130.28,36.21 130.16,36.34 130.16,37.09 130.3,37.23 130.61,37.23 130.76,37.08 130.76,36.81 130.87,36.7 131.24,36.7 131.39,36.84 131.39,37.1 131.51,37.23 131.84,37.23 131.96,37.1 131.96,36.84 132.11,36.7 132.75,36.7 132.89,36.84 132.89,37.1 133.02,37.23 133.35,37.23 133.47,37.1 133.47,36.84 133.62,36.7 134.9,36.7 135.05,36.84 135.05,37.1 135.17,37.23 135.5,37.23 135.63,37.1 135.63,36.84 135.77,36.7 136.82,36.7 136.97,36.84 136.97,37.1 137.09,37.23 137.42,37.23 137.55,37.1 137.55,36.53 137.67,36.4 138.37,36.4 138.5,36.53 138.5,37.1 138.62,37.23 138.95,37.23 139.08,37.1 139.08,36.84 139.22,36.7 139.51,36.7 139.66,36.84 139.66,37.1 139.78,37.23 140.11,37.23 140.23,37.1 140.23,36.84 140.38,36.7 140.67,36.7 140.81,36.84 140.81,37.1 140.94,37.23 141.27,37.23 141.39,37.1 141.39,36.84 141.54,36.7 141.83,36.7 141.97,36.84 141.97,37.1 142.1,37.23 142.42,37.23 142.55,37.1 142.55,36.84 142.7,36.7 142.98,36.7 143.13,36.84 143.13,37.1 143.26,37.23 143.58,37.23 143.71,37.1 143.71,36.84 143.85,36.7 146,36.7 148.44,34.26 151.67,34.26 152.6,33.33 152.6,28.81 v1(152.35,28.56)
  IN4 w0.076: v4(140.17,28.16) 139.02,28.16 138.92,28.26 138.92,28.46 139.02,28.56 140.47,28.56 140.57,28.67 140.57,29.66 140.66,29.74 140.85,29.74 140.95,29.64 140.95,28.53 141.08,28.4 144.03,28.4 144.51,27.92 147.92,27.92 148.35,28.35 151.68,28.35 151.89,28.56 v1(152.35,28.56) 158.68,28.56 158.95,28.29 159.65,28.29 160.29,27.65 160.29,27.27 160.5,27.06 161.68,27.06 162.01,27.39 164.15,27.39 164.47,27.08 167.24,27.08 167.86,27.7 168.66,27.7 v4(168.79,27.84)
  BOTTOM w0.076: v1(121.73,51.27) 121.86,51.27 UCPU1.AU49
DDR_B_CAS#: length 143.3
  TOP w0.076: v1(158.99,31.74) 159.39,32.14 159.39,33.2 RD62.1
  TOP w0.102: UD1.K3 161.9,29.5 v1(162.32,29.91) ; UD4.K3 174.54,29.45 174.82,29.45 v1(175.01,29.64) ; v1(146.55,29.89) 146.19,29.53 146.19,29.45 UD3.K3 ; v1(133.98,29.83) 133.6,29.45 133.6,29.45 UD7.K3
  IN1 w0.076: v1(146.55,29.89) 146.55,30.53 146.46,30.62 144.13,30.62 142.96,31.79 140.63,31.79 v4(140.28,31.44) 139.41,30.58 139.41,30.31 139.05,29.95 137.84,29.95 137.37,29.49 136.6,29.49 136.43,29.31 134.5,29.31 v1(133.98,29.83) ; v1(131.44,54.45) 131.44,54.31 131.79,53.95 131.79,52.94 131.93,52.8 132.77,52.8 132.89,52.68 132.89,52.16 133.49,51.56 141.53,51.56 141.94,51.14 ; v1(175.01,29.64) 174.02,30.62 173.06,30.62 172.88,30.8 172.26,30.8 171.24,31.83 168.54,31.83 v4(168.21,31.49) 168.21,30.78 167.39,29.96 166.19,29.96 165.72,29.49 164.91,29.49 164.79,29.37 164.25,29.37 163.71,29.91 v1(162.32,29.91)
  IN1 w0.145: 141.94,51.14 142.88,50.2 144.24,50.2 144.85,49.6 144.85,48.59 145.08,48.36 146.14,48.36 146.84,47.66 147.31,47.66 147.4,47.57 147.4,47.1 147.53,46.97 147.81,46.97 147.95,47.11 147.95,47.51 148.1,47.65 148.34,47.65 148.48,47.51 148.48,47.11 148.63,46.97 151.36,46.97 153.06,45.27 156.3,45.27 160.83,40.75 161.03,40.75 161.52,41.23 161.72,41.23 161.93,41.03 161.93,40.82 161.07,39.97 161.07,39.75 161.3,39.52 161.48,39.52 162.4,40.44 162.6,40.44 162.83,40.21 162.83,39.47 162.7,39.35 162.27,39.35 162.16,39.23 162.16,39.03 162.01,38.88 161.76,38.88 161.61,38.74 161.61,38.45 161.76,38.3 162.16,38.3 162.45,38.6 162.65,38.6 162.83,38.42 162.83,38.01 162.63,37.81 161.61,37.81 161.41,37.61 161.41,36.78 161.61,36.58 161.83,36.58 161.93,36.68 161.93,37.19 162.09,37.35 162.65,37.35 162.83,37.18 162.83,34.42 162.94,34.3 162.94,33.96 162.64,33.66 162.12,33.66 161.99,33.79 161.99,35.94 161.87,36.07 161.62,36.07 161.5,35.94 161.5,33.69 160.99,33.19 160.43,33.19 158.99,31.75 v1(158.99,31.74)
  IN4 w0.076: v4(168.21,31.49) 168.01,31.49 167.76,31.25 167.6,31.25 167.49,31.36 167.49,31.57 167.81,31.89 167.81,32.03 167.71,32.13 167.61,32.13 167.31,31.84 166.84,31.84 166.72,31.71 166.72,31.14 166.59,31.01 166.09,31.01 165.92,31.19 165.92,31.71 165.79,31.84 165.27,31.84 165.14,31.71 165.14,31.1 165.02,30.98 164.85,30.98 164.72,31.1 164.72,31.78 164.6,31.91 164.05,31.91 163.83,32.13 163.83,32.44 163.73,32.55 163.35,32.55 163.25,32.44 163.25,31.9 163.35,31.8 163.69,31.8 163.82,31.68 163.82,31.48 163.69,31.36 163.3,31.36 163.24,31.29 163.24,30.58 163.16,30.5 162.95,30.5 162.87,30.58 162.87,31.14 162.67,31.34 161.92,31.34 161.83,31.24 161.83,31.17 161.72,31.06 161.24,31.06 161.14,31.16 161.14,31.56 161.04,31.66 160.9,31.66 160.8,31.56 160.8,31.16 160.7,31.06 160.53,31.06 160.43,31.16 160.43,31.58 160.13,31.89 160.02,31.89 159.96,31.83 159.96,31.6 159.88,31.52 159.71,31.52 159.63,31.59 159.63,31.81 159.55,31.89 159.13,31.89 v1(158.99,31.74) 158.77,31.95 153.85,31.95 153.47,31.58 151.5,31.58 151,31.07 147.25,31.07 146.78,30.6 143.56,30.6 142.74,31.42 141.52,31.42 141.15,31.05 140.38,31.05 140.28,31.15 v4(140.28,31.44)
  BOTTOM w0.076: UCPU1.AM33 131.7,54.71 v1(131.44,54.45)
DDR_B_CKE0: length 136.4
  TOP w0.076: RD58.1 153.64,34.69 v1(151.54,32.59)
  TOP w0.102: UD1.K9 166.7,29.45 167.13,29.88 v1(167.13,30.53) ; v1(138.81,30.53) 138.81,30.12 138.38,29.69 138.38,29.45 UD7.K9 ; v1(179.71,29.85) 179.34,29.48 UD4.K9 ; UD3.K9 150.97,29.45 150.96,29.45 v1(150.59,29.83)
  IN1 w0.076: v1(179.71,29.85) 179.71,29.59 179.59,29.46 177.7,29.46 177.62,29.38 176.94,29.38 176.15,30.17 176.15,31.17 175.68,31.63 174.65,31.63 174.53,31.51 174.53,31.19 174.36,31.03 173.23,31.03 172.87,31.38 v4(172.56,31.38) 172.18,31.76 172.18,32.53 171.9,32.8 166.99,32.8 166.68,32.49 166.68,30.98 v1(167.13,30.53) ; v1(150.59,29.83) 150.05,29.29 148.43,29.29 147.8,29.92 147.8,30.79 147.34,31.26 146.83,31.26 146.65,31.07 144.51,31.07 143.32,32.26 143.32,32.32 v4(143.04,32.6) 142.94,32.7 139.85,32.7 139.67,32.53 139.67,31.57 139.58,31.47 139.21,31.47 139.11,31.57 139.11,31.89 139.37,32.15 139.37,32.53 139.29,32.6 138.47,32.6 138.37,32.5 138.37,30.69 138.52,30.53 v1(138.81,30.53)
  IN1 w0.145: v1(120.81,48.06) 120.81,41.67 124.88,37.59 124.88,35.37 125.18,35.08 126.59,35.08 128.22,33.44 136.01,33.44 136.8,34.23 137.69,34.23 138.51,35.05 143.1,35.05 143.55,34.6 144.19,34.6 144.56,34.24 146.91,34.24 148.43,32.72 151.41,32.72 v1(151.54,32.59)
  IN4 w0.076: v4(172.56,31.38) 172.17,31.38 170.57,32.98 168.82,32.98 168.53,33.26 165.03,33.26 164.92,33.16 161.39,33.16 161.09,32.86 160.03,32.86 159.61,33.29 159.02,33.29 158.89,33.42 158.25,33.42 158.12,33.29 152.99,33.29 152.29,32.59 v1(151.54,32.59) 151.24,32.89 148.79,32.89 148.58,32.68 148.42,32.68 148.29,32.81 148.11,32.81 148.05,32.75 148.05,32.39 148.35,32.09 148.35,31.98 148.17,31.8 147.99,31.8 147.86,31.93 147.86,32.06 147.76,32.16 147.59,32.16 147.49,32.06 147.49,31.83 147.39,31.73 147.04,31.73 146.95,31.81 146.95,31.98 147.51,32.54 147.51,32.79 147.41,32.89 147.21,32.89 147.11,32.79 147.11,32.7 147,32.6 146.8,32.6 146.7,32.7 146.7,32.79 146.6,32.89 146.37,32.89 146.27,32.79 146.27,31.95 146.15,31.83 144.74,31.83 144.64,31.73 144.64,31.33 144.54,31.23 143.8,31.23 143.7,31.33 143.7,31.46 143.8,31.56 144.03,31.56 144.13,31.66 144.13,31.77 143.93,31.98 143.17,31.98 142.95,32.2 142.83,32.2 142.56,32.48 142.56,32.7 142.47,32.78 142.26,32.78 142.16,32.68 142.16,32.56 142.06,32.46 141.86,32.46 141.75,32.56 141.75,32.68 141.65,32.78 140.5,32.78 140.38,32.91 140.38,33.11 140.5,33.24 142.29,33.24 142.93,32.6 v4(143.04,32.6)
  BOTTOM w0.089: UCPU1.AY49 122.27,49.51 122.27,48.85 121.48,48.06 v1(120.81,48.06)
DDR_B_CKE1: length 135.7
  TOP w0.076: v1(151.54,33.29) 153.83,35.57 RD89.1
  TOP w0.102: v1(166.33,30.59) 166.67,30.25 166.67,30.25 UD1.J9 ; UD4.J9 179.34,30.21 179.34,30.2 v1(178.99,29.85) ; v1(150.59,30.65) 150.59,30.65 UD3.J9 ; v1(138.01,30.59) 138.35,30.25 138.35,30.25 UD7.J9
  IN1 w0.076: v1(138.01,30.59) 137.6,31 137.6,32.74 137.82,32.97 139.41,32.97 139.48,33.03 140.29,33.03 140.37,33.11 140.37,33.24 140.44,33.31 140.6,33.31 140.67,33.24 140.67,33.11 140.75,33.03 140.9,33.03 140.98,33.11 140.98,33.24 141.05,33.31 141.2,33.31 141.28,33.24 141.28,33.11 141.36,33.03 141.51,33.03 141.59,33.11 141.59,33.24 141.66,33.31 141.81,33.31 141.89,33.24 141.89,33.11 141.97,33.03 142.12,33.03 142.2,33.11 142.2,33.24 142.47,33.52 143.22,33.52 v4(143.7,33.03) 144.02,33.03 144.63,32.43 144.63,32.01 144.78,31.85 147.41,31.85 148.01,31.26 148.01,30.03 148.3,29.73 148.3,29.73 148.59,29.45 149.1,29.45 149.45,29.8 149.45,29.99 149.7,30.25 150.18,30.25 v1(150.59,30.65) ; v1(166.33,30.59) 165.92,31 165.92,32.81 166.21,33.1 167.88,33.1 168.07,33.29 168.07,34.18 168.19,34.3 168.36,34.3 168.47,34.18 168.47,33.44 168.6,33.31 v4(171.29,33.31) 171.63,32.97 172.43,32.97 172.97,32.43 172.97,32.11 173.25,31.83 174.3,31.83 174.3,31.84 175.77,31.84 176.35,31.26 176.35,30.28 177.06,29.57 177.38,29.57 177.6,29.8 177.6,29.8 177.66,29.85 v1(178.99,29.85)
  IN1 w0.145: v1(120.8,48.62) 121.19,48.23 121.19,41.75 125.77,37.17 125.77,35.93 126.04,35.66 126.48,35.66 127.88,34.25 132.74,34.25 132.88,34.11 132.88,33.91 133.01,33.78 133.33,33.78 133.46,33.91 133.46,34.11 133.61,34.25 134.91,34.25 135.1,34.44 135.1,35.17 135.23,35.29 135.55,35.29 135.68,35.17 135.68,34.24 135.81,34.11 136.35,34.11 136.48,34.24 136.48,34.91 136.61,35.03 137.67,35.03 138.02,35.39 139.26,35.39 139.48,35.6 143.42,35.6 143.96,35.07 146.55,35.07 148.57,33.05 151.3,33.05 v1(151.54,33.29)
  IN4 w0.076: v4(143.7,33.03) 143.7,33.09 143.22,33.57 143.22,33.87 143.35,34 143.54,34 143.67,33.87 143.67,33.73 143.79,33.61 144.29,33.61 144.43,33.74 144.71,33.74 144.79,33.66 144.79,33.32 144.67,33.2 144.26,33.2 144.14,33.07 144.14,32.75 144.26,32.62 145.29,32.62 145.41,32.74 145.41,32.97 145.47,33.04 146.21,33.04 146.27,33.09 146.77,33.09 146.89,33.22 146.89,34.42 147.02,34.55 147.18,34.55 147.29,34.44 147.29,33.19 147.39,33.09 147.59,33.09 147.7,33.19 147.7,34.43 147.81,34.55 147.98,34.55 148.1,34.43 148.1,33.19 148.2,33.09 148.41,33.09 148.51,33.19 148.51,34.43 148.63,34.55 148.8,34.55 148.91,34.43 148.91,33.19 149.02,33.09 151.35,33.09 v1(151.54,33.29) 151.92,33.67 159.64,33.67 160.24,33.07 161.01,33.07 161.3,33.36 164.77,33.36 164.82,33.41 164.82,33.42 164.88,33.48 169.57,33.48 169.74,33.31 v4(171.29,33.31)
  BOTTOM w0.076: v1(120.8,48.62) 121.2,49.02 121.2,49.34 120.99,49.54 120.99,51.39 UCPU1.AU50
DDR_B_CS0#: length 129.3
  TOP w0.076: RD60.1 158.73,30.3 v1(159.43,30.3)
  TOP w0.102: v1(174.16,29.12) 173.74,28.7 173.74,28.65 UD4.L2 ; UD3.L2 145.39,28.7 v1(145.81,29.12) ; UD1.L2 161.1,28.62 v1(161.48,28.24) ; UD7.L2 132.78,28.65 v1(133.15,28.28)
  IN1 w0.076: v1(132.39,54.97) 133.49,53.86 133.49,52.3 133.71,52.08 142.53,52.08 142.84,51.77 ; v1(174.16,29.12) 173.87,29.12 173.52,28.76 173.17,28.76 172.42,29.52 172.08,29.52 171.42,30.18 169.05,30.18 v4(168.11,29.24) 168.11,28.94 167.72,28.54 163.25,28.54 163.07,28.36 161.6,28.36 v1(161.48,28.24) ; v1(145.81,29.12) 145.81,28.87 145.71,28.77 144.86,28.77 144.58,29.04 144.3,29.33 144.1,29.33 143.67,29.75 142.43,29.75 142.22,29.96 141.2,29.96 140.96,29.72 140.96,29.38 140.83,29.25 140.49,29.25 140.29,29.45 v4(140.05,29.45) 139.54,29.45 139.34,29.25 139.34,28.84 139.17,28.67 137,28.67 136.82,28.5 135.24,28.5 135.17,28.42 133.29,28.42 v1(133.15,28.28)
  IN1 w0.086: 142.84,51.77 143.13,51.77
  IN1 w0.145: v1(159.43,30.3) 160.19,30.3 160.33,30.44 160.33,30.9 160.51,31.08 162.96,31.08 163.76,31.88 163.76,36.6 164.05,36.9 164.05,40.98 162.55,42.48 160.82,42.48 156.8,46.5 153.9,46.5 151.94,48.46 147.06,48.46 143.75,51.77 143.13,51.77
  IN4 w0.076: v4(168.11,29.24) 168.91,30.03 169.07,30.03 169.23,29.87 169.23,29.71 168.09,28.57 167.31,28.57 167.09,28.79 167.09,29.69 166.99,29.79 166.86,29.79 166.78,29.71 166.78,28.67 166.72,28.6 166.53,28.6 166.48,28.66 166.48,29.63 166.38,29.73 166.25,29.73 166.12,29.61 166.12,28.73 165.99,28.6 165.82,28.6 165.69,28.73 165.69,29.15 165.56,29.28 165.32,29.28 165.2,29.15 163.92,29.15 163.53,28.76 163.4,28.76 163.28,28.88 163.28,29.18 163.51,29.41 163.51,29.7 163.41,29.8 163.03,29.8 162.9,29.67 162.9,28.89 162.78,28.76 162.17,28.76 162.07,28.86 162.07,29.19 161.97,29.29 160.37,29.29 160.15,29.5 159.66,29.5 159.55,29.61 159.55,30.18 v1(159.43,30.3) 159.21,30.52 158.3,30.52 158.14,30.68 154.38,30.68 153.96,30.27 152.1,30.27 150.99,29.16 147.22,29.16 146.79,28.74 144.85,28.74 143.6,29.99 143.3,29.99 143.13,30.16 140.76,30.16 v4(140.05,29.45)
  BOTTOM w0.076: v1(132.39,54.97) 132.52,54.97 UCPU1.AM32
DDR_B_CS1#: length 132.1
  TOP w0.076: v1(159.61,30.88) 159.05,30.88 RD90.1
  TOP w0.102: UD4.L1 172.94,28.72 v1(173.35,29.13) ; UD1.L1 160.3,28.65 v1(160.71,28.25) ; UD7.L1 131.98,28.65 132.06,28.65 v1(132.39,28.98) ; UD3.L1 144.59,28.72 v1(145,29.13)
  IN1 w0.076: v1(160.71,28.25) 161.15,28.69 161.81,28.69 161.94,28.56 162.98,28.56 163.17,28.74 166.13,28.74 166.34,28.95 v4(167.59,28.95) 167.77,29.14 167.77,29.41 168.86,30.51 171.37,30.51 172.16,29.72 172.5,29.72 173.09,29.13 v1(173.35,29.13) ; v1(132.37,55.69) 131.97,55.29 131.97,54.77 133.32,53.42 133.32,52.22 133.64,51.9 141.89,51.9 142.41,51.39 142.63,51.39 ; v1(145,29.13) 144.71,29.13 144.37,29.48 144.16,29.48 143.74,29.9 142.49,29.9 142.28,30.11 141.14,30.11 140.76,29.73 140.76,29.54 140.68,29.47 140.53,29.47 140.45,29.54 140.45,29.73 140.38,29.81 139.6,29.81 138.99,29.2 v4(138.99,29.16) 138.71,28.88 136.92,28.88 136.74,28.7 135.09,28.7 135.09,28.69 135.04,28.64 132.47,28.64 132.39,28.72 v1(132.39,28.98)
  IN1 w0.145: 142.63,51.39 143.79,51.39 146.95,48.23 151.7,48.23 153.76,46.16 156.66,46.16 160.68,42.15 162.41,42.15 163.71,40.85 163.71,37.06 163.47,36.81 163.47,33.01 162.79,32.34 162.15,32.34 161.7,31.89 161.36,31.89 161.1,31.64 160.37,31.64 v1(159.61,30.88)
  IN4 w0.076: v4(167.59,28.95) 167.77,29.14 167.77,29.63 167.89,29.74 168.33,29.74 168.83,30.24 169.16,30.24 169.33,30.06 171.28,30.06 171.8,30.58 171.8,31.33 171.67,31.46 171.49,31.46 171.37,31.33 171.37,30.8 171.05,30.48 169.45,30.48 169.3,30.63 168.22,30.63 168.1,30.51 168.1,30.21 167.8,29.91 167.5,29.91 167.26,30.15 166.87,30.15 166.7,29.99 166.01,29.99 165.94,29.92 165.94,29.71 165.71,29.48 165.24,29.48 165.11,29.35 164,29.35 163.72,29.64 163.72,29.99 163.62,30.1 162.8,30.1 162.7,29.99 162.7,29.63 162.6,29.53 160.48,29.53 160.32,29.7 160.32,30.03 160.01,30.33 160.01,31.01 159.96,31.07 159.8,31.07 v1(159.61,30.88) 159.54,30.81 158.47,30.81 158.22,31.07 154.22,31.07 153.75,30.6 152.14,30.6 150.91,29.37 146.95,29.37 146.8,29.51 144.39,29.51 143.68,30.22 143.36,30.22 143.09,30.49 140.49,30.49 139.16,29.16 v4(138.99,29.16)
  BOTTOM w0.076: UCPU1.AK32 132.69,56.01 v1(132.37,55.69)
DDR_B_D0: length 18.8
  TOP w0.102: UD7.F2 132.78,32.64 v1(133.14,32.29)
  IN2 w0.076: 133.38,42.96 133.38,43.42 133.82,43.87 133.82,45.49 v1(133.29,46.03)
  IN2 w0.152: 133.38,42.96 133.38,32.53 v1(133.14,32.29)
  BOTTOM w0.076: UCPU1.AY31 132.7,49.52 132.7,49.1 132.52,48.91 132.52,46.79 v1(133.29,46.03)
DDR_B_D1: length 20.7
  TOP w0.102: v1(133.2,31.49) 132.84,31.85 UD7.G2
  IN2 w0.076: v1(133.25,44.84) 133.63,44.45 133.63,43.94 132.97,43.28
  IN2 w0.089: 132.97,43.28 132.97,42.96
  IN2 w0.152: 132.97,42.96 132.97,33.49 132.73,33.25 132.73,31.97 v1(133.2,31.49)
  BOTTOM w0.076: v1(133.25,44.84) 132.87,45.21 132.87,45.93 132.35,46.45 132.35,49.04 132.54,49.23 132.54,49.72 132.61,49.86 132.63,49.9 132.83,50.1 UCPU1.AW31
DDR_B_D2: length 20.8
  TOP w0.102: UD7.H7 136.78,31.05 136.91,31.18 136.98,31.18 v1(137.22,31.42)
  IN2 w0.076: 135.28,42.96 135.28,43.9 v1(134.9,44.28)
  IN2 w0.152: v1(137.22,31.42) 136.81,31.82 136.81,32.53 137.58,33.29 137.58,34.28 137.61,34.32 137.61,36.85 135.28,39.18 135.28,42.96
  BOTTOM w0.076: v1(134.9,44.28) 134.06,45.12 134.06,48.52 134.18,48.64 UCPU1.AY29
DDR_B_D3: length 22.3
  TOP w0.102: UD7.F8 137.58,32.61 137.58,32.61 137.22,32.24 v1(137.22,32.23)
  IN2 w0.076: 135.63,42.96 135.63,44.12 v1(134.9,44.85)
  IN2 w0.152: v1(137.22,32.23) 137.72,32.73 138.69,32.73 139.21,33.26 139.21,36.6 135.63,40.19 135.63,42.96
  BOTTOM w0.076: UCPU1.AW29 134.18,50.06 134.46,49.78 134.46,49.51 134.34,49.4 134.34,48.55 134.23,48.43 134.23,45.51 v1(134.9,44.85)
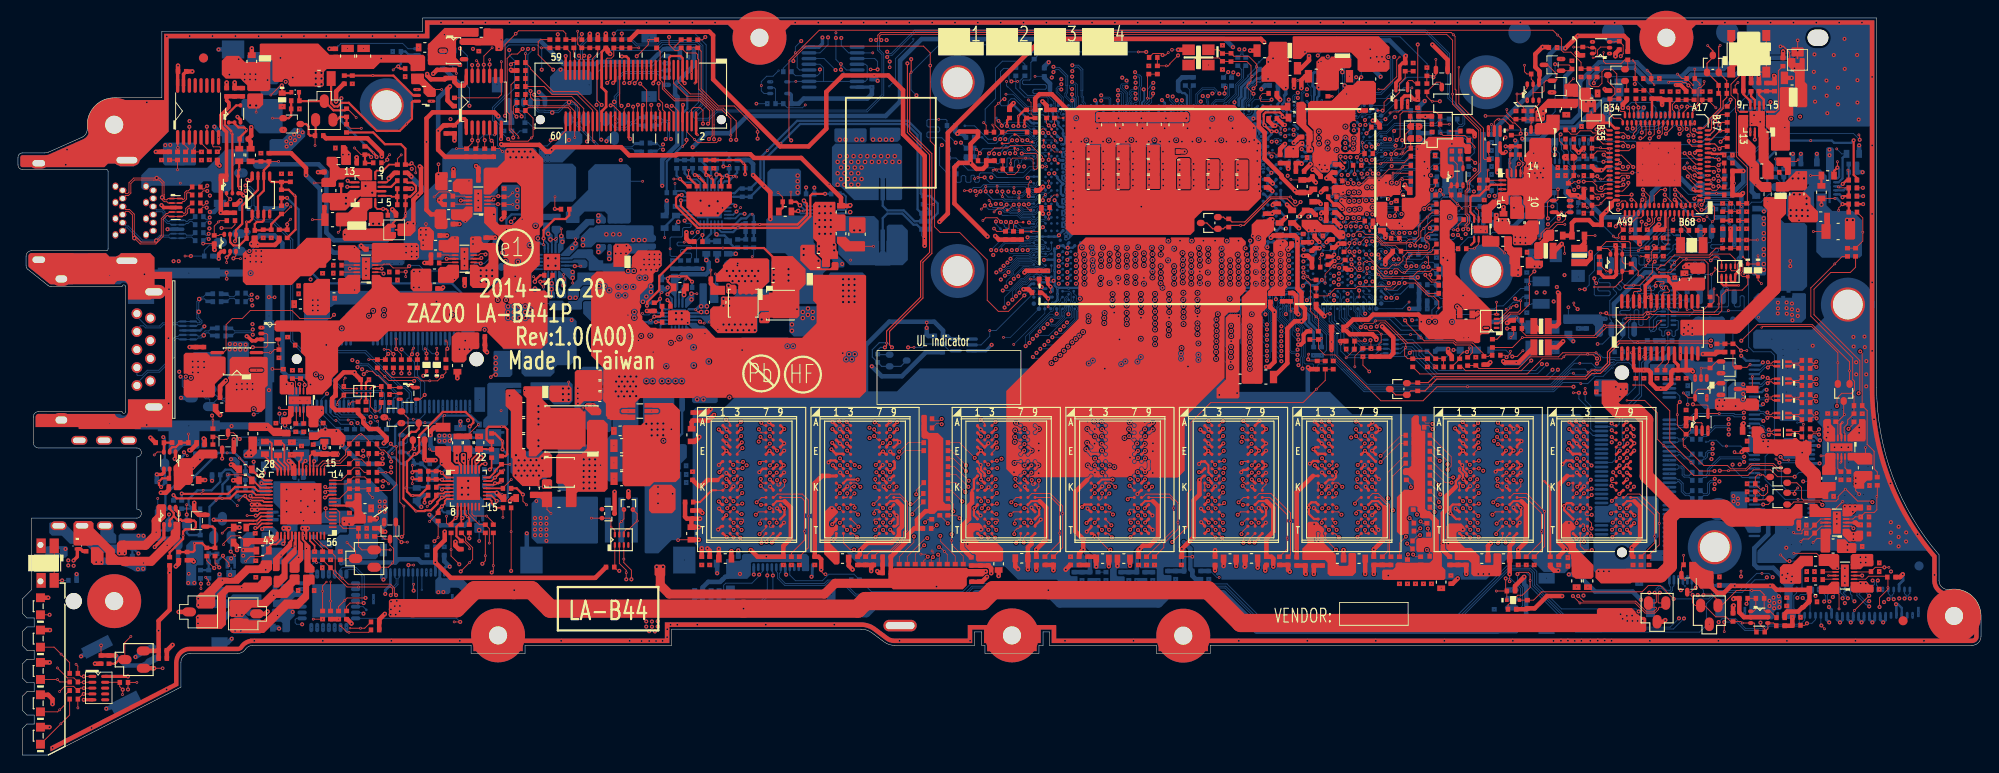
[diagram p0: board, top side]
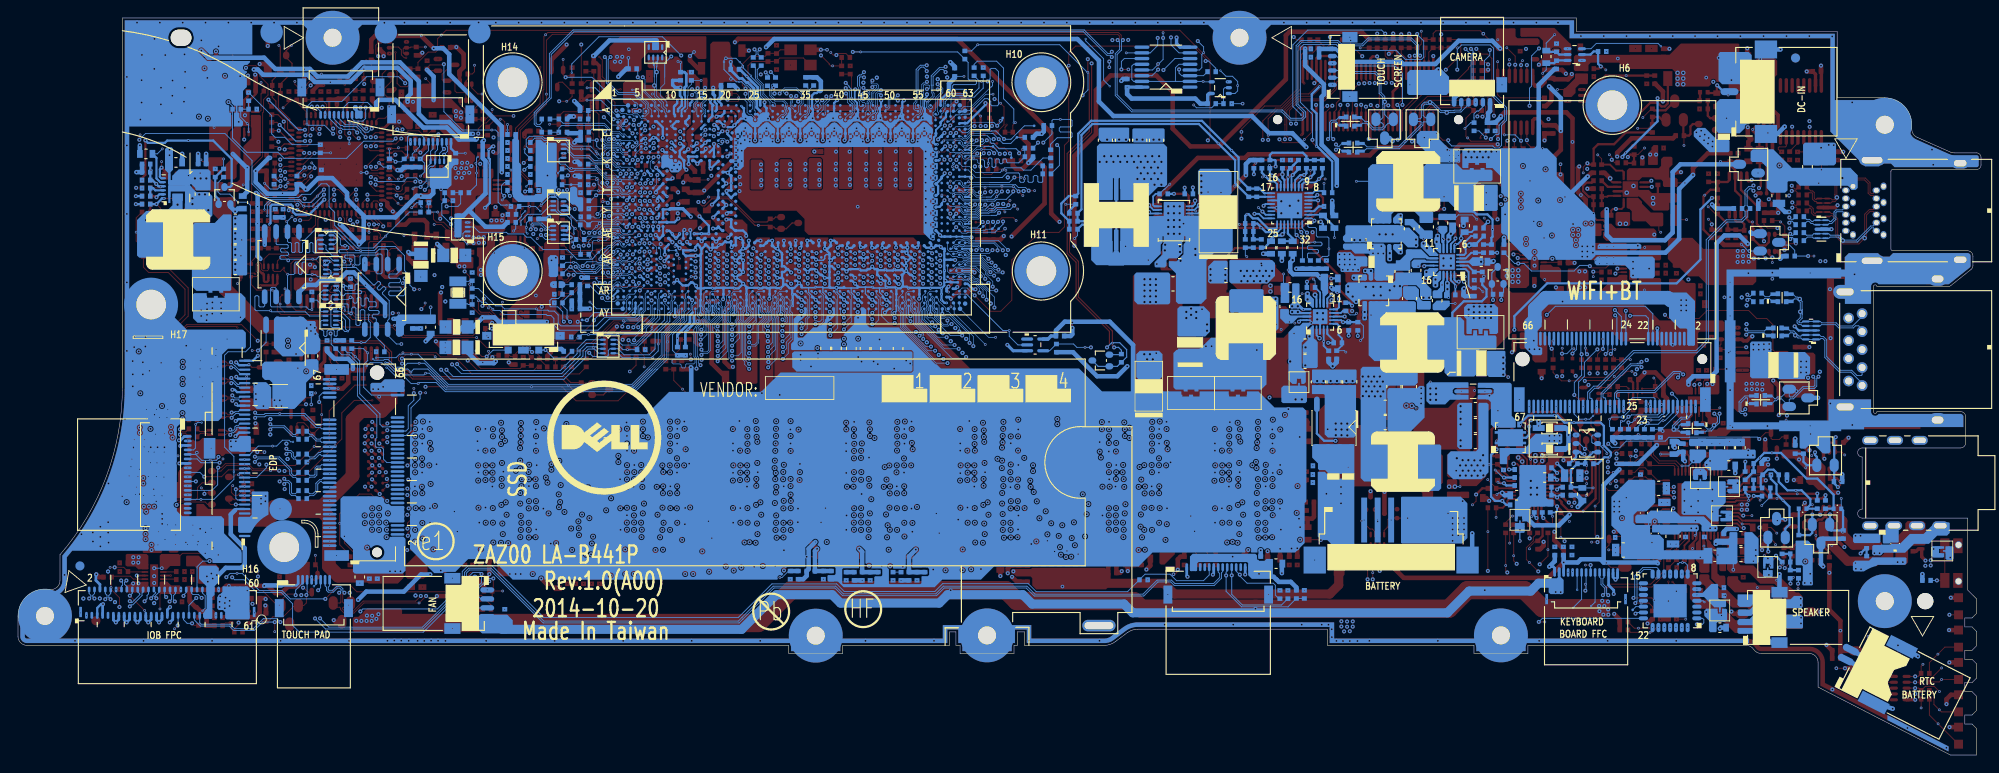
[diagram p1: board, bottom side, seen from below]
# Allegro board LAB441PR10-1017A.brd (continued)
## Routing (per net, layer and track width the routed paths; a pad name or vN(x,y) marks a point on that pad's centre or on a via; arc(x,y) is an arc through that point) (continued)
DDR_B_D4: length 23
  TOP w0.102: v1(133.21,30.68) 133.58,31.05 UD7.H3
  IN2 w0.152: v1(133.21,30.68) 133.04,30.68 131.92,31.8 131.92,43.32 132.67,44.07 v1(133.25,44.07)
  BOTTOM w0.076: v1(133.25,44.07) 132.64,44.67 132.64,45.78 132.19,46.23 132.19,49.17 132.37,49.36 132.37,49.76 132.39,49.8 132.44,49.9 132.44,50.57 UCPU1.AV31
DDR_B_D5: length 20.5
  TOP w0.102: v1(134.09,33.84) 133.7,33.45 UD7.E3
  IN2 w0.076: 133.72,42.96 133.72,43.45 134.01,43.74 134.01,45.9 v1(133.29,46.63)
  IN2 w0.152: v1(134.09,33.84) 134.46,34.21 134.46,37.22 133.72,37.96 133.72,40.25 133.72,40.25 133.72,42.96
  BOTTOM w0.076: v1(133.29,46.63) 133.71,47.05 133.71,48.69 133.83,48.8 133.83,49.21 133.72,49.31 133.72,49.75 133.79,49.89 133.8,49.91 133.8,50.03 133.79,50.05 133.78,50.06 133.76,50.12 133.72,50.19 133.72,50.41 133.76,50.49 133.8,50.57 133.8,50.75 133.78,50.76 133.78,51.14 133.8,51.15 133.8,51.4 133.59,51.6 UCPU1.AU31
DDR_B_D6: length 20.8
  TOP w0.102: v1(136.09,32.5) 136.25,32.65 136.78,32.65 UD7.F7
  IN2 w0.152: v1(136.09,32.5) 136.72,33.13 136.72,37.26 134.94,39.03 134.94,43.09 134.89,43.14 v1(134.89,43.14)
  BOTTOM w0.076: UCPU1.AV29 133.99,50.87 133.99,50.52 133.94,50.47 133.94,50.47 133.91,50.42 133.89,50.36 133.89,50.23 133.9,50.22 133.9,50.21 133.94,50.13 133.96,50.08 133.96,49.87 133.94,49.82 133.89,49.71 133.89,49.38 133.99,49.28 133.99,48.69 133.89,48.59 133.89,44.13 v1(134.89,43.14)
DDR_B_D7: length 24.3
  TOP w0.102: v1(137.98,31.42) 137.95,31.42 137.58,31.05 UD7.H8
  IN2 w0.076: 135.97,42.96 135.97,44.33 v1(134.91,45.39)
  IN2 w0.152: v1(137.98,31.42) 138.38,31.82 138.92,31.82 139.7,32.6 139.7,36.67 135.97,40.41 135.97,42.96
  BOTTOM w0.076: v1(134.91,45.39) 134.4,45.9 134.4,48.35 134.51,48.46 134.51,49.33 134.64,49.46 134.64,49.84 134.47,50 134.47,50.42 134.35,50.54 134.35,50.81 134.37,50.83 134.37,51.07 134.07,51.36 UCPU1.AU29
DDR_B_D8: length 14.8
  TOP w0.102: UD7.A2 132.78,36.75 v1(132.39,37.14)
  IN4 w0.119: v1(134.92,46.61) 134.46,46.14 134.46,41.2 133,39.74 133,37.76 v1(132.39,37.14)
  BOTTOM w0.076: v1(134.92,46.61) 135.47,47.15 135.47,47.71 135.47,47.71 135.47,48.03 135.02,48.48 135.02,49.14 135.13,49.25 135.13,49.61 135.17,49.65 UCPU1.AY27
DDR_B_D9: length 17.4
  TOP w0.102: v1(132.38,35.49) 132.78,35.09 UD7.C2
  IN4 w0.119: v1(132.38,35.49) 131.92,35.95 131.92,37.64 132.65,38.38 132.65,39.88 134.14,41.37 134.14,46.41 v1(134.91,47.18)
  BOTTOM w0.076: UCPU1.AW27 135.26,50.06 134.97,49.77 134.97,49.32 134.85,49.21 134.85,48.38 135.3,47.93 135.3,47.57 v1(134.91,47.18)
DDR_B_D10: length 15.3
  TOP w0.102: v1(137.2,36.26) 137.2,36.26 137.2,36.26 137.58,35.88 137.58,35.88 UD7.B8
  IN4 w0.119: v1(137.2,36.26) 137.2,40.55 137.98,41.33 137.98,43.12 v1(136.99,44.11)
  BOTTOM w0.076: UCPU1.AY25 136.48,49.52 136.48,48.7 137.39,47.8 137.39,44.5 v1(136.99,44.11)
DDR_B_D11: length 15.4
  TOP w0.102: v1(136.26,37.16) 136.77,36.65 UD7.A7
  IN4 w0.119: v1(136.26,37.16) 136.26,40.05 137.47,41.26 137.47,43.04 v1(136.99,43.52)
  BOTTOM w0.076: v1(136.99,43.52) 137.55,44.08 137.55,47.91 136.65,48.81 136.65,49.27 136.9,49.52 136.9,49.68 136.85,49.78 136.85,49.81 136.83,49.87 136.83,50.08 UCPU1.AW25
DDR_B_D12: length 17.7
  TOP w0.102: v1(134.01,35.49) 134,35.49 133.58,35.07 UD7.C3
  IN4 w0.119: v1(134.01,35.49) 133.35,36.16 133.35,39.59 135.31,41.55 135.31,47.36 v1(134.91,47.76)
  BOTTOM w0.076: UCPU1.AV27 135.37,50.82 134.97,50.42 134.97,50.01 134.8,49.85 134.8,49.39 134.68,49.26 134.68,48.32 134.91,48.08 v1(134.91,47.76)
DDR_B_D13: length 19.7
  TOP w0.102: v1(137.19,34.63) 136.81,34.25 UD7.D7
  IN4 w0.119: v1(137.19,34.63) 137.62,35.07 137.62,40.53 138.33,41.24 138.33,45.71 v1(136.99,47.04)
  BOTTOM w0.076: v1(136.99,47.04) 136.57,47.46 136.57,47.79 136.15,48.21 136.15,49.75 136.23,49.91 136.23,49.99 136.18,50.1 136.18,50.14 136.15,50.19 136.15,50.41 136.19,50.49 136.22,50.54 136.23,50.56 136.23,51.4 136.02,51.6 UCPU1.AU27
DDR_B_D14: length 16.8
  TOP w0.102: UD7.A3 133.58,36.72 v1(133.99,37.13)
  IN4 w0.119: v1(133.99,37.13) 133.98,37.13 133.7,37.41 133.7,39.45 135.67,41.42 135.67,47.08 136.28,47.69 v1(136.99,47.69)
  BOTTOM w0.076: UCPU1.AV25 136.61,50.71 136.37,50.47 136.34,50.42 136.32,50.36 136.32,50.23 136.33,50.22 136.33,50.21 136.37,50.13 136.37,50.13 136.39,50.08 136.39,49.94 136.41,49.9 136.35,49.77 136.32,49.7 136.32,48.36 v1(136.99,47.69)
DDR_B_D15: length 19.1
  TOP w0.102: v1(137.19,35.44) 137.58,35.05 UD7.C8
  IN4 w0.119: v1(137.19,35.44) 136.73,35.9 136.73,36.36 136.43,36.67 135.97,36.67 135.82,36.82 135.82,40.04 137.16,41.38 137.16,42.79 v1(136.99,42.96)
  BOTTOM w0.076: UCPU1.AU25 136.99,51.22 136.99,49.91 137.02,49.85 137.03,49.84 137.04,49.8 137.04,49.8 137.04,49.8 137.07,49.75 137.07,49.46 136.93,49.31 136.82,49.2 136.82,48.88 137.05,48.65 137.06,48.65 137.37,48.34 137.37,48.32 137.72,47.97 137.72,44.01 137.51,43.8 137.51,43.47 v1(136.99,42.96)
DDR_B_D16: length 42.9
  TOP w0.102: UD1.G2 161.16,31.85 v1(161.52,31.49)
  IN2 w0.076: 145.19,42.96 143.62,44.53 143.62,46.56 142.45,47.72 141.23,47.72 140.72,48.23 139.44,48.23 139.22,48.45 135.6,48.45 133.28,50.76 133.28,53.98 133.69,54.39 v1(133.86,54.39)
  IN2 w0.152: 145.19,42.96 145.51,42.64 146.15,42.64 153.71,35.08 158.27,35.08 160.31,33.03 160.75,33.03 161.05,32.73 161.05,31.96 v1(161.52,31.49)
  BOTTOM w0.076: v1(133.86,54.39) 134.19,54.71 UCPU1.AM29
DDR_B_D17: length 45.7
  TOP w0.102: UD1.H3 161.87,31.05 v1(161.5,30.68)
  IN2 w0.076: 142.27,43 141.88,43.4 141.88,45.47 140.86,46.48 140.86,47.84 140.65,48.05 139.37,48.05 139.15,48.27 135.52,48.27 133.1,50.69 133.1,55.25 133.54,55.69 v1(133.86,55.69)
  IN2 w0.152: v1(161.5,30.68) 159.84,32.34 159.84,32.94 158.08,34.7 153.55,34.7 148.45,39.8 145.47,39.8 142.27,43
  BOTTOM w0.076: v1(133.86,55.69) 134.19,56.01 UCPU1.AK29
DDR_B_D18: length 46.4
  TOP w0.102: v1(165.54,32.23) 165.54,32.24 165.9,32.61 UD1.F8
  IN2 w0.076: 149.93,42.96 148.52,44.38 147.56,44.38 143.17,48.76 143.17,49.41 142.44,50.13 139.5,50.13 139.31,50.33 136.88,50.33 135.36,51.86 135.36,54.48 v1(134.8,55.04)
  IN2 w0.14: 165.07,37.59 165.92,36.74
  IN2 w0.152: 149.93,42.96 154.08,38.81 163.85,38.81 165.07,37.59 ; v1(165.54,32.23) 165.92,32.61 165.92,36.74
  BOTTOM w0.076: v1(134.8,55.04) 135.13,55.36 UCPU1.AL28
DDR_B_D19: length 48
  TOP w0.102: v1(166.3,31.42) 166.27,31.42 165.9,31.05 UD1.H8
  IN2 w0.076: 150.49,42.96 148.9,44.55 147.63,44.55 143.34,48.84 143.34,49.48 142.52,50.31 139.58,50.31 139.38,50.51 137.08,50.51 136.14,51.45 136.14,55.18 v1(135.64,55.68)
  IN2 w0.152: 150.49,42.96 154.3,39.15 164.05,39.15 166.73,36.47 166.73,31.85 v1(166.3,31.42)
  BOTTOM w0.076: UCPU1.AK28 135.31,56.01 v1(135.64,55.68)
DDR_B_D20: length 39.6
  TOP w0.102: UD1.E3 161.9,33.57 v1(162.48,34.15)
  IN2 w0.076: 145.95,43.4 145.47,43.4 144.34,44.53 144.34,46.35 142.61,48.08 141.38,48.08 140.87,48.59 139.69,48.59 138.87,49.4 135.61,49.4 133.86,51.14 v1(133.86,52.43)
  IN2 w0.152: 145.95,43.4 146.48,43.4 154.03,35.84 158.96,35.84 160.55,34.26 162.36,34.26 v1(162.48,34.15)
  BOTTOM w0.089: v1(133.86,52.43) 134.12,52.43 134.24,52.56 UCPU1.AR29
DDR_B_D21: length 40.9
  TOP w0.102: UD1.F2 161.1,32.65 v1(161.46,32.3)
  IN2 w0.076: 146.02,43.08 145.53,43.08 144.11,44.5 144.11,46.32 142.53,47.9 141.3,47.9 140.8,48.41 139.51,48.41 139.3,48.62 136.49,48.62 135.94,49.18 135.58,49.18 133.46,51.3 133.46,53.3 133.86,53.71 v1(133.86,53.74)
  IN2 w0.152: v1(161.46,32.3) 161.46,32.96 161,33.42 160.57,33.42 158.52,35.46 153.87,35.46 146.25,43.08 146.02,43.08
  BOTTOM w0.076: UCPU1.AN29 134.19,54.06 v1(133.86,53.74)
DDR_B_D22: length 42.5
  TOP w0.102: v1(164.49,32.5) 164.64,32.65 UD1.F7
  IN2 w0.076: v1(134.8,52.43) 134.8,51.9 136.74,49.97 139.16,49.97 139.36,49.78 142.3,49.78 142.81,49.26 142.81,48.61 147.41,44.02 147.9,44.02 148.96,42.96
  IN2 w0.152: v1(164.49,32.5) 164.08,32.9 164.08,34.17 163.52,34.74 163.52,37.95 163.34,38.12 153.8,38.12 148.96,42.96
  BOTTOM w0.089: UCPU1.AR28 135.13,52.76 v1(134.8,52.43)
DDR_B_D23: length 44.8
  TOP w0.102: UD1.H7 165.1,31.05 165.23,31.18 165.3,31.18 v1(165.54,31.42)
  IN2 w0.076: v1(134.8,53.08) 135.18,52.71 135.18,51.78 136.81,50.15 139.23,50.15 139.43,49.95 142.37,49.95 142.99,49.34 142.99,48.69 147.48,44.2 148.21,44.2 149.38,43.02
  IN2 w0.152: 149.38,43.02 153.94,38.47 163.66,38.47 164.99,37.13 164.99,31.96 v1(165.54,31.42)
  BOTTOM w0.089: v1(134.8,53.08) 135.13,53.41 UCPU1.AP28
DDR_B_D24: length 37.9
  TOP w0.102: UD1.A3 162.09,36.65 v1(162.38,36.94)
  IN4 w0.076: 145.5,42.96 145.27,43.19 145.27,43.93 143.76,45.45 143.76,46.88 142.61,48.03 141.6,48.03 141.23,48.39 140.23,48.39 138.15,50.47 136.89,50.47 135.37,52 135.37,53.38 135.72,53.74 v1(135.76,53.74)
  IN4 w0.119: 145.5,42.96 150.08,38.38 158.83,38.38 160.14,37.07 160.14,37.01 160.52,36.63 162.06,36.63 v1(162.38,36.94)
  BOTTOM w0.076: UCPU1.AN26 136.08,54.06 v1(135.76,53.74)
DDR_B_D25: length 36.5
  TOP w0.102: UD1.A2 161.06,36.65 v1(160.67,37.04)
  IN4 w0.076: 145.61,43.29 145.61,43.87 143.93,45.55 143.93,46.95 142.68,48.2 141.68,48.2 141.31,48.57 140.31,48.57 138.23,50.65 136.97,50.65 135.76,51.86 v1(135.76,52.43)
  IN4 w0.086: 145.94,42.96 145.61,43.29
  IN4 w0.099: v1(160.67,37.04) 160.12,37.59
  IN4 w0.119: 160.12,37.59 158.99,38.73 150.17,38.73 148.06,40.84 148.06,41 148.44,41.38 148.44,41.55 148.28,41.72 148.11,41.72 147.73,41.34 147.56,41.34 147.39,41.51 147.39,41.68 147.77,42.06 147.77,42.23 147.6,42.4 147.43,42.4 147.05,42.02 146.88,42.02 145.94,42.96
  BOTTOM w0.089: UCPU1.AR26 136.08,52.76 v1(135.76,52.43)
DDR_B_D26: length 36.1
  TOP w0.102: UD1.A7 164.9,36.65 v1(164.58,36.97)
  IN4 w0.076: 147.71,43.89 142.8,48.8 142.8,49.15 142.56,49.39 141.85,49.39 141.1,50.14 139.64,50.14 138.5,51.28 137.61,51.28 137,51.89 136.71,52.18 v1(136.71,52.43)
  IN4 w0.119: 147.71,43.89 147.91,43.89 152,39.8 159.44,39.8 161.05,38.19 163.87,38.19 164.58,37.48 v1(164.58,36.97)
  BOTTOM w0.076: UCPU1.AR25 137.03,52.76 v1(136.71,52.43)
DDR_B_D27: length 39.6
  TOP w0.102: v1(164.6,34.6) 164.76,34.6 164.92,34.44 UD1.D7
  IN4 w0.076: 147.66,44.21 142.98,48.89 142.98,49.22 142.64,49.56 141.93,49.56 141.18,50.31 139.71,50.31 138.57,51.45 137.69,51.45 137.07,52.07 137.07,52.73 v1(136.71,53.08)
  IN4 w0.119: 147.66,44.21 148.03,44.21 152.13,40.11 159.57,40.11 161.18,38.5 164.06,38.5 165.05,37.5 165.05,35.18 164.96,35.09 164.96,34.96 v1(164.6,34.6)
  BOTTOM w0.076: UCPU1.AP25 137.03,53.41 v1(136.71,53.08)
DDR_B_D28: length 43.8
  TOP w0.102: v1(162.4,35.49) 162.39,35.49 161.95,35.05 161.95,35.05 UD1.C3
  IN4 w0.076: v1(136.53,56.37) 135.46,56.37 134.45,55.36 134.45,52.28 136.6,50.13 136.99,50.13 138.55,48.56 139.42,48.56 139.93,48.05 141.09,48.05 141.45,47.68 142.46,47.68 143.41,46.73 143.41,45.25 144.55,44.11 144.55,43.04 144.63,42.96
  IN4 w0.119: 144.63,42.96 149.92,37.67 152.29,37.67 152.29,37.68 158.18,37.68 159.41,36.45 159.41,36.08 160.43,35.07 161.97,35.07 v1(162.4,35.49)
  BOTTOM w0.076: UCPU1.AK26 136.17,56.01 v1(136.53,56.37)
DDR_B_D29: length 37.8
  TOP w0.102: v1(160.7,35.47) 161.1,35.06 UD1.C2
  IN4 w0.076: 145.07,42.96 144.88,43.14 144.88,44.05 143.59,45.35 143.59,46.8 142.54,47.85 141.53,47.85 141.16,48.22 140.16,48.22 138.08,50.3 136.82,50.3 135.19,51.93 135.19,53.82 135.72,54.34 v1(135.72,54.35)
  IN4 w0.119: 145.07,42.96 149.99,38.03 158.69,38.03 160.22,36.49 160.22,35.95 v1(160.7,35.47)
  BOTTOM w0.076: UCPU1.AM26 136.08,54.71 v1(135.72,54.35)
DDR_B_D30: length 41.6
  TOP w0.102: v1(165.49,35.45) 165.89,35.05 UD1.C8
  IN4 w0.076: 147.63,44.78 143.33,49.08 143.33,49.37 143.1,49.6 143.1,49.6 142.79,49.91 142.08,49.91 141.15,50.83 140.7,50.83 139.73,51.8 138.63,51.8 138.12,52.32 138.12,54.07 137.19,54.99 137.19,55.37 136.88,55.69 v1(136.66,55.69)
  IN4 w0.119: v1(165.49,35.45) 165.9,35.87 165.9,37.64 164.42,39.12 161.44,39.12 159.82,40.73 152.38,40.73 148.34,44.78 147.63,44.78
  BOTTOM w0.076: v1(136.66,55.69) 136.98,56.01 UCPU1.AK25
DDR_B_D31: length 39.9
  TOP w0.102: v1(165.49,36.26) 165.49,36.26 165.49,36.26 165.9,35.85 UD1.B8
  IN4 w0.076: v1(136.74,55.04) 137.09,54.69 137.09,52.95 137.24,52.8 137.24,52.15 137.76,51.63 139.66,51.63 140.63,50.66 141.08,50.66 142,49.73 142.72,49.73 143.16,49.29 143.16,49.17 143.16,49.17 143.16,48.99 147.62,44.53
  IN4 w0.099: 165.46,37.59 165.49,37.56
  IN4 w0.119: 147.62,44.53 148.15,44.53 152.26,40.42 159.69,40.42 161.31,38.81 164.24,38.81 165.46,37.59 ; 165.49,37.56 v1(165.49,36.26)
  BOTTOM w0.076: v1(136.74,55.04) 137.07,55.36 UCPU1.AL25
DDR_B_D32: length 20
  TOP w0.102: v1(145.83,33.83) 146.19,33.47 UD3.E3
  IN2 w0.076: v1(138.9,46.19) 139.62,45.48 139.62,43.65 139.51,43.55 139.51,43.32
  IN2 w0.152: v1(145.83,33.83) 145.24,33.83 143.72,35.35 143.72,36.42 139.51,40.63 139.51,43.32
  BOTTOM w0.076: UCPU1.AY23 137.96,48.43 138.21,48.18 138.21,46.88 v1(138.9,46.19)
DDR_B_D33: length 21
  TOP w0.102: UD3.F2 145.39,32.65 v1(145.03,33.02)
  IN2 w0.076: v1(138.9,45.54) 139.27,45.17 139.27,43.56 139.17,43.46 139.17,42.96
  IN2 w0.152: 139.17,42.96 139.17,40.43 143.27,36.33 143.27,35.48 145.03,33.73 v1(145.03,33.02)
  BOTTOM w0.076: v1(138.9,45.54) 138.47,45.97 138.05,46.39 138.05,48.11 137.8,48.36 137.8,49.33 137.67,49.45 137.67,49.72 137.74,49.86 137.76,49.9 137.96,50.1 UCPU1.AW23
DDR_B_D34: length 24.7
  TOP w0.102: UD3.H8 150.18,31.05 v1(149.77,31.47)
  IN2 w0.076: v1(140.48,44.4) 140.86,44.02 140.86,43.63 141.14,43.35 141.14,42.96
  IN2 w0.152: v1(149.77,31.47) 149.37,31.86 148.65,31.86 147.48,33.03 147.48,38.11 146.93,38.66 145,38.66 141.14,42.52 141.14,42.96
  BOTTOM w0.076: v1(140.48,44.4) 139.58,45.29 139.58,48.19 139.44,48.34 139.44,49.52 UCPU1.AY21
DDR_B_D35: length 23.8
  TOP w0.102: UD3.F7 149.36,32.65 149,32.29 v1(149,32.27)
  IN2 w0.076: v1(140.5,44.95) 141.18,44.27 141.18,43.57 141.5,43.25 141.5,42.96
  IN2 w0.152: v1(149,32.27) 147.83,33.44 147.83,38.33 147.16,39 145.14,39 141.5,42.65 141.5,42.96
  BOTTOM w0.076: UCPU1.AW21 139.31,50.06 139.61,49.77 139.61,48.41 139.75,48.26 139.75,45.7 v1(140.5,44.95)
DDR_B_D36: length 25.8
  TOP w0.102: UD3.G2 145.25,31.99 145.23,31.99 v1(145.01,32.22)
  IN2 w0.152: v1(145.01,32.22) 144.62,31.83 142.79,31.83 142.14,32.48 142.14,36.38 137.85,40.67 137.85,43.59 138.68,44.42 v1(138.9,44.42)
  BOTTOM w0.076: UCPU1.AV23 137.58,50.57 137.58,49.9 137.52,49.8 137.5,49.76 137.5,49.38 137.63,49.25 137.63,48.29 137.88,48.04 137.88,44.77 138.24,44.42 v1(138.9,44.42)
DDR_B_D37: length 25.6
  TOP w0.102: UD3.H3 145.8,31.45 v1(145.8,31.45)
  IN2 w0.076: 138.23,42.96 138.23,43.2 v1(138.9,43.87)
  IN2 w0.152: 138.23,42.96 138.23,40.83 142.52,36.54 142.52,34.85 144.76,32.62 145.24,32.62 145.42,32.44 145.42,31.83 v1(145.8,31.45)
  BOTTOM w0.076: UCPU1.AU23 138.73,51.6 138.93,51.4 138.93,51.15 138.91,51.14 138.91,50.76 138.93,50.75 138.93,50.56 138.92,50.54 138.9,50.49 138.86,50.41 138.86,50.19 138.89,50.12 138.93,50.03 138.93,49.91 138.86,49.75 138.86,49.46 139.09,49.22 139.09,48.22 139.25,48.06 139.25,44.23 v1(138.9,43.87)
DDR_B_D38: length 25.7
  TOP w0.102: v1(149,31.45) 149.39,31.06 UD3.H7
  IN2 w0.076: 140.78,42.96 140.78,43.19 140.5,43.48 v1(140.5,43.82)
  IN2 w0.152: 140.78,42.96 140.78,42.37 144.84,38.31 146.73,38.31 147.13,37.92 147.13,32.79 148.47,31.45 v1(149,31.45)
  BOTTOM w0.076: v1(140.5,43.82) 139.42,44.9 139.42,48.12 139.26,48.28 139.26,49.28 139.02,49.53 139.02,49.71 139.07,49.82 139.07,49.82 139.09,49.87 139.09,50.08 139.07,50.13 139.07,50.13 139.03,50.21 139.03,50.22 139.02,50.23 139.02,50.36 139.05,50.42 139.07,50.47 139.21,50.61 UCPU1.AV21
DDR_B_D39: length 25.9
  TOP w0.102: UD3.F8 150.19,32.63 v1(150.58,32.25)
  IN2 w0.076: v1(140.5,45.5) 141.51,44.49 141.51,43.49 141.85,43.14 141.85,42.96
  IN2 w0.152: v1(150.58,32.25) 149.29,33.53 149.29,37.42 149.29,37.42 147.36,39.34 145.28,39.34 141.85,42.78 141.85,42.96
  BOTTOM w0.076: v1(140.5,45.5) 139.92,46.08 139.92,48.33 139.77,48.47 139.77,49.84 139.61,50 139.61,50.42 139.5,50.53 139.5,51.07 139.21,51.36 UCPU1.AU21
DDR_B_D40: length 18.6
  TOP w0.102: v1(145.01,35.48) 145.39,35.1 145.39,35.1 UD3.C2
  IN4 w0.076: 139.64,42.96 139.64,45.76 v1(140.48,46.6)
  IN4 w0.119: v1(145.01,35.48) 143.94,35.48 142.92,36.49 142.92,39.3 139.64,42.59 139.64,42.96
  BOTTOM w0.076: v1(140.48,46.6) 141.06,47.17 141.06,47.95 140.27,48.74 140.27,49.52 UCPU1.AY19
DDR_B_D41: length 19.7
  TOP w0.102: v1(145.78,35.48) 145.77,35.48 145.77,35.47 146.19,35.05 UD3.C3
  IN4 w0.076: 140.26,42.96 140.26,43.19 140.53,43.46 140.66,43.46 140.86,43.66 140.86,47.06 140.78,47.14 v1(140.5,47.14)
  IN4 w0.119: v1(145.78,35.48) 145.36,35.9 144.01,35.9 143.57,36.34 143.57,39.1 140.26,42.4 140.26,42.96
  BOTTOM w0.076: v1(140.5,47.14) 140.89,47.54 140.89,47.89 140.1,48.68 140.1,49.77 140.39,50.06 UCPU1.AW19
DDR_B_D42: length 17.7
  TOP w0.102: UD3.B8 150.19,35.91 v1(150.59,36.31)
  IN4 w0.076: 144.17,43.52 144.17,44.22 143.09,45.3 143.09,46.54 142.31,47.32
  IN4 w0.086: 142.31,47.32 v1(142.31,47.32)
  IN4 w0.119: 144.17,43.52 144.17,42.71 149.57,37.31 149.58,37.31 150.24,36.65 150.24,36.65 v1(150.59,36.31)
  BOTTOM w0.076: v1(142.31,47.32) 142.05,47.58 142.05,48.2 141.7,48.55 141.7,49.61 UCPU1.AY17
DDR_B_D43: length 20.4
  TOP w0.102: UD3.D7 149.39,34.28 v1(149.78,34.66)
  IN4 w0.119: v1(149.78,34.66) 149.32,35.12 149.32,36.45 149.06,36.71 148.36,36.71 142.41,42.66 v1(142.41,43.38)
  BOTTOM w0.076: UCPU1.AW17 141.96,50.08 141.96,49.87 142.03,49.72 142.04,49.71 142.04,49.53 141.87,49.36 141.87,48.62 142.22,48.27 142.22,47.95 142.67,47.5 142.67,46.93 142.77,46.83 142.77,44.39 142.65,44.27 142.65,43.62 v1(142.41,43.38)
DDR_B_D44: length 17.2
  TOP w0.102: UD3.A2 145.39,36.67 v1(144.96,37.1)
  IN4 w0.076: v1(140.5,47.69) 141.05,47.14 141.05,43.59 140.58,43.12
  IN4 w0.086: 140.58,42.96 140.58,43.12
  IN4 w0.119: 140.58,42.96 140.58,42.52 144.96,38.14 v1(144.96,37.1)
  BOTTOM w0.076: UCPU1.AV19 140.5,50.8 140.1,50.4 140.1,50.01 139.94,49.85 139.94,48.54 140.5,47.98 v1(140.5,47.69)
DDR_B_D45: length 18.9
  TOP w0.102: v1(145.8,37.1) 146.19,36.7 UD3.A3
  IN4 w0.076: 141.14,42.96 141.14,43.23 141.45,43.54 141.45,45.28 v1(142.39,46.22)
  IN4 w0.119: v1(145.8,37.1) 145.8,37.75 141.14,42.4 141.14,42.96
  BOTTOM w0.076: v1(142.39,46.22) 142.24,46.22 141.7,46.76 141.7,48.09 141.37,48.41 141.37,49.33 141.29,49.41 141.29,49.75 141.35,49.89 141.36,49.91 141.36,50.04 141.35,50.06 141.32,50.12 141.29,50.19 141.29,50.41 141.33,50.49 141.35,50.54 141.36,50.56 141.36,51.4 141.16,51.6 UCPU1.AU19
DDR_B_D46: length 19.7
  TOP w0.102: v1(149.8,35.52) 150.19,35.12 UD3.C8
  IN4 w0.076: 143.86,44.25 142.92,45.18 142.92,46.2 v1(142.36,46.77)
  IN4 w0.119: v1(149.8,35.52) 149.76,35.56 149.76,36.68 143.86,42.58 143.86,44.25
  BOTTOM w0.076: UCPU1.AV17 141.74,50.71 141.5,50.47 141.48,50.42 141.45,50.36 141.45,50.23 141.46,50.22 141.46,50.21 141.5,50.13 141.53,50.08 141.53,49.87 141.5,49.82 141.45,49.71 141.45,49.48 141.54,49.39 141.54,48.48 141.89,48.13 141.89,47.23 v1(142.36,46.77)
DDR_B_D47: length 18.6
  TOP w0.102: UD3.A7 148.95,37.1 v1(148.81,37.1)
  IN4 w0.119: v1(148.81,37.1) 148.77,37.14 148.57,37.14 142.85,42.85 v1(142.85,42.99)
  BOTTOM w0.076: v1(142.85,42.99) 142.85,44.24 142.98,44.37 142.98,46.87 142.84,47.02 142.84,47.57 142.38,48.02 142.38,48.34 142.03,48.69 142.03,49.29 142.2,49.46 142.2,49.78 142.18,49.8 142.16,49.84 142.15,49.85 142.13,49.91 142.13,50.46 142.04,50.56 142.04,51.31 UCPU1.AU17
DDR_B_D48: length 47.1
  TOP w0.102: v1(174.15,33.87) 174.54,33.47 UD4.E3
  IN2 w0.076: 150.14,45.42 149.51,45.42 143.77,51.15 141.06,51.15 140.53,51.68 140.1,51.68 139.46,52.32 v1(139.46,52.43)
  IN2 w0.152: 150.14,45.42 150.46,45.09 150.68,45.09 151.15,45.56 151.36,45.56 151.58,45.34 151.58,45.13 151.11,44.66 151.11,44.44 151.33,44.23 151.54,44.23 152.01,44.69 152.22,44.69 152.44,44.48 152.44,44.26 151.97,43.8 151.97,43.58 154.92,40.64 167.34,40.64 172.9,35.08 172.9,34.33 173.36,33.87 v1(174.15,33.87)
  BOTTOM w0.076: v1(139.46,52.43) 139.79,52.76 UCPU1.AR21
DDR_B_D49: length 49.2
  TOP w0.102: v1(173.35,32.27) 173.6,32.02 173.6,31.99 UD4.G2
  IN2 w0.076: 149.64,44.94 147.75,44.94 143.7,48.99 143.7,49.63 142.63,50.7 141.01,50.7 140.39,51.32 139.95,51.32 139.6,51.67 139.28,51.67 v1(138.51,52.43)
  IN2 w0.152: 149.64,44.94 154.63,39.95 164.43,39.95 165.12,39.27 165.33,39.27 165.76,39.7 165.97,39.7 166.19,39.48 166.19,39.26 165.76,38.84 165.76,38.62 166.01,38.38 166.22,38.38 167.33,39.5 167.51,39.5 167.77,39.24 167.77,39.06 167.29,38.57 167.29,38.33 170.79,34.82 170.79,33.26 171.31,32.75 172.87,32.75 v1(173.35,32.27)
  BOTTOM w0.076: UCPU1.AR22 138.83,52.76 v1(138.51,52.43)
DDR_B_D50: length 53
  TOP w0.102: UD4.H7 177.41,31.39 v1(177.41,31.46)
  IN2 w0.076: 148.91,47.18 148.47,47.18 143.99,51.67 141.36,51.67 140.78,52.24 140.78,55.13 140.57,55.34 139.77,55.34 v1(139.46,55.04)
  IN2 w0.152: v1(177.41,31.46) 175.46,33.4 175.46,37.26 174.52,38.2 171.4,38.2 167.82,41.78 157.01,41.78 151.6,47.18 148.91,47.18
  BOTTOM w0.076: v1(139.46,55.04) 139.79,55.36 UCPU1.AL21
DDR_B_D51: length 55.8
  TOP w0.102: v1(178.16,33.05) 177.76,32.65 UD4.F7
  IN2 w0.076: v1(138.51,54.39) 138.96,54.83 138.96,55.72 139.28,56.05 139.94,56.05 140.18,56.29 140.76,56.29 141.09,56.62 141.53,56.62 141.88,56.28 141.88,53.34 142.64,52.57 143.59,52.57 147.45,48.71 150.66,48.71
  IN2 w0.152: v1(178.16,33.05) 177.11,33.05 176.23,33.94 176.23,37.46 174.81,38.88 171.68,38.88 168.1,42.47 158.22,42.47 151.97,48.71 150.66,48.71
  BOTTOM w0.076: UCPU1.AM22 138.83,54.71 v1(138.51,54.39)
DDR_B_D52: length 50.3
  TOP w0.102: v1(174.14,31.45) 174.14,31.45 UD4.H3
  IN2 w0.076: 149.37,44.73 147.71,44.73 143.52,48.91 143.52,49.56 142.56,50.52 140.94,50.52 140.31,51.14 139.87,51.14 139.53,51.49 138.94,51.49 138.14,52.28 138.14,53.37 v1(138.51,53.74)
  IN2 w0.152: 149.37,44.73 154.49,39.61 164.28,39.61 166.12,37.77 166.33,37.77 166.71,38.15 166.93,38.15 167.14,37.94 167.14,37.72 166.76,37.34 166.76,37.13 166.98,36.91 167.19,36.91 167.57,37.29 167.79,37.29 170.43,34.65 170.43,33.1 171.71,31.82 172.91,31.82 172.94,31.84 173.75,31.84 v1(174.14,31.45)
  BOTTOM w0.076: v1(138.51,53.74) 138.83,54.06 UCPU1.AN22
DDR_B_D53: length 48.4
  TOP w0.102: UD4.F2 173.74,32.65 173.37,33.02 v1(173.37,33)
  IN2 w0.076: 149.92,45.15 149.52,45.15 143.7,50.97 140.99,50.97 140.46,51.5 140.02,51.5 139.68,51.84 139.54,51.84 139.1,52.28 139.1,52.72 v1(139.46,53.08)
  IN2 w0.152: v1(173.37,33) 173.22,33.15 172.69,33.15 171.96,33.88 171.96,35.53 169.82,37.68 169.6,37.68 169.12,37.2 168.9,37.2 168.69,37.42 168.69,37.63 169.17,38.11 169.17,38.33 168.95,38.54 168.74,38.54 168.27,38.08 168.09,38.08 167.84,38.33 167.84,38.51 168.31,38.97 168.31,39.19 167.2,40.3 154.77,40.3 149.92,45.15
  BOTTOM w0.076: v1(139.46,53.08) 139.79,53.41 UCPU1.AP21
DDR_B_D54: length 54.3
  TOP w0.102: v1(178.11,31.48) UD4.H8
  IN2 w0.076: 148.49,48.06 147.85,48.06 144.06,51.84 141.43,51.84 140.96,52.32 140.96,55.72 140.56,56.11 140.26,56.11 139.83,55.69 v1(139.44,55.69)
  IN2 w0.152: 148.49,48.06 152.14,48.06 158.08,42.12 167.96,42.12 171.54,38.54 174.66,38.54 175.85,37.36 175.85,33.75 v1(178.11,31.48)
  BOTTOM w0.076: v1(139.44,55.69) 139.76,56.01 UCPU1.AK21
DDR_B_D55: length 55.8
  TOP w0.102: v1(178.93,33.07) 178.93,33.07 178.93,33.07 178.54,32.69 UD4.F8
  IN2 w0.076: 150.37,49.46 146.95,49.46 143.66,52.75 142.73,52.75 142.05,53.42 142.05,56.35 141.61,56.8 141.01,56.8 140.69,56.47 140.11,56.47 139.87,56.23 139.21,56.23 138.67,55.69 v1(138.51,55.69)
  IN2 w0.152: v1(178.93,33.07) 178.54,33.47 177.02,33.47 176.54,33.95 176.54,37.64 174.95,39.23 171.82,39.23 168.24,42.81 158.36,42.81 151.71,49.46 150.37,49.46
  BOTTOM w0.076: UCPU1.AK22 138.83,56.01 v1(138.51,55.69)
DDR_B_D56: length 46.2
  TOP w0.102: UD4.A3 174.52,36.65 v1(174.11,37.07)
  IN4 w0.076: 147.73,45.45 143.89,49.29 143.89,49.55 143.01,50.43 142.51,50.43 141.59,51.35 140.92,51.35 140.05,52.21 140.05,53.38 v1(140.41,53.74)
  IN4 w0.086: 148.92,45.45 147.73,45.45
  IN4 w0.119: 148.92,45.45 149.15,45.45 151.88,42.71 152.15,42.71 152.27,42.59 152.27,42.35 152.39,42.23 152.62,42.23 152.74,42.35 152.74,42.59 152.86,42.71 153.1,42.71 153.22,42.59 153.22,41.92 153.33,41.81 153.57,41.81 153.7,41.94 153.7,42.59 153.82,42.71 154.04,42.71 154.16,42.59 154.16,41.9 154.28,41.78 160.26,41.78 161.87,40.16 164.85,40.16 168.35,36.67 173.71,36.67 v1(174.11,37.07)
  BOTTOM w0.076: UCPU1.AN20 140.74,54.06 v1(140.41,53.74)
DDR_B_D57: length 41.8
  TOP w0.102: v1(173.27,37.11) 173.73,36.65 UD4.A2
  IN4 w0.076: v1(140.41,52.43) 140.41,52.1 140.99,51.52 141.67,51.52 142.14,51.05 143.56,51.05 148.96,45.64
  IN4 w0.086: 148.96,45.64 149.39,45.64
  IN4 w0.119: 149.39,45.64 151.33,43.7 151.82,43.7 151.94,43.58 151.94,43.21 152.06,43.09 152.39,43.09 152.51,43.21 152.51,43.61 152.63,43.73 152.86,43.73 152.98,43.61 152.98,43.21 153.1,43.09 154.1,43.09 155.1,42.09 160.38,42.09 162,40.47 164.98,40.47 167.95,37.5 172.88,37.5 v1(173.27,37.11)
  BOTTOM w0.076: v1(140.41,52.43) 140.74,52.76 UCPU1.AR20
DDR_B_D58: length 47.8
  TOP w0.102: UD4.B8 178.55,35.85 v1(178.93,36.24)
  IN4 w0.076: 141.9,53.68 142.81,52.76 143.4,52.76 147.47,48.68
  IN4 w0.086: v1(141.33,55.65) 141.9,55.08 141.9,53.68
  IN4 w0.119: 147.47,48.68 152.37,48.68 156.96,44.1 161.22,44.1 162.83,42.48 165.82,42.48 168.78,39.51 174.83,39.51 176.38,37.96 177.56,37.96 178.27,37.25 178.27,36.9 v1(178.93,36.24)
  BOTTOM w0.076: UCPU1.AK18 141.69,56.01 v1(141.33,55.65)
DDR_B_D59: length 47.8
  TOP w0.102: UD4.C8 178.55,35.05 178.95,35.45 v1(178.93,35.45)
  IN4 w0.076: 141.72,53.6 142.74,52.59 143.3,52.59 147.47,48.41
  IN4 w0.086: v1(141.34,55.04) 141.72,54.65 141.72,53.6
  IN4 w0.119: v1(178.93,35.45) 177.92,36.47 177.92,37.07 177.41,37.58 176.32,37.58 174.7,39.2 168.66,39.2 165.69,42.17 162.7,42.17 161.09,43.79 156.83,43.79 152.2,48.41 147.47,48.41
  BOTTOM w0.076: v1(141.34,55.04) 141.67,55.36 UCPU1.AL18
DDR_B_D60: length 48.7
  TOP w0.102: UD4.C3 174.51,35.05 174.12,35.44 174.12,35.45 v1(174.13,35.45)
  IN4 w0.076: v1(140.41,55.75) 140.12,56.04 139.28,56.04 139.08,55.84 139.08,52.31 139.41,51.97 139.8,51.97 140.77,51 141.23,51 142.15,50.08 142.87,50.08 143.37,49.58 143.5,49.44 143.5,49.18 147.65,45.04
  IN4 w0.119: v1(174.13,35.45) 173.73,35.05 173.07,35.05 172.59,35.53 168.61,35.53 164.6,39.54 161.61,39.54 160,41.16 152.56,41.16 148.68,45.04 147.65,45.04
  BOTTOM w0.076: UCPU1.AK20 140.67,56.01 v1(140.41,55.75)
DDR_B_D61: length 44.1
  TOP w0.102: v1(173.36,35.45) 173.74,35.07 UD4.C2
  IN4 w0.076: v1(140.41,54.39) 140.01,53.98 140.01,53.58 139.88,53.45 139.88,52.14 140.85,51.17 141.52,51.17 142.44,50.25 142.94,50.25 143.72,49.47 143.72,49.21 147.69,45.24
  IN4 w0.086: 147.95,45.24 147.69,45.24
  IN4 w0.119: 147.95,45.24 148.91,45.24 152.69,41.47 160.13,41.47 161.74,39.85 164.73,39.85 168.7,35.87 172.94,35.87 v1(173.36,35.45)
  BOTTOM w0.076: v1(140.41,54.39) 140.74,54.71 UCPU1.AM20
DDR_B_D62: length 43.4
  TOP w0.102: UD4.A7 177.47,36.65 v1(177.23,36.89)
  IN4 w0.076: 148.22,47.13 143.67,51.68 142.41,51.68 141.66,52.43 v1(141.37,52.43)
  IN4 w0.119: 148.22,47.13 151.59,47.13 155.55,43.17 160.83,43.17 162.45,41.55 165.43,41.55 168.4,38.58 174.4,38.58 176.09,36.89 v1(177.23,36.89)
  BOTTOM w0.076: UCPU1.AR18 141.69,52.76 v1(141.37,52.43)
DDR_B_D63: length 46.7
  TOP w0.102: v1(178.12,34.65) 177.74,34.27 UD4.D7
  IN4 w0.076: v1(141.37,53.08) 141.96,52.49 141.96,52.38 142.48,51.85 143.77,51.85 147.46,48.16
  IN4 w0.119: 147.46,48.16 152.02,48.16 156.7,43.48 160.96,43.48 162.58,41.86 165.56,41.86 168.53,38.89 174.57,38.89 176.12,37.34 177.33,37.34 177.7,36.97 177.7,35.07 v1(178.12,34.65)
  BOTTOM w0.076: UCPU1.AP18 141.69,53.41 v1(141.37,53.08)
DDR_B_DQS0: length 22.8
  TOP w0.102: UD7.F3 134.04,32.65 v1(134.14,32.75)
  IN2 w0.089: v1(133.29,47.8) 133.5,48.02 133.95,48.02 134.24,47.73 134.24,43.02 134.23,43.01
  IN2 w0.152: v1(134.14,32.75) 134.4,32.49 134.74,32.49 135.38,33.13 135.38,36.95 134.23,38.09 134.23,43.01
  BOTTOM w0.076: UCPU1.AV30 133.5,51.12 133.44,51.05 133.27,51.05 133.11,50.9 133.04,50.73 133.04,50.52 133.1,50.38 133.1,50.37 133.11,50.36 133.11,50.23 133.1,50.22 133.06,50.14 133.04,50.09 133.04,49.87 133.06,49.82 133.06,49.81 133.08,49.78 133.1,49.72 133.1,49.72 133.11,49.71 133.11,49.53 132.87,49.29 132.87,48.81 132.73,48.68 132.73,48.67 132.72,48.65 132.72,48.2 132.88,48.04 133.04,48.04 v1(133.29,47.8)
DDR_B_DQS1: length 20.5
  TOP w0.102: v1(136.17,35.39) 136.5,35.05 136.78,35.05 UD7.C7
  IN4 w0.137: v1(136.17,35.39) 136.17,35.56 136.01,35.72 134.9,35.72 134.62,36 134.62,36.97 134.84,37.19 134.84,38 134.56,38.28 134.56,39.7 136.11,41.25 136.11,45.52 136.35,45.76 136.82,45.76 v1(136.99,45.93)
  BOTTOM w0.076: v1(136.99,45.93) 136.74,45.67 136.36,45.67 136.11,45.92 136.11,47.89 135.39,48.62 135.39,48.96 135.72,49.29 135.72,49.77 135.69,49.81 135.67,49.85 135.65,49.88 135.64,49.9 135.64,50.04 135.65,50.06 135.69,50.14 135.72,50.19 135.72,50.59 135.75,50.62 UCPU1.AW26
DDR_B_DQS2: length 44.5
  TOP w0.102: v1(162.46,32.75) 162.36,32.65 162.02,32.65 162.02,32.65 UD1.F3
  IN2 w0.089: v1(134.8,54.39) 134.57,54.15 134.39,54.15 134.23,53.99 134.23,51.95 136.55,49.63 138.96,49.63 139.18,49.41 141.15,49.41 142.2,48.37 142.58,48.37 147.98,42.96
  IN2 w0.152: v1(162.46,32.75) 162.46,32.54 162.65,32.35 162.92,32.35 163.29,32.72 163.29,33.94 162.83,34.39 162.83,37.06 162.45,37.44 153.51,37.44 148,42.95 147.99,42.95 147.98,42.96
  BOTTOM w0.076: UCPU1.AM28 135.13,54.71 v1(134.8,54.39)
DDR_B_DQS3: length 40.2
  TOP w0.102: v1(164.49,35.39) 164.82,35.05 UD1.C7
  IN4 w0.076: 147.53,43.32 147.53,43.37 147.28,43.62 144.24,46.66 144.24,46.89 142.62,48.51 141.91,48.51 141.62,48.81 141.62,49.13 140.94,49.8 139.5,49.8 138.34,50.96 137.1,50.96 136.14,51.92 136.14,53.8 136.14,53.99 136.34,54.19 136.52,54.19 v1(136.71,54.39)
  IN4 w0.137: v1(164.49,35.39) 164.32,35.56 164.06,35.56 163.5,36.12 163.5,37.03 163,37.54 160.78,37.54 159.17,39.16 151.69,39.16 147.53,43.32
  BOTTOM w0.076: UCPU1.AM25 137.03,54.71 v1(136.71,54.39)
DDR_B_DQS4: length 25.5
  TOP w0.102: v1(145.83,32.23) 146.05,32.23 146.19,32.37 UD3.F3
  IN2 w0.086: 140.08,43.02 140.08,43.09 140.08,43.09 140.08,43.33 139.87,43.54 139.87,47.32 139.74,47.45 139,47.45 v1(138.9,47.35)
  IN2 w0.089: 140.05,42.96 140.05,42.97 140.06,42.98 140.07,42.98 140.08,42.99 140.08,43.02
  IN2 w0.152: v1(145.83,32.23) 145.99,32.4 145.99,32.7 146.43,33.13 146.43,37.05 145.84,37.63 143.77,37.63 140.05,41.35 140.05,42.96
  BOTTOM w0.076: v1(138.9,47.35) 138.38,47.87 138.38,48.29 138.19,48.49 138.19,49.27 138.24,49.33 138.24,49.71 138.24,49.72 138.23,49.72 138.21,49.78 138.19,49.81 138.19,49.82 138.17,49.87 138.17,50.09 138.2,50.14 138.24,50.22 138.24,50.23 138.24,50.66 138.25,50.67 138.25,50.71 138.41,50.87 138.41,51.05 UCPU1.AV22
DDR_B_DQS5: length 21.6
  TOP w0.102: UD3.C7 149.24,35.05 v1(148.81,35.49)
  IN4 w0.137: v1(148.81,35.49) 148.53,35.77 147.58,35.77 146.98,36.36 146.98,37.17 141.66,42.49 141.66,44.67 141.9,44.91 142.11,44.91 v1(142.3,45.1)
  BOTTOM w0.076: UCPU1.AW18 140.89,50.62 140.85,50.59 140.85,50.19 140.83,50.14 140.79,50.06 140.78,50.04 140.78,49.9 140.78,49.88 140.8,49.85 140.82,49.81 140.85,49.77 140.85,49.44 140.61,49.19 140.61,48.94 141.49,48.05 141.49,45.05 141.69,44.85 142.14,44.85 142.3,45.02 v1(142.3,45.1)
DDR_B_DQS6: length 51.7
  TOP w0.102: UD4.F3 174.56,32.65 v1(175,32.22)
  IN2 w0.089: 151.4,46.74 151.39,46.75 151.34,46.75 151.32,46.78 151.27,46.78 151.27,46.78 148.63,46.78 143.92,51.49 141.28,51.49 140.74,52.02 140.24,52.02 140.05,52.21 140.05,53.9 139.86,54.09 139.76,54.09 v1(139.46,54.39)
  IN2 w0.152: 151.4,46.74 153.52,44.62 153.52,44.22 153.29,43.99 153.29,43.74 153.69,43.34 153.94,43.34 154.16,43.57 154.57,43.57 155.13,43.01 155.13,42.61 154.9,42.37 154.9,42.19 155.37,41.72 155.54,41.72 155.78,41.96 156.18,41.96 156.82,41.32 167.63,41.32 171.21,37.74 174.33,37.74 174.84,37.24 174.84,32.38 v1(175,32.22)
  BOTTOM w0.076: UCPU1.AM21 139.79,54.71 v1(139.46,54.39)
DDR_B_DQS7: length 47.5
  TOP w0.102: v1(177.25,35.39) 177.58,35.05 UD4.C7
  IN4 w0.076: 148.66,46.53 148.65,46.53 148.62,46.56 148.59,46.56 148.55,46.6 148.5,46.6 148.31,46.6 148.25,46.6 143.49,51.36 142.2,51.36 141.72,51.83 141.1,51.83 140.81,52.12 140.81,52.31 140.81,52.31 140.81,53.95 141.05,54.19 141.17,54.19 v1(141.37,54.39)
  IN4 w0.137: v1(177.25,35.39) 177.07,35.56 175.97,35.56 175.08,36.45 175.08,36.99 174.13,37.94 168.13,37.94 165.16,40.91 162.18,40.91 160.56,42.52 155.28,42.52 151.14,46.66 149.28,46.66 149.15,46.53 148.66,46.53
  BOTTOM w0.076: UCPU1.AM18 141.69,54.71 v1(141.37,54.39)
DDR_B_DQS#0: length 22.9
  TOP w0.102: UD7.G3 134.1,31.85 v1(134.17,31.92)
  IN2 w0.089: v1(133.29,48.45) 133.55,48.18 134.02,48.18 134.41,47.79 134.41,43.11 134.46,43.05 134.46,43.01
  IN2 w0.152: v1(134.17,31.92) 134.5,32.26 134.83,32.26 135.6,33.03 135.6,37.04 134.46,38.19 134.46,43.01
  BOTTOM w0.076: UCPU1.AW30 133.5,50.8 133.43,50.88 133.34,50.88 133.26,50.8 133.21,50.69 133.21,50.56 133.26,50.46 133.29,50.42 133.29,50.19 133.26,50.14 133.22,50.06 133.21,50.04 133.21,49.9 133.22,49.88 133.24,49.85 133.26,49.81 133.29,49.77 133.29,49.46 133.04,49.22 133.04,48.73 132.91,48.6 132.91,48.28 132.96,48.23 133.07,48.23 v1(133.29,48.45)
DDR_B_DQS#1: length 20.7
  TOP w0.102: v1(136.17,36.26) 136.58,35.85 UD7.B7
  IN4 w0.137: v1(136.99,45.3) 136.99,45.43 136.88,45.54 136.43,45.54 136.32,45.43 136.32,41.16 134.78,39.61 134.78,38.37 135.05,38.09 135.05,37.1 134.84,36.88 134.84,36.08 134.99,35.93 135.85,35.93 v1(136.17,36.26)
  BOTTOM w0.076: v1(136.99,45.3) 136.8,45.5 136.29,45.5 135.94,45.85 135.94,47.82 135.21,48.54 135.21,49.03 135.54,49.36 135.54,49.51 135.54,49.51 135.54,49.71 135.53,49.72 135.53,49.72 135.51,49.78 135.49,49.81 135.49,49.82 135.47,49.87 135.47,50.09 135.5,50.14 135.53,50.22 135.54,50.23 135.54,50.66 135.55,50.67 135.55,50.71 135.71,50.87 135.71,51.05 UCPU1.AV26
DDR_B_DQS#2: length 44.7
  TOP w0.102: UD1.G3 162.43,31.85 v1(162.46,31.89)
  IN2 w0.089: v1(134.84,53.74) 134.84,53.87 134.71,53.99 134.46,53.99 134.4,53.93 134.4,52.02 136.62,49.8 139.03,49.8 139.25,49.58 141.22,49.58 142.27,48.53 142.64,48.53 148.02,43.15 148.08,43.15 148.11,43.12 148.15,43.12 148.16,43.11
  IN2 w0.152: 148.16,43.11 153.61,37.67 162.54,37.67 163.06,37.15 163.06,34.49 163.52,34.03 163.52,32.63 163.01,32.12 162.7,32.12 v1(162.46,31.89)
  BOTTOM w0.076: UCPU1.AN28 135.2,53.8
  BOTTOM w0.089: 135.2,53.8 135.13,53.74 v1(134.84,53.74)
DDR_B_DQS#3: length 40.1
  TOP w0.102: UD1.B7 164.76,35.85 v1(164.49,36.12)
  IN4 w0.076: v1(136.71,53.74) 136.71,53.96 136.63,54.04 136.4,54.04 136.29,53.93 136.29,53.87 136.29,53.87 136.29,51.98 137.16,51.11 138.41,51.11 139.56,49.96 140.88,49.96 141,49.96 141.77,49.19 141.77,48.87 141.98,48.66 142.55,48.66 142.55,48.66 142.68,48.66 144.39,46.95 144.39,46.82 144.39,46.72 147.62,43.5 147.65,43.5 147.69,43.46
  IN4 w0.137: 147.69,43.46 151.78,39.37 159.26,39.37 160.87,37.76 163.08,37.76 163.72,37.12 163.72,36.21 164.15,35.78 164.47,35.78 164.58,35.89 164.58,36.03 v1(164.49,36.12)
  BOTTOM w0.089: v1(136.71,53.74) 136.71,53.83 136.94,54.06 UCPU1.AN25
DDR_B_DQS#4: length 25.5
  TOP w0.102: UD3.G3 146.29,31.85 v1(146.65,32.22)
  IN2 w0.086: 140.24,43.02 140.24,43.04 140.24,43.04 140.24,43.09 140.24,43.15 140.24,43.15 140.24,43.4 140.03,43.6 140.03,47.39 139.81,47.61 139.15,47.61 138.9,47.86 v1(138.9,47.91)
  IN2 w0.089: 140.24,43.02 140.24,42.99 140.25,42.98 140.26,42.98 140.27,42.97 140.27,42.96
  IN2 w0.152: v1(146.65,32.22) 146.65,32.03 146.54,31.92 146.31,31.92 146.22,32.01 146.22,32.6 146.65,33.03 146.65,37.14 145.93,37.86 143.86,37.86 140.27,41.44 140.27,42.96
  BOTTOM w0.076: UCPU1.AW22 138.46,50.62 138.42,50.59 138.42,50.19 138.4,50.14 138.36,50.06 138.35,50.04 138.35,49.9 138.35,49.88 138.37,49.85 138.39,49.81 138.42,49.77 138.42,49.61 138.42,49.61 138.42,49.25 138.36,49.2 138.36,48.56 138.55,48.37 138.55,48.08 138.73,47.91 v1(138.9,47.91)
DDR_B_DQS#5: length 21.8
  TOP w0.102: v1(148.81,36.24) 148.81,36.11 149.06,35.85 UD3.B7
  IN4 w0.137: v1(148.81,36.24) 148.55,35.98 147.66,35.98 147.2,36.45 147.2,37.26 141.88,42.58 141.88,44.58 141.99,44.7 142.12,44.7 v1(142.3,44.52)
  BOTTOM w0.076: UCPU1.AV18 140.84,51.05 140.84,50.87 140.68,50.71 140.68,50.67 140.67,50.66 140.67,50.23 140.67,50.22 140.63,50.14 140.6,50.09 140.6,49.87 140.62,49.82 140.62,49.81 140.64,49.78 140.66,49.72 140.67,49.72 140.67,49.71 140.67,49.51 140.43,49.27 140.43,48.87 141.32,47.98 141.32,44.97 141.61,44.68 142.14,44.68 v1(142.3,44.52)
DDR_B_DQS#6: length 51.7
  TOP w0.102: UD4.G3 174.54,31.86 v1(174.17,32.23)
  IN2 w0.089: v1(139.47,53.74) 139.66,53.93 139.79,53.93 139.88,53.83 139.88,52.14 140.17,51.86 140.68,51.86 141.21,51.33 143.85,51.33 148.56,46.62 151.2,46.62 151.24,46.58
  IN2 w0.152: v1(174.17,32.23) 174.29,32.11 174.49,32.11 174.59,32.21 174.59,32.27 174.61,32.28 174.61,37.14 174.24,37.51 171.11,37.51 167.53,41.1 156.72,41.1 156.09,41.73 155.87,41.73 155.64,41.5 155.27,41.5 154.67,42.1 154.67,42.46 154.9,42.7 154.9,42.91 154.47,43.35 154.26,43.35 154.03,43.12 153.6,43.12 153.07,43.65 153.07,44.09 153.29,44.31 153.29,44.53 151.24,46.58
  BOTTOM w0.089: UCPU1.AN21 139.8,54.06 v1(139.47,53.74)
DDR_B_DQS#7: length 47.4
  TOP w0.102: UD4.B7 177.53,35.85 v1(177.25,36.14)
  IN4 w0.076: v1(141.37,53.74) 141.37,53.95 141.27,54.04 141.11,54.04 140.96,53.89 140.96,52.25 140.96,52.19 141.16,51.98 141.79,51.98 142.26,51.51 143.56,51.51 148.31,46.75 148.5,46.75 148.61,46.75 148.62,46.74 148.66,46.74
  IN4 w0.137: v1(177.25,36.14) 177.25,35.86 177.16,35.77 176.06,35.77 175.29,36.54 175.29,37.08 174.22,38.15 168.22,38.15 165.25,41.12 162.27,41.12 160.65,42.73 155.37,42.73 151.23,46.88 149.19,46.88 149.06,46.74 148.66,46.74
  BOTTOM w0.076: v1(141.37,53.74) 141.69,54.06 UCPU1.AN18
DDR_B_MA0: length 120.7
  TOP w0.076: v1(157.54,27.04) 157.54,27.05 RD94.1
  TOP w0.102: v1(147.19,26.74) 146.87,27.05 146.19,27.05 UD3.N3 ; UD1.N3 162.11,26.84 162.16,26.84 v1(162.4,26.6) ; v1(175.01,26.72) 174.95,26.67 174.4,26.67 174.29,26.78 174.29,26.94 174.4,27.05 UD4.N3 ; UD7.N3 133.59,27.05 v1(133.99,26.65)
  IN1 w0.076: v1(133.99,26.65) 135.23,26.65 135.5,26.38 135.79,26.38 135.84,26.43 139.13,26.43 139.4,26.7 140.39,26.7 140.52,26.56 140.88,26.56 141.19,26.88 v4(141.35,26.88) 141.46,26.76 142.2,26.76 142.28,26.84 142.28,27.01 142.35,27.09 142.5,27.09 142.58,27.01 142.58,26.84 142.66,26.76 142.81,26.76 142.89,26.84 142.89,27.01 142.96,27.09 143.11,27.09 143.19,27.01 143.19,26.97 143.27,26.89 143.45,26.89 143.53,26.81 143.53,26.65 143.61,26.56 143.74,26.56 143.83,26.65 143.83,26.81 143.91,26.89 144.13,26.89 144.23,26.8 147.13,26.8 v1(147.19,26.74) ; v1(162.4,26.6) 163.56,26.6 163.82,26.34 164.74,26.34 164.81,26.28 167.68,26.28 167.89,26.48 169.3,26.48 v4(169.61,26.79) 169.61,26.94 169.7,27.04 170.61,27.04 170.64,27.01 170.64,26.8 170.72,26.72 170.84,26.72 170.92,26.8 170.92,27 170.97,27.04 171.16,27.04 171.53,26.67 172.12,26.67 172.2,26.6 173.99,26.6 174.05,26.66 174.05,26.83 174.12,26.91 174.24,26.91 174.32,26.82 174.32,26.68 174.39,26.62 174.54,26.62 174.6,26.68 174.6,26.86 174.66,26.91 174.88,26.91 175.01,26.78 v1(175.01,26.72) ; 127.66,45.78 127.27,46.17 127.27,51.25 126.55,51.96 126.55,53.14 v1(127.08,53.68)
  IN1 w0.145: 127.66,45.78 127.66,45.24 130.1,42.8 133.45,42.8 134.46,41.79 147.25,41.79 148.71,40.32 152.3,40.32 155.43,37.19 155.43,36.1 156.29,35.25 156.29,31.4 156.54,31.14 156.54,29.49 157.07,28.97 157.07,27.51 v1(157.54,27.04)
  IN4 w0.076: v4(141.35,26.88) 141.53,26.7 144.18,26.7 144.43,26.45 146.42,26.45 147.07,25.8 147.89,25.8 148.22,25.47 152.14,25.47 153.81,27.15 157.43,27.15 v1(157.54,27.04) 157.7,27.04 158.45,26.29 158.45,25.79 158.97,25.27 160.28,25.27 160.48,25.48 160.82,25.48 160.86,25.43 164.19,25.43 164.26,25.37 167.11,25.37 167.97,26.23 169.77,26.23 170.07,26.53 170.63,26.53 171.14,27.04 171.14,27.17 171.02,27.28 170.9,27.28 170.62,27 169.73,27 169.61,26.87 v4(169.61,26.79)
  BOTTOM w0.076: v1(127.08,53.68) 127.35,53.41 UCPU1.AP40
DDR_B_MA1: length 118
  TOP w0.076: RD91.1 156.87,25.12 v1(156.79,25.2)
  TOP w0.102: UD3.P7 149.39,26.24 v1(149.01,25.85) ; v1(164.44,25.75) 164.95,26.25 UD1.P7 ; v1(177.36,25.85) 177.74,26.24 UD4.P7 ; UD7.P7 136.78,26.25 136.63,26.25 v1(136.12,25.75)
  IN1 w0.076: v1(127.11,53.06) 126.72,52.68 126.72,52.04 127.44,51.32 127.44,46.47 128.17,45.74 ; v1(136.12,25.75) 136.51,25.75 137.18,25.08 141.55,25.08 141.95,24.68 142.23,24.68 v4(142.46,24.9) 144.13,24.9 144.69,25.46 145.15,25.46 145.78,26.09 145.78,26.11 145.94,26.27 146.6,26.27 147.1,25.76 148.92,25.76 v1(149.01,25.85) ; v1(177.36,25.85) 177.29,25.92 174.04,25.92 173.35,25.23 171.92,25.23 171.8,25.1 v4(170.63,25.1) 170.31,25.43 169.73,25.43 169.4,25.1 168.66,25.1 168.35,24.79 166.33,24.79 166.07,25.06 165.42,25.06 164.73,25.75 v1(164.44,25.75)
  IN1 w0.145: v1(156.79,25.2) 156.79,25.22 157.96,26.39 157.96,27.18 157.38,27.77 157.38,29.08 156.88,29.58 156.88,31.28 156.62,31.54 156.62,35.39 155.77,36.24 155.77,37.38 152.47,40.68 148.86,40.68 147.38,42.16 134.63,42.16 133.65,43.14 130.32,43.14 129.8,43.66 129.8,45.47 129.52,45.74 128.17,45.74
  IN4 w0.076: v4(170.63,25.1) 170.28,25.45 169.78,25.45 169.61,25.28 168.85,25.28 168.34,24.78 167.9,24.78 167.15,24.02 164.94,24.02 164.91,23.99 163.67,23.99 163.07,23.39 159.78,23.39 159.22,23.95 158.58,23.95 157.99,24.54 157.01,24.54 156.79,24.76 v1(156.79,25.2) 156.38,25.61 155.83,25.61 155.22,25.01 153.54,25.01 152.48,23.94 149.79,23.94 149.24,23.39 148.49,23.39 148.24,23.64 145.88,23.64 144.65,24.86 142.5,24.86 v4(142.46,24.9)
  BOTTOM w0.076: UCPU1.AR40 127.41,52.76 v1(127.11,53.06)
DDR_B_MA2: length 122.3
  TOP w0.076: v1(155.95,25.23) 155.62,24.91 RD49.1
  TOP w0.102: v1(162.32,25.84) 161.91,26.25 UD1.P3 ; UD4.P3 174.54,26.25 175,25.8 v1(175,25.2) ; UD3.P3 146.19,26.04 146.39,25.84 v1(146.51,25.84) ; UD7.P3 133.59,26.25 v1(134,25.84)
  IN1 w0.076: v1(175,25.2) 175.39,25.2 175.45,25.27 175.45,25.63 175.35,25.73 174.17,25.73 173.47,25.03 172.05,25.03 171.75,24.72 v4(169.45,24.72) 169.39,24.78 168.55,24.78 168.36,24.59 166.25,24.59 165.98,24.86 165.33,24.86 164.82,25.37 163.89,25.37 163.42,25.84 v1(162.32,25.84) ; v1(134,25.84) 135.1,25.84 135.57,25.37 136.4,25.37 136.94,24.84 140.62,24.84 v4(140.94,24.52) 141.37,24.52 141.44,24.6 141.44,24.61 141.52,24.69 141.67,24.69 141.75,24.61 141.75,24.6 141.82,24.52 142.7,24.52 142.92,24.74 144.2,24.74 144.76,25.3 145.22,25.3 145.38,25.46 147,25.46 147.06,25.52 147.06,25.59 146.81,25.84 v1(146.51,25.84) ; 127.09,45.84 127.09,51.17 126.17,52.1 v1(126.17,53.14)
  IN1 w0.145: 127.09,45.84 127.09,45.24 129.87,42.46 133.24,42.46 134.28,41.41 147.12,41.41 148.55,39.98 152.12,39.98 154.84,37.26 154.84,36.17 155.86,35.14 155.86,31.32 156.21,30.98 156.21,28.9 156.35,28.76 156.65,28.76 156.8,28.61 156.8,28.32 156.65,28.18 156.35,28.18 156.21,28.03 156.21,27.7 156.33,27.57 156.67,27.57 156.8,27.45 156.8,27.1 156.67,26.98 156.51,26.98 156.38,26.85 156.38,26.6 156.52,26.45 157.03,26.45 157.18,26.31 157.18,26.02 157.03,25.87 156.52,25.87 156.38,25.73 156.38,25.4 156.21,25.23 v1(155.95,25.23)
  IN4 w0.076: v4(169.45,24.72) 169.36,24.81 168.59,24.81 168.3,24.52 168.11,24.52 167.31,23.73 166.07,23.73 165.4,23.06 158.39,23.06 157.82,23.63 157.82,23.78 157.99,23.95 157.99,24.12 157.87,24.24 157.7,24.24 157.53,24.07 157.13,24.07 156.43,24.77 156.43,25.02 156.22,25.23 v1(155.95,25.23) 155.68,25.23 155.13,24.68 153.68,24.68 152.7,23.7 149.99,23.7 149.35,23.06 148.37,23.06 147.99,23.43 145.77,23.43 144.69,24.52 141.87,24.52 141.57,24.82 141.23,24.82 v4(140.94,24.52)
  BOTTOM w0.076: UCPU1.AP42 126.44,53.41 v1(126.17,53.14)
DDR_B_MA3: length 128.8
  TOP w0.076: v1(145.76,27.47) 145.39,27.1 UD3.N2 ; v1(158.02,28.15) 158.02,28.35 RD96.1
  TOP w0.102: v1(160.69,27.46) 161.1,27.05 UD1.N2 ; UD7.N2 132.78,27.05 v1(132.37,27.46) ; UD4.N2 173.74,27.12 v1(174.08,27.47)
  IN1 w0.076: v1(132.37,27.46) 132.71,27.8 133.33,27.8 133.53,27.6 135.75,27.6 136.03,27.32 136.38,27.32 136.81,26.89 138.92,26.89 139.2,27.17 139.72,27.17 v4(140.14,27.58) 140.56,28 140.56,28.17 140.63,28.25 140.77,28.25 140.84,28.17 140.84,28.08 140.92,28.01 141.07,28.01 141.15,28.08 141.15,28.17 141.22,28.25 141.38,28.25 141.45,28.17 141.45,27.97 141.53,27.89 141.68,27.89 141.76,27.97 141.76,28.17 141.83,28.25 142.23,28.25 142.4,28.07 142.99,28.07 143.17,28.25 144.3,28.25 144.54,28.01 145.94,28.01 146.19,27.75 146.19,27.37 146.12,27.29 145.93,27.29 v1(145.76,27.47) ; v1(160.69,27.46) 161.07,27.83 161.66,27.83 162.16,27.33 164.2,27.33 164.29,27.24 164.97,27.24 165.32,26.89 167.36,26.89 167.79,27.31 v4(168.22,27.31) 168.4,27.5 169.08,27.5 169.26,27.67 169.26,27.85 169.09,28.02 169.09,28.14 169.28,28.34 170.67,28.34 170.74,28.26 170.74,28.18 170.82,28.11 171.07,28.11 171.15,28.18 171.15,28.27 171.21,28.34 171.42,28.34 171.64,28.11 172.37,28.11 172.86,27.62 173.01,27.62 173.26,27.88 174.21,27.88 174.34,27.75 174.34,27.59 174.21,27.47 v1(174.08,27.47) ; 128.11,46.04 127.61,46.55 127.61,51.45 127.83,51.67 127.83,52.04 127.37,52.49 v1(127.08,52.49)
  IN1 w0.086: 128.22,46.04 128.11,46.04
  IN1 w0.145: v1(158.02,28.15) 157.71,28.45 157.71,29.22 157.21,29.72 157.21,31.42 156.96,31.68 156.96,35.53 156.11,36.38 156.11,37.61 152.68,41.04 149.05,41.04 147.55,42.54 141.29,42.54 141.14,42.68 141.14,43.11 141.01,43.25 140.72,43.25 140.56,43.09 140.56,42.68 140.42,42.54 140.13,42.54 139.99,42.68 139.99,43.07 139.84,43.22 139.55,43.22 139.41,43.07 139.41,42.68 139.26,42.54 134.82,42.54 133.85,43.51 130.62,43.51 130.26,43.88 130.26,45.59 129.81,46.04 128.22,46.04
  IN4 w0.076: v4(168.22,27.31) 167.76,27.31 167.51,27.06 167.51,26.72 167.43,26.64 167.06,26.64 166.96,26.75 166.96,26.77 166.85,26.87 166.65,26.87 166.55,26.77 166.55,26.75 166.45,26.64 166.24,26.64 166.14,26.75 166.14,26.77 166.04,26.87 165.84,26.87 165.74,26.77 165.74,26.75 165.64,26.64 165.43,26.64 165.33,26.75 165.33,26.77 165.23,26.87 165.03,26.87 164.92,26.77 164.92,26.75 164.82,26.64 164.61,26.64 164.07,27.19 163.59,27.19 163.49,27.09 163.49,26.2 163.39,26.1 163.19,26.1 163.09,26.2 163.09,27.09 162.98,27.19 162.09,27.19 161.76,26.86 160.89,26.86 160.79,26.76 160.79,26.32 160.68,26.21 160.47,26.21 160.37,26.32 160.37,26.9 160.26,27 160.12,27 160.01,26.9 160.01,26.32 159.96,26.27 159.52,26.27 159.47,26.32 159.47,26.48 159.57,26.58 159.58,26.58 159.68,26.68 159.68,27 159.45,27.24 158.75,27.24 158.65,27.34 158.65,27.48 158.75,27.59 159.55,27.59 159.67,27.71 159.67,27.87 159.55,27.99 159.03,27.99 158.7,28.32 158.19,28.32 v1(158.02,28.15) 152.99,28.15 152.53,27.69 151.99,27.69 151.53,28.15 149.64,28.15 149.08,27.59 147.22,27.59 146.7,27.07 144.9,27.07 144.61,27.36 144.61,27.51 144.09,28.03 140.59,28.03 v4(140.14,27.58)
  BOTTOM w0.076: v1(127.08,52.49) 126.81,52.76 UCPU1.AR42
DDR_B_MA4: length 125.6
  TOP w0.076: RD38.1 155.58,26.88 v1(155.58,26.75)
  TOP w0.102: UD1.P8 165.9,26.24 v1(166.29,25.85) ; UD3.P8 150.19,26.27 v1(149.81,26.65) ; UD4.P8 178.54,26.27 v1(178.16,26.65) ; UD7.P8 137.58,26.24 v1(137.97,25.85)
  IN1 w0.076: v1(178.16,26.65) 178.01,26.5 176.93,26.5 176.81,26.37 172.19,26.37 172.05,26.24 v4(171.8,26.24) 171.5,26.24 171.45,26.19 170.93,26.19 170.41,26.71 170.06,26.71 169.51,26.15 167.9,26.15 167.8,26.05 167.52,26.05 167.39,25.92 167.39,25.53 167.27,25.41 166.73,25.41 v1(166.29,25.85) ; v1(149.81,26.65) 149.66,26.5 147.98,26.5 147.6,26.12 147.22,26.12 146.69,26.65 144.26,26.65 143.66,26.05 v4(143.35,26.05) 143.35,26.28 143.1,26.53 141.22,26.53 141.09,26.41 140.46,26.41 140.34,26.53 139.45,26.53 139.2,26.28 137.61,26.28 137.51,26.18 137.51,25.96 137.62,25.85 v1(137.97,25.85)
  IN1 w0.145: v1(124.26,52.51) 124.26,51.87 124.45,51.68 124.69,51.68 125.05,52.03 125.34,52.03 125.49,51.88 125.49,48.39 125.35,48.25 124.85,48.25 124.71,48.1 124.71,47.86 124.85,47.72 125.35,47.72 125.49,47.57 125.49,47.35 125.35,47.2 124.85,47.2 124.71,47.06 124.71,46.86 124.85,46.71 125.35,46.71 125.49,46.57 125.49,45.89 127.35,44.03 127.35,43.87 129.93,41.29 130.12,41.29 130.22,41.39 130.22,41.67 130.34,41.79 130.66,41.79 130.77,41.67 130.77,40.72 130.89,40.61 131.24,40.61 131.35,40.72 131.35,41.69 131.45,41.79 131.83,41.79 131.93,41.68 131.93,40.7 132.03,40.61 132.41,40.61 132.51,40.71 132.51,41.65 132.65,41.79 132.89,41.79 133.14,41.54 133.14,40.88 133.35,40.67 146.81,40.67 148.18,39.3 151.75,39.3 154.09,36.95 154.09,35.92 155.19,34.82 155.19,31.05 155.54,30.7 155.54,26.8 v1(155.58,26.75)
  IN4 w0.076: v4(171.8,26.24) 171.3,26.24 170.96,25.9 167.93,25.9 167.2,25.17 163.13,25.17 162.58,24.62 160.58,24.62 160.25,24.94 158.87,24.94 157.74,26.07 157.28,26.07 156.6,26.75 v1(155.58,26.75) 153.83,26.75 153.74,26.66 153.74,26.01 153.64,25.91 152.82,25.91 152.5,25.59 152.5,25.19 151.97,24.66 148.66,24.66 148.56,24.76 148.56,25.17 148.45,25.27 148.25,25.27 148.15,25.17 148.15,24.37 148.03,24.25 147.85,24.25 147.73,24.37 147.73,25.5 147.61,25.63 147.36,25.63 147.16,25.42 146.15,25.42 146.03,25.54 146.03,26.09 145.9,26.22 144.68,26.22 144.51,26.05 144.3,26.05 144.2,26.15 144.2,26.39 144.1,26.5 143.92,26.5 143.79,26.37 143.79,26.14 143.7,26.05 v4(143.35,26.05)
  BOTTOM w0.076: v1(124.26,52.51) 124.51,52.76 UCPU1.AR45
DDR_B_MA5: length 126
  TOP w0.076: RD93.1 156.19,25.78 v1(155.99,25.99)
  TOP w0.102: UD3.P2 145.13,26.25 144.99,26.12 v1(144.99,25.84) ; v1(133.18,25.84) 132.78,26.24 UD7.P2 ; UD1.P2 161.1,26.24 v1(161.51,25.84) ; UD4.P2 173.74,26.25 173.45,26.25 173.34,26.14 v1(173.34,25.82)
  IN1 w0.076: v1(144.99,25.84) 144.85,25.84 144.32,25.31 142.41,25.31 142.36,25.36 142.36,25.83 142.29,25.91 142.14,25.91 142.06,25.83 142.06,25.56 141.99,25.5 141.82,25.5 141.76,25.56 141.76,25.93 141.68,26.01 141.53,26.01 141.45,25.93 141.45,25.36 141.37,25.28 141.22,25.28 141.15,25.36 141.15,25.63 141.07,25.71 140.92,25.71 140.84,25.63 140.84,25.36 140.76,25.28 140.59,25.28 v4(140.4,25.48) 140.16,25.24 137.24,25.24 136.35,26.13 135.42,26.13 135.34,26.22 133.57,26.22 v1(133.18,25.84) ; v1(124.26,53.16) 124.75,53.16 124.87,53.28 124.87,53.51 124.78,53.6 123.71,53.6 123.58,53.73 123.58,53.93 123.69,54.04 125.53,54.04 125.7,53.87 125.7,52.72 125.85,52.57 125.85,47.08 ; v1(173.34,25.82) 173.34,25.55 173.23,25.43 170.82,25.43 170.72,25.54 170.72,25.93 170.6,26.05 170.34,26.05 170.22,25.93 170.22,25.72 170.14,25.65 169.41,25.65 169.33,25.57 169.33,25.37 169.24,25.28 168.96,25.28 168.89,25.35 168.89,25.55 168.8,25.64 168.58,25.64 168.51,25.72 168.34,25.72 168.24,25.62 168.24,25.31 v4(168.3,25.24) 168.07,25.01 166.42,25.01 166.16,25.26 165.53,25.26 164.65,26.14 163.41,26.14 163.32,26.22 161.89,26.22 v1(161.51,25.84)
  IN1 w0.086: 125.85,47.08 126.04,46.89 126.67,46.89 126.89,46.67 126.89,44.86 128.32,43.43
  IN1 w0.145: v1(155.99,25.99) 156.11,26.12 156.11,27.18 155.87,27.42 155.87,30.84 155.52,31.18 155.52,34.98 154.46,36.04 154.46,37.11 151.93,39.64 148.36,39.64 146.96,41.04 134.16,41.04 133.08,42.12 129.62,42.12 128.32,43.43
  IN4 w0.076: v4(168.3,25.24) 168.18,25.37 167.98,25.37 167.8,25.19 167.18,24.57 167.18,24.35 167.08,24.25 166.86,24.25 166.76,24.35 166.76,24.66 166.66,24.76 166.46,24.76 166.35,24.66 166.35,24.33 166.25,24.23 166.03,24.23 165.93,24.33 165.93,24.57 165.81,24.69 165.64,24.69 165.52,24.57 165.52,24.33 165.42,24.23 165.23,24.23 165.13,24.33 165.13,24.61 165.03,24.72 164.88,24.72 164.77,24.61 164.77,24.3 164.67,24.2 164.11,24.2 164,24.31 164,24.55 163.88,24.66 163.72,24.66 163.61,24.55 163.61,24.29 163.52,24.2 163.24,24.2 162.64,23.59 160.05,23.59 159.36,24.28 158.68,24.28 157.43,25.53 157.07,25.53 156.6,25.99 v1(155.99,25.99) 155.99,25.99 155.34,25.34 153.41,25.34 152.21,24.14 149.7,24.14 149.21,23.66 148.55,23.66 148.37,23.84 146.05,23.84 144.83,25.07 142.78,25.07 142.36,25.49 141.84,25.49 141.63,25.28 140.59,25.28 v4(140.4,25.48)
  BOTTOM w0.076: UCPU1.AP45 124.51,53.41 v1(124.26,53.16)
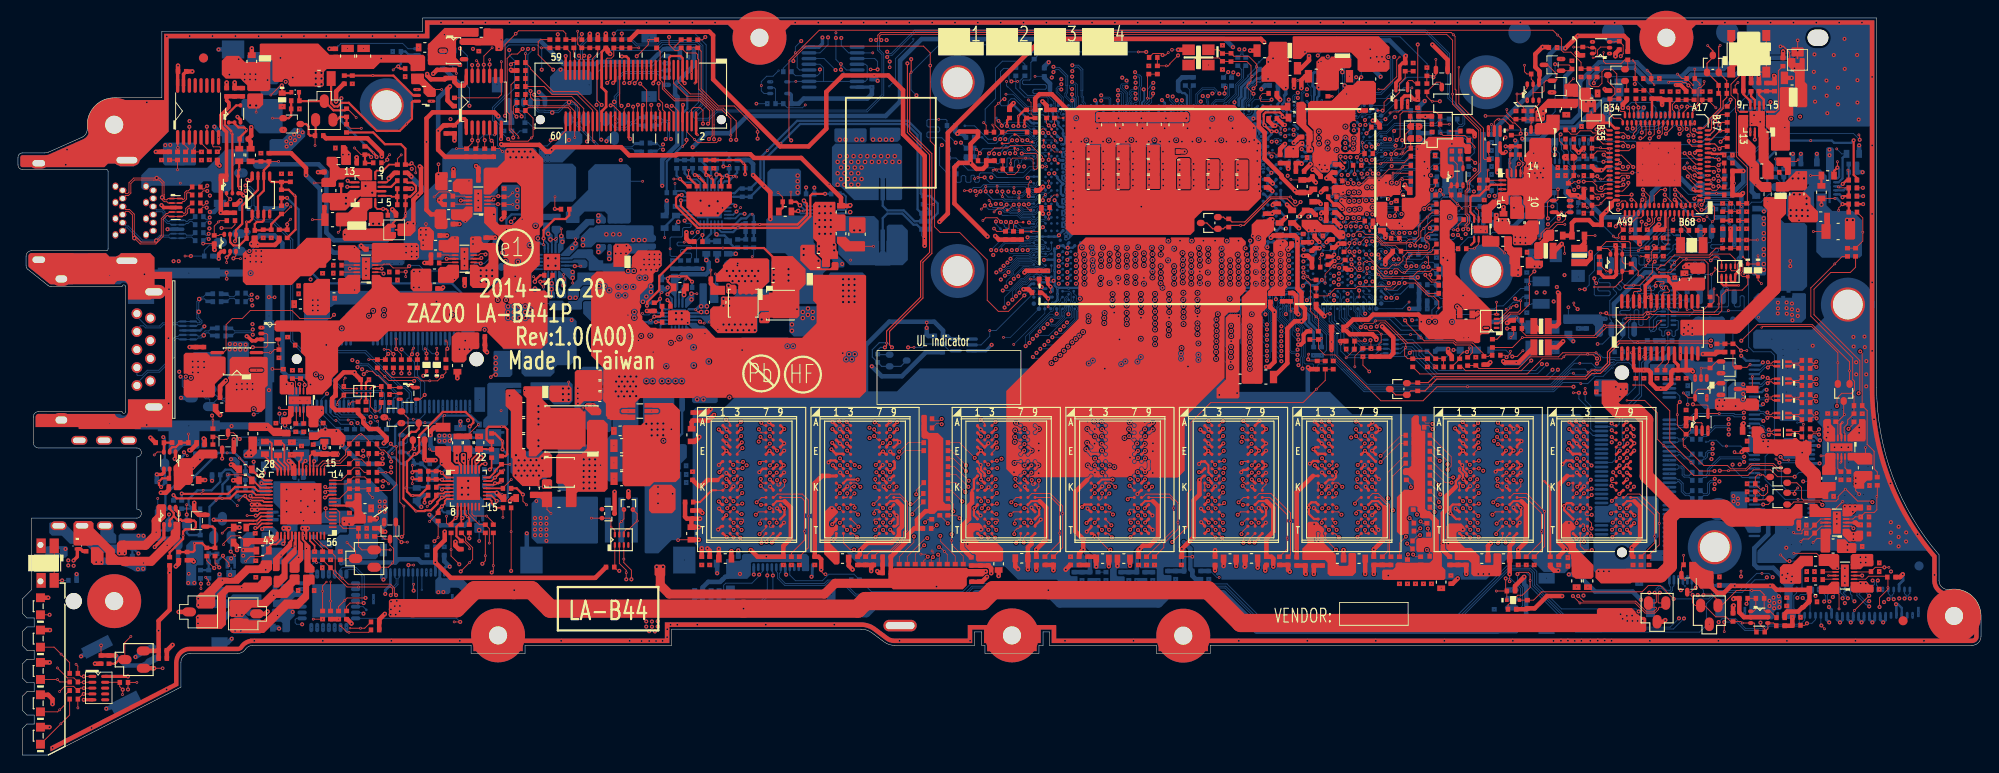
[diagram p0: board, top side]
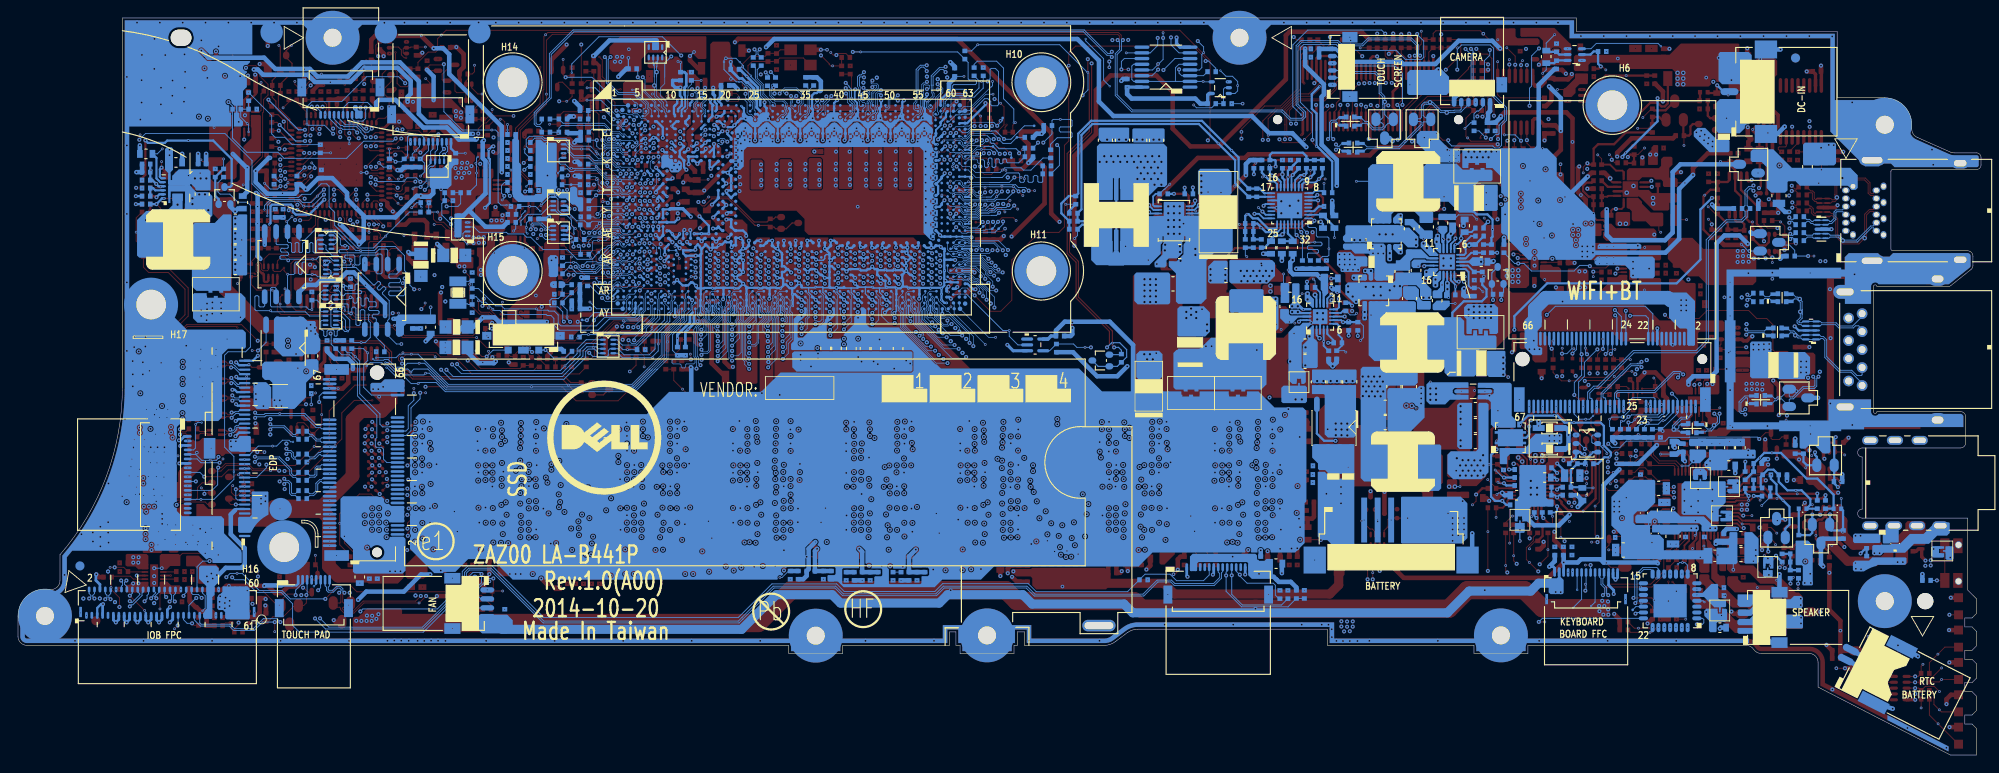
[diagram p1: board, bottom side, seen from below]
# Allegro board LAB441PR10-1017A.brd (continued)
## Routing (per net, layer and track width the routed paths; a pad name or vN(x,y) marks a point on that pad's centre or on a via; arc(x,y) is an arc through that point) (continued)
DDR_B_MA6: length 131.9
  TOP w0.076: v1(154.76,26.35) 154.8,26.35 155.24,25.92 RD73.1
  TOP w0.102: UD1.R8 165.89,25.45 v1(165.49,25.85) ; v1(178.14,25.87) 178.15,25.87 178.15,25.88 178.54,25.49 178.54,25.48 UD4.R8 ; UD7.R8 137.58,25.45 137.58,25.65 137.38,25.85 v1(137.17,25.85) ; v1(149.79,25.87) 149.8,25.87 149.8,25.88 150.19,25.49 150.19,25.48 UD3.R8
  IN1 w0.076: v1(137.17,25.85) 137.54,25.48 138.92,25.48 139.32,25.88 139.44,25.88 139.51,25.96 139.51,26.23 139.59,26.3 139.74,26.3 139.82,26.23 139.82,26.04 139.89,25.96 140.05,25.96 140.12,26.04 140.12,26.23 140.2,26.3 140.35,26.3 140.43,26.23 140.43,25.96 140.5,25.88 140.9,25.88 141.2,26.18 142.31,26.18 142.82,25.67 v4(142.94,25.67) 143.59,25.67 144.38,26.46 146.63,26.46 147.16,25.92 147.8,25.92 148.18,26.3 149.37,26.3 v1(149.79,25.87) ; v1(178.14,25.87) 177.72,26.3 177.02,26.3 176.92,26.2 172.33,26.2 171.95,25.82 v4(171.42,25.82) 171.09,25.82 170.53,26.38 170.2,26.38 169.64,25.82 168.72,25.82 168.62,25.92 168.07,25.92 167.35,25.21 166.5,25.21 166.24,25.47 165.62,25.47 165.49,25.59 v1(165.49,25.85) ; v1(123.3,50.01) 123.3,49.65 123.38,49.56 123.59,49.56 123.72,49.68 123.89,49.68 124.01,49.56 124.01,45.82
  IN1 w0.086: 124.01,45.82 124.42,45.42 125,45.42 125.75,44.67 125.75,44.16 126.13,43.78
  IN1 w0.145: 126.13,43.78 126.13,43.5 126.3,43.33 126.3,43.12 125.93,42.76 125.93,42.58 126.16,42.35 126.34,42.35 126.71,42.71 126.92,42.71 127.12,42.51 127.12,42.3 126.65,41.83 126.65,41.62 126.85,41.42 127.06,41.42 127.53,41.89 127.73,41.89 127.94,41.69 127.94,41.48 127.2,40.74 127.2,40.56 127.43,40.33 127.61,40.33 128.35,41.07 128.55,41.07 128.76,40.87 128.76,40.66 127.45,39.36 127.45,39.18 127.68,38.95 127.86,38.95 129.17,40.25 129.37,40.25 129.58,40.05 129.58,39.84 129.1,39.37 129.1,39.16 129.31,38.96 129.51,38.96 129.99,39.43 130.19,39.43 130.68,38.95 147,38.95 147.66,38.28 151.34,38.28 153.08,36.54 153.08,36.23 152.8,35.94 152.8,35.68 154.18,34.29 154.18,29.11 154.92,28.37 154.92,27.88 154.7,27.65 154.7,27.22 154.92,26.99 154.92,26.52 v1(154.76,26.35)
  IN4 w0.076: v4(142.94,25.67) 142.84,25.77 142.69,25.77 142.58,25.66 142.58,25.51 142.79,25.3 145,25.3 145.57,25.87 145.71,25.87 145.82,25.76 145.82,25.61 145.31,25.1 145.31,24.92 145.56,24.66 146.04,24.66 146.14,24.56 146.14,24.16 146.24,24.06 146.42,24.06 146.52,24.16 146.52,24.56 146.63,24.66 146.93,24.66 147.03,24.77 147.03,25.01 147.12,25.1 147.29,25.1 147.36,25.02 147.36,24.51 147.29,24.44 147.29,24.14 147.39,24.04 148.47,24.04 148.65,23.86 149.13,23.86 149.62,24.35 151.95,24.35 153.27,25.67 154.14,25.67 154.23,25.76 154.23,25.9 154.14,26 154.01,26 153.9,26.1 153.9,26.25 154.01,26.35 v1(154.76,26.35) 154.78,26.37 156.63,26.37 157.19,25.81 157.57,25.81 158.77,24.61 160.15,24.61 160.23,24.54 160.23,23.88 160.31,23.8 162.55,23.8 163.71,24.96 167.28,24.96 167.95,25.63 171.23,25.63 v4(171.42,25.82)
  BOTTOM w0.076: v1(123.3,50.01) 123.42,50.01 UCPU1.AW46
DDR_B_MA7: length 129.7
  TOP w0.076: RD48.1 153.64,23.58 v1(154.35,24.3)
  TOP w0.102: UD1.R2 161.11,25.45 v1(161.51,25.05) ; v1(174.14,25.05) 174.22,25.12 174.22,25.63 174.13,25.71 173.99,25.71 UD4.R2 ; UD3.R2 145.39,25.45 v1(145.8,25.05) ; v1(133.19,25.05) 132.79,25.45 UD7.R2
  IN1 w0.076: v1(123.31,48.48) 123.67,48.12 123.67,47.58 123.47,47.39 123.47,45.77 123.67,45.58 ; v1(161.51,25.05) 161.9,25.44 163.3,25.44 163.57,25.17 164.73,25.17 165.24,24.65 165.89,24.65 166.16,24.39 167.59,24.39 167.88,24.1 v4(168.24,24.1) 168.36,23.98 168.88,23.98 169.03,24.13 169.38,24.13 169.79,24.55 170.24,24.55 170.3,24.48 170.3,24.33 170.36,24.27 170.64,24.27 170.71,24.34 170.71,24.48 170.78,24.55 171.04,24.55 171.12,24.47 171.12,24.34 171.19,24.27 171.45,24.27 171.52,24.34 171.52,24.47 171.6,24.55 171.86,24.55 172.14,24.82 173.92,24.82 v1(174.14,25.05) ; v1(133.19,25.05) 133.56,25.43 134.99,25.43 135.25,25.17 136.31,25.17 136.85,24.63 138.92,24.63 139.41,24.14 v4(139.54,24.14) 140.49,24.14 140.51,24.12 141.16,24.12 141.24,24.2 141.24,24.24 141.31,24.32 142.72,24.32 142.99,24.59 144.26,24.59 144.82,25.15 145.7,25.15 v1(145.8,25.05)
  IN1 w0.145: v1(154.35,24.3) 153.8,24.85 153.8,26.42 154.13,26.75 154.13,28.2 153.51,28.81 153.51,33.98 151.87,35.63 151.87,36.45 151.67,36.65 151.15,36.65 151.07,36.73 151.07,37.33 150.91,37.49 150.26,37.49 150.16,37.38 150.15,37.38 150.15,36.42 150.03,36.3 150.03,36.3 150.02,36.29 149.69,36.29 149.56,36.41 149.56,37.39 149.34,37.61 148.54,37.61 148.39,37.45 148.39,36.98 147.94,36.53 147.76,36.53 147.54,36.76 147.54,36.9 147.81,37.17 147.81,37.37 147.7,37.49 147.51,37.49 146.76,38.24 127.4,38.24 125.26,40.38 125.26,41.14 125.12,41.29 124.36,41.29 124.21,41.43 124.21,41.72 124.36,41.87 125.12,41.87 125.26,42.01 125.26,42.3 125.12,42.45 124.2,42.45 123.91,42.15 123.72,42.15 123.52,42.35 123.52,42.66 123.89,43.03 125.12,43.03 125.26,43.17 125.26,44.52 124.94,44.85 124.74,44.85 124.12,44.22 123.9,44.22 123.72,44.4 123.72,44.58 124.08,44.95 124.08,45.16 123.67,45.58
  IN4 w0.076: v4(139.54,24.14) 143.97,24.14 144.08,24.03 144.08,23.65 144.18,23.55 144.59,23.55 144.83,23.8 145.02,23.8 145.59,23.23 147.54,23.23 148.04,22.73 149.49,22.73 150.13,23.37 152.84,23.37 153.77,24.3 v1(154.35,24.3) 155.22,24.3 155.77,24.85 156.14,24.85 158.25,22.73 165.92,22.73 166.07,22.87 166.07,23.31 166.2,23.43 167.7,23.43 168.24,23.97 v4(168.24,24.1)
  BOTTOM w0.076: UCPU1.AY46 123.71,48.88 v1(123.31,48.48)
DDR_B_MA8: length 134.7
  TOP w0.076: RD84.1 155.4,22.06 v1(155.16,22.3)
  TOP w0.102: UD4.T8 178.53,24.65 v1(178.15,25.04) ; UD3.T8 149.86,24.65 149.8,24.72 v1(149.8,25.04) ; UD7.T8 136.95,24.02 v1(136.95,23.67) ; v1(165.45,23.64) 165.45,24.2 UD1.T8
  IN1 w0.076: 123.84,45.75 123.84,48.66 v1(123.3,49.2) ; v1(136.95,23.67) 136.95,23.53 137.92,22.56 138.27,22.56 138.35,22.64 138.35,23.42 138.42,23.5 138.58,23.5 138.65,23.42 138.65,22.35 138.73,22.28 138.88,22.28 138.96,22.35 138.96,22.86 139.03,22.94 139.19,22.94 139.26,22.86 139.26,22.37 139.34,22.29 139.49,22.29 139.57,22.37 139.57,22.7 139.64,22.77 139.8,22.77 139.87,22.7 139.87,22.4 139.95,22.33 140.1,22.33 140.18,22.4 140.18,22.65 140.25,22.72 140.4,22.72 140.48,22.65 140.48,22.64 140.56,22.56 v4(141.62,22.56) 141.9,22.28 144.58,22.28 146.06,23.76 147.09,23.76 147.95,24.61 149.02,24.61 149.45,25.04 v1(149.8,25.04) ; v1(178.15,25.04) 178.57,24.62 178.57,24.35 178.38,24.16 178.12,24.16 177.59,24.69 177.13,24.69 176,23.56 174.58,23.56 174.2,23.19 173.93,23.19 173.17,22.43 171.89,22.43 v4(171.35,22.97) 170.85,22.97 170.32,22.44 166.21,22.44 166.11,22.54 166.11,23.09 166.01,23.19 165.8,23.19 165.7,23.09 165.7,22.54 165.6,22.44 165.34,22.44 165.13,22.65 165.13,23.33 v1(165.45,23.64)
  IN1 w0.086: 125.6,43.5 125.58,43.52 125.58,44.59 124.93,45.24 124.34,45.24 123.84,45.75
  IN1 w0.145: v1(155.16,22.3) 155.16,23.52 154.79,23.89 154.79,24.51 155.05,24.77 155.05,25.38 154.96,25.47 154.68,25.47 154.48,25.26 154.28,25.26 154.18,25.36 154.18,26.38 154.47,26.67 154.47,28.35 153.85,28.97 153.85,34.14 152.25,35.74 152.25,36.89 151.2,37.95 147.52,37.95 146.86,38.61 127.5,38.61 126.89,39.22 126.89,39.43 127.26,39.8 127.26,40 127.06,40.21 126.85,40.21 126.48,39.84 126.28,39.84 126.07,40.04 126.07,40.28 126.64,40.84 126.64,41.16 126.45,41.34 126.25,41.34 126.02,41.11 125.81,41.11 125.61,41.31 125.61,41.52 125.84,41.75 125.84,41.95 125.6,42.19 125.6,43.5
  IN4 w0.076: v4(141.62,22.56) 142.05,22.13 142.49,22.13 142.63,22.26 142.63,22.39 142.75,22.52 142.96,22.52 143.08,22.39 143.08,22.26 143.21,22.13 143.53,22.13 144.29,21.38 152.93,21.38 153.06,21.51 153.06,21.77 153.17,21.87 153.17,21.87 153.32,21.87 153.32,21.87 153.42,21.77 153.42,21.44 153.48,21.38 153.73,21.38 153.85,21.5 153.85,22.51 154.21,22.86 155.21,22.86 155.31,22.76 155.31,22.46 v1(155.16,22.3) 156.05,21.41 167.89,21.41 168.92,22.44 170.33,22.44 170.87,22.97 v4(171.35,22.97)
  BOTTOM w0.076: UCPU1.AY47 122.88,49.62 v1(123.3,49.2)
DDR_B_MA9: length 132.8
  TOP w0.076: v1(155.92,24.46) 155.72,24.46 RD57.1
  TOP w0.102: v1(146.65,25.05) 146.24,25.45 146.24,25.45 UD3.R3 ; v1(134.07,25.04) 133.65,25.45 UD7.R3 ; UD4.R3 174.54,25.11 174.96,24.7 v1(174.96,24.39) ; UD1.R3 161.98,25.45 v1(162.39,25.04)
  IN1 w0.076: 124.18,45.89 124.18,49.7 123.73,50.16 123.73,50.88 v1(123.31,51.3) ; v1(174.96,24.39) 175.23,24.39 175.38,24.54 175.38,24.72 175.26,24.83 174.61,24.83 174.4,24.62 173.11,24.62 172.98,24.49 172.98,24.27 172.86,24.14 172.7,24.14 172.58,24.27 172.58,24.49 172.45,24.62 172.24,24.62 172.11,24.49 172.11,24.19 171.99,24.06 170.26,24.06 170.12,23.93 v4(169.7,23.93) 169.17,23.93 168.95,23.71 167.72,23.71 167.38,24.06 166.2,24.06 165.81,24.45 165.16,24.45 164.64,24.96 163.48,24.96 163.4,25.04 v1(162.39,25.04) ; v1(134.07,25.04) 134.43,25.04 134.51,24.97 134.51,24.7 134.58,24.63 134.73,24.63 134.81,24.7 134.81,24.88 134.89,24.96 135.28,24.96 135.36,24.89 135.36,24.65 135.44,24.58 135.59,24.58 135.66,24.65 135.66,24.89 135.74,24.96 136.23,24.96 136.76,24.43 138.71,24.43 139.38,23.76 v4(139.98,23.76) 141.17,23.76 141.57,24.16 142.79,24.16 143.01,24.37 145.64,24.37 146.18,24.91 146.18,25.21 146.27,25.31 146.39,25.31 v1(146.65,25.05)
  IN1 w0.086: 124.18,45.89 124.47,45.61 125.08,45.61 125.92,44.78 125.92,44.37 126.36,43.93
  IN1 w0.145: 126.36,43.93 126.36,43.79 130.87,39.28 147.14,39.28 147.8,38.62 151.48,38.62 153.42,36.67 153.42,35.59 154.52,34.49 154.52,29.25 155.14,28.63 155.14,26.66 155.2,26.61 155.2,26.24 155.06,26.1 155.06,25.76 155.38,25.44 155.38,23.75 155.62,23.51 155.62,21.55 155.74,21.43 157.81,21.43 157.94,21.55 157.94,21.86 157.81,21.99 156.25,21.99 156.16,22.07 156.16,24.22 v1(155.92,24.46)
  IN4 w0.076: v4(139.98,23.76) 140.04,23.81 143.59,23.81 144.18,23.22 145.13,23.22 145.45,22.9 145.97,22.9 146.47,22.4 151.12,22.4 151.2,22.48 151.2,22.93 151.31,23.04 152.98,23.04 153.4,23.46 153.92,23.46 154.37,23.92 155.12,23.92 155.67,24.46 v1(155.92,24.46) 155.99,24.46 156.11,24.33 156.11,23.94 156.19,23.86 156.86,23.86 158.33,22.4 167.09,22.4 168.56,23.86 168.94,23.86 169.4,24.32 170.22,24.32 170.34,24.21 170.34,24.05 170.22,23.93 v4(169.7,23.93)
  BOTTOM w0.076: v1(123.31,51.3) 123.46,51.3 UCPU1.AU46
DDR_B_MA10: length 137
  TOP w0.076: v1(157.95,30.03) 157.95,30.19 RD100.1
  TOP w0.102: v1(135.74,28.11) 136.28,28.65 136.78,28.65 UD7.L7 ; UD4.L7 177.64,28.65 v1(177.26,28.27) ; v1(148.69,27.97) 148.69,28.07 149.27,28.65 149.39,28.65 UD3.L7 ; UD1.L7 165.1,28.65 164.6,28.65 v1(164.07,28.11)
  IN1 w0.076: 129.95,52.01 129.95,56.41 129.77,56.59 129.16,56.59 128.99,56.41 128.99,55.58 129.09,55.47 129.37,55.47 129.51,55.61 v1(129.51,55.84) ; v1(135.74,28.11) 135.89,28.26 137,28.26 137.08,28.34 139.04,28.34 139.45,28.74 139.82,28.74 139.9,28.82 140.18,28.82 140.46,29.1 141.94,29.1 142.08,29.24 v4(142.08,29.6) 143.61,29.6 144.04,29.17 144.24,29.17 144.8,28.61 148.05,28.61 v1(148.69,27.97) ; v1(164.07,28.11) 164.29,28.34 168.14,28.34 168.73,28.92 168.73,29.03 168.61,29.14 168.61,29.25 168.72,29.36 168.83,29.36 168.94,29.24 169.05,29.24 169.42,29.62 169.68,29.62 169.77,29.71 169.77,29.86 169.85,29.95 170.12,29.95 170.2,29.87 170.2,29.69 v4(170.27,29.62) 170.6,29.95 171.36,29.95 171.99,29.31 172.33,29.31 173.08,28.56 176.97,28.56 v1(177.26,28.27)
  IN1 w0.086: 129.95,52.01 130.9,51.06 131.31,51.06
  IN1 w0.145: 131.31,51.06 131.91,50.46 133.93,50.46 134.56,49.83 135.66,49.83 135.81,49.97 135.81,50.29 135.95,50.43 136.24,50.43 136.39,50.29 136.39,49.97 136.53,49.83 136.82,49.83 136.97,49.97 136.97,50.29 137.11,50.43 137.4,50.43 137.55,50.29 137.55,49.97 137.69,49.83 137.98,49.83 138.13,49.97 138.13,50.29 138.27,50.43 138.56,50.43 138.71,50.29 138.71,49.97 138.85,49.83 139.6,49.83 139.74,49.68 139.74,49.37 139.89,49.23 140.18,49.23 140.32,49.37 140.32,49.68 140.47,49.83 141.38,49.83 141.58,49.62 141.58,48.74 141.77,48.55 143.09,48.55 145.6,46.05 146.36,46.05 146.46,45.95 146.46,45.18 146.81,44.84 146.97,44.84 147.06,44.92 147.06,45.93 147.18,46.05 147.38,46.05 147.5,45.92 147.5,44.96 147.63,44.84 148.2,44.84 148.33,44.96 148.33,45.92 148.45,46.05 148.67,46.05 148.8,45.92 148.8,44.96 148.93,44.84 149.33,44.84 149.45,44.95 149.45,45.19 149.56,45.3 149.91,45.3 150.03,45.18 150.03,44.93 150.13,44.84 150.51,44.84 150.61,44.93 150.61,45.18 150.72,45.3 151.04,45.3 151.19,45.15 151.19,44.93 151.28,44.84 151.39,44.84 154.13,42.09 154.27,42.09 154.63,42.45 154.91,42.45 155.08,42.28 155.08,42.08 154.66,41.66 154.66,41.5 154.92,41.25 155.07,41.25 155.52,41.7 155.66,41.7 155.9,41.46 155.9,41.26 155.47,40.82 155.47,40.7 155.74,40.43 155.89,40.43 156.33,40.87 156.49,40.87 156.74,40.62 156.74,40.46 156.3,40.02 156.3,39.86 156.55,39.61 156.71,39.61 157.16,40.06 157.3,40.06 157.56,39.8 157.56,39.64 157.13,39.21 157.13,39.04 157.35,38.81 157.55,38.81 157.97,39.23 158.13,39.23 158.33,39.03 158.33,38.77 157.99,38.43 157.99,38.23 158.31,37.91 158.31,37.38 158.45,37.24 158.45,36.72 158.3,36.56 158.3,33.71 157.7,33.11 157.7,32.31 157.87,32.15 157.87,30.12 v1(157.95,30.03)
  IN4 w0.076: v4(170.27,29.62) 170.41,29.48 170.41,29.27 170.26,29.12 169.93,29.12 169.83,29.22 169.83,29.76 169.73,29.86 169.54,29.86 169.44,29.76 169.44,29.22 169.33,29.12 168.93,29.12 168.15,28.34 165.61,28.34 165.49,28.47 165.49,28.82 165.36,28.94 165.16,28.94 165.06,28.84 165.06,28.56 164.94,28.44 164.77,28.44 164.65,28.56 164.65,28.84 164.55,28.94 164.01,28.94 163.62,28.56 162.02,28.56 161.49,29.08 160.25,29.08 160.05,29.29 159.35,29.29 159.17,29.47 159.17,29.82 158.86,30.14 158.06,30.14 v1(157.95,30.03) 157.81,30.18 154.59,30.18 154.12,29.71 152.03,29.71 151.28,28.96 147.3,28.96 146.87,28.53 144.77,28.53 143.51,29.79 142.54,29.79 142.35,29.6 v4(142.08,29.6)
  BOTTOM w0.076: UCPU1.AK36 129.91,55.9 129.57,55.9 v1(129.51,55.84)
DDR_B_MA11: length 133.6
  TOP w0.076: v1(154.49,23.53) 155.08,22.94 RD71.1
  TOP w0.102: UD7.R7 136.07,24.74 v1(136.07,24.58) ; v1(164.39,24.58) 164.39,24.74 UD1.R7 ; v1(148.94,25.07) 149.33,25.45 UD3.R7 ; UD4.R7 177.67,25.45 177.67,25.45 v1(177.28,25.07)
  IN1 w0.076: v1(136.07,24.58) 136.42,24.23 138.54,24.23 139.39,23.38 141.01,23.38 141.49,23.86 142.68,23.86 142.82,23.73 142.82,23.41 v4(142.84,23.38) 143,23.22 144.73,23.22 146.11,24.6 147.54,24.6 147.67,24.73 147.67,25.1 147.79,25.22 147.98,25.22 148.11,25.1 148.11,24.9 148.24,24.78 148.41,24.78 148.7,25.07 v1(148.94,25.07) ; v1(177.28,25.07) 177.22,25.07 175.98,23.83 174.64,23.83 174.34,24.13 173.93,24.13 173.5,23.7 170.65,23.7 v4(170.59,23.64) 170.54,23.69 169.98,23.69 169.75,23.46 168.8,23.46 168.72,23.38 168.72,23.27 168.65,23.19 168.49,23.19 168.42,23.27 168.42,23.38 168.34,23.46 168.19,23.46 168.11,23.38 168.11,23.28 168.04,23.2 167.88,23.2 167.81,23.28 167.81,23.38 167.73,23.46 167.51,23.46 167.24,23.73 166.24,23.73 165.72,24.25 164.72,24.25 v1(164.39,24.58) ; 123.07,44.68 123.85,43.9 123.85,43.46
  IN1 w0.086: v1(123.31,47.94) 123.07,47.7 123.07,44.68
  IN1 w0.145: 123.85,43.46 123.19,42.8 123.19,41.98 127.26,37.9 146.62,37.9 146.95,37.57 146.95,36.59 147.59,35.94 148.19,35.94 148.3,36.05 148.3,36.42 148.55,36.67 149.1,36.67 149.22,36.55 149.22,36.06 149.32,35.95 150.2,35.95 150.23,35.92 150.9,35.92 151.03,35.79 151.03,35.66 151.26,35.43 151.58,35.43 153.18,33.84 153.18,28.67 153.79,28.06 153.79,26.88 153.26,26.35 153.26,25.96 153.47,25.75 153.47,23.57 153.37,23.47 152.91,23.47 152.79,23.34 152.79,22.96 152.91,22.84 153.5,22.84 153.62,22.71 153.62,22.38 153.5,22.25 152.85,22.25 152.72,22.12 152.72,21.79 152.85,21.67 154.07,21.67 154.2,21.79 154.2,22.54 154.42,22.77 154.6,22.77 154.73,22.9 154.73,23.3 v1(154.49,23.53)
  IN4 w0.076: v4(170.59,23.64) 170.55,23.67 169.98,23.67 169.82,23.51 168.71,23.51 167.27,22.07 158.19,22.07 156.94,23.32 156.94,23.47 156.7,23.71 156.3,23.71 156.13,23.53 v1(154.49,23.53) 154.26,23.31 153.71,23.31 153.12,22.71 152.7,22.71 152.57,22.58 152.57,22.16 152.48,22.07 152.27,22.07 152.17,22.17 152.17,22.63 152.05,22.75 151.89,22.75 151.77,22.63 151.77,22.17 151.67,22.07 146.05,22.07 145.95,22.17 145.95,22.43 145.85,22.53 145.65,22.53 145.54,22.43 145.54,22.17 145.44,22.07 145.24,22.07 145.14,22.17 145.14,22.79 145.02,22.91 144.85,22.91 144.73,22.79 144.73,22.17 144.63,22.07 144.43,22.07 144.32,22.17 144.32,22.8 144.2,22.93 143.93,22.93 143.74,22.73 143.58,22.73 143.46,22.85 143.46,23.01 143.67,23.22 143.67,23.32 143.53,23.46 142.92,23.46 142.84,23.38 v4(142.84,23.38)
  BOTTOM w0.076: v1(123.31,47.94) 123.05,47.94 122.59,48.4 122.59,50.66 UCPU1.AV47
DDR_B_MA12: length 136.6
  TOP w0.076: RD26.1 152.9,31.04 v1(152.9,27.23)
  TOP w0.102: UD3.N7 149.23,27.22 148.99,27.22 148.82,27.05 v1(148.82,26.88) ; UD1.N7 165.1,27.06 164.29,27.06 v1(163.97,26.74) ; v1(177.17,26.88) 177.34,27.05 177.74,27.05 UD4.N7 ; UD7.N7 135.97,27.06 v1(135.65,26.74)
  IN1 w0.076: v1(163.97,26.74) 164.1,26.86 164.84,26.86 164.91,26.79 164.91,26.56 164.99,26.48 167.57,26.48 167.73,26.65 169.05,26.65 169.26,26.85 169.26,27.09 169.38,27.22 170.32,27.22 v4(170.53,27.42) 170.73,27.22 171.24,27.22 171.6,26.85 172.25,26.85 172.3,26.81 173.78,26.81 174.05,27.07 175.01,27.07 175.14,27.19 176.86,27.19 v1(177.17,26.88) ; v1(135.65,26.74) 135.39,26.74 135.34,26.79 135.34,27.01 135.45,27.13 135.78,27.13 135.94,26.98 136.29,26.98 136.68,26.58 139.06,26.58 139.34,26.86 140.44,26.86 140.59,26.72 140.75,26.72 141.03,26.99 141.03,27.09 141.24,27.31 v4(141.63,27.31) 141.67,27.27 143.32,27.27 143.46,27.13 144.11,27.13 144.29,26.95 146.54,26.95 146.68,27.09 148.61,27.09 v1(148.82,26.88)
  IN1 w0.145: v1(121.72,50.02) 121.52,49.82 121.52,48.95 121.75,48.72 121.75,41.99 128.66,35.08 134.18,35.08 134.95,35.85 138.97,35.85 139.27,36.16 143.66,36.16 143.92,35.89 146.33,35.89 148.81,33.42 150.91,33.42 151.34,33.85 151.68,33.85 152.38,33.15 152.38,32.59 151.94,32.16 151.94,29.82 151.8,29.67 151.32,29.67 151.17,29.53 151.17,29.24 151.32,29.09 151.8,29.09 151.94,28.95 151.94,28.66 151.8,28.51 150.66,28.51 150.54,28.39 150.54,28.06 150.66,27.94 151.8,27.94 151.94,27.79 151.94,27.35 152.07,27.23 v1(152.9,27.23)
  IN4 w0.076: v4(170.53,27.42) 169.69,27.42 169.26,26.99 169.26,26.84 168.99,26.56 167.97,26.56 167.65,26.24 164.39,26.24 163.79,25.64 163.07,25.64 162.48,26.22 161.35,26.22 160.8,25.68 160.19,25.68 160.11,25.6 159.1,25.6 158.77,25.94 158.77,26.38 157.68,27.48 153.15,27.48 v1(152.9,27.23) 153.04,27.08 153.04,26.85 152.54,26.34 152.43,26.34 152.09,26.69 151.96,26.69 151.87,26.6 151.87,26.47 152.21,26.13 152.21,26.02 151.88,25.68 151.08,25.68 150.98,25.78 150.98,25.91 151.08,26.01 151.42,26.01 151.53,26.11 151.53,26.71 151.42,26.81 151.24,26.81 151.13,26.71 151.13,26.52 150.89,26.27 149.55,26.27 149.45,26.37 149.45,26.64 149.34,26.74 149.2,26.74 149.1,26.64 149.1,26.37 149,26.27 148.82,26.27 148.63,26.09 148.63,25.78 148.53,25.68 148.31,25.68 148.21,25.78 148.21,26.19 148.51,26.49 148.51,26.65 148.4,26.77 148.23,26.77 147.8,26.34 147.8,26.08 147.7,25.98 147.14,25.98 146.47,26.65 144.49,26.65 144.24,26.9 143.19,26.9 143.06,27.03 142.48,27.03 142.4,27.11 142.4,27.37 142.33,27.45 142.17,27.45 142.1,27.37 142.1,27.11 142.02,27.03 141.72,27.03 141.63,27.12 v4(141.63,27.31)
  BOTTOM w0.076: v1(121.72,50.02) 121.73,50.01 122.25,50.01 122.42,50.18 122.42,50.91 122.83,51.31 UCPU1.AU47
DDR_B_MA13: length 135.2
  TOP w0.076: RD46.1 156.99,22.52 v1(156.68,22.82)
  TOP w0.102: v1(162.45,24.24) 162.04,24.65 UD1.T3 ; UD7.T3 133.58,24.53 v1(133.94,24.18) ; v1(174.15,23.75) 174.15,24.26 174.15,24.26 UD4.T3 ; UD3.T3 146.47,24.65 v1(146.91,24.22)
  IN1 w0.076: v1(131.41,55.75) 131.79,55.37 131.79,54.24 131.97,54.07 ; v1(174.15,23.75) 173.75,23.35 173.48,23.35 173.41,23.28 173.41,23.04 173.33,22.96 173.18,22.96 173.1,23.04 173.1,23.28 173.03,23.35 172.88,23.35 172.81,23.28 172.81,22.79 172.73,22.71 172.58,22.71 172.5,22.79 172.5,23.28 172.43,23.35 170.84,23.35 170.39,22.9 169.98,22.9 169.74,23.14 169.29,23.14 v4(169.05,22.9) 167.6,22.9 166.99,23.51 166.17,23.51 165.64,24.05 164.4,24.05 164.21,24.24 v1(162.45,24.24) ; 131.97,53.36 132.21,53.11 132.83,53.11 133.06,52.88 133.06,52.24 133.57,51.73 141.8,51.73 142.49,51.04 142.71,51.04 ; v1(146.91,24.22) 146.08,24.22 144.75,22.89 142.57,22.89 142.41,23.05 140.86,23.05 v4(140.78,22.97) 139.38,22.97 138.33,24.02 134.09,24.02 v1(133.94,24.18)
  IN1 w0.086: 131.97,54.07 131.97,53.36
  IN1 w0.145: v1(156.68,22.82) 156.9,22.61 157.11,22.61 157.28,22.78 157.28,23.4 157.42,23.55 157.71,23.55 157.86,23.4 157.86,22.7 158.06,22.49 159.55,22.49 159.8,22.73 159.8,25.85 159.94,25.99 160.58,25.99 160.72,26.14 160.72,26.43 160.58,26.57 159.94,26.57 159.8,26.71 159.8,26.95 159.38,27.36 159.38,27.54 160.06,28.22 160.06,29.08 159.04,30.11 159.04,31.22 159.55,31.73 159.55,31.75 160.58,32.78 161.17,32.78 161.6,33.21 162.82,33.21 163.16,33.56 163.16,40.62 162.18,41.6 160.45,41.6 156.44,45.61 153.29,45.61 151.69,47.2 149.16,47.2 148.45,47.91 146.92,47.91 143.78,51.04 142.71,51.04
  IN4 w0.076: v4(169.05,22.9) 168.91,22.9 167.75,21.74 156.19,21.74 155.77,22.16 155.77,22.63 155.89,22.75 156.06,22.75 156.18,22.63 156.18,22.3 156.35,22.12 157.09,22.12 157.19,22.23 157.19,22.44 156.81,22.82 v1(156.68,22.82) 156.4,22.82 156.07,23.15 154.03,23.15 152.62,21.74 144.34,21.74 143.65,22.43 143.46,22.43 142.89,23 142.51,23 142.44,23.06 140.88,23.06 v4(140.78,22.97)
  BOTTOM w0.076: UCPU1.AK33 131.84,56.01 131.58,55.75 v1(131.41,55.75)
DDR_B_MA14: length 134.7
  TOP w0.076: v1(154.58,22.33) 154.53,22.27 RD35.1
  TOP w0.102: v1(177.31,24.24) 177.73,24.65 UD4.T7 ; UD3.T7 149.38,24.65 v1(148.97,24.24) ; UD1.T7 165.1,24.12 v1(164.6,23.61) ; UD7.T7 136.28,24.15 v1(136.28,23.61)
  IN1 w0.076: v1(123.31,52.58) 122.88,52.15 122.88,44.59 123.51,43.95 123.51,43.6 ; v1(136.28,23.61) 136.28,23.27 136.35,23.2 136.76,23.2 136.83,23.12 136.83,22.97 136.76,22.89 136.35,22.89 136.28,22.82 136.28,22.66 136.35,22.59 136.83,22.59 137.61,21.8 138.01,21.8 138.08,21.88 138.08,22.25 138.16,22.33 138.31,22.33 138.39,22.25 138.39,21.88 138.46,21.8 v4(141.55,21.8) 144.58,21.8 146.18,23.4 147.37,23.4 148.2,24.24 v1(148.97,24.24) ; v1(164.6,23.61) 164.6,23.31 164.47,23.18 163.66,23.18 163.54,23.06 163.54,22.89 163.66,22.78 164.47,22.78 164.6,22.65 164.6,22.19 164.72,22.06 v4(169.77,22.06) 173.46,22.06 174.76,23.36 176.22,23.36 177.1,24.24 v1(177.31,24.24)
  IN1 w0.145: 123.51,43.6 122.85,42.94 122.85,41.84 127.12,37.57 146.48,37.57 146.61,37.43 146.61,36.4 148.07,34.94 148.87,34.94 149.02,35.08 150.74,35.08 151.05,34.77 151.7,34.77 152.84,33.62 152.84,28.46 153.45,27.85 153.45,27.01 152.87,26.43 152.62,26.43 152.49,26.3 152.49,25.9 152.62,25.77 152.84,25.77 152.99,25.63 152.99,25.34 152.84,25.19 152.61,25.19 152.48,25.06 152.48,24.74 152.61,24.61 152.84,24.61 152.99,24.47 152.99,24.18 152.84,24.03 152.49,24.03 152.37,23.91 152.37,21.35 152.49,21.22 154.44,21.22 154.58,21.37 v1(154.58,22.33)
  IN4 w0.076: v4(169.77,22.06) 169.01,22.06 168.03,21.08 155.19,21.08 154.58,21.69 v1(154.58,22.33) 154.32,22.33 154.14,22.15 154.14,21.62 154.25,21.52 154.32,21.52 154.46,21.38 154.46,21.24 154.3,21.08 143.8,21.08 143.73,21.15 143.73,21.43 143.65,21.5 143.5,21.5 143.42,21.43 143.42,21.15 143.35,21.08 143.19,21.08 143.12,21.15 143.12,21.43 143.04,21.5 142.89,21.5 142.81,21.43 142.81,21.15 142.74,21.08 142.27,21.08 v4(141.55,21.8)
  BOTTOM w0.076: v1(123.31,52.58) 123.63,52.58 UCPU1.AR46
DDR_B_MA15: length 132.8
  TOP w0.076: RD74.1 154.91,30.1 v1(154.91,29.8)
  TOP w0.102: UD7.M7 136.75,27.82 136.22,27.82 v1(136.23,27.83) ; UD1.M7 165.07,27.82 164.54,27.82 v1(164.55,27.83) ; v1(178.14,27.47) 178.12,27.47 UD4.M7 ; v1(149.79,27.47) 149.78,27.47 UD3.M7
  IN1 w0.076: 124.36,46.04 124.36,49.78 123.91,50.23 123.91,52.62 v1(123.31,53.22) ; v1(136.23,27.83) 136.4,27.99 138.92,27.99 139.51,28.59 139.88,28.59 139.96,28.67 140.25,28.67 140.5,28.92 142.09,28.92 142.33,29.16 v4(143.1,29.16) 143.83,29.16 143.97,29.02 144.17,29.02 144.73,28.46 147.31,28.46 148.3,27.47 149.79,27.47 v1(149.79,27.47) ; v1(178.14,27.47) 178.13,27.47 177.22,27.47 176.28,28.41 172.95,28.41 172.24,29.11 171.66,29.11 v4(171.35,29.41) 171.17,29.24 169.33,29.24 168.23,28.13 164.86,28.13 v1(164.55,27.83)
  IN1 w0.086: 124.36,46.04 124.59,45.81 125.17,45.81 126.26,44.72
  IN1 w0.145: 126.26,44.72 126.99,43.98 126.99,43.7 129.74,40.95 130.3,40.95 130.44,40.81 130.44,40.25 130.88,39.82 131.02,39.82 131.09,39.89 131.09,40.2 131.17,40.27 131.6,40.27 131.68,40.19 131.68,39.72 131.79,39.62 132.17,39.62 132.26,39.71 132.26,40.18 132.35,40.27 132.74,40.27 132.84,40.18 132.84,39.73 132.96,39.62 133.31,39.62 133.42,39.73 133.42,40.17 133.52,40.27 133.9,40.27 134,40.18 134,39.72 134.1,39.62 134.46,39.62 134.58,39.73 134.58,40.16 134.69,40.27 135.06,40.27 135.16,40.17 135.16,39.7 135.24,39.62 135.63,39.62 135.74,39.72 135.74,40.17 135.84,40.27 136.21,40.27 136.31,40.17 136.31,39.73 136.42,39.62 136.79,39.62 136.89,39.72 136.89,40.17 137,40.27 137.38,40.27 137.47,40.18 137.47,39.7 137.55,39.62 137.97,39.62 138.05,39.7 138.05,40.2 138.13,40.27 138.54,40.27 138.63,40.18 138.63,39.71 138.72,39.62 139.1,39.62 139.21,39.73 139.21,40.17 139.31,40.27 139.69,40.27 139.79,40.18 139.79,39.71 139.88,39.62 140.26,39.62 140.37,39.73 140.37,40.16 140.48,40.27 140.83,40.27 140.95,40.16 140.95,39.7 141.03,39.62 141.44,39.62 141.53,39.71 141.53,40.18 141.62,40.27 142.02,40.27 142.11,40.18 142.11,39.71 142.2,39.62 142.58,39.62 142.69,39.72 142.69,40.17 142.79,40.27 143.16,40.27 143.26,40.17 143.26,39.72 143.37,39.62 143.75,39.62 143.84,39.71 143.84,40.16 143.96,40.27 144.31,40.27 144.42,40.17 144.42,39.72 144.53,39.62 144.89,39.62 145,39.73 145,40.19 145.09,40.27 145.48,40.27 145.58,40.18 145.58,39.72 145.68,39.62 146.06,39.62 146.16,39.72 146.16,40.16 146.27,40.27 146.67,40.27 146.79,40.16 146.79,39.74 146.91,39.63 147.32,39.63 147.99,38.95 151.61,38.95 153.75,36.81 153.75,35.77 154.85,34.67 154.85,29.85 v1(154.91,29.8)
  IN4 w0.076: v4(143.1,29.16) 142.63,29.16 142.2,28.74 141.34,28.74 141.24,28.84 141.24,29.03 141.34,29.13 142.12,29.13 142.58,29.59 143.42,29.59 144.68,28.33 147.17,28.33 147.26,28.42 147.26,28.63 147.39,28.76 147.58,28.76 147.68,28.66 147.68,28.64 147.78,28.54 147.96,28.54 148.18,28.76 151.51,28.76 152.08,29.33 154.44,29.33 v1(154.91,29.8) 157.47,29.8 157.89,29.38 158.84,29.38 159.27,28.95 160,28.95 160.11,28.84 161.44,28.84 161.93,28.36 163.71,28.36 163.89,28.54 164.38,28.54 164.78,28.14 167.45,28.14 167.45,28.13 168.24,28.13 169.03,28.92 170.5,28.92 170.63,29.05 170.98,29.05 v4(171.35,29.41)
  BOTTOM w0.076: v1(123.31,53.22) 123.61,53.22 UCPU1.AP46
DDR_B_RAS#: length 144.1
  TOP w0.076: v1(158.11,32.73) 158.08,32.73 RD64.1
  TOP w0.102: v1(147.27,29.83) 146.83,30.27 146.21,30.27 UD3.J3 ; v1(162.27,30.68) 162.27,30.62 162.06,30.41 UD1.J3 ; UD4.J3 174.54,30.25 174.91,30.62 v1(174.91,30.63) ; UD7.J3 133.58,30.25 133.66,30.25 v1(134.09,30.68)
  IN1 w0.076: v1(134.09,30.68) 135.19,29.59 136.34,29.59 136.97,30.23 137.65,30.23 137.71,30.18 138.96,30.18 139.19,30.41 139.19,30.87 139.93,31.61 139.93,32.27 140.21,32.55 141.02,32.55 v4(141.38,32.19) 142.85,32.19 144.27,30.77 146.6,30.77 146.93,31.1 147.27,31.1 147.64,30.74 147.64,30.59 147.57,30.52 147.34,30.52 147.26,30.44 147.26,30.29 147.34,30.21 147.57,30.21 147.64,30.14 147.64,29.77 147.57,29.69 147.35,29.69 147.27,29.77 v1(147.27,29.83) ; v1(174.91,30.63) 174.96,30.68 175.8,30.68 175.92,30.81 175.92,31.1 175.59,31.43 174.85,31.43 174.73,31.31 174.73,31.11 174.45,30.82 173.14,30.82 172.96,31 172.35,31 171.11,32.24 v4(168.88,32.24) 168.74,32.37 167.95,32.37 167.51,31.93 167.51,30.37 167.26,30.12 166.07,30.12 165.95,30.25 165.38,30.25 164.71,29.57 164.33,29.57 163.23,30.68 v1(162.27,30.68) ; v1(130.48,54.39) 130.4,54.47 130.27,54.47 130.13,54.33 130.13,52.13
  IN1 w0.086: 130.13,52.13 130.46,51.79 131.47,51.79 131.63,51.64
  IN1 w0.145: 131.63,51.64 131.63,51.11 131.83,50.9 132.08,50.9 132.22,51.05 132.22,51.46 132.37,51.6 132.66,51.6 132.8,51.46 132.8,51.05 132.95,50.9 134.07,50.9 134.71,50.26 135.03,50.26 135.17,50.41 135.17,50.74 135.28,50.85 139.18,50.85 139.32,50.71 139.32,50.43 139.49,50.26 140.29,50.26 140.44,50.41 140.44,50.83 140.58,50.98 140.87,50.98 141.02,50.83 141.02,50.41 141.16,50.26 141.71,50.26 144.78,47.19 144.99,47.19 145.44,47.64 145.65,47.64 145.84,47.44 145.84,47.24 145.43,46.82 145.43,46.62 145.63,46.41 145.84,46.41 146.25,46.83 146.46,46.83 147.01,46.28 148.79,46.28 149.54,45.53 151.22,45.53 153.08,43.67 154.04,43.67 154.19,43.53 154.19,42.93 154.33,42.79 154.62,42.79 154.77,42.93 154.77,43.53 154.91,43.67 155.2,43.67 155.35,43.53 155.35,42.73 155.49,42.58 155.78,42.58 155.93,42.73 155.93,43.53 156.07,43.67 156.48,43.67 156.84,43.31 156.84,42.95 155.96,42.08 155.96,41.87 156.16,41.67 156.37,41.67 157.32,42.62 157.53,42.62 157.73,42.41 157.73,42.21 156.78,41.26 156.78,41.05 156.98,40.85 157.19,40.85 158.14,41.8 158.34,41.8 158.55,41.59 158.55,41.39 157.6,40.44 157.6,40.23 157.8,40.03 158.01,40.03 158.82,40.85 159,40.85 159.23,40.62 159.23,40.02 159.07,39.86 158.66,39.86 158.42,39.62 158.42,39.41 158.67,39.16 158.67,39.11 158.82,38.96 159.08,38.96 159.22,38.82 159.22,38.53 159.08,38.38 158.82,38.38 158.67,38.24 158.67,37.95 158.82,37.8 159.08,37.8 159.22,37.66 159.22,37.37 159.08,37.22 158.82,37.22 158.67,37.08 158.67,33.73 158.11,33.16 v1(158.11,32.73)
  IN4 w0.076: v4(141.38,32.19) 141.66,31.92 142.82,31.92 143.73,31.01 146.61,31.01 147.12,31.52 148.18,31.52 148.61,31.95 148.61,32.42 148.88,32.69 150.68,32.69 151.22,32.15 152.25,32.15 152.84,32.73 v1(158.11,32.73) 158.81,32.73 158.94,32.87 159.53,32.87 159.85,32.55 160.23,32.55 160.34,32.66 161.18,32.66 161.47,32.95 161.98,32.95 162.08,32.85 162.08,32.49 162.18,32.39 162.74,32.39 162.84,32.49 162.84,32.85 162.94,32.95 165.01,32.95 165.11,33.06 167.6,33.06 167.71,32.96 167.71,32.74 167.81,32.64 168.01,32.64 168.11,32.74 168.11,32.96 168.21,33.06 168.36,33.06 168.48,32.93 168.48,32.7 168.53,32.65 169.06,32.65 169.3,32.42 170.39,32.42 171.2,31.62 171.2,31.46 171.08,31.34 170.92,31.34 170.2,32.06 169.06,32.06 v4(168.88,32.24)
  BOTTOM w0.076: v1(130.48,54.39) 130.81,54.71 UCPU1.AM35
DDR_B_WE#: length 140.8
  TOP w0.076: v1(158.98,32.35) 158.98,32.72 RD81.1
  TOP w0.102: v1(134.02,29.21) 133.58,28.77 UD7.L3 ; v1(146.59,29.13) 146.59,28.78 146.46,28.65 146.19,28.65 UD3.L3 ; v1(175.01,28.93) 174.73,28.65 174.54,28.65 UD4.L3 ; v1(162.45,29.15) 161.96,28.65 UD1.L3
  IN1 w0.076: 141.7,50.97 141.29,51.39 133.42,51.39 132.77,52.03 132.23,52.03 132.12,52.14 131.27,52.14 131.08,52.33 131.08,55.15 130.9,55.33 130.9,56.53 ; v1(146.59,29.13) 146.83,29.13 146.91,29.21 146.91,29.45 146.83,29.53 146.32,29.53 146.17,29.68 146.17,30.27 146.03,30.42 144.04,30.42 142.86,31.6 141.01,31.6 v4(140.84,31.43) 140.36,30.95 140.27,30.95 139.1,29.78 137.98,29.78 137.48,29.28 136.74,29.28 136.56,29.1 134.13,29.1 v1(134.02,29.21) ; v1(130.46,55.69) 130.29,55.69 130.17,55.81 130.17,56.53 130.29,56.66 130.78,56.66 ; v1(175.01,28.93) 174.43,29.51 173.99,29.51 173.79,29.71 173.79,30.15 173.52,30.42 172.97,30.42 172.8,30.6 172.14,30.6 171.29,31.45 v4(168.83,31.45) 168.41,31.03 168.41,30.69 167.5,29.78 166.59,29.78 165.96,29.15 v1(162.45,29.15)
  IN1 w0.086: 130.9,56.53 130.78,56.66
  IN1 w0.145: 141.7,50.97 143.18,49.5 143.38,49.5 143.85,49.97 144.06,49.97 144.26,49.76 144.26,49.56 143.79,49.09 143.79,48.88 144.55,48.13 146.04,48.13 147.43,46.74 151.07,46.74 151.73,46.08 151.73,46.07 153.46,44.34 153.65,44.34 153.8,44.49 153.8,44.79 153.94,44.93 154.23,44.93 154.38,44.79 154.38,44.49 154.52,44.34 155.26,44.34 155.4,44.49 155.4,44.79 155.55,44.93 155.84,44.93 155.98,44.79 155.98,44.49 156.13,44.34 156.76,44.34 159.9,41.19 159.9,40.61 160.05,40.47 160.57,40.47 160.71,40.33 160.71,40.04 160.57,39.89 160.05,39.89 159.9,39.75 159.9,39.46 160.05,39.31 161,39.31 161.13,39.18 161.13,38.86 161,38.73 160.05,38.73 159.9,38.59 159.9,38.3 160.05,38.15 160.95,38.15 161.08,38.03 161.08,37.7 160.95,37.57 160.05,37.57 159.9,37.43 159.9,36.97 159.34,36.4 159.34,36.07 159.49,35.93 160.16,35.93 160.29,36.05 160.29,36.5 160.42,36.63 161.04,36.63 161.17,36.5 161.17,35.19 161.04,35.07 160.46,35.07 160.17,35.35 159.49,35.35 159.34,35.2 159.34,34.91 159.49,34.77 160.16,34.77 160.3,34.62 160.3,34.34 160.16,34.19 159.49,34.19 159.34,34.05 159.34,33.76 159.49,33.61 159.87,33.61 160.01,33.47 160.01,33.18 159.87,33.03 159.49,33.03 159.34,32.89 159.34,32.71 v1(158.98,32.35)
  IN4 w0.076: v4(168.83,31.45) 168.89,31.38 169.9,31.38 170.08,31.21 170.22,31.21 170.36,31.34 170.36,31.49 170.12,31.73 169.3,31.73 169.19,31.84 168.6,31.84 168.5,31.94 168.5,32.39 168.42,32.46 168.24,32.46 168.17,32.39 167.68,32.39 167.55,32.51 167.55,32.82 167.47,32.91 167.33,32.91 167.25,32.83 167.25,32.67 167.18,32.59 167.02,32.59 166.95,32.67 166.95,32.83 166.87,32.91 166.72,32.91 166.64,32.83 166.64,32.67 166.57,32.59 166.41,32.59 166.34,32.67 166.34,32.83 166.26,32.91 166.11,32.91 166.03,32.83 166.03,32.54 165.94,32.45 165.82,32.45 165.73,32.54 165.73,32.83 165.65,32.91 165.31,32.91 165.18,32.78 165.18,32.24 165.06,32.11 164.13,32.11 164.03,32.22 164.03,32.65 163.93,32.75 163.14,32.75 163.04,32.65 163.04,32.48 162.8,32.24 161.97,32.24 161.64,31.9 161.33,31.9 161.15,32.08 160.99,32.08 160.77,31.86 160.46,31.86 160.24,32.08 160.24,32.27 160.18,32.34 159.96,32.34 159.68,32.06 159.5,32.06 159.44,32.12 159.44,32.37 159.55,32.49 159.55,32.63 159.47,32.72 159.08,32.72 158.98,32.62 v1(158.98,32.35) 153.78,32.35 153.33,31.91 150.75,31.91 150.69,31.85 148.8,31.85 148.27,31.32 147.21,31.32 146.69,30.81 143.64,30.81 142.86,31.59 140.99,31.59 v4(140.84,31.43)
  BOTTOM w0.076: UCPU1.AK35 130.79,56.01 v1(130.46,55.69)
DDR_CHA_EN: length 5
  TOP w0.089: v1(153.26,66.87) v2(153.85,66.87) 154.15,66.87 154.53,67.25
  TOP w0.102: 154.53,67.25 154.63,67.25 RH440.1 154.89,67.93 154.87,67.96 RH442.1
  BOTTOM w0.076: v1(153.26,66.87) 153.26,66.99 152.8,67.45 151.75,67.45 UCPU1.J1
DDR_CHB_EN: length 9.2
  TOP w0.076: v1(152.71,66.86) 152.71,66.24 v2(152.74,66.21)
  TOP w0.089: 154.33,67.75 154.33,67.65 154.11,67.43 153.28,67.43 v1(152.71,66.86)
  TOP w0.102: 154.33,67.75 154.33,69.1 154.87,69.64 RH443.1 154.87,71.03 RH441.1
  BOTTOM w0.076: UCPU1.K3 150.56,66.85 151.12,66.85 151.3,67.03 151.72,67.03 151.72,67.03 151.98,67.29 152.47,67.29 152.71,67.04 v1(152.71,66.86)
DH_1.35V: length 5.5
  TOP w0.102: v2(75.37,49.54) 75.62,49.29 v7(75.98,49.29)
  IN2 w0.762: 77.44,49.16 77.88,49.16 78.2,48.85 82.07,48.85
  vias: v7(76.61,49.29) v7(82.71,48.46) v7(83.34,48.46)
DISP_CEC: length 7.8
  GND1 w0.102: v3(15.97,66.19) v4(15.97,65.66)
  IN4 w0.071: JMDP.6 16.45,60.63 16.45,65.18 v4(15.97,65.66)
DISP_CLK_AUXP_CONN: length 15.4
  TOP w0.102: UV1.4 19.71,68.72 19.71,67.64 19.52,67.46 CV798.1 v3(20.4,67.1)
  GND1 w0.102: v4(21.02,67.32) 20.81,67.1 v3(20.4,67.1)
  IN4 w0.071: JMDP.16 14.98,61.98 14.98,62.1 15.25,62.37 15.63,62.37 15.91,62.65 15.91,64.41 15.41,64.91 15.41,65.93 16.38,66.9 18.46,66.9 19.59,68.03 20.96,68.03 21.22,67.77 21.22,67.51 v4(21.02,67.32)
DISP_DAT_AUXN_CONN: length 15.5
  TOP w0.102: UV1.7 21.66,68.51 21.66,68.51 21.66,67.75 21.75,67.66 22.45,67.66 22.55,67.56 22.55,67.38 22.28,67.12 v3(22.17,67.12)
  GND1 w0.102: v3(22.17,67.12) 21.73,67.12 v4(21.53,67.32)
  IN4 w0.071: v4(21.53,67.32) 21.44,67.41 21.44,67.86 21.05,68.25 19.5,68.25 18.37,67.12 16.28,67.12 15.19,66.03 15.19,64.81 15.68,64.32 15.68,62.74 15.54,62.59 15.27,62.59 JMDP.18
DISP_HPD_SINK: length 10.9
  TOP w0.102: v1(19.23,55.51) v2(18.58,55.51)
  IN4 w0.071: v1(19.23,55.51) 17.12,57.63 14.49,57.63 JMDP.2
  BOTTOM w0.102: v1(19.23,55.51) RV10.1 20.72,56.16 21.3,56.74 22.19,56.74 QV2.1
DISPOFF#: length 5.8
  TOP w0.102: v1(194.09,29.57) 193.77,29.57 193.21,30.13 R540.1 193.21,30.92 193.46,31.17 v2(193.79,31.17) 194.1,31.17 194.34,30.94 D72.1
  BOTTOM w0.102: v1(194.09,29.57) 194.09,28.57 193.89,28.37 JEDP.9
DL_1.35V: length 0.6
  TOP w0.102: v7(74.9,51.32) v2(75.5,51.32)
  vias: v7(74.9,50.69) v7(79.02,52.21) v7(79.02,51.58)
DMIC_CLK_CODEC: length 12.9
  TOP w0.102: v1(41.46,17.79) 41.64,17.97 41.64,18.5 41.45,18.7 v2(37.88,18.7) 36.59,18.7 35.07,20.22 35.07,20.53 CA23.2 RA45.2
  BOTTOM w0.102: v1(41.46,17.79) 41.64,17.96 41.64,18.63 42.05,19.05 42.05,19.62 41.92,19.76 JKB1.12
DMIC_DAT_CODEC: length 15.9
  TOP w0.102: v1(42.04,17.79) 41.85,17.99 41.85,18.59 41.43,19.01 36.73,19.01 v2(36.06,19.68) 35.28,20.46 35.28,22.12 CA25.2 34.1,23.29 33.96,23.29 33.26,23.99 UA2.54
  BOTTOM w0.102: JKB1.11 42.41,20.3 42.41,19.77 42.26,19.62 42.26,18.96 41.84,18.54 41.84,17.99 v1(42.04,17.79)
DP_CBL_DET: length 1.6
  TOP w0.102: RV8.1 17.76,67.12 UV1.1
DSWODVREN: length 10.8
  BOTTOM w0.076: 153.27,46.78 149.64,46.78 147.78,48.63 147.78,50 UCPU1.AW7
  BOTTOM w0.102: 153.27,46.78 v2(154.87,46.78) 155.59,46.78 RH147.2
EC_WAKE#: length 54.7
  TOP w0.102: v1(181.47,68.59) 181.51,68.59 181.97,69.05 181.97,70.34 UE5.B27
  IN1 w0.071: v4(162.1,58.6) 163.46,58.6 163.7,58.84 168.17,58.84 168.61,58.4 169.79,58.4 170.39,57.79 176.22,57.79 176.68,58.25 178.47,58.25 178.71,58.49 180.45,58.49 180.66,58.29 181.63,58.29 v4(181.83,58.09)
  IN3 w0.086: v4(181.83,58.09) 181.83,59.87 181.47,60.22 v1(181.47,68.59)
  IN4 w0.071: v4(162.1,58.6) 161.75,58.95 160.11,58.95 157.83,56.66 157.15,56.66 156.37,55.89 152.57,55.89 152.23,55.55 151.78,55.55 150.91,54.68 149.19,54.68 v1(149.18,54.69)
  GND3 w0.102: v4(162.1,58.6) 162.1,58.6 162.1,58.72 v5(162.38,59)
  BOTTOM w0.076: UCPU1.AN5 148.7,54.21 v1(149.18,54.69)
  BOTTOM w0.102: v1(181.47,68.59) v2(181.47,68) ; v5(162.38,59) 162.38,59.42 161.64,60.16 160.1,60.16 159.16,61.1 RP20.3
EDP_AUXN: length 123
  TOP w0.102: C1065.1 199.64,35.74 200.21,35.74 v1(200.29,35.65)
  IN1 w0.071: v1(200.29,35.65) 200.5,35.86 200.67,35.86 200.85,36.03 200.85,36.74 201.9,37.79 201.9,44.94 198.47,48.37 198.47,49.75 195,53.22 195,62.58 194.75,62.84 194.75,67.1 195,67.36 195,70.99 193.46,72.53 192.48,72.53 189.75,75.27 185.84,75.27 185.68,75.11 180.28,75.11 180.12,75.27 174.85,75.27 174.52,74.94 168.06,74.94 165.04,77.96 160.54,77.96 157.6,75.02 149.08,75.02 148.87,74.82 137.37,74.82 135.68,73.13 134.62,73.13 134.43,72.94 132.43,72.94 131.83,72.33 131.16,72.33 129.64,73.85 127.87,73.85 125.83,75.9 124.31,75.9 v1(124.23,75.98)
  BOTTOM w0.076: UCPU1.A45 124.35,72.24 124.46,72.14 124.61,72.14 124.72,72.24 124.72,72.69 124.83,72.8 124.83,74.27 124.95,74.39 124.95,74.47
  BOTTOM w0.102: v1(124.23,75.98) 124.55,75.66 124.75,75.66 124.95,75.46 124.95,74.47
EDP_AUXN_C: length 1.8
  TOP w0.102: C1065.2 198,35.79 197.3,35.79 197.15,35.64 L58.1 196.81,35.64
EDP_AUXN_CONN: length 3.3
  TOP w0.102: L58.2 195.21,35.64 195.05,35.8 194.89,35.8 v1(194.7,35.62)
  BOTTOM w0.102: JEDP.25 193.58,36.37 193.68,36.47 193.94,36.47 193.98,36.43 193.98,36.21 194.34,35.85 194.51,35.85 194.7,35.66 v1(194.7,35.62)
EDP_AUXP: length 122.9
  TOP w0.102: C1064.1 199.65,35.95 200,35.95 v1(200.29,36.24)
  IN1 w0.071: v1(200.29,36.24) 200.54,35.99 200.61,35.99 200.72,36.09 200.72,36.79 201.77,37.85 201.77,44.89 198.34,48.31 198.34,49.69 194.87,53.16 194.87,62.53 194.61,62.78 194.61,67.16 194.87,67.41 194.87,70.93 193.4,72.4 192.43,72.4 189.69,75.13 185.89,75.13 185.74,74.98 180.22,74.98 180.06,75.13 174.91,75.13 174.57,74.8 168,74.8 164.98,77.83 160.6,77.83 157.66,74.89 149.13,74.89 148.93,74.68 137.43,74.68 135.74,73 134.68,73 134.49,72.81 132.49,72.81 131.88,72.2 131.1,72.2 129.58,73.72 127.82,73.72 125.77,75.76 124.56,75.76 124.23,75.43 v1(124.23,75.39)
  BOTTOM w0.076: UCPU1.B45 124.35,71.86 124.06,72.16 124.06,72.48 124.16,72.58 124.35,72.58 124.65,72.88 124.65,74.36 124.73,74.45 124.73,74.47
  BOTTOM w0.102: 124.73,74.47 124.73,75.37 124.66,75.44 124.28,75.44 v1(124.23,75.39)
EDP_AUXP_C: length 1.8
  TOP w0.102: 196.81,36.14 L58.4 197.22,36.14 197.37,36 198.1,36 C1064.2
EDP_AUXP_CONN: length 3.3
  TOP w0.102: v1(194.7,36.2) 194.89,36.01 195.08,36.01 195.2,36.14 L58.3
  BOTTOM w0.102: v1(194.7,36.2) 194.56,36.06 194.43,36.06 194.19,36.3 194.19,36.51 194.03,36.67 193.79,36.67 193.59,36.87 JEDP.26
EDP_BIA_PWM: length 134.4
  TOP w0.102: RC147.1 RC146.2 v2(127.72,76.67) 127.92,76.67 128.1,76.84 128.1,76.92 v1(129.01,77.83) ; v1(200.67,27.83) 200.35,28.15 197.49,28.15 197.21,27.88 D73.2
  IN2 w0.086: v1(200.67,27.83) 201.05,28.22 204.38,28.22 205.3,29.13 205.3,34.08 203.99,35.38 203.99,38.06 201.69,40.37 199.11,40.37 198.45,41.02 198.45,50.6 195.71,53.34 195.71,69.27 189.24,75.74 181.61,75.74 180.7,76.64 171.85,76.64 171.24,76.03 167.72,76.03 165.04,78.71 159.11,78.71 158.99,78.6 155.59,78.6 154.63,79.55 148.25,79.55 145.86,77.16 142.75,77.16 142.74,77.17 142.63,77.17 141.95,77.84 139.31,77.84 137.59,79.55 128.93,79.55 128.58,79.21 128.58,78.27 v1(129.01,77.83)
EDP_BKLCTL: length 31.3
  TOP w0.102: RC147.2 126.23,78.04 127.13,78.04 v1(127.3,77.88) 127.65,77.88 v2(127.92,78.15)
  IN2 w0.086: v1(148.82,75.41) 148.82,75.41 148.58,75.66 136.62,75.66 135.99,75.03 129.07,75.03
  IN2 w0.102: v1(127.3,77.88) 127.3,76.2 128.47,75.03 129.07,75.03
  BOTTOM w0.076: UCPU1.B8 146.84,71.63 147.38,72.17 147.38,72.66 148.58,73.87 148.58,75.17 v1(148.82,75.41)
EDP_COM: length 3.5
  TOP w0.076: v1(139.81,70.01) 140.18,70.01 140.45,69.74 v2(140.45,69.16)
  TOP w0.508: RC36.1 139.08,70.55 139.62,70.01 v1(139.81,70.01)
  BOTTOM w0.254: v1(139.81,70.01) 140.29,70.49 UCPU1.D20
EDP_DISP: length 6.2
  TOP w0.076: v2(125.61,73.07) 126.01,73.07 126.23,73.29 v1(126.23,73.6)
  TOP w0.089: 125.61,75.4 v2(125.61,73.07)
  TOP w0.102: RC146.1 RC158.2 125.62,75.62 125.62,75.41 125.61,75.4
  BOTTOM w0.076: v1(126.23,73.6) 126.08,73.45 126.08,72.62 UCPU1.A43
EDP_HPD: length 86.5
  TOP w0.102: v1(158.13,72.73) v2(157.28,72.73) 157.2,72.73 156.68,73.26 RC148.1 157.75,74.86 158.16,74.86 158.34,74.68 QC5.1
  IN1 w0.071: v4(174.74,39.98) 175.18,39.54 179.48,39.54 181.39,41.45 181.39,43.35 183.24,45.21 183.24,45.98 183.16,46.06 183.16,47.04 184.68,48.55 186.35,48.55 187,47.9 187,43.41 187.55,42.86 187.55,38.22 188.83,36.94 188.83,33.09 189.29,32.64 190.35,32.64 v1(190.68,32.3)
  IN3 w0.086: v1(158.13,72.73) 161.14,69.72 161.57,69.72 163.02,68.28 163.02,66.77 163.56,66.23 163.99,66.23 165.85,64.36 165.85,60.69 166.31,60.23 168.84,60.23 169.08,59.99 169.08,57.24 169.61,56.7 169.61,55.67 170.92,54.37 170.92,53.2 171.65,52.47 171.65,49.59 171.1,49.04 171.1,47.65 172.34,46.4 172.34,43.22 174.74,40.82 v4(174.74,39.98)
  BOTTOM w0.102: v1(190.68,32.3) 190.68,31.95 191.76,30.87 JEDP.14
EDP_TXN_P0: length 119.7
  TOP w0.102: C1062.1 199.7,37.8 199.85,37.8 200.02,37.97 v1(200.02,38.04)
  IN1 w0.071: 149.79,74.12 149.78,74.1 149.77,74.1 149.74,74.08 149.74,74.08 149.49,73.83 147.35,73.83 146.15,72.62 142.13,72.62 141.37,73.38 137.99,73.38 137.61,73 137.19,73 136.8,72.61 136.8,72.19 136.63,72.01 132.61,72.01 132.13,71.54 130.73,71.54 130.26,72.01 127.13,72.01 125.62,73.52 124.97,73.52 124.6,73.89 124.37,73.89 124.28,73.8 v1(124.28,73.58) ; 153.19,74.19 153.24,74.15 153.33,74.06 158.86,74.06 161.16,71.76 165.44,71.76 167.77,74.09 175.08,74.09 175.68,73.49 176.89,73.49 177.51,74.11 181.08,74.11 181.24,73.95 189.94,73.95 192.3,71.59 193.23,71.59 194.2,70.63 194.2,69.69 194.21,69.68 194.21,67.96 193.92,67.67 193.92,61.98 193.62,61.67 193.62,53.44 196.15,50.9 196.15,48.77 197.32,47.61 198.11,47.61 201.11,44.61 201.11,38.16 200.66,37.71 200.29,37.71 200.22,37.78 200.22,37.84 v1(200.02,38.04)
  IN1 w0.076: 149.79,74.12 149.86,74.19 153.19,74.19
  BOTTOM w0.076: v1(124.28,73.58) 124.28,73.69 124.15,73.82 124.15,73.82 124.14,73.82 123.85,73.82 123.77,73.74 123.77,73.58 123.89,73.45 123.89,73.16 123.76,73.03 123.76,72.81 123.88,72.69 123.88,72.47 123.88,72.46 123.88,71.68 124.08,71.48 124.08,71.1 124.21,70.98 UCPU1.C45
EDP_TXN_P0_C: length 1.8
  TOP w0.102: C1062.2 198.09,37.89 197.35,37.89 197.2,38.05 L57.4 196.81,38.05
EDP_TXN_P0_CONN: length 2.8
  TOP w0.102: L57.3 195.14,38.05 194.95,37.85 194.8,37.85 v1(194.55,38.11)
  BOTTOM w0.102: v1(194.55,38.11) 194.26,38.11 194.17,38.2 193.8,38.2 193.63,38.37 JEDP.29
EDP_TXN_P1: length 119.7
  TOP w0.102: v1(199.98,39.93) 199.8,39.76 199.65,39.76 C1063.1
  IN1 w0.071: v1(123.29,75.03) 122.98,74.73 122.14,74.73 121.7,74.3 121.7,72.73 123.22,71.21 125.09,71.21 127.06,69.24 138.52,69.24 139.76,70.47 146.74,70.47 148.32,72.05 152.47,72.05 153.1,71.41 158.69,71.41 160.33,69.78 166.26,69.78 166.87,70.39 169.73,70.39 170.85,71.51 179.46,71.51 179.46,71.51 181.25,71.51 181.62,71.88 182.77,71.88 183.03,71.62 189.15,71.62 191.31,69.46 191.31,68.27 191.92,67.65 191.92,65.73 191.1,64.91 191.1,62.84 190.09,61.83 190.09,56.58 190.54,56.13 190.54,53.59 190.96,53.16 190.96,51.89 193.76,49.09 193.76,48.35 197.6,44.52 197.6,41.27 198.5,40.37 200.18,40.37 200.42,40.13 200.42,39.79 200.33,39.7 200.21,39.7 v1(199.98,39.93)
  BOTTOM w0.076: v1(123.29,75.03) 123.44,74.89 123.44,74.75 123.36,74.67 122.77,74.67 122.62,74.53 122.62,74.19 123.23,73.59 123.23,72.6 123.33,72.49 123.33,72.36 123.25,72.28 UCPU1.A47
EDP_TXN_P1_C: length 1.8
  TOP w0.102: 196.81,39.95 L56.4 197.21,39.95 197.35,39.81 198.1,39.81 C1063.2
EDP_TXN_P1_CONN: length 2.8
  TOP w0.102: L56.3 195.15,39.95 195.03,39.82 194.66,39.82 v1(194.47,40.01)
  BOTTOM w0.102: JEDP.32 193.56,39.87 193.71,39.72 194.19,39.72 v1(194.47,40.01)
EDP_TXN_P2: length 119.4
  TOP w0.102: v1(200,41.85) 199.81,41.66 199.65,41.66 C1066.1
  IN1 w0.071: v1(200,41.85) 200.21,41.64 200.33,41.64 200.4,41.7 200.4,42.15 200.14,42.4 198.73,42.4 198.36,42.77 198.36,44.69 194.46,48.59 194.46,49.87 192.29,52.04 192.29,55.51 191.2,56.6 191.2,58.86 191.69,59.35 192.22,59.35 192.29,59.42 192.29,59.63 192.22,59.7 191.39,59.7 191.21,59.88 191.21,60.14 191.39,60.32 192.14,60.32 192.27,60.45 192.27,61.16 192.14,61.29 191.23,61.29 191.05,61.47 191.05,61.73 191.23,61.91 192.19,61.91 192.29,62.01 192.29,62.64 192.59,62.94 192.59,67.93 191.99,68.53 191.99,69.72 189.08,72.63 180.67,72.63 180.52,72.78 178.05,72.78 177.44,72.17 167.72,72.17 165.99,70.44 160.61,70.44 158.86,72.19 153.53,72.19 153.1,72.62 147.94,72.62 146.69,71.37 138.78,71.37 137.71,70.3 126.97,70.3 125.42,71.85 123.34,71.85 122.91,72.27 122.91,73.58 122.87,73.63 122.41,73.63 122.33,73.55 v1(122.33,73.38)
  BOTTOM w0.076: UCPU1.C47 123.34,70.87 123.34,70.77 123.25,70.68 123.08,70.68 122.93,70.84 122.93,71.26 122.92,71.27 122.86,71.34 122.81,71.39 122.81,71.42 122.75,71.48 122.75,71.77 122.81,71.84 122.81,72.07 122.75,72.13 122.75,72.36 122.75,73.5 122.62,73.63 122.49,73.63 122.48,73.61 122.45,73.61 122.33,73.5 v1(122.33,73.38)
EDP_TXN_P2_C: length 1.7
  TOP w0.102: C1066.2 198.06,41.67 197.37,41.67 197.19,41.86 L59.4
EDP_TXN_P2_CONN: length 3
  TOP w0.102: L59.3 195.09,41.86 194.97,41.73 194.81,41.73 v1(194.59,41.95)
  BOTTOM w0.102: JEDP.35 193.6,41.37 193.75,41.22 193.87,41.22 193.95,41.3 193.95,41.31 194.59,41.95 v1(194.59,41.95)
EDP_TXN_P3: length 119.6
  TOP w0.102: C1068.1 199.65,43.57 199.8,43.57 v1(199.99,43.76)
  IN1 w0.071: v1(120.46,73.39) 120.69,73.17 120.79,73.17 120.87,73.25 120.87,75.58 121.65,76.35 123.27,76.35 123.52,76.1 123.52,75.51 123.77,75.26 123.77,73.05 124.15,72.68 125.67,72.68 127,71.36 130.13,71.36 130.53,70.96 132.27,70.96 132.67,71.36 136.86,71.36 137.66,72.16 146.43,72.16 147.6,73.33 158.84,73.33 160.94,71.23 165.66,71.23 167.96,73.54 174.89,73.54 175.46,72.97 177.11,72.97 177.72,73.57 180.87,73.57 181.01,73.42 189.42,73.42 192,70.84 192.28,70.84 193.68,69.44 193.68,68.18 193.38,67.88 193.38,62.35 193.09,62.06 193.09,52.37 195.27,50.19 195.27,48.91 197.64,46.53 197.74,46.53 197.98,46.76 198.19,46.76 198.42,46.53 198.42,46.32 198.18,46.09 198.18,45.99 198.33,45.84 198.43,45.84 198.67,46.07 198.88,46.07 199.11,45.84 199.11,45.63 198.87,45.4 198.87,45.3 199.25,44.92 199.25,43.69 199.4,43.54 199.75,43.54 199.83,43.61 199.84,43.61 v1(199.99,43.76)
  BOTTOM w0.076: v1(120.46,73.39) 120.67,73.19 121.36,73.19 121.53,73.02 121.53,72.12 121.61,72.04 121.77,72.04 121.85,72.12 UCPU1.A49
EDP_TXN_P3_C: length 1.7
  TOP w0.102: C1068.2 198.09,43.6 197.34,43.6 197.19,43.76 L60.4
EDP_TXN_P3_CONN: length 3
  TOP w0.102: L60.3 195.19,43.76 195.03,43.6 194.72,43.6 v1(194.61,43.71)
  BOTTOM w0.102: JEDP.38 193.75,42.87 194.2,43.32 194.22,43.32 v1(194.61,43.71)
EDP_TXP_P0: length 119.7
  TOP w0.102: C1060.1 199.59,37.59 199.89,37.59 v1(200.02,37.46)
  IN1 w0.071: 153.19,74.33 153.21,74.33 153.21,74.32 153.25,74.32 153.33,74.25 153.33,74.24 153.38,74.19 158.92,74.19 161.21,71.89 165.39,71.89 167.71,74.22 175.14,74.22 175.74,73.63 176.84,73.63 177.45,74.24 181.14,74.24 181.29,74.08 189.99,74.08 192.35,71.73 193.29,71.73 194.33,70.68 194.33,69.75 194.34,69.74 194.34,67.9 194.05,67.62 194.05,61.92 193.75,61.62 193.75,53.49 196.28,50.96 196.28,48.83 197.37,47.74 198.17,47.74 201.24,44.67 201.24,38.1 200.71,37.58 200.14,37.58 v1(200.02,37.46) ; 149.69,74.21 149.44,73.96 147.3,73.96 146.09,72.75 142.18,72.75 141.43,73.51 137.94,73.51 137.56,73.13 137.14,73.13 136.67,72.66 136.67,72.24 136.57,72.14 132.55,72.14 132.08,71.67 130.79,71.67 130.32,72.14 127.18,72.14 125.67,73.65 125.02,73.65 124.65,74.02 124.49,74.02 v1(124.28,74.23)
  IN1 w0.076: 149.69,74.21 149.8,74.33 153.19,74.33
  BOTTOM w0.076: v1(124.28,74.23) 124.07,74.01 123.77,74.01 123.58,73.82 123.58,73.5 123.71,73.38 123.71,73.24 123.58,73.1 123.58,72.73 123.7,72.61 123.7,72.47 123.69,72.46 123.69,71.68 123.51,71.5 123.51,71.34 123.61,71.24 123.73,71.24 UCPU1.B46
EDP_TXP_P0_C: length 1.8
  TOP w0.102: 196.81,37.55 L57.1 197.22,37.55 197.35,37.68 198.02,37.68 C1060.2
EDP_TXP_P0_CONN: length 2.9
  TOP w0.102: v1(194.55,37.52) 194.67,37.65 195.14,37.65 195.24,37.55 L57.2
  BOTTOM w0.102: v1(194.55,37.52) 194.08,37.99 193.74,37.99 193.62,37.87 JEDP.28
EDP_TXP_P1: length 119.7
  TOP w0.102: v1(199.98,39.35) 199.78,39.55 199.65,39.55 C1061.1
  IN1 w0.071: v1(123.3,74.3) 123,74.6 122.19,74.6 121.84,74.24 121.84,72.78 123.28,71.34 125.15,71.34 127.12,69.37 138.47,69.37 139.7,70.6 146.69,70.6 148.27,72.18 152.52,72.18 153.16,71.55 158.75,71.55 160.38,69.91 166.21,69.91 166.82,70.52 169.68,70.52 170.8,71.64 179.6,71.64 179.6,71.64 181.2,71.64 181.57,72.01 182.82,72.01 183.09,71.75 189.2,71.75 191.44,69.51 191.44,68.33 192.05,67.71 192.05,65.68 191.23,64.86 191.23,62.79 190.22,61.77 190.22,56.63 190.67,56.18 190.67,53.64 191.09,53.22 191.09,51.95 193.9,49.15 193.9,48.41 197.73,44.57 197.73,41.32 198.55,40.5 200.24,40.5 200.55,40.19 200.55,39.73 200.38,39.56 200.19,39.56 v1(199.98,39.35)
  BOTTOM w0.076: UCPU1.B47 123.23,71.72 123.51,72.01 123.51,72.57 123.41,72.67 123.41,73.67 122.81,74.27 122.81,74.45 122.85,74.49 123.11,74.49 v1(123.3,74.3)
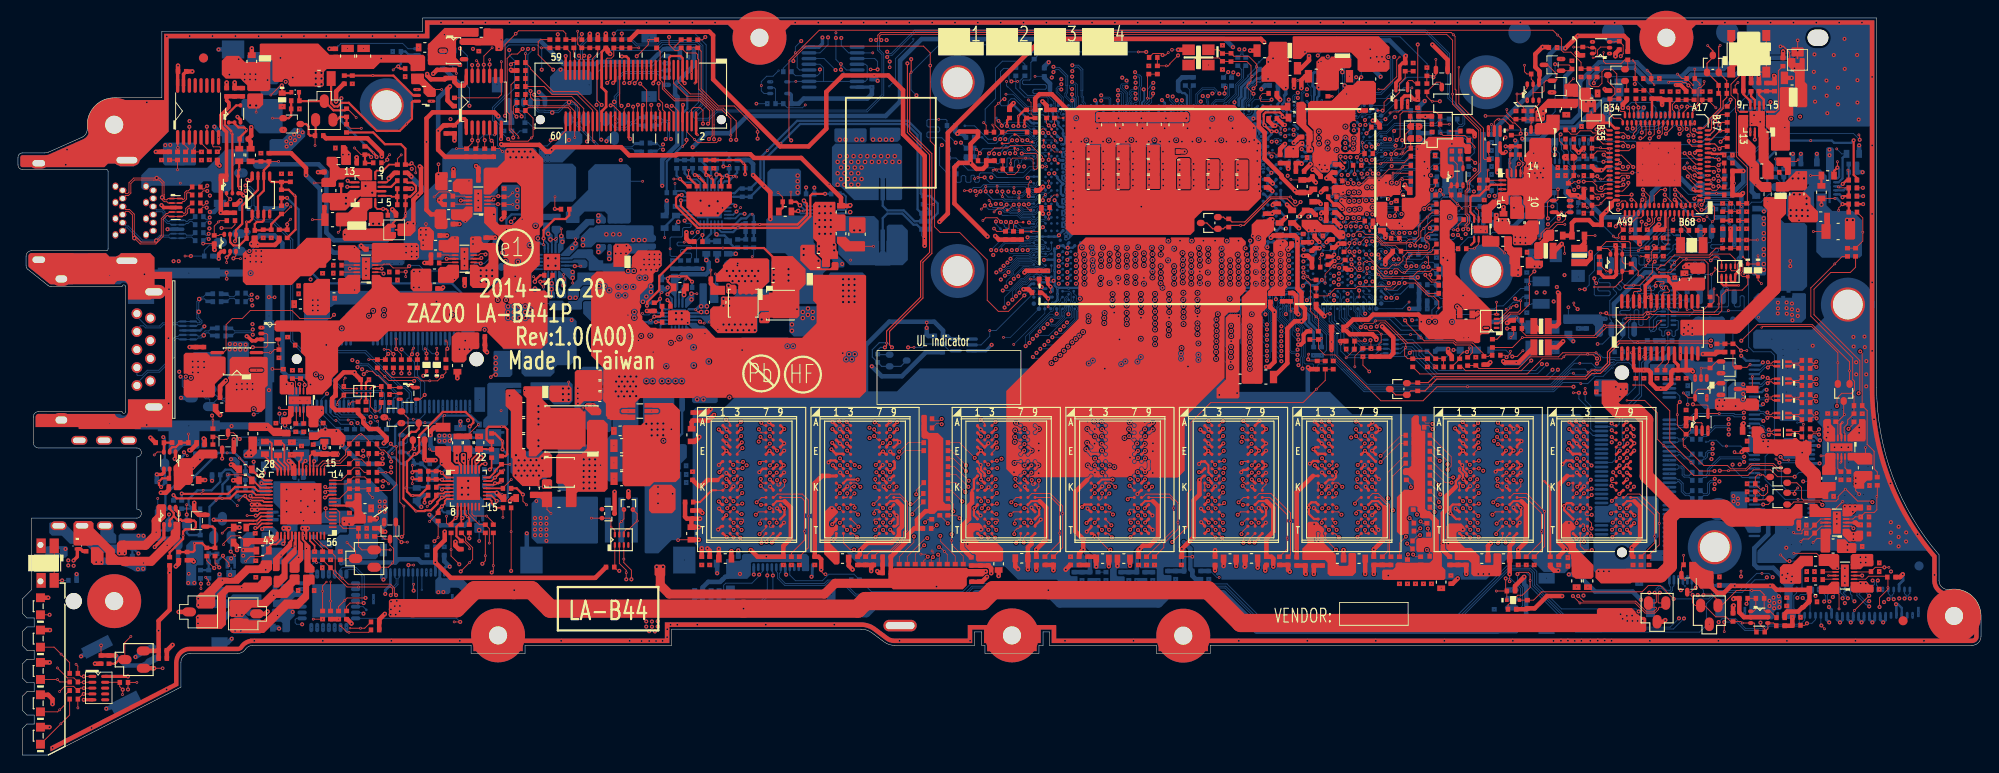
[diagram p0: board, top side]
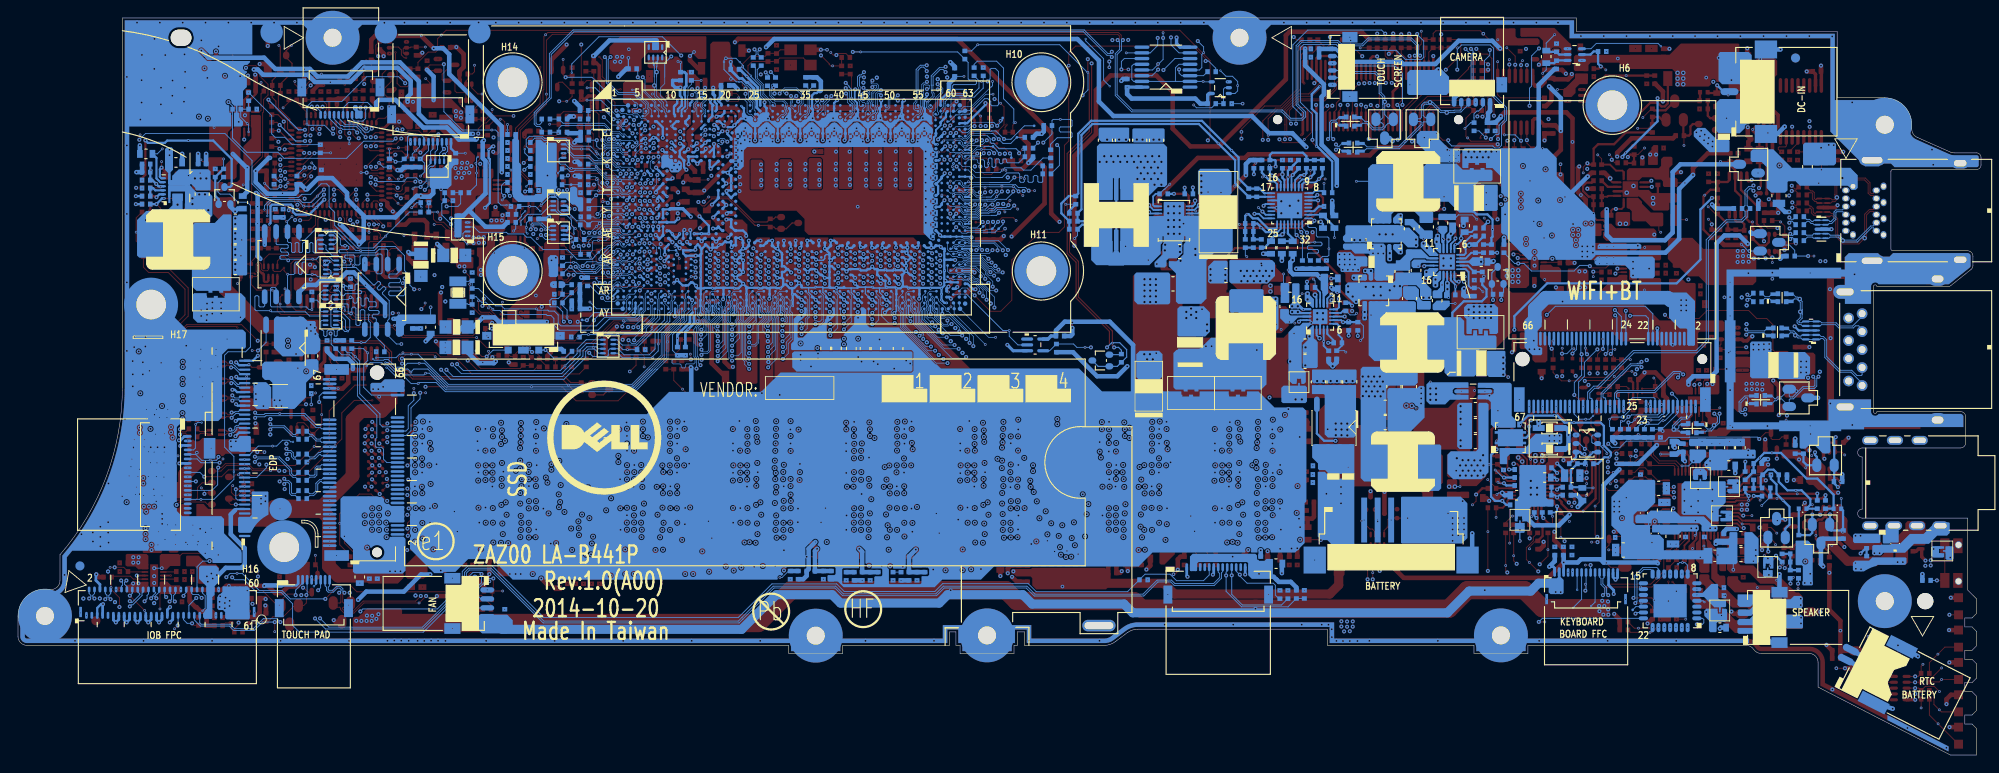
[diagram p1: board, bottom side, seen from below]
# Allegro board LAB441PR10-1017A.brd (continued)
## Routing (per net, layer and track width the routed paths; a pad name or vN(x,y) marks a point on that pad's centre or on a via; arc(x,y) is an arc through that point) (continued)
EDP_TXP_P1_C: length 1.8
  TOP w0.102: C1061.2 198,39.6 197.3,39.6 197.15,39.45 L56.1 196.81,39.45
EDP_TXP_P1_CONN: length 2.8
  TOP w0.102: v1(194.47,39.43) 194.66,39.61 195.02,39.61 195.19,39.45 L56.2
  BOTTOM w0.102: JEDP.31 193.6,39.37 193.74,39.52 194.38,39.52 v1(194.47,39.43)
EDP_TXP_P2: length 119.8
  TOP w0.102: C1067.1 199.65,41.46 199.81,41.46 v1(200,41.27)
  IN1 w0.071: v1(122.33,73.97) 122.54,73.76 122.92,73.76 123.05,73.64 123.05,72.32 123.39,71.98 125.47,71.98 127.02,70.43 137.66,70.43 138.73,71.5 146.64,71.5 147.89,72.75 153.15,72.75 153.59,72.32 158.91,72.32 160.66,70.57 165.93,70.57 167.67,72.31 177.39,72.31 177.99,72.91 180.57,72.91 180.72,72.76 189.14,72.76 192.12,69.78 192.12,68.58 192.72,67.99 192.72,62.89 192.42,62.59 192.42,61.95 192.25,61.78 191.28,61.78 191.18,61.67 191.18,61.52 191.28,61.42 192.2,61.42 192.4,61.22 192.4,60.39 192.2,60.19 191.45,60.19 191.34,60.09 191.34,59.94 191.45,59.84 192.27,59.84 192.42,59.69 192.42,59.36 192.27,59.22 191.74,59.22 191.33,58.8 191.33,56.66 192.42,55.56 192.42,52.1 194.59,49.93 194.59,48.64 198.49,44.74 198.49,42.82 198.78,42.53 200.2,42.53 200.53,42.2 200.53,41.65 200.39,41.51 200.24,41.51 v1(200,41.27)
  BOTTOM w0.076: UCPU1.C46 123.79,70.82 123.29,71.32 123.18,71.33 123.15,71.35 123.11,71.35 123.07,71.39 123.04,71.41 123,71.46 122.95,71.51 122.95,71.53 122.93,71.56 122.93,71.7 122.95,71.72 122.95,71.74 122.99,71.78 122.99,72.12 122.95,72.16 122.95,72.19 122.93,72.21 122.93,72.28 122.93,73.58 122.7,73.81 122.49,73.81 v1(122.33,73.97)
EDP_TXP_P2_C: length 1.7
  TOP w0.102: L59.1 197.15,41.36 197.26,41.47 198.04,41.47 C1067.2
EDP_TXP_P2_CONN: length 3
  TOP w0.102: v1(194.59,41.37) 194.74,41.53 195.03,41.53 195.2,41.36 L59.2
  BOTTOM w0.102: JEDP.34 193.6,40.87 193.75,41.02 193.96,41.02 194.15,41.21 194.15,41.22 194.39,41.46 194.51,41.46 194.59,41.38 v1(194.59,41.37)
EDP_TXP_P3: length 119.6
  TOP w0.102: C1069.1 199.65,43.36 199.8,43.36 v1(199.99,43.17)
  IN1 w0.071: v1(199.99,43.17) 199.76,43.4 199.34,43.4 199.12,43.63 199.12,44.87 198.74,45.24 198.74,45.45 198.97,45.69 198.97,45.79 198.82,45.94 198.72,45.94 198.49,45.71 198.28,45.71 198.05,45.93 198.05,46.14 198.28,46.38 198.28,46.48 198.13,46.63 198.03,46.63 197.8,46.4 197.59,46.4 195.13,48.85 195.13,50.14 192.96,52.32 192.96,62.11 193.25,62.41 193.25,67.94 193.55,68.24 193.55,69.38 192.23,70.71 191.95,70.71 189.36,73.29 180.96,73.29 180.81,73.44 177.78,73.44 177.17,72.83 175.41,72.83 174.84,73.4 168.02,73.4 165.71,71.1 160.88,71.1 158.79,73.19 147.65,73.19 146.49,72.03 137.72,72.03 136.92,71.23 132.72,71.23 132.32,70.83 130.47,70.83 130.08,71.22 126.94,71.22 125.62,72.55 124.09,72.55 123.64,73 123.64,75.21 123.39,75.46 123.39,76.05 123.21,76.22 121.7,76.22 121,75.52 121,73.2 120.84,73.04 120.69,73.04 v1(120.46,72.81)
  BOTTOM w0.076: UCPU1.B49 121.85,71.79 121.77,71.86 121.54,71.86 121.35,72.05 121.35,72.95 121.29,73.01 120.66,73.01 v1(120.46,72.81)
EDP_TXP_P3_C: length 1.7
  TOP w0.102: L60.1 197.18,43.26 197.32,43.4 198.03,43.4 198.39,43.03 C1069.2
EDP_TXP_P3_CONN: length 3
  TOP w0.102: v1(194.61,43.12) 194.62,43.12 194.87,43.37 195.13,43.37 195.24,43.26 L60.2
  BOTTOM w0.102: JEDP.37 193.54,42.37 194.3,43.12 v1(194.61,43.12)
EN_0.675VSP: length 6
  TOP w0.203: PC614.1 70.96,48.15 v1(70.95,48.16)
  BOTTOM w0.102: PR610.1 69.1,48.16 68.69,47.75 68.69,46.44 v2(69,46.12)
  BOTTOM w0.203: v1(70.95,48.16) 71.17,48.38 72.01,48.38 PU600.7
  BOTTOM w0.254: v1(70.95,48.16) PR609.2 PR610.1
EN_1.5V: length 5.7
  GND1 w0.102: v3(192.65,69.33) 192.65,69.74 v4(192.6,69.8)
  GND3 w0.102: v5(192.66,69.33) 192.66,69.73 v4(192.6,69.8)
  BOTTOM w0.102: PR410.2 192.67,72.78 PC400.1 PR400.2 193.54,70.97 v2(192.82,70.25) 192.66,70.1 v5(192.66,69.33)
EN_1.8V: length 9.2
  TOP w0.102: PR411.2 38.16,66.8 v2(37.42,67.53)
  TOP w0.203: PU401.13 36.92,63.71 36.74,63.89 v1(36.66,63.89) ; PR405.2 39.47,65.86 PC408.1
  TOP w0.254: PR411.2 38.59,66.8 ; 38.59,66.8 39.01,66.8 v1(39.27,66.53) ; 38.59,66.8 PC408.1
  IN1 w0.254: v1(39.27,66.53) 38.54,66.53 36.66,64.66 v1(36.66,63.89)
EN_1.35V: length 3.7
  TOP w0.102: v2(70.35,48.37) 70.76,48.78 v1(70.77,48.78)
  TOP w0.254: v1(70.77,48.78) 71.4,48.78 71.65,49.02 PC613.1 PR608.2
  BOTTOM w0.203: PU600.8 72.01,48.78 v1(70.77,48.78)
EN_+1.05SP: length 5.5
  TOP w0.102: R272.2 R271.2 205.16,57.18 v2(205.16,58.17) 205.16,59.75 PR500.2
EN_CAM: length 118.9
  TOP w0.102: v2(55.03,61.24) R1177.1 54.02,61.29 v1(53.38,61.29) U718.3
  IN3 w0.086: 110.07,67.97 110.04,67.95 107.31,67.95 106.15,66.79 101.51,66.79 98.62,69.67 75.59,69.67 74.31,70.96 67.5,70.96 65.79,69.24 56.26,69.24 55.29,68.27 54.92,68.27 54,67.36 54,61.91 v1(53.38,61.29)
  IN3 w0.089: 110.07,67.97 112.79,67.97 112.94,68.12 115.33,68.12 115.93,67.51 136.4,67.51 137.41,66.51 138.35,66.51 138.64,66.22 140.44,66.22 140.9,65.76 140.9,65.06 141.1,64.86 142.07,64.86 143.2,63.73 143.2,61.5 142.14,60.45 142.14,59.79 142.78,59.15 143.95,59.15 144.32,58.78 145.42,58.78 147.69,56.5 147.69,55.84 147.9,55.63 148.77,55.63 v1(149.17,55.23)
  BOTTOM w0.076: UCPU1.AM4 149.65,54.75 v1(149.17,55.23)
EN_INVPWR: length 38.4
  TOP w0.102: Q71.2 189.29,43.78 188.91,43.78 R1161.1 187.2,43.05 v2(187.19,43.04) 187.16,43.01 v3(187.16,41.94)
  GND1 w0.102: v4(182.22,71.54) 182.22,71.19 v3(182.22,71.19) ; v4(187.1,42.31) 187.16,42.24 v3(187.16,41.94)
  IN4 w0.071: v4(187.1,42.31) 186.91,42.11 186.15,42.11 185.75,42.51 185.75,44.46 184.03,46.18 184.03,46.93 183.68,47.28 183.55,47.28 182.77,48.05 182.77,52.57 182.91,52.71 182.91,55.42 183.15,55.66 183.15,58 184.65,59.49 184.65,63.52 183.93,64.24 183.93,69.64 183.49,70.07 182.9,70.07 182.52,70.45 182.52,71.24 v4(182.22,71.54)
EN_MPOWER: length 96.5
  TOP w0.102: v3(162.16,60.83) 162.44,60.55 U34.3 ; 203.87,40.24 204.23,40.61 204.23,41.59 204.04,41.78 204.04,44.17 199.38,48.83 199.38,51.97 v2(202.05,54.64) 202.88,55.47 R272.1 ; 203.87,40.24 204.18,39.92 R269.2 R270.2 203.48,37.28 203.48,36.85 203.09,36.46 203.09,35.86 203.18,35.77 U715.3 ; 203.87,40.24 202.82,40.24 202.29,39.71 v1(202.29,38.83)
  GND1 w0.102: v4(162.53,60.55) 162.25,60.83 v3(162.16,60.83)
  IN1 w0.071: v4(187.89,59.89) 187.67,60.11 186.83,60.11 186.77,60.17 181.15,60.17 180.78,59.8 178.8,59.8 178.58,59.58 177.26,59.58 176.28,58.6 173.16,58.6 171.65,60.12 167.67,60.12 167.38,60.41 166.31,60.41 165.33,61.39 164.42,61.39 163.58,60.55 v4(162.53,60.55)
  IN2 w0.086: v1(189.12,63.86) 189.55,63.43 189.55,61.34 189.73,61.16 189.73,54.77 189.88,54.63 189.88,51.67 193.75,47.8 195.27,47.8 198.16,44.91 198.16,39.69 199.02,38.83 v1(202.29,38.83)
  IN3 w0.086: v4(187.89,59.89) 187.8,59.98 187.8,63.37 188.12,63.69 188.94,63.69 v1(189.12,63.86)
  BOTTOM w0.102: v1(189.12,63.86) 189.36,63.86 189.83,64.33 R1163.1
ENVDD: length 4.8
  TOP w0.102: U715.5 202.38,36.85 R1026.2 202.35,37.09 203.13,37.86 v2(203.13,37.87) 203.04,37.96 D93.1
ENVDD_PCH: length 95
  TOP w0.089: 153.27,75.41 151.92,74.07 v3(151.3,74.07)
  TOP w0.102: v3(153.65,77.66) 153.33,77.34 153.33,75.47 153.27,75.41 ; v3(193.91,47.56) 194.02,47.68 199.46,47.68 202.39,44.75 v2(202.39,43.63) 202.39,41.29 D93.3 ; UE5.A7 188.5,64.99 v1(188.61,64.87)
  GND1 w0.089: v3(151.3,74.07) 151.27,74.07 151.04,73.83 v4(150.37,73.83)
  GND1 w0.102: v3(153.65,77.66) 153.65,77.92 v4(153.98,78.25) ; v3(193.91,47.56) 193.91,47.46 v4(194.11,47.26)
  IN2 w0.086: v1(188.61,64.87) 188.07,64.32 188.07,62.29 189.36,61 189.36,54.62 189.5,54.47 189.5,51.52 193.76,47.26 v4(194.11,47.26)
  IN3 w0.086: v4(153.98,78.25) 154.25,78.52 159.31,78.52 160.56,79.77 166.07,79.77 166.7,79.14 168.16,79.14 168.78,79.77 177.7,79.77 178.96,78.51 179.89,78.51 182.62,75.77 184.99,75.77 185.96,76.74 187.44,76.74 187.89,76.29 187.89,65.59 v1(188.61,64.87)
  GND3 w0.089: v5(149.99,74) 150.2,74 v4(150.37,73.83)
  BOTTOM w0.076: UCPU1.C6 147.83,71.75 148.17,72.09 148.17,72.51 149.66,74 v5(149.99,74)
F-IMAX: length 5.4
  TOP w0.102: v1(74.58,64.28) v2(74.58,65.06)
  TOP w0.254: PR708.1 75.52,63.33 v1(74.58,64.28)
  BOTTOM w0.203: v1(74.58,64.28) 74.82,64.03 75.5,64.03 75.88,63.65 PU700.10
  BOTTOM w0.254: v1(74.58,64.28) 74.13,64.72 PR703.2
FAN1_PWM: length 109.1
  TOP w0.102: R1103.1 165.7,16.7 166.78,17.78 167.3,17.78 168.17,18.64 v2(168.17,19.41) 168.17,20.13 167.96,20.33 166.95,20.33 v1(166.76,20.14)
  GND1 w0.102: v3(182.72,71.19) 182.72,70.97 182.92,70.77 v4(182.92,70.57)
  IN2 w0.086: v4(182.92,70.57) 182.1,69.76 182.1,68.49 182.76,67.83 182.76,61.59 183.1,61.26 183.1,51.8 184.7,50.2 185.97,50.2 189.43,46.74 191.63,46.74 193.15,45.23 194.79,45.23 195.74,44.27 195.74,36.97 196.61,36.11 196.61,26.3 194.56,24.25 194.56,21.84 194.94,21.46 194.94,20.21 v1(194.49,19.77)
  BOTTOM w0.102: v1(194.49,19.77) 194.23,19.5 193.17,19.5 191.76,18.09 189.03,18.09 187.77,16.83 187.77,14.43 187.01,13.67 173.24,13.67 168.86,18.05 168.15,18.75 168.15,19.87 167.71,20.32 166.93,20.32 v1(166.76,20.14) 166.76,19.17 167.31,18.61 167.31,16.61 167.08,16.37 JFAN1.3
FAN1_TACH: length 92.5
  TOP w0.102: UE5.B22 184.47,70.34 184.47,69.97 v1(184.77,69.66) ; v1(184.13,17.37) 182.64,18.86 181.31,18.86 180.61,18.16 169.47,18.16 168.55,17.23 R884.1 D81.2
  IN2 w0.086: v1(184.77,69.66) 184.41,69.3 184.41,67.77 184.65,67.53 184.65,58.96 183.74,58.04 183.74,55.82 184.03,55.52 184.03,51.4 184.85,50.57 186.15,50.57 189.61,47.12 191.79,47.12 193.31,45.6 194.94,45.6 196.12,44.43 196.12,37.17 196.98,36.3 196.98,30.3 197.99,29.29 197.99,27.4 194.75,24.15 194.75,21.94 195.14,21.55 v1(195.14,19.78)
  BOTTOM w0.102: v1(195.14,19.78) 194.71,20.21 v2(193.95,20.21) 193.37,20.21 191.46,18.3 188.94,18.3 188.02,17.37 v1(184.13,17.37)
FB_1.5V: length 3.5
  TOP w0.254: PC402.2 PR401.2 PR403.1 193.61,73.46 194.15,72.92 PU400.5
FB_1.8V: length 3.5
  TOP w0.203: PU401.5 40.48,62.21 41.46,62.21 41.56,62.12 PC410.2 ; PC410.2 PR408.1 ; PC410.2 PR406.2
FB_1.35V: length 4.9
  BOTTOM w0.102: 71.65,44.98 70.8,44.98 v2(70.64,44.83)
  BOTTOM w0.203: PR607.1 71.65,44.98 71.07,45.56 PR605.1 71.07,46.36 71.45,46.74 71.45,47.82 71.62,47.98 72.01,47.98 PU600.6
FB_3V: length 2.8
  BOTTOM w0.203: PU300.4 57.31,55.25 56.68,55.88 PR302.2 PR300.2
FB_5V: length 2.7
  BOTTOM w0.203: PU300.2 57.88,54.45 57.06,54.45 PR303.1 PR301.2
FWP#: length 11.8
  TOP w0.102: v1(184.28,62.35) 184.97,61.66 184.97,61.14 UE5.B65 ; RE81.2 v3(191.36,59.46)
  GND1 w0.102: v4(190.85,59.67) 191.05,59.46 v3(191.36,59.46)
  GND3 w0.102: v4(190.85,59.67) 190.58,59.93 v5(190.58,59.97)
  BOTTOM w0.102: v1(184.28,62.35) 185.57,61.06 v2(186.54,61.06) 187.1,61.61 190.12,61.61 190.58,61.15 v5(190.58,59.97)
GPIO88_SLP_S0#: length 18.2
  TOP w0.076: v2(149.52,68.13) 149.52,67.52 149.75,67.29 R253.2 149.31,66.91 v1(148.9,66.5)
  IN2 w0.086: v1(148.9,66.5) 149.1,66.7 151.69,66.7 151.9,66.49 154.02,66.49 155.08,67.55 159.44,67.55 159.63,67.36 160.83,67.36 v4(161.13,67.65)
  GND3 w0.102: v5(161.95,67.41) 161.37,67.41 v4(161.13,67.65)
  BOTTOM w0.076: v1(148.9,66.5) 148.9,66 148.96,65.94 UCPU1.L5
  BOTTOM w0.102: v5(161.95,67.41) 161.95,66.99 RH198.1
H_CATERR#: length 4.7
  TOP w0.089: v1(110.91,66.96) 110.84,67.03 T2.1
  BOTTOM w0.076: v1(110.91,66.96) 111.31,66.55 112.49,66.55 112.74,66.3 113.1,66.3 113.27,66.47 113.27,66.65 113.5,66.89 114.02,66.89 UCPU1.K61
H_CPU_SVIDALRT#: length 11.5
  BOTTOM w0.076: UCPU1.L62 113.24,65.46 112.47,65.46 111.82,64.81 110.07,64.81
  BOTTOM w0.102: RC94.2 104.31,66.42 105.66,65.08 106.49,65.08 106.75,65.33 108.57,65.33 v2(108.82,65.08) 109.09,64.81 110.07,64.81
H_CPU_SVIDCLK: length 14.4
  BOTTOM w0.076: 110.07,64.25 111.79,64.25 112.63,65.1 UCPU1.N63
  BOTTOM w0.102: CC243.1 RC92.2 104.35,63.81 104.44,63.72 104.77,63.72 104.89,63.84 104.89,64.34 105.02,64.47 105.27,64.47 105.4,64.34 105.4,63.84 105.53,63.72 105.88,63.72 105.99,63.82 105.99,64.4 106.09,64.5 106.29,64.5 106.39,64.4 v2(106.39,64.12) 106.39,63.82 106.49,63.72 106.79,63.72 106.91,63.84 106.91,64.63 107.04,64.76 108.35,64.76 108.86,64.25 110.07,64.25
H_CPU_SVIDDAT: length 13.1
  BOTTOM w0.076: UCPU1.L63 112.97,65.85 112.59,66.22 111.65,66.22 111.57,66.15 111.57,65.91 111.5,65.84 111.35,65.84 111.27,65.91 111.27,66.15 111.19,66.22 110.96,66.22
  BOTTOM w0.102: 110.96,66.22 110.83,66.09 110.83,65.48 110.7,65.36 110.52,65.36 110.4,65.48 v2(110.4,65.82) 110.4,66.32 110.29,66.42 110.09,66.42 109.99,66.32 109.99,65.49 109.87,65.37 109.69,65.37 109.57,65.49 109.57,66.22 109.47,66.32 109.27,66.32 109.18,66.23 109.18,65.91 109.06,65.79 108.89,65.79 108.77,65.91 108.77,66.21 108.67,66.31 108.47,66.31 108.36,66.21 108.36,65.99 108.26,65.89 107.01,65.89 R1371.2 RC96.2
H_CPUPWRGD_R: length 7.5
  BOTTOM w0.076: UCPU1.C61 114.62,71.06 114.62,72.07 114.55,72.14 114.55,73.06 114.42,73.19 111.97,73.19
  BOTTOM w0.102: 111.97,73.19 110.96,74.19 RC44.2
H_DRAMRST#: length 16.1
  TOP w0.102: v2(143.54,44.6) 143.48,44.53 v1(143.48,44.02) 143.65,43.84 RD24.1 RD28.1
  BOTTOM w0.076: UCPU1.AV15 142.7,50.71 142.7,49.22 142.74,49.18 142.74,48.85 142.56,48.67 142.56,48.08 143,47.64 143,47.52 143.15,47.37 143.15,44.3 143.02,44.17 143.02,43.64 143.15,43.51 143.98,43.51 144.05,43.44 144.05,43.19 144.18,43.07 144.43,43.07 144.56,43.19 144.56,43.38 144.68,43.51 145.44,43.51 145.57,43.64 145.57,43.89 145.44,44.02 v1(143.48,44.02)
H_PROCHOT#: length 583.1
  TOP w0.089: v1(111.29,65.48) 111.29,65.04 110.83,64.58 110.07,64.58
  TOP w0.102: PR461.2 24.14,59.01 23.75,58.62 v1(22.64,58.62) ; RC41.1 109.52,65.13 110.07,64.58 ; RC41.1 RC43.2 ; RC41.1 108.58,65.19 v2(108.45,65.06) ; PC718.1 76.12,57.84 v1(76.12,57.85) ; PR216.1 v1(50.19,24.11) ; UE5.A46 176.5,62.99 176.22,62.71 175.78,62.71 175.58,62.9 175.58,63.32 175.11,63.79 v1(174.12,63.79)
  IN2 w0.086: v4(99.57,80.01) 99.1,80.01 98.88,80.22 87.28,80.22 83.92,76.86 77.69,76.86 76.17,78.37 71.69,78.37 70.79,79.27 59.72,79.27 58.98,80.01 49.39,80.01 46.45,77.07 39.12,77.07 36.44,74.39 36.44,71.69 31.63,66.88 31.63,48.4 34.69,45.34 34.69,41.46 33.94,40.71 33.94,39.48 36.95,36.47 39.67,36.47 40.54,37.35 42.61,37.35 44.49,39.23 49.78,39.23 52.61,42.06 52.61,45.64 52.77,45.81 57.46,45.81 58.23,45.03 58.23,42.83 59.72,41.35 63.09,41.35 63.83,42.1 66.27,42.1 67.1,42.93 69.3,42.93 71.66,45.29 71.66,48.59 73.37,50.31 73.37,52.21 74.39,53.23 76.55,53.23 77.35,54.03 77.35,56.61 v1(76.12,57.85)
  IN3 w0.086: v1(174.12,63.79) 172.49,65.42 172.49,66.77 173.15,67.43 173.15,69.38 175.67,71.9 175.67,76.52 175.18,77.01 175.18,78.27 174.57,78.88 v4(174.57,78.88)
  IN4 w0.071: v1(111.29,65.48) 110.33,66.44 107.85,66.44 107.62,66.66 107.62,67.63 107.14,68.12 107.14,69.1 105.37,70.87 102.78,70.87 100.39,73.26 100.39,73.44 99.35,74.48 97.33,74.48 v4(97.25,74.41) ; v4(99.57,80.01) 99.62,80.01 100.36,80.74 172.7,80.74 174.57,78.88 v4(174.57,78.88) ; v4(35.44,78.51) 34.81,77.89 25.27,77.89 23.73,76.34 23.73,67.13 23.11,66.51 21.25,66.51 20.83,66.09 20.83,65.4 19.65,64.22 19.65,57.03 21.96,54.72 21.96,52.61 26.75,47.82 26.75,40.32 27.42,39.65 33.04,39.65 34.64,41.25 39.49,41.25 41.5,43.26 48.5,43.26 49.31,42.45 51.94,42.45 52.81,41.58 62.78,41.58 63.4,42.2 65.97,42.2 66.59,42.83 69.12,42.83 71.67,45.38 71.67,48.88 73.25,50.46 73.25,53.86 76.12,56.73 v1(76.12,57.85) ; v1(50.19,24.11) 47.18,24.11 44.33,26.96 44.33,30.05 44.82,30.55 44.82,39.08 46.99,41.25 62.98,41.25 63.73,42 66.14,42 66.74,42.6 69.28,42.6 71.98,45.29 71.98,48.78 73.56,50.37 73.56,53.74 76.52,56.69 76.52,57.72 76.39,57.85 v1(76.12,57.85) ; v1(22.64,58.62) 22.76,58.5 22.76,52.08 27.06,47.79 27.06,40.39 27.54,39.91 32.91,39.91 34.52,41.53 39.35,41.53 41.44,43.61 48.57,43.61 49.46,42.72 51.99,42.72 52.9,41.8 62.57,41.8 63.26,42.5 65.88,42.5 66.46,43.08 68.99,43.08 71.37,45.45 71.37,48.97 72.95,50.56 72.95,54.01 75.7,56.76 75.7,57.68 75.87,57.85 v1(76.12,57.85)
  GND3 w0.102: v5(35.6,78.86) 35.6,78.68 v4(35.44,78.51) ; v4(99.57,80.01) v5(99.57,79.66) ; v4(97.25,74.41) v5(96.89,74.41)
  BOTTOM w0.102: v5(99.57,79.66) 99.57,79.46 97.58,77.47 97.58,75.09 v5(96.89,74.41) ; PR723.2 75.47,57.2 v1(76.12,57.85) 76.28,58.02 PU700.30 ; v5(35.6,78.86) 35.92,79.17 42.78,79.17 43.37,78.58 PQ102.3
H_PROCHOT#_R: length 9.9
  TOP w0.089: RC41.2 110.43,66.23 110.61,66.41 v2(112.07,66.41) 112.77,66.41 112.89,66.28 112.89,65.29 113.02,65.17 113.22,65.17 113.35,65.29 113.35,66.79 113.22,66.92 v1(111.63,66.92)
  BOTTOM w0.076: v1(111.63,66.92) 111.63,66.92 111.82,66.72 112.85,66.72 UCPU1.K63
H_THERMTRIP#: length 89.2
  TOP w0.076: v1(110.48,74.94) v2(111.16,74.94)
  TOP w0.102: v3(176.33,78.17) 176.33,77.15 176.57,76.91 178.26,76.91 178.69,77.34 RC149.1 179.02,76.6 QE9.3
  GND1 w0.102: v4(176.59,78.69) 176.33,78.44 v3(176.33,78.17)
  IN4 w0.071: 110.85,75.43 115.19,79.78 165.97,79.78 166.03,79.71 172.46,79.71 174.19,77.99 175.01,77.99 175.71,78.69 v4(176.59,78.69)
  IN4 w0.076: v1(110.48,74.94) 110.48,75.07 110.85,75.43
  BOTTOM w0.076: UCPU1.D60 114.75,70.48 114.55,70.68
  BOTTOM w0.102: v1(110.48,74.94) 110.2,75.22 110.2,76.27 110.08,76.39 109.62,76.39 109.26,76.04 109.26,72.36 109.39,72.23 110,72.23 110.13,72.36 110.13,72.7 110.44,73.02 110.81,73.02 112.19,71.64 112.19,71.61 112.51,71.29 113.31,71.29 113.38,71.23 114,71.23 114.55,70.68
H_VR_READY: length 58.8
  TOP w0.102: v2(107.4,70.35) 107.67,70.08 RH4.2 RC201.1 108.54,69.85 108.37,70.01 v3(108.37,70.12)
  GND1 w0.102: v4(107.99,70.27) 108.14,70.12 v3(108.37,70.12)
  IN2 w0.086: v4(73.46,61.04) 73.25,61.25 73.25,64.85 76.15,67.75 80.59,67.75 83.57,70.73 99.23,70.73 100.46,69.5 107.22,69.5 v4(107.99,70.27)
  GND3 w0.102: v4(107.99,70.27) 107.9,70.36 v5(107.56,70.36)
  GND3 w0.254: v5(73.07,61.04) v4(73.46,61.04)
  BOTTOM w0.102: RC152.1 111.98,76.84 111.62,77.19 109.48,77.19 108.7,76.42 108.7,73.01 107.56,71.87 v5(107.56,70.36)
  BOTTOM w0.203: PU700.3 74.16,60.5
  BOTTOM w0.254: 74.16,60.5 73.63,61.04 v5(73.07,61.04)
HD_SOC_SEL: length 10.3
  TOP w0.102: v2(41.4,22.82) QA7.3 38.24,22.82 37.86,23.2 RA86.2 RA82.2 36.16,25.22 35.78,25.6 35.78,27 35.43,27.35 35.01,27.35 UA2.6
HDA#_I2S_SEL: length 196.2
  TOP w0.102: QA8.2 42.02,24.32 v1(42.65,23.69) v2(43.3,23.69) ; v1(179.63,65.42) 178.31,66.74 UE5.B41
  IN3 w0.086: v1(179.63,65.42) 179.99,65.06 179.99,63.66 178.82,62.49 178.82,60.01 178.07,59.26 178.07,57.86 178.35,57.58 178.35,55.51 178.07,55.23 178.07,51.89 178.79,51.17 178.79,46.38 180.49,44.68 180.49,40.4 181.94,38.94 181.94,23.82 177.78,19.66 175.27,19.66 174.52,18.91 171.81,18.91 171.22,18.31 141.56,18.31 140.67,19.2 126.64,19.2 125.2,17.76 119.08,17.76 117.45,19.39 110.12,19.39 108.66,20.84 103.94,20.84 102.78,19.68 93.55,19.68 93.13,19.26 70.91,19.26 70.07,20.11 54.16,20.11 53.56,20.71 51.02,20.71 49.64,22.08 45.21,22.08 45.11,21.98 44.36,21.98 v1(42.65,23.69)
HDD_DET#: length 4.2
  BOTTOM w0.076: 154.53,64.34 154.09,64.34 v2(153.9,64.16) 153.8,64.05 153.8,63.51
  BOTTOM w0.089: UCPU1.U1 151.74,62.95 153.23,62.95 153.8,63.51
  BOTTOM w0.102: RH466.1 154.53,64.34
HOST_ALERT1_R_N: length 18.4
  IN2 w0.086: v4(161.99,61.26) 161.59,60.86 159.35,60.86 157.84,59.34 152.37,59.34 151.96,59.76 v1(149.14,59.76)
  GND3 w0.102: v4(161.99,61.26) 161.9,61.17 v5(161.9,60.5)
  BOTTOM w0.076: UCPU1.AD6 148.58,59.27 149.06,59.76 v1(149.14,59.76)
  BOTTOM w0.102: v5(161.9,60.5) 162.29,60.11 162.29,59.93 RH270.1 162.96,58.54 v2(163.2,58.3)
HOST_DEBUG_TX: length 9.2
  TOP w0.102: v1(179.06,65.44) 179.06,65.15 178.96,65.05 178.31,65.05 178.12,65.24 177.96,65.24 177.96,65.24 UE5.B44
  IN1 w0.071: v1(179.06,65.44) 178.71,65.8 177.97,65.8 177.8,65.63 174.74,65.63 v4(174.54,65.83)
  GND3 w0.102: v4(174.54,65.83) 174.46,65.9 v5(174.46,66.32)
  BOTTOM w0.102: JDEG1.8 173.66,67.67 v2(174.12,67.21) 174.46,66.86 v5(174.46,66.32)
HP2_D_L: length 11
  TOP w0.203: UA2.32 27.91,29.35 26.69,29.35
  TOP w0.254: v1(18.21,29.09) 18.23,29.06 v2(20.44,29.06) 23.38,29.06 24.14,29.82 26.23,29.82 26.69,29.35
  BOTTOM w0.254: RA17.1 v1(18.21,29.09)
HP2_D_L_C: length 15.2
  TOP w0.102: v1(18.77,26.75) v2(18.77,27.85)
  IN4 w0.254: v1(18.77,26.75) 16.87,24.86 12.97,24.86 JHP1.1
  BOTTOM w0.254: v1(18.77,26.75) DA2.3 18.77,24.72 19.02,24.47 CA29.2 20.27,24.47 LA7.2
HP2_D_L_R1: length 11.4
  BOTTOM w0.254: 19.42,27.41 LA7.1 ; 19.42,27.41 RA17.2 ; 19.42,27.41 18.98,27.84 18.98,28.47 19.96,29.45 v2(20.59,29.45) 21.53,29.45 22.5,30.41 RA61.1 23.07,31.75 23.7,31.75 RA48.2 24.5,30.95 24.5,29.87 RA50.2
HP2_D_R: length 11.8
  TOP w0.203: UA2.33 27.91,28.95 26.45,28.95 26.09,29.31
  TOP w0.254: v1(17.3,28.91) 17.66,28.55 v2(22.7,28.55) 23.59,28.55 24.35,29.31 26.09,29.31
  BOTTOM w0.254: RA15.1 v1(17.3,28.91)
HP2_D_R_C: length 26.4
  IN4 w0.254: JHP1.2 6.82,35.57 7.08,35.84 16.48,35.84 16.8,35.52 v1(16.8,26.77)
  BOTTOM w0.102: LA6.2 v2(15.54,28.55)
  BOTTOM w0.254: v1(16.8,26.77) 16.8,25.68 DA2.2 16.83,25.15 16.67,24.98 CA69.1 15.34,25.01 15.34,27.19 LA6.2
HP2_D_R_R2: length 16
  BOTTOM w0.254: RA49.2 26.21,30.62 RA51.2 25.29,32.43 RA60.1 25.28,32.43 24.1,33.61 v2(23.26,33.61) 22.26,33.61 19.4,30.76 18.19,30.76 16.39,28.96 LA6.1 16.41,27.41 RA15.2
I2C0_SCK: length 9.7
  BOTTOM w0.076: 153.27,70.28 153.11,70.28 152.17,69.34 151.4,69.34 151.14,69.09 150.84,69.09 150.52,68.76 UCPU1.F3
  BOTTOM w0.102: RA8.2 RH425.1 157.69,70.28 153.27,70.28
I2C0_SCK_DSP: length 209.4
  TOP w0.102: v1(34.16,29.83) 34.35,29.64 34.47,29.64 34.58,29.75 35.01,29.75 UA2.12
  IN1 w0.071: v1(96.66,77.66) 96.46,77.86 87.95,77.86 85.8,75.72 79.37,75.72 77.51,77.58 72.36,77.58 71.9,77.12 62.08,77.12 61.07,78.13 59.18,78.13 58.21,79.1 49.01,79.1 47.55,77.64 37.56,77.64 33.84,73.91 29.19,73.91 23.27,67.98 19.25,67.98 19.11,67.84 19.11,57.65 20.55,56.21 20.55,50.88 25.22,46.21 31.89,46.21 34.42,43.67 34.42,41.11 33.57,40.25 33.57,29.82 33.73,29.65 33.98,29.65 v1(34.16,29.83)
  BOTTOM w0.102: v1(96.66,77.66) 96.86,77.85 97.2,77.85 99.82,80.47 156.49,80.47 159.01,77.95 159.01,73.09 160.7,71.41 160.7,70.28 160.55,70.13 160.29,70.13 160.06,70.36 RA8.1
I2C0_SDA: length 9.3
  BOTTOM w0.076: 153.27,70.03 153.09,70.03 152.24,69.18 151.48,69.18 151.11,68.8 UCPU1.F2
  BOTTOM w0.102: RA7.2 RH424.1 158.16,69.74 157.87,70.03 153.27,70.03
I2C0_SDA_DSP: length 210.7
  TOP w0.102: UA2.11 34.58,29.35 34.5,29.44 34.35,29.44 v1(34.16,29.25)
  IN1 w0.071: v1(34.16,29.25) 33.93,29.48 33.66,29.48 33.39,29.74 33.39,40.32 34.25,41.18 34.25,43.6 31.82,46.03 25.15,46.03 20.38,50.81 20.38,56.14 18.94,57.58 18.94,67.91 19.18,68.16 23.2,68.16 29.12,74.08 33.77,74.08 37.49,77.81 47.48,77.81 48.94,79.27 58.29,79.27 59.25,78.3 61.14,78.3 62.15,77.3 71.83,77.3 72.29,77.75 77.58,77.75 79.44,75.89 85.73,75.89 87.87,78.04 96.46,78.04 96.66,78.24 v1(96.66,78.24)
  BOTTOM w0.102: v1(96.66,78.24) 96.86,78.05 97.12,78.05 99.74,80.67 156.57,80.67 159.21,78.03 159.21,73.18 160.9,71.49 160.9,70.2 160.63,69.93 160.27,69.93 160.06,69.72 RA7.1
I2C1_SCK: length 109.2
  TOP w0.102: 194.61,14.69 QH7.4 ; 194.61,14.69 195.24,14.69 RH5.1 ; 194.61,14.69 QH7.4 ; QH7.4 194.61,14.69 194.61,14.04 RH456.1 194.25,14.03 193.79,14.49 193.79,14.69 193.78,14.7 v1(193.78,14.73)
  IN4 w0.071: v1(152.58,68.5) 152.35,68.73 152.35,68.81 152.43,68.9 153.51,68.9 153.72,69.11 157.23,69.11 157.48,69.36 160.66,69.36 160.95,69.08 163.2,69.08 163.5,68.78 164.54,68.78 164.84,69.08 165.9,69.08 168.88,72.06 176.79,72.06 177.47,72.74 180.78,72.74 180.89,72.63 187.49,72.63 190.59,69.53 190.59,62.1 189.92,61.43 189.92,53.23 190.4,52.74 190.4,45.11 187.65,42.35 187.65,36.82 188,36.46 188,35.63 187.76,35.38 187.76,33.16 187.38,32.78 187.38,27.32 185.55,25.49 185.55,20.93 190.59,15.89 192.42,15.89 193.78,14.52 193.78,14.66 193.79,14.68 193.79,14.69 193.78,14.7 v1(193.78,14.73)
  BOTTOM w0.076: UCPU1.F1 151.66,68.9 152.18,68.9 v1(152.58,68.5)
I2C1_SCK_TP: length 11.5
  TOP w0.102: v1(186.24,17.8) 186.24,16.93 186.53,16.63 MD10.3 187.56,16.63 188.82,15.38 189.96,15.38 190.48,14.86 R1105.1 191.59,14.86 v2(191.76,14.69) QH7.3 193.07,14.69 193.13,14.63 193.13,13.89 RH456.2
  BOTTOM w0.102: JTP1.3 186.15,17.88 v1(186.24,17.8)
I2C1_SDA: length 108.8
  TOP w0.102: v1(192.23,16.82) 192.35,16.94 RH3.1 RH461.1 193.27,16.25 193.01,15.99 QH7.1
  IN4 w0.071: v1(152.03,68.54) 152.18,68.68 152.18,68.89 152.36,69.07 153.44,69.07 153.65,69.28 157.15,69.28 157.41,69.53 160.74,69.53 161.02,69.25 163.27,69.25 163.57,68.95 164.47,68.95 164.77,69.25 165.83,69.25 168.81,72.23 176.72,72.23 177.4,72.91 180.85,72.91 180.97,72.8 187.56,72.8 190.76,69.6 190.76,62.03 190.09,61.36 190.09,53.3 190.58,52.82 190.58,45.04 187.82,42.28 187.82,36.89 188.18,36.53 188.18,35.56 187.93,35.31 187.93,33.09 187.55,32.71 187.55,27.25 185.72,25.42 185.72,21 190.66,16.06 191.47,16.06 v1(192.23,16.82)
  BOTTOM w0.076: v1(152.03,68.54) 152.03,68.53 152,68.5 151.36,68.5 151.24,68.39 149.95,68.39 UCPU1.G4
I2C1_SDA_TP: length 14
  TOP w0.102: R1104.1 194.86,15.99 QH7.6 194.31,15.99 194.19,16.11 RH461.2 194.19,17.85 193.74,18.3 v2(192.82,18.3) 191.11,18.3 189.45,16.63 MD10.2 189.06,17.2 188.36,17.9 187.55,17.9 v1(187.43,17.79)
  BOTTOM w0.102: JTP1.2 186.65,19.12 187.43,18.35 v1(187.43,17.79)
I2S_BIT_CLK: length 9.5
  BOTTOM w0.076: UCPU1.AW8 146.42,49.99 146.42,48.83
  BOTTOM w0.102: RP15.7 151.63,45.7 151.03,45.1 v2(150.53,45.1) CH1242.1 149.46,45.34 146.42,48.38 146.42,48.83
I2S_BITCLK_AUDIO: length 201.9
  TOP w0.102: v2(41.23,30.17) 40.91,30.49 v1(40.61,30.49) RA52.1
  IN4 w0.071: v1(170.03,43.46) 170.09,43.52 174.15,43.52 177.36,40.32 178.64,40.32 181.41,37.55 181.41,23.32 176.24,18.16 101.74,18.16 101.38,18.52 94.96,18.52 94.6,18.16 50.27,18.16 49.7,18.73 43.78,18.73 41.22,21.29 41.22,29.88 v1(40.61,30.49)
  BOTTOM w0.076: RP15.2 153.27,45.7
  BOTTOM w0.102: v1(170.03,43.46) 169.67,43.09 169.66,43.09 169,42.43 157.86,42.43 155.8,44.5 155.8,45.09 155.09,45.8 153.89,45.8 153.79,45.7 153.27,45.7
I2S_BITCLK_AUDIO_R: length 4.5
  TOP w0.102: UA2.13 35.13,30.15 35.13,30.15 36.51,30.15 CA57.1 37.29,30.94 38.56,30.94 RA52.2
I2S_RST#: length 10.1
  BOTTOM w0.076: 147.02,49.5 147.02,50.79 147.06,50.83 147.06,51.31 UCPU1.AU8
  BOTTOM w0.089: 147.02,49.5 146.93,49.41 146.93,48.55 147.81,47.67 v2(147.81,47.46) 147.81,47.33 149.53,45.61 151.1,45.61 151.66,46.17
  BOTTOM w0.102: 151.66,46.17 151.69,46.2 RP15.8
I2S_RST_AUDIO#: length 203
  TOP w0.102: RA54.1 v1(40.53,33.54)
  IN4 w0.071: v1(169.48,43.5) 169.88,43.09 170.19,43.09 170.35,43.25 174.04,43.25 177.24,40.04 178.53,40.04 181.13,37.44 181.13,23.44 176.13,18.43 101.86,18.43 101.49,18.8 94.85,18.8 94.48,18.43 50.39,18.43 49.81,19 43.89,19 41.5,21.4 41.5,30.62 41.05,31.07 41.05,33.03 40.54,33.54 v1(40.53,33.54)
  BOTTOM w0.076: RP15.1 153.27,46.2
  BOTTOM w0.102: v1(169.48,43.5) 169.48,43.48 168.78,42.78 157.99,42.78 v2(157.48,43.3) 156.13,44.65 156.13,45.2 155.12,46.2 153.27,46.2
I2S_RST_AUDIO#_R: length 7.2
  TOP w0.102: UA2.15 34.06,32.08 34.19,32.21 36.66,32.21 CA26.2 37.37,32.92 38.2,32.92 38.72,32.4 RA14.2 RA54.2
I2S_SDIN0: length 211.6
  TOP w0.102: RA62.1 38.06,33.25 v1(38.39,33.25)
  IN4 w0.071: 178.95,37.61 177.87,38.69 176.68,38.69 173.89,41.48 168.47,41.48 166.74,43.21 163.56,43.21 161.19,45.58 160.69,45.58 160.04,46.22 155.86,46.22 152.36,49.72 147.96,49.72 147.08,50.6 v1(146.36,50.6) ; 177.55,23.06 173.59,19.1 102.13,19.1 101.77,19.47 94.57,19.47 94.21,19.1 50.66,19.1 50.09,19.67 44.17,19.67 42.26,21.59 42.26,32.65 40.86,34.05 39.2,34.05 v1(38.39,33.25)
  IN4 w0.076: 177.55,23.06 177.99,23.51 179.34,23.51 180.37,24.54 180.37,36.19 178.95,37.61
  BOTTOM w0.076: v1(146.36,50.6) 146.36,50.23 145.98,49.86 UCPU1.AY10
  BOTTOM w0.102: v1(38.39,33.25) v2(38.97,33.25)
I2S_SDIN0_AUDIO: length 4.4
  TOP w0.102: RA62.2 36.85,33.47 35.84,32.46 34.07,32.46 33.66,32.06 33.66,31.5 UA2.16
I2S_SDOUT: length 21.1
  TOP w0.102: RH24.2 RH42.2 MC31.1 156.8,44.95 v2(155.94,44.95) 154.99,44.95 v1(154.78,44.74)
  BOTTOM w0.076: UCPU1.AU11 145.59,51.28 145.59,50.62 145.69,50.51 145.69,49.47 146.12,49.05 146.12,48.26
  BOTTOM w0.102: 146.12,48.26 147.46,46.92 147.46,45.18 148.11,44.53 150.91,44.53 151.58,45.2 RP15.6 152.47,45.2 152.66,45.02 152.66,44.49 152.81,44.34 154.38,44.34 v1(154.78,44.74)
I2S_SDOUT_AUDIO: length 201.6
  TOP w0.102: RA36.2 39.92,34.36 40.35,33.93 40.7,33.93 41.29,33.33 v2(41.29,33.16) 41.5,32.95 v1(41.5,32.65)
  IN4 w0.071: v1(41.5,32.65) 42,32.15 42,21.53 44.08,19.45 50,19.45 50.57,18.88 94.3,18.88 94.66,19.24 101.67,19.24 102.04,18.88 175.94,18.88 180.62,23.56 180.62,37.26 178.29,39.6 177.06,39.6 174.15,42.5 171.02,42.5 v1(170.66,42.86)
  BOTTOM w0.076: RP15.3 153.26,45.2 153.27,45.2
  BOTTOM w0.102: 153.27,45.2 153.8,45.2 154.01,45.42 155.03,45.42 155.48,44.97 155.48,44.38 157.75,42.11 169.91,42.11 v1(170.66,42.86)
I2S_SDOUT_AUDIO_R: length 8.9
  TOP w0.102: UA2.17 33.26,32.08 33.9,32.72 35.74,32.72 36.44,33.42 36.44,33.94 36.85,34.35 CA27.2 37.9,35.67 v2(38.12,35.67) 38.3,35.67 39.01,34.96 RA36.1
I2S_SYNC: length 12.3
  BOTTOM w0.076: UCPU1.AV11 145.27,50.69 145.53,50.43 145.53,49.33 145.82,49.05 145.82,48.59
  BOTTOM w0.102: RP15.5 152.11,44.7 151.59,44.7 151.1,44.21 147.86,44.21 147.11,44.96 v2(147.11,45.73) 147.11,46.95 145.82,48.24 145.82,48.59
I2S_SYNC_AUDIO: length 200.4
  TOP w0.102: RA53.1 v2(40.9,31.45) v1(41.5,31.45)
  IN4 w0.071: v1(171.25,42.87) 174.1,42.87 177.15,39.82 178.38,39.82 180.88,37.33 180.88,23.5 176.04,18.66 101.95,18.66 101.58,19.02 94.76,19.02 94.39,18.66 50.48,18.66 49.91,19.23 43.99,19.23 41.75,21.46 41.75,31.19 v1(41.5,31.45)
  BOTTOM w0.076: RP15.4 153.27,44.7
  BOTTOM w0.102: 153.27,44.7 153.72,44.7 154.18,45.16 154.91,45.16 155.17,44.9 155.17,44.22 157.59,41.8 170.18,41.8 v1(171.25,42.87)
I2S_SYNC_AUDIO_R: length 4.8
  TOP w0.102: UA2.14 35.01,30.55 35.95,30.55 CA24.2 37.36,31.95 38,31.95 38.51,31.45 RA53.2
I_ADP: length 207
  TOP w0.102: v1(188.65,67.38) 188.54,67.49 187.92,67.49 UE5.A12 ; v1(46.31,23.79) v2(46.73,24.21) PR214.1
  IN1 w0.071: v1(46.31,23.79) 47.57,22.53 49.12,22.53 49.87,21.78 49.87,15.58 v4(49.61,15.32)
  IN3 w0.086: v4(49.61,15.32) 50.3,16 54.61,16 55.84,14.77 68.6,14.77 69.69,15.86 94.56,15.86 95.01,16.3 102.92,16.3 103.37,15.86 116.16,15.86 117.8,14.21 126.73,14.21 128.32,15.8 138.6,15.8 140.85,13.56 174.25,13.56 176.93,16.24 179.16,16.24 179.8,16.87 182.27,16.87 185.73,20.33 185.73,25.01 187.1,26.38 187.1,39.9 190.64,43.44 190.64,52.37 190.1,52.91 190.1,57.96 189.77,58.29 189.77,62.55 189.88,62.65 189.88,66.15 v1(188.65,67.38)
I_BATT: length 176.5
  TOP w0.102: v3(180.46,55.48) 181.17,55.48 RE64.2 ; v1(49.08,21.22) 48.16,22.14 v2(48.16,22.84) PR217.1
  GND1 w0.102: v4(180.03,55.48) v3(180.46,55.48)
  IN3 w0.086: v1(49.08,21.22) 49.97,21.22 51.46,19.73 65.7,19.73 66.56,18.87 93.32,18.87 93.76,19.31 104.17,19.31 104.61,18.87 117.43,18.87 118.92,17.38 125.36,17.38 126.8,18.82 140.52,18.82 141.43,17.9 171.34,17.9 171.96,18.53 174.67,18.53 175.43,19.29 177.94,19.29 182.32,23.67 182.32,43.13 182.01,43.44 182.01,44.37 181.01,45.36 181.01,50.54 179.89,51.65 179.89,55.35 v4(180.03,55.48)
I_SYS: length 186.1
  TOP w0.102: PR218.1 49.79,24.23 49.79,23.85 50.56,23.07 50.56,21.76 v2(50.23,21.43) 49.24,20.44 v1(49.24,20.43) ; UE5.A57 182.72,59.83 v1(182.5,59.62)
  IN3 w0.086: v1(182.5,59.62) 182.89,59.23 182.89,55.92 182.52,55.55 181.56,55.55 180.48,54.46 180.48,53.17 180.73,52.91 181.24,52.91 181.65,52.5 181.65,50.49 182.17,49.97 182.17,48.73 181.53,48.09 181.53,45.45 181.84,45.14 182.9,44.09 182.9,23.72 178.1,18.91 175.82,18.91 173.15,16.24 142.19,16.24 140,18.44 127.2,18.44 125.61,16.84 118.9,16.84 117.25,18.49 104.46,18.49 104.01,18.93 93.91,18.93 93.47,18.49 68.49,18.49 68.09,18.09 52.18,18.09 49.83,20.43 v1(49.24,20.43)
ILMT_1.05V: length 2.4
  BOTTOM w0.254: PR507.1 PR504.2 203.28,63.07 203.04,62.83 202.15,62.83 PU500.3
IMON: length 3.5
  BOTTOM w0.203: PU700.13 77.08,64.06
  BOTTOM w0.254: 77.08,64.06 v2(77.08,64.36) 77.08,65 PC700.1 76.45,65.64 76.45,65.64 75.91,66.17 PR701.1
INV_PWM_R: length 7.4
  TOP w0.102: v1(194.09,27.87) 194.64,27.87 194.85,28.08 D73.1 194.4,28.53 194.28,28.4 MC3.1 R545.1 193.49,29.29 193.91,28.87 194.23,28.87 194.58,29.22 194.58,29.82 v2(194.43,29.97)
  BOTTOM w0.102: JEDP.8 v1(194.09,27.87)
IRQ_SERIRQ: length 47.5
  GND1 w0.102: v3(180.72,71.19) 180.93,70.97 v4(180.93,70.85) ; v4(157.73,64.64) 157.73,65.28 v3(157.65,65.36)
  IN1 w0.071: v4(157.73,64.64) 158.31,64.06 158.72,64.06 159.12,63.65 160.34,63.65 160.58,63.42 162.5,63.42 163,62.92 166.16,62.92 168.44,60.64 172.42,60.64 173.03,60.02 175.62,60.02 177.22,61.62 178.57,61.62 179.18,61.01 179.71,61.01 179.89,61.18 181.16,61.18 v4(181.87,61.9)
  IN2 w0.086: v4(180.93,70.85) 180.93,70.44 181.09,70.27 181.09,68.23 182.2,67.12 182.2,62.22 v4(181.87,61.9) ; v4(157.73,64.64) 157.73,64.42 157.28,63.98 154.79,63.98 154.63,63.81 154.1,63.81 153.57,63.29 151.38,63.29 150.88,62.79 150.41,62.79 v1(150.04,63.16)
  BOTTOM w0.076: UCPU1.T4 149.65,63.54 v1(150.04,63.16)
JACK_PLUG: length 16.4
  TOP w0.254: QA3.5 16.87,30.87 RA26.1 16.04,30.79 v2(15.68,30.43) 15.68,30.06 v1(15.92,29.82)
  IN1 w0.254: v1(16.16,35.36) 15.65,35.87 9.74,35.87 9.57,35.7 JHP1.6
  BOTTOM w0.254: v1(16.16,35.36) 16.33,35.19 DA1.3 16.33,30.45 RA35.1 16.36,30.26 v1(15.92,29.82)
JACK_PLUG_DL: length 3.5
  TOP w0.254: v1(22.7,32.98) 22.7,33.96 QA6.2
  IN2 w0.254: v1(20.24,32.88) 20.33,32.98 v1(22.7,32.98)
  vias: v2(19.5,31.95)
JACK_PLUG_DL#: length 29.9
  TOP w0.102: RA31.2 21.68,34.54 RA29.1 22.14,35.39 22.42,35.11 23.22,35.11 23.36,35.25 QA6.1 23.96,35.86 v1(24.66,35.16) ; v1(41.46,34.63) 41.75,34.34 v2(42.07,34.34) 42.07,30.06 41.45,29.44 40.02,29.44 RA75.1
  BOTTOM w0.102: v1(41.46,34.63) 41.06,34.24 40.15,34.24 39.46,34.92 35.12,34.92 34.7,35.35 32.44,35.35 32.42,35.37 24.87,35.37 v1(24.66,35.16)
JTAG_CLK: length 15.9
  TOP w0.102: v1(180.66,61.79) 180.47,61.6 180.47,61.14 UE5.B56
  IN1 w0.071: v1(180.66,61.79) 180,61.79 179.57,61.36 179.34,61.36 178.72,61.98 177.09,61.98 176.35,61.24 175.06,61.24 173.72,62.57 173.37,62.57 v1(173.07,62.88)
  BOTTOM w0.102: JDEG1.4 171.66,68.22 171.66,67.35 171.92,67.09 171.92,66.06 ; v1(173.07,62.88) 172.71,63.23 172.71,65.23 172.45,65.5 172.14,65.5 171.92,65.71 171.92,66.06 ; 171.92,66.06 RPE7.3
JTAG_RST#: length 10.6
  TOP w0.102: JTAG1.1 173.04,65.38 RE66.1 CE59.1 172.42,63.87 RE65.2 172.88,63.6 173.06,63.78 v1(173.56,63.78) ; v1(178.54,64.05) 178.23,63.74 UE5.B47
  BOTTOM w0.102: v1(178.54,64.05) 178.31,63.81 175.44,63.81 v2(175.38,63.88) 175.04,64.22 174,64.22 v1(173.56,63.78)
JTAG_TDI: length 24.2
  TOP w0.102: UE5.A51 179.72,60 179.31,59.6 179.09,59.6 178.71,59.22 178.71,59.04 v1(178.71,59.03)
  IN4 w0.071: v1(178.71,59.03) 178.71,59.04 178.38,58.7 178.38,55.66 178.21,55.5 175.66,55.5 175.42,55.73 175.42,56.47 172.41,59.48 172.41,64.76 170.92,66.24 v1(170.92,66.79)
  BOTTOM w0.102: RPE7.1 v1(170.92,66.79) 170.55,67.16 170.55,67.66 170.66,67.77 JDEG1.2 ; v1(178.71,59.03) v2(178.2,59.03)
JTAG_TDO: length 14.6
  TOP w0.102: v1(179.43,61.79) 179.65,61.79 179.97,61.47 179.97,61.14 UE5.B55
  IN1 w0.071: v1(179.43,61.79) 179.06,62.16 177.02,62.16 176.28,61.41 175.32,61.41 173.54,63.19 v1(173.54,63.2)
  BOTTOM w0.102: 172.42,66.06 RPE7.4 ; 172.42,66.06 172.42,65.81 172.91,65.32 172.91,63.82 v1(173.54,63.2) 174.18,63.2 v2(174.38,62.99) ; 172.42,66.06 172.42,67.17 172.16,67.44 JDEG1.5
JTAG_TMS: length 26.5
  TOP w0.102: v1(179.27,59.03) 180,59.76 180.48,59.76 180.72,59.99 UE5.A53
  IN4 w0.071: v1(170.93,67.43) 171.6,66.76 171.6,65.81 172.59,64.82 172.59,59.55 175.6,56.54 175.6,55.8 175.73,55.67 178.14,55.67 178.2,55.73 178.2,59.2 178.42,59.42 178.89,59.42 v1(179.27,59.03)
  BOTTOM w0.102: JDEG1.3 171.16,68.22 171.16,67.65 v1(170.93,67.43) 171.42,66.94 171.42,66.06 RPE7.2 ; v1(179.27,59.03) v2(179.27,58.14)
KB_DET#: length 234.4
  TOP w0.076: v1(153.6,52.51) 152.93,51.84 v2(152.09,51.84)
  IN1 w0.071: v1(153.6,52.51) 153.96,52.15 154.58,52.15 154.84,52.41 159.02,52.41 161.71,49.72 161.71,49.39 164.16,46.94 168.36,46.94 168.76,46.55 173.73,46.55 v4(174.77,47.59)
  IN2 w0.086: v1(161.92,62.7) 161.92,62.39 163.26,61.05 163.61,61.05 164.1,61.54 164.36,61.54 164.67,61.85 165.63,61.85 165.77,61.71 170.54,61.71 172.22,60.03 174.3,60.03 174.5,59.83 174.5,58.9 173.26,57.66 173.26,56.28 173.64,55.89 173.64,51.51 174.4,50.75 174.4,49.1 174.77,48.73 v4(174.77,47.59) 174.77,47.13 174.33,46.7 174.33,42.78 177.43,39.68 180.81,39.68 184.14,36.34 184.14,35.09 185.62,33.62 185.62,26.4 178.2,18.98 171.33,18.98 170.36,18.01 126.26,18.01 126.15,17.9 114.24,17.9 114.1,18.03 105.89,18.03 105.16,18.76 72.59,18.76 69.9,21.45 66.19,21.45 64.33,19.59 45.82,19.59 45.41,20.01 v4(45.41,20.02)
  GND3 w0.102: v4(45.41,20.02) 45.43,20.05 v5(45.43,20.41)
  BOTTOM w0.076: UCPU1.AT3 150.56,52.03 151.08,52.03 151.27,52.22 151.27,52.46 151.44,52.62 151.76,52.62 152.33,52.06 153.15,52.06 v1(153.6,52.51) 153.99,52.9 T282.1
  BOTTOM w0.102: RH302.1 161.78,62.82 161.9,62.7 v1(161.92,62.7)
LANCLK_REQ#: length 15.2
  IN3 w0.086: v1(157.14,64.49) 156.72,64.07 155.57,64.07 154.53,63.03 152.64,63.03 151.9,62.28 151.9,60.1 152.55,59.44 152.83,59.44 v1(154.18,58.09)
  BOTTOM w0.076: UCPU1.AD1 151.67,59 153.28,59 v1(154.18,58.09)
  BOTTOM w0.102: RH91.2 157.31,64.33 v1(157.14,64.49)
LCD_TST: length 49.2
  TOP w0.102: UE5.A38 177.02,66.99 176.72,66.99 176.51,67.2 175.62,67.2 v3(175.05,66.63)
  GND1 w0.102: v4(175.4,66.03) 175.05,66.38 v3(175.05,66.63)
  IN2 w0.086: v4(186.69,34.92) 186.69,35.07 180.8,40.97 179.28,40.97 178.88,41.37 176.98,41.37 175.22,43.12 175.22,44.25 175.82,44.85 175.82,53.81 175.27,54.36 175.27,56.11 174.95,56.43 174.95,57.95 175.4,58.4 175.4,61.43 175.05,61.79 175.05,65.1 175.4,65.45 v4(175.4,66.03)
  GND3 w0.102: v4(186.69,34.92) 187.65,34.92 v5(187.72,34.84)
  BOTTOM w0.102: JEDP.19 192.59,33.37 191.59,34.37 v2(190,34.37) 189.54,34.37 188.89,35.02 188.17,35.02 187.99,34.84 v5(187.72,34.84)
LCD_VCC_TEST_EN: length 54.2
  TOP w0.102: v1(191.65,46.09) 193.44,47.88 199.55,47.88 203.69,43.74 v2(203.69,42.74) D93.2 ; UE5.A39 176.64,66.49 v1(176.34,66.79)
  IN1 w0.071: v1(191.65,46.09) 191.65,46.38 191.22,46.8 191.22,47.77 188.2,50.8 182.67,50.8 182.41,51.06 180.51,51.06 180.08,50.63 178.66,50.63 177.65,49.62 v4(177.18,49.62)
  IN2 w0.086: v1(176.34,66.79) 176.97,66.17 176.97,61.98 176.08,61.09 176.08,58.23 176.07,58.23 176.07,58.16 175.63,57.72 175.63,56.7 175.91,56.43 175.91,54.63 176.55,53.99 176.55,51.61 177.18,50.98 v4(177.18,49.62)
LG_3V: length 3
  TOP w0.102: v7(62.01,56.91) v2(62.01,57.42)
  IN3 w1.016: 61.82,57.86 63.59,59.64
  vias: v7(61.62,56.4) v7(64.55,60.02) v7(64.55,59.39)
LG_5V: length 7
  TOP w0.102: v7(61.69,53.1) v2(61.69,52.51)
  IN3 w1.016: 62.81,52.85 62.81,52.49 63.03,52.49 65.53,49.99 67.78,49.99
  vias: v7(61.68,53.74) v7(68.55,49.29) v7(68.55,48.66)
LID_CL_SIO#: length 3.9
  TOP w0.102: UE5.A21 184.22,71.59 184.01,71.8 184.01,72.4 184.51,72.9 CE13.1 RE25.2 RE26.2
LID_SW_IN#: length 86.7
  TOP w0.102: RE26.1 186.4,73.87 v1(185.77,74.5) 185.77,74.51 185.45,74.82 185.17,74.82 185.06,74.94 183.66,74.94 v2(183.57,74.85)
  IN3 w0.086: v4(183.42,21.57) 183.66,21.81 183.66,43.52 184.29,44.15 184.29,48.54 183.67,49.16 183.67,52.2 183.1,52.77 183.1,55.06 183.67,55.63 183.67,58.43 185.24,60 185.24,63.32 184.76,63.8 184.76,68.32 184.4,68.68 184.4,69.83 185.1,70.54 185.1,70.81 186.33,72.03 186.33,73.94 v1(185.77,74.5)
  IN4 w0.071: v4(198.24,16.26) 198.15,16.18 198.15,14.92 196.74,13.51 184.58,13.51 183.71,14.37 183.71,18.79 183.42,19.09 v4(183.42,21.57)
  GND3 w0.102: v5(197.79,16.04) 198.02,16.26 v4(198.24,16.26)
  BOTTOM w0.102: v5(197.79,16.04) 197.49,16.34 197.49,17.72 197.8,18.03 JIO1.44
LINE1-VREFO: length 7.4
  TOP w0.203: UA2.39 27.91,26.55 27.03,26.55 26.56,26.08 26.17,26.08
  TOP w0.254: 26.17,26.08 v2(22.65,26.08) 21.86,26.08 v1(21.76,26.18)
  BOTTOM w0.254: DA6.1 21.86,26.29 v1(21.76,26.18)
LINE1_L: length 4.8
  TOP w0.102: v1(25.27,28.83) 25.04,28.83 v2(24.57,28.36)
  TOP w0.203: UA2.35 27.36,28.15 27.2,28.31 25.7,28.31 25.27,28.74 v1(25.27,28.83)
  BOTTOM w0.254: v1(25.27,28.83) 25.25,28.8 CA70.1
LINE1_L_C: length 1
  BOTTOM w0.254: CA71.2 25.29,29.67 RA51.1
LINE1_R: length 3.7
  TOP w0.203: v1(25.84,28.83) 26.03,28.64 27.34,28.64 27.43,28.55 UA2.34
  BOTTOM w0.102: v1(25.84,28.83) v2(25.84,28.33)
  BOTTOM w0.254: v1(25.84,28.83) 26.22,29.2 CA71.1
LINE1_R_C: length 2.4
  BOTTOM w0.102: CA70.2 23.44,28.71 v2(24.39,27.76)
  BOTTOM w0.254: RA50.1 23.43,28.81 CA70.2
LPC_AD0: length 78.3
  TOP w0.102: v1(179.65,72.02) 179.72,71.95 UE5.A30
  IN2 w0.086: v1(179.65,72.02) 179.37,71.74 179.37,70.92 177.38,68.93 177.38,61.76 177.19,61.57 177.19,60.22 176.45,59.49 176.45,58.01 176.01,57.57 176.01,56.85 176.29,56.58 176.29,54.9 177.91,53.28 177.91,48.93 177.69,48.71 177.69,48.16 177.82,48.03 v4(177.82,44.05)
  GND3 w0.102: v5(177.33,43.11) 177.33,43.16 177.82,43.64 v4(177.82,44.05)
  BOTTOM w0.076: UCPU1.AU14 144.06,51.31 144.06,50.83 144.02,50.79 144.02,49.46 144.18,49.3 144.18,48.34 146.02,46.51 146.02,44.1 147.16,42.96
  BOTTOM w0.102: 147.16,42.96 147.24,42.87 149.69,40.43 170.79,40.43 171.81,41.45 173.68,41.45 v2(173.8,41.32) 174.58,41.32 175.39,42.13 176.29,42.13 177.26,43.11 v5(177.33,43.11) ; JLPDE1.3 181.15,70.79 180.89,70.52 179.95,70.52 179.65,70.83 v1(179.65,72.02)
LPC_AD1: length 74.4
  TOP w0.102: v1(179.58,69.7) 179.47,69.82 179.47,70.21 UE5.B32
  IN2 w0.086: v1(179.58,69.7) 179.19,69.3 178.29,69.3 177.75,68.77 177.75,61.61 177.57,61.42 177.57,60.07 176.83,59.33 176.83,57.85 176.48,57.51 176.48,56.96 176.67,56.77 176.67,55.06 178.28,53.44 178.28,49.12 178.6,48.8 178.6,47.44 178.87,47.17 v4(178.87,44.41)
  GND3 w0.102: v5(178.82,44.06) 178.82,44.36 v4(178.87,44.41)
  BOTTOM w0.076: UCPU1.AW12 144.78,50 144.78,49.36 144.72,49.3 144.72,48.62 146.59,46.75 146.59,44.39 148.02,42.96
  BOTTOM w0.102: JLPDE1.4 181.65,70.58 181.4,70.32 180.45,70.32 179.82,69.7 v1(179.58,69.7) ; 148.02,42.96 148.11,42.87 149.94,41.04 170.54,41.04 173.08,43.58 v2(173.69,43.58) 175,43.58 175.44,43.15 176.28,43.15 177.14,44 177.57,44 177.64,43.93 178.69,43.93 178.82,44.05 v5(178.82,44.06)
LPC_AD2: length 76.2
  TOP w0.102: v1(179.06,72.01) 179.22,71.86 UE5.A31
  IN2 w0.086: v1(179.06,72.01) 179.13,71.95 179.13,70.94 177.19,69.01 177.19,61.84 177,61.65 177,60.3 176.27,59.57 176.27,58.09 175.82,57.65 175.82,56.78 176.1,56.5 176.1,54.82 177.72,53.21 177.72,49.01 177.5,48.79 177.5,47.57 177.5,47.57 177.5,46.62 177.31,46.43 v4(177.31,44.07)
  GND3 w0.102: v4(177.31,44.07) 177.31,43.81 v5(177.45,43.67)
  BOTTOM w0.076: UCPU1.AY12 144.51,49.62 144.51,48.57 146.4,46.69 146.4,44.3 147.73,42.96
  BOTTOM w0.102: v5(177.45,43.67) 177.15,43.67 176.42,42.94 174.95,42.94 v2(174.62,42.6) 174.28,42.94 172.73,42.94 170.62,40.83 149.86,40.83 149.81,40.88 147.73,42.96 ; v1(179.06,72.01) 179.06,72.24 179.43,72.61 181.55,72.61 182.15,72 182.15,71.22 JLPDE1.5
LPC_AD3: length 74.9
  TOP w0.102: UE5.B33 178.97,70.34 v1(178.97,69.7)
  IN2 w0.086: v4(178.2,44.4) 178.2,47.82 178.41,48.03 178.41,48.73 178.1,49.04 178.1,53.36 176.48,54.98 176.48,56.69 176.26,56.92 176.26,57.55 176.64,57.93 176.64,59.41 177.38,60.15 177.38,61.5 177.57,61.68 177.57,68.85 178.42,69.7 v1(178.97,69.7)
  GND3 w0.102: v5(178.49,44.21) 178.49,44.21 178.3,44.4 v4(178.2,44.4)
  BOTTOM w0.076: UCPU1.AW11 144.95,50.02 144.95,49.26 144.89,49.2 144.89,48.71 146.78,46.81 146.78,44.49 148.31,42.96
  BOTTOM w0.102: v5(178.49,44.21) 176.27,44.21 175.88,44.6 v2(174.57,44.6) 173.81,44.6 170.45,41.24 150.03,41.24 148.31,42.96 ; v1(178.97,69.7) 179.37,69.29 179.73,69.29 180.56,70.12 181.89,70.12 182.65,70.88 182.65,71.22 JLPDE1.6
LPC_FRAME#: length 79.4
  TOP w0.102: v1(179.65,68.73) 179.65,69.14 179.97,69.46 UE5.B31
  IN2 w0.086: v1(179.65,68.73) 179.02,68.11 178.29,68.11 177.94,67.77 177.94,62.21 178.42,61.74 178.42,60.57 177.03,59.19 177.03,57.75 176.67,57.39 176.67,57.04 176.88,56.83 176.88,55.11 178.47,53.52 178.47,49.2 178.79,48.88 178.79,47.76 179.48,47.07 v4(179.48,43.75)
  GND3 w0.102: v4(179.48,43.75) 179.49,43.77 179.53,43.73 v5(179.53,43.27)
  BOTTOM w0.076: 147.45,42.96 146.21,44.2 146.21,46.6 144.35,48.46 144.35,49.37 144.19,49.53 144.19,50.69 UCPU1.AV12
  BOTTOM w0.102: JLPDE1.7 183.15,70.75 182.44,70.04 182.21,70.04 182.08,69.92 180.67,69.92 180.18,69.42 180.18,69.27 v1(179.65,68.73) ; 147.45,42.96 147.53,42.87 149.78,40.63 170.7,40.63 172.55,42.48 v2(172.98,42.48) 173.17,42.29 175.26,42.29 175.68,42.71 176.52,42.71 177.2,43.39 177.58,43.39 177.84,43.65 179.15,43.65 v5(179.53,43.27)
LX_1.05V: length 2.2
  TOP w0.102: PC505.2 v2(202.07,61.93)
  TOP w0.254: v7(200.56,61.23) PC505.2
  vias: v7(203.42,59.51) v7(204.06,59.51)
LX_3V: length 5.9
  TOP w0.102: v7(59.21,57.35) v2(59.76,57.35)
  IN4 w1.016: 64.23,57.48 62.83,58.88 60.04,58.88 59.66,58.5
  vias: v7(58.96,57.99) v7(64.55,56.59) v7(64.55,55.96)
LX_5V: length 12.4
  TOP w0.102: v7(59.34,51.83) 59.34,51.01 59.23,50.9 v2(59.21,50.9)
  IN4 w1.016: 69.44,52.27 69.44,51.78 69.02,51.36 69.02,51.35 67.53,49.86 60.93,49.86 59.78,51
  vias: v7(59.35,52.47) v7(69.12,53.1) v7(69.75,53.1)
LX_CORE:
  vias: v2(92.6,55.06) v7(92.99,58.37) v7(93.63,58.37)
M_CLK_A_DDR0: length 118.6
  TOP w0.076: v1(102.72,37.39) 102.53,37.19 101.88,37.19 RD75.1 ; 111.51,30.25 UD31.J7
  TOP w0.102: v1(110.93,30.72) 110.93,30.52 111.23,30.22 111.47,30.22 UD31.J7 111.51,30.25 ; v1(82.61,30.72) 82.61,30.49 82.85,30.25 83.19,30.25 UD28.J7 ; v1(123.69,30.72) 123.91,30.72 124.15,30.48 124.15,30.25 UD32.J7 ; UD29.J7 95.53,30.25 95.53,30.25 95.34,30.44 v1(95.34,30.69)
  IN1 w0.076: v4(116.45,34.45) 116.17,34.17 115.03,34.17 114.96,34.24 114.96,35.05 114.74,35.28 114.2,35.28 113.97,35.05 113.97,33.77 113.64,33.45 111.77,33.45 111.4,33.82 108.71,33.82 108.22,34.3 107.74,34.3 107.22,34.82 106.31,34.82 103.9,37.23 102.88,37.23 v1(102.72,37.39) 102.49,37.15 102.27,37.15 100.64,35.51 97.63,35.51 97.38,35.26 97.38,34.57 97.13,34.33 95.95,34.33 95.54,34.74 92.78,34.74 92.59,34.55 92.59,33.71 92.33,33.45 92.01,33.45 91.87,33.59 90.28,33.59 89.5,34.36 88.33,34.36 v4(88.11,34.58)
  IN4 w0.076: v1(95.34,30.69) 95.04,30.39 94.9,30.39 94.79,30.5 94.79,31.95 93.68,33.06 92.39,33.06 91.88,33.57 90.32,33.57 89.51,34.38 88.31,34.38 v4(88.11,34.58) 87.96,34.43 87.18,34.43 86.67,34.94 85.96,34.94 85.67,34.65 85.67,33.59 85.46,33.39 83.63,33.39 83.01,32.77 83.01,30.5 82.95,30.43 82.72,30.43 82.61,30.55 v1(82.61,30.72) ; v1(123.69,30.72) 123.36,30.39 123.25,30.39 123.12,30.52 123.12,32.07 121.84,33.35 120.41,33.35 120.22,33.54 118.6,33.54 117.87,34.27 116.64,34.27 v4(116.45,34.45) 116.19,34.19 115.41,34.19 115.19,34.41 115.19,34.58 115,34.77 114.38,34.77 114.19,34.58 114.19,33.9 113.75,33.45 111.66,33.45 111.35,33.14 111.35,30.51 111.23,30.39 111.04,30.39 110.93,30.51 v1(110.93,30.72)
  IN4 w0.145: v1(129.62,48.71) 129.62,48.58 129.47,48.43 129.09,48.43 128.72,48.06 128.72,46.89 127.36,45.54 127.36,45.17 126.65,44.46 125.7,44.46 125.19,44.97 119.04,44.97 115.76,41.69 105.93,41.69 103.15,38.91 103.15,37.28 103.07,37.19 102.92,37.19 v1(102.72,37.39)
  BOTTOM w0.076: v1(129.62,48.71) 129.75,48.58 129.75,48.4 129.65,48.3 129.47,48.3 129.39,48.22 129.13,48.22 128.9,48.45 128.9,50.99 128.99,51.08 129.05,51.08 UCPU1.AV37
M_CLK_A_DDR#0: length 118.5
  TOP w0.076: v1(102.72,36.8) 102.62,36.91 102.16,36.91 RD77.1
  TOP w0.102: UD29.K7 95.66,29.45 95.66,29.45 v1(95.28,29.83) ; v1(82.61,29.96) 83.11,29.45 UD28.K7 ; UD32.K7 123.93,29.67 123.64,29.96 v1(123.63,29.96) ; UD31.K7 111.51,29.45 111.51,29.57 111.12,29.96 v1(110.93,29.96)
  IN1 w0.076: v4(116.45,33.87) 116.3,34.02 114.97,34.02 114.81,34.18 114.81,34.99 114.67,35.13 114.26,35.13 114.12,34.99 114.12,33.71 113.71,33.3 111.71,33.3 111.34,33.67 108.65,33.67 108.16,34.15 107.68,34.15 107.16,34.67 106.24,34.67 103.84,37.08 103,37.08 v1(102.72,36.8) 102.53,37 102.33,37 100.7,35.36 97.69,35.36 97.53,35.19 97.53,34.51 97.2,34.18 95.89,34.18 95.48,34.59 92.84,34.59 92.74,34.48 92.74,33.65 92.39,33.3 91.95,33.3 91.81,33.44 90.21,33.44 89.44,34.21 88.32,34.21 v4(88.11,34)
  IN4 w0.076: v1(110.93,29.96) 110.93,30.13 111.03,30.23 111.28,30.23 111.5,30.44 111.5,33.06 111.74,33.3 113.84,33.3 114.34,33.81 114.34,34.52 114.44,34.62 114.94,34.62 115.04,34.52 115.04,34.33 115.33,34.04 116.29,34.04 v4(116.45,33.87) 116.69,34.11 117.81,34.11 118.54,33.38 120.17,33.38 120.36,33.19 121.78,33.19 122.96,32.01 122.96,30.46 123.18,30.24 123.34,30.24 v1(123.63,29.96) ; v1(82.61,29.96) 82.61,30.01 82.87,30.28 83.01,30.28 83.16,30.43 83.16,32.7 83.69,33.23 85.54,33.23 85.82,33.5 85.82,34.58 86.02,34.79 86.57,34.79 87.08,34.28 87.82,34.28 v4(88.11,34) 88.34,34.23 89.43,34.23 90.24,33.42 91.83,33.42 92.33,32.91 93.62,32.91 94.63,31.89 94.63,30.41 94.81,30.23 94.88,30.23 v1(95.28,29.83)
  IN4 w0.145: v1(129.62,47.94) 129.62,48.07 129.48,48.21 129.18,48.21 128.93,47.96 128.93,46.8 127.58,45.45 127.58,45.08 126.74,44.24 125.61,44.24 125.1,44.75 119.13,44.75 115.85,41.47 106.02,41.47 103.37,38.82 103.37,37.19 103.16,36.98 102.9,36.98 v1(102.72,36.8)
  BOTTOM w0.076: UCPU1.AU37 129.13,51.52 128.72,51.11 128.72,48.24 129.01,47.94 v1(129.62,47.94)
M_CLK_B_DDR0: length 137.7
  TOP w0.076: RD76.1 156.38,37.11 156.56,36.93 157.22,36.93 v1(157.32,36.83)
  TOP w0.102: v1(148.94,30.69) 148.82,30.58 148.82,30.39 148.96,30.25 148.96,30.25 UD3.J7 ; UD4.J7 177.67,30.32 177.25,30.32 177.12,30.45 177.12,30.56 v1(177.28,30.72) ; v1(136.2,30.72) 136.17,30.69 136.17,30.43 136.29,30.32 136.36,30.32 136.53,30.15 136.68,30.15 136.78,30.25 UD7.J7 ; v1(164.52,30.73) 164.42,30.63 164.42,30.42 164.49,30.34 164.69,30.34 164.77,30.25 164.77,30.25 UD1.J7
  IN1 w0.076: v1(164.52,30.73) 164.52,30.53 164.65,30.41 164.8,30.41 164.91,30.52 164.91,32.5 165.9,33.48 167.41,33.48 167.54,33.61 167.54,34.7 167.77,34.92 168.71,34.92 168.94,34.7 168.94,34.44 169.07,34.31 169.9,34.31 v4(170.05,34.45) 170.19,34.31 171.6,34.31 172.38,33.53 173.82,33.53 173.85,33.51 175.29,33.51 176.7,32.09 176.7,30.49 176.83,30.36 176.93,30.36 v1(177.28,30.72) ; v1(136.2,30.72) 136.2,30.51 136.3,30.41 136.5,30.41 136.62,30.52 136.62,32.81 137.32,33.5 138.96,33.5 139.16,33.71 139.16,34.58 139.4,34.82 140.46,34.82 140.62,34.67 140.62,34.44 140.69,34.37 141.49,34.37 v4(141.7,34.58) 141.92,34.37 143.04,34.37 143.79,33.62 145.46,33.62 145.71,33.36 147.02,33.36 148.4,31.98 148.4,30.51 148.52,30.39 148.81,30.39 148.94,30.52 v1(148.94,30.69)
  IN1 w0.145: v1(128.58,53.8) 128.58,53.85 128.38,54.05 128.03,54.05 127.94,53.96 127.94,52.52 129.06,51.4 129.06,47.62 130.28,46.41 131.69,46.41 132.37,47.09 132.37,49.1 132.98,49.71 133.74,49.71 134.89,48.56 135.34,48.56 135.6,48.29 136.57,48.29 136.79,48.52 140.66,48.52 141.24,47.93 142.66,47.93 143.07,47.53 143.07,45.04 143.45,44.66 143.7,44.66 144.09,44.27 144.09,43.37 144.24,43.22 147.96,43.22 148.74,42.43 148.86,42.43 148.95,42.53 148.95,42.95 149.23,43.22 149.84,43.22 150.11,42.95 150.11,41.93 150.23,41.81 150.74,41.81 150.84,41.91 150.84,42.95 151.11,43.22 151.62,43.22 151.91,42.93 151.91,41.96 152.01,41.86 152.98,41.86 156.87,37.97 156.87,36.77 157.03,36.62 157.21,36.62 157.32,36.73 v1(157.32,36.83)
  IN4 w0.076: v4(141.7,34.58) 141.92,34.36 142.12,34.36 142.45,34.69 144.3,34.69 145.57,33.42 146.04,33.42 146.21,33.59 146.21,34.71 146.44,34.94 149.17,34.94 149.39,34.71 149.39,33.57 149.5,33.47 150.77,33.47 153.89,36.59 157.08,36.59 v1(157.32,36.83) 157.54,36.62 158.05,36.62 158.23,36.44 158.23,35.7 158,35.47 156.1,35.47 155.96,35.34 155.96,34.8 156.12,34.64 159.74,34.64 160.21,34.17 160.21,33.72 160.52,33.42 160.86,33.42 161.15,33.71 164.41,33.71 165.18,34.48 168.87,34.48 169.07,34.27 169.87,34.27 v4(170.05,34.45)
  BOTTOM w0.076: UCPU1.AN38 128.75,54.06 128.58,53.89 v1(128.58,53.8)
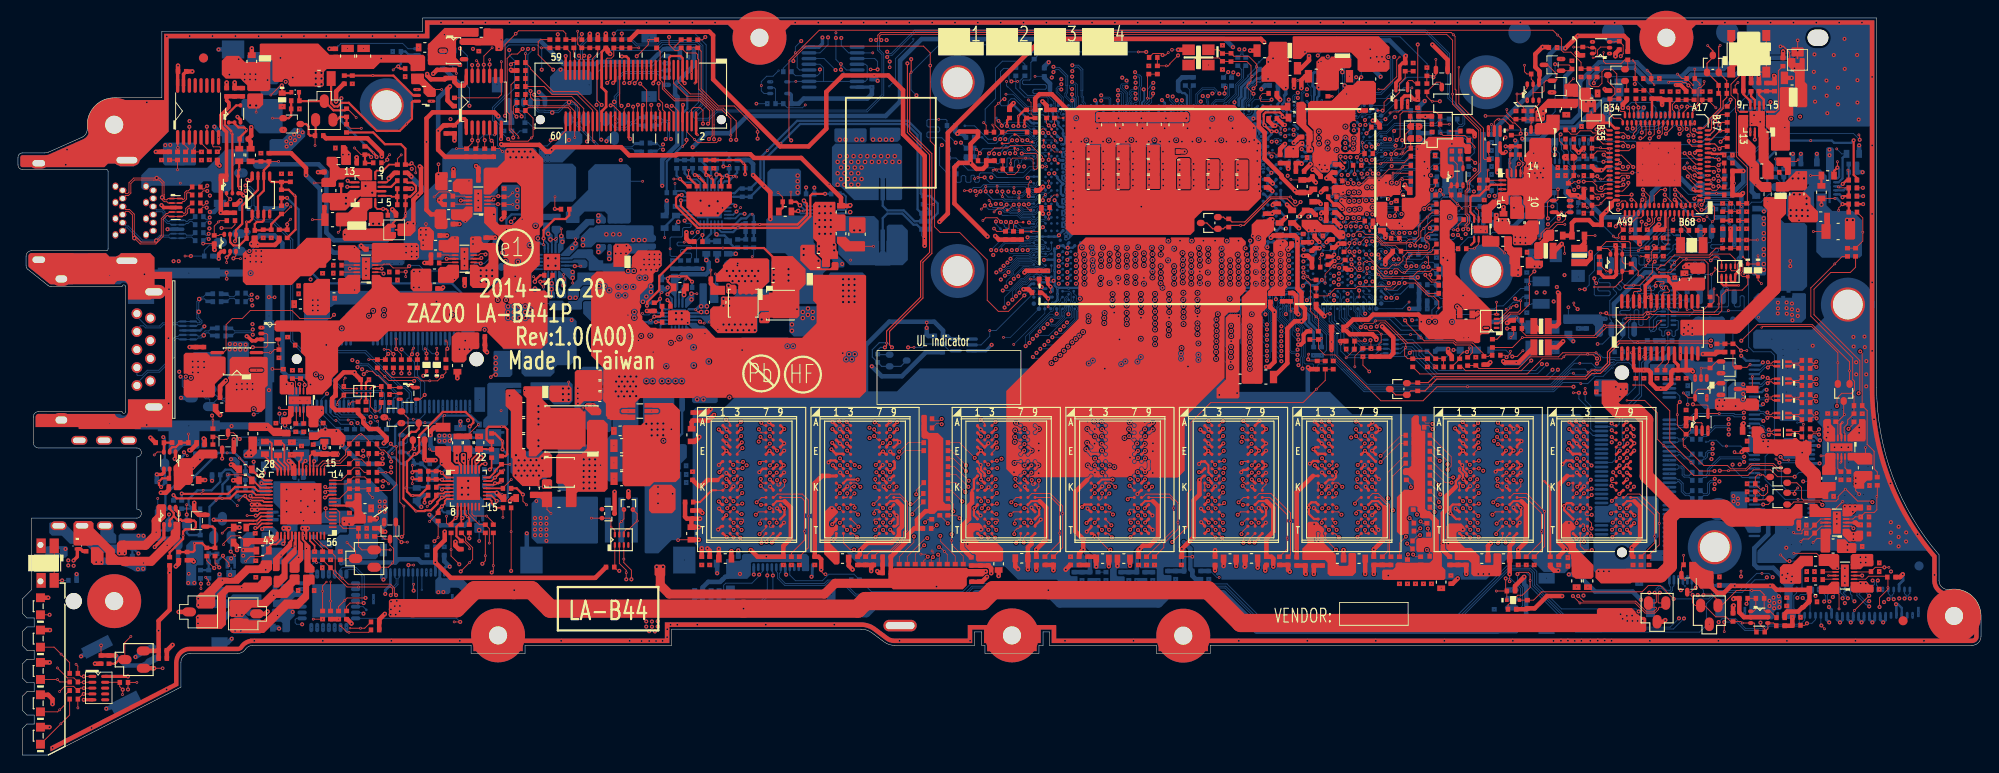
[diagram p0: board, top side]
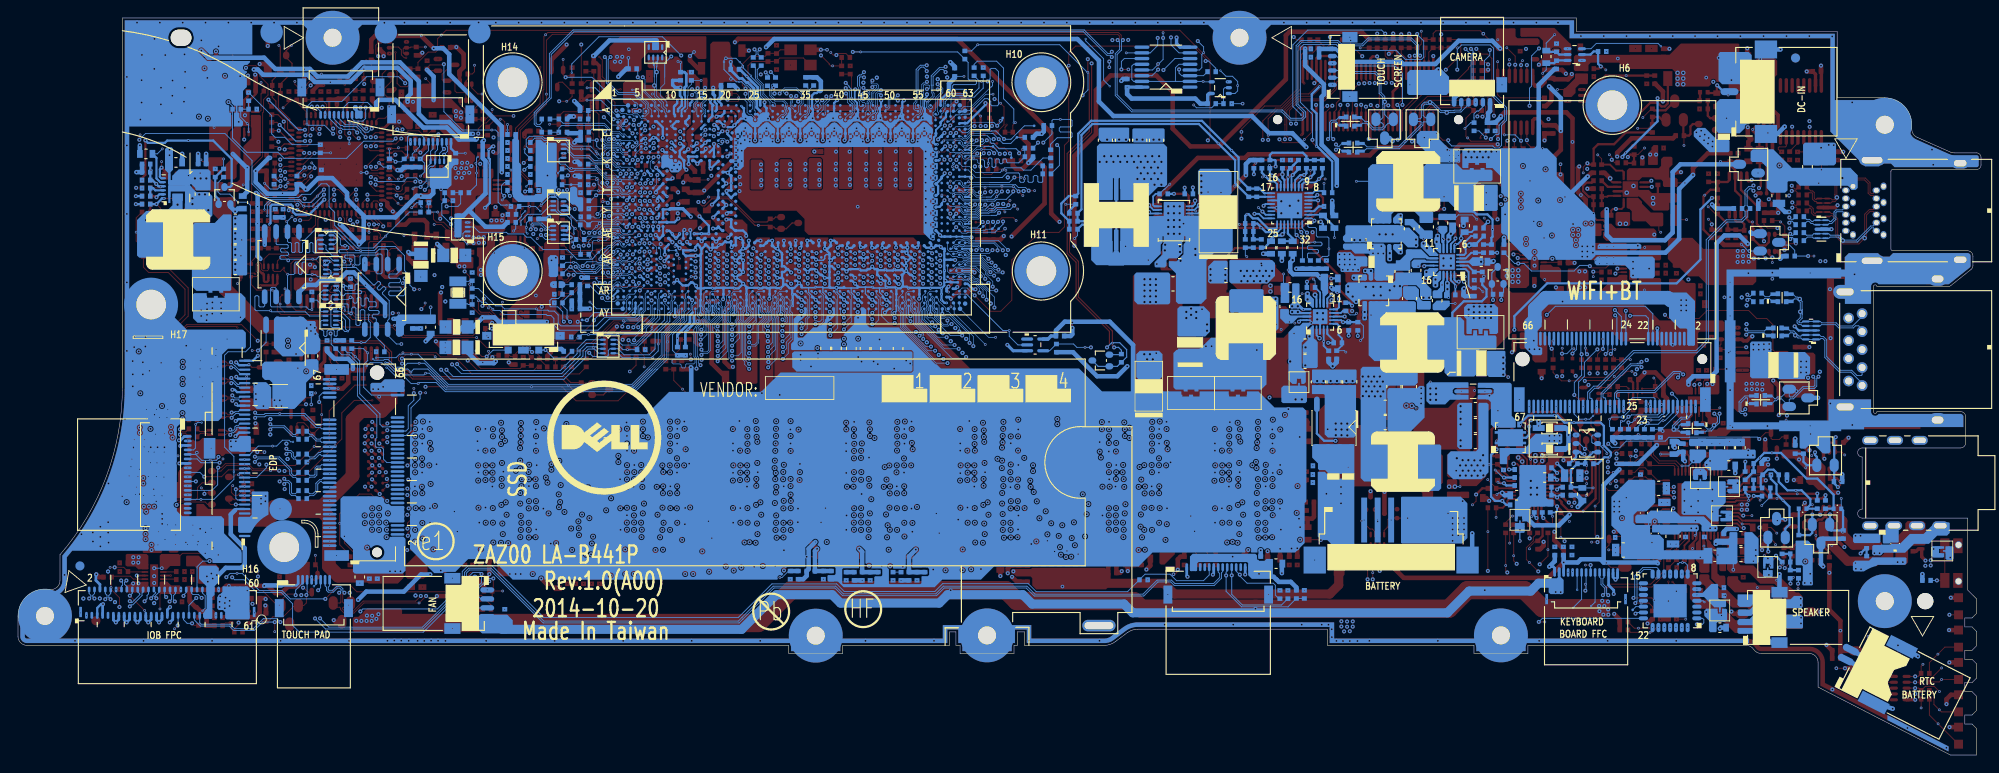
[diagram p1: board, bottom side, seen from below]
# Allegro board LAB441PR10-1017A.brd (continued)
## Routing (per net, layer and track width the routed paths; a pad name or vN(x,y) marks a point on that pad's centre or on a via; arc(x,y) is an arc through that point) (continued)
M_CLK_B_DDR#0: length 136.8
  TOP w0.076: RD78.1 156.57,36.65 156.92,36.65 v1(157.32,36.25)
  TOP w0.102: UD4.K7 177.24,29.96 v1(177.22,29.96) ; v1(148.87,29.83) 149.08,29.83 149.39,29.51 UD3.K7 ; v1(164.52,29.96) 165.02,29.45 165.1,29.45 UD1.K7 ; UD7.K7 136.7,29.45 136.7,29.45 v1(136.2,29.96)
  IN1 w0.076: v1(164.52,29.96) 164.52,30 164.77,30.26 164.87,30.26 165.06,30.45 165.06,32.43 165.96,33.33 167.47,33.33 167.69,33.54 167.69,34.63 167.83,34.77 168.65,34.77 168.79,34.63 168.79,34.37 169,34.16 169.76,34.16 v4(170.05,33.87) 170.34,34.16 171.54,34.16 172.31,33.38 173.76,33.38 173.79,33.36 175.22,33.36 176.55,32.03 176.55,30.43 176.77,30.21 176.97,30.21 v1(177.22,29.96) ; v1(148.87,29.83) 148.87,29.99 148.62,30.24 148.45,30.24 148.25,30.44 148.25,31.92 146.96,33.21 145.65,33.21 145.39,33.47 143.73,33.47 142.98,34.22 141.92,34.22 v4(141.7,34) 141.48,34.22 140.63,34.22 140.47,34.38 140.47,34.61 140.4,34.67 139.46,34.67 139.31,34.52 139.31,33.64 139.02,33.35 137.38,33.35 136.77,32.74 136.77,30.45 136.57,30.25 136.32,30.25 136.2,30.13 v1(136.2,29.96)
  IN1 w0.145: v1(128.58,54.39) 128.46,54.27 127.94,54.27 127.73,54.05 127.73,52.43 128.85,51.31 128.85,47.53 130.19,46.19 131.78,46.19 132.59,47 132.59,49.01 133.07,49.49 133.65,49.49 134.8,48.34 135.25,48.34 135.51,48.07 136.66,48.07 136.88,48.3 140.57,48.3 141.15,47.72 142.57,47.72 142.85,47.44 142.85,44.95 143.36,44.44 143.6,44.44 143.87,44.18 143.87,43.28 144.15,43 147.87,43 148.65,42.22 148.95,42.22 149.17,42.44 149.17,42.86 149.32,43 149.75,43 149.9,42.86 149.9,41.84 150.14,41.59 150.83,41.59 151.06,41.82 151.06,42.86 151.2,43 151.53,43 151.69,42.84 151.69,41.87 151.92,41.64 152.89,41.64 156.66,37.88 156.66,36.68 156.94,36.4 157.17,36.4 v1(157.32,36.25)
  IN4 w0.076: v4(141.7,34) 141.91,34.21 142.19,34.21 142.51,34.54 144.24,34.54 145.51,33.27 146.1,33.27 146.36,33.52 146.36,34.65 146.5,34.79 149.1,34.79 149.24,34.65 149.24,33.51 149.43,33.32 150.83,33.32 153.95,36.44 157.13,36.44 v1(157.32,36.25) 157.54,36.47 157.99,36.47 158.08,36.37 158.08,35.76 157.94,35.62 156.03,35.62 155.81,35.4 155.81,34.74 156.05,34.49 159.67,34.49 160.06,34.1 160.06,33.66 160.46,33.27 160.92,33.27 161.21,33.56 164.47,33.56 165.24,34.33 168.81,34.33 169.01,34.12 169.79,34.12 v4(170.05,33.87)
  BOTTOM w0.076: v1(128.58,54.39) 128.65,54.39 UCPU1.AM38
M_ODT0: length 77
  TOP w0.102: UD29.J1 91.02,30.25 v1(91.39,29.89) 91,29.51 UD29.K1 ; UD32.J1 119.35,30.26 119.39,30.26 v1(119.75,29.89) 119.35,29.49 UD32.K1 ; 78.39,29.45 UD28.K1 ; 78.39,29.45 78.8,29.86 v1(78.8,29.92) 78.46,30.25 UD28.J1 ; 78.39,29.45 77.64,29.45 ; UD31.K1 106.71,29.45 106.81,29.45 107.18,29.82 v1(107.18,29.85) 106.77,30.25 UD31.J1
  TOP w0.229: 77.64,29.45 77.16,29.45 75.85,28.14 RD92.1
  IN1 w0.076: v4(86.57,30.66) 86.77,30.86 88.29,30.86 88.36,30.8 89.74,30.8 90.27,30.27 93.16,30.27 93.17,30.26 97.09,30.26 97.86,31.03 106.15,31.03 106.94,30.24 106.94,30.09 v1(107.18,29.85) 107.27,29.85 107.4,29.97 107.4,30.13 107.33,30.19 107.33,30.33 107.43,30.43 107.57,30.43 107.73,30.28 108.07,30.28 108.22,30.43 108.44,30.43 108.57,30.29 108.88,30.29 108.89,30.29 109.48,30.89 109.87,30.89 109.94,30.95 109.94,31.05 110.05,31.17 110.22,31.17 110.34,31.05 110.34,29.49 110.48,29.35 112.36,29.35 112.46,29.45 112.46,29.81 112.56,29.91 113.77,29.91 114.32,30.46 114.32,30.98 114.42,31.08 114.66,31.08 114.76,30.98 114.76,30.56 114.89,30.43 115.71,30.43 115.98,30.7 116.08,30.7 116.39,30.39 116.98,30.39 117.52,30.93 117.52,31.32 119.04,32.84 119.04,33.01 118.92,33.13 118.75,33.13 117.06,31.43 117.06,31.15 116.77,30.86 116.51,30.86 v4(116.48,30.82)
  IN4 w0.076: v1(119.75,29.89) 119.8,29.84 119.8,29.68 119.42,29.3 119.23,29.3 119.13,29.4 119.13,29.51 119.36,29.73 119.36,29.84 119.25,29.94 119.14,29.94 118.92,29.72 118.81,29.72 118.7,29.83 118.7,29.94 119.15,30.38 119.15,30.49 119.04,30.6 118.93,30.6 118.49,30.15 118.38,30.15 118.27,30.26 118.27,30.37 118.72,30.81 118.72,30.92 118.61,31.03 118.5,31.03 118.07,30.6 117.94,30.6 117.86,30.67 117.86,30.72 117.78,30.8 117.63,30.8 117.56,30.72 117.56,30.67 117.48,30.6 117.33,30.6 117.25,30.67 117.25,30.72 117.17,30.8 117.02,30.8 116.95,30.72 116.84,30.82 v4(116.48,30.82) ; v1(78.8,29.92) 79.41,29.3 79.89,29.3 80.4,28.79 80.77,28.79 80.9,28.92 83,28.92 83.13,29.05 84.35,29.05 84.88,29.58 86.02,29.58 86.57,30.13 v4(86.57,30.66) 86.57,30.76 86.64,30.84 86.83,30.84 87.04,30.63 88.41,30.63 88.48,30.71 88.48,31 88.56,31.08 88.71,31.08 88.79,31 88.79,30.71 88.86,30.63 89.02,30.63 89.09,30.71 89.09,31 89.17,31.08 89.32,31.08 89.4,31 89.4,30.71 89.47,30.63 89.63,30.63 89.7,30.71 89.7,31 89.78,31.08 90.07,31.08 91.26,29.89 v1(91.39,29.89)
M_ODT2: length 81.1
  TOP w0.102: v1(145,29.89) 144.64,30.26 144.59,30.26 UD3.J1 UD3.K1 ; UD4.K1 UD4.J1 172.94,30.26 172.51,30.26 v1(172.42,30.16) ; v1(132.39,29.92) 132.05,30.26 132.05,30.25 UD7.J1 UD7.K1 ; UD1.K1 UD1.J1 160.37,30.25 v1(160.71,29.92)
  TOP w0.229: RD95.1 170.4,29.82 v3(169.75,30.47)
  GND1 w0.076: v3(169.75,30.47) v4(169.75,30.89)
  IN1 w0.076: v1(132.39,29.92) 133.45,28.86 134.34,28.86 134.39,28.9 136.65,28.9 136.83,29.08 137.57,29.08 138.1,29.62 139.15,29.62 140.21,30.67 140.76,30.67 141.47,31.38 141.99,31.38 142.36,31.01 v4(142.36,30.86) 142.36,30.68 142.28,30.61 141.13,30.61 141.05,30.53 141.05,30.34 141.13,30.27 142.35,30.27 142.54,30.08 142.89,30.08 142.97,30.15 142.97,30.41 142.89,30.49 142.77,30.49 142.69,30.56 142.69,30.72 142.77,30.79 142.89,30.79 142.97,30.87 142.97,30.96 143.05,31.04 143.2,31.04 143.27,30.96 143.27,30.15 143.35,30.08 143.54,30.08 143.62,30.15 143.62,30.33 143.7,30.41 143.83,30.41 143.93,30.31 143.93,29.93 144.07,29.78 144.15,29.78 144.23,29.86 144.23,30.19 144.31,30.27 144.52,30.27 144.62,30.16 144.62,29.57 144.7,29.49 145.33,29.49 145.41,29.57 145.41,30.18 145.33,30.25 145.08,30.25 145,30.18 v1(145,29.89) ; v4(169.75,30.89) 170.13,31.27 171.15,31.27 172.25,30.16 v1(172.42,30.16)
  IN4 w0.076: v4(169.75,30.89) 169.74,30.88 169.45,30.88 169.4,30.93 169.4,31.07 169.28,31.18 169.1,31.18 169.03,31.1 169.03,30.9 168.98,30.85 168.33,30.85 168.28,30.9 168.28,31.04 168.22,31.1 168,31.1 167.9,31 167.9,30.3 167.73,30.13 167.58,30.13 167.48,30.23 167.48,30.38 167.48,30.38 167.52,30.41 167.52,30.88 167.39,31 166.87,31 166.74,30.88 166.74,30.32 166.62,30.19 166.06,30.19 165.93,30.32 165.93,30.89 165.79,31.03 165.35,31.03 165.12,30.79 165.12,30.65 165.07,30.6 164.95,30.6 164.82,30.47 164.82,30.28 164.89,30.21 165.07,30.21 165.16,30.13 165.16,29.68 165.03,29.55 164.09,29.55 163.96,29.68 163.96,29.99 164.19,30.21 164.19,30.38 163.96,30.61 163.96,30.72 164.06,30.81 164.19,30.95 164.19,31.11 164.08,31.23 163.92,31.23 163.83,31.14 163.54,31.14 163.44,31.04 163.44,30.82 163.57,30.7 163.57,30.46 163.41,30.3 162.83,30.3 162.67,30.46 162.67,31.05 162.58,31.14 162.11,31.14 161.88,30.9 161.88,30.53 162.04,30.37 162.04,30.23 161.95,30.13 161.82,30.13 161.65,30.3 161.32,30.3 161.15,30.47 161.05,30.47 160.95,30.37 160.95,30.23 161.03,30.15 161.03,30.04 160.9,29.92 v1(160.71,29.92) 160.27,30.36 160.27,31.03 159.98,31.31 159.35,31.31 159.15,31.12 158.4,31.12 158.12,31.4 154.08,31.4 153.67,30.98 152.19,30.98 151.47,30.26 146.77,30.26 146.63,30.4 143.47,30.4 143.19,30.68 142.54,30.68 v4(142.36,30.86)
MCARD_PCIE#_SATA: length 38.5
  TOP w0.102: 187.94,37.98 v2(189.2,37.98) ; 187.94,37.98 187.94,38.83 187.83,38.94 186.36,38.94 v1(186.28,39.02) ; 187.94,37.98 U683.4
  IN4 w0.071: v1(170.64,61.04) 170.81,60.87 170.81,59.12 172.66,57.26 172.66,57 174.34,55.32 178.38,55.32 180.66,53.04 180.66,49.62 183.06,47.22 183.06,46.7 185.21,44.55 185.21,42.6 186.28,41.54 v1(186.28,39.02)
  BOTTOM w0.102: R1020.2 R1021.2 169.08,61.34 169.38,61.04 v1(170.64,61.04)
MCARD_PCIE#_SATA_R: length 27.6
  TOP w0.089: RH392.2 153.31,60.4 153.11,60.21 v1(153.11,59.98)
  IN2 w0.086: v1(170.15,59.05) 170.52,59.43 170.52,59.86 168.86,61.52 165.69,61.52 165.55,61.66 164.75,61.66 164.44,61.35 164.18,61.35 163.68,60.86 163.1,60.86 162.16,61.79 156.84,61.79 155.74,60.69 153.38,60.69 153.11,60.42 v1(153.11,59.98)
  BOTTOM w0.076: v1(153.11,59.98) 152.71,59.58 152.05,59.58 151.82,59.81 UCPU1.AC1
  BOTTOM w0.102: v1(170.15,59.05) 171.17,60.08 171.17,61.36 RH395.2 R1020.1
MCARD_PCIE_SATA#: length 9.4
  TOP w0.102: U683.2 187.29,36.08 187.29,36.88 187.21,36.97 186.51,36.97 186,36.46 186,36.17 R220.2 184.54,36.67 v2(184.54,37.87) 184.54,38.99 v1(184.81,39.27)
  BOTTOM w0.102: v1(184.81,39.27) 184.81,39.92 184.44,40.29 JNGFF3.61
MCP23017_I2CCLK: length 212.7
  TOP w0.102: v1(189.05,64.45) 189.13,64.45 189.5,64.09 RE73.1 ; v1(185.7,64.38) 185.7,64.26 186.05,63.91 186.05,63.88 186.7,63.24 UE5.B4
  IN1 w0.071: v1(189.05,64.45) 189,64.5 187.82,64.5 187.35,64.97 186.3,64.97 v1(185.7,64.38)
  IN3 w0.086: v4(33.96,20.12) 34.37,20.52 35.53,20.52 37.2,18.86 42.34,18.86 45.52,15.68 47.59,15.68 49.05,17.13 68.5,17.13 68.92,17.55 93.86,17.55 94.3,17.99 103.62,17.99 104.07,17.55 116.86,17.55 118.51,15.9 126,15.9 127.59,17.5 139.35,17.5 141.56,15.28 173.56,15.28 176.24,17.96 178.48,17.96 181.19,20.67 183.57,20.67 184.04,21.14 184.04,43.31 184.76,44.04 184.76,52.02 184.05,52.74 184.05,58.01 185.7,59.67 v1(185.7,64.38)
  GND3 w0.102: v4(33.96,20.12) 33.96,20.97 v5(33.71,21.22)
  BOTTOM w0.102: UE4.8 32.63,20.13 32.63,21.11 32.92,21.41 v2(33.2,21.41) 33.52,21.41 v5(33.71,21.22)
MCP23017_I2CDATA: length 212
  TOP w0.102: UE5.A3 188.24,62.99 188.41,62.82 188.88,62.82 189.12,63.06 v1(189.12,63.3) 189.3,63.3 189.4,63.2 RE71.1
  IN3 w0.086: v1(189.12,63.3) 189.21,63.2 189.21,58.06 189.54,57.73 189.54,52.63 189.87,52.3 189.87,49.06 189.42,48.61 189.42,42.75 186.69,40.02 186.69,38.6 186.05,37.96 186.05,30.1 185.35,29.4 185.35,20.54 183.43,18.62 181,18.62 178.99,16.62 176.76,16.62 174.08,13.94 141,13.94 138.76,16.18 128.16,16.18 126.57,14.59 117.96,14.59 116.32,16.23 103.52,16.23 103.08,16.68 94.85,16.68 94.4,16.23 69.53,16.23 68.45,15.15 56.51,15.15 55.46,16.19 49.93,16.19 48.66,14.92 43.76,14.92 42.92,15.77 42.92,17.48 42.1,18.3 37.38,18.3 37.18,18.1 34.59,18.1 v4(33.62,19.06)
  GND3 w0.102: v4(33.62,19.06) 33.27,19.41 v5(33.27,20.13)
  BOTTOM w0.102: v2(190.9,63.61) 190.25,62.96 189.44,62.96 189.12,63.28 v1(189.12,63.3)
ME_EN: length 4.2
  TOP w0.102: v2(161.4,45.3) 161.4,45.09 v1(161.14,44.84) 160.75,44.84 160.33,44.42 R1191.1 160.33,44.06 RH24.1
  BOTTOM w0.102: SW4.2 161.35,45.04 v1(161.14,44.84)
ME_FWP_EC: length 47.8
  TOP w0.102: v2(167.37,44.98) 166.72,44.33 v1(166.18,44.33) ; v1(168.29,43.89) 167.16,42.76 160.99,42.76 160.57,43.18 R1191.2 ; v1(179.06,64.31) 178.86,64.51 178.38,64.51 178.1,64.24 UE5.B46
  IN1 w0.071: v1(166.18,44.33) 166.2,44.35 167.14,44.35 167.61,43.89 v1(168.29,43.89) 168.76,44.35 174.27,44.35 176.06,46.14 177.23,46.14 178.23,47.14 179.24,47.14 179.93,47.83 179.93,48.21 179.81,48.32 v4(179.81,48.35)
  IN2 w0.086: v1(179.06,64.31) 179.48,63.89 179.48,63.41 178.79,62.73 178.79,60.42 178.15,59.77 178.15,57.93 178.17,57.91 178.17,54.35 178.19,54.34 178.85,53.67 178.85,50.86 179.94,49.77 179.94,48.47 v4(179.81,48.35)
  BOTTOM w0.102: SW4.3 165.47,45.04 v1(166.18,44.33)
ME_SUS_PWR_ACK: length 52.3
  TOP w0.102: RH297.2 165.33,44.48 v1(165.55,44.26) 165.98,44.69 v2(165.98,44.92) ; v1(189.15,65.05) 188.71,65.49 UE5.A8
  IN1 w0.071: v1(165.55,44.26) 165.84,43.97 167.13,43.97 167.61,43.49 168.42,43.49 169.1,44.18 174.35,44.18 176.14,45.96 177.4,45.96 178.4,46.97 179.56,46.97 181.07,48.48 181.07,49.87 181.3,50.1 182.02,50.1 182.28,49.84 186.9,49.84 190.06,46.68 v4(190.06,46.36)
  IN3 w0.086: v4(190.06,46.36) 190.06,46.36 190.06,52.38 189.72,52.71 189.72,57.81 189.4,58.13 189.4,62.84 189.5,62.94 189.5,64.69 v1(189.15,65.05)
MEC_XTAL1: length 3.7
  TOP w0.102: YE1.1 184.9,58.31 CE62.1 184.95,59.64 184.72,59.88 UE5.A61
MEC_XTAL2: length 2.6
  TOP w0.102: YE1.2 187.4,57.77 187.6,57.96 CE53.1 RE62.2
MEC_XTAL2_R: length 2.2
  TOP w0.102: RE62.1 185.22,58.97 UE5.A62
MEDIACARD_IRQ#: length 85.1
  TOP w0.102: v1(197.01,21.57) 196.72,21.57 v2(196.03,22.26) ; v1(156.39,60.74) 156.94,61.29 RH3533.1
  IN1 w0.071: v4(185.04,31.51) 185.88,31.51 193.81,23.58 193.81,20.93 194,20.74 196.17,20.74 v1(197.01,21.57)
  IN2 w0.086: v1(156.39,60.74) 155.22,59.57 152.43,59.57 151.47,60.53 149.66,60.53 149.54,60.41 148.94,60.41 v1(148.66,60.69) ; v4(158.02,47.75) 158.75,47.02 160.58,47.02 161.18,46.43 167.86,46.43 168.33,45.96 169.55,45.96 177.55,37.96 180.74,37.96 182.87,35.83 182.87,33.68 v4(185.04,31.51)
  IN3 w0.14: v4(158.02,47.75) 158.02,48.78 159.39,50.15 159.39,56.42 158.58,57.23 158.58,59.55 157.8,60.34 156.8,60.34 v1(156.39,60.74)
  BOTTOM w0.076: v1(148.66,60.69) 148.32,60.34 UCPU1.AB6
  BOTTOM w0.102: v1(197.01,21.57) 197.76,21.57 198.4,20.93 JIO1.42
MEDIACARD_PWREN: length 103.7
  TOP w0.102: U716.5 206.03,20.37 R1176.1 206.55,20.88 v1(207.56,20.88) v2(208.06,20.88)
  GND1 w0.102: v4(158.07,68.89) 157.65,69.31 v3(157.27,69.31)
  IN1 w0.071: v4(194.15,21.15) 194.15,23.48 185.62,32.02 v4(185.04,32.02)
  IN2 w0.086: v4(185.04,32.02) 183.06,34 183.06,35.91 180.82,38.15 177.63,38.15 173.37,42.41 173.37,47.16 173.06,47.47 169.91,47.47 169.48,47.9 166.48,47.9 165.49,48.89 163.51,48.89 163.02,48.41 162.09,48.41 161.39,49.11 158.41,52.09 154.39,52.09
  IN2 w0.089: v1(152.45,52.51) 152.87,52.09 154.39,52.09
  IN3 w0.076: 155.46,57.11 154.09,57.11 153.85,56.87 153.85,55.79 154.06,55.58 154.06,54.88 153.79,54.6 153.79,53.34 153.43,52.98 152.92,52.98 v1(152.45,52.51)
  IN3 w0.086: 155.46,57.11 156.01,57.11 156.24,57.34 156.24,57.8 156.36,57.92 156.36,58.16 155.21,59.31 155.21,61.32 155.92,62.03 155.92,63.51 156.08,63.67 157.92,63.67 158.36,64.11 158.36,66.68 158.07,66.96 v4(158.07,68.89)
  IN4 w0.086: v4(194.15,21.15) 194.95,21.95 203.61,21.95 204.11,22.45 205.99,22.45 v1(207.56,20.88)
  BOTTOM w0.076: UCPU1.AP1 151.84,52.83 152.12,52.83 v1(152.45,52.51)
MEDIACARD_RST#: length 12.5
  TOP w0.089: v1(148.51,57.83) 148.89,58.22 149.53,58.22 149.84,57.91 150.97,57.91 151.85,57.03 154.34,57.03 154.7,57.39 155.43,57.39
  TOP w0.102: RH3535.1 157.29,60.4 v2(156.73,59.84) 155.78,58.9 155.78,57.74 155.43,57.39
  BOTTOM w0.076: UCPU1.AG6 148.32,57.64 v1(148.51,57.83)
MEM_CONFIG0: length 9.8
  TOP w0.089: 153.27,73.34 152.97,73.04 152.34,73.04 151.92,72.62 151.92,71.86 v1(151.76,71.69) 151.74,71.71 T286.1
  TOP w0.102: RH316.2 RH303.1 154.27,75.34 153.62,74.69 153.62,73.7 153.27,73.34
  BOTTOM w0.076: UCPU1.C4 149.49,71.01 149.57,71.1 149.85,71.1 150.04,71.29 150.58,71.29 150.65,71.36 151.22,71.36 151.55,71.69 v1(151.76,71.69)
MEM_CONFIG1: length 16.7
  IN3 w0.086: v4(155.34,62.81) 155.34,63.23 155.96,63.86 157.84,63.86 158.11,64.12 158.11,66.48 157.93,66.66 154.9,66.66 153.76,67.79 v1(153.2,67.79)
  GND3 w0.102: v4(155.34,62.81) 155.34,63.01 155.78,63.45 v5(155.81,63.45)
  BOTTOM w0.076: v1(153.2,67.79) 153.19,67.78 151.43,67.78 150.96,67.3 UCPU1.J2
  BOTTOM w0.102: v5(155.81,63.45) 155.82,63.46 T287.1 156.81,63.45 RH180.1
MEM_CONFIG2: length 11.6
  TOP w0.102: v1(153.32,68.42) 153.7,68.8 153.7,71.25 154.02,71.57 157.66,71.57 RH271.1 RH314.2 v2(159.18,70.18)
  BOTTOM w0.076: UCPU1.G1 151.77,68.05 151.85,67.97 152.87,67.97 153.27,68.37
  BOTTOM w0.102: v1(153.32,68.42) 153.27,68.37
MIC1-VREFO: length 19.1
  TOP w0.102: v1(26.44,26.64) v2(25.48,26.64)
  TOP w0.203: v1(26.44,26.64) 26.62,26.64 26.94,26.95 27.91,26.95 UA2.38
  IN1 w0.254: v1(13.4,22.42) 15.79,22.42 20.01,26.64 26.44,26.64 v1(26.44,26.64)
  BOTTOM w0.254: RA27.1 12.72,22.14 RA28.1 12.82,23 v1(13.4,22.42)
MIC1_L: length 12.6
  IN2 w1.016: 14.82,24.16 15.01,24.35 18.74,24.35 19.62,25.23 19.62,26.9 20.86,28.14 24.75,28.14
  vias: v1(13.4,24.4) v1(13.96,24.39) v1(26,27.86) v1(26.6,27.87)
MIC1_L_L: length 6.6
  TOP w1.016: 15.93,26.61 15.37,26.05 v2(15.37,24.79) 15.37,24.52 14.18,23.34 11.53,23.34
  vias: v1(11.28,22.45) v1(11.86,22.46)
MIC1_R: length 13.6
  IN2 w1.016: 14.77,21.12 16.75,23.11 19.08,23.11 20.74,24.76 20.74,26.44 21.33,27.02 24.91,27.02
  vias: v1(8.69,21.46) v1(9.28,21.46) v1(13.34,20.67) v1(13.92,20.71) v1(26.02,27.29) v1(26.61,27.29) v2(13.96,21.36)
MIC1_R_L: length 7.2
  TOP w1.016: 17.5,24.68 17.5,24.24 v2(16.59,23.33) 14.82,21.56 11.89,21.56
MMICLK_REQ#: length 95.5
  TOP w0.102: v1(152.78,63.68) 152.91,63.81 152.91,64.72 v2(152.93,64.74) 153.74,64.74 153.76,64.72 RH100.2
  IN1 w0.071: v1(152.78,63.68) 153.16,64.06 156.8,64.06 157.48,63.38 160.33,63.38 160.46,63.25 162.42,63.25 162.92,62.74 166.09,62.74 168.37,60.46 171.79,60.46 173.3,58.95 176.13,58.95 177.12,59.94 178.45,59.94 178.66,60.15 180.64,60.15 181,60.51 181.93,60.51 182.35,60.93 185.03,60.93 185.58,61.49 186.89,61.49 187.09,61.69 187.56,61.69 187.79,61.46 187.79,60.49 188.24,60.04 188.24,59.75 187.95,59.47 187.95,59.11 188.24,58.83 188.24,53.26 189.11,52.38 189.11,51.09 191.91,48.29 191.91,47.1 193.27,45.74 193.27,44.69 193.66,44.31 194.85,44.31 195.5,43.66 195.5,36.08 196.55,35.02 196.55,25.85 199.34,23.06 199.34,20.25 201.83,17.76 v1(201.83,17.57)
  BOTTOM w0.076: v1(152.78,63.68) 152.78,63.4 152.65,63.28 151.42,63.28 150.95,62.81 UCPU1.U2
  BOTTOM w0.102: v1(201.83,17.57) 202,17.74 JIO1.30
MONO_IN: length 9.1
  TOP w0.102: v2(23.45,21.05) 23.45,21.36 22.8,22.01 v1(22.8,22.17)
  TOP w0.203: UA2.41 27.12,25.75 26.61,25.25 v1(26.39,25.25)
  IN1 w0.254: v1(26.39,25.25) 25.58,25.25 22.8,22.47 v1(22.8,22.17)
  BOTTOM w0.254: v1(22.8,22.17) 22.13,21.5 CA34.2
MPCIE_RST#: length 164.2
  TOP w0.102: U675.1 41.43,40.88 R1314.1 40.1,42.21 39.89,42.21 39.41,42.69 v2(38.83,42.69) 38.77,42.69 v1(38.45,42.38) ; v1(157.24,62.88) 157.65,63.29 RH393.1
  IN1 w0.071: 154.53,63.17 154.91,63.55 156.57,63.55 v1(157.24,62.88)
  IN1 w0.086: 154.53,63.17 154.25,62.89 153.29,62.89 152.37,61.97 v1(152.37,61.87)
  IN4 w0.071: v1(38.45,42.38) 38.77,42.69 39.89,42.69 41.25,44.06 42.33,44.06 43.1,44.83 43.1,45.59 49.04,51.54 49.04,56.52 49.98,57.46 49.98,62.37 50.35,62.74 50.35,66.38 49.86,66.87 49.86,69.28 54.83,74.24 56.05,74.24 57.17,75.37 67,75.37 67.42,75.79 74.38,75.79 75.15,75.02 78.43,75.02 80,73.45 88.65,73.45 89.49,74.29 96.85,74.29 97.1,74.04 98.75,74.04 99.76,73.02 100.24,73.02 102.66,70.6 105.25,70.6 106.87,68.99 106.87,68 107.35,67.52 107.35,66.55 107.74,66.16 109.58,66.16 110.67,65.06 113.64,65.06 116.28,62.43 116.28,59.1 116.82,58.56 119.41,58.56 121.08,60.23 137.56,60.23 138.09,60.76 144.11,60.76 144.28,60.93 145.8,60.93 146.44,60.3 147.34,60.3 147.61,60.57 147.61,60.71 148.04,61.13 149.34,61.13 149.54,61.34 150.78,61.34 151.34,61.9 152.34,61.9 v1(152.37,61.87)
  BOTTOM w0.076: UCPU1.V1 152.18,62.06 v1(152.37,61.87)
MPHY_PWREN#: length 10.8
  TOP w0.102: v2(167.54,76.74) 167.54,76.02 167.8,75.77 R1381.2 168.29,75.2 168.5,75 168.5,74.63 ; 168.5,73.69 168.5,72.84 Q361.2 ; 168.5,73.69 169.52,73.69 169.72,73.88 169.72,74.81 169.93,75.02 Q39.2 171.01,75.02 171.14,75.15 171.14,75.74 170.1,76.79 Q362.1 ; 168.5,73.69 168.5,74.63 ; 168.5,74.63 Q361.5
MPHYP_PWR_EN: length 39.2
  TOP w0.102: v1(170.95,76.86) 171.04,76.77 172.5,76.77 172.81,76.46 R1169.1 172.62,76.14 Q362.2
  IN1 w0.099: v4(155.11,61.76) 155.14,61.76 155.48,62.1 162.06,62.1 162.69,61.47 v4(163.49,61.47)
  GND3 w0.102: v5(154.83,60.78) 154.84,60.78 155.11,61.06 v4(155.11,61.76) ; v4(163.49,61.47) 163.77,61.47 163.97,61.27 v5(163.97,61.18)
  BOTTOM w0.076: 154.53,61.03 151.23,61.03 UCPU1.Y2
  BOTTOM w0.102: v5(154.83,60.78) 154.58,61.03 154.53,61.03 ; v1(170.95,76.86) 170.95,71.58 168.9,69.53 v2(165.61,69.53) 165.19,69.53 164.91,69.26 164.91,61.5 164.59,61.18 v5(163.97,61.18)
MSATA_DEVSLP: length 75.7
  TOP w0.076: v1(150.66,64.68) 150.66,64.83 v2(150.4,65.1)
  IN1 w0.071: v1(150.66,64.68) 151.02,64.33 151.45,64.33 151.93,64.81 153.69,64.81 154.36,65.48 157.95,65.48 158.12,65.32 160.72,65.32 161.73,64.31 165.61,64.31 167.85,62.07 171.24,62.07 173.4,64.23 174.24,64.23 175.81,62.66 177.06,62.66 177.2,62.52 178.91,62.52 179.2,62.81 180.1,62.81 180.57,63.28 182.08,63.28 v4(183.19,64.39)
  IN4 w0.071: v4(183.19,64.39) 183.19,63.6 183.73,63.07 183.73,59.12 182.98,58.37 182.98,55.76 182.73,55.51 182.73,52.78 182.6,52.64 182.6,47.96 183.55,47.01 v1(183.55,46.9)
  BOTTOM w0.076: v1(150.66,64.68) 150.95,64.39 UCPU1.P2
  BOTTOM w0.102: JNGFF3.38 177.29,32.54 177.66,32.92 177.66,34.03 177.87,34.24 178.47,34.24 178.57,34.34 178.57,35.15 178.4,35.32 178.4,37.8 180.56,39.96 180.56,43.65 181.44,44.53 182.29,44.53 R1376.2 183.48,45.72 183.48,46.83 v1(183.55,46.9)
MSATACLK_REQ#: length 64.7
  TOP w0.102: v1(174.29,40.26) v2(174.29,40.79)
  IN1 w0.071: v4(182.88,45.35) 182.74,45.21 182.34,45.21 180.66,43.53 180.66,41.1 179.51,39.94 175.48,39.94 175.09,40.33 174.36,40.33 v1(174.29,40.26)
  IN4 w0.071: v4(182.88,45.35) 182.88,45.77 182.28,46.38 182.28,46.9 180.8,48.37 180.33,48.37 179.88,48.83 179.88,52.71 178.18,54.4 175.82,54.4 175.34,53.92 173.5,53.92 170.53,56.89 170.53,57.43 169.89,58.08 169.7,58.08 169.02,58.76 169.02,60.71 167.74,62 165.59,62 164.57,63.02 162.83,63.02 162.22,63.63 161.07,63.63 160.86,63.43 158.87,63.43 v4(158.58,63.72)
  GND3 w0.102: v4(158.58,63.72) 158.3,64 158.3,64.68 v5(158.25,64.73)
  BOTTOM w0.076: 154.32,65.06 154.29,65.03 153.95,65.03 152.96,64.03 151.98,64.03 151.78,63.84 151.24,63.84 UCPU1.T2
  BOTTOM w0.102: v5(158.25,64.73) 158.25,64.77 RH110.2 157.22,65.22 156.92,64.92 156.51,64.92 156.36,65.06 154.32,65.06 ; v1(174.29,40.26) 174.29,39.47 174.91,38.85 174.91,36.31 175.17,36.04 JNGFF3.52
MSCLK: length 10.8
  TOP w0.102: v1(178.5,65.43) 178.2,65.74 177.87,65.74 UE5.B43
  IN1 w0.071: v4(173.58,65.94) 174.06,65.46 178.48,65.46 v1(178.5,65.43)
  GND3 w0.102: v4(173.58,65.94) v5(173.58,66.32)
  BOTTOM w0.102: JDEG1.6 172.66,67.24 v5(173.58,66.32) 173.57,66.32 173.12,65.87 173.12,64.84 v2(173.55,64.41)
MSDATA: length 8.8
  TOP w0.102: UE5.A40 176.94,65.99 176.33,65.99 v1(176.32,66)
  BOTTOM w0.102: JDEG1.7 173.16,68.67 173.4,68.91 174.85,68.91 175,68.76 175,66.68 RE75.2 175.67,66 v1(176.32,66) 176.64,66.32 RE85.1 v2(177,67.42)
NB_MUTE#: length 28.4
  TOP w0.102: v1(21.82,20.8) 21,21.62 RA57.1
  TOP w0.203: UA2.52 32.46,24.2 32.46,24.2 32.46,23.84 32.99,23.32 v3(32.99,22.63)
  GND1 w0.254: v4(33.96,22.63) v3(32.99,22.63)
  IN1 w0.102: v4(33.96,22.63) 33.46,22.63 31.32,20.49 22.13,20.49 v1(21.82,20.8)
  IN4 w0.102: v4(33.96,22.63) 33.42,22.09 33.42,19.9 37.59,15.73 v1(38.42,15.73)
  BOTTOM w0.102: UE4.20 38.3,15.86 v1(38.42,15.73)
NB_PSID: length 5.3
  TOP w0.102: v1(29.34,74.51) 29.2,74.51 v2(28.12,73.43)
  TOP w0.254: v1(29.34,74.51) 29.38,74.47 PD102.1 30.31,73.64 PL102.2
  BOTTOM w0.254: v1(29.34,74.51) 28.63,73.8 JP100.3
NFC_DET#: length 194.6
  TOP w0.076: v1(149.15,51.69) v2(149.15,50.96)
  TOP w0.102: RH465.1 v3(159.22,69.42)
  GND1 w0.102: v3(159.22,69.42) 159.22,69.19 v4(159.49,68.92)
  IN1 w0.071: 150.4,52.03 149.5,52.03 v1(149.15,51.69) ; 153.27,50.48 153.74,50.48 154.02,50.76 155.57,50.76 156.3,50.02 v4(156.32,50.02)
  IN1 w0.076: 150.4,52.03 151.95,50.48 153.27,50.48
  IN2 w0.086: v1(82.43,20.07) 82.81,20.45 84.01,20.45 85.32,19.14 105.31,19.14 106.04,18.41 114.26,18.41 114.39,18.27 125.99,18.27 126.1,18.38 170.2,18.38 171.22,19.4 178.07,19.4 182.58,23.91 182.58,35.85 180.69,37.75 177.5,37.75 169.63,45.61 168.38,45.61 167.76,46.24 163.54,46.24 162.91,45.61 160.63,45.61 159.98,46.26 158.21,46.26 156.52,47.96 156.52,49.82 v4(156.32,50.02)
  IN3 w0.086: v4(156.32,50.02) 156.5,50.21 156.5,50.76 154.39,52.87 ; v4(159.49,68.92) 159.09,68.53 159.09,67.07 159.31,66.85 159.31,65.31 159.85,64.77 159.85,63.64 158.43,62.21 156.37,62.21 155.4,61.24 155.4,59.39 156.55,58.24 156.55,57.85 156.43,57.72 156.43,57.33 157.02,56.73 157.02,56.26 156.81,56.04 155.46,56.04
  IN3 w0.089: 155.46,56.04 155.45,56.04 153.96,54.54 153.96,53.3 154.39,52.87
  BOTTOM w0.076: UCPU1.AT5 148.7,52.14 149.15,51.69 v1(149.15,51.69)
  BOTTOM w0.102: JNFC1.12 82.83,20.46 82.44,20.07 v1(82.43,20.07) 82.43,19.93 81.61,19.12 78.71,19.12 78.48,18.89 78.48,17.79 78.08,17.4 R1228.1
NFC_IRQ: length 181.7
  TOP w0.102: v1(156.85,54.3) 156.85,55.33 v2(156.77,55.41)
  IN2 w0.086: v1(156.85,54.3) 156.99,54.17 158.24,54.17 162.03,50.38 166.8,50.38 167.78,51.36 167.78,53.25 167.96,53.43 169.94,53.43 170.56,54.04 172.84,54.04 173.26,53.63 173.26,51.26 174.02,50.5 174.02,48.91 174.21,48.73 174.21,48.16 174.21,48.16 174.21,47.11 173.96,46.85 173.96,42.62 177.28,39.3 180.55,39.3 183.68,36.17 183.68,34.52 184.81,33.39 185.26,33.39 185.43,33.22 185.43,26.48 178.12,19.17 171.25,19.17 170.28,18.2 126.18,18.2 126.07,18.09 114.31,18.09 114.18,18.22 105.96,18.22 105.24,18.95 84.37,18.95 v1(83.33,19.99)
  BOTTOM w0.076: 154.39,53.6 153.98,53.6 153.45,54.13 152.38,54.13 152.32,54.07 151.77,54.07 151.72,54.11 151.48,54.11 151.31,53.94 151.31,53.76 151.08,53.52 150.56,53.52 UCPU1.AN3
  BOTTOM w0.102: 154.39,53.6 156.16,53.6 156.45,53.88 156.45,53.9 v1(156.85,54.3) 156.99,54.3 RH294.1 ; R1100.2 77.79,16.69 82.14,16.69 83.33,17.88 v1(83.33,19.99) JNFC1.11
NFC_VDD_SIM: length 12.5
  BOTTOM w0.102: JNFC1.10 83.83,20.47 83.95,20.35 v1(83.95,19.97) 83.95,18.21 82.22,16.49 77.07,16.49 R973.2 R974.1
NGFF_ON: length 23.2
  TOP w0.102: v1(40.66,53.56) 40.5,53.72 U720.3 ; R1186.2 43.08,53.74 v1(43.12,53.77) v2(43.12,53.22)
  GND1 w0.102: v3(40.74,37.58) v4(40.74,37.99)
  IN2 w0.086: v1(43.12,53.77) 42.9,53.56 v1(40.66,53.56) 38.07,50.97 38.07,48.21 39.73,46.54 39.73,39 v4(40.74,37.99)
NGFF_PWREN: length 164.9
  TOP w0.076: v2(148.21,64.03) 148.53,63.71 v1(148.53,63.6)
  GND1 w0.102: v3(42.64,36.93) v4(42,36.93)
  IN1 w0.071: v1(148.53,63.6) 148.9,63.23 149.46,63.23 149.8,63.58 150.96,63.58 151.4,63.15 153.39,63.15 154.08,63.83 156.79,63.83 157.41,63.2 160.25,63.2 160.38,63.07 162.28,63.07 162.78,62.57 163.24,62.57 v1(163.61,62.21)
  IN3 w0.086: 110.07,69.58 109.82,69.58 109.71,69.47 107.49,69.47 106.57,68.55 100.99,68.55 99.11,70.43 80.9,70.43 78.67,72.66 75.08,72.66 73.98,71.56 67.31,71.56 65.56,69.81 50.67,69.81 49.5,68.64 49.5,63.01 50.29,62.23 50.29,58.77 52.8,56.26 52.8,55.55 53.36,54.98 53.36,52.76 51.54,50.94 48.18,50.94 46.13,48.9 46.13,43.82 45.63,43.32 45.55,43.32 44.62,42.4 44.62,39.54 v4(42,36.93)
  IN3 w0.089: 110.07,69.58 115.6,69.58 115.88,69.31 137.84,69.31 139.3,67.84 140.44,67.84 141.24,67.04 144.63,67.04 144.82,66.86 145.47,66.86 146.66,65.66 146.66,65.52 147.24,64.95 148.14,64.95 148.28,64.81 148.28,63.86 v1(148.53,63.6)
  BOTTOM w0.076: v1(148.53,63.6) 148.32,63.82 UCPU1.R6
  BOTTOM w0.102: R1396.1 163.87,62.47 v1(163.61,62.21)
NGFF_RST#: length 198.4
  TOP w0.102: v1(45.23,40.06) 44.76,39.58 U675.4 ; v1(173.59,40.3) v2(172.97,40.3) ; v1(44.42,44.59) R1203.1
  IN2 w0.086: v1(173.59,40.3) 174.27,39.62 175.21,39.62 177.39,37.44 180.16,37.44 182.29,35.31 182.29,24.06 177.92,19.7 171.11,19.7 170.08,18.67 125.98,18.67 125.87,18.56 114.51,18.56 114.38,18.7 106.16,18.7 105.43,19.43 85.48,19.43 84.06,20.84 72.42,20.84 71.52,21.74 66.07,21.74 64.21,19.88 47.71,19.88 v4(47.12,20.47)
  IN4 w0.071: v1(45.23,40.06) 44.48,39.31 44.48,30.6 44.04,30.15 44.04,25.1 47.12,22.02 v4(47.12,20.47)
  BOTTOM w0.102: JNGFF1.44 44.5,44.67 v1(44.42,44.59) 44.42,42.26 45.23,41.45 v1(45.23,40.06) ; v1(173.59,40.3) 173.59,39.63 174.6,38.62 174.6,36.09 175.15,35.54 JNGFF3.50
O-USR: length 5.9
  TOP w0.102: v1(73.63,64.09) v2(72.94,64.09)
  TOP w0.254: PR709.1 74.44,63.27 v1(73.63,64.09)
  BOTTOM w0.203: v1(73.63,64.09) 74.01,63.7 75.3,63.7 75.48,63.52 PU700.9
  BOTTOM w0.254: PR704.2 73.25,64.47 v1(73.63,64.09)
OCP-I: length 4.9
  TOP w0.254: PR730.2 76.48,64.59 v1(76.55,64.53) 76.77,64.53 v2(77.05,64.25) 77.31,63.99 PR706.1
  BOTTOM w0.203: v1(76.55,64.53) 76.68,64.39 PU700.12
  BOTTOM w0.254: v1(76.55,64.53) 75.91,65.17 PR701.2
PANEL_BKEN_EC: length 188.2
  TOP w0.102: v1(189.26,31.63) v2(190.23,31.63) 192.23,31.63 192.81,32.21 195.12,32.21 195.74,31.59 D72.3
  IN2 w0.086: v4(31.13,16.6) 31.81,15.92 37.4,15.92 38.28,15.04 45.2,15.04 49.19,19.03 64.57,19.03 66.42,20.89 69.67,20.89 72.35,18.2 104.92,18.2 105.65,17.47 113.87,17.47 114,17.33 127.07,17.33 127.12,17.38 170.61,17.38 171.43,18.2 172.05,18.2 172.32,17.93 172.32,17.46 172.67,17.1 178.29,17.1 180.41,19.22 182.99,19.22 184.45,17.77 185.19,17.77 186.56,19.14 186.56,20.64 185.68,21.51 185.68,24.48 188.43,27.24 188.43,29 188.08,29.36 188.08,31.58 188.49,31.99 188.93,31.99 189.26,31.66 v1(189.26,31.63)
  GND3 w0.102: v5(30.75,17.01) 30.75,16.98 v4(31.13,16.6)
  BOTTOM w0.102: UE4.4 31.6,17.16 30.9,17.16 v5(30.75,17.01)
PANEL_BKLEN: length 121.6
  TOP w0.102: D72.2 197.82,30.29 198.34,29.77 198.34,28.58 198.56,28.36 200.58,28.36 200.68,28.25 202.19,28.25 202.43,28.49 202.43,28.79 v2(203.22,29.57) 203.27,29.57 204.59,28.25 206.11,28.25 v1(206.23,28.13)
  IN2 w0.086: v1(206.23,28.13) 205.67,28.68 205.67,34.23 204.37,35.54 204.37,38.22 201.84,40.74 199.3,40.74 198.84,41.21 198.84,50.75 196.09,53.5 196.09,69.42 189.4,76.11 181.76,76.11 180.86,77.02 171.7,77.02 171.09,76.41 168.89,76.41 168.28,77.02 168.19,77.02 165.47,79.74 147.69,79.74 v1(145.66,77.71)
  BOTTOM w0.076: UCPU1.A9 146.15,72.63 146.88,73.36 146.88,74.19 146.38,74.69 146.38,75.43
  BOTTOM w0.102: 146.38,75.43 146.38,76.99 v1(145.66,77.71)
PBAT_PRES#: length 181.4
  TOP w0.102: v1(66.87,20.49) 66.73,20.49 PR100.2 66.38,20.97 PRP100.1 ; PR224.1 v2(54.84,24.85) v1(54.84,20.48) ; UE5.A49 178.72,60.01 177.69,58.98 v1(177.69,58.82)
  IN3 w0.086: v1(54.84,20.48) 54.85,20.49 v1(66.87,20.49) 69.95,20.49 70.98,19.45 93.05,19.45 93.47,19.87 102.68,19.87 103.81,21.01 108.76,21.01 110.19,19.57 117.53,19.57 119.16,17.94 125.13,17.94 126.57,19.38 140.76,19.38 141.64,18.51 171.11,18.51 171.7,19.1 174.44,19.1 175.19,19.85 177.71,19.85 181.75,23.9 181.75,38.86 180.3,40.32 180.3,44.6 178.6,46.3 178.6,51.1 177.88,51.82 177.88,55.39 178.15,55.66 178.15,57.45 177.69,57.91 v1(177.69,58.82)
PBAT_SMBCLK: length 188.5
  TOP w0.102: v1(68.22,19.55) 68.22,20.56 67.38,21.4 v2(67.38,21.8) 67.38,23.37 PRP100.3 ; UE5.A56 182.22,59.92 182,59.7 182,59.25 v3(181.2,58.45)
  GND1 w0.102: v3(181.2,58.45) 181.2,58.1 181.03,57.94 181.03,57.94 v4(180.97,57.94)
  IN2 w0.086: v4(180.97,57.94) 180.97,54.19 181.46,53.69 181.46,53.08 181.75,52.79 181.75,52.05 184.38,49.43 185.66,49.43 187.5,47.59 187.5,45.71 189.25,43.96 192.29,43.96 193.52,42.73 193.52,37.16 193.97,36.71 194.85,36.71 195.37,36.19 195.37,33.77 195.04,33.44 195.04,26.68 194.35,25.99 194.35,21.75 194.73,21.37 194.73,20.82 194.12,20.21 194.12,15.76 192.06,13.71 178.18,13.71 176.67,15.21 172.27,15.21 171.26,16.22 171.09,16.39 127.52,16.39 127.48,16.35 113.59,16.35 113.46,16.48 105.24,16.48 104.51,17.21 71.91,17.21 69.38,19.73 68.41,19.73 v1(68.22,19.55)
PBAT_SMBDAT: length 194.8
  TOP w0.102: v1(67.65,19.55) v2(67.65,20.29) 67.65,20.55 66.88,21.32 66.88,23.37 PRP100.2 ; RE52.2 180.57,58.72 v1(180.57,59.34) ; v1(183.18,62.9) 182.64,62.9 181.97,62.23 181.97,61.14 UE5.B59
  IN2 w0.086: v1(180.57,59.34) 180.57,57.26 180.78,57.06 180.78,54.06 181.27,53.57 181.27,53.01 181.57,52.71 181.57,51.96 184.29,49.24 185.58,49.24 187.31,47.51 187.31,45.64 189.17,43.77 192.21,43.77 193.34,42.65 193.34,35.04 194.85,33.52 194.85,26.76 194.16,26.07 194.16,21.64 194.53,21.27 194.53,20.89 193.93,20.29 193.93,15.86 191.97,13.9 178.25,13.9 176.71,15.44 172.31,15.44 171.34,16.41 171.17,16.58 127.45,16.58 127.4,16.54 113.67,16.54 113.54,16.67 105.32,16.67 104.59,17.4 71.98,17.4 69.46,19.92 68.02,19.92 v1(67.65,19.55)
  IN4 w0.071: v1(180.57,59.34) 182.38,61.14 182.38,62.1 v1(183.18,62.9)
PBATT+_C:
  vias: v1(71.18,29.07) v6(71.18,29.82) v6(71.18,28) v6(72.8,29.07)
PBTN_SW#: length 232
  TOP w0.102: v2(200.91,14.04) 200.55,14.4 v1(200.55,14.41) ; RH21.2 v1(67.15,80.27) ; RE33.2 CE21.1 192.32,61.44 192.32,65.36 191.1,66.58 191.1,71.45 191,71.55 191,72.93 190.51,73.43 190.51,74.62 191.43,75.55 191.43,76.26 191.86,76.69 192.71,76.69 v1(192.96,76.45) 193.43,75.98 SW2.2 SW2.4
  IN3 w0.086: v1(200.55,14.41) 200.4,14.56 200.4,18.96 198.72,20.63 195.89,20.63 194.44,22.08 194.44,24.37 198.53,28.46 v1(198.53,30.44) 198.53,37.75 197.81,38.47 197.81,44.23 193.21,48.83 193.21,52.93 192.86,53.27 192.86,64.7 192.07,65.49 192.07,74.16 193.13,75.23 193.13,76.27 v1(192.96,76.45) 191.69,77.72 185.59,77.72 184.74,76.86 182.62,76.86 180,79.48 179.75,79.48 v4(179.3,79.93)
  IN4 w0.071: v4(179.3,79.93) 178.86,79.48 175.76,79.48 174.8,78.52 174.43,78.52 172.48,80.47 101.27,80.47 100.41,79.61 98.92,79.61 97.83,80.69 86.85,80.69 83.49,77.33 81.43,77.33 78.09,80.68 67.56,80.68 v1(67.15,80.27)
  BOTTOM w0.102: JAPS.11 198.53,30.44 v1(198.53,30.44) ; JIO1.35 200.5,14.46 v1(200.55,14.41)
PCH_ALW_ON: length 117.5
  TOP w0.102: v1(204.7,40.24) 204.83,40.37 204.83,43.89 199.74,48.98 199.74,51.82 201.59,53.68 203.76,53.68 204.36,54.28 R271.1 ; v1(188.67,31.6) 187.01,31.6 v2(186.06,32.55) 183.7,34.91 183.7,38.29 180.83,41.16 v3(179.66,41.16) ; U717.3 203.88,25.46 v1(204.12,25.22) ; UE5.A34 176.74,68.99 v1(176.13,69.6) 175.73,69.2 175.16,69.2 174.92,69.45 173.73,69.45 173.36,69.08 172.71,69.08 172.24,69.55 R1187.2
  GND1 w0.102: v3(179.66,41.16) 179.54,41.28 v4(179.54,41.49)
  IN2 w0.086: v1(188.67,31.6) 188.27,31.2 188.27,29.43 188.64,29.07 188.64,28.44 189.53,27.56 189.53,26.81 192.74,23.6 v4(192.74,22.18)
  IN3 w0.086: v4(179.54,41.49) 179.44,41.39 177.19,41.39 176.52,42.06 176.52,44.72 176.16,45.08 176.16,61.44 176.89,62.17 176.89,68.82 176.13,69.58 v1(176.13,69.6) ; v1(204.12,25.22) 204.81,24.53 205.15,24.53 205.66,25.04 205.66,36.25 204.7,37.21 v1(204.7,40.24)
  IN4 w0.071: v4(192.74,22.18) 203.55,22.18 203.87,22.5 203.87,23.58 203.75,23.69 203.75,24.85 204.12,25.22 v1(204.12,25.22)
PCH_AUDIO_PWR: length 169.5
  TOP w0.102: U719.5 51.25,55.61 51.41,55.78 51.92,55.78 v1(52,55.7) ; U664.3 31.75,41.05 v1(31.88,41.18) 31.88,41.41 31.41,41.88 R1140.1 31.41,41.88 R1141.1 30.85,41.55 30.85,40.97 30.95,40.86 U664.5
  IN2 w0.086: v4(42.75,39.25) 42.75,39.66 44.58,41.49 44.58,43.37 44.99,43.78 44.99,47.07 49.01,51.09 51.24,51.09 53.15,53 53.15,54.55 52,55.7 v1(52,55.7)
  IN3 w0.086: v4(42.75,39.25) 41.99,38.49 36.7,38.49 33.56,41.63 32.33,41.63 v1(31.88,41.18) ; 110.07,70.78 107.97,70.78 106.76,69.57 101.78,69.57 100.27,71.08 81.04,71.08 78.9,73.22 59.22,73.22 58.32,72.32 54.08,72.32 52.59,70.83 51.64,70.83 51.14,70.33 50.67,70.33 49.13,68.79 49.13,62.86 49.91,62.07 49.91,58.84 52,56.75 v1(52,55.7)
  IN3 w0.089: v1(151.3,64.68) 150.73,65.25 149.04,65.25 148.18,66.12 147.02,66.12 146.19,66.94 146.19,70.17 145.71,70.65 139.6,70.65 139.02,71.24 132.55,71.24 131.8,70.48 117.27,70.48 116.97,70.78 110.07,70.78
  BOTTOM w0.076: T279.1 153.92,65.48 152.87,64.44 151.74,64.44 UCPU1.P1 151.3,64.61 v1(151.3,64.68)
PCH_BATLOW#: length 20.2
  TOP w0.076: v2(150,53.55) 150,54.13 v1(150.05,54.18)
  IN4 w0.071: 149.7,57.65 150.74,57.65 151.22,57.17 153.31,57.17 153.61,57.47 155.36,57.47 v4(155.41,57.52)
  IN4 w0.086: 149.7,57.65 149.51,57.45 148.08,57.45 147.72,57.09 147.72,55.86 148.07,55.51 148.52,55.51 148.76,55.27 148.76,54.07 149.04,53.79 149.67,53.79 v1(150.05,54.18)
  GND3 w0.089: v4(155.41,57.52) 155.44,57.55 155.46,57.55
  GND3 w0.102: v5(156.49,58) 156.49,58 156.04,57.55 155.46,57.55
  BOTTOM w0.076: v1(150.05,54.18) 149.66,53.78 UCPU1.AN4
  BOTTOM w0.102: RP20.4 158.78,60.61 158.57,60.61 157.99,60.02 157.26,60.02 156.76,59.53 156.76,58.93 156.49,58.66 v5(156.49,58)
PCH_DP_AUXN: length 156.9
  GND1 w0.102: v3(21.28,66.21) 20.87,66.21 20.39,65.73 v4(20.24,65.73)
  IN1 w0.071: 128.2,75.43 126.02,77.61 109.71,77.61 108.83,78.49 101.6,78.49 98.74,75.64 94.48,75.64 93.76,74.91 77.15,74.91 75.29,76.78 72.7,76.78 71.86,75.94 63.92,75.94 63.52,76.34 61.09,76.34 60.78,76.65 59.7,76.65 58.45,77.91 48.88,77.91 47.95,76.97 37.83,76.97 33.58,72.71 29.64,72.71 23.49,66.56 19.92,66.56 19.86,66.5 19.86,66.02 19.96,65.92 20.16,65.92 20.24,65.85 v4(20.24,65.73) ; v1(152.41,77.66) 152.61,77.66 152.68,77.73 152.68,77.81 152.75,77.87 152.75,78.01 152.69,78.06 148.92,78.06 147.83,76.97 143.46,76.97 142.95,77.49 138.39,77.49 137.9,77 134.78,77 133.22,75.43
  IN1 w0.076: 128.2,75.43 128.24,75.4 133.18,75.4 133.22,75.43
  BOTTOM w0.076: 149.1,73.11 149.09,73.11 149.08,73.1 149.02,73.1 148.94,73.01 148.34,72.42 148.34,71.95 148.15,71.76 148.15,71.46 148.53,71.08 UCPU1.C5
  BOTTOM w0.102: 149.1,73.11 149.14,73.11 149.75,73.72 151.52,73.72 152.67,74.87 152.67,77.39 v1(152.41,77.66)
PCH_DP_AUXN_C: length 2
  TOP w0.102: CV10.1 21.28,67.18 20.36,68.1 20.36,68.72 UV1.5
PCH_DP_AUXP: length 156.8
  GND1 w0.102: v3(18.64,66.19) 18.67,66.19 19.14,65.72 v4(19.64,65.72)
  IN1 w0.071: v4(19.64,65.72) 19.73,65.81 19.73,66.56 19.86,66.69 23.44,66.69 29.59,72.84 33.52,72.84 37.78,77.1 47.89,77.1 48.83,78.04 58.5,78.04 59.76,76.78 60.83,76.78 61.15,76.47 63.58,76.47 63.97,76.07 71.81,76.07 72.65,76.91 75.34,76.91 77.21,75.05 93.7,75.05 94.43,75.77 98.69,75.77 101.54,78.62 108.89,78.62 109.77,77.74 126.08,77.74 128.25,75.57 128.25,75.57 128.29,75.53 133.13,75.53 133.17,75.57 133.17,75.57 134.73,77.13 137.85,77.13 138.34,77.62 143,77.62 143.52,77.1 147.77,77.1 148.86,78.19 152.75,78.19 152.88,78.06 152.88,77.82 v1(153.05,77.66)
  BOTTOM w0.076: 149.1,72.9 149.08,72.9 148.52,72.34 148.52,72.01 148.59,71.93 148.72,71.93 148.8,71.86 148.8,71.41 148.73,71.34 148.54,71.34 148.4,71.47 148.4,71.57 UCPU1.B5
  BOTTOM w0.102: 149.1,72.9 149.23,72.9 149.84,73.51 151.61,73.51 152.88,74.78 152.88,77.49 v1(153.05,77.66)
PCH_DP_AUXP_C: length 1.9
  TOP w0.102: UV1.2 18.41,68.01 18.92,67.5 18.92,67.39 CV8.1
PCH_DP_CLK: length 147.2
  TOP w0.102: v1(19.06,69.89) 19.06,68.83 UV1.3
  IN1 w0.071: v4(147.45,77.59) 147.31,77.74 147.31,78.02 146.72,78.6 137.87,78.6 137.24,77.97 134.89,77.97 132.86,80.01 100.25,80.01 99.9,79.66 97.45,79.66 96.8,79.01 86.31,79.01 83.9,76.6 80,76.6 78.01,78.59 73,78.59 72.53,79.05 59.7,79.05 58.8,79.95 48.11,79.95 46.69,78.53 36.98,78.53 35.13,76.68 23.98,76.68 20.04,72.75 20.04,70.17 19.76,69.89 v1(19.06,69.89)
  GND3 w0.102: v4(147.45,77.59) 147.45,77.26 v5(147.29,77.1)
  BOTTOM w0.076: UCPU1.B9 145.99,71.54 146.1,71.54 146.21,71.64 146.21,71.87 146.55,72.22 146.55,72.61 147.29,73.35 147.29,75.43
  BOTTOM w0.102: 147.29,75.43 v7(147.29,75.98) 147.29,76.6 147.26,76.63 147.26,77.07 v5(147.29,77.1) 147.16,77.22 RP14.7
PCH_DP_DAT: length 147.2
  TOP w0.102: v1(21.01,69.9) 21.01,68.72 UV1.6
  IN1 w0.071: v4(146.94,77.53) 147.08,77.67 147.08,77.92 146.63,78.38 137.96,78.38 137.33,77.75 134.8,77.75 132.77,79.78 100.34,79.78 100,79.44 97.54,79.44 96.89,78.79 86.4,78.79 83.99,76.38 79.91,76.38 77.92,78.37 72.9,78.37 72.44,78.83 59.6,78.83 58.71,79.73 48.2,79.73 46.78,78.31 37.07,78.31 35.23,76.46 24.07,76.46 20.26,72.65 20.26,70.13 20.48,69.9 v1(21.01,69.9)
  GND3 w0.102: v4(146.94,77.53) 146.94,77.03 147.22,76.75 v5(147.57,76.75)
  BOTTOM w0.076: 147.54,75.43 v7(147.54,74.48) 147.54,73.28 146.91,72.65 146.78,72.52 146.78,72.12 146.44,71.78 146.44,71.55 146.25,71.37 UCPU1.C9
  BOTTOM w0.102: 147.54,75.43 147.54,76.73 v5(147.57,76.75) 147.66,76.85 RP14.6
PCH_DP_HPD: length 159.8
  IN3 w0.086: v1(149.38,75.41) 149.38,74.63 147.25,72.5 142.43,72.5 141.23,73.7 139.68,73.7 138.06,72.08 132.37,72.08 131.91,71.62 130.73,71.62 130.37,71.98 107.77,71.98 106.34,70.55 102.43,70.55 100.73,72.25 80.95,72.25 79.23,73.97 58.9,73.97 58,73.07 53.77,73.07 52.28,71.58 51.33,71.58 50.83,71.09 50.15,71.09 47.59,68.52 47.59,59.3 48.79,58.1 48.79,53.96 47.31,52.48 v4(46.83,52.48)
  IN4 w0.071: v4(46.83,52.48) 37.74,52.48 35.84,54.38 35.84,55.71 34.45,57.11 26.77,57.11 v1(25.73,56.07)
  BOTTOM w0.076: UCPU1.C8 147.07,71.63 147.54,72.1 147.54,72.59 148.86,73.92 148.86,74.89 v1(149.38,75.41) 149.38,75.43
  BOTTOM w0.102: 149.38,75.43 149.38,76.22 RH300.2 ; v2(26.66,56.82) 26.62,56.82 25.88,56.07 v1(25.73,56.07) QV2.3
PCH_DP_N0: length 116.2
  IN1 w0.071: v1(21.21,57.99) 21.42,57.78 21.62,57.78 21.87,58.03 21.87,60.47 22.75,61.35 22.75,61.95 30.81,70 32.46,70 33.78,68.68 42.56,68.68 47.83,73.95 48.25,73.95 48.68,74.38 58.03,74.38 58.61,73.8 62.26,73.8 63.2,72.86 74.57,72.86 75.12,72.3 98.27,72.3 100.61,69.96 105.86,69.96 109.56,73.66 116.35,73.66 116.48,73.79 116.48,74.4 116.62,74.54 117.07,74.54 117.22,74.69 v1(117.22,74.89)
  BOTTOM w0.076: UCPU1.C54 118.77,70.83 118.33,71.27 118.16,71.27 118,71.43 117.97,71.48 117.92,71.66 117.97,71.79 117.99,71.86 117.99,72.03 117.97,72.11 117.95,72.16 117.92,72.23 117.92,73.23 117.8,73.35 117.8,74.6 117.63,74.77 117.34,74.77 v1(117.22,74.89)
  BOTTOM w0.102: v1(21.21,57.99) 21.01,57.79 20.96,57.79 20.62,58.12 CV4.2
PCH_DP_N0_C: length 9.3
  BOTTOM w0.102: 18.18,58 MD16.4 ; 18.18,58 MD16.7 16.93,58 16.77,57.83 15.79,57.83 15.25,57.29 13.84,57.29 12.26,58.86 12,58.86 JMDP.5 ; 18.18,58 18.6,58 18.76,57.83 19.42,57.83 CV4.1
PCH_DP_N1: length 111.1
  TOP w0.102: CV7.2 20.29,61.41 20.54,61.16 20.67,61.16 v1(20.99,61.48)
  IN1 w0.071: v1(20.99,61.48) 20.99,61.4 21.14,61.25 21.43,61.25 21.61,61.43 21.61,61.74 30.61,70.74 33.12,70.74 34.52,69.34 42.23,69.34 47.98,75.1 58.25,75.1 58.89,74.46 62.54,74.46 63.44,73.56 74.88,73.56 75.47,72.96 98.68,72.96 101.02,70.62 105.55,70.62 109.33,74.41 115.8,74.41 v1(116.03,74.63)
  BOTTOM w0.076: v1(116.03,74.63) 116.03,74.55 115.84,74.37 115.66,74.37 115.45,74.16 115.45,73.69 116.06,73.08 116.06,71.58 115.93,71.45 115.93,71.31 116.04,71.2 116.16,71.2 UCPU1.B58
PCH_DP_N1_C: length 14
  TOP w0.102: JMDP.11 11.97,60.69 12.41,60.69 12.93,60.17 12.93,57.84 13.31,57.46 13.31,57.43 13.67,57.07 15.22,57.07 v7(15.38,57.24) 15.94,57.79 15.94,59.68 16.5,60.24 16.65,60.24 16.82,60.41 MD5.4 MD5.7 18.28,60.41 18.42,60.27 18.53,60.27 18.66,60.4 18.66,60.8 18.92,61.06 19.01,61.06 CV7.1
PCH_DP_N2: length 113.7
  TOP w0.102: CV12.2 20.29,63.19 20.5,62.98 20.69,62.98 v1(21.05,63.34)
  IN1 w0.071: v1(21.05,63.34) 21.05,63.24 21.21,63.08 21.72,63.08 30.07,71.43 35.72,71.43 39.69,75.4 46.32,75.4 46.69,75.76 58.53,75.76 59.17,75.12 62.93,75.12 63.83,74.22 75.41,74.22 75.98,73.65 99.03,73.65 101.37,71.31 105.24,71.31 109.35,75.42 111.66,75.42 112.07,75.01 115.21,75.01 115.54,75.34 115.54,75.57 116.58,76.6 117.11,76.6 v1(117.25,76.74)
  BOTTOM w0.076: 118.42,73.96 118.42,73.95 118.41,73.94 118.41,73.32 118.52,73.21 118.52,72.71 118.71,72.52 118.71,71.89 118.54,71.72 118.31,71.72 118.21,71.63 UCPU1.B55
  BOTTOM w0.102: 118.42,73.96 118.42,76.27 117.96,76.74 v1(117.25,76.74)
PCH_DP_N2_C: length 12.4
  TOP w0.102: JMDP.17 12,62.46 12.2,62.46 12.34,62.6 12.34,63.67 12.86,64.19 v7(15.42,64.19) 15.78,64.19 16.24,63.72 16.24,62.35 16.26,62.33 16.26,61.85 16.34,61.77 16.55,61.77 16.7,61.91 MD5.1 MD5.9 18.23,61.91 18.33,61.81 18.41,61.81 18.55,61.95 18.55,62.58 18.72,62.76 18.93,62.76 CV12.1
PCH_DP_N3: length 117.6
  IN1 w0.071: v1(21.32,59.81) 21.32,59.77 20.98,59.42 20.51,59.42 19.93,60 19.93,63.95 20.43,64.45 22.33,64.45 29.92,72.03 34,72.03 37.9,75.93 44.89,75.93 45.26,76.3 49.47,76.3 50.4,77.22 57.82,77.22 59.38,75.66 63.21,75.66 63.61,75.26 75.13,75.26 76.18,74.21 95.65,74.21 96.36,74.93 98.97,74.93 101.87,77.83 108.3,77.83 109.76,76.37 114.81,76.37 114.99,76.2 115.11,76.2 115.15,76.15 v1(115.15,75.98)
  BOTTOM w0.076: 116.54,74.54 116.54,74.53 116.55,74.51 116.55,74.45 116.56,74.45 116.56,73.76 116.43,73.62 116.43,73.25 117.11,72.57 117.11,72.19 117.06,72.14 117.06,72.12 116.85,71.9 116.73,71.9 116.59,72.04 116.59,72.16 116.71,72.28 UCPU1.A57
  BOTTOM w0.102: 116.54,74.54 116.54,75.48 115.75,76.27 115.43,76.27 v1(115.15,75.98) ; v1(21.32,59.81) 21.12,59.61 20.91,59.61 CV9.2
PCH_DP_N3_C: length 6.1
  BOTTOM w0.102: CV9.1 19.4,59.59 19.05,59.59 18.81,59.34 18.72,59.34 18.56,59.5 MD16.1 MD16.9 16.95,59.5 16.81,59.36 16.68,59.36 16.35,59.69 16.35,60.42 16.12,60.65 15.41,60.65 JMDP.12
PCH_DP_P0: length 116.2
  IN1 w0.071: v1(117.22,74.1) 117.21,74.11 117.21,74.32 117.12,74.41 116.67,74.41 116.61,74.35 116.61,73.73 116.4,73.53 109.61,73.53 105.92,69.83 100.55,69.83 98.21,72.17 75.07,72.17 74.51,72.72 63.14,72.72 62.2,73.66 58.56,73.66 57.97,74.25 48.73,74.25 48.31,73.82 47.88,73.82 42.61,68.55 33.72,68.55 32.4,69.87 30.86,69.87 22.88,61.89 22.88,61.29 22.01,60.41 22.01,57.98 21.68,57.65 21.45,57.65 v1(21.21,57.41)
  BOTTOM w0.076: v1(117.22,74.1) 117.03,74.1 116.93,74.19 116.93,74.45 117.02,74.54 117.42,74.54 117.47,74.59 117.55,74.59 117.62,74.52 117.62,73.28 117.75,73.15 117.75,72.19 117.76,72.14 117.78,72.1 117.8,72.05 117.81,72 117.81,71.9 117.8,71.86 117.72,71.67 117.8,71.4 117.85,71.31 117.86,71.31 117.89,71.25 UCPU1.C55
  BOTTOM w0.102: CV3.2 20.62,57.23 20.97,57.58 21.04,57.58 v1(21.21,57.41)
PCH_DP_P0_C: length 9.3
  BOTTOM w0.102: CV3.1 19.31,57.62 18.76,57.62 18.64,57.5 18.18,57.5 ; 17.31,57.5 18.18,57.5 ; 17.31,57.5 MD16.6 ; 17.31,57.5 16.92,57.5 16.79,57.62 15.88,57.62 15.33,57.08 13.75,57.08 12.18,58.65 11.97,58.65 JMDP.3 ; 18.18,57.5 MD16.5
PCH_DP_P1: length 111.1
  TOP w0.102: CV5.2 20.29,60.68 20.56,60.95 20.94,60.95 v1(20.99,60.9)
  IN1 w0.071: v1(20.99,60.9) 21.2,61.11 21.49,61.11 21.74,61.37 21.74,61.69 30.67,70.61 33.06,70.61 34.46,69.21 42.28,69.21 48.04,74.96 58.2,74.96 58.84,74.32 62.49,74.32 63.38,73.43 74.82,73.43 75.42,72.83 98.62,72.83 100.96,70.49 105.6,70.49 109.39,74.27 115.8,74.27 v1(116.03,74.05)
  BOTTOM w0.076: v1(116.03,74.05) 115.89,74.18 115.73,74.18 115.64,74.09 115.64,73.76 116.24,73.16 116.24,71.76 116.55,71.45 116.55,71.18 116.27,70.89 UCPU1.C58
PCH_DP_P1_C: length 14
  TOP w0.102: JMDP.9 12,60.49 12.32,60.49 12.73,60.08 12.73,57.72 v7(12.94,57.51) 13.58,56.86 15.34,56.86 15.78,57.31 15.78,57.34 16.15,57.7 16.15,59.6 16.59,60.04 16.67,60.04 16.79,59.91 MD5.5 MD5.6 18.28,59.91 18.43,60.06 18.62,60.06 18.87,60.31 18.87,60.72 19,60.85 19.05,60.85 CV5.1
PCH_DP_P2: length 113.7
  TOP w0.102: CV11.2 20.29,62.45 20.61,62.77 21.03,62.77 v1(21.05,62.75)
  IN1 w0.071: v1(117.25,76.09) 116.87,76.47 116.63,76.47 115.68,75.52 115.68,75.29 115.26,74.88 112.01,74.88 111.6,75.29 109.41,75.29 105.3,71.18 101.31,71.18 98.98,73.52 75.93,73.52 75.36,74.09 63.78,74.09 62.87,74.99 59.11,74.99 58.47,75.63 46.75,75.63 46.38,75.27 39.74,75.27 35.78,71.3 30.12,71.3 21.77,62.95 21.25,62.95 v1(21.05,62.75)
  BOTTOM w0.076: UCPU1.A55 118.17,72.23 118.17,71.97 118.23,71.91 118.47,71.91 118.53,71.96 118.53,72.44 118.34,72.64 118.34,73.13 118.23,73.24 118.23,73.93 118.22,73.95 118.22,73.96
  BOTTOM w0.102: v1(117.25,76.09) 117.25,76.19 117.59,76.53 117.87,76.53 118.22,76.19 118.22,73.96
PCH_DP_P2_C: length 12.3
  TOP w0.102: 17.98,61.41 18.16,61.41 18.35,61.6 18.49,61.6 18.76,61.86 18.76,62.5 18.81,62.55 19.13,62.55 CV11.1 ; 17.98,61.41 MD5.2 16.7,61.41 16.55,61.56 16.26,61.56 16.03,61.78 v7(16.03,62.04) 16.03,63.64 15.71,63.96 15.07,63.96 15.05,63.98 12.95,63.98 12.55,63.59 12.55,62.52 12.29,62.25 11.97,62.25 JMDP.15 ; 17.98,61.41 MD5.8
PCH_DP_P3: length 117.6
  IN1 w0.071: v1(115.15,76.57) 115.08,76.5 109.81,76.5 108.35,77.96 101.81,77.96 98.91,75.06 96.3,75.06 95.59,74.35 76.24,74.35 75.19,75.4 63.67,75.4 63.27,75.79 59.43,75.79 57.87,77.36 50.34,77.36 49.42,76.43 45.2,76.43 44.83,76.06 37.85,76.06 33.95,72.16 29.86,72.16 22.28,64.58 20.37,64.58 19.8,64.01 19.8,59.95 20.46,59.29 21.25,59.29 v1(21.32,59.22)
  BOTTOM w0.076: 116.75,74.54 116.75,74.52 116.74,74.52 116.74,73.68 116.61,73.55 116.61,73.33 117.29,72.65 117.29,72.11 117.24,72.07 117.24,72.04 116.83,71.63 UCPU1.B57
  BOTTOM w0.102: v1(115.15,76.57) 115.24,76.48 115.84,76.48 116.75,75.56 116.75,74.54 ; CV6.2 21.01,59.4 21.14,59.4 v1(21.32,59.22)
PCH_DP_P3_C: length 6.1
  BOTTOM w0.102: CV6.1 19.33,59.38 19.14,59.38 18.9,59.14 18.7,59.14 18.56,59 MD16.2 MD16.8 17.03,59 16.88,59.15 16.59,59.15 16.14,59.6 16.14,60.34 16.04,60.44 15.36,60.44 JMDP.10
PCH_DPWROK: length 49.1
  TOP w0.102: v1(175.68,68.59) 176.29,67.99 UE5.A36 ; v1(175.61,44.11) 175.19,44.53 172.13,44.53 v2(171.91,44.31) 171.68,44.07 169.5,44.07 167.83,42.39 155.9,42.39 RH309.1
  IN2 w0.086: v1(175.61,44.11) 176.04,44.54 176.04,53.89 175.48,54.45 175.48,56.21 175.18,56.51 175.18,57.87 175.62,58.31 175.62,61.52 175.49,61.65 175.26,61.88 175.26,65.01 175.82,65.57 175.82,68.45 v1(175.68,68.59)
PCH_DPWROK_R: length 13.5
  TOP w0.089: v1(151.1,47.67) 151.51,48.07 152.01,48.07 153.27,46.81
  TOP w0.102: RH401.1 RH309.2 154.55,44.1 154.21,44.44 154.21,45.22 v2(154.34,45.35) 154.34,45.74 153.27,46.81
  BOTTOM w0.076: v1(151.1,47.67) 151.1,47.89 150.7,48.3 149.43,48.3 148.97,48.76 148.97,48.86 148.96,48.86 148.96,49.23 148.7,49.5 148.7,50.71 UCPU1.AV5
PCH_GPIO12: length 12.7
  TOP w0.089: 154.39,53.26 154.24,53.26 151.92,53.26 151.06,54.12 151.06,54.31 150.47,54.9 v2(150,54.9) 149.77,54.9 149.6,54.73 149.6,53.96 149.41,53.78 149.03,53.78 148.85,53.96 148.85,54.04 148.31,54.58 v1(148.31,54.59)
  TOP w0.102: 154.39,53.26 155.13,53.26 155.68,53.81 157.05,53.81 157.29,54.05 RH3538.1
  BOTTOM w0.076: UCPU1.AM7 148.05,54.85 v1(148.31,54.59)
PCH_GPIO14: length 1
  TOP w0.076: T288.1 149.95,57.13 v1(149.98,57.16)
  BOTTOM w0.076: UCPU1.AH4 149.65,56.83 v1(149.98,57.16)
PCH_GPIO16: length 2.5
  TOP w0.089: v1(152.72,61.43) 152.97,61.67 RH3539.1
  BOTTOM w0.076: v2(153.27,61.56) 152.86,61.56 v1(152.72,61.43) 152.6,61.3 151.6,61.3 UCPU1.Y1
PCH_GPIO38: length 13.8
  BOTTOM w0.076: UCPU1.L2 150.95,65.88 151.27,66.19 151.27,66.19 151.75,66.19 151.75,66.19 152.06,66.5 153.39,66.5 v2(154.01,67.12) 154.53,67.63
  BOTTOM w0.102: RH3540.1 161.79,67.72 161.79,68.49 161.45,68.84 159.98,68.84 159.72,68.58 157.35,68.58 156.94,68.17 156.94,68.03 156.65,67.74 154.63,67.74 154.53,67.63
PCH_GPIO48: length 5.6
  BOTTOM w0.076: UCPU1.U4 149.98,62.44 150.33,62.44 150.42,62.35 151.15,62.35 151.31,62.52 151.92,62.52 152.18,62.78 v2(153.75,62.78) 154.53,62.78
  BOTTOM w0.102: 154.53,62.78 154.62,62.78 RH3530.1
PCH_GPIO49: length 13.3
  IN2 w0.086: v1(150.65,60.92) 150.65,60.94 150.77,61.07 155.36,61.07 156.33,62.04 160.34,62.04 v4(161.03,62.73)
  GND3 w0.102: v4(161.03,62.73) 161.36,63.06 161.59,63.06 v5(161.79,63.25)
  BOTTOM w0.076: v1(150.65,60.92) 150.65,60.95 150.32,61.27 UCPU1.Y3
  BOTTOM w0.102: RH3543.1 161.78,63.25 v5(161.79,63.25)
PCH_GPIO51: length 1.8
  TOP w0.089: RH3544.2 148.65,65.44 v1(148.65,64.62)
  BOTTOM w0.076: UCPU1.R5 148.97,64.3 v1(148.65,64.62)
PCH_GPIO58: length 9.8
  TOP w0.102: RH3546.1 157.5,55.71 155,55.71 v2(154.67,55.38) 154.39,55.1 v1(154.39,54.37)
  BOTTOM w0.076: v1(154.39,54.37) 154.13,54.62 152.77,54.62 152.29,55.11 151.82,55.11 151.74,55.04 151.35,55.04 151.17,54.86 150.49,54.86 150.44,54.91 150.02,54.91 UCPU1.AL4
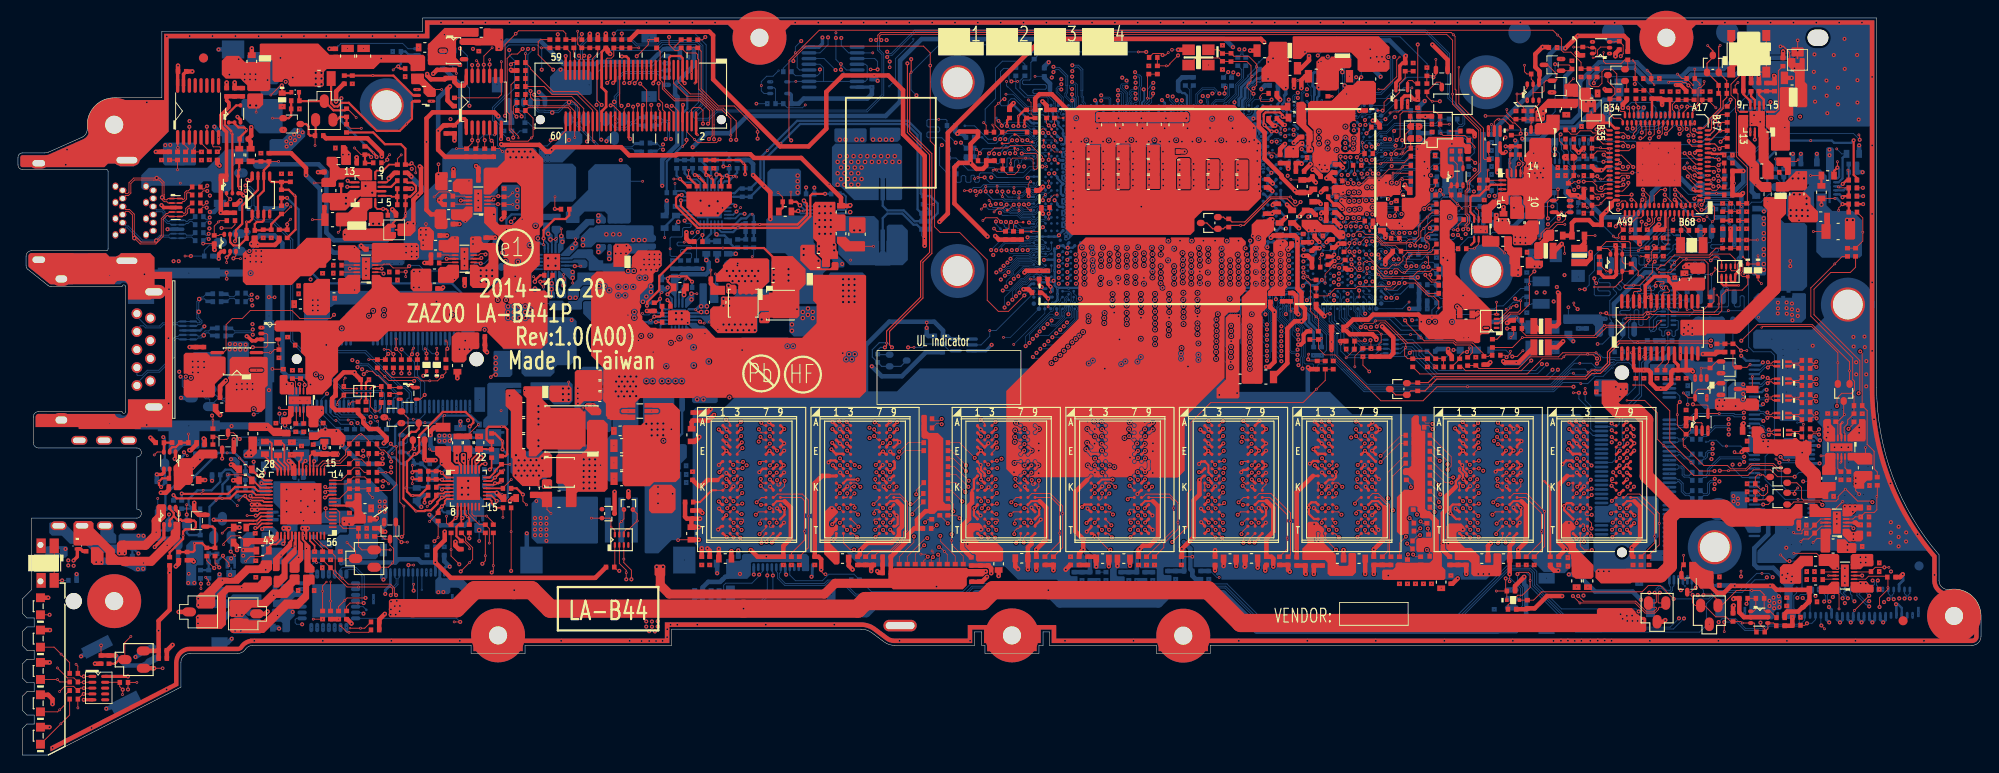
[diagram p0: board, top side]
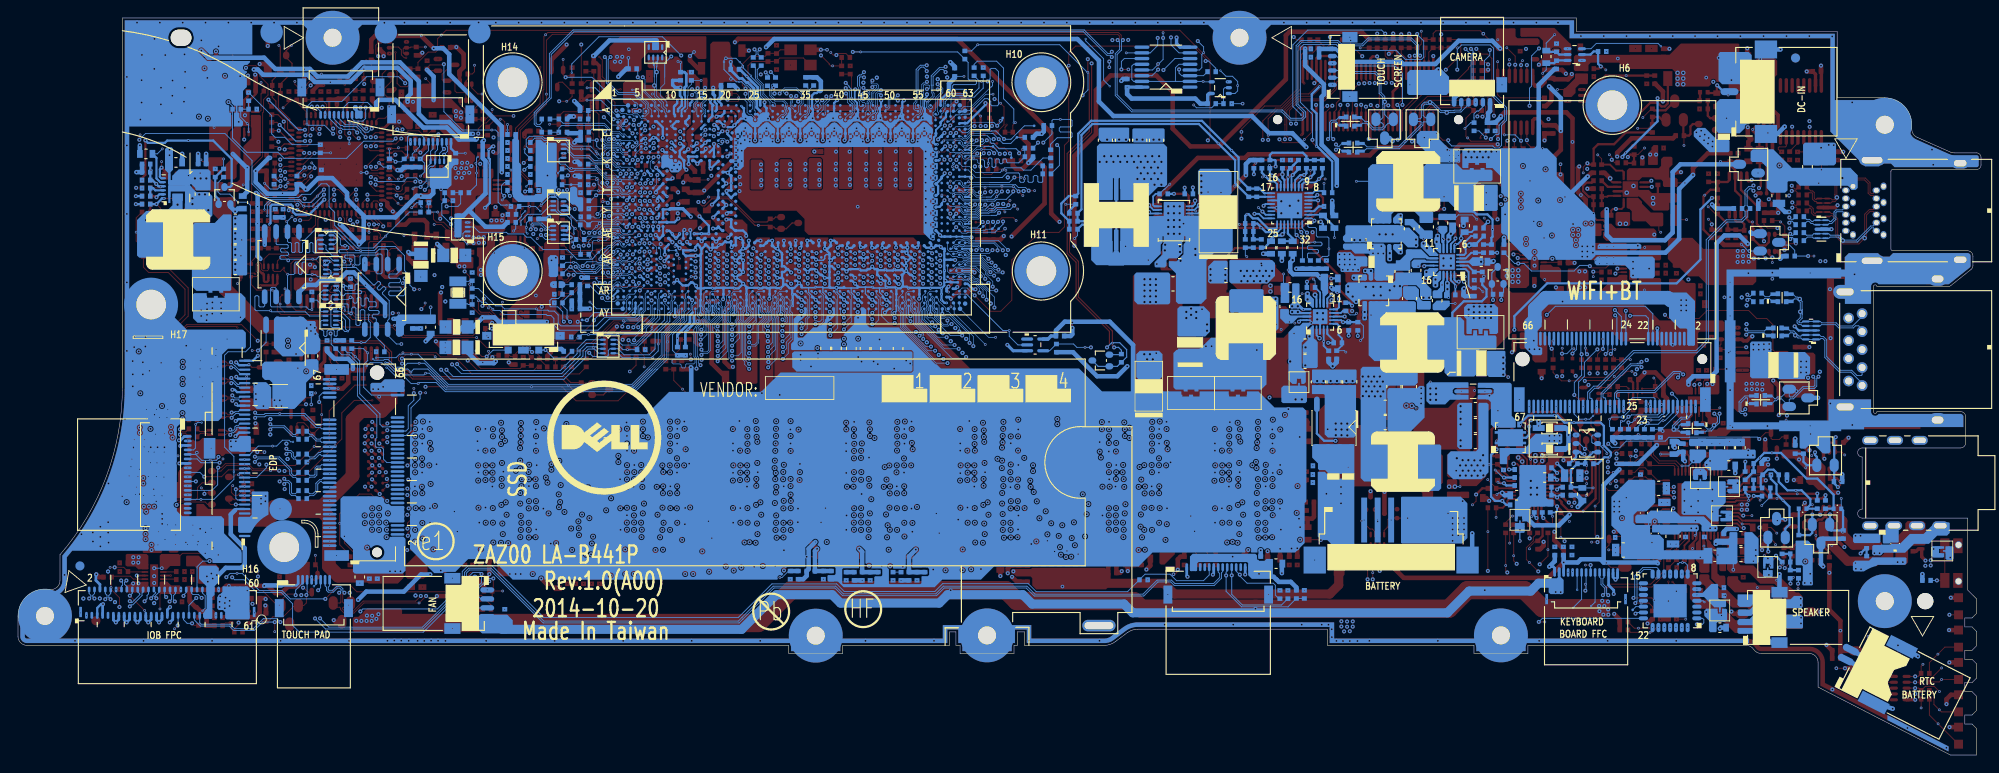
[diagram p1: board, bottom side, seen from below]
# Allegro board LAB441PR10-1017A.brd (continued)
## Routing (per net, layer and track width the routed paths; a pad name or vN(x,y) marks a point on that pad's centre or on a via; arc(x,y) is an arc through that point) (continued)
PCH_GPIO73: length 20.3
  TOP w0.102: v3(164.43,49.02) v2(164.43,50.38)
  GND1 w0.102: v4(164.63,47.88) 164.63,48.82 v3(164.43,49.02)
  IN2 w0.102: v4(164.63,47.88) 164.1,47.34 161.43,47.34 157.76,51.01 154.29,51.01 154.28,51.01 153.52,51.01 v1(153.36,50.85)
  BOTTOM w0.076: UCPU1.AU4 149.63,51.43 149.79,51.27 150.42,51.27 150.59,51.11 150.59,50.85 150.81,50.63 151.77,50.63 151.94,50.46 152.96,50.46 153.25,50.74
  BOTTOM w0.102: v1(153.36,50.85) 153.25,50.74
PCH_GPIO77: length 7.6
  TOP w0.089: v1(149.12,63.59) 149.46,63.59 150.16,64.28 151.58,64.28 152.47,65.17 153.73,65.17 v2(154,65.44) 154.16,65.6 154.53,65.6
  TOP w0.102: RH3547.2 154.53,65.6
  BOTTOM w0.076: v1(149.12,63.59) 149.05,63.59 148.54,63.08 UCPU1.U6
PCH_GPIO78: length 10.4
  BOTTOM w0.076: UCPU1.P4 149.93,63.99 150.42,63.99 150.42,64 151.71,64 151.91,64.2 152.89,64.2 153.87,65.18 153.87,65.19 153.88,65.2 154.17,65.2 154.24,65.27
  BOTTOM w0.102: RP4.5 157.63,66.45 158.01,66.45 158.14,66.31 158.14,65.88 158.01,65.74 157.45,65.74 156.98,65.27 v2(156.76,65.27) 154.24,65.27
PCH_GPIO79: length 9.3
  BOTTOM w0.076: UCPU1.N4 149.95,65.39 151.22,65.39 151.34,65.51 151.72,65.51 152.37,66.17 153.89,66.17 153.9,66.15
  BOTTOM w0.102: 153.9,66.15 154.24,66.15 154.78,66.69 156.47,66.69 156.94,67.15 156.94,67.44 157.45,67.95 RP4.8
PCH_GPIO80: length 7.8
  BOTTOM w0.076: 154.53,66.12 154.37,65.96 152.42,65.96 151.81,65.35 151.48,65.35 151.19,65.06 UCPU1.N2
  BOTTOM w0.102: RP4.7 157.29,67.45 157.14,67.3 157.14,67.07 156.51,66.44 154.84,66.44 154.53,66.12
PCH_GPIO84: length 21.2
  TOP w0.102: v3(161.98,67.62) 161.98,67.76 RH199.1 161.33,68.5 160.91,68.92 158.5,68.92 v2(158.25,69.17)
  GND1 w0.102: v4(162.45,67.74) 162.32,67.62 v3(161.98,67.62)
  IN2 w0.086: 154.08,65.97 155.29,67.17 159.28,67.17 159.52,66.94 161.64,66.94 v4(162.45,67.74)
  IN2 w0.089: 154.08,65.97 152.3,65.97 152.16,65.83 149,65.83 148.31,66.51 v1(148.19,66.51)
  BOTTOM w0.076: UCPU1.L6 148.19,66.07 v1(148.19,66.51)
PCH_GPIO87: length 1.2
  TOP w0.076: RH3531.1 147.65,63.88 v1(147.91,63.62)
  BOTTOM w0.076: UCPU1.R7 147.67,63.86 v1(147.91,63.62)
PCH_GPIO90: length 20
  IN2 w0.086: 154.05,66.21 155.21,67.36 159.36,67.36 159.56,67.17 161.24,67.17 161.56,67.48 161.56,67.87 161.26,68.16 160.87,68.16 160.63,68.41 160.63,69.04 161.01,69.42 v4(164.32,69.42)
  IN2 w0.089: 154.05,66.21 152.31,66.21 152.09,65.99 150.79,65.99 v1(150.58,66.21)
  GND3 w0.102: v5(163.87,69.53) 164.2,69.53 v4(164.32,69.42)
  BOTTOM w0.076: v1(150.58,66.21) 150.92,66.55 UCPU1.K2
  BOTTOM w0.102: RH200.1 v5(163.87,69.53) v2(163.87,70.15)
PCH_INTVRMEN: length 11.5
  TOP w0.076: v2(148.67,43.19) 148.67,44.37 149.54,45.24 RH34.1
  TOP w0.089: RH34.1 RH31.2 150.46,46.1 v1(150.41,46.15)
  BOTTOM w0.076: UCPU1.AV7 147.19,50.69 147.19,49.55 147.2,49.54
  BOTTOM w0.089: 147.2,49.54 147.2,48.67 148.44,47.43 148.44,46.97 149.63,45.79 150.04,45.79 v1(150.41,46.15)
PCH_JTAG_JTAGX: length 72.6
  TOP w0.102: v1(79.88,68.44) 79.88,70.54 78.44,71.98 77.8,71.98 75.71,74.07 75.71,77.36 75.59,77.48 75.59,77.92 75.4,78.11 74.32,78.11 RH412.2 73.45,78.37 73.08,78.37 72.41,79.04 v1(72.41,79.88) ; v1(109.32,59.32) 109.32,59.34 108.88,59.78 107.61,59.78 v2(107.31,59.47) ; RH374.2 v1(60.04,80.19)
  IN4 w0.071: v1(109.32,59.32) 108.3,60.33 107.23,60.33 106.74,60.82 105.4,60.82 102.63,63.59 102.63,65.25 98.66,69.22 98.19,69.22 97.25,70.16 90.82,70.16 90.21,69.55 80.99,69.55 v1(79.88,68.44) ; v1(72.41,79.88) 71.79,80.49 67.94,80.49 67.23,79.78 62.55,79.78 61.65,80.68 60.53,80.68 v1(60.04,80.19)
  BOTTOM w0.076: UCPU1.AE63 110.79,58.35 110.64,58.5 110.24,58.5
  BOTTOM w0.102: v1(109.32,59.32) 109.69,58.94 109.69,58.82 T273.1 110.01,58.5 110.24,58.5
PCH_JTAG_TCK: length 86.4
  TOP w0.102: v1(54.17,71.12) 54.17,79.05 55.35,80.23 v6(55.35,80.25) 55.68,80.58 60.63,80.58 60.93,80.28 RH411.2 RH373.2
  IN4 w0.071: v1(108.76,59.36) 107.98,60.13 107.15,60.13 106.66,60.62 105.32,60.62 102.43,63.51 102.43,65.17 98.58,69.02 98.11,69.02 97.16,69.96 90.9,69.96 90.29,69.36 81.36,69.36 80.07,68.06 76.77,68.06 73.87,70.96 59.54,70.96 58.44,69.86 56.95,69.86 56.38,70.43 56.38,71.22 56.1,71.5 54.55,71.5 v1(54.17,71.12)
  BOTTOM w0.076: UCPU1.AE62 113.33,58.06 112.78,58.06 112.68,58.16 110.45,58.16
  BOTTOM w0.102: v1(108.76,59.36) 108.76,59.05 T277.1 109.65,58.16 110.45,58.16
PCH_JTAG_TDI: length 72.4
  TOP w0.076: v1(111.03,59.3) 111.05,59.28 T278.1
  TOP w0.089: RH40.2 110.71,59.01 111.01,59.3 v1(111.03,59.3)
  TOP w0.102: RH371.2 55.08,72.16 55.08,71.38 v1(55.44,71.03)
  IN4 w0.071: v1(55.44,71.03) 55.44,70.66 56.66,69.44 58.64,69.44 59.77,70.57 73.68,70.57 76.59,67.66 80.28,67.66 81.57,68.96 90.46,68.96 91.07,69.57 97,69.57 97.94,68.63 98.42,68.63 102.04,65.01 102.04,63.34 105.15,60.23 106.49,60.23 107,59.71 107.56,59.71 108.53,58.75 110.47,58.75 v1(111.03,59.3)
  BOTTOM w0.076: UCPU1.AD61 114.02,59.39 113.5,59.39 113.27,59.16 113.27,58.98 113.1,58.81 112.68,58.81 112.58,58.71 111.61,58.71 v1(111.03,59.3)
PCH_JTAG_TDO: length 55.6
  TOP w0.076: v1(113.98,58.73) 113.48,58.23 T275.1 112.66,58.26 RH445.2
  TOP w0.102: v1(82.25,68.58) v6(82.25,69.33) 82.25,69.62 79.66,72.21 77.9,72.21 75.98,74.13 75.98,78.3 RH413.2 RH369.2
  IN4 w0.071: v1(82.25,68.58) 82.44,68.76 90.54,68.76 91.15,69.37 96.92,69.37 97.86,68.43 98.33,68.43 101.84,64.92 101.84,63.26 105.07,60.03 106.41,60.03 106.92,59.52 107.48,59.52 108.45,58.55 110.69,58.55 110.86,58.73 v1(113.98,58.73)
  BOTTOM w0.076: UCPU1.AE61 114.28,58.43 v1(113.98,58.73)
PCH_JTAG_TMS: length 70.7
  TOP w0.102: v1(110.44,59.3) 110.21,59.07 110.21,58.62 109.85,58.26 RH39.2 108.85,58.26 v6(108.54,58.57) ; v1(56.01,71.05) 56.01,71.21 RH372.2
  IN4 w0.071: v1(110.44,59.3) 110.08,58.95 108.61,58.95 107.64,59.91 107.09,59.91 106.57,60.43 105.23,60.43 102.24,63.42 102.24,65.09 98.5,68.83 98.02,68.83 97.08,69.77 90.98,69.77 90.37,69.16 81.49,69.16 80.19,67.86 76.69,67.86 73.79,70.77 59.65,70.77 58.54,69.66 56.84,69.66 56.01,70.48 v1(56.01,71.05)
  BOTTOM w0.076: UCPU1.AD62 113.18,58.66 113.17,58.66 113.17,58.65 112.81,58.65 112.71,58.55 111.23,58.55 T276.1 110.93,58.82 v1(110.44,59.3)
PCH_JTAG_TRST#: length 57.2
  TOP w0.102: v1(111.92,51.13) 110.15,49.36 109.03,49.36 107.79,50.6 107.79,55.08 104.72,58.14 102.55,58.14 101.94,58.76 101.94,67.83 101.45,68.31 v6(101.45,76.7) 101.45,78.12 100.7,78.87 87.62,78.87 86.23,77.47 v1(86.23,77.21)
  BOTTOM w0.076: UCPU1.AU62 113.63,51.64 113.31,51.96 112.74,51.96 v1(111.92,51.13)
  BOTTOM w0.102: v1(86.23,77.21) 85.9,77.21 85.11,76.42 RH370.2
PCH_NFC_RST#: length 185.5
  TOP w0.076: v1(147.85,59.75) 147.84,59.75 147.4,59.31 v2(147.4,59.29)
  IN3 w0.086: v4(184.8,18.86) 184.52,18.86 181.64,15.97 v1(180.23,15.97)
  IN4 w0.071: v4(184.8,18.86) 184.58,19.08 184.58,26.85 185.72,27.99 185.72,38.19 185.17,38.73 184.83,38.73 182.75,40.82 182.75,44 179.81,46.93 174.92,46.93 173.52,48.33 173.18,48.33 172.59,47.74 172.35,47.74 172.11,47.5 170.97,47.5 170.76,47.71 170.76,48.48 169.99,49.25 168.19,49.25 167.67,49.77 167.67,51.11 166.45,52.32 166.45,55.13 162.29,59.29 159.97,59.29 158.93,58.26 156.85,58.26 156.53,58.57 153.57,58.57 153.24,58.24 153.24,57.86 153.09,57.71 152.42,57.71 150.82,59.31 148.28,59.31 v1(147.85,59.75)
  BOTTOM w0.076: v1(147.85,59.75) 147.67,59.57 UCPU1.AD7
  BOTTOM w0.102: JNFC1.6 85.83,20.03 86.47,19.39 89.46,19.39 90.19,20.12 92.97,20.12 R1142.1 94.91,18.18 105.07,18.18 105.96,19.06 115.47,19.06 116.35,18.19 126.42,18.19 127.27,19.04 134.46,19.04 138.21,15.29 159.83,15.29 165.57,21.04 168.28,21.04 168.9,20.42 168.9,19.01 171.66,16.25 179.95,16.25 v1(180.23,15.97)
PCH_OPIRCOMP: length 5.7
  BOTTOM w0.089: UCPU1.AW15 143.27,50.01 143.27,49.23
  BOTTOM w0.305: RC156.1 v2(144.97,46.36) 144.97,46.76 143.58,48.16 143.58,48.92 143.27,49.23
PCH_PCIE_WAKE#: length 44.3
  GND1 w0.102: v4(176.2,63.84) 176.35,63.99 v3(177.02,63.99)
  IN1 w0.071: 155.46,55.54 156.62,55.54 157.11,56.03 160.46,56.03 161.72,57.29 v4(162.01,57.29) 163.31,57.29 164.1,58.08 167.83,58.08 168.3,57.61 168.63,57.61 169.77,56.48 172.22,56.48 172.71,56.97 176.62,56.97 176.83,56.77 177.18,56.77 v4(177.59,57.17)
  IN1 w0.086: 155.46,55.54 154,55.54 153.19,56.35 152.06,56.35 151.91,56.5 151.17,56.5 150.91,56.23 149.42,56.23 v1(149.19,56)
  IN4 w0.071: v4(177.59,57.17) 177.2,56.78 176.79,56.78 175.33,58.24 175.33,62.96 v4(176.2,63.84)
  GND3 w0.102: v4(162.01,57.29) 162,57.29 161.65,57.64 v5(161.65,58.01)
  BOTTOM w0.076: v1(149.19,56) 149.19,56.19 148.97,56.41 UCPU1.AJ5
  BOTTOM w0.102: RH146.1 161.78,59.2 v2(161.78,58.7) 161.8,58.67 161.8,58.16 v5(161.65,58.01)
PCH_PLTRST#: length 24
  TOP w0.102: RH168.2 160.05,65.72 UH5.2 UH5.1 159.39,63.38 159.15,63.14 159.15,62.56 RH183.2 159.4,62 v2(160.07,61.34) 160.61,60.79 v3(160.62,60.79)
  GND1 w0.102: v4(161.14,60.32) 161.14,60.42 160.77,60.79 v3(160.62,60.79)
  IN1 w0.071: 154.53,59.44 157.09,59.44 158.37,60.72 159.5,60.72 160.29,59.93 160.75,59.93 v4(161.14,60.32)
  IN1 w0.086: 154.53,59.44 151.65,59.44 151.43,59.22 151.43,58.66 150.8,58.03 149.93,58.03 149.37,57.47 148.29,57.47 147.95,57.81 v1(147.95,57.83)
  BOTTOM w0.076: v1(147.95,57.83) 147.67,57.55 UCPU1.AG7
PCH_PLTRST#_EC: length 336.3
  TOP w0.102: UH5.4 160.7,65.99 RH168.1 v3(160.38,67.2) ; v3(182.5,53.7) 183.81,53.7 185.18,55.07 187.56,55.07 187.95,54.68 187.95,51.18 RH474.2 ; U675.2 41.44,40.23 v3(41.32,40.11) ; UE5.B30 180.47,70.34 180.47,70.02 180.59,69.9 v1(180.59,69.25) ; v3(179.58,77.28) 179.85,77.01 v2(179.85,76.31) RE54.2 179.85,74.69 v1(179.81,74.65) ; v1(54.82,76.84) 55.02,77.04 RH363.1
  GND1 w0.102: v4(41.15,40.79) 41.32,40.62 v3(41.32,40.11) ; v3(179.58,77.28) 179.52,77.28 v4(179.09,77.71) ; v4(159.97,67.72) 159.97,67.6 v3(160.38,67.2) ; v3(182.5,53.7) 182.5,53.41 182.38,53.29 182.35,53.29 v4(182.34,53.3)
  IN1 w0.071: v1(180.59,69.25) 180.4,69.06 179.84,69.06 179.67,69.23 175.39,69.23 175.2,69.42 171.39,69.42 168.7,66.73 165.06,66.73 164.34,67.46 163.29,67.46 163.03,67.19 160.8,67.19 160.27,67.72 v4(159.97,67.72)
  IN2 w0.086: v4(179.09,77.71) 178.68,77.31 168.31,77.31 165.58,80.04 100.52,80.04 99.14,78.67 96.21,78.67 92.9,75.36 76.76,75.36 74.78,77.34 69.4,77.34 68.75,76.69 60.88,76.69 58.52,79.06 55.55,79.06 55.02,78.53 55.02,77.04 v1(54.82,76.84) ; v4(195.81,28.04) 195.33,28.52 195.33,33.28 195.66,33.61 195.66,36.34 195.26,36.74 195.26,43.87 194.53,44.6 193.07,44.6 192.29,45.38 190.12,45.38 185.78,49.72 184.5,49.72 182.54,51.68 182.54,52.38 182.34,52.59 v4(182.34,53.3) 182.34,53.55 181.48,54.42 181.48,55.12 181.91,55.55 181.91,56.55 182.03,56.68 182.03,57.8 182.2,57.97 182.2,58.39 182.02,58.57 182.02,60.4 181.51,60.91 181.51,67.27 180.8,67.97 180.8,69.04 v1(180.59,69.25) 180.59,70.21 180.45,70.34 180.45,70.89 181.77,72.2 181.77,72.35 179.81,74.31 v1(179.81,74.65)
  IN3 w0.086: v4(34.23,44.55) 34.66,44.55 38.47,40.74 41.1,40.74 v4(41.15,40.79)
  IN4 w0.071: v4(34.23,44.55) 34.31,44.47 34.31,41.7 32.8,40.19 27.65,40.19 27.33,40.51 27.33,47.91 23.59,51.65 23.59,55.52 23.14,55.97 23.14,63.66 23.97,64.49 28.1,64.49 32.72,69.1 43.77,69.1 50.97,76.31 54.29,76.31 v1(54.82,76.84) ; v4(195.81,28.04) 192.36,24.59 192.36,20.67 193.77,19.26 196.32,19.26 196.66,18.92 198.76,18.92 199.9,17.78 v1(199.9,17.7)
  BOTTOM w0.102: JIO1.38 199.6,18.09 199.9,17.79 v1(199.9,17.7) ; v1(180.59,69.25) 180.94,69.61 182.21,69.61 182.34,69.74 182.59,69.74 183.65,70.8 JLPDE1.8
PCH_RSMRST#: length 38.8
  TOP w0.102: v1(176.09,63.11) 176.47,63.49 176.94,63.49 UE5.A45 ; v1(175.59,43.55) 175.99,43.94 175.99,44.27 v2(175.5,44.76) 171.78,44.76 171.33,44.3 168.15,44.3 166.85,43 162.46,43 RH159.2 RH133.2
  IN2 w0.086: v1(175.59,43.55) 176.25,44.21 176.25,53.98 175.7,54.54 175.7,56.33 175.4,56.63 175.4,57.79 175.86,58.25 175.86,61.25 176.69,62.08 176.69,62.51 v1(176.09,63.11)
PCH_RSMRST#_R: length 18.7
  TOP w0.089: v1(149.33,47.59) 149.77,48.03 150.71,48.03 v2(150.98,48.3) 152.09,48.3 153.27,47.12
  TOP w0.102: 153.27,47.12 154.53,45.86 159.64,45.86 159.88,45.61 161.56,45.61 161.74,45.44 161.74,44.76 RH133.1
  BOTTOM w0.076: UCPU1.AW6 147.95,50.02 147.95,48.97 v1(149.33,47.59)
PCH_RTCRST#: length 71.2
  TOP w0.102: v1(197.59,30.96) 195.67,30.96 194.9,31.73 193.01,31.73 192.39,31.11 186.34,31.11 v2(183.04,34.42) 182.3,35.16 182.3,38.06 180.91,39.45 v3(178.92,39.45)
  GND1 w0.102: v4(178.5,38.72) 178.92,39.14 v3(178.92,39.45)
  IN4 w0.071: v4(178.5,38.72) 178.08,39.14 176.87,39.14 174.08,41.93 169.17,41.93 165.86,45.25 162.66,45.25 161.08,46.83 159.51,46.83 158.13,48.21 v1(157.6,48.21) 157.54,48.21 155.48,50.27 148.76,50.27 147.87,51.16 v1(147.87,51.33)
  BOTTOM w0.076: v1(147.87,51.33) 147.6,51.6 UCPU1.AU7
  BOTTOM w0.102: RH25.2 157.79,52.33 CLRP1.1 157.8,51.31 CH4.1 158.21,50.8 158.94,50.8 159.16,50.57 159.16,49.97 159.06,49.87 158.29,49.87 157.73,49.31 157.73,48.34 v1(157.6,48.21) ; v1(197.59,30.96) 198.07,31.44 JAPS.9
PCH_RTCX1: length 25.1
  BOTTOM w0.102: YH1.1 168.17,52.7 168.1,52.77 CH2.1 RH2.1 167.11,51.91 165.17,49.97 164.53,49.97 164.2,49.63 v2(160.65,49.63) 160.51,49.49 159.36,49.49 159.26,49.39 158.67,49.39 158.23,48.95 158.23,48.05 157.94,47.75 154,47.75 153.05,48.7 149.67,48.7 149.35,49.02 149.35,49.93 UCPU1.AW5
PCH_RTCX2: length 24.6
  BOTTOM w0.102: YH1.2 169.25,50.2 169.25,50.2 168.31,50.2 168.24,50.13 CH3.1 RH2.2 167.37,50.99 166.76,50.38 166.29,50.38 v2(165.5,49.59) 165.37,49.46 164.72,49.46 164.27,49.01 159.56,49.01 159.46,48.9 159.03,48.9 158.72,48.59 158.72,47.85 158.14,47.27 153.8,47.27 152.56,48.51 149.47,48.51 149.16,48.82 149.16,49.51 UCPU1.AY5
PCH_SATALED#: length 5.5
  TOP w0.089: v1(153.32,63.66) 153.67,64.01 v2(153.98,64.01) 154.39,64.01
  TOP w0.102: RH35.2 154.72,64.01 154.39,64.01
  BOTTOM w0.076: UCPU1.U3 150.56,62.52 151.08,62.52 151.31,62.75 151.31,62.93 151.5,63.12 152.77,63.12 v1(153.32,63.66)
PCH_SMB_ALERT#: length 23.1
  TOP w0.102: v1(166.5,50.76) 166.51,50.76 166.73,50.54 v2(167.1,50.54) 167.1,49.53 166.83,49.26 165.87,49.26 164.63,48.03 164.43,48.03 RP16.2
  IN2 w0.086: v1(166.5,50.76) 166.33,50.59 162.08,50.59 157.97,54.7 156.68,54.7 v1(156.29,54.32)
  BOTTOM w0.076: UCPU1.AN2 151.41,54.28 151.82,54.28 151.86,54.23 152.25,54.23 152.32,54.29 153.57,54.29 154.07,53.8 154.39,53.8
  BOTTOM w0.102: 154.39,53.8 155.73,53.8 156.26,54.32 v1(156.29,54.32)
PCH_SMBCLK: length 159.9
  TOP w0.102: v1(161.29,58.49) 161.12,58.66 161.12,58.87 161.41,59.16 161.41,59.97 161.14,60.24 161.14,62.65 161.41,62.91 161.41,63.67 162.67,64.92 162.67,69.61 159.92,72.35 159.92,73.97 159.82,74.08 159.82,79.95 v2(159.64,80.13) 159.39,80.38 95.92,80.38 95.62,80.08 95.62,79.73 v1(95.43,79.54) ; v1(62.39,77.8) 62.58,77.61 62.58,77.48 62.41,77.32 JXDP.53
  IN4 w0.071: v1(153.25,53.69) 153.25,54.09 153.94,54.78 156.72,54.78 157.63,55.69 159.77,55.69 161.37,57.29 161.37,58.41 v1(161.29,58.49)
  BOTTOM w0.076: UCPU1.AP2 151.19,53.07 151.48,53.36 151.72,53.36 151.92,53.16 152.73,53.16 v1(153.25,53.69)
  BOTTOM w0.102: v1(95.43,79.54) 95.6,79.38 95.6,78.42 96.08,77.93 96.08,73.47 94.37,71.76 77.68,71.76 76.77,70.84 75.55,70.84 75.32,71.08 75.32,71.46 76.17,72.31 76.17,78.93 75.6,79.5 71.51,79.5 71.11,79.1 68.84,79.1 68.17,79.77 63.33,79.77 62.58,79.02 62.58,78 v1(62.39,77.8) ; RP2.1 159.08,58.87 159.23,58.72 159.57,58.72 160.03,59.18 161.09,59.18 161.25,59.03 161.25,58.52 v1(161.29,58.49)
PCH_SMBDATA: length 158.2
  TOP w0.102: v1(62.97,77.8) 62.78,77.61 62.78,77.47 62.92,77.34 62.92,76.22 JXDP.51 ; v1(96.02,79.54) 95.83,79.73 95.83,80 96,80.18 158.89,80.18 159.54,79.52 v2(159.54,73.53) 159.54,72.41 162.45,69.5 162.45,65.03 161.18,63.76 161.18,63 160.94,62.76 160.94,60.16 161.21,59.89 161.21,59.24 160.91,58.95 160.91,58.68 v1(160.72,58.49)
  IN4 w0.071: v1(153,55.14) 153,54.61 153.07,54.55 153.43,54.55 153.86,54.98 156.64,54.98 157.52,55.86 159.66,55.86 160.63,56.83 160.63,58.4 v1(160.72,58.49)
  BOTTOM w0.076: UCPU1.AH1 151.8,56.81 153,55.61 v1(153,55.14)
  BOTTOM w0.102: RP2.2 159.16,58.37 159.28,58.49 159.63,58.49 160.12,58.98 161.01,58.98 161.05,58.94 161.05,58.8 160.74,58.49 v1(160.72,58.49) ; v1(96.02,79.54) 95.8,79.33 95.8,78.5 96.28,78.02 96.28,73.39 94.45,71.55 77.77,71.55 76.85,70.64 75.47,70.64 75.11,70.99 75.11,71.54 75.96,72.39 75.96,78.85 75.52,79.29 71.59,79.29 71.2,78.9 68.76,78.9 68.09,79.57 63.41,79.57 62.78,78.94 62.78,78 v1(62.97,77.8)
PCH_SML0ALERT: length 22.3
  TOP w0.102: RP16.3 164.43,48.53 164.78,48.53 v2(166,49.75) 166.23,49.98 v1(166.66,49.98)
  IN1 w0.071: v1(150.54,55.69) 151.04,55.19 152.06,55.19 152.75,54.49 153.45,54.49 154.02,55.06 157.9,55.06 162.09,50.88 165.76,50.88 v1(166.66,49.98)
  BOTTOM w0.076: UCPU1.AL2 150.91,55.32 v1(150.54,55.69)
PCH_SPI_CLK: length 55.9
  IN1 w0.071: v4(184.4,51.86) 184.54,52.01 184.54,54.03 183.62,54.95 182.59,54.95 182.15,54.5 178.18,54.5 177.88,54.8 173.39,54.8 v1(171.99,53.39)
  IN4 w0.071: v1(150.62,60.15) 151.47,60.15 152.08,60.77 153.89,60.77 154.53,60.12 157.34,60.12 157.41,60.19 157.41,61.5 157.48,61.57 157.62,61.57 157.69,61.5 157.69,60.22 157.79,60.12 157.93,60.12 158.03,60.22 158.03,61.51 158.11,61.6 158.23,61.6 158.32,61.51 158.32,61.21 158.4,61.13 158.52,61.13 158.6,61.21 158.6,61.49 158.73,61.62 162.2,61.62 163.13,60.69 163.13,60.3 164.59,58.84 167.14,58.84 168.5,57.49 168.5,57.05 168.36,56.9 168.36,56.45 168.85,55.95 169.43,55.95 v1(171.99,53.39)
  GND3 w0.102: v5(184.73,51.25) 184.73,51.27 184.4,51.6 v4(184.4,51.86)
  BOTTOM w0.076: 154.53,59.88 154.27,59.88 154.14,59.75 153.69,59.75 153.51,59.93 153.51,60.18 153.28,60.41 152.25,60.41 152.11,60.27 151.06,60.27 150.94,60.15 v1(150.62,60.15) 150.62,60.18 150.3,60.5 UCPU1.AA3
  BOTTOM w0.102: MC29.2 154.53,59.88 ; v5(184.73,51.25) 184.67,51.19 RP5.7 ; v5(184.73,51.25) 184.73,51.35 184.39,51.7 184.08,51.7 RP5.6 ; v5(184.73,51.25) 184.73,51 184.42,50.69 RP5.8
PCH_SPI_CLK_TPM: length 14
  TOP w0.102: U652.21 182.92,51.35 183.04,51.48 183.55,51.48 183.65,51.58 183.65,51.72 183.47,51.89 183.47,52.09 183.37,52.19 183.22,52.19 183.11,52.09 183.11,51.91 183,51.8 182.9,51.8 182.78,51.93 v2(182.78,52.01) 182.69,52.01 182.57,52.14 182.57,52.28 182.69,52.41 182.98,52.41 183.06,52.49 183.06,52.61 182.98,52.69 182.2,52.69 182.07,52.56 182.07,52.27 v1(182.14,52.21)
  BOTTOM w0.102: MC33.1 181.72,52.09 181.83,52.21 v1(182.14,52.21) 182.01,52.08 182.01,51.8 181.88,51.67 180.95,51.67 180.83,51.8 180.83,52.28 180.71,52.4 180.55,52.4 180.43,52.28 180.43,51.8 180.31,51.67 180.19,51.67 180.09,51.57 180.09,51.43 180.19,51.33 181.88,51.33 182.01,51.2 182.01,51.18 182.08,51.1 182.34,51.1 182.43,51.19 182.43,51.46 182.67,51.69 RP5.3
PCH_SPI_CS0#: length 56.6
  TOP w0.102: v6(175.52,52.5) 175.3,52.71 v1(175.3,53.03)
  IN4 w0.071: v1(148.05,61.64) 148.39,61.3 149.29,61.3 149.53,61.54 149.53,61.9 149.71,62.07 150.13,62.07 150.31,62.24 152.94,62.24 153.43,61.75 154.32,61.75 154.81,62.23 155.61,62.23 155.68,62.16 155.68,61.38 155.76,61.3 155.88,61.3 155.96,61.38 155.96,62.16 156.03,62.23 156.17,62.23 156.25,62.16 156.25,61.58 156.33,61.5 156.45,61.5 156.53,61.58 156.53,62.16 156.6,62.23 159.01,62.23 159.08,62.31 159.08,62.61 159.17,62.7 159.28,62.7 159.37,62.61 159.37,62.31 159.44,62.23 159.74,62.23 159.81,62.31 159.81,62.52 159.9,62.6 160.01,62.6 160.1,62.52 160.1,62.31 160.17,62.23 160.31,62.23 160.38,62.31 160.38,62.89 160.47,62.98 160.58,62.98 160.67,62.89 160.67,62.31 160.74,62.23 162.17,62.23 162.51,62.57 162.85,62.57 162.92,62.5 162.92,62.13 163,62.06 163.14,62.06 163.21,62.13 163.21,62.5 163.28,62.57 164.38,62.57 164.89,62.07 164.89,61.97 164.7,61.78 164.7,61.68 164.8,61.58 164.9,61.58 165.09,61.77 165.19,61.77 165.41,61.55 167.38,61.55 167.76,61.16 167.76,60.86 167.83,60.79 168.21,60.79 168.28,60.72 168.28,60.57 168.21,60.5 167.83,60.5 167.76,60.43 167.76,60.29 167.83,60.22 168.21,60.22 168.28,60.15 168.28,60.01 168.21,59.93 167.83,59.93 167.76,59.86 167.76,59.39 169.32,57.83 169.32,57.34 173.19,53.47 174.86,53.47 v1(175.3,53.03)
  BOTTOM w0.076: UCPU1.Y7 147.67,61.25 v1(148.05,61.64)
  BOTTOM w0.102: U48.1 175.93,53.77 176.18,53.51 176.97,53.51 177.07,53.41 177.07,53.17 176.94,53.04 175.9,53.04 175.77,52.92 175.77,52.68 175.9,52.55 176.94,52.55 177.07,52.42 177.07,52.19 176.94,52.07 175.82,52.07 175.7,51.94 175.7,51.76 175.82,51.63 176.94,51.63 177.07,51.51 177.07,51.23 176.94,51.1 175.43,51.1 175.3,51.23 v1(175.3,53.03)
PCH_SPI_CS1#: length 52
  TOP w0.102: v2(173.66,51.81) v1(174.25,51.81)
  IN4 w0.071: v1(149.21,60.77) 149.46,60.52 151.56,60.52 152.01,60.97 154.2,60.97 154.66,60.5 155.39,60.5 155.99,61.11 156.38,61.11 157.27,62 162.4,62 162.58,61.83 164.09,61.83 164.59,61.32 167.28,61.32 167.54,61.07 167.54,59.3 169.1,57.73 169.1,57.25 174.24,52.11 174.24,51.81 v1(174.25,51.81)
  BOTTOM w0.076: UCPU1.Y4 149.65,61.22 v1(149.21,60.77)
  BOTTOM w0.102: v1(174.25,51.81) 174.73,52.29 174.73,53.31 175.32,53.89 175.32,55.56 176.33,56.57 178.26,56.57 178.7,56.13 180.73,56.13 183.01,58.4 185.32,58.4 186.46,57.27 186.94,57.27 187.06,57.39 U727.1
PCH_SPI_CS2#: length 38.7
  TOP w0.102: v2(176,49.16) v1(176.64,49.16) 176.85,48.95 180.7,48.95 181.07,49.32 182.01,49.32 182.27,49.58 U652.22
  IN4 w0.071: v1(152.57,59.98) 153.09,59.46 158.28,59.46 159.06,60.24 159.62,60.24 159.89,59.96 162.57,59.96 166.75,55.78 168.18,55.78 168.6,55.35 169.18,55.35 171.92,52.61 171.92,52.28 173.98,50.21 175.62,50.21 176.64,49.2 v1(176.64,49.16)
  BOTTOM w0.076: v1(152.57,59.98) 152.46,60.09 151.24,60.09 150.96,59.81 UCPU1.AC2
PCH_SPI_IO2: length 47.4
  TOP w0.076: v1(148.6,61.67) 148.15,62.11 v2(147.57,62.11) RH57.2
  IN1 w0.071: v4(183.47,54.53) 183.46,54.53 182.8,53.87 180.57,53.87 v4(179.39,52.69)
  IN4 w0.071: v4(179.39,52.69) 179.01,52.69 177.52,54.18 175.92,54.18 175.43,53.7 173.37,53.7 170.31,56.76 170.31,57.34 169.8,57.86 169.61,57.86 168.8,58.66 168.8,60.62 167.65,61.77 165.5,61.77 164.48,62.8 162.74,62.8 162.16,63.37 161.19,63.37 161.02,63.2 159.31,63.2 158.58,62.47 154.73,62.47 154.17,61.91 153.5,61.91 153.01,62.4 150.26,62.4 150.07,62.22 149.15,62.22 v1(148.6,61.67)
  GND3 w0.102: v5(183.57,54.89) 183.57,54.63 v4(183.47,54.53)
  BOTTOM w0.076: v1(148.6,61.67) 148.32,61.38 UCPU1.Y6
  BOTTOM w0.102: RP8.5 184.07,55.01 183.7,55.01 v5(183.57,54.89) 183.94,54.51 184.07,54.51 RP8.6
PCH_SPI_IO3: length 47.5
  TOP w0.076: RH55.2 153.49,57.49 v1(152.87,58.11)
  TOP w0.102: v2(173.03,50.29) 173.03,50.03 v1(173.45,49.62)
  IN1 w0.071: v4(183.46,52.94) 182.76,53.64 181.67,53.64 180.95,52.92 180.63,52.92 179.52,51.81 176.12,51.81 173.92,49.62 v1(173.45,49.62)
  IN4 w0.071: v1(152.87,58.11) 153.75,58.99 159.35,58.99 159.87,59.52 162.38,59.52 167.2,54.7 167.2,51.89 167.89,51.2 167.89,49.89 168.31,49.47 170.08,49.47 170.98,48.58 170.98,47.8 171.06,47.72 172.02,47.72 172.26,47.96 172.49,47.96 173.21,48.67 173.21,49.37 v1(173.45,49.62)
  GND3 w0.102: v5(183.51,53.58) 183.51,52.99 v4(183.46,52.94)
  BOTTOM w0.076: v1(152.87,58.11) 152.87,58.12 152.58,58.41 151.7,58.41 UCPU1.AF1
  BOTTOM w0.102: RP8.7 184.07,54.01 183.68,54.01 183.51,53.84 v5(183.51,53.58) 183.57,53.51 RP8.8
PCH_SPI_SI: length 51.2
  IN4 w0.071: v1(153.86,60.19) 154.31,59.74 158.25,59.74 158.98,60.47 158.98,61.17 159.05,61.24 159.19,61.24 159.26,61.17 159.26,60.69 159.34,60.61 159.46,60.61 159.55,60.69 159.55,61.17 159.62,61.24 159.76,61.24 159.83,61.17 159.83,60.74 159.91,60.66 160.03,60.66 160.11,60.74 160.11,61.17 160.19,61.24 160.33,61.24 160.4,61.17 160.4,60.74 160.48,60.66 160.6,60.66 160.68,60.74 160.68,61.17 160.76,61.24 160.9,61.24 160.97,61.17 160.97,60.72 161.02,60.66 161.49,60.66 161.97,60.19 162.66,60.19 166.85,56 168.27,56 168.69,55.58 169.27,55.58 172.14,52.71 172.14,52.4 174.1,50.44 177.64,50.44 178.96,49.12 178.96,48.42 179.39,47.98 180.25,47.98 181.49,46.74 v4(181.88,46.74)
  GND3 w0.102: v5(181.62,47.15) 181.63,47.15 181.88,46.9 v4(181.88,46.74)
  BOTTOM w0.076: v1(153.86,60.19) 153.21,60.84 151.24,60.84 UCPU1.AA2
  BOTTOM w0.102: RP6.7 182.36,48.85 181.88,48.37 181.88,47.41 v5(181.62,47.15) ; v5(181.62,47.15) 181.41,47.36 181.41,48.41 182.35,49.35 RP6.8 ; v5(181.62,47.15) 181.66,47.11 181.96,47.11 182.22,47.38 182.22,48.19 182.38,48.35 RP6.6
PCH_SPI_SI_TPM: length 14.3
  TOP w0.102: v2(181.46,51.96) 181.62,51.81 v3(181.62,50.48)
  GND1 w0.102: v3(181.62,50.48) 181.62,50.47 v4(181.62,49.75)
  GND3 w0.102: v4(181.62,49.75) 181.91,49.46 v5(181.96,49.46)
  BOTTOM w0.102: RP6.3 184.56,48.35 184.64,48.27 184.64,47.41 184.51,47.28 184.43,47.28 184.31,47.15 184.31,46.69 184.18,46.57 184.07,46.57 183.94,46.69 183.94,47.15 183.81,47.28 183.27,47.28 183.14,47.15 183.14,46.7 183.04,46.61 182.91,46.61 182.81,46.7 182.81,47.15 182.68,47.28 182.59,47.28 182.5,47.36 182.5,47.48 182.59,47.56 183.35,47.56 183.51,47.71 183.51,49.46 183.34,49.63 182.89,49.63 182.85,49.67 182.85,49.86 182.77,49.93 182.66,49.93 182.55,49.83 182.55,49.69 182.47,49.6 182.34,49.6 182.25,49.69 182.25,49.84 182.16,49.93 182.03,49.93 181.96,49.86 v5(181.96,49.46)
PCH_SPI_SO: length 40.8
  IN1 w0.071: v4(182.4,56.77) 182.64,56.52 182.64,55.81 182.39,55.56 180.86,55.56 180.4,55.1 178.43,55.1 178.1,55.43 168.39,55.43 v4(168.19,55.23)
  IN4 w0.071: v1(150.02,60.17) 150.46,59.73 152.01,59.73 152.51,59.23 159.28,59.23 159.78,59.74 162.47,59.74 167.35,54.86 167.82,54.86 v4(168.19,55.23)
  GND3 w0.102: v5(182.82,57.32) 182.4,56.9 v4(182.4,56.77)
  BOTTOM w0.076: UCPU1.AA4 149.65,60.54 v1(150.02,60.17)
  BOTTOM w0.102: v5(182.82,57.32) 183.45,57.32 RP7.7 ; v5(182.82,57.32) 182.82,57.45 183.19,57.82 RP7.8 ; v5(182.82,57.32) 182.82,57.11 183.11,56.82 183.45,56.82 RP7.6
PCH_SPI_SO_TPM: length 12.9
  TOP w0.102: U652.26 179.67,51.47 179.75,51.56 180.38,51.56 180.51,51.69 180.51,51.79 180.4,51.9 178.71,51.9 178.61,52.01 178.61,52.16 178.71,52.27 v2(179.67,52.27) 180.33,52.27 181.79,53.73 181.79,54.67 v1(182.02,54.9)
  BOTTOM w0.102: v1(182.02,54.9) 182.72,55.6 183.39,55.6 184.05,56.26 184.05,56.66 184.21,56.82 184.6,56.82 RP7.3
PCH_SRTCRST#: length 14.6
  IN4 w0.071: v1(156.91,48.2) 156.91,48.2 156.18,48.93 153.89,48.93 152.74,50.08 148.36,50.08 v1(147.85,50.58)
  BOTTOM w0.076: v1(147.85,50.58) 148.22,50.95 UCPU1.AV6
  BOTTOM w0.102: v1(156.91,48.2) 157.25,48.54 v2(157.25,48.74) 157.25,49.51 157.75,50.02 CH5.1 157.75,50.42 156.74,51.43 RH23.2
PCH_SYS_PWROK_XDP: length 6.5
  TOP w0.102: v2(62.25,80.53) 62.25,79.09 62.66,78.68 R1309.1 C1282.1 R1311.2 64.48,78.06 63.91,77.49 JXDP.47
PCIE_PRX_CARDTX_N1: length 113.9
  IN1 w0.071: v1(141.86,69.01) 141.86,69.07 142.15,69.35 144.09,69.35 144.52,69.78 146.99,69.78 148.22,71.01 150.99,71.01 151.75,70.25 152.93,70.25 153.17,70.49 158.64,70.49 160.01,69.12 163.85,69.12 164.16,68.81 164.79,68.81 165.1,69.12 166.58,69.12 166.98,69.52 169.79,69.52 171.13,70.85 176.16,70.85 176.27,70.74 180.01,70.74 180.37,70.37 182.24,70.37 182.52,70.09 183.68,70.09 184.36,70.77 186.87,70.77 187.06,70.96 188.87,70.96 190.63,69.19 190.63,67.99 191.23,67.4 191.23,65.97 190.44,65.18 190.44,63.12 189.42,62.1 189.42,56.28 189.88,55.82 189.88,53.31 190.3,52.88 190.3,51.6 193.1,48.8 193.1,47.6 194.03,46.67 194.51,46.67 196.8,44.38 196.8,36.76 198.02,35.55 198.02,27.14 200.69,24.47 200.69,20.68 203.11,18.25 203.11,17.63 v1(202.92,17.44)
  BOTTOM w0.076: UCPU1.G17 142.34,68.54 v1(141.86,69.01)
  BOTTOM w0.102: v1(202.92,17.44) 203.09,17.61 203.09,17.65 202.6,18.14 JIO1.28
PCIE_PRX_CARDTX_P1: length 113.9
  IN1 w0.071: v1(141.86,69.56) 141.94,69.48 144.03,69.48 144.46,69.91 146.94,69.91 148.16,71.14 151.05,71.14 151.8,70.38 152.88,70.38 153.11,70.62 158.7,70.62 160.07,69.25 163.9,69.25 164.21,68.94 164.73,68.94 165.04,69.25 166.52,69.25 166.92,69.65 169.74,69.65 171.08,70.98 176.21,70.98 176.33,70.87 180.06,70.87 180.42,70.5 182.29,70.5 182.58,70.22 183.62,70.22 184.3,70.9 186.82,70.9 187.01,71.09 188.92,71.09 190.76,69.25 190.76,68.05 191.36,67.45 191.36,65.92 190.57,65.13 190.57,63.06 189.56,62.05 189.56,56.33 190.01,55.88 190.01,53.36 190.43,52.94 190.43,51.66 193.23,48.85 193.23,47.65 194.09,46.8 194.57,46.8 196.94,44.43 196.94,36.82 198.15,35.6 198.15,27.2 200.82,24.53 200.82,20.73 203.24,18.31 203.24,17.7 v1(203.5,17.44)
  BOTTOM w0.076: v1(141.86,69.56) 142.34,69.09 UCPU1.F17
  BOTTOM w0.102: JIO1.26 203.2,18.28 203,18.08 203,18.03 203.3,17.73 203.3,17.64 v1(203.5,17.44)
PCIE_PRX_WLANTX_N4: length 153.7
  IN4 w0.071: 144.35,69.14 144.43,69.14 v1(144.67,69.38) ; v1(37.76,43.74) 37.76,43.62 37.84,43.54 37.91,43.54 38.02,43.42 39.19,43.42 41.6,45.83 42.21,45.83 48.37,51.99 48.37,61.95 49.15,62.73 49.15,72.68 51.37,74.9 55.74,74.9 58.23,77.39 61.09,77.39 61.87,76.62 66.81,76.62 68.55,78.36 70.9,78.36 71.73,77.53 73.97,77.53 74.37,77.92 78.14,77.92 80.68,75.38 85.63,75.38 88.46,78.22 92.58,78.22 93.27,78.9 97.61,78.9 98.37,78.14 100.76,78.14 101.87,79.26 107.3,79.26 109.05,77.52 109.05,72.43 109.77,71.71 110.42,71.71
  IN4 w0.076: 144.35,69.14 144.25,69.24 144.25,70.51 143.05,71.71 110.42,71.71
  BOTTOM w0.076: v1(144.67,69.38) 144.29,69.01 UCPU1.F13
  BOTTOM w0.102: v1(37.76,43.74) 37.92,43.58 38.17,43.58 38.23,43.52 38.98,43.52 42.25,40.25 JNGFF1.35
PCIE_PRX_WLANTX_P4: length 153.6
  IN4 w0.071: 144.29,69 144.52,69 144.67,68.86 v1(144.67,68.63) ; 110.37,71.58 110.36,71.58 109.71,71.58 108.92,72.38 108.92,77.46 107.25,79.13 101.93,79.13 100.81,78.01 98.32,78.01 97.56,78.77 93.32,78.77 92.64,78.08 88.52,78.08 85.69,75.25 80.63,75.25 78.09,77.79 74.42,77.79 74.03,77.4 71.67,77.4 70.85,78.22 68.61,78.22 66.87,76.48 61.81,76.48 61.04,77.26 58.28,77.26 55.79,74.77 51.42,74.77 49.28,72.63 49.28,62.67 48.51,61.9 48.51,51.94 42.27,45.7 41.66,45.7 39.25,43.29 37.89,43.29 v1(37.76,43.16)
  IN4 w0.076: 144.29,69 144.11,69.18 144.11,70.45 142.99,71.58 110.37,71.58
  BOTTOM w0.076: v1(144.67,68.63) 144.39,68.36 UCPU1.G13
  BOTTOM w0.102: v1(37.76,43.16) 37.76,43.25 37.89,43.37 38.08,43.37 38.15,43.31 38.9,43.31 42.04,40.16 42.04,39.84 41.94,39.73 41.81,39.73 41.75,39.67 JNGFF1.33
PCIE_PTX_C_CARDRX_N1: length 5.6
  BOTTOM w0.076: CH25.2 134.72,74.23 134.72,73.35 134.13,72.75 133.26,72.75 132.94,72.43 132.94,72.26 132.94,72.26 132.98,72.16 133,72.1 133.02,72.03 133.02,71.87 133,71.8 132.94,71.66 132.99,71.47 133.19,71.27 133.38,71.27 133.82,70.83 UCPU1.C30
PCIE_PTX_C_CARDRX_P1: length 5.6
  BOTTOM w0.076: UCPU1.C31 133.13,71.08 132.94,71.25 132.9,71.31 132.9,71.31 132.84,71.4 132.77,71.67 132.84,71.86 132.86,71.9 132.86,72 132.84,72.05 132.82,72.1 132.8,72.17 132.77,72.19 132.77,72.5 133.19,72.92 134.06,72.92 134.56,73.42 134.56,74.18 134.52,74.21 134.52,74.54 134.42,74.64 134.24,74.64 CH26.2
PCIE_PTX_CARDRX_N1: length 125.7
  IN1 w0.071: v1(135.16,75.95) 135.13,75.92 135,75.92 134.96,75.96 134.96,76.09 134.93,76.12 134.93,76.2 135.06,76.33 135.65,76.33 135.74,76.23 148.19,76.23 148.54,76.59 157.18,76.59 159.74,79.15 165.88,79.15 168.81,76.21 171.37,76.21 171.76,76.61 173.94,76.61 174.1,76.46 180.78,76.46 180.91,76.32 184.71,76.32 185.16,76.77 189.95,76.77 192.95,73.77 194.34,73.77 196.19,71.91 196.19,53.71 199.66,50.24 199.66,48.86 203.51,45.01 203.51,38.19 204.14,37.55 204.14,35.59 205.69,34.05 205.69,27.31 205.95,27.05 205.95,22.73 206.57,22.11 206.57,19.66 206.47,19.57 206.47,19.45 206.41,19.39 206.28,19.39 v1(206.25,19.41)
  BOTTOM w0.102: v1(135.16,75.95) 134.84,75.63 134.84,75.49 CH25.1 ; JIO1.16 206.2,18.74 206.48,19.02 206.48,19.19 v1(206.25,19.41)
PCIE_PTX_CARDRX_P1: length 125.8
  IN1 w0.071: v1(134.59,75.99) 134.61,76.01 134.61,76.07 135.01,76.46 135.7,76.46 135.8,76.37 148.13,76.37 148.49,76.72 157.13,76.72 159.69,79.28 165.93,79.28 168.86,76.35 171.31,76.35 171.71,76.74 174,76.74 174.15,76.59 180.83,76.59 180.97,76.46 184.66,76.46 185.1,76.9 190.01,76.9 193.01,73.9 194.39,73.9 196.32,71.97 196.32,53.77 199.79,50.3 199.79,48.92 203.64,45.07 203.64,38.24 204.28,37.61 204.28,35.65 205.82,34.1 205.82,27.36 206.08,27.1 206.08,22.78 206.7,22.17 206.7,19.55 v1(206.84,19.41)
  BOTTOM w0.102: v1(134.59,75.99) 134.07,75.46 CH26.1 ; v1(206.84,19.41) 206.81,19.41 206.68,19.29 206.68,18.91 206.8,18.79 JIO1.14
PCIE_PTX_WLANRX_N4: length 179.3
  IN1 w0.071: v1(33.13,42.34) 33.3,42.34 33.43,42.47 33.43,42.81 31.31,44.92 29.6,44.92 29.24,44.57 23.01,44.57 21.81,45.77 21.81,48.44 19.69,50.56 19.69,55.9 18.28,57.3 18.28,71.92 25.55,79.19 46.37,79.19 47.84,80.66 59.04,80.66 59.9,79.8 68.04,79.8 68.86,80.62 77.19,80.62 80.48,77.33 83.47,77.33 86.82,80.67 135.04,80.67 136.4,79.31 v1(136.4,78.51)
  BOTTOM w0.102: CH11.1 136.22,77.93 136.22,78.33 v1(136.4,78.51) ; v1(33.13,42.34) 33.46,42.67 34.21,42.67 36.35,40.54 40.46,40.54 40.75,40.25 40.75,38.77 JNGFF1.29
PCIE_PTX_WLANRX_N4_C: length 6
  BOTTOM w0.076: 136.31,75.43 136.31,75.42 136.29,75.41 136.29,75.35 136.28,75.34 136.28,75.23 135.55,74.5 135.55,73.49 134.68,72.61 134.68,71.92 UCPU1.B29
  BOTTOM w0.102: CH11.2 136.31,76.46 136.31,75.43
PCIE_PTX_WLANRX_P4: length 179.3
  IN1 w0.071: v1(135.82,78.51) 135.92,78.51 136.04,78.63 136.04,78.66 136.27,78.89 136.27,79.26 134.99,80.54 86.87,80.54 83.53,77.19 80.43,77.19 77.14,80.48 68.92,80.48 68.1,79.66 59.85,79.66 58.98,80.53 47.89,80.53 46.43,79.06 25.61,79.06 18.41,71.87 18.41,57.36 19.82,55.95 19.82,50.62 21.94,48.49 21.94,45.82 23.06,44.7 29.19,44.7 29.55,45.06 31.36,45.06 33.56,42.86 33.56,42.16 v1(33.71,42.01)
  BOTTOM w0.102: CH16.1 136.02,77.97 136.02,78.31 v1(135.82,78.51) ; JNGFF1.27 40.25,38.77 40.25,39.62 40.34,39.71 40.47,39.71 40.54,39.78 40.54,40.17 40.38,40.33 36.26,40.33 34.13,42.47 33.54,42.47 33.51,42.43 33.51,42.08 33.58,42.01 v1(33.71,42.01)
PCIE_PTX_WLANRX_P4_C: length 6
  BOTTOM w0.076: 136.1,75.43 136.1,75.31 135.37,74.58 135.37,73.56 134.37,72.56 134.21,72.56 134.09,72.45 134.09,72.2 134.13,72.16 134.27,72.16 134.38,72.27 UCPU1.A29
  BOTTOM w0.102: 136.1,75.43 136.1,76.25 CH16.2
PCIE_RCOMP: length 5
  BOTTOM w0.305: UCPU1.A27 135.76,72.97 136.03,73.24 136.03,74.28 v2(137.25,75.49) 138.04,76.29 RH338.2
PCIE_WAKE#: length 222.7
  TOP w0.102: v1(186.44,65.37) 186.57,65.24 UE5.B8
  IN1 w0.071: v4(48.3,15.86) 49.7,17.26 49.7,21.71 49.2,22.2 46.21,22.2 43.34,25.07 43.34,27.27 43.12,27.48 43.12,37.88 v4(42.68,38.33)
  IN3 w0.086: v1(186.44,65.37) 186.09,65.02 186.09,63.98 185.93,63.82 185.93,59.63 184.23,57.93 184.23,52.82 184.98,52.07 184.98,49.49 186.63,47.84 186.63,45.64 184.22,43.24 184.22,21.06 183.65,20.49 181.27,20.49 178.56,17.77 176.32,17.77 173.64,15.09 141.48,15.09 139.27,17.31 127.67,17.31 126.08,15.72 118.43,15.72 116.79,17.36 103.99,17.36 103.54,17.8 94.38,17.8 93.94,17.36 69.04,17.36 68.62,16.94 49.39,16.94 v4(48.3,15.86)
  GND3 w0.102: v4(42.68,38.33) 43.15,37.86 v5(43.15,37.75)
  BOTTOM w0.102: v5(43.15,37.75) 43.53,37.36 v2(43.96,37.36) 44.67,37.36 45.25,37.94 JNGFF1.47 ; v1(186.44,65.37) 187.29,64.52 RE86.1
PECI_EC: length 71.7
  TOP w0.076: v1(113.92,65.47) v2(114.4,65.47)
  GND1 w0.102: v3(174.13,60.28) v4(174.13,60.64)
  IN1 w0.071: v4(174.13,60.64) 174.13,61.37 173.7,61.8 167.67,61.8 165.71,63.75 161.49,63.75 160.95,64.3 160.44,64.3 160.21,64.07 159.09,64.07 158.83,64.33 158.6,64.33 157.76,65.17 154.84,65.17 154.11,64.44 152.01,64.44 151.55,63.97 149.24,63.97 149,64.21 149,65.62 148.54,66.07 148.54,66.84 148.38,67 146.88,67 146.13,66.25 142,66.25 141.7,65.95 141.7,64.94 v1(141.2,64.45)
  IN4 w0.076: v1(141.2,64.45) 140.15,65.5 140.15,66.86 139.35,67.66 117.4,67.66 115.2,65.47 v1(113.92,65.47)
  BOTTOM w0.076: v1(113.92,65.47) 113.63,65.17 UCPU1.N62
PECI_EC_R: length 3.2
  TOP w0.102: RE61.1 CE68.1 175.82,61.16 v2(176.05,61.39) 176.65,61.99 UE5.A48
PEG_WIGIGCLK_REQ#: length 17.1
  IN2 w0.086: v1(149.12,62.59) 149.45,62.92 149.45,63.08 150.07,63.7 151.64,63.7 152.07,64.14 154.59,64.14 155.34,64.88 157.4,64.88 157.58,65.06 161.24,65.06 161.67,65.49 163.29,65.49 v4(163.44,65.64)
  GND3 w0.102: v5(163.87,66.37) 163.87,66.07 v4(163.44,65.64)
  BOTTOM w0.076: v1(149.12,62.59) 148.97,62.75 UCPU1.U5
PLTRST#_XDP: length 12.5
  TOP w0.102: v2(56.43,78.04) RH363.2 57,76.47 57,76.34 59.53,73.81 62.27,73.81 64.41,71.67 JXDP.46
PM_APWROK: length 20.7
  GND1 w0.102: v4(186.85,65.8) 187.04,65.99 v3(187.92,65.99)
  IN1 w0.071: v4(186.85,65.8) 186.78,65.73 185.23,65.73 184.93,65.44 184.93,63.48 184.73,63.27 182.76,63.27 180.91,61.42 179.88,61.42 179.64,61.18 179.25,61.18 178.63,61.8 177.16,61.8 175.63,60.28 173.84,60.28 v4(173.53,60.59)
  GND3 w0.102: v5(173.42,60.94) 173.42,60.69 v4(173.53,60.59)
  BOTTOM w0.102: v2(174.53,60.89) 173.97,61.45 RH134.2 173.53,61.04 v5(173.42,60.94)
PM_APWROK_R: length 28.7
  TOP w0.102: v6(171.26,62.94) 171.26,61.81 171.14,61.69 UC6.4 170.31,61.69 170.1,61.47 170.1,59.75 v1(170.15,59.7)
  IN2 w0.086: v1(170.15,59.7) 168.54,61.31 165.63,61.31 165.47,61.47 164.83,61.47 164.7,61.35 164.52,61.16 164.25,61.16 163.76,60.67 163.02,60.67 162.72,60.96 162.3,60.96 162.01,60.67 159.5,60.67 157.97,59.14 152.27,59.14 152.02,59.39 148.88,59.39 v1(148.53,59.73)
  BOTTOM w0.076: UCPU1.AB5 148.97,60.17 v1(148.53,59.73)
PM_SLP_S0#: length 104.2
  IN1 w0.071: v4(193.88,31.75) 190.18,31.75 189.47,32.46 186.25,32.46 v4(184.96,33.76)
  IN2 w0.086: v1(156.53,56.55) 156.61,56.64 160.8,56.64 161.95,57.79 164.27,57.79 164.79,58.3 170.85,58.3 173.45,55.7 173.45,51.39 174.21,50.62 174.21,48.99 174.41,48.79 174.41,47.05 174.14,46.78 174.14,42.7 177.35,39.49 180.63,39.49 183.87,36.25 183.87,34.85 v4(184.96,33.76)
  GND3 w0.102: v5(194.3,31.52) 194.11,31.52 v4(193.88,31.75)
  BOTTOM w0.102: RH463.2 156.53,57.08 v1(156.53,56.55) ; JAPS.15 v2(197.96,28.44) 196.52,28.44 194.3,30.66 v5(194.3,31.52) 194.3,33.22 195.33,34.25 195.33,44.48 194.95,44.87 192.99,44.87 192.46,45.4 192.46,61.16 192.8,61.5 193.85,61.5 194.75,62.4 195.83,62.4 196.08,62.65 196.08,63.67 PR511.1
PM_SYS_RESET#: length 184.9
  TOP w0.102: v3(55.66,68.65) 55.66,68.84 54.83,69.67 54.83,74.58 RH451.2 ; v3(185.2,35.14) 185.2,34.49 v2(185.37,34.32) 187.48,32.21 190.12,32.21 190.49,31.84 192.14,31.84 192.72,32.41 195.25,32.41 195.69,31.97 v1(196.04,31.97)
  GND1 w0.102: v3(185.2,35.14) 184.85,35.14 v4(184.8,35.19) ; v4(55.74,68.19) 55.66,68.28 v3(55.66,68.65)
  IN2 w0.086: v1(155.38,58.1) 154.82,57.55 152.92,57.55 152.37,58.1 149.59,58.1 149.48,58.21 146.78,58.21 146.26,58.74 146.26,62.43 144.52,64.17 143.35,64.17 140.02,67.51 139.64,67.51 138.32,68.82 138.32,69.59 137.78,70.13 117.4,70.13 116.72,70.81 113.49,70.81 ; 110.07,71.36 107.95,71.36 106.7,70.11 100.71,70.11 99.46,71.36 81.9,71.36 79.65,69.11 58.75,69.11 58.17,68.54 56.09,68.54 v4(55.74,68.19)
  IN2 w0.089: 113.49,70.81 112.94,71.36 110.07,71.36
  IN4 w0.071: 155.46,58.19 155.67,58.4 156.46,58.4 156.78,58.09 159,58.09 160.04,59.12 162.22,59.12 166.28,55.06 166.28,52.24 167.25,51.27 167.25,49.7 168.05,48.9 169.24,48.9 170.82,47.32 172.18,47.32 172.4,47.54 173.8,47.54 174.6,46.74 179.76,46.74 181.96,44.54 181.96,41.36 184.6,38.72 184.6,35.4 v4(184.8,35.19)
  IN4 w0.086: 155.46,58.19 v1(155.38,58.1)
  BOTTOM w0.102: RH450.2 155.77,58.5 v1(155.38,58.1) ; JAPS.13 196.72,29.44 196.11,30.06 196.11,31.91 v1(196.04,31.97)
POWER_SW_IN#: length 13.3
  TOP w0.102: CE49.1 RE31.2 v3(191.36,60.45) ; v1(184.28,62.9) 184.41,62.9 185.97,61.35 185.97,61.14 UE5.B67
  GND1 w0.102: v4(190.89,60.28) 191.05,60.45 v3(191.36,60.45)
  GND3 w0.102: v5(190.9,60.68) 190.9,60.3 v4(190.89,60.28)
  BOTTOM w0.102: v5(190.9,60.68) 190.9,61.12 190.21,61.82 187.01,61.82 186.68,61.48 185.7,61.48 v2(185,62.19) v1(184.28,62.9)
PROC_OPI_COMP: length 4.7
  BOTTOM w0.102: UCPU1.AY15 142.98,49.35 142.97,49.35 142.97,48.97 143.12,48.82
  BOTTOM w0.305: 143.12,48.82 143.12,48.03 143.77,47.38 v2(143.78,47.38) 144.09,47.08 RC154.1
PS_ID: length 182
  TOP w0.102: v1(43.77,65.84) 43.77,65.86 44.23,65.4 v2(44.23,64.77) ; UE5.B19 185.97,70.34 185.97,69.31 v1(186.34,68.93)
  TOP w0.254: v1(43.77,65.84) 43.62,65.69 PR102.1 43.08,67.46 42.59,67.95 40.81,67.95 39.5,69.26 PR103.2
  IN3 w0.254: v1(43.77,65.84) 43.79,65.86 43.79,66.67 44.51,67.38 44.51,75.7 46.36,77.55 56.32,77.55 56.96,76.91 64.37,76.91 65.09,77.64 65.09,78.65 65.33,78.89 70.48,78.89 71.05,78.32 79.79,78.32 81.29,76.82 83.51,76.82 84.58,77.89 86.91,77.89 87.47,77.33 94.18,77.33 95.88,79.03 99.26,79.03 100.55,80.32 101.87,80.32 101.88,80.31 136.8,80.31 138.35,78.76 152.85,78.76 153.72,77.9 153.72,77.41 153.89,77.24 158.42,77.24 160.67,79.5 165.96,79.5 166.59,78.87 168.27,78.87 168.9,79.5 177.59,79.5 178.85,78.23 179.77,78.23 182.42,75.58 182.38,75.58 182.49,75.47 186.51,75.47 187.08,74.9 187.08,69.54 186.47,68.93 v1(186.34,68.93)
PTP_DIS#: length 156
  TOP w0.102: v1(49.18,14.81) v2(48.51,14.81)
  IN3 w0.086: v1(49.18,14.81) 49.67,14.81 50.65,15.79 54.44,15.79 55.67,14.56 68.67,14.56 69.77,15.66 94.63,15.66 95.08,16.11 102.84,16.11 103.3,15.66 116.07,15.66 117.71,14.02 126.81,14.02 128.4,15.6 138.51,15.6 140.76,13.36 174.31,13.36 177,16.05 179.61,16.05 180.08,15.58 181.53,15.58 184.28,18.33 v1(184.93,18.33)
  BOTTOM w0.102: v1(184.93,18.33) 184.65,18.61 JTP1.6 ; UE4.21 48.78,15.21 v1(49.18,14.81)
PTP_INT#: length 49
  TOP w0.102: v3(191.84,55.42) 192.37,54.88 DZ4.1 DZ3.1 v2(193.51,55.55) ; v1(186.61,18.61) 186.52,18.61 186.02,18.12 Q40.1
  GND1 w0.102: v3(191.84,55.42) 191.64,55.61 191.29,55.61 v4(191.28,55.63)
  IN3 w0.086: v4(191.28,55.63) 191.63,55.28 191.63,53.11 192.22,52.52 192.22,47.14 194.25,45.11 194.85,45.11 195.24,44.71 195.24,28.23 192.22,25.21 192.22,21.54 189.3,18.61 v1(186.61,18.61)
PTP_INT#_EC: length 44.9
  TOP w0.102: RPE5.2 190.46,53.99 190.58,53.88 191.06,53.88 191.24,54.05 191.24,54.61 191.39,54.76 191.65,54.76 191.82,54.6 191.82,53.83 191.61,53.62 191.61,53.39 191.78,53.23 192.37,53.23 DZ4.2 192.37,52.34 191.75,51.72 v2(190.04,51.72) 189.48,51.17 189.48,49.43 189.06,49.01 181.71,49.01 181.65,49.07 181.17,49.07 180.76,48.66 178.88,48.66 v3(178.77,48.54) ; UE5.B37 v1(178.52,68.74)
  GND1 w0.102: v4(178.06,48.58) 178.11,48.54 v3(178.77,48.54)
  IN3 w0.086: v4(178.06,48.58) 178.06,50.13 176.46,51.74 176.46,59.04 177.39,59.97 177.39,61.34 178.03,61.99 178.03,68.25 v1(178.52,68.74)
PTP_INT#_R: length 4.6
  TOP w0.102: v3(185.37,19.5) 184.99,19.89 Q40.3 184.99,20.02 184.99,20.92 R1299.2 v2(185.23,22.22)
  GND1 w0.102: v3(185.37,19.5) 185.23,19.36 v4(185.23,19.14)
  GND3 w0.102: v4(185.23,19.14) 185.23,18.94 v5(185.4,18.78)
  BOTTOM w0.102: JTP1.5 185.15,19.02 v5(185.4,18.78)
PWM1: length 19.9
  TOP w0.254: v1(73.72,61.7) 73.72,61.07 75.76,59.03 v2(82.49,59.03) 86.69,59.03 87.74,60.07 87.74,61.34 v7(87.41,61.67)
  BOTTOM w0.203: PU701.8 87.65,61.05 87.41,61.29 v7(87.41,61.67) ; PU700.6 73.72,61.7 v1(73.72,61.7)
PWR_DEBUG#_XDP: length 64.8
  TOP w0.102: v2(106.57,67.4) 106.98,66.98 v1(106.98,66.95) 106.76,66.73 R1179.2 ; JXDP.45 64.41,72.83 v1(64.91,72.33)
  IN3 w0.086: v1(64.86,68.46) 65.44,69.03 65.85,69.03 67.57,70.75 74.21,70.75 75.47,69.49 98.54,69.49 101.43,66.6 106.63,66.6 v1(106.98,66.95)
  BOTTOM w0.076: 110.51,68.9 112.28,68.9 112.8,68.39 113.17,68.39 113.33,68.55 114.1,68.55 114.23,68.42 115.28,68.42 UCPU1.H59
  BOTTOM w0.102: v1(64.91,72.33) 64.67,72.09 64.67,68.65 v1(64.86,68.46)
  BOTTOM w0.109: 110.51,68.9 110.19,68.58 110.19,68.2 110.05,68.06 109.8,68.06 109.2,67.46 107.31,67.46 106.98,67.13 v1(106.98,66.95)
PWR_SRC_ON: length 6.9
  TOP w0.102: C613.2 R535.2 R536.1 190.87,45.75 v1(191.62,45) v2(192.26,45)
  BOTTOM w0.102: Q70.4 190.72,45.9 v1(191.62,45)
PWRBTN#_XDP: length 5.9
  TOP w0.102: v2(69.04,78.68) R1312.2 RH21.1 RH444.1 66.26,77.79 66,77.53 65.53,77.53 65.41,77.41 JXDP.41
PWRBTN_LED#: length 73.9
  TOP w0.102: v1(180.73,62.35) 181.04,62.03 181.04,61.6 180.97,61.52 180.97,61.14 UE5.B57 ; v1(189.76,14.79) v2(189.76,13.72)
  IN2 w0.086: v1(180.73,62.35) 181.03,62.04 181.03,60.9 180.19,60.06 180.19,58.48 179.64,57.92 179.64,54.69 180.48,53.85 180.48,51.57 182.15,49.9 182.15,47.75 186.5,43.4 192.06,43.4 192.96,42.5 192.96,34.88 194.47,33.37 194.47,27.03 193.77,26.32 193.77,21.59 193.45,21.27 193.45,15.91 192.34,14.79 v1(189.76,14.79)
  BOTTOM w0.102: v1(189.76,14.79) 191.11,14.79 192.05,13.85 194.3,13.85 194.8,14.35 198.02,14.35 198.7,15.03 JIO1.41
REM_DIODE1_N: length 66.4
  TOP w0.127: UE5.B13 186.17,67.74 185.82,68.09 v1(185.82,68.33) ; v1(189.35,68.23) 189.73,68.61 CE58.1 ; v1(142.04,61.55) v2(141.51,62.09) 139.23,62.09 136.44,59.31 135,59.31 CE47.1 134.26,59.65 134.07,59.85 QE3.3
  IN1 w0.127: v4(169.03,63.06) 170.08,64.11 170.08,65.11 172.63,67.66 174.09,67.66 174.17,67.58 177.49,67.58 178.09,66.98 184.02,66.98 184.92,67.88 185.37,67.88 v1(185.82,68.33) 186.27,67.88 187.43,67.88 187.66,68.1 189.22,68.1 v1(189.35,68.23)
  IN4 w0.127: v1(142.04,61.55) 142.75,62.26 142.95,62.26 143.89,63.2 149.27,63.2 149.81,63.75 151.4,63.75 151.91,64.26 153.91,64.26 154.86,65.22 157.28,65.22 157.63,65.57 160.53,65.57 161.6,64.51 162.86,64.51 163.15,64.21 167.13,64.21 168.28,63.06 v4(169.03,63.06)
REM_DIODE1_P: length 68.6
  TOP w0.127: QE3.1 132.21,59.2 132.86,58.55 QE3.2 134.05,58.55 134.24,58.74 CE47.2 134.83,58.92 v2(135.97,58.92) 136.35,58.92 139.31,61.89 141.15,61.89 141.93,61.1 142.21,61.1 v1(142.64,61.53) ; UE5.A13 188.7,67.99 v1(189.23,67.45) 189.48,67.69 CE58.2
  IN1 w0.127: v1(189.23,67.45) 188.84,67.84 187.76,67.84 187.54,67.62 185.02,67.62 184.12,66.73 177.98,66.73 177.39,67.32 174.07,67.32 173.98,67.41 172.74,67.41 170.34,65.01 170.34,64 169.54,63.2 v4(169.54,63.03)
  IN4 w0.127: v4(169.54,63.03) 169.18,62.67 168.31,62.67 167.02,63.96 163.05,63.96 162.75,64.25 161.49,64.25 160.43,65.32 157.74,65.32 157.38,64.96 154.99,64.96 154.08,64.05 151.99,64.05 151.49,63.55 149.9,63.55 149.35,63 143.97,63 142.64,61.67 v1(142.64,61.53)
REM_DIODE2_N: length 227
  TOP w0.127: v1(98.91,76.95) 98.91,69.27 101.38,66.8 101.38,55.92 100.39,54.92 100.39,50.95 96.6,47.17 v2(96.6,45.83) 96.6,45.54 v1(96.41,45.35) ; CE67.1 189.5,70.38 v1(189.21,70.09) ; v1(186.39,68.31) 186.47,68.24 UE5.B14
  IN2 w0.127: v1(189.21,70.09) 189.19,70.09 188.83,69.73 188.24,69.73 187.99,69.98 187.99,72.28 186.81,73.46 181.46,73.46 180.5,74.42 180.5,75.27 179.97,75.8 167.62,75.8 164.94,78.47 159.2,78.47 159.04,78.32 155.54,78.32 154.62,79.23 150.82,79.23 148.21,76.62 138.24,76.62 137.94,76.92 134.45,76.92 133.41,75.88 128.88,75.88 128.29,76.46 128.29,78.7 127.47,79.52 101.43,79.52 99.76,77.85 99.2,77.85 98.91,77.56 v1(98.91,76.95)
  IN4 w0.127: v1(96.41,45.35) 96.72,45.66 96.72,47.18 94.3,49.59 88.98,49.59 86.42,52.15 86.42,54.85 82.96,58.31 82.96,63.01 82.59,63.38 72.22,63.38 66.67,68.93 61.16,68.93 57.62,65.4 54.22,65.4 52.28,63.46 52.28,57.5 50.77,55.99 50.77,52.14 51.48,51.43 53.46,51.43 v1(54.27,50.62)
  BOTTOM w0.127: QE11.1 54.4,53.65 QE11.2 54.4,51.39 CE57.2 v1(54.27,50.62) ; QE4.3 95.66,44.54 CE48.2 95.6,45.04 95.91,45.35 v1(96.41,45.35) ; v1(186.39,68.31) 187.43,68.31 v1(189.21,70.09)
REM_DIODE2_P: length 227.6
  TOP w0.127: UE5.A14 188.3,68.49 189.29,69.47 v1(189.31,69.47) CE67.2 ; v1(97.2,45.35) 96.93,45.62 96.93,47.14 100.64,50.84 100.64,54.82 101.63,55.81 101.63,66.91 99.17,69.37 99.17,75.8 v2(99.33,75.97) v1(99.33,77.42)
  IN2 w0.127: v1(99.33,77.42) 99.69,77.42 101.53,79.26 127.37,79.26 128.03,78.6 128.03,76.36 128.77,75.62 133.56,75.62 134.6,76.67 137.83,76.67 138.13,76.37 148.31,76.37 150.92,78.98 154.52,78.98 155.43,78.06 159.15,78.06 159.3,78.22 164.84,78.22 167.51,75.54 179.86,75.54 180.24,75.16 180.24,74.31 181.35,73.2 186.71,73.2 187.74,72.18 187.74,69.88 188.14,69.47 v1(189.31,69.47)
  IN4 w0.127: v1(53.36,50.62) 53.56,50.83 53.56,50.97 53.36,51.18 51.37,51.18 50.51,52.04 50.51,56.1 52,57.59 52,63.54 54.12,65.66 57.52,65.66 61.05,69.19 66.77,69.19 72.32,63.64 82.7,63.64 83.22,63.12 83.22,58.42 86.67,54.96 86.67,52.26 89.09,49.84 94.41,49.84 96.97,47.28 96.97,45.58 v1(97.2,45.35)
  BOTTOM w0.127: v1(53.36,50.62) CE57.1 53.1,51.52 QE11.3 ; v1(97.2,45.35) 96.68,45.87 95.79,45.87 95.01,45.1 95.01,44.27 CE48.1 96.04,43.24 QE4.2 98.18,43.24 QE4.1
REM_DIODE3_N: length 67.1
  TOP w0.127: CE39.1 189.4,71.25 188.75,70.6 v1(188.75,70.47) 188.65,70.37 188.65,69.48 188.15,68.99 UE5.A15 ; v1(188.28,46.11) 188.25,46.07 178,46.07 176.76,44.84 176.76,43.59 175.99,42.81 v2(175.39,42.81) 175.04,42.81 174.31,42.09 157.49,42.09 156.83,41.43 CE66.2 155.61,41.37 QE10.3
  IN4 w0.127: v1(188.75,70.47) 187.7,69.42 187.7,62.96 188.96,61.7 188.96,56.06 188.11,55.22 188.11,53.63 189.69,52.05 189.69,48.08 188.28,46.67 v1(188.28,46.11)
REM_DIODE3_P: length 73.3
  TOP w0.127: UE5.B16 187.07,69.24 186.72,69.24 v1(186.4,69.56) ; CE39.2 190.45,72.53 v1(190.45,72.91) ; QE10.1 153.21,40.07 QE10.2 154.91,40.51 CE66.1 156.47,40.51 v2(157.11,41.15) 157.8,41.84 174.42,41.84 175.03,42.45 175.99,42.45 177.02,43.48 177.02,44.73 178.11,45.82 187.97,45.82 v1(188.28,45.52)
  IN4 w0.127: v1(188.28,45.52) 188.19,45.52 187.82,45.88 187.82,46.58 189.43,48.19 189.43,51.95 187.86,53.52 187.86,55.32 188.7,56.16 188.7,61.59 187.44,62.85 187.44,68.52 v1(186.4,69.56)
  BOTTOM w0.127: v1(190.45,72.91) 190.45,72.89 187.12,69.56 v1(186.4,69.56)
REM_DIODE4_N: length 10.9
  TOP w0.127: UE5.A16 188.17,69.49 188.33,69.66 188.33,70.63 189.63,71.93 189.63,72.76 190.03,73.16 CE60.1 CE51.1 190.03,75.05 QE8.3 189.14,78.79 v2(189.3,78.95)
REM_DIODE4_P: length 11.5
  TOP w0.127: UE5.B17 187.48,69.74 188.08,70.34 188.08,70.74 189.35,72.01 189.35,73.38 CE60.2 CE51.2 189.12,74.66 QE8.2 187.84,76.96 188.49,77.61 QE8.1 188.49,78.36 v2(187.91,78.93)
RESET_OUT#: length 66.5
  TOP w0.102: R1353.1 166.95,68.96 v1(167.12,69.14) 167.12,69.67 166.48,70.32 166.24,70.32 165.45,71.1 v6(163.2,71.1) ; UE5.B39 v1(178.5,67.74)
  GND1 w0.089: v4(147.95,45.87) 147.95,45.72 147.72,45.49 v3(147.72,45.16)
  GND1 w0.102: v3(173.02,68.53) 173.41,68.53 v4(173.55,68.39)
  IN1 w0.071: v1(178.5,67.74) 178.36,67.74 177.88,68.22 175.17,68.22 174.58,68.81 173.97,68.81 v4(173.55,68.39)
  IN3 w0.076: 153.27,47.15 149.22,47.15 v4(147.95,45.87)
  IN3 w0.086: 153.27,47.15 159.06,47.15 161.84,49.93 164.71,49.93 166.31,51.53 166.31,55.04 164.22,57.13 164.22,58.09 161.52,60.79 161.52,62.96 162.46,63.9 162.46,66.6 162.04,67.02 v4(162.04,68.05)
  IN4 w0.071: v4(173.55,68.39) 169.33,68.39 168.11,69.61 167.39,69.61 167.12,69.34 v1(167.12,69.14) 166.76,68.77 166.3,68.77 165.81,68.28 164.65,68.28 164.43,68.5 162.5,68.5 v4(162.04,68.05)
RESET_OUT#_L: length 3.4
  TOP w0.102: U672.2 164.18,70.44 164.47,70.74 v2(164.67,70.74) 165.22,70.74 R1353.2
RESET_OUT#_R: length 7.9
  TOP w0.076: RH452.1 148.63,45.12 v2(147.71,44.19)
  TOP w0.089: v1(149.79,46.15) 149.7,46.05 RH394.2 RH452.1
  BOTTOM w0.089: v1(149.79,46.15) 149.79,46.36 147.55,48.6 147.55,49.57 UCPU1.AY7
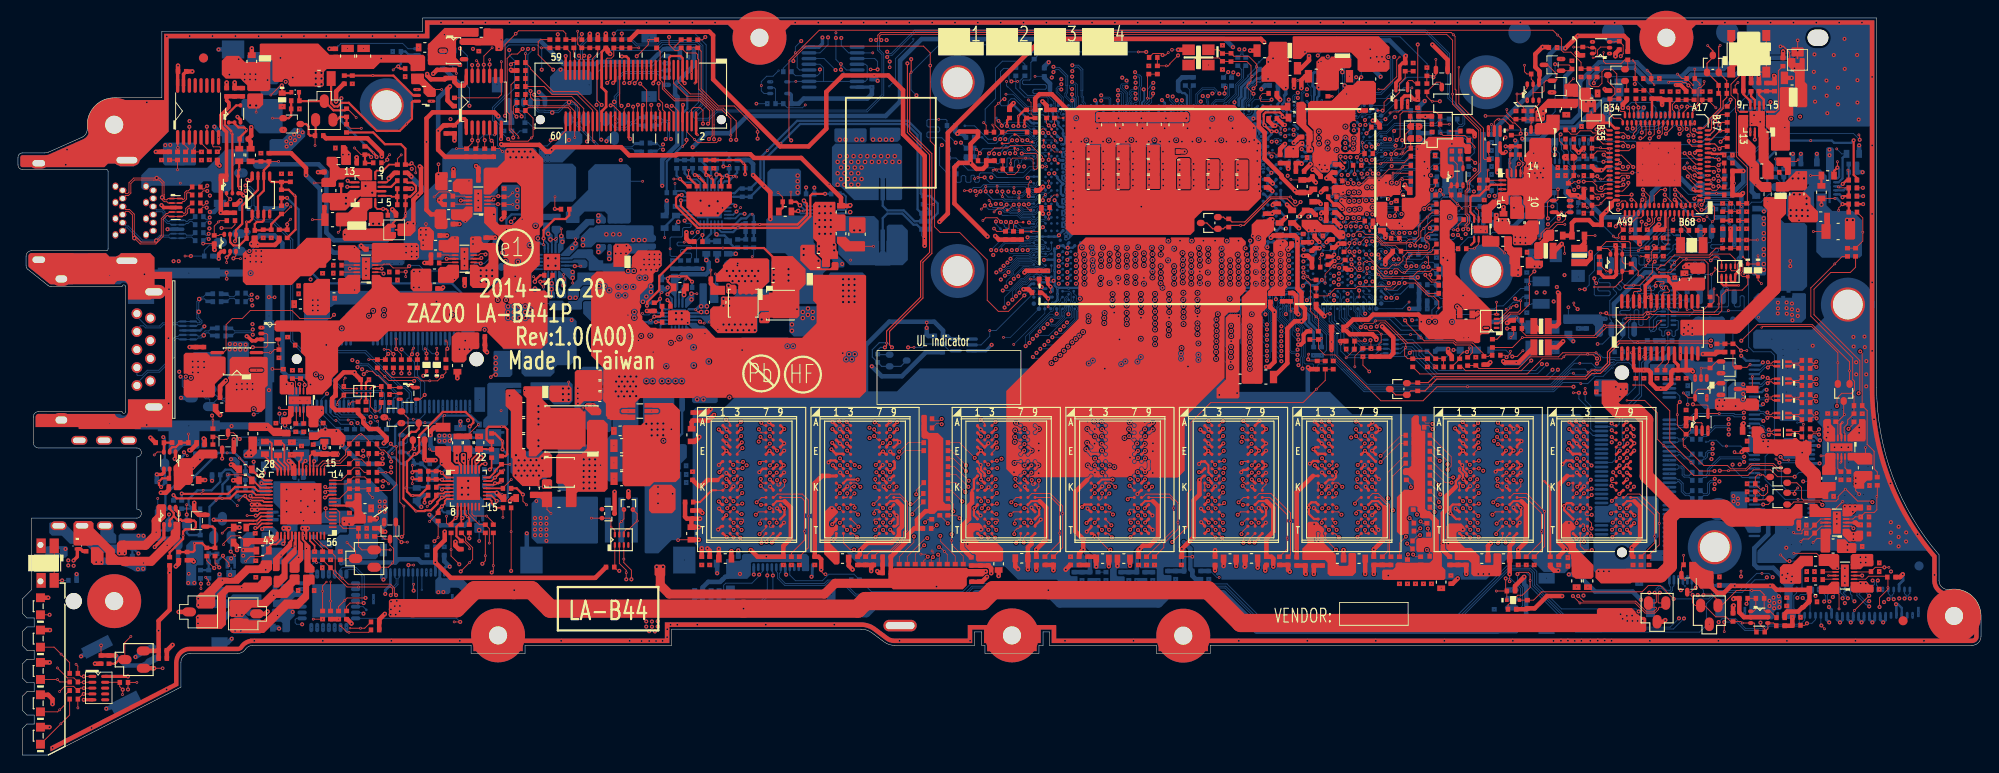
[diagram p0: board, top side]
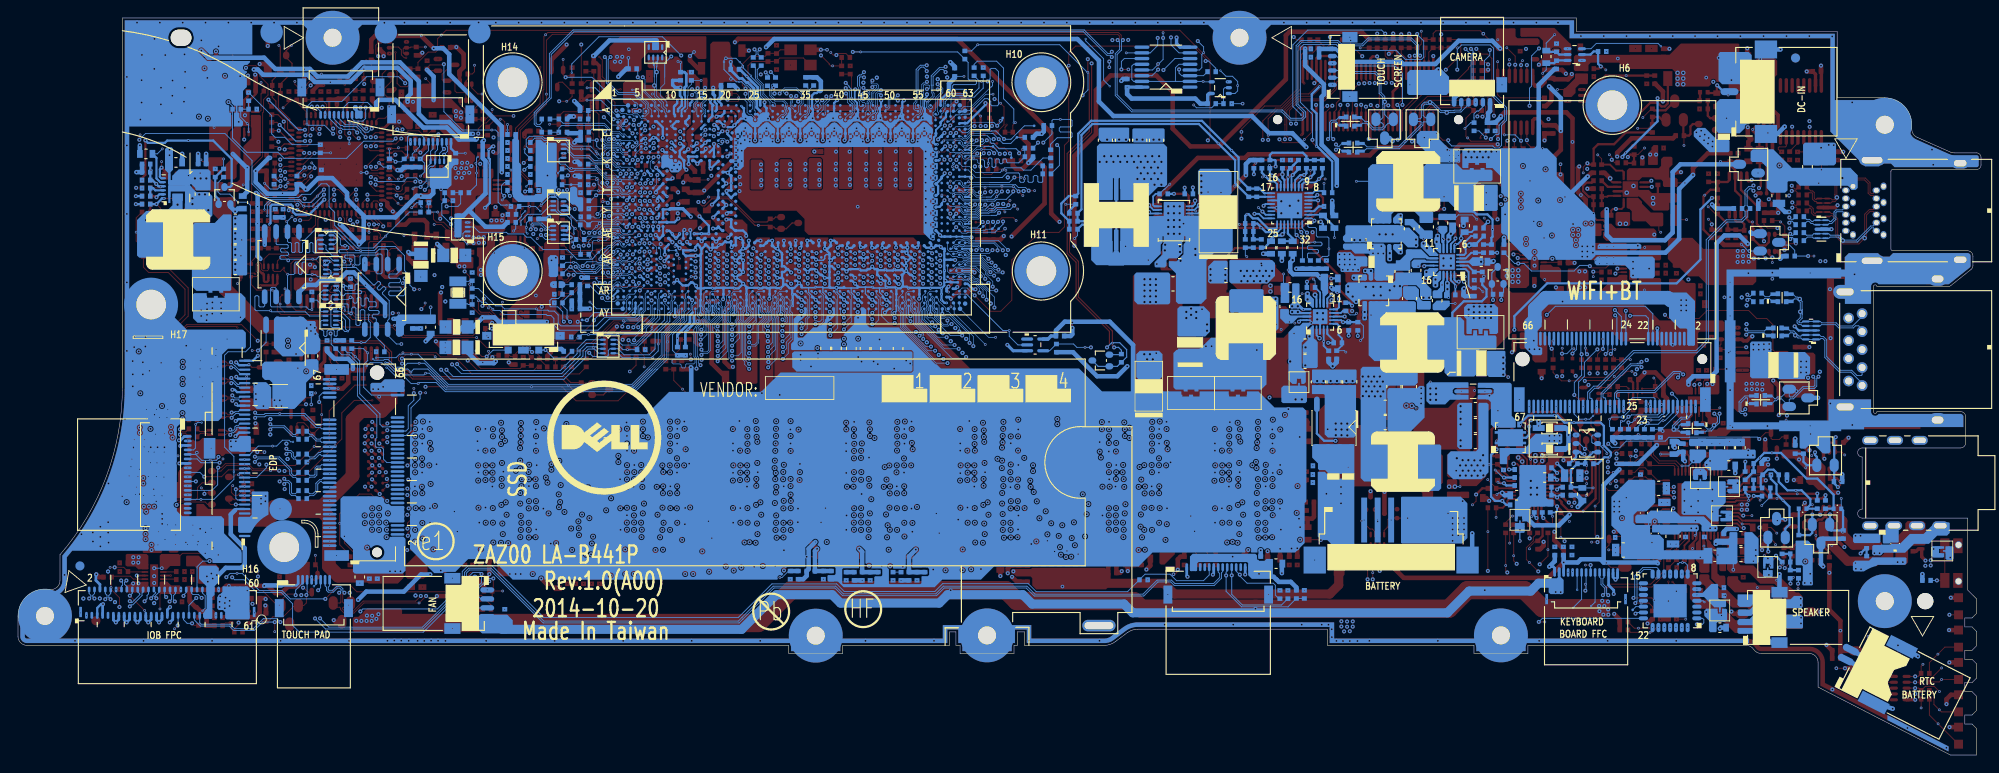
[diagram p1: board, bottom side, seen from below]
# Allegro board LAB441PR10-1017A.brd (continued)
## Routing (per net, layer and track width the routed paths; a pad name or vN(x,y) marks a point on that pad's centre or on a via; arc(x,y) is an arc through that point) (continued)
RUN_ON: length 4
  TOP w0.102: UE5.B9 187.07,65.74 186.57,65.74 v1(185.35,66.96)
  BOTTOM w0.102: v1(185.35,66.96) 185.31,66.99 R250.2 v2(183.54,66.99)
RUN_ON#: length 3.4
  TOP w0.102: QE12.6 175.39,78.04 175.47,78.12 175.47,78.58 175.35,78.69 QE12.5 174.69,78.69 174.62,78.77 RE84.2 v2(173.01,78.77)
RUN_ON_EC: length 453.9
  TOP w0.102: v1(166.91,65.77) 166.59,65.46 166.59,64.72 U673.16 ; U720.5 40.59,54.52 40.7,54.62 41.29,54.62 41.72,54.19 43.3,54.19 v1(43.5,54.4) ; U719.3 51.34,54.81 v1(51.46,54.69) ; v3(175.15,77.57) 175.35,77.57 175.67,77.89 175.67,78.44 176,78.77 176.93,78.77 QE12.2 ; R1189.2 206.77,31.49 206.42,31.85 206.42,33.79 205.64,34.57 205.64,38.32 R269.1 205.1,44.68 v1(204.88,44.9)
  TOP w0.254: PR411.1 38.8,67.71 v2(39.53,66.99) 39.88,66.63 v1(39.88,66.53)
  GND1 w0.102: v4(175.65,77.69) 175.53,77.57 v3(175.15,77.57) ; v3(174.13,68.53) 174.08,68.48 v4(174.08,68.2)
  IN1 w0.071: v4(183.55,67.91) 183.55,67.9 182.99,67.35 180.13,67.35 180.13,67.35 178.32,67.35 177.72,67.94 174.64,67.94 174.38,68.2 v4(174.08,68.2) 173.87,68.2 173.69,68.02 170.98,68.02 169.41,66.45 167.58,66.45 v1(166.91,65.77)
  IN2 w0.086: v1(204.88,44.9) 201.06,44.9 199.02,46.94 199.02,50.83 196.34,53.51 196.34,67.87 197.2,68.72 197.2,68.73 197.19,68.74 v1(197.19,70.8) 197.19,70.8
  IN2 w0.254: v1(35.97,73.07) 35.97,74.45 39.01,77.49 46.3,77.49 49.21,80.41 59.11,80.41 59.87,79.64 71.14,79.64 71.45,79.33 72.55,79.33 73.2,79.97 75.1,79.97 77.84,77.23 83.77,77.23 87.14,80.6 165.81,80.6 168.55,77.87 172.24,77.87 173.72,79.35 177,79.35 177.91,78.44 179.82,78.44 181.88,76.38 189.61,76.38 191.71,74.28 v4(193.25,74.28) 193.25,72.74 194.47,71.52 196.47,71.52 197.19,70.8 197.19,70.8
  IN3 w0.086: v4(175.65,77.69) 176.15,77.18 176.15,71.93 174.08,69.86 v4(174.08,68.2) ; 151.24,76.67 152.14,76.67 152.25,76.77 158.86,76.77 160.19,75.44 160.19,73.19 163.61,69.77 165.03,69.77 165.84,68.96 165.84,68.4 165.66,68.22 165.16,68.22 164.96,68.03 164.96,66.86 165.51,66.31 166.5,66.31 166.91,65.91 v1(166.91,65.77)
  IN3 w0.102: v1(43.5,54.4) 43.7,54.6 44.39,54.6 45.75,55.96 45.75,65.79 44.84,66.7 44.84,75.63 46.47,77.27 56.21,77.27 56.84,76.63 64.48,76.63 65.37,77.52 65.37,78.15 65.65,78.43 70.53,78.43 70.94,78.02 79.58,78.02 81.81,75.79 92.51,75.79 93.38,76.67 97.84,76.67 100.98,79.81 136.5,79.81 138.04,78.27 149.63,78.27 151.24,76.67
  GND3 w0.102: v4(193.25,74.28) 192.68,73.71 v5(192.66,73.71) ; v4(183.55,67.91) v5(184.69,67.91)
  BOTTOM w0.102: v5(192.66,73.71) 190.1,71.15 190.1,69.11 189.72,68.73 188.64,68.73 187.82,67.91 v5(184.69,67.91) ; v1(43.5,54.4) 43.58,54.47 44.63,54.47 45.25,53.85 49.99,53.85 50.83,54.69 v1(51.46,54.69) 51.86,54.69 R290.2
  BOTTOM w0.254: v1(35.97,73.07) 35.97,70.51 39.88,66.59 v1(39.88,66.53)
RUNPWROK: length 117.6
  TOP w0.102: v1(182.48,69.33) 182.47,69.34 182.47,70.34 UE5.B26 ; QE12.3 177.58,79.34 177.64,79.4 RE83.2 178.52,78.97 178.52,78.02 v1(178.25,77.75)
  IN3 w0.086: v4(85.27,76.41) 85.6,76.74 86.53,76.74 86.84,77.05 94.29,77.05 95.99,78.75 99.42,78.75 100.68,80.01 136.58,80.01 138.12,78.47 152.76,78.47 153.45,77.78 153.45,77.3 153.78,76.97 158.53,76.97 160.16,78.6 168.38,78.6 169.01,79.22 176.78,79.22 v1(178.25,77.75) 180.66,75.34 181.32,75.34 182.11,74.55 182.11,73.75 182.57,73.29 182.57,69.42 v1(182.48,69.33)
  GND3 w0.102: v4(85.27,76.41) 84.94,76.41 84.68,76.15 v5(84.6,76.15)
  BOTTOM w0.102: v5(84.6,76.15) 83.96,75.52 83.25,75.52 82.67,74.93 v2(82.67,74.48) 82.67,73.89 82.96,73.6 U697.1
SATA2_PCIE6_L1: length 27
  TOP w0.102: RH467.1 161.64,66.3 v1(162.06,65.88)
  IN2 w0.086: v4(166.36,65.85) 166.28,65.93 164.25,65.93 164.18,66 162.18,66 v1(162.06,65.88) 161.79,65.88 161.16,65.25 157.5,65.25 157.32,65.07 155.16,65.07 154.45,64.35
  IN2 w0.089: 154.45,64.35 151.95,64.35 151.48,63.88 149.99,63.88 149.16,63.04 148.25,63.04 148,62.79 v1(148,62.58)
  GND3 w0.102: v5(167.19,66.54) 167.02,66.54 166.36,65.88 v4(166.36,65.85)
  BOTTOM w0.076: v1(148,62.58) 148,62.45 UCPU1.V6
  BOTTOM w0.102: v5(167.19,66.54) 167.31,66.41 v2(167.31,64.75) 167.31,63.41 R1021.1
SATA_RCOMP: length 6.8
  BOTTOM w0.102: v2(144.62,77.07) RH43.1
  BOTTOM w0.203: 144.17,73.44 144.11,73.38 144.11,72.15 144.51,71.76 144.51,71.1 UCPU1.C12
  BOTTOM w0.305: 144.17,73.44 144.17,74.26 143.98,74.45 143.98,75.77 144.19,75.97 RH43.1
SATA_RN2/PERN6_L1: length 97.7
  IN4 w0.071: v1(147.6,67.53) 147.6,67.66 147.69,67.74 147.98,67.74 148.11,67.87 148.11,70.77 148.44,71.09 149.53,71.09 149.76,71.32 151.21,71.32 151.35,71.19 152.06,71.19 152.2,71.32 153.36,71.32 154.2,70.49 156.66,70.49 156.9,70.73 161.23,70.73 161.52,70.44 165.28,70.44 168.95,74.1 181.35,74.1 181.46,73.99 188.43,73.99 191.95,70.47 191.95,65.57 192.3,65.22 192.3,52.47 192.04,52.21 192.04,43.13 190.15,41.25 190.15,39.1 189.96,38.92 189.96,38.38 189.55,37.97 189.55,33.4 188.09,31.93 188.09,30.55 188.26,30.37 188.48,30.37 v1(188.7,30.15)
  BOTTOM w0.076: v1(147.6,67.53) 148.04,67.09 UCPU1.J6
  BOTTOM w0.102: CS60.1 187.45,28.87 187.88,28.87 188.1,29.09 188.1,30.14 188.31,30.35 188.5,30.35 v1(188.7,30.15)
SATA_RN2/PERN6_L1_C: length 3.9
  BOTTOM w0.102: JNGFF3.29 184.44,30.29 184.56,30.42 184.69,30.42 184.98,30.14 184.98,29.31 185.43,28.86 185.87,28.86 CS60.2
SATA_RN3/PERN6_L0: length 87.3
  IN4 w0.071: v1(188.46,34.08) 188.46,33.97 188.58,33.85 188.82,33.85 188.89,33.92 188.89,37.29 188.51,37.67 188.51,42.14 191.11,44.74 191.11,53.05 190.69,53.47 190.69,57.4 191.21,57.92 191.21,59.39 191.29,59.47 191.29,69.91 187.87,73.33 181.18,73.33 181.07,73.44 169.26,73.44 165.6,69.78 161.24,69.78 160.96,70.06 157.17,70.06 156.93,69.82 150.32,69.82 150.04,69.54 149.12,69.54 148.89,69.78 148.8,69.78 148.56,69.53 v1(148.56,69.51)
  BOTTOM w0.076: UCPU1.F5 149,69.06 v1(148.56,69.51)
  BOTTOM w0.102: CS61.1 187.45,33.14 187.56,33.14 187.69,33.28 187.69,33.62 187.95,33.88 188.26,33.88 v1(188.46,34.08)
SATA_RN3/PERN6_L0_C: length 2.9
  BOTTOM w0.102: CS61.2 185.88,33.16 185.37,33.16 184.88,33.65 184.69,33.65 184.55,33.79 JNGFF3.43
SATA_RP2/PERP6_L1: length 97.5
  IN4 w0.071: v1(147.6,68.09) 147.81,67.88 147.93,67.88 147.98,67.93 147.98,70.82 148.38,71.22 149.47,71.22 149.71,71.46 151.27,71.46 151.41,71.32 152.01,71.32 152.15,71.46 153.42,71.46 154.26,70.62 156.6,70.62 156.85,70.86 161.29,70.86 161.58,70.57 165.23,70.57 168.89,74.24 181.4,74.24 181.52,74.12 188.48,74.12 192.08,70.52 192.08,65.63 192.43,65.28 192.43,52.42 192.17,52.16 192.17,43.08 190.28,41.19 190.28,39.05 190.09,38.86 190.09,38.32 189.68,37.92 189.68,33.34 188.22,31.88 188.22,30.6 188.32,30.51 188.47,30.51 v1(188.7,30.73)
  BOTTOM w0.076: UCPU1.H6 147.67,68.09 v1(147.6,68.09)
  BOTTOM w0.102: CS59.1 187.45,29.07 187.79,29.07 187.9,29.18 187.9,30.23 188.22,30.56 188.54,30.56 188.54,30.57 v1(188.7,30.73)
SATA_RP2/PERP6_L1_C: length 3.9
  BOTTOM w0.102: JNGFF3.31 184.4,30.79 184.56,30.63 184.78,30.63 185.18,30.22 185.18,29.4 185.51,29.07 185.85,29.07 CS59.2
SATA_RP3/PERP6_L0: length 87.5
  IN4 w0.071: v1(188.46,33.5) 188.68,33.71 188.87,33.71 189.02,33.86 189.02,37.34 188.64,37.72 188.64,42.09 191.24,44.69 191.24,53.11 190.82,53.53 190.82,57.35 191.34,57.87 191.34,59.34 191.42,59.41 191.42,69.96 187.92,73.46 181.24,73.46 181.12,73.58 169.21,73.58 165.55,69.91 161.3,69.91 161.01,70.19 157.12,70.19 156.88,69.95 150.26,69.95 149.98,69.67 149.18,69.67 148.94,69.91 148.73,69.91 v1(148.58,70.05)
  BOTTOM w0.076: UCPU1.E5 148.98,69.66 v1(148.58,70.05)
  BOTTOM w0.102: CS62.1 187.45,32.93 187.64,32.93 187.9,33.19 187.9,33.53 188.04,33.67 188.29,33.67 v1(188.46,33.5)
SATA_RP3/PERP6_L0_C: length 3
  BOTTOM w0.102: CS62.2 185.84,32.95 185.28,32.95 184.8,33.44 184.69,33.44 184.55,33.29 JNGFF3.41
SATA_TN2/PETN6_L1: length 105.9
  IN4 w0.071: v1(143.35,73.43) 143.35,73.57 143.55,73.77 143.81,73.77 143.95,73.63 143.95,72.56 144.33,72.18 148.07,72.18 148.66,72.77 154.03,72.77 154.68,72.12 161.72,72.12 162.08,71.76 164.6,71.76 168.26,75.42 174.22,75.42 174.63,75.83 189.02,75.83 194.13,70.72 194.13,70.04 193.62,69.52 193.62,46.22 193.36,45.96 193.36,40.45 191.28,38.37 191.28,34.87 191.19,34.78 191.19,33.31 191.45,33.06 191.57,33.06 191.97,32.67 v1(191.97,32.6)
  BOTTOM w0.076: v1(143.35,73.43) 143.08,73.69 142.98,73.69 142.89,73.6 142.89,72.73 143.18,72.44 143.18,72.09 143,71.9 143,71.64 143.1,71.54 143.21,71.54 UCPU1.B14
  BOTTOM w0.102: v1(191.97,32.6) 191.62,32.95 189.32,32.95 188.08,31.72 188.08,31.24 187.73,30.89 187.43,30.89 187.11,30.57 CS58.1
SATA_TN2/PETN6_L1_C: length 3.6
  BOTTOM w0.102: JNGFF3.35 184.55,31.79 184.69,31.94 184.97,31.94 185.07,31.84 185.07,31.14 185.3,30.92 185.84,30.92 CS58.2
SATA_TN3/PETN6_L0: length 99.2
  IN4 w0.071: v1(142.33,73.69) 142.53,73.49 142.71,73.49 142.9,73.29 142.9,72.81 143.88,71.83 148.44,71.83 148.83,72.23 153.68,72.23 154.32,71.59 161.5,71.59 161.86,71.23 164.95,71.23 168.62,74.9 174.47,74.9 174.88,75.3 188.79,75.3 192.53,71.57 192.53,71.05 193.09,70.5 193.09,69.58 192.78,69.28 192.78,65.93 193.09,65.62 193.09,46.44 192.83,46.18 192.83,42.77 190.94,40.88 190.94,38.78 190.75,38.59 190.75,36.6 190.59,36.44 190.47,36.44 v1(190.25,36.22)
  BOTTOM w0.076: UCPU1.C17 141.91,71.31 141.83,71.39 141.83,71.8 142.2,72.17 142.2,72.41 141.77,72.84 141.77,73.31 141.95,73.49 142.14,73.49 v1(142.33,73.69)
  BOTTOM w0.102: v1(190.25,36.22) 190.05,36.42 188.75,36.42 187.79,35.45 187.44,35.45 187.12,35.13 CS43.1
SATA_TN3/PETN6_L0_C: length 3
  BOTTOM w0.102: CS43.2 185.85,35.47 185.69,35.47 185.15,34.94 184.69,34.94 184.55,34.79 JNGFF3.47
SATA_TP2/PETP6_L1: length 105.9
  IN4 w0.071: v1(143.35,74.08) 143.52,73.9 143.86,73.9 144.08,73.69 144.08,72.62 144.38,72.32 148.02,72.32 148.6,72.9 154.09,72.9 154.73,72.25 161.78,72.25 162.14,71.89 164.55,71.89 168.21,75.56 174.17,75.56 174.57,75.97 189.08,75.97 194.26,70.78 194.26,69.98 193.75,69.47 193.75,46.16 193.49,45.9 193.49,40.39 191.41,38.31 191.41,34.81 191.32,34.72 191.32,33.37 191.5,33.19 v1(191.97,33.19)
  BOTTOM w0.076: v1(143.35,74.08) 143.15,73.87 142.91,73.87 142.71,73.68 142.71,72.66 143,72.36 143,72.16 142.82,71.98 142.82,71.22 UCPU1.C15
  BOTTOM w0.102: CS57.1 187.46,31.1 187.65,31.1 187.88,31.33 187.88,31.81 189.23,33.16 191.94,33.16 v1(191.97,33.19)
SATA_TP2/PETP6_L1_C: length 3.6
  BOTTOM w0.102: CS57.2 185.88,31.12 185.39,31.12 185.28,31.23 185.28,31.93 185.06,32.15 184.69,32.15 184.55,32.29 JNGFF3.37
SATA_TP3/PETP6_L0: length 99.2
  IN4 w0.071: v1(142.33,73.1) 142.59,73.36 142.65,73.36 142.77,73.24 142.77,72.76 143.83,71.7 148.49,71.7 148.89,72.09 153.63,72.09 154.26,71.46 161.44,71.46 161.8,71.1 165.01,71.1 168.67,74.76 174.52,74.76 174.93,75.17 188.74,75.17 192.4,71.51 192.4,71 192.96,70.44 192.96,69.64 192.65,69.33 192.65,65.87 192.96,65.57 192.96,46.49 192.7,46.23 192.7,42.82 190.81,40.93 190.81,38.83 190.62,38.64 190.62,36.65 190.54,36.57 190.49,36.57 v1(190.25,36.81)
  BOTTOM w0.076: v1(142.33,73.1) 142.13,73.31 142.03,73.31 141.95,73.23 141.95,72.91 142.38,72.48 142.38,72.39 142.38,72.09 142.01,71.72 142.01,71.46 142.29,71.19 UCPU1.D17
  BOTTOM w0.102: v1(190.25,36.81) 190.07,36.63 188.67,36.63 187.7,35.66 187.47,35.66 CS42.1
SATA_TP3/PETP6_L0_C: length 3
  BOTTOM w0.102: JNGFF3.49 184.55,35.29 184.69,35.15 185.07,35.15 185.6,35.68 185.86,35.68 CS42.2
SDIO_CLK: length 173.5
  TOP w0.089: v1(149.97,69.17) 150.51,69.71 CH1246.1
  IN2 w0.086: v1(149.97,69.17) 150.54,69.74 151.96,69.74 152.62,70.4 152.62,70.98 152.38,71.22 152.38,71.84 150.98,73.24 148.23,73.24 146.83,74.64 137.31,74.64 136.64,73.97 135.6,73.97 134.14,72.5 132.2,72.5 131.72,72.02 131,72.02 129.29,73.72 127.86,73.72 125.74,75.83 125.58,75.83 123.52,77.9 102.1,77.9 98.98,74.78 96.51,74.78 95.41,73.69 60.28,73.69 59.57,72.97 54.88,72.97 53.87,73.99 52.02,73.99 50.75,75.26 45.14,75.26 44.57,75.83 38.84,75.83 37.15,74.14 37.15,71.04 32.97,66.87 32.97,51.34 32.36,50.73 32.36,48.31 35.3,45.37 35.3,41.13 v1(34.37,40.2)
  BOTTOM w0.076: v1(149.97,69.17) 150.3,69.5 UCPU1.E3
  BOTTOM w0.102: R1360.2 R1395.2 35.5,36.25 33.75,38 JNGFF1.9 33.75,39.58 v1(34.37,40.2)
SDIO_CMD: length 174
  IN2 w0.086: v1(37.08,36.92) 35.69,38.3 35.69,45.54 33.77,47.46 33.77,67.06 37.54,70.82 37.54,73.98 39,75.44 44.41,75.44 44.98,74.87 50.59,74.87 51.86,73.6 53.7,73.6 54.72,72.58 59.73,72.58 60.44,73.29 95.88,73.29 96.4,73.81 100.17,73.81 102.1,71.89 105.96,71.89 108.06,73.98 114.31,73.98 116.02,72.27 130.51,72.27 130.93,71.85 131.78,71.85 132.27,72.34 134.21,72.34 134.89,73.03 135.41,73.03 136.08,72.35 141.23,72.35 141.89,71.69 148.42,71.69 149.13,72.4 151.57,72.4 152.2,71.77 152.2,71.15 152.44,70.91 152.44,70.55 151.95,70.05 150.32,70.05 149.6,69.33 149.6,68.05 v1(149.95,67.7)
  BOTTOM w0.076: v1(149.95,67.7) 149.65,67.7 149.36,67.99 149.36,68.25 149.65,68.55 UCPU1.F4
  BOTTOM w0.102: R1361.2 37.43,36.56 v1(37.08,36.92) 36.96,36.8 35.9,36.8 35.48,37.22 v2(35.35,37.22) 35.14,37.22 34.25,38.11 34.25,38.77 JNGFF1.11
SDIO_D0: length 168
  IN2 w0.086: v1(152.07,70.74) 151.57,71.25 148.81,71.25 148.54,71.52 141.8,71.52 141.14,72.18 132.36,72.18 131.86,71.68 130.85,71.68 130.43,72.1 115.86,72.1 114.21,73.75 108.16,73.75 106.06,71.65 101.35,71.65 99.99,73 60.57,73 59.86,72.29 54.64,72.29 53.57,73.36 48.92,73.36 44.9,69.34 36.39,69.34 34.03,66.98 34.03,47.57 36.07,45.53 36.07,38.62 v1(37.76,36.93)
  BOTTOM w0.076: 153.27,71.71 153.04,71.71 v1(152.07,70.74) 151.43,70.74 151.25,70.56 151.25,70.11 151.06,69.92 150.63,69.92 UCPU1.D3
  BOTTOM w0.102: R1362.2 38.32,36.37 v1(37.76,36.93) 37.36,37.34 36.79,37.34 v2(36.72,37.27) 35.79,37.27 35.41,37.66 35.13,37.66 34.75,38.04 34.75,38.77 JNGFF1.13 ; RH435.1 RH434.2 153.27,71.71
SDIO_D1: length 163
  IN2 w0.086: v1(149.85,70.11) 150.17,70.42 150.17,70.87 149.97,71.07 148.74,71.07 148.47,71.34 141.72,71.34 141.06,72 132.44,72 131.94,71.5 130.78,71.5 130.36,71.92 114.24,71.92 112.69,73.48 110.1,73.48 ; v1(39.21,37) 38.83,37.38 38.83,45.78 38.26,46.35 35.59,46.35 34.27,47.67 34.27,66.88 36.49,69.1 45,69.1 49.02,73.12 53.47,73.12 54.59,72 62.6,72 63.31,72.71 99.95,72.71 101.25,71.41 106.16,71.41 108.23,73.48 110.07,73.48
  IN2 w0.089: 110.1,73.48 110.07,73.48
  BOTTOM w0.076: UCPU1.E4 149.65,69.91 v1(149.85,70.11)
  BOTTOM w0.102: JNGFF1.15 35.25,38.01 35.35,37.91 35.51,37.91 35.83,37.59 38.2,37.59 v2(38.51,37.29) 38.8,37 v1(39.21,37) R1363.2
SDIO_D2: length 160
  IN2 w0.086: 113.29,72.62 114.19,71.72 130.31,71.72 130.7,71.32 132.01,71.32 132.51,71.83 140.95,71.83 141.62,71.16 148.28,71.16 148.78,70.65 v1(149.8,70.65) ; v1(39.21,37.63) 39.15,37.69 39.15,45.96 38.52,46.59 35.74,46.59 34.51,47.82 34.51,66.78 36.59,68.86 45.1,68.86 47.68,71.44 52.82,71.44 53.14,71.76 80.79,71.76 81.49,72.46 99.86,72.46 101.15,71.17 106.26,71.17 107.52,72.43 109.99,72.43 110.07,72.51
  IN2 w0.089: 113.29,72.62 112.88,73.03 110.58,73.03 110.07,72.51
  BOTTOM w0.076: UCPU1.C3 150.18,70.97 149.86,70.65 v1(149.8,70.65)
  BOTTOM w0.102: JNGFF1.17 35.75,38.05 35.96,37.85 38.87,37.85 39.08,37.63 v1(39.21,37.63) 39.7,37.14 v2(39.99,37.14) 40.1,37.03 R1364.2
SDIO_D3: length 172.3
  IN2 w0.086: 110.43,72.18 110.5,72.11 113.26,72.11 113.86,71.52 130.26,71.52 130.63,71.14 132.08,71.14 132.59,71.65 140.88,71.65 141.55,70.98 147.68,70.98 148.18,70.49 148.18,69.2 148.34,69.04 148.65,69.04 148.94,68.75 148.94,68.16 149.8,67.3 151.23,67.3 151.54,67.61 151.54,69.06 153.15,70.68 v1(153.15,70.97)
  IN2 w0.102: v1(39.81,37.61) 39.4,38.02 39.4,46.06 38.63,46.83 35.84,46.83 34.76,47.92 34.76,66.68 36.67,68.59 45.18,68.59 47.78,71.19 52.93,71.19 53.24,71.51 80.89,71.51 81.56,72.18 99.79,72.18 101.05,70.92 106.36,70.92 107.62,72.18 110.43,72.18
  BOTTOM w0.076: v1(153.15,70.97) 152.27,70.09 151.47,70.09 150.95,69.58 UCPU1.E2
  BOTTOM w0.102: 39.81,37.6 39.09,38.31 39.09,39.43 38.77,39.76 36.37,39.76 36.25,39.64 JNGFF1.19 ; 39.81,37.6 41.06,37.6 v2(41.31,37.36) 41.31,36.56 R1365.2 ; 39.81,37.6 v1(39.81,37.61)
SDIO_RST#: length 5.5
  TOP w0.102: U679.D1 36.47,40.76 v3(36.24,41) 36.24,41.79 v2(36.39,41.94)
  GND1 w0.102: v4(36.81,40.83) 36.41,40.83 v3(36.24,41)
  IN4 w0.071: v4(37.29,39.14) 37.29,40.34 v4(36.81,40.83)
  GND3 w0.102: v5(37.25,38.77) 37.25,39.11 37.29,39.15 v4(37.29,39.14)
SDIO_RST#_R: length 2.2
  TOP w0.102: R1313.2 R1314.2 39.43,41 U679.A1
SDIO_WAKE#: length 152.1
  TOP w0.089: v1(149.94,66.21) 150.39,65.77 v2(151.53,65.77) 151.57,65.77 151.69,65.9 153.96,65.9
  TOP w0.102: 153.96,65.9 154.16,65.9 RH397.2
  GND1 w0.102: v4(41.58,39.67) 41.32,39.4 v3(41.32,39.22)
  IN2 w0.086: v4(41.58,39.67) 41.58,40.97 40.77,41.78 40.77,47.5 43.41,50.15 46.73,50.15 47.85,51.26 v4(47.85,52.15)
  IN3 w0.086: v1(149.94,66.21) 149.94,66.41 149.24,67.11 149.24,68.42 148.7,68.96 148.2,68.96 147.92,69.24 147.45,69.24 147.01,69.69 147.01,70.52 145.99,71.54 141.79,71.54 141.56,71.77 132.34,71.77 131.84,71.27 130.71,71.27 130.38,71.6 107.95,71.6 106.51,70.16 102.29,70.16 100.39,72.06 80.86,72.06 79.14,73.78 58.98,73.78 58.08,72.88 53.85,72.88 52.36,71.39 51.4,71.39 50.91,70.9 50.23,70.9 47.79,68.46 47.79,59.37 48.98,58.18 48.98,53.28 v4(47.85,52.15)
  BOTTOM w0.076: UCPU1.L3 150.3,65.85 v1(149.94,66.21)
SDIO_WAKE#_Q: length 5.1
  TOP w0.102: U679.D2 37.68,40.27 36.47,40.27 v3(36.24,40.04) 36.23,40.04 35.51,39.33 v2(35.51,39)
  GND1 w0.102: v4(36.84,40.27) 36.46,40.27 v3(36.24,40.04)
  IN4 w0.071: v4(36.75,39.12) 36.75,40.18 v4(36.84,40.27)
  GND3 w0.102: v5(36.75,38.77) v4(36.75,39.12)
SDIO_WAKE#_R: length 3.7
  TOP w0.102: U679.A2 39.19,38.75 v2(39.68,38.26) 40.07,38.26 40.4,38.59 R1199.2
SIO_EXT_SCI#: length 39.7
  TOP w0.102: v1(175.55,69.6) 175.94,69.99 176.3,69.99 176.8,69.49 176.92,69.49 UE5.A33
  IN1 w0.071: v1(162,65.12) 161.72,65.12 160.92,65.92 159.05,65.92 158.23,66.75 154.61,66.75 153.76,65.9 152.4,65.9 151.74,65.24 149.98,65.24 v1(149.42,64.68)
  IN2 w0.086: v1(162,65.12) 162,65.11 162.95,64.16 164.11,64.16 165.97,62.31 171.85,62.31 172.54,61.62 173.36,61.62 v4(173.69,61.29)
  IN4 w0.071: v1(175.55,69.6) 175.05,69.1 175.05,62.66 v4(173.69,61.29)
  BOTTOM w0.076: UCPU1.N5 149.12,64.99 v1(149.42,64.68)
  BOTTOM w0.102: RH383.1 161.63,65.48 v1(162,65.12)
SIO_EXT_SMI#: length 53.2
  TOP w0.089: v1(149.19,56.92) 149.88,57.61 151.02,57.61 151.76,56.87 154.41,56.87 154.58,57.03 155.05,57.03 v1(155.4,56.68) 155.4,56.97 155.46,57.03
  TOP w0.102: 155.46,57.03 156.01,57.59 156.01,58.27 v2(156.33,58.58) 157.26,59.51 RH3536.1
  GND1 w0.102: v3(187.92,64.49) 187.46,64.49 187.06,64.09 v4(186.94,64.09)
  IN1 w0.071: v4(187.52,58.69) 187.3,58.46 180.73,58.46 180.52,58.67 178.64,58.67 178.4,58.42 176.61,58.42 176.15,57.97 170.46,57.97 169.86,58.57 168.68,58.57 168.17,59.08 164.02,59.08 163.86,59.24 158.34,59.24 157.13,58.03 156.75,58.03 155.46,56.74
  IN1 w0.086: v1(155.4,56.68) 155.46,56.74
  IN4 w0.071: v4(186.94,64.09) 186.94,61.88 186.49,61.43 186.49,59.36 187.16,58.69 v4(187.52,58.69)
  BOTTOM w0.076: UCPU1.AG5 148.97,57.15 v1(149.19,56.92)
SIO_EXT_WAKE#: length 67.5
  TOP w0.102: UE5.B5 186.74,63.74 186.41,64.06 186.28,64.06 186.08,64.26 186.08,64.54 v1(185.32,65.3)
  IN1 w0.071: v4(187.78,49.45) 187.22,50.01 182.35,50.01 182.09,50.27 180.83,50.27 180.39,49.83 178.97,49.83 178.41,49.26 178.41,48.44 176.9,46.93 175.73,46.93 173.94,45.13 167.02,45.13 166.32,45.83 163.76,45.83 160.38,49.21 160.06,49.21 158.2,51.08 154.39,51.08
  IN1 w0.076: v1(152.73,50.87) 152.73,50.89 153.13,51.29 153.95,51.29 154.16,51.08 154.39,51.08
  IN2 w0.086: v1(185.32,65.3) 185.32,59.36 183.93,57.96 183.93,55.89 184.24,55.58 184.24,52.75 187.54,49.45 v4(187.78,49.45)
  BOTTOM w0.076: UCPU1.AU2 151.27,51.95 151.88,51.95 152.73,51.1 v1(152.73,50.87)
  BOTTOM w0.102: v2(185.64,65.87) 185.32,65.55 v1(185.32,65.3) ; RH3537.1 154.66,52.19 153.75,51.28 153.14,51.28 v1(152.73,50.87)
SIO_PWRBTN#: length 158.5
  TOP w0.102: UE5.B58 181.47,61.14 181.47,62.15 v1(180.71,62.9) ; RH444.2 v1(66.26,80.25) ; T281.1 148.1,56.01 v1(148.07,56.01)
  IN1 w0.071: v4(181.83,53.29) 181.67,53.29 181.08,52.7 180.73,52.7 179.61,51.59 178.22,51.59 177.99,51.36 176.05,51.36 173.57,48.88 172.6,48.88 172.47,49.01 170.57,49.01 170.32,49.26 166.37,49.26 166.36,49.26 165.95,49.68 165.27,50.36 161.87,50.36 159.21,53.02 156.34,53.02 155.66,53.7 154.53,53.7 154.11,53.28 151.16,53.28 150.66,53.79 149.04,53.79 148.81,54.02 148.81,55.08 148.07,55.83 v1(148.07,56.01)
  IN2 w0.086: v4(181.83,53.29) 181.83,53.65 181.17,54.31 181.17,57.42 181.4,57.65 181.4,58.85 181.73,59.18 181.73,60.28 181.22,60.79 181.22,62.4 v1(180.71,62.9)
  IN3 w0.086: v4(75.61,70.83) 75.78,71 76.38,71 76.96,71.58 78.95,71.58 80.66,69.86 98.7,69.86 101.58,66.98 106.07,66.98 107.23,68.14 109.96,68.14 110.07,68.24
  IN3 w0.089: 110.07,68.24 110.19,68.37 110.19,68.63 110.39,68.84 112.64,68.84 113.17,68.3 115.4,68.3 116.01,67.69 136.48,67.69 137.48,66.69 138.65,66.69 139.04,67.08 140.11,67.08 143.37,63.82 143.37,61.43 142.92,60.97 142.92,59.66 143.26,59.31 144.02,59.31 144.37,58.96 145.49,58.96 148.07,56.38 v1(148.07,56.01)
  GND3 w0.102: v4(75.61,70.83) v5(75.61,71.24)
  BOTTOM w0.076: v1(148.07,56.01) 148.07,55.71 UCPU1.AL7
  BOTTOM w0.102: v1(66.26,80.25) 66.66,80.65 74.88,80.65 76.54,79 76.54,72.16 v5(75.61,71.24)
SIO_RCIN#: length 50.6
  GND1 w0.102: v4(181.84,70.97) 181.44,70.97 181.22,71.19 v3(181.22,71.19)
  IN1 w0.071: v1(164.23,62.21) 166.39,62.21 168.3,60.29 171.72,60.29 173.23,58.78 176.2,58.78 177.19,59.76 178.52,59.76 178.73,59.97 180.71,59.97 181.07,60.34 182.24,60.34 v4(182.49,60.59)
  IN2 w0.086: v1(149.93,61.72) 150.29,62.08 151.12,62.08 151.88,62.84 154.54,62.84 155.18,63.48 158.29,63.48 158.41,63.37 162.48,63.37 162.9,62.94 163.49,62.94 v1(164.23,62.21)
  IN3 w0.086: v4(182.49,60.59) 182.68,60.78 182.68,62 182.07,62.61 182.07,70.04 181.84,70.27 v4(181.84,70.97)
  BOTTOM w0.076: UCPU1.V4 149.65,61.99 v1(149.93,61.72)
  BOTTOM w0.102: v2(164.46,61.76) 164.23,61.99 v1(164.23,62.21) 164.53,62.51 164.53,63.37 164.2,63.7 RH196.1
SIO_SLP_A#: length 95.2
  TOP w0.102: v1(181.47,69.19) 181.47,70.34 UE5.B28 ; UC6.1 172.21,60.39 172.1,60.28 172.1,59.62 171.76,59.28 170.97,59.28 170.3,58.61 169.96,58.61 169.38,58.04 169.38,57.57 v3(169.22,57.41) ; v2(195.51,32.94) 195.51,32.9 v1(195.89,32.52)
  GND1 w0.102: v4(169.67,57.47) 169.29,57.47 v3(169.22,57.41)
  IN1 w0.071: v4(182.28,55.98) 181.78,56.48 181.44,56.48 181.41,56.46 178.39,56.46 178.14,56.71 178.14,57.28 177.86,57.55 176.88,57.55 176.55,57.23 169.92,57.23 v4(169.67,57.47) 169.34,57.8 168.36,57.8 167.9,58.26 164.03,58.26 163.44,57.67 161.84,57.67 160.38,56.2 156.94,56.2 156.57,55.84 155.46,55.84
  IN1 w0.086: v1(148.63,56.01) 149.03,56.4 150.83,56.4 151.1,56.67 152.02,56.67 152.18,56.51 153.41,56.51 154.08,55.84 155.46,55.84
  IN2 w0.086: v1(195.89,32.52) 196.08,32.52 196.41,32.85 196.41,36.01 195.55,36.87 195.55,44.01 194.62,44.94 193.13,44.94 192.37,45.71 190.2,45.71 185.9,50.01 184.62,50.01 182.91,51.72 182.91,55.35 v4(182.28,55.98) 182.91,56.61 182.91,61.18 182.55,61.54 182.55,67.77 181.85,68.48 181.85,68.81 v1(181.47,69.19)
  BOTTOM w0.076: UCPU1.AL5 148.7,55.94 v1(148.63,56.01)
  BOTTOM w0.102: JAPS.6 198.38,32.94 197.96,32.52 v1(195.89,32.52)
SIO_SLP_S3#: length 347.3
  TOP w0.102: 176.31,68.59 176.41,68.49 UE5.A35 ; 176.31,68.59 v1(176.31,68.59) ; 176.31,68.59 176.31,68.68 175.99,69 175.51,69 R249.2 ; v2(41.33,66.79) 41.06,66.52 v1(41.06,66.23) 40.72,65.88 40.43,65.88 PR405.1
  IN1 w0.102: v4(193.88,31.23) 190.3,31.23 189.26,32.27 185.3,32.27 v4(185.04,32.53)
  IN2 w0.086: v1(149.9,52.68) 151.32,54.1 153.63,54.1 153.78,53.95 155.44,53.95 156.4,52.99 158.79,52.99 161.94,49.84 166.12,49.84 166.61,49.35 170.48,49.35 170.59,49.46 172.57,49.46 173.3,50.19 v4(173.47,50.19) 173.83,49.83 173.83,47.26 173.56,46.99 173.56,42.48 177.7,38.34 180.97,38.34 183.3,36.01 183.3,34.24 185.02,32.53 v4(185.04,32.53)
  IN2 w0.102: v4(71.15,70.13) 70.95,69.94 58.49,69.94 58.05,69.49 53.57,69.49 52.96,68.88 50.39,68.88 47.74,66.23 v1(41.06,66.23)
  IN3 w0.102: v1(176.31,68.59) 175.82,68.11 175.82,65.7 175.15,65.03 175.15,61.7 175.58,61.27 175.58,54.35 174.63,53.4 174.63,51.34 v4(173.47,50.19) ; v4(71.15,70.13) 71.01,69.99 71.01,58.5 72.23,57.28 72.23,54.05 70.9,52.72 70.9,49.6 70.31,49.01 70.31,47.63 v1(69.31,46.62) ; v1(194.9,72.64) 194.84,72.7 194.84,75.33 192.23,77.94 185.43,77.94 184.62,77.13 182.65,77.13 179.4,80.37 176.55,80.37 176.32,80.6 86.87,80.6 83.45,77.18 81.39,77.18 79.98,78.6 71.44,78.6 70.87,79.17 65.13,79.17 64.72,78.75 64.72,77.79 64.21,77.29 57.11,77.29 56.48,77.92 46.2,77.92 44.14,75.86 44.14,67.59 43.27,66.71 41.55,66.71 v1(41.06,66.23)
  IN4 w0.102: v4(199.2,35.33) 197.37,35.33 195.52,33.49 195.52,32.87 v4(193.88,31.23)
  GND3 w0.102: v5(199.43,34.94) 199.43,35.16 199.25,35.33 v4(199.2,35.33)
  BOTTOM w0.102: v1(149.9,52.68) 149.89,52.68 149.65,52.44 UCPU1.AT4 ; PR610.2 v1(69.31,46.62) ; v1(194.9,72.64) 194.45,72.19 PR400.1 194.45,68.63 192.88,67.06 189.39,67.06 188.71,66.38 181.77,66.38 179.86,68.29 176.61,68.29 176.31,68.59 v1(176.31,68.59)
SIO_SLP_S4#: length 106.6
  TOP w0.102: v3(177.8,74.7) 177.8,75.77 177.27,76.3 176.45,76.3 176.15,76.01 176.15,74.72 175.79,74.36 175.01,74.36 174.72,74.65 R252.2 ; v1(196.02,33.17) 196.37,32.81 v2(196.93,32.81) ; v1(179.08,68.73) 178.58,69.24 177.87,69.24 UE5.B36
  GND1 w0.102: v4(177.4,74.69) 177.79,74.69 v3(177.8,74.7)
  IN1 w0.071: v1(148.65,56.93) 149.01,56.57 150.77,56.57 151.38,57.18 153.12,57.18 154.25,56.05 156.54,56.05 157.04,56.55 160.43,56.55 161.72,57.84 163.37,57.84 163.96,58.43 167.97,58.43 168.41,57.99 169.63,57.99 170.22,57.4 176.41,57.4 176.83,57.82 178.62,57.82 178.74,57.94 v4(180.2,57.94) 180.2,57.94 180.8,57.34 183.75,57.34 183.91,57.18 183.91,55.68 184.14,55.45 184.71,55.45 184.71,55.45 186.87,55.45 187.63,54.69 187.63,52.61 188.77,51.48 188.77,50.91 191.57,48.11 191.57,46.95 193.1,45.42 193.1,44.62 193.59,44.13 194.73,44.13 195.29,43.57 195.29,36.01 195.8,35.51 195.8,33.38 v1(196.02,33.17)
  IN3 w0.086: v1(179.08,68.73) 179.61,69.27 179.96,69.27 180.56,69.86 180.56,71.07 181,71.52 181.2,71.52 181.7,72.02 181.7,72.98 180.88,73.8 177.89,73.8 177.4,74.29 v4(177.4,74.69)
  IN4 w0.071: v4(180.2,57.94) 179.98,58.15 179.98,59.33 179.79,59.51 179.79,61.02 180.05,61.27 180.05,62.11 180.29,62.35 180.29,67.73 179.81,68.22 179.32,68.22 179.08,68.46 v1(179.08,68.73)
  BOTTOM w0.076: UCPU1.AJ6 148.65,56.74 v1(148.65,56.93)
  BOTTOM w0.102: JAPS.5 198.54,33.44 197.88,32.79 196.25,32.79 196.02,33.01 v1(196.02,33.17)
SIO_SLP_S5#: length 98.9
  GND1 w0.102: v3(185.72,71.19) 185.8,71.27 v4(186.22,71.27)
  IN1 w0.071: 155.89,54.83 157.88,54.83 162.02,50.7 165.41,50.7 166.29,49.83 166.29,49.82 166.51,49.6 166.82,49.6 167.21,50 167.21,52.65 167.98,53.41 169.04,53.41 170.84,55.21 178,55.21 178.33,54.88 180.5,54.88 180.95,55.34 183.77,55.34 184,55.1 186.7,55.1 187.28,54.51 187.28,52.21 188.2,51.29 v4(188.21,51.29)
  IN1 w0.086: 155.89,54.83 154.01,54.83 153.27,54.09 151.82,54.09 151.24,54.68 149.85,54.68 149.32,54.14 v1(149.21,54.14)
  IN2 w0.086: v4(197.68,37.69) 197.68,44.79 195.57,46.91 193.85,46.91 189.74,51.02 188.47,51.02 188.21,51.28 v4(188.21,51.29) 188.22,51.29 188.58,51.65 188.84,51.65 189.32,52.12 189.32,54.39 189.17,54.54 189.17,60.93 187.56,62.53 187.56,65.83 187.08,66.32 185.32,66.32 184.92,66.72 184.92,67.51 185.18,67.78 185.18,70.23 v4(186.22,71.27)
  GND3 w0.102: v5(197.87,36.98) 197.87,37.17 197.68,37.36 v4(197.68,37.69)
  BOTTOM w0.076: UCPU1.AP5 148.7,53.63 v1(149.21,54.14)
  BOTTOM w0.102: JAPS.4 198.78,33.94 198.58,34.15 198.58,36.76 v2(198.55,36.79) 198.35,36.98 v5(197.87,36.98)
SIO_SLP_SUS#: length 42.1
  TOP w0.089: v1(152.68,53.69) 153.09,54.09 153.46,54.09 153.88,53.67 v2(154.17,53.67) 154.25,53.67 154.39,53.81
  TOP w0.102: 154.39,53.81 v1(154.96,54.38) ; UE5.B52 178.47,61.14 178.47,60.86 178.28,60.68 177.96,60.68 v1(177.95,60.66)
  IN1 w0.071: v1(154.96,54.38) 155.46,53.88 157.15,53.88 157.32,54.04 158.43,54.04 161.94,50.53 165.34,50.53 166.12,49.75 166.12,49.75 166.43,49.44 166.44,49.43 172.01,49.43 173.23,50.66 174.14,50.66 175.86,52.38 v4(177,52.38)
  IN3 w0.086: v4(177,52.38) 177.68,53.06 177.68,55.5 177.96,55.77 177.96,57.34 177.22,58.08 177.22,59.17 177.95,59.9 v1(177.95,60.66)
  BOTTOM w0.076: v1(152.68,53.69) 152.34,53.34 151.97,53.34 151.77,53.54 151.32,53.54 151.14,53.36 150.47,53.36 150.36,53.47 150.02,53.47 UCPU1.AP4
SIO_SLP_WLAN#: length 54.6
  TOP w0.102: v1(179.53,64.79) 179.48,64.74 UE5.B45
  IN1 w0.071: v4(181.03,52.35) 180.66,52.35 179.72,51.41 178.3,51.41 178.07,51.18 176.13,51.18 173.65,48.71 172.53,48.71 172.4,48.84 170.5,48.84 170.25,49.08 166.3,49.08 166.29,49.09 165.2,50.18 161.8,50.18 159.21,52.78 154.66,52.78 154.31,53.13 151.1,53.13 151.03,53.19 149.71,53.19 149.27,53.63 148.98,53.63 148.66,53.95 148.66,54.75 v1(148.27,55.14)
  IN3 w0.086: v4(180.04,57.24) 180.52,57.24 180.75,57.01 180.75,55.27 180.1,54.62 180.1,53.01 180.76,52.35 v4(181.03,52.35)
  IN4 w0.071: v1(179.53,64.79) 179.87,64.45 179.87,61.34 179.62,61.09 179.62,59.44 179.81,59.25 179.81,57.58 180.07,57.32 180.07,57.27 v4(180.04,57.24)
  BOTTOM w0.076: v1(148.27,55.14) 148.42,55.14 UCPU1.AM5
  BOTTOM w0.102: v1(179.53,64.79) v2(180.17,64.79)
SKIP#: length 24
  TOP w0.254: v1(89.76,62.43) 88.33,62.43 88.12,62.22 88.12,59.95 86.81,58.64 v2(80.15,58.64) 75.59,58.64 73.18,61.05 73.18,61.99 73.5,62.31 v1(73.82,62.31)
  BOTTOM w0.203: v1(73.82,62.31) 74.02,62.1 PU700.7
  BOTTOM w0.254: PR728.2 v1(89.76,62.43)
SKIP#-1: length 4
  BOTTOM w0.102: PR728.1 90.83,62.96 90.77,62.96 v2(90.21,63.51)
  BOTTOM w0.203: PU701.1 91.93,61.05 92.07,61.19 92.07,62.15 91.79,62.43 PR728.1
SLEWA: length 5.2
  TOP w0.102: v1(78.83,64.47) 79.76,64.47 v2(79.91,64.31)
  TOP w0.254: v1(78.83,64.47) 79.09,64.21 PR710.1
  BOTTOM w0.203: PU700.15 77.88,63.77 78.01,63.9
  BOTTOM w0.254: 78.01,63.9 78.58,64.47 v1(78.83,64.47) 79.09,64.72 PR700.2
SLP_S0#: length 6.2
  BOTTOM w0.076: UCPU1.AF3 150.56,58.02 151.08,58.02 151.31,58.26 151.31,58.43 151.47,58.59 152.91,58.59 153.22,58.28 153.22,57.97 153.46,57.73 154.96,57.73 RH463.1
SM_INTRUDER#: length 8.4
  TOP w0.089: v1(149.88,47.59) 150.26,47.21 151.22,47.21 v2(151.6,46.83) 151.6,45.92 151.35,45.67 RH11.2
  BOTTOM w0.076: UCPU1.AU6 148.56,51.31 148.56,50.83 148.53,50.8 148.53,49.43 148.8,49.17 148.8,48.67 v1(149.88,47.59)
SM_PG_CTRL: length 42.7
  TOP w0.102: v1(98.99,45.35) v2(99.64,45.35)
  IN3 w0.086: v1(70.32,46.66) 70.32,43.4 71.68,42.05 78.57,42.05 80.38,40.24 90.37,40.24 95.88,45.75 98.59,45.75 v1(98.99,45.35)
  BOTTOM w0.102: v1(98.99,45.35) 100.55,45.35 100.93,45.73 RC161.2 103.58,44.98 104.29,44.98 UC1.4
  BOTTOM w0.254: PR609.1 v1(70.32,46.66)
SM_RCOMP0: length 2.2
  TOP w0.076: v1(114.83,52.11) v2(114.83,51.5)
  TOP w0.381: RC55.2 114.52,52.42 v1(114.83,52.11)
  BOTTOM w0.305: v1(114.83,52.11) 115.04,51.9 UCPU1.AU60
SM_RCOMP1: length 2.6
  TOP w0.076: v1(114.56,50.77) v2(114.56,49.86)
  TOP w0.381: v1(114.56,50.77) 113.89,51.44 RC58.2
  BOTTOM w0.305: UCPU1.AV60 114.75,50.95 v1(114.56,50.77)
SM_RCOMP2: length 2.5
  TOP w0.076: RC60.2 v2(112.58,52.96)
  TOP w0.381: RC60.2 113.57,52.35 v1(113.85,52.07)
  BOTTOM w0.305: UCPU1.AU61 114.05,51.88 v1(113.85,52.07)
SML0CLK: length 178.3
  TOP w0.102: v1(156.52,53.42) 156.52,53.3 157.2,52.62 157.66,52.62 RH70.1
  IN4 w0.071: v1(184.72,15.21) 184.93,15.42 184.93,17.12 183.94,18.1 183.94,38.58 181.39,41.13 181.39,44.3 179.54,46.15 174.36,46.15 173.87,46.65 173,46.65 172.75,46.41 170.61,46.41 169.16,47.85 168.26,47.85 167.55,48.56 166.73,48.56 165.26,50.03 162.68,50.03 159.65,53.06 156.87,53.06 v1(156.52,53.42) 156.33,53.61 153.85,53.61 153.53,53.29 152.52,53.29 v1(152.11,53.7)
  BOTTOM w0.076: UCPU1.AN1 151.99,53.82 v1(152.11,53.7)
  BOTTOM w0.102: v1(184.72,15.21) 183.73,14.23 173.32,14.23 168.65,18.9 168.65,20.32 168.18,20.79 165.7,20.79 159.81,14.9 138.2,14.9 137.79,15.31 134.32,18.78 127.37,18.78 126.52,17.93 116.24,17.93 115.39,18.78 106.1,18.78 105.21,17.9 93.19,17.9 91.63,19.46 90.03,19.46 89.65,19.08 85.34,19.08 84.67,19.75 84.67,20.2 84.83,20.36 JNFC1.8
SML0DATA: length 180.1
  TOP w0.102: v1(157.08,53.43) 157.08,53.06 157.29,52.85 157.69,52.85 RH72.1
  IN4 w0.071: v1(155.51,54.41) 155.4,54.3 155.4,54 155.59,53.81 156.7,53.81 v1(157.08,53.43) 157.27,53.23 159.72,53.23 162.75,50.2 165.33,50.2 166.8,48.73 167.62,48.73 168.33,48.03 169.23,48.03 170.68,46.58 172.68,46.58 172.92,46.82 173.94,46.82 174.43,46.33 179.61,46.33 181.56,44.37 181.56,41.2 184.11,38.65 184.11,18.18 185.1,17.19 185.1,15.37 v1(185.28,15.2)
  BOTTOM w0.076: UCPU1.AK1 151.6,55.96 151.95,55.62 152.01,55.62 152.84,54.79 153.89,54.79 153.98,54.88 154.39,54.88
  BOTTOM w0.102: v1(155.51,54.41) 155.04,54.88 154.39,54.88 ; JNFC1.9 84.33,20.41 84.47,20.28 84.47,19.67 85.26,18.87 89.73,18.87 90.11,19.25 91.55,19.25 93.11,17.69 105.29,17.69 106.18,18.58 115.31,18.58 116.16,17.73 126.61,17.73 127.46,18.58 134.23,18.58 137.71,15.11 138.12,14.7 159.9,14.7 165.79,20.58 168.09,20.58 168.45,20.23 168.45,18.82 173.24,14.02 184.1,14.02 v1(185.28,15.2)
SML1_SMBCLK: length 50.1
  TOP w0.102: v1(186.47,64.49) 186.48,64.49 186.73,64.24 UE5.B6
  IN1 w0.071: v4(174.15,59.58) 174.33,59.39 176.08,59.39 176.98,60.29 178.31,60.29 178.51,60.49 180.39,60.49 180.82,60.92 181.78,60.92 182.14,61.28 184.88,61.28 186.05,62.44 187.51,62.44 187.72,62.65 187.72,63.79 187.02,64.49 v1(186.47,64.49)
  IN2 w0.086: v1(159.59,57.86) 159.78,57.67 159.78,57.46 160.02,57.23 161.08,57.23 161.83,57.98 164.13,57.98 164.65,58.49 173.56,58.49 173.94,58.87 173.94,59.37 v4(174.15,59.58)
  IN4 w0.071: v1(159.59,57.86) 158.22,56.49 157.22,56.49 156.25,55.51 152.74,55.51 152.34,55.11 151.92,55.11 ; 149.79,53.22 149.25,52.68 v1(149.25,52.52)
  IN4 w0.086: 149.79,53.22 150.92,53.22 151.58,53.87 151.58,54.76 151.92,55.11
  BOTTOM w0.076: UCPU1.AU3 150.29,51.64 149.95,51.98 149.55,51.98 149.25,52.28 v1(149.25,52.52)
  BOTTOM w0.102: RP2.3 159.59,57.87 v1(159.59,57.86)
SML1_SMBDAT: length 48.1
  TOP w0.102: v1(160.15,57.86) 160.15,57.86 v2(160.56,57.45) ; UE5.A5 187.92,63.99 188.46,63.99 v1(188.59,64.11)
  IN1 w0.071: v4(173.54,59.56) 173.88,59.22 176.15,59.22 177.05,60.12 178.38,60.12 178.58,60.32 180.46,60.32 180.89,60.75 181.86,60.75 182.22,61.11 184.96,61.11 186.12,62.27 187.59,62.27 187.9,62.58 187.9,63.42 v1(188.59,64.11)
  IN2 w0.086: v4(173.54,59.56) 173.75,59.35 173.75,58.95 173.48,58.68 164.57,58.68 164.05,58.16 161.75,58.16 161.01,57.42 160.6,57.42 v1(160.15,57.86)
  IN4 w0.071: v1(153.55,55.16) 153.7,55.32 156.44,55.32 157.36,56.24 158.5,56.24 160.12,57.86 v1(160.15,57.86)
  BOTTOM w0.076: 152.53,56.49 152.4,56.49 151.79,57.11 151.48,57.11 151.31,56.94 151.31,56.76 151.08,56.52 150.8,56.52 150.55,56.78 UCPU1.AH3
  BOTTOM w0.102: v1(153.55,55.16) 153.55,55.48 152.53,56.49 ; v1(160.15,57.86) 159.66,57.37 158.78,57.37 RP2.4
SNB_1.05V: length 3.1
  TOP w0.102: PR502.2 v2(199.66,58.24)
  TOP w0.635: PR502.2 201.2,58.37 PC502.1
SNUB_1.5V: length 1.7
  TOP w0.102: PR402.2 197.78,66.03 v2(197.96,66.21)
SNUB_1.8V: length 2.8
  TOP w0.102: PR407.2 v2(32.75,59.56)
  TOP w0.508: PR407.2 34.08,59.62 PC415.1
SPI_CLK_ROM: length 16
  BOTTOM w0.102: MC30.1 177.56,45.56 178.47,46.47 U48.6 178.47,48.5 178.59,48.62 178.79,48.62 178.91,48.75 178.91,48.92 178.79,49.04 178.27,49.04 178.15,49.17 178.15,49.33 178.27,49.46 179.21,49.46 179.32,49.56 179.32,49.76 179.21,49.86 178.57,49.86 178.47,49.97 178.47,50.3 178.59,50.43 179.21,50.43 179.34,50.55 179.34,50.75 179.45,50.86 179.61,50.86 179.72,50.75 179.72,50.08 179.85,49.96 180.04,49.96 180.17,50.08 180.17,50.8 180.29,50.92 180.46,50.92 180.59,50.8 180.59,50.4 180.71,50.28 180.9,50.28 181.03,50.4 181.03,50.8 181.16,50.92 v6(181.34,50.92) 181.56,50.69 RP5.1
SPI_CLK_VROM: length 12.9
  BOTTOM w0.102: RP5.2 183.32,51.19 183.48,51.04 183.48,50.59 183.83,50.24 184.69,50.24 185.06,50.61 MC32.1 v2(185.63,49.55) 185.93,49.55 186.24,49.86 190.1,49.86 190.23,49.98 190.23,51.9 190.1,52.03 189.73,52.03 189.6,51.9 U727.6
SPI_IO2_ROM: length 13
  BOTTOM w0.102: U48.3 178.47,53.67 178.34,53.54 177.94,53.54 177.82,53.67 177.82,55.61 177.94,55.74 178.32,55.74 178.43,55.62 180.14,55.62 180.27,55.5 180.27,54.64 180.4,54.52 180.73,54.52 180.85,54.64 180.85,55.5 180.98,55.62 181.87,55.62 182,55.5 182,55.39 181.87,55.27 181.42,55.27 181.3,55.14 v6(181.3,55.05) 181.3,54.62 181.4,54.51 RP8.3
SPI_IO2_VROM: length 13.1
  BOTTOM w0.102: RP8.4 182.92,55.01 183.28,55.01 183.71,55.44 184.85,55.44 185.13,55.16 v2(185.53,55.16) 189.07,55.16 189.18,55.28 189.18,55.44 189.07,55.56 188.35,55.56 188.22,55.69 188.22,55.83 188.35,55.95 188.98,55.95 189.11,56.08 189.11,56.25 188.98,56.38 188.36,56.38 188.26,56.48 188.26,56.68 188.36,56.78 189.5,56.78 189.6,56.88 U727.3
SPI_IO3_ROM: length 15.8
  BOTTOM w0.102: RP8.2 182.5,54.01 182.28,54.24 180.71,54.24 178.79,52.31 178.64,52.31 178.27,52.68 178.13,52.68 177.99,52.54 177.99,52.4 178.36,52.02 178.36,51.88 178.21,51.74 178.07,51.74 177.7,52.11 177.55,52.11 177.41,51.96 177.41,51.82 177.78,51.45 177.78,51.31 177.03,50.55 177.03,48.52 177.2,48.36 U48.7 177.2,46.71 176.22,45.73 v6(175.67,45.73)
SPI_IO3_VROM: length 13.1
  BOTTOM w0.102: U727.7 188.33,53.35 188.22,53.46 187.65,53.46 187.52,53.59 187.52,54.75 187.42,54.85 187.22,54.85 187.11,54.75 187.11,53.59 186.99,53.46 186.84,53.46 186.71,53.59 186.71,54.75 186.61,54.85 186.4,54.85 186.31,54.76 186.31,53.56 186.21,53.46 v2(185.59,53.46) 185.23,53.46 184.98,53.21 183.46,53.21 183.15,53.51 RP8.1
SPI_SI_ROM: length 13.2
  BOTTOM w0.102: RP6.1 184.6,49.35 184.67,49.42 184.67,49.64 184.56,49.75 183.75,49.75 183.31,50.19 181.68,50.19 181.59,50.1 181.59,49.17 181.54,49.12 v6(181.27,49.12) 181.18,49.21 181.18,49.7 181.06,49.83 180.85,49.83 180.73,49.7 180.73,47.91 180.6,47.79 180.38,47.79 180.26,47.91 180.26,49.41 180.13,49.54 179.86,49.54 179.74,49.41 U48.5
SPI_SI_VROM: length 12.9
  BOTTOM w0.102: U727.5 190.87,49.98 191,49.86 191.39,49.86 191.52,49.98 191.52,50.97 191.65,51.1 191.84,51.1 191.97,50.97 191.97,49.56 191.84,49.44 v2(190.21,49.44) 190.09,49.31 186.34,49.31 185.88,48.85 RP6.2
SPI_SO_ROM: length 13
  BOTTOM w0.102: RP7.1 184.13,57.82 183.85,58.1 183.1,58.1 182.46,57.46 182.46,56.79 182.33,56.66 v6(181.93,56.66) 181.65,56.66 181.53,56.54 181.53,56.36 181.65,56.23 182.5,56.23 182.61,56.13 182.61,55.98 182.5,55.88 178.54,55.88 178.13,56.28 177.31,56.28 177.2,56.17 U48.2
SPI_SO_VROM: length 15
  BOTTOM w0.102: RP7.2 184.6,57.32 184.99,57.32 185.12,57.19 185.12,56 185.25,55.88 185.37,55.88 185.5,56 185.5,56.89 185.63,57.01 185.76,57.01 185.86,56.91 185.86,56 185.96,55.9 186.16,55.9 186.26,56 186.26,56.91 186.36,57.01 186.57,57.01 186.67,56.91 186.67,56 186.77,55.9 186.97,55.9 187.08,56 187.08,56.91 187.18,57.01 187.38,57.01 187.48,56.91 187.48,56 187.58,55.9 187.79,55.9 187.89,56 187.89,56.91 187.99,57.01 188.21,57.01 188.33,57.14 U727.2 188.33,59.39 v2(187.84,59.89)
SPK_L+_C:
  vias: v1(20.05,17.4) v1(20.05,16.68) v2(22.73,19.45)
SPK_L-_C:
  vias: v1(20.01,15.27) v1(20.02,14.64) v2(24.88,18.63)
SPK_OUT_L+:
  vias: v2(29.27,22.25)
SPK_OUT_L-:
  vias: v2(30.82,23.25)
SPK_OUT_R+:
  vias: v2(32.09,22.97)
SPK_OUT_R-:
  vias: v2(31.22,21.99)
SPK_R+_C:
  vias: v1(24.15,13.8) v1(24.77,13.81) v2(28.86,15.53)
SPK_R-_C:
  vias: v1(24.3,15.58) v1(24.91,15.59) v2(28.44,17.76)
SPKR: length 248.6
  TOP w0.102: v2(20.87,19.77) 21.19,19.45 v1(21.19,19.07)
  IN2 w0.086: v1(21.19,19.07) 23.16,17.1 31.29,17.1 32.28,16.11 37.48,16.11 38.36,15.23 42.59,15.23 43.38,16.02 43.38,20.51 43.72,20.85 44.38,20.85 44.39,20.84 44.56,20.84 44.89,20.52 44.89,19.72 45.2,19.41 64.41,19.41 66.27,21.26 69.82,21.26 72.51,18.57 105.08,18.57 105.81,17.84 114.02,17.84 114.16,17.71 126.23,17.71 126.29,17.77 170.39,17.77 171.41,18.79 178.27,18.79 185.81,26.32 185.81,33.69 184.33,35.17 184.33,36.44 180.9,39.87 177.51,39.87 174.53,42.85 174.53,46.61 175.12,47.21 175.12,48.66 174.59,49.2 174.59,50.83 173.83,51.59 173.83,56.02 173.45,56.4 173.45,57.58 174.69,58.83 174.69,59.91 174.38,60.22 172.3,60.22 170.62,61.9 165.85,61.9 165.7,62.04 164.59,62.04 164.38,61.83 162.77,61.83 162.58,62.03 162.58,62.89 162.29,63.17 158.34,63.17 158.24,63.27 155.23,63.27 154.53,62.56
  IN2 w0.089: 154.53,62.56 154.24,62.28 v1(154.02,62.28)
  BOTTOM w0.076: 154.53,61.77 v1(154.02,62.28) 153.94,62.35 151.49,62.35 151.19,62.06 UCPU1.V2
  BOTTOM w0.102: RH37.2 154.62,61.67 154.53,61.77 ; v1(21.19,19.07) 21.21,19.1 RA25.1
SS_1.5V: length 4.1
  TOP w0.102: PU400.9 191.66,71.56 191.66,71.56 191.44,71.56 191.28,71.73 191.28,73.55 PC406.1 190.97,74.51 v2(191.28,74.82)
SS_1.8V: length 4.5
  TOP w0.102: v2(42.63,66.77) 42.19,66.34 PC414.1
  TOP w0.203: PU401.9 39.74,64.86 39.89,65.02 40.59,65.02 41.25,65.69 PC414.1
SSD_PCIE_WAKE#: length 12.4
  BOTTOM w0.102: R1377.1 182.08,45.16 181.67,44.75 181.22,44.75 v2(180.8,44.32) 180.31,43.83 180.31,40.2 178.06,37.95 178.06,36.8 177.77,36.51 177,36.51 176.97,36.54 JNGFF3.54
SSD_PWREN: length 106.9
  TOP w0.102: U682.4 154.54,74.93 154.64,75.03 155.06,75.03 155.39,74.7 RH431.1 v1(155.67,79.05) ; U717.5 204.08,26.26 204.31,26.49 v3(204.93,26.49) 204.93,26.5 205.4,26.97 206.42,26.97 206.72,27.28 v2(206.72,28.77) 206.77,28.83 R1189.1
  GND1 w0.102: v4(204.67,27.07) 204.93,26.81 v3(204.93,26.49)
  IN2 w0.086: v4(204.67,27.07) 204.75,27.07 205.49,27.8 205.49,34.15 204.18,35.46 204.18,38.14 201.77,40.56 199.18,40.56 198.64,41.1 198.64,50.68 195.9,53.42 195.9,69.35 189.32,75.92 181.69,75.92 180.78,76.83 171.77,76.83 171.16,76.22 168.82,76.22 168.21,76.83 168.12,76.83 165.39,79.55 156.17,79.55 v1(155.67,79.05)
SUS_ON: length 20.3
  TOP w0.102: UE5.B23 183.97,70.34 183.97,69.82 v1(183.27,69.11) ; R251.2 175.25,75.08 v1(175.25,74.74)
  BOTTOM w0.102: v1(175.25,74.74) 175.98,75.47 179.53,75.47 182.31,72.7 185.62,72.7 186.17,72.14 v2(186.17,70.19) 186.05,70.06 184.21,70.06 v1(183.27,69.11)
SUS_ON_EC: length 136.4
  TOP w0.102: R251.1 R252.1 RE68.1 173.83,77.07 172.69,78.2 171.86,78.2 171.65,78.42 171.65,79.69 v2(171.23,80.1) 170.7,80.63 89.1,80.63 85.74,77.28 85.74,68.68 85.98,68.44 v1(85.98,68.39)
  TOP w0.254: v1(72.23,50.61) 72.56,50.28 PR608.1
  IN3 w0.086: v1(85.98,68.39) 85.98,68.44 85.18,69.25 76.21,69.25 74.96,68 73.86,68 71.23,65.38 71.23,58.84 72.75,57.32 72.75,51.13 v1(72.23,50.61)
SUS_PWR_DN: length 18.1
  TOP w0.102: v1(154.26,48.36) 154.45,48.17 154.45,48.02 v2(156.05,46.42) 156.39,46.08 159.7,46.08 159.94,45.84 161.76,45.84 163.02,44.59 RH154.1 163.54,44.35 163.67,44.48 RH297.1
  BOTTOM w0.076: UCPU1.AV4 149.95,50.64 149.95,50.17 150.01,50.12 150.01,49.5 150.63,48.88 153.19,48.88 153.27,48.96
  BOTTOM w0.102: 153.27,48.96 153.71,48.96 154.26,48.41 v1(154.26,48.36)
SUS_STAT#/LPCPD#: length 14.2
  TOP w0.102: v2(159.63,58.43) v1(160.11,58.43) 160.16,58.48 160.16,58.96 160.77,59.56 RH197.1
  IN2 w0.086: v1(160.11,58.43) 160.11,58.42 159.93,58.24 156.87,58.24 155.75,57.13 154.71,57.13 154.46,57.37 152.85,57.37 152.3,57.93 150.88,57.93 150.79,57.84 v1(149.23,57.84)
  BOTTOM w0.076: v1(149.23,57.84) 149.47,57.6 UCPU1.AG4
SUSACK#: length 44.9
  TOP w0.102: v3(182.72,48.27) 182.06,47.61 176.67,47.61 175.51,46.44 v2(167.3,46.44) 166.2,45.34 RH430.2
  GND1 w0.102: v3(183.22,71.19) 183.61,71.19 v4(183.62,71.17) ; v4(183.13,48.26) 182.74,48.26 v3(182.72,48.27)
  IN4 w0.071: v4(183.62,71.17) 184.1,70.69 184.1,64.34 184.83,63.62
  IN4 w0.086: 184.83,63.62 184.83,59.42 183.35,57.95 183.35,55.6 183.1,55.34 183.1,48.29 v4(183.13,48.26)
SUSACK#_R: length 31.7
  TOP w0.102: v1(168.64,53.81) 168.08,53.25 v2(168.08,52.37) 168.08,50.14 167,49.06 165.98,49.06 164.93,48 164.93,46.7 164.49,46.25 RH430.1
  IN2 w0.086: v1(152.1,55.97) 153.26,55.97 154.14,55.08 157.86,55.08 162.08,50.86 165.11,50.86 168.05,53.81 v1(168.64,53.81)
  BOTTOM w0.076: UCPU1.AK2 151.09,56.06 151.39,56.36 151.71,56.36 v1(152.1,55.97)
SUSCLK: length 19.4
  IN1 w0.071: 152.28,60.35 151.15,59.22 151.15,58.78 150.75,58.38 148.37,58.38 148.23,58.52 v1(148.23,58.8) ; v4(160.6,60.31) 159.71,61.21 158.12,61.21 157.26,60.35 154.65,60.35 154.53,60.47
  IN1 w0.076: 152.28,60.35 152.68,60.75 154.25,60.75 154.53,60.47
  GND3 w0.102: v4(160.6,60.31) 160.6,60.32 160.4,60.32 v5(160.21,60.5)
  BOTTOM w0.076: UCPU1.AE6 148.31,58.32 148.23,58.41 v1(148.23,58.8)
  BOTTOM w0.102: v5(160.21,60.5) 160.75,61.04 v2(161.42,61.04) RH132.2 162.92,60.69 CH102.2
SUSCLK_R: length 234.9
  TOP w0.102: R1255.2 v1(43.53,42.46)
  IN2 w0.086: v4(44.48,20.41) 44.48,19.79 45.04,19.22 64.49,19.22 66.34,21.07 69.74,21.07 72.43,18.39 105,18.39 105.73,17.66 113.94,17.66 114.08,17.52 126.3,17.52 126.37,17.59 170.5,17.59 171.33,18.41 172.18,18.41 172.51,18.08 172.51,17.55 172.75,17.31 178.22,17.31 181.04,20.13 182.36,20.13 184.53,17.96 185.11,17.96 186.37,19.22 186.37,20.56 185.49,21.44 185.49,24.58 187.29,26.39 187.29,35.12 186.06,36.35 186.06,37.31 184.94,38.43 183.98,38.43 180.1,42.31 180.1,46.79 179.14,47.75 179.14,49.18 179.34,49.39 v4(179.34,49.48)
  IN4 w0.071: v4(44.48,20.41) 44.48,20.74 43.22,22 43.22,24.36 42.99,24.59 42.99,26.9 42.79,27.11 42.79,34.81 43.1,35.12 43.1,42.03 v1(43.53,42.46) ; v4(179.34,49.48) 178.14,50.68 174.22,50.68 172.41,52.5 172.41,53.62 168.87,57.15 168.87,57.64 166.11,60.4 164.87,60.4 v4(164.47,60.8)
  GND3 w0.102: v4(179.34,49.48) 179.32,49.45 v5(179.32,48.98) ; v4(164.47,60.8) 163.73,60.8 v5(163.49,61.04)
  BOTTOM w0.102: v5(179.32,48.98) 179.32,48.31 179.13,48.12 179.13,46.45 179.68,45.89 v2(180.14,45.89) 180.96,45.89 R2662.2
SW_1.5V:
  vias: v2(196.5,69.82)
SW_1.8V: length 1.5
  TOP w0.102: v2(35.62,58.16) 35.83,58.38 PR407.1
SW_1.35V:
  vias: v2(77.83,47.35) v7(75.98,49.93) v7(76.61,49.93) v7(78.45,50.75) v7(78.45,49.99) v7(78.45,47.89) v7(78.77,47.26) v7(79.09,50.75) v7(79.09,49.99) v7(79.09,47.89) v7(79.4,47.26) v7(79.72,47.89) v7(80.04,47.26) v7(80.36,47.89) v7(80.67,47.26) v7(80.99,47.89) v7(81.31,47.26) v7(81.63,47.89) v7(81.94,47.26)
SYS_PWROK: length 178.4
  TOP w0.102: R1309.2 v1(62.7,80.21) ; v1(74.35,68.44) 74.35,68.14 v2(73.92,67.71) ; v1(185.88,65.36) 186.25,64.99 186.52,64.99 186.77,64.74 UE5.B7
  IN1 w0.071: v1(155.96,56.64) 155.96,56.66 156.28,56.98 160.57,56.98 161.63,58.04 163.29,58.04 163.88,58.63 168.06,58.63 168.49,58.19 169.71,58.19 170.31,57.6 176.31,57.6 176.77,58.05 178.55,58.05 178.79,58.29 180.37,58.29 180.59,58.08 180.59,57.84 180.85,57.57 183.87,57.57 184.1,57.34 184.1,55.77 184.22,55.65 186.96,55.65 187.84,54.78 187.84,52.92 188.3,52.46 v4(188.3,52.45)
  IN2 w0.086: v1(155.96,56.64) 155.4,56.08 154.03,56.08 153.78,56.33 152.52,56.33 152.36,56.5 151.95,56.5 151.79,56.66 149.48,56.66 149.37,56.55 147.78,56.55 147.5,56.83 147.5,56.95 145.9,58.55 145.9,62.28 145.18,63.01 144.01,63.01 139.86,67.16 139.49,67.16 137.5,69.14 117.28,69.14 115.97,70.45 111.98,70.45 111.49,70.94 108.09,70.94 106.86,69.71 100.55,69.71 99.31,70.94 83.48,70.94 80.5,67.96 76.36,67.96 75.89,68.44 v1(74.35,68.44) ; v4(188.3,52.45) 188.3,52.63 188.45,52.78 188.45,55.14 188.95,55.65 188.95,60.84 187.35,62.44 187.35,64.44 186.88,64.91 186.33,64.91 v1(185.88,65.36)
  BOTTOM w0.102: v1(62.7,80.21) 62.7,80.17 61.98,79.45 61.98,77.63 62.22,77.39 64.03,77.39 65.03,78.39 71.06,78.39 71.71,79.04 75.35,79.04 75.7,78.7 75.7,72.63 74.35,71.28 v1(74.35,68.44) ; RH455.2 155.74,56.43 v1(155.96,56.64)
SYS_RESET#: length 12.6
  BOTTOM w0.076: 154.53,59.32 154.46,59.39 151.96,59.39 151.81,59.54 150.54,59.54 UCPU1.AC3
  BOTTOM w0.102: v2(160.14,61.13) 159.17,62.1 RP20.1 158.51,62.1 158.26,61.85 158.26,60.62 157.89,60.25 156.99,60.25 156.17,59.43 155.3,59.43 RH450.1 154.53,59.32
SYS_RESET#_XDP: length 13.9
  TOP w0.102: 63.91,70.5 JXDP.48 ; 63.91,70.5 63.91,71.74 62.15,73.5 59.39,73.5 58.52,74.37 C1237.1 RH451.1 RH367.2 ; 63.91,70.5 63.91,68.42 v2(64.06,68.27)
TD_IREF: length 4.8
  BOTTOM w0.076: v2(142.34,75.06) RC155.1 143.41,74.63 143.79,74.25 143.79,73.36 143.85,73.3 143.85,71.92 UCPU1.B12
TESTLOW1: length 3.9
  BOTTOM w0.076: RH36.2 130.27,74.05 130.27,72.19 130.29,72.17 130.32,72.1 130.33,72.05 130.35,72 130.35,71.9 130.33,71.86 130.26,71.67 130.33,71.4 130.39,71.31 130.39,71.31 130.43,71.25 UCPU1.C35
TESTLOW2: length 4.4
  BOTTOM w0.076: UCPU1.C34 131.31,70.83 130.87,71.27 130.69,71.27 130.53,71.43 130.5,71.48 130.45,71.66 130.51,71.79 130.53,71.86 130.53,72.03 130.51,72.11 130.49,72.16 130.46,72.25 130.46,74.23 RH41.2
TESTLOW3: length 3.7
  TOP w0.076: v2(148.79,57.39) 148.51,57.39 148.07,56.95 v1(148.07,56.94)
  TOP w0.089: v1(148.07,56.94) 148.07,56.58 RH44.2
  BOTTOM w0.076: UCPU1.AK8 147.3,56.51 147.74,56.94 v1(148.07,56.94)
TESTLOW4: length 5.1
  TOP w0.076: v2(145.37,52.49) 145.37,53.5 146.23,54.36 v1(146.4,54.36)
  TOP w0.089: v1(146.4,54.36) 146.69,54.65 147.17,54.65 RH45.2
  BOTTOM w0.076: UCPU1.AL8 147.28,55.18 146.46,54.36 v1(146.4,54.36)
THERMATRIP2#: length 7.9
  TOP w0.102: RE69.2 178,73 CE61.1 ; RE69.2 v2(177.04,72.12) 177.04,71.29 177.49,70.84 178.22,70.84 178.47,70.6 178.47,70.34 UE5.B34 ; RE69.2 177.59,73.55 177.59,74.14 176.82,74.91 QE9.1
THERMATRIP3#: length 1.9
  TOP w0.102: RE67.1 189.57,62.49 v2(188.89,62.49) UE5.A2
THSEL_STRAP: length 11.4
  TOP w0.102: v3(181.97,74.56) 181.97,74.6 181.63,74.94 RE78.1 181.63,75.75 v2(181.18,76.2) ; UE5.B29 180.97,70.34 180.97,69.98 181.06,69.89 181.06,68.98 180.7,68.62 v1(180.42,68.62)
  GND1 w0.102: v3(181.97,74.56) 181.57,74.56 v4(181.55,74.55)
  IN3 w0.086: v4(181.55,74.55) 181.55,73.95 182.08,73.42 182.08,72.02 181.45,71.39 181.45,70.44 180.96,69.95 180.96,69.1 180.74,68.88 180.68,68.88 v1(180.42,68.62)
TON_1.35V: length 2.9
  BOTTOM w0.102: v2(69.45,49.15) 69.63,48.97 70.17,48.97 70.61,49.4 PR606.2
  BOTTOM w0.203: PU600.9 72.01,49.18 71.2,49.18 70.97,49.4 PR606.2
TOUCH_PANEL_INTR#: length 122
  TOP w0.076: v2(149.48,64.21) 149.6,64.21 150.07,64.68 v1(150.07,64.68)
  IN1 w0.071: v1(150.07,64.68) 150.42,65.04 153.56,65.04 155.08,66.56 158.17,66.56 158.98,65.75 160.84,65.75 161.84,64.75 163.53,64.75 v4(163.68,64.9)
  IN3 w0.086: v1(64.34,72.33) 65.05,73.03 78.82,73.03 80.97,70.89 100.2,70.89 102.34,68.75 106.23,68.75 107.34,69.85 108.32,69.85 109.06,70.59 110.07,70.59
  IN3 w0.089: v1(150.07,64.68) 149.69,65.06 148.98,65.06 148.1,65.94 146.94,65.94 146.02,66.87 146.02,70.09 145.64,70.47 138.38,70.47 138.21,70.3 117,70.3 116.71,70.59 110.07,70.59
  GND3 w0.102: v5(163.87,64.59) 163.87,64.71 v4(163.68,64.9)
  BOTTOM w0.076: v1(150.07,64.68) 150.3,64.45 UCPU1.P3
  BOTTOM w0.102: v1(64.34,72.33) 64.34,75.84 65.16,76.66 70.57,76.66 71.67,77.76 JTS.5
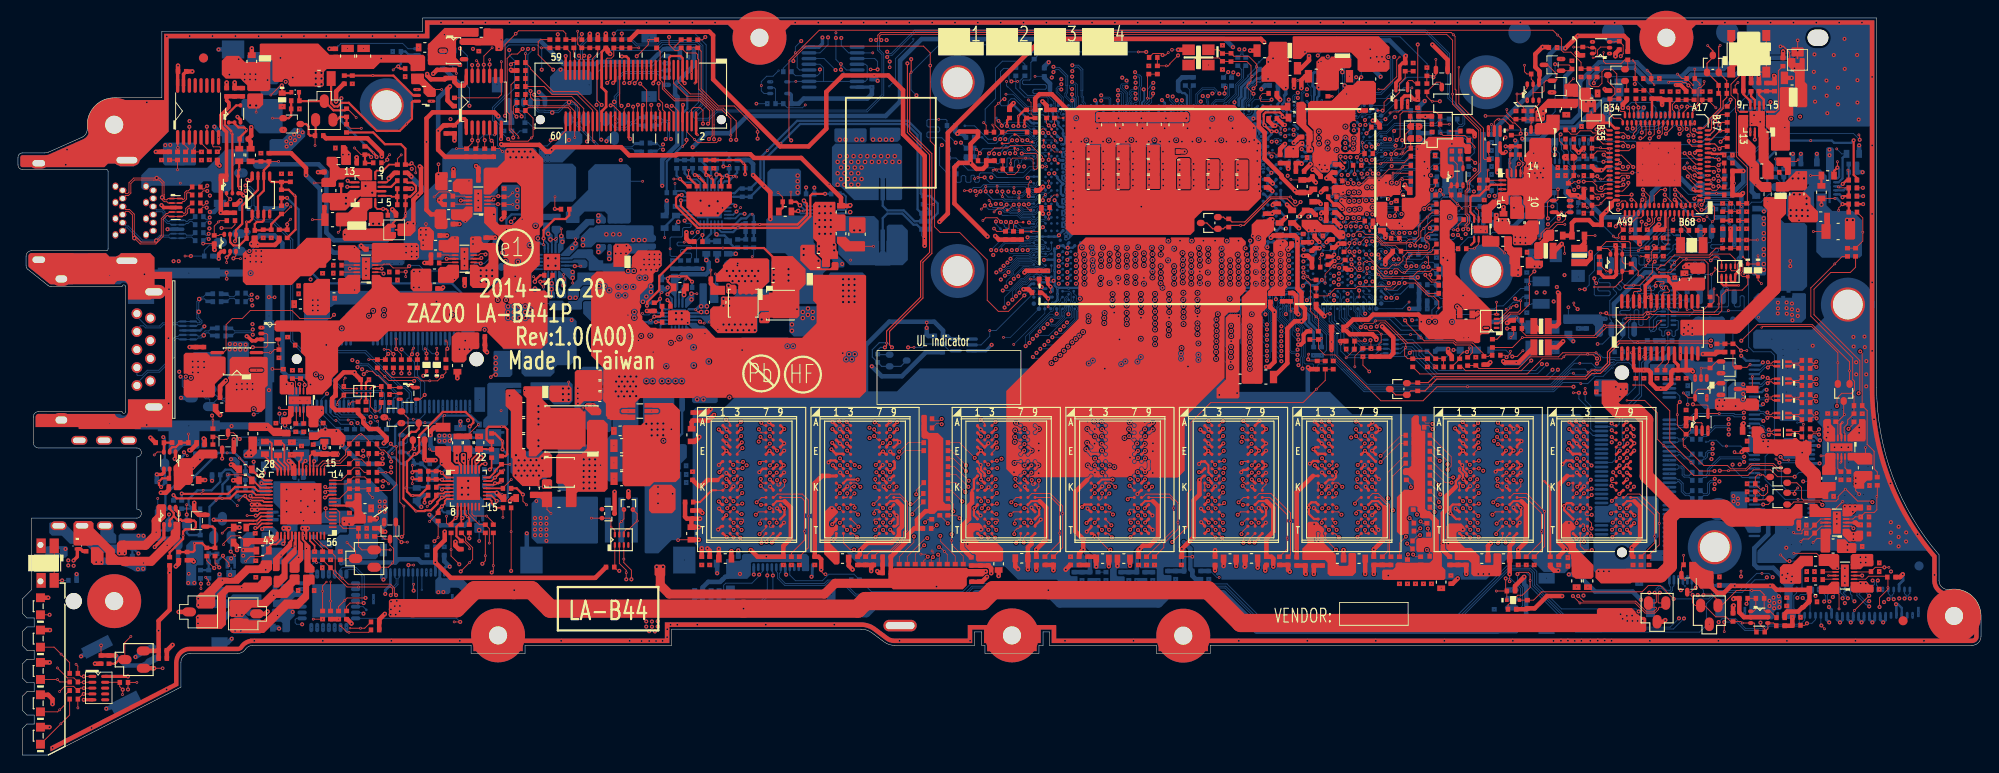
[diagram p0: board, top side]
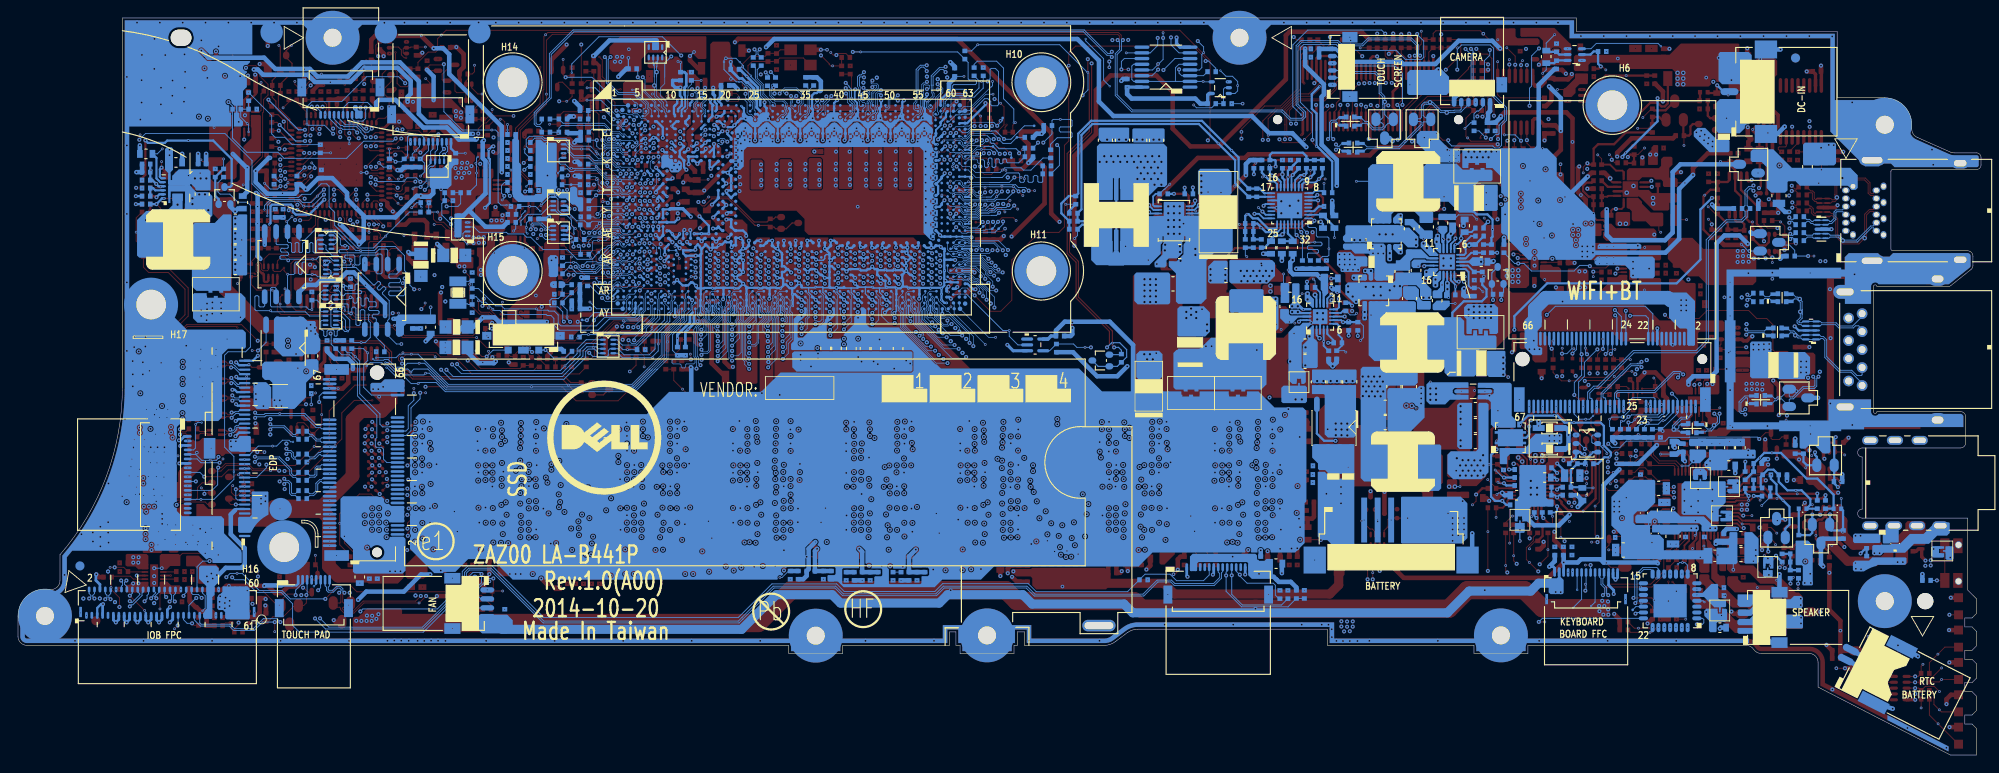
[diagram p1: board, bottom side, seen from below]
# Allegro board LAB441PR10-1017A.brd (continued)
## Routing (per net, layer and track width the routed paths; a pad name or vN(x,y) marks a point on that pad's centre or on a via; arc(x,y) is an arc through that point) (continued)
TOUCH_RST_N_GYRO_INT1: length 11.2
  BOTTOM w0.076: UCPU1.L1 151.71,65.81 152.24,66.33 153.73,66.33 154.53,67.13
  BOTTOM w0.102: RH3545.2 160.85,68.63 160.06,68.63 159.81,68.38 157.43,68.38 157.14,68.09 157.14,67.95 156.62,67.42 v2(155.64,67.42) 154.82,67.42 154.53,67.13
TOUCHPAD_INTR#: length 72
  TOP w0.102: v2(193.9,52.45) 193.51,52.83 DZ3.2 193.51,53.23 193.13,53.61 192.02,53.61 v3(191.93,53.52)
  GND1 w0.102: v4(191.26,54.12) 191.27,54.12 191.87,53.52 v3(191.93,53.52)
  IN1 w0.071: v4(188.33,65.78) 188.16,65.95 187.83,65.95 187.61,66.17 185.01,66.17 183.58,64.73 183,64.73 181.72,63.46 180.5,63.46 180.03,62.98 179.13,62.98 178.84,62.69 177.27,62.69 176.47,63.5 175.47,63.5 174.5,64.46 173.39,64.46 171.17,62.24 167.92,62.24 165.68,64.48 161.81,64.48 160.75,65.55 158.22,65.55 v4(157.59,66.18)
  IN2 w0.086: v1(147.21,64.54) 147.64,64.97 148.11,64.97 148.29,64.79 148.29,64.3 148.51,64.08 151.38,64.08 151.81,64.52 154.23,64.52 155,65.29 156.94,65.29 157.59,65.93 v4(157.59,66.18)
  IN3 w0.086: v4(188.33,65.78) 188.18,65.93 188.18,67.55 188.47,67.84 189.44,67.84 189.69,67.59 189.69,66.65 190.06,66.28 190.06,62.97 191.34,61.69 191.34,57.37 190.9,56.93 190.9,54.48 v4(191.26,54.12)
  GND3 w0.102: v5(157.63,66.95) 157.63,66.68 157.59,66.64 v4(157.59,66.18)
  BOTTOM w0.076: v1(147.21,64.54) 147.3,64.45 147.3,63.45 UCPU1.U7
TP_PW_EN: length 186.2
  TOP w0.102: v1(207.03,16.47) 207.03,17.51 207.95,18.44 v2(207.95,18.63) 207.95,19.73 R1175.2 207.79,19.9 205.81,19.9 205.48,19.57 U716.3
  IN2 w0.086: v1(207.03,16.47) 207.03,14.14 206.41,13.52 178.1,13.52 176.59,15.02 172.2,15.02 171.19,16.03 171.01,16.21 127.6,16.21 127.56,16.16 113.51,16.16 113.38,16.3 105.17,16.3 104.44,17.02 71.78,17.02 70.64,18.16 49.45,18.16 45.5,14.21 35.64,14.21 v4(35.22,13.79)
  GND3 w0.102: v4(35.22,13.79) v5(35.22,14.18)
TPM_PIRQ#: length 70.5
  TOP w0.102: U652.20 183.57,49.62 183.92,49.27 188.68,49.27 189.16,49.75 v2(189.16,50.17) 189.16,50.94 v3(188.92,51.18)
  GND1 w0.102: v4(156.99,66) 156.99,66.13 157.57,66.71 v3(157.6,66.71) ; v4(188.69,52.07) 188.69,51.83 188.92,51.6 v3(188.92,51.18)
  IN1 w0.071: v4(188.69,52.07) 188.69,52.55 188.06,53.18 188.06,58.71 187.64,59.13 187.39,59.13 186.9,58.63 180.8,58.63 180.57,58.86 179.98,58.86 179.43,59.41 177.34,59.41 176.07,58.14 170.53,58.14 169.93,58.74 168.75,58.74 167.26,60.23 166.24,60.23 166.01,60.46 164.24,60.46 163.31,59.53 160.14,59.53 159.35,60.31 158.35,60.31 157.2,59.16 154.53,59.16
  IN1 w0.076: 154.53,59.16 151.96,59.16 v4(151.81,59.01)
  IN3 w0.086: v4(151.81,59.01) 151.17,59.65 151.17,62.06 150.59,62.65 v1(150.59,63.15) 150.67,63.23 153.43,63.23 153.84,63.64 153.84,64.75 154.49,65.4 156.77,65.4 156.99,65.62 v4(156.99,66)
  BOTTOM w0.076: v1(150.59,63.15) 150.3,63.44 UCPU1.T3
TPM_RESET#_TPM: length 5.1
  TOP w0.102: U652.16 186.17,49.69 186.38,49.47 187.42,49.47 187.98,50.04 RH474.1 188.2,50.04 188.61,50.45 v2(188.61,51.86)
UART1_CTS#: length 139
  TOP w0.102: U671.10 52.46,75.56 v1(52.46,76.82) v2(52.46,77.36)
  IN1 w0.071: v4(163.42,67.08) 163.25,66.92 159.53,66.92 157.4,69.05 152.89,69.05 152.68,69.25 151.86,69.25 150.98,68.38 149.74,68.38 149.39,68.04 v1(148.52,68.04)
  IN2 w0.086: v1(148.52,68.04) 149.5,67.06 151.45,67.06 151.82,67.43 153.5,67.43 154.32,68.25 154.32,71.38 150.97,74.73 148.43,74.73 147.95,75.21 136.94,75.21 136.27,74.55 128.26,74.55 126.02,76.79 125.96,76.79 123.98,78.77 101.74,78.77 98.62,75.65 94.29,75.65 93.23,74.6 75.17,74.6 74.14,75.63 53.65,75.63 v1(52.46,76.82)
  GND3 w0.102: v4(163.42,67.08) 163.42,67.69 v5(163.87,68.15)
  BOTTOM w0.076: v1(148.52,68.04) 149.09,68.04 149.65,67.47 UCPU1.J4
UART1_CTS#_NGFF: length 32.6
  TOP w0.102: U671.5 52.46,69.79 52.46,68.56 v1(52.67,68.35) 52.89,68.13 R1372.2 53.55,67.47 v2(53.89,67.13)
  IN2 w0.086: v1(40.72,49.51) 41.98,50.76 44.91,50.76 46.36,52.22 46.36,55.38 50.35,59.37 50.35,63.43 52.39,65.46 52.39,68.07 v1(52.67,68.35)
  BOTTOM w0.102: JNGFF1.26 40,48.78 v1(40.72,49.51)
UART1_RTS#: length 120.8
  TOP w0.102: v2(52.74,78.69) 51.81,77.75 v1(51.81,76.8) 51.81,75.56 U671.11
  IN2 w0.086: 128.68,74.37 136.36,74.37 137,75.01 147.83,75.01 148.28,74.56 150.8,74.56 154.08,71.27 154.08,68.54 v1(153.94,68.4) ; 128.1,74.37 125.92,76.55 125.86,76.55 123.88,78.53 101.84,78.53 98.72,75.41 94.39,75.41 93.33,74.36 75.07,74.36 74.05,75.39 53.21,75.39 v1(51.81,76.8)
  IN2 w0.089: 128.68,74.37 128.1,74.37
  BOTTOM w0.076: 153.95,67.75 153.95,67.74 153.65,67.44 153.05,67.44 152.88,67.61 152.87,67.61 152.86,67.61 151.68,67.61 151.68,67.61 151.5,67.61 151.31,67.43 151.31,67.27 151.05,67.01 150.56,67.01 UCPU1.J3
  BOTTOM w0.102: RH459.1 v1(153.94,68.4) 153.95,68.39 153.95,67.75
UART1_RTS#_NGFF: length 31.4
  TOP w0.102: R1375.2 51.91,67.47 v1(51.91,68.4) 51.8,68.51 U671.4
  IN2 w0.086: v1(40.68,48.92) 40.35,49.26 40.35,49.79 41.56,51 44.81,51 46.13,52.32 46.13,55.48 50.12,59.47 50.12,63.56 51.38,64.82 51.38,67.87 v1(51.91,68.4)
  BOTTOM w0.102: v1(40.68,48.92) 40.5,48.74 JNGFF1.28
UART1_RXD: length 141.1
  TOP w0.102: v2(51,77.25) 51.15,77.09 v1(51.15,76.76) 51.15,75.75 U671.12
  IN1 w0.071: v4(163.84,66.8) 163.69,66.65 159.45,66.65 157.29,68.8 152.86,68.8 152.59,69.06 151.96,69.06 151.13,68.23 149.85,68.23 149.1,67.48 v1(148.49,67.48)
  IN2 w0.086: v1(51.15,76.76) 51.61,77.22 52.84,77.22 54.19,75.86 74.24,75.86 75.27,74.84 93.13,74.84 94.19,75.89 98.52,75.89 101.64,79.01 124.08,79.01 126.05,77.04 126.11,77.04 128.42,74.73 136.15,74.73 136.81,75.39 148.06,75.39 148.54,74.91 151.15,74.91 154.56,71.49 154.56,68.15 153.66,67.25 151.9,67.25 151.53,66.88 149.36,66.88 148.77,67.48 v1(148.49,67.48)
  GND3 w0.102: v4(163.84,66.8) 163.84,67.23 v5(163.87,67.26)
  BOTTOM w0.076: v1(148.49,67.48) 148.54,67.43 149.09,67.43 149.65,66.86 UCPU1.K4
UART1_RXD_NGFF: length 35.7
  TOP w0.102: U671.3 v1(51.15,68.34) 51.15,67.71 R1374.2
  IN2 w0.086: v1(51.15,68.34) 50.28,67.47 50.28,64.12 49.88,63.71 49.88,60.52 45.89,56.53 45.89,52.41 44.71,51.24 41.46,51.24 39.97,49.75 39.97,49.28 39.56,48.87 v1(39.03,48.87)
  BOTTOM w0.102: v1(39.03,48.87) 37.28,48.87 37,48.59 JNGFF1.22 ; v1(51.15,68.34) 51.81,69 v2(53,69)
UART1_TXD: length 118.3
  TOP w0.102: U671.13 50.5,75.56 v1(50.5,76.76)
  IN2 w0.086: 125.79,76.28 123.78,78.29 101.94,78.29 98.82,75.17 96.35,75.17 95.29,74.12 61.98,74.12 61.13,74.96 52.3,74.96 v1(50.5,76.76) ; 127.94,74.19 136.62,74.19 137.24,74.82 146.91,74.82 148.3,73.42 151.59,73.42 153.84,71.17 153.84,70.23 v1(153.04,69.43)
  IN2 w0.089: 125.79,76.28 125.85,76.28 127.94,74.19
  BOTTOM w0.076: 153.27,69.64 153.23,69.64 153.04,69.45 v1(153.04,69.43) 152.91,69.31 152.91,68.84 152.94,68.81 152.94,68.35 152.72,68.14 151.92,68.14 151.73,68.33 151.72,68.33 151.71,68.34 151.43,68.34 151.15,68.05 UCPU1.G2
  BOTTOM w0.102: 153.27,69.64 154.49,69.64 RH458.1
UART1_TXD_NGFF: length 32.4
  TOP w0.102: U671.2 v1(50.5,68.41) 50.5,68.08 R1373.2 v2(48.77,67.46)
  IN2 w0.086: v1(50.5,68.41) 50.5,68.35 49.47,67.31 49.47,64.37 49.64,64.2 49.64,60.62 45.65,56.63 45.65,52.51 44.61,51.48 41.36,51.48 39.5,49.62 v1(39.5,49.42)
  BOTTOM w0.102: v1(39.5,49.42) 39.5,46.32 JNGFF1.24
UART_WAKE#: length 165.8
  TOP w0.089: 154.39,53.04 151.73,53.04 v2(151.3,53.47) 150.64,54.13 v1(150.64,54.19)
  TOP w0.102: RH382.1 156.84,51.36 155.16,53.04 154.39,53.04
  IN3 w0.086: 110.07,69.2 109.98,69.2 109.87,69.09 107.66,69.09 105.73,67.16 101.66,67.16 98.78,70.05 80.74,70.05 79.03,71.77 76.88,71.77 76.3,71.19 67.47,71.19 65.71,69.43 50.83,69.43 50.11,68.71 50.11,67.04 50.5,66.65 50.5,62.55 50.66,62.38 50.66,58.93 53.22,56.37 53.22,55.73 53.74,55.22 53.74,52.6 50.87,49.73 49.05,49.73 v1(48.29,48.97)
  IN3 w0.089: v1(150.64,54.19) 150.92,54.48 150.92,56.04 151.12,56.23 151.12,57.17 150.07,58.22 146.81,58.22 145.89,59.13 144.43,59.13 144.09,59.48 143.33,59.48 143.08,59.73 143.08,60.9 143.73,61.55 143.73,64 140.29,67.44 139.2,67.44 137.69,68.95 115.78,68.95 115.49,68.66 113.32,68.66 112.77,69.2 110.07,69.2
  BOTTOM w0.076: UCPU1.AM3 150.3,54.53 v1(150.64,54.19)
  BOTTOM w0.102: JNGFF1.20 36.5,49.09 37.33,49.93 47.34,49.93 v1(48.29,48.97)
UG_3V: length 5.9
  TOP w0.102: v7(60.42,57.74) v2(60.42,58.54)
  IN4 w1.016: 60.55,56.24 60.55,55.96 61.18,55.32 62.27,55.32 62.78,54.81 64.86,54.81
  vias: v7(60.55,57.1) v7(65.75,55.83) v7(65.75,55.2)
UG_5V: length 6.5
  TOP w0.102: v7(60.67,52.9) v2(60.67,53.45)
  IN4 w1.016: 61.69,52.02 61.88,52.02 62.89,53.04 66.26,53.04 66.92,53.7 66.97,53.7
  vias: v7(60.67,52.27) v7(67.85,53.86) v7(68.48,53.86)
USB0_DET#: length 49.4
  TOP w0.102: RE34.2 v3(192.24,57.3) v2(193.43,57.3)
  GND1 w0.102: v4(191.82,56.72) 192.24,57.15 v3(192.24,57.3)
  IN3 w0.086: v4(199.83,18.92) 198.3,20.44 195.81,20.44 194.25,22.01 194.25,24.7 196.3,26.74 196.3,29.03 198.23,30.96 198.23,37.78 197.48,38.53 197.48,43.3 192.41,48.37 192.41,52.6 191.82,53.18 v4(191.82,56.72)
  GND3 w0.102: v5(200.2,18.41) 200.2,18.55 v4(199.83,18.92)
USB0_DET_EC#: length 20.9
  TOP w0.102: UE5.B63 183.97,61.14 183.97,61.48 183.14,62.31 v1(183.14,62.35) ; RE34.1 RE36.2 CE56.1 188.84,56.39 188.08,55.63 184.22,55.63 183.06,54.47 v3(182.72,54.47) v2(182.3,54.05)
  GND1 w0.102: v4(182.33,54.21) 182.58,54.47 v3(182.72,54.47)
  IN4 w0.071: v1(183.14,62.35) 183.55,61.93 183.55,59.19 182.81,58.44 182.81,55.83 182.53,55.55 182.53,54.42 v4(182.33,54.21)
USB0_PWR_EN: length 8
  BOTTOM w0.076: 154.39,54 154.14,54 153.69,54.46 152.7,54.46 152.22,54.94 151.89,54.94 151.81,54.86 151.41,54.86 151.12,54.57 UCPU1.AM2
  BOTTOM w0.102: 154.39,54 155.65,54 155.91,54.27 155.91,54.48 156.25,54.81 v2(156.53,54.81) 157.37,54.81 RH400.1
USB0_PWR_EN_EC: length 60.7
  TOP w0.102: v2(177.41,57.73) 177.6,57.55 v3(178.01,57.55) 178.01,57.93 RE60.1 178.2,58.77 178.2,59.15 178.9,59.84 179,59.84 179.22,60.06 UE5.A50
  GND1 w0.102: v4(178.72,57.11) 178.44,57.11 v3(178.01,57.55)
  IN1 w0.071: v4(178.72,57.11) 179.19,57.58 180.26,57.58 180.67,57.16 183.68,57.16 183.73,57.11 183.73,55.61 184.07,55.27 186.77,55.27 187.46,54.59 187.46,52.54 188.59,51.41 188.59,50.82 191.4,48.02 191.4,46.88 192.93,45.35 192.93,42.88 193.45,42.36 193.45,34.25 195.67,32.03 195.67,31.26 196.28,30.66 196.28,25.88 199.15,23.01 199.15,18.14 v1(198.48,17.47)
  BOTTOM w0.102: JIO1.39 199.3,16.67 198.49,17.47 v1(198.48,17.47)
USB1_EN: length 3.8
  TOP w0.102: US2.4 v2(28.06,44.77) 28.18,44.77 28.52,45.11 R1216.1 29.02,45.6 28.92,45.71 U699.4
USB1_PWR_EN: length 243.3
  TOP w0.102: RH95.2 157.65,62.32 v1(158.17,62.84) 158.17,62.66 v2(158.53,62.3)
  GND1 w0.102: v3(27.07,47.55) 27.07,47.97 v4(27.44,48.33)
  IN1 w0.071: v1(158.17,62.84) 158.19,62.84 158.74,62.28 162.14,62.28 162.6,61.82 166.03,61.82 v4(166.97,60.88)
  IN2 w0.086: v1(158.17,62.84) 157.69,62.36 154.69,62.36 154.25,61.91 153.48,61.91 153.06,62.34 151.8,62.34 150.82,61.35 149.44,61.35 v1(149.15,61.65)
  IN3 w0.076: 82.78,21.27 98.4,21.27 98.75,20.92 102.43,20.92 103.28,21.77 109.44,21.77 110.15,21.06 117.22,21.06 117.37,20.91
  IN3 w0.086: 82.78,21.27 82.77,21.27 74.44,21.27 74.39,21.22 73.06,21.22 72.81,21.47 52.35,21.47 51.12,22.7 45.88,22.7 43.24,25.33 39.99,25.33 37.94,27.38 37.94,35.26 34.35,38.85 34.34,38.85 33.36,39.82 29.38,39.82 27.44,41.76 v4(27.44,48.33) ; 117.37,20.91 119.56,18.72 124.79,18.72 126.2,20.14 141.07,20.14 141.95,19.26 170.72,19.26 171.99,20.53 173.79,20.53 175.65,22.39 175.65,27.2 177.11,28.66 179.56,28.66 180.28,29.38 180.28,36.25 172.55,43.99 172.55,46.46 171.29,47.72 171.29,48.97 171.84,49.51 171.84,52.54 171.1,53.27 171.1,54.45 169.8,55.75 169.8,56.78 169.26,57.32 169.26,60.07 168.45,60.88 v4(166.97,60.88)
  BOTTOM w0.089: UCPU1.Y5 148.97,61.47 v1(149.15,61.65)
USB1_PWR_EN_EC: length 227.9
  TOP w0.102: RE59.1 175.12,64.4 v1(175.65,64.4) 175.65,64.34 175.91,64.07 v2(176.01,64.07) 176.31,64.07 176.72,64.49 176.89,64.49 176.89,64.49 UE5.A43 ; v1(26.12,45.37) 27.59,45.37 27.77,45.55 27.77,46.76 27.63,46.9 U699.2
  IN3 w0.086: v1(175.65,64.4) 175.35,64.11 175.35,61.77 175.79,61.34 175.79,54.28 174.9,53.39 174.9,52.37 175.79,51.48 175.79,44.85 176.06,44.57 176.06,41.69 178.01,39.75 178.86,39.75 181.13,37.47 181.13,26.65 179.14,24.66 176.73,24.66 176.51,24.44 176.51,22.06 174.14,19.68 171.47,19.68 170.86,19.07 141.87,19.07 141,19.95 126.33,19.95 124.89,18.51 119.4,18.51 117.77,20.14 110.43,20.14 108.96,21.6 103.47,21.6 102.6,20.74 98.66,20.74 98.3,21.09 98.14,21.09 98.13,21.08 74.52,21.08 73.53,20.09 71.17,20.09 69.99,21.27 52.24,21.27 51.01,22.5 45.51,22.5 43.32,24.68 42.12,24.68 41.7,24.27 40.79,24.27 37.75,27.31 37.75,35.18 34.27,38.66 34.26,38.66 33.29,39.63 28.12,39.63 26.59,41.17 26.59,44.9 v1(26.12,45.37)
USB3RN0: length 129.4
  IN1 w0.071: v1(210.39,17.41) 210.39,17.41 210.39,16.56 209.71,15.88 202.77,15.88 202.36,16.28 202.36,18.03 200.03,20.36 200.03,24.17 197.08,27.12 197.08,35.45 196.11,36.42 196.11,44.14 194.44,45.81 193.95,45.81 192.44,47.32 192.44,48.52 189.64,51.32 189.64,52.6 189.22,53.03 189.22,55.53 188.76,55.98 188.76,62.38 189.78,63.39 189.78,65.87 190.57,66.66 190.57,67.12 189.95,67.73 189.95,68.35 189.49,68.81 188.4,68.81 187.19,70.01 185.66,70.01 185.57,70.1 184.67,70.1 184.07,69.5 184.07,68.9 183.72,68.56 183.13,68.56 182.78,68.21 182.18,68.21 181.92,68.47 181.92,69.5 181.71,69.71 180.1,69.71 179.73,70.08 176.84,70.08 176.74,69.97 171.19,69.97 168.89,67.67 166.45,67.67 166.03,68.1 163.47,68.1 163.18,68.39 161.75,68.39 161.61,68.25 160.55,68.25 160.43,68.37 159.33,68.37 158.1,69.61 153.4,69.61 153.18,69.82 152.34,69.82 152.13,69.61 149.44,69.61 148.77,68.94 148.28,68.94 148.09,69.13 147.48,69.13 147.15,68.8 147.15,68.45 146.24,67.54 146.24,67.16 145.91,66.83 140.05,66.83 139.43,67.45 139.43,68.23 v1(139.43,68.24)
  BOTTOM w0.076: v1(139.43,68.24) 139.8,68.61 140.18,68.61 UCPU1.G20
  BOTTOM w0.102: v1(210.39,17.41) 210.2,17.6 210.2,17.77 210.4,17.96 JIO1.2
USB3RN1: length 144.9
  IN1 w0.071: v1(140.91,69.55) 140.68,69.32 140.48,69.32 140.07,68.91 117.58,68.91 115.21,71.28 109.82,71.28 106.02,67.48 100.99,67.48 97.49,70.98 80.03,70.98 78.79,69.74 73.26,69.74 72.13,70.87 63.18,70.87 61.77,72.27 54.63,72.27 53.89,73.01 50.03,73.01 49.38,72.36 48.13,72.36 43.1,67.33 32.02,67.33 27.58,62.89 27.58,53.31 27.39,53.11 27.39,50.19 25.43,48.23 25.43,47.15 25.63,46.95 25.93,46.95 v1(26.11,46.76)
  BOTTOM w0.076: UCPU1.E18 141.27,69.55 v1(140.91,69.55)
  BOTTOM w0.102: v1(26.11,46.76) 25.89,46.98 24.13,46.98 23.82,46.67 ML13.1 23.14,46.67 R560.1
USB3RN1_RC_CON: length 12.9
  BOTTOM w0.102: R560.2 22.14,46.67 ML13.2 21.52,46.67 21.22,46.97 20.94,46.97 v7(20.66,46.69) 20.36,46.4 20.03,46.4 19.87,46.24 DI1.10 DI1.1 17.92,46.24 17.81,46.35 17.6,46.35 17.37,46.11 17.37,44.23 15.74,42.59 14.46,42.59 13.22,41.36 JUSB1.5
USB3RP0: length 129.5
  IN1 w0.071: v1(139.97,68.24) 139.56,67.83 139.56,67.5 140.1,66.96 145.86,66.96 146.11,67.21 146.11,67.59 147.02,68.51 147.02,68.86 147.42,69.26 148.14,69.26 148.34,69.07 148.71,69.07 148.96,69.32 148.96,69.61 149.1,69.74 152.08,69.74 152.29,69.95 153.28,69.95 153.49,69.74 158.15,69.74 159.39,68.51 160.48,68.51 160.61,68.38 161.55,68.38 161.7,68.52 163.23,68.52 163.52,68.23 166.08,68.23 166.51,67.81 168.84,67.81 171.14,70.11 176.69,70.11 176.79,70.21 179.79,70.21 180.15,69.84 181.76,69.84 182.05,69.55 182.05,68.52 182.23,68.34 182.72,68.34 183.07,68.69 183.67,68.69 183.93,68.95 183.93,69.55 184.61,70.24 185.62,70.24 185.71,70.14 187.25,70.14 188.45,68.94 189.55,68.94 190.09,68.4 190.09,67.79 190.7,67.17 190.7,66.61 189.91,65.82 189.91,63.34 188.9,62.33 188.9,56.04 189.35,55.59 189.35,53.08 189.77,52.66 189.77,51.38 192.57,48.58 192.57,47.37 194.01,45.94 194.5,45.94 196.24,44.2 196.24,36.48 197.21,35.5 197.21,27.17 200.16,24.23 200.16,20.42 202.49,18.08 202.49,16.34 202.82,16.01 209.66,16.01 210.26,16.62 210.26,16.96 v1(209.81,17.41)
  BOTTOM w0.076: v1(139.97,68.24) 139.97,67.96 140.04,67.9 140.2,67.9 140.34,68.04 140.44,68.04 140.54,67.93 140.54,67.82 UCPU1.H20
  BOTTOM w0.102: JIO1.4 209.8,17.96 209.99,17.77 209.99,17.6 v1(209.81,17.41)
USB3RP1: length 144.8
  IN1 w0.071: v1(140.92,68.85) 141.03,68.95 141.03,69.09 140.92,69.19 140.53,69.19 140.12,68.78 117.52,68.78 115.16,71.14 109.87,71.14 106.08,67.34 100.93,67.34 97.43,70.84 80.09,70.84 78.85,69.6 73.21,69.6 72.08,70.74 63.12,70.74 61.72,72.14 54.57,72.14 53.84,72.88 50.09,72.88 49.44,72.23 48.18,72.23 43.15,67.2 32.08,67.2 27.72,62.84 27.72,53.25 27.52,53.06 27.52,50.13 25.56,48.18 25.56,47.21 25.69,47.08 25.84,47.08 26.1,47.35 v1(26.11,47.35)
  BOTTOM w0.076: v1(140.92,68.85) 141.08,69.01 UCPU1.F18
  BOTTOM w0.102: R565.1 23.14,47.47 ML13.4 23.79,47.47 24.07,47.19 25.96,47.19 v1(26.11,47.35)
USB3RP1_RC_CON: length 13.2
  BOTTOM w0.102: JUSB1.6 13.22,42.31 13.31,42.22 13.79,42.22 14.37,42.8 15.65,42.8 17.16,44.31 17.16,46.2 17.52,46.55 17.77,46.55 17.96,46.74 DI1.2 DI1.9 19.9,46.74 20.03,46.61 20.24,46.61 20.82,47.18 21.22,47.18 21.5,47.47 ML13.3 22.13,47.47 R565.2
USB3TN0: length 138.1
  IN1 w0.071: 133.06,74.43 133.06,74.45 133.07,74.45 133.07,74.49 133.48,74.91 135.89,74.91 136.57,75.59 148.29,75.59 148.72,76.01 157.52,76.01 160.13,78.62 165.33,78.62 168.3,75.66 174.3,75.66 174.57,75.93 180.44,75.93 180.59,75.77 184.94,75.77 185.38,76.22 189.75,76.22 192.76,73.21 193.73,73.21 195.66,71.28 195.66,53.49 199.13,50.02 199.13,48.64 202.81,44.97 202.81,37.82 202.59,37.6 202.59,36.4 205.16,33.83 205.16,26.85 205.41,26.6 205.41,23.22 204.4,22.22 204.4,18.76 204.73,18.43 208.05,18.43 208.3,18.17 208.3,17.64 208.4,17.54 208.4,17.4 208.46,17.34 v1(208.6,17.34) ; v1(132.83,73.6) 133.06,73.82
  IN1 w0.076: 133.06,74.43 133.06,73.83 133.06,73.82
  BOTTOM w0.076: UCPU1.C33 131.88,71.18 131.5,71.56 131.5,72.23 131.17,72.55 131.17,73.45 131.77,74.04 132.99,74.04 133.15,73.88 133.15,73.71 133.04,73.6 v1(132.83,73.6)
  BOTTOM w0.102: JIO1.8 208.6,17.96 208.41,17.78 208.41,17.52 v1(208.6,17.34)
USB3TN1: length 134.6
  IN1 w0.071: v1(25.99,50.63) 25.28,50.63 24.52,51.39 24.52,60.85 31.68,68 42.82,68 47.91,73.1 49.17,73.1 49.78,73.71 54.26,73.71 54.87,73.1 61.9,73.1 63.36,71.64 97.91,71.64 100.8,68.75 105.72,68.75 109.01,72.04 116.32,72.04 121.35,77.08 125.67,77.08 128.33,74.41 131.75,74.41 132.34,73.82 v1(132.34,73.32)
  BOTTOM w0.076: v1(132.34,73.32) 132.34,72.72 132.42,72.64 132.42,72.2 132.13,71.91 131.88,71.66 UCPU1.B33
  BOTTOM w0.102: C621.1 25.69,50.81 25.81,50.81 v1(25.99,50.63)
USB3TN1_C: length 2.1
  BOTTOM w0.102: C621.2 24.05,50.78 23.55,50.78 23.24,50.48 ML12.1 22.63,50.48 R555.1
USB3TN1_RC_CON: length 12.4
  BOTTOM w0.102: JUSB1.8 13.22,47.37 13.61,47.75 13.96,47.75 14.19,47.52 15.83,47.52 16.18,47.88 17.75,47.88 17.89,47.74 DI1.4 DI1.7 19.87,47.74 20.02,47.88 20.26,47.88 20.46,48.08 20.46,48.32 20.1,48.67 v7(20.1,49.31) 20.1,50.35 20.49,50.74 20.76,50.74 21.03,50.48 ML12.2 21.63,50.48 R555.2
USB3TP0: length 138.1
  IN1 w0.071: v1(208.02,17.34) 208.17,17.49 208.17,18.12 207.99,18.3 204.68,18.3 204.27,18.7 204.27,22.27 205.28,23.28 205.28,26.54 205.03,26.79 205.03,33.78 202.46,36.34 202.46,37.65 202.68,37.87 202.68,44.91 199,48.59 199,49.97 195.53,53.44 195.53,71.22 193.67,73.08 192.7,73.08 189.7,76.09 185.44,76.09 184.99,75.64 180.53,75.64 180.38,75.8 174.63,75.8 174.36,75.52 168.24,75.52 165.28,78.49 160.19,78.49 157.57,75.88 148.77,75.88 148.35,75.45 136.63,75.45 135.95,74.77 133.54,74.77 133.2,74.44 133.2,74.43 ; v1(133.61,73.6) 133.61,73.45 133.55,73.39 133.33,73.39 133.2,73.52
  IN1 w0.076: 133.2,73.52 133.2,74.43
  BOTTOM w0.076: v1(133.61,73.6) 133.33,73.87 133.33,73.95 133.06,74.23 131.7,74.23 130.99,73.52 130.99,72.47 131.31,72.15 UCPU1.B34
  BOTTOM w0.102: v1(208.02,17.34) 208.21,17.52 208.21,17.75 208,17.96 JIO1.10
USB3TP1: length 134.5
  IN1 w0.071: v1(25.99,51.21) 25.99,51.06 25.92,50.99 25.82,50.99 25.59,50.76 25.34,50.76 24.66,51.44 24.66,60.79 31.74,67.87 42.88,67.87 47.97,72.97 49.23,72.97 49.83,73.57 54.2,73.57 54.81,72.97 61.85,72.97 63.31,71.51 97.85,71.51 100.75,68.61 105.77,68.61 109.07,71.91 116.37,71.91 121.4,76.95 125.61,76.95 128.28,74.28 131.69,74.28 132.21,73.76 132.21,73.68 131.98,73.46 131.98,73.37 131.93,73.32 v1(131.76,73.32)
  BOTTOM w0.076: UCPU1.A33 131.88,72.16 131.92,72.11 132.07,72.11 132.24,72.28 132.24,72.57 132.16,72.65 132.16,72.97 131.98,73.14 131.98,73.26 131.92,73.32 v1(131.76,73.32)
  BOTTOM w0.102: C623.1 25.69,51.01 25.79,51.01 v1(25.99,51.21)
USB3TP1_C: length 2.1
  BOTTOM w0.102: C623.2 24.01,50.99 23.55,50.99 23.27,51.28 ML12.4 22.63,51.28 R556.1
USB3TP1_RC_CON: length 12.7
  BOTTOM w0.102: R556.2 21.62,51.28 ML12.3 20.92,51.28 20.59,50.95 20.38,50.95 v7(20.16,50.73) 19.89,50.47 19.89,49.58 19.87,49.56 19.87,49.05 19.89,49.03 19.89,48.59 20.25,48.23 20.25,48.17 20.17,48.09 19.94,48.09 19.8,48.24 DI1.6 DI1.5 17.87,48.24 17.71,48.08 16.1,48.08 15.74,47.73 14.28,47.73 13.22,48.78 JUSB1.9
USB20_N0: length 93.7
  IN1 w0.071: v4(181.05,17.23) 181.05,17.23 181.23,17.04 181.23,16.89 181.54,16.58 190,16.58 190.49,16.09 191.26,16.09 191.69,16.52 191.69,17.7 192.5,18.51 196.1,18.51 197.83,16.78 199.73,16.78 200.53,17.58 200.95,17.58 201.1,17.43 201.1,17.32 v1(200.87,17.08)
  IN4 w0.071: v4(181.05,17.23) 181.25,17.43 181.25,17.51 180.77,17.99 180.77,20.84 182.62,22.69 182.62,38.03 179.89,40.76 179.89,43.93 178.99,44.83 169.41,44.83 167.81,46.44 164.27,46.44 159.09,51.62 154.94,51.62 154.82,51.75 151.52,51.75 150.82,51.05 148.79,51.05 148.53,51.31 148.53,51.59 148.16,51.95 147.82,51.95 147.5,52.27 147.5,53.72 147.34,53.88 147.1,53.88 146.91,53.69 v1(146.91,53.57)
  BOTTOM w0.076: UCPU1.AN8 147.21,53.87 v1(146.91,53.57)
  BOTTOM w0.102: JIO1.34 200.8,17.96 201.03,17.73 201.03,17.25 v1(200.87,17.08)
USB20_N1: length 245.4
  IN4 w0.071: v1(148.3,53.29) 148.47,53.12 148.64,53.12 148.89,52.87 148.89,52.39 149.1,52.17 150.68,52.17 151.58,53.07 155.19,53.07 155.85,52.41 159.55,52.41 162.53,49.44 164.98,49.44 166.49,47.92 167.44,47.92 169.74,45.63 179.32,45.63 180.68,44.26 180.68,41.08 183.41,38.36 183.41,22.36 182.6,21.55 182.6,18.95 183.14,18.41 183.14,17.4 182.24,16.49 170.49,16.49 170.22,16.76 101.27,16.76 100.92,17.11 95.42,17.11 95.07,16.76 43.86,16.76 42.26,18.36 39.97,18.36 37.17,21.15 37.17,27.8 36.45,28.52 36.45,35.16 35.57,36.05 34.32,36.05 33.91,35.63 29.25,35.63 26.66,38.22 26.55,38.22 26.46,38.13 26.36,38.13 26.22,37.99 v1(26.22,37.89)
  BOTTOM w0.076: UCPU1.AR7 147.91,52.9 v1(148.3,53.29)
  BOTTOM w0.102: R222.1 25.31,40 ML11.4 26.26,39.95 26.91,39.3 26.91,38.22 26.7,38.01 26.33,38.01 v1(26.22,37.89)
USB20_N1_CONN: length 15.8
  IN1 w0.071: JUSB1.2 14.72,45.21 14.85,45.09 17.65,45.09 18.45,44.29 18.45,42.31 v1(18.66,42.09)
  BOTTOM w0.102: R222.2 24,39.95 ML11.3 23.24,39.95 22.92,39.62 22.85,39.62 22.63,39.84 22.19,39.84 DI2.2 21.33,39.94 21.23,39.84 20.94,39.84 19.8,40.98 18.63,40.98 18.48,41.13 18.48,41.91 v1(18.66,42.09)
USB20_N2: length 234.7
  IN4 w0.071: v1(29.08,37.98) 29.32,38.22 29.32,38.36 29.51,38.56 29.99,38.56 31.43,37.12 35.78,37.12 37.25,35.65 37.25,28.97 38,28.21 38,21.44 40.3,19.15 42.61,19.15 44.21,17.55 94.74,17.55 95.18,17.99 101.16,17.99 101.6,17.55 170.75,17.55 171.01,17.29 176.29,17.29 181.96,22.96 181.96,37.76 179.23,40.48 179.23,41.06 178.98,41.31 177.81,41.31 177.71,41.41 177.03,41.41 174.26,44.17 168.54,44.17 166.94,45.78 162.93,45.78 160.74,47.96 160.42,47.96 157.42,50.96 153.9,50.96 153.64,51.22 151.68,51.22 151.09,50.62 148.76,50.62 148.24,51.14 148.24,51.47 148.03,51.67 147.59,51.67 147.22,52.05 147.22,52.49 147.13,52.58 146.93,52.58 146.87,52.52 v1(146.87,52.33)
  BOTTOM w0.076: v1(146.87,52.33) 147.12,52.57 UCPU1.AR8
  BOTTOM w0.102: R742.1 31.32,35.85 ML10.4 31.21,35.96 30.64,35.96 30.55,36.05 30,36.05 29.09,36.97 29.09,37.97 v1(29.08,37.98)
USB20_N2_R: length 5.4
  BOTTOM w0.102: JNGFF1.5 32.75,37.88 32.68,37.81 32.68,37.67 32.76,37.59 33.36,37.59 34.02,36.93 34.32,36.62 34.32,36.35 v7(34.18,36.21) 34.03,36.06 33.57,36.06 33.43,35.91 ML10.3 32.63,35.91 R742.2
USB20_N3: length 90.5
  IN4 w0.071: v1(72.04,68.53) 72.29,68.78 72.29,68.96 72.49,69.17 74.33,69.17 76.37,67.13 80.51,67.13 81.27,67.89 97.96,67.89 101.17,64.68 101.17,63.15 105.61,58.72 106.24,58.72 107.65,57.32 110.53,57.32 111.55,58.33 116.1,58.33 116.65,57.78 121.47,57.78 122.92,59.23 141.36,59.23 142.52,58.06 142.84,58.06 143.36,57.54 143.36,56.55 145.58,54.33 145.58,53.45 145.92,53.11 146.16,53.11 v1(146.36,53.31)
  BOTTOM w0.076: v1(146.36,53.31) 145.95,52.9 UCPU1.AR10
  BOTTOM w0.102: R1012.1 70.71,70.07 ML9.1 71.5,70.07 71.58,70.15 71.58,70.34 71.66,70.42 72.13,70.42 72.26,70.29 72.26,68.74 v1(72.04,68.53)
USB20_N3_CONN: length 16.7
  BOTTOM w0.102: JTS.3 71.52,76.16 71.4,76.04 67.33,76.04 66.73,75.45 66.73,73.7 66.31,73.29 v7(66.31,72.67) 66.31,71.24 65.79,70.72 DI4.2 65.36,70.57 65.64,70.29 65.93,70.29 66.27,69.95 66.27,69.86 66.57,69.56 67.66,69.56 68.2,70.1 68.2,70.19 68.29,70.29 68.76,70.29 68.97,70.07 ML9.2 69.59,70.07 R1012.2
USB20_N4: length 84
  IN4 w0.071: v1(142.95,54.24) 142.73,54.45 142.5,54.45 142.22,54.73 142.22,56.18 141.68,56.72 141.68,57.7 141.5,57.88 139.51,57.88 138.87,58.53 123.35,58.53 121.98,57.16 112.74,57.16 112.12,56.53 108.05,56.53 107.89,56.37 107.31,56.37 105.75,57.93 105.02,57.93 100.32,62.62 100.32,64.4 97.65,67.07 81.62,67.07 80.88,66.34 75.34,66.34 74.11,67.57 71.96,67.57 v1(71.73,67.34)
  BOTTOM w0.076: UCPU1.AM15 143.24,54.53 v1(142.95,54.24)
  BOTTOM w0.102: R1005.1 70.56,67.07 L55.1 71.05,67.18 71.37,67.51 71.57,67.51 v1(71.73,67.34)
USB20_N4_CONN: length 18.2
  BOTTOM w0.102: JCAM.4 57,72.38 57.84,71.54 58.5,71.54 58.56,71.47 v7(59.42,71.47) 60.12,71.47 61.04,72.4 61.63,72.4 61.65,72.42 61.82,72.42 62.03,72.21 62.03,71.13 61.8,70.9 61.37,70.9 DI3.2 61.19,70.56 61.31,70.44 61.99,70.44 62.06,70.38 62.06,70.08 64.69,67.45 68.35,67.45 68.62,67.18 L55.2 69.26,67.18 R1005.2
USB20_P0: length 93.7
  IN1 w0.071: v4(181.58,17.23) 181.36,17.01 181.36,16.95 181.59,16.71 190.06,16.71 190.54,16.23 191.2,16.23 191.55,16.58 191.55,17.76 192.44,18.64 196.15,18.64 197.88,16.91 199.67,16.91 200.47,17.71 201.01,17.71 201.24,17.48 201.24,17.29 v1(201.45,17.08)
  IN4 w0.071: v4(181.58,17.23) 181.38,17.43 181.38,17.57 180.9,18.04 180.9,20.79 182.75,22.63 182.75,38.08 180.02,40.81 180.02,43.98 179.04,44.96 169.47,44.96 167.86,46.57 164.33,46.57 159.14,51.75 155,51.75 154.87,51.88 151.46,51.88 150.77,51.18 148.84,51.18 148.66,51.36 148.66,51.64 148.22,52.08 147.88,52.08 147.63,52.33 147.63,53.77 147.39,54.02 147.11,54.02 v1(146.93,54.19)
  BOTTOM w0.076: v1(146.93,54.19) 147.26,54.53 UCPU1.AM8
  BOTTOM w0.102: JIO1.32 201.4,17.96 201.24,17.81 201.24,17.29 v1(201.45,17.08)
USB20_P1: length 245.3
  IN4 w0.071: v1(148.3,52.59) 148.19,52.59 148.1,52.68 148.1,52.88 148.16,52.94 148.47,52.94 148.51,52.99 148.58,52.99 148.75,52.82 148.75,52.33 149.05,52.04 150.73,52.04 151.63,52.94 155.13,52.94 155.79,52.28 159.49,52.28 162.47,49.3 164.93,49.3 166.44,47.79 167.39,47.79 169.68,45.49 179.27,45.49 180.55,44.21 180.55,41.03 183.28,38.3 183.28,22.41 182.47,21.6 182.47,18.9 183.01,18.36 183.01,17.45 182.18,16.63 170.54,16.63 170.27,16.89 101.32,16.89 100.97,17.25 95.37,17.25 95.01,16.89 43.91,16.89 42.32,18.49 40.02,18.49 37.3,21.21 37.3,27.86 36.59,28.58 36.59,35.22 35.63,36.18 34.26,36.18 33.85,35.76 29.31,35.76 26.72,38.35 26.34,38.35 v1(26.22,38.47)
  BOTTOM w0.076: v1(148.3,52.59) 147.96,52.25 UCPU1.AT7
  BOTTOM w0.102: R262.1 25.31,39.06 ML11.1 25.94,39.1 25.98,39.14 25.98,39.68 26.03,39.74 26.17,39.74 26.7,39.21 26.7,38.3 26.61,38.22 26.48,38.22 v1(26.22,38.47)
USB20_P1_CONN: length 15.8
  IN1 w0.071: v1(18.08,42.09) 18.32,42.33 18.32,44.23 17.59,44.95 14.8,44.95 14.72,44.88 JUSB1.3
  BOTTOM w0.102: R262.2 24.01,39.1 ML11.2 23.26,39.1 22.95,39.41 22.77,39.41 22.55,39.63 22.19,39.63 DI2.3 21.33,39.53 21.23,39.63 20.86,39.63 19.72,40.77 18.54,40.77 18.27,41.04 18.27,41.91 v1(18.08,42.09)
USB20_P2: length 234.7
  IN4 w0.071: v1(29.66,37.98) 29.45,38.19 29.45,38.31 29.57,38.43 29.94,38.43 31.38,36.99 35.73,36.99 37.11,35.6 37.11,28.91 37.87,28.15 37.87,21.39 40.24,19.02 42.56,19.02 44.15,17.42 94.8,17.42 95.24,17.86 101.1,17.86 101.54,17.42 170.7,17.42 170.96,17.16 176.34,17.16 182.09,22.91 182.09,37.81 179.36,40.54 179.36,41.11 179.04,41.44 177.87,41.44 177.77,41.54 177.08,41.54 174.32,44.3 168.6,44.3 166.99,45.91 162.99,45.91 160.8,48.1 160.48,48.1 157.48,51.09 153.96,51.09 153.7,51.35 151.63,51.35 151.03,50.76 148.82,50.76 148.37,51.2 148.37,51.52 148.09,51.8 147.65,51.8 147.35,52.1 147.35,52.54 147.18,52.71 147.12,52.71 v1(146.89,52.94)
  BOTTOM w0.076: UCPU1.AP8 147.18,53.22 v1(146.89,52.94)
  BOTTOM w0.102: R741.1 31.55,36.76 ML10.1 30.92,36.76 30.42,36.26 30.12,36.26 v7(29.69,36.68) 29.3,37.08 29.3,37.61 v1(29.66,37.98)
USB20_P2_R: length 5.4
  BOTTOM w0.102: R741.2 32.67,36.76 ML10.2 33.46,36.76 33.61,36.61 33.61,36.4 33.74,36.26 33.91,36.26 34.12,36.47 34.12,36.54 33.27,37.38 32.67,37.38 32.47,37.58 32.47,37.65 32.25,37.88 JNGFF1.3
USB20_P3: length 90.6
  IN4 w0.071: v1(72.62,68.53) 72.42,68.73 72.42,68.91 72.55,69.03 74.27,69.03 76.31,67 80.57,67 81.33,67.76 97.91,67.76 101.04,64.62 101.04,63.1 105.55,58.59 106.19,58.59 107.59,57.18 110.58,57.18 111.6,58.2 116.05,58.2 116.6,57.65 121.52,57.65 122.97,59.1 141.3,59.1 142.47,57.93 142.79,57.93 143.23,57.49 143.23,56.49 145.45,54.27 145.45,53.39 145.86,52.98 146.24,52.98 146.34,52.87 v1(146.34,52.6)
  BOTTOM w0.076: v1(146.34,52.6) 146,52.25 UCPU1.AT10
  BOTTOM w0.102: R1013.1 70.67,70.92 ML9.4 71.44,70.92 71.74,70.63 72.21,70.63 72.46,70.38 72.46,68.68 v1(72.62,68.53)
USB20_P3_CONN: length 16.3
  BOTTOM w0.102: R1013.2 69.63,70.92 ML9.3 68.95,70.92 68.53,70.49 68.2,70.49 67.99,70.28 67.99,70.19 67.57,69.77 66.65,69.77 66.48,69.95 66.48,70.16 66.65,70.34 67.15,70.34 67.29,70.48 DI4.3 66.72,70.72 66.52,70.92 66.52,72.35 66.54,72.37 66.54,73.01 66.52,73.03 66.52,73.2 66.94,73.62 66.94,75.36 67.41,75.83 71.05,75.83 71.52,75.36 JTS.2
USB20_P4: length 84.2
  IN4 w0.071: v1(142.95,54.92) 142.95,54.7 142.84,54.59 142.55,54.59 142.35,54.79 142.35,56.23 141.81,56.78 141.81,57.75 141.55,58.01 139.57,58.01 138.92,58.66 123.29,58.66 121.92,57.29 112.69,57.29 112.06,56.66 108,56.66 107.84,56.5 107.37,56.5 105.81,58.06 105.07,58.06 100.45,62.68 100.45,64.45 97.7,67.2 81.56,67.2 80.83,66.47 75.39,66.47 74.16,67.7 71.96,67.7 v1(71.73,67.93)
  BOTTOM w0.076: UCPU1.AL15 143.37,55.18 143.12,54.92 v1(142.95,54.92)
  BOTTOM w0.102: R1004.1 70.63,68.09 L55.4 71.07,68.03 71.39,67.71 71.52,67.71 v1(71.73,67.93)
USB20_P4_CONN: length 17.8
  BOTTOM w0.102: JCAM.5 57.8,71.87 57.93,71.74 58.59,71.74 58.65,71.68 59.04,71.68 59.06,71.7 59.67,71.7 59.7,71.68 60.03,71.68 60.98,72.63 v7(61.28,72.63) 61.91,72.63 62.24,72.3 62.24,70.92 62.37,70.79 63.06,70.79 DI3.3 63.12,70.62 62.98,70.48 62.32,70.48 62.27,70.42 62.27,70.17 64.78,67.66 68.28,67.66 68.65,68.03 L55.3 69.32,68.03 R1004.2
USB_OC0#: length 100.7
  TOP w0.089: T289.1 151.45,55.51 v1(151.29,55.68)
  IN1 w0.071: v4(166.84,51.18) 166.84,52.69 167.23,53.07 167.23,55.37 168.31,56.45 168.31,57.02 v4(168.11,57.21) 168.05,57.15 168.05,56.83 167.7,56.47 166.11,56.47 165.67,56.91 162.18,56.91 161.12,55.85 157.3,55.85 156.72,55.28 154.01,55.28 153.67,55.61 151.35,55.61 v1(151.29,55.68)
  IN4 w0.071: v1(204.23,17.1) 203.4,16.26 202.2,16.26 201.64,15.71 199.45,15.71 198.54,16.61 197.99,16.61 197.79,16.4 197.79,14.8 196.67,13.68 187.97,13.68 185.5,16.15 185.5,17.21 184.4,18.3 184.4,38.67 181.79,41.29 181.79,44.47 179.69,46.56 174.53,46.56 173.72,47.37 172.47,47.37 172.26,47.15 170.75,47.15 169.17,48.73 167.97,48.73 167.07,49.63 167.07,50.95 v4(166.84,51.18)
  GND3 w0.102: v4(168.11,57.21) 168.11,57.56 v5(168.3,57.75)
  BOTTOM w0.076: v1(151.29,55.68) 151.25,55.64 151.25,55.18 151.1,55.04 150.54,55.04 150.3,55.27 UCPU1.AL3
  BOTTOM w0.102: JIO1.24 203.8,17.92 203.95,17.76 203.95,17.38 v1(204.23,17.1)
USB_OC1#: length 226
  TOP w0.102: v1(35.15,48.97) 34.74,48.57 31.36,48.57 30.46,49.46 25.84,49.46 24.95,48.57 23.84,48.57 23.14,47.88 23.14,45.08 22.83,44.77 US2.5 ; T290.1 158.01,49.75 158.01,50.47 157.42,51.06 156.85,51.06 155.4,52.51 v1(154.22,52.51)
  IN1 w0.071: v4(170.36,48.33) 169.78,48.91 166.23,48.91 165.6,49.54 165.13,50.01 161.73,50.01 159.15,52.59 154.39,52.59
  IN1 w0.076: 154.39,52.59 154.3,52.59 v1(154.22,52.51)
  IN3 w0.086: v4(170.36,48.33) 170.36,49.05 171.35,50.05 171.35,50.73 170.73,51.36 170.73,54.29 168.75,56.27 v4(168.75,56.8)
  IN4 w0.071: v1(154.22,52.51) 153.88,52.17 151.54,52.17 150.7,51.33 148.9,51.33 148.81,51.43 148.81,51.71 148.28,52.23 148.07,52.23 147.88,52.42 147.88,54.33 147.27,54.94 147.27,57.16 145.89,58.54 145.43,58.54 143.36,60.61 138.16,60.61 137.62,60.08 121.14,60.08 119.47,58.42 116.76,58.42 116.13,59.04 116.13,62.37 113.59,64.91 110.56,64.91 109.48,65.99 107.19,65.99 106.61,66.57 106.61,69 105.18,70.43 102.59,70.43 100.17,72.85 99.69,72.85 98.68,73.86 97.02,73.86 96.77,74.12 89.56,74.12 88.72,73.27 79.93,73.27 78.36,74.85 75.08,74.85 74.31,75.62 67.49,75.62 67.07,75.19 57.24,75.19 56.11,74.06 54.89,74.06 50.04,69.2 50.04,66.94 50.53,66.46 50.53,62.65 50.16,62.28 50.16,57.39 49.22,56.45 49.22,51.47 43.3,45.55 43.3,44.76 42.42,43.89 41.32,43.89 39.24,41.8 35.35,41.8 35.15,42 v1(35.15,48.97)
  GND3 w0.102: v4(168.75,56.8) 168.68,56.86 168.38,56.86 v5(168.34,56.83)
  BOTTOM w0.102: UCPU1.AT1 151.85,52.28 152.44,51.69 153.4,51.69 v1(154.22,52.51) ; RP21.2 168.38,58.25 168.6,58.25 168.83,58.02 168.83,57.31 v5(168.34,56.83)
USB_OC2#: length 19.9
  BOTTOM w0.076: T291.1 153.33,56.34 153.02,56.34 152.66,56.69 152.45,56.69 151.87,57.27 151.41,57.27 151.4,57.26 151.4,57.26 UCPU1.AH2
  BOTTOM w0.102: T291.1 154.19,55.47 154.19,55.42 154.39,55.23 154.46,55.16 156.13,55.16 157.21,56.23 159.92,56.23 161.29,57.61 161.74,57.61 162.11,57.97 163.81,57.97 163.99,58.15 167,58.15 167.6,58.75 168.3,58.75 RP21.3
USB_OC3#: length 38.3
  IN2 w0.086: v1(155.04,48.38) 157.38,46.03 159.9,46.03 160.52,45.42 163.01,45.42 163.46,45.87 v4(167.59,45.87)
  IN3 w0.086: v4(168.46,59.67) 168.61,59.52 168.61,57.16 168.33,56.88 168.33,56.42 170.54,54.21 170.54,51.28 171.16,50.66 171.16,50.12 168.03,46.99 168.03,46.3 v4(167.59,45.87)
  GND3 w0.102: v4(168.46,59.67) 168.33,59.54 168.31,59.54 168.3,59.54 v5(168.3,59.25)
  BOTTOM w0.076: UCPU1.AV3 150.28,50.9 150.61,50.57 150.61,49.84 150.67,49.79 150.67,49.37 150.98,49.06 152.2,49.06 152.37,49.22 153.27,49.22
  BOTTOM w0.102: T292.1 155.54,48.38 v1(155.04,48.38) 155.03,48.38 154.18,49.22 153.27,49.22
USB_PWR_SHR_EN#: length 87.6
  TOP w0.102: UE5.B38 178.55,68.24 v1(179.06,67.73) ; v2(204.22,16.07) v1(205.87,17.73)
  IN2 w0.086: v4(187.47,36.07) 187.49,36.09 187.49,36.6 185.26,38.83 184.11,38.83 180.67,42.27 180.67,48.14 180.13,48.69 180.13,49.85 179.04,50.94 179.04,53.75 178.36,54.43 178.36,57.99 178.34,58.01 178.34,59.7 178.98,60.34 178.98,62.57 180.01,63.59 180.01,65.6 179.06,66.55 v1(179.06,67.73)
  IN4 w0.071: v1(205.87,17.73) 204.32,17.73 203.83,17.23 203.83,16.94 203.34,16.46 202.14,16.46 201.56,15.88 199.52,15.88 198.61,16.79 197.93,16.79 197.62,16.48 197.62,14.87 196.6,13.86 188.04,13.86 185.76,16.14 185.76,19.1 185.01,19.85 185.01,25.7 186.77,27.45 186.77,32.95 187.22,33.41 187.22,35.82 v4(187.47,36.07)
  BOTTOM w0.102: v1(205.87,17.73) 205.6,18 JIO1.18
USBRBIAS: length 2.9
  TOP w0.076: v1(145.01,55.68) 144.77,55.44 v2(144.77,55.24) 144.82,55.19 RH163.1
  BOTTOM w0.076: UCPU1.AJ10 UCPU1.AJ11 145.01,56.02 v1(145.01,55.68)
V_DDR_REF_CA: length 45.4
  IN3 w0.508: v1(121.4,52.52) 122.56,51.36 122.56,45.44 121.98,44.86 121.98,43.17 123.22,41.92 125.3,41.92 130.78,36.45 130.78,22.58 129.34,21.15 125.73,21.15 v4(124.43,19.84)
  GND3 w0.508: v5(124.43,19.43) v4(124.43,19.84)
  BOTTOM w0.254: UCPU1.AP49 121.84,53.41 121.4,52.97 v1(121.4,52.52)
  BOTTOM w0.508: CD43.1 v5(124.43,19.43)
V_DDR_REF_DQA: length 48.2
  IN3 w0.508: v1(120.36,52.4) 120.22,52.26 120.22,47.78 121.37,46.64 121.37,42.92 122.97,41.31 125.05,41.31 130.15,36.21 130.15,22.82 129.09,21.76 125.48,21.76 123.56,19.84 v4(120.11,19.84)
  GND3 w0.508: v5(120.11,19.43) v4(120.11,19.84)
  BOTTOM w0.254: v1(120.36,52.4) 120.49,52.4 UCPU1.AR51
  BOTTOM w0.508: v5(120.11,19.43) RD121.2
V_DDR_REF_DQB: length 41
  IN3 w0.508: v1(120.45,53.08) 120.2,53.08 119.63,52.51 119.63,47.53 120.76,46.4 120.76,42.66 122.71,40.71 124.8,40.71 129.53,35.97 v4(129.53,24.33)
  GND3 w0.508: v5(129.63,23.7) 129.63,24.23 v4(129.53,24.33)
  BOTTOM w0.254: UCPU1.AP51 120.78,53.41 v1(120.45,53.08)
  BOTTOM w0.508: CD39.1 130.98,19.56 130.6,19.94 RD20.2 130.38,20.68 130.38,22.95 v5(129.63,23.7)
VCI_IN3#: length 13.1
  TOP w0.102: RPE5.3 189.96,54.37 189.96,53.95 189.79,53.79 189.15,53.79 v3(188.73,54.21) 188.73,53.89 v2(188.32,53.49) ; UE5.B68 186.47,60.78 187,60.25 187.83,60.25 v1(188.2,60.62)
  GND1 w0.102: v4(188.88,53.86) 188.73,54 v3(188.73,54.21)
  IN3 w0.086: v4(188.88,53.86) 189.35,54.33 189.35,57.65 189.02,57.98 189.02,58.23 188.71,58.53 188.71,60.11 188.21,60.62 v1(188.2,60.62)
VR_ON: length 60.2
  TOP w0.089: RC151.1 112.04,69.47 110.07,69.47
  TOP w0.102: 110.07,69.47 109.89,69.29 RC201.2 108.65,70.09 108.65,72.13 v2(109.04,72.51) 109.51,72.98 v1(109.71,72.98)
  IN3 w0.086: v1(109.71,72.98) 108.19,72.98 106.14,70.93 102.83,70.93 100.68,73.08 100.26,73.08 99.8,72.63 81.11,72.63 79.49,74.25 73.83,74.25 v4(73.35,74.73)
  GND3 w0.102: v4(73.35,74.73) 73.35,74.61 v5(73.56,74.39)
  BOTTOM w0.254: v5(73.56,74.39) 74.43,73.53 74.43,71.9 73.89,71.37 73.89,67.78 72.15,66.04 PR716.2
VR_ON_MCP: length 3.5
  TOP w0.076: v2(115.37,68.32) 115.37,68.42 114.59,69.2 v1(114.59,69.2)
  TOP w0.089: v1(114.59,69.2) 114.13,69.66 113.91,69.66 113.54,69.29 RC151.2
  BOTTOM w0.076: v1(114.59,69.2) 114.93,68.87 UCPU1.F60
VR_SVID_ALRT#: length 51.6
  IN2 w0.086: v1(104.28,68.13) 103.25,68.13 102.97,68.41 99.29,68.41 98.09,69.61 85.78,69.61 82.21,66.05 78.31,66.05 76.97,64.71 76.97,64.19 74.73,61.95 74.73,58.34 v1(74.96,58.12)
  BOTTOM w0.102: RC94.1 103.47,67.95 102.74,68.68 101.21,68.68 101.08,68.81 101.08,69.19 101.21,69.32 102.38,69.32 102.51,69.45 102.51,69.75 102.38,69.88 101.21,69.88 101.08,70 101.08,70.59 101.21,70.72 v2(102.39,70.72) 103.19,70.72 103.32,70.59 RC93.1 103.32,69.1 v1(104.28,68.13) ; v1(74.96,58.12) 75.48,58.64 PU700.32
VR_SVID_CLK: length 48.1
  IN2 w0.086: v1(102.75,67.87) 99.07,67.87 97.87,69.07 86,69.07 82.35,65.42 79.09,65.42 75.28,61.61 75.28,60.07 75.59,59.76 v1(75.59,58.18)
  BOTTOM w0.102: PR726.2 74.91,55.35 74.91,55.74 74.81,55.84 73.79,55.84 73.69,55.94 73.69,56.14 73.79,56.25 74.81,56.25 74.91,56.35 74.91,56.55 74.81,56.65 73.42,56.65 73.3,56.77 73.3,56.94 73.42,57.06 v2(74.1,57.06) 74.81,57.06 74.91,57.16 74.91,57.37 75.59,58.05 v1(75.59,58.18) 75.88,58.47 PU700.31 ; RC92.1 102.49,65.6 102.49,67.61 v1(102.75,67.87)
VR_SVID_DAT: length 47.7
  IN2 w0.086: v1(104.87,68.13) 104.87,68.59 104.78,68.68 103.47,68.68 103.2,68.95 99.52,68.95 98.32,70.16 84.48,70.16 80.94,66.62 78.1,66.62 74.19,62.71 74.19,59.51 v1(74.13,59.45)
  BOTTOM w0.102: PR727.2 73.23,55.48 72.65,55.48 72.52,55.6 v2(72.52,56.32) 72.52,57.51 72.65,57.63 73.79,57.63 73.92,57.76 73.92,58.56 74.05,58.69 74.73,58.69 74.86,58.82 74.86,59.03 74.73,59.16 74.3,59.16 74.13,59.32 v1(74.13,59.45) 74.39,59.7 PU700.1 ; RC96.1 105.43,67.55 104.87,68.11 v1(104.87,68.13)
VREF: length 36.3
  TOP w0.102: v2(79.13,65.59) 79.02,65.48 v1(78.45,65.48)
  IN1 w0.254: v1(88.56,63.12) 88.23,63.45 88.23,65.23 87.47,65.99 82.38,65.99 81.87,65.48 v1(78.45,65.48) 77.69,65.48 77.18,64.97 77.18,64.09 78.71,62.56 78.71,58.94 v7(77.69,57.93)
  BOTTOM w0.203: PU700.27 77.48,58.13
  BOTTOM w0.254: PH700.1 v1(88.56,63.12) ; PR718.2 79.67,56.45 PC713.1 78.96,57.42 78.58,57.8 77.82,57.8 v7(77.69,57.93) 77.48,58.13 ; PR704.1 PR703.1 PR702.1 75.02,66.63 75.4,67.01 78.83,67.01 79.09,66.75 PR700.1 78.53,66.19 78.45,66.12 v1(78.45,65.48)
VRPG_MCP: length 7.9
  BOTTOM w0.076: 115.2,72.49 115.21,72.48 115.21,71.85 115.41,71.65 115.41,71.51 115.57,71.34 115.57,71.11 UCPU1.C59
  BOTTOM w0.102: 115.2,72.49 115.2,72.68 114.49,73.38 112.26,73.38 111.43,74.21 111.43,75.02 RC152.2
VSET_5085: length 4.2
  TOP w0.102: v2(188.83,72.01) 188.18,72.65 RE77.1 CE55.1 187.29,72.61 186.22,71.54 UE5.A17
VTTREF_1.35V: length 2.6
  BOTTOM w0.203: PU600.4 v2(73.1,46.01) 73.1,45.53 PC610.1
WLAN_WIGIG60GHZ_DIS#: length 38.7
  TOP w0.102: RE14.2 38.56,14.11 v2(38.09,14.11) v3(36.92,14.11) ; v1(46.58,42.15) DZ1.1
  GND1 w0.102: v4(36.52,13.81) 36.83,14.11 v3(36.92,14.11)
  IN1 w0.071: v1(46.58,42.15) 46.23,41.8 45.22,41.8 43.92,40.51 42.63,40.51 42.19,40.08 42.19,38.16 42.95,37.4 42.95,27.41 43.16,27.2 43.16,26.18 42.19,25.21 42.19,22.72 36.52,17.05 v4(36.52,13.81)
  GND3 w0.102: v4(36.52,13.81) v5(36.52,14.18)
WLAN_WIGIG60GHZ_DIS#_R: length 3.6
  TOP w0.102: DZ1.2 46.58,44.63 v1(46.6,44.65) 46.58,44.68 v2(46.58,45.26)
  BOTTOM w0.102: v1(46.6,44.65) 46.05,44.65 45.5,45.21 45.5,46.32 JNGFF1.48
WLANCLK_REQ#: length 148.3
  IN2 w0.086: 110.07,71.93 107.72,71.93 106.46,70.68 100.95,70.68 99.69,71.93 81.68,71.93 79.43,69.69 58.52,69.69 58.11,69.27 53.63,69.27 53.14,68.79 53.14,65.79 50.59,63.24 50.59,59.23 48.26,56.89 48.26,51.4 42.66,45.81 v1(42.66,45.13)
  IN2 w0.089: 110.07,71.93 113.19,71.93 113.78,71.34 130.17,71.34 130.54,70.97 132.15,70.97 132.66,71.48 139.28,71.48 140.1,70.65 141.29,70.65 141.45,70.81 147.61,70.81 148,70.41 148,69.65 147.67,69.32 147.45,69.32 147.01,68.87 147.01,67.12 146.71,66.83 146.71,66.42 146.96,66.18 147.16,66.18 147.3,66.04 148.53,66.04 148.94,65.63 152.66,65.63 v1(152.77,65.53)
  BOTTOM w0.089: UCPU1.N1 152.3,65.06 v1(152.77,65.53) 153,65.76 153.9,65.76 153.9,65.76 154.13,65.76 154.14,65.76 154.53,65.76
  BOTTOM w0.102: RH103.2 154.87,65.76 154.53,65.76 ; JNGFF1.45 44.75,38.77 44.75,41.5 44.11,42.14 44.11,43.68 v1(42.66,45.13)
XCLK_BIASREF: length 7.8
  TOP w0.076: v1(139.41,72.91) 139.19,72.69 138.26,72.69 138.16,72.79 v2(138.16,73.12) 138.16,73.35 138.42,73.61 RH113.1
  BOTTOM w0.076: v1(139.41,72.91) 137.53,72.91 137.23,72.61 137.23,71.49 137.02,71.29 136.75,71.29 136.33,70.87 UCPU1.C26
XDP_BPM0#: length 51.9
  GND1 w0.102: v3(70.41,76.22) 70.41,76.69 v4(70.42,76.69)
  IN4 w0.071: v4(70.42,76.69) 71.04,76.06 74.25,76.06 74.88,76.7 77.63,76.7 80.25,74.07 88.39,74.07 89.72,75.4 96.23,75.4 96.4,75.22 99.63,75.22 101.11,73.74 101.11,73.56 103.07,71.59 105.67,71.59 107.86,69.4 107.86,68.42 108.67,67.61 109.1,67.61 v1(109.75,66.96)
  BOTTOM w0.076: UCPU1.J60 114.63,67.01 114.15,67.01 114.12,67.05 113.33,67.05 113.17,66.89 112.66,66.89 112.66,66.88 112.17,66.88 111.67,67.38 v2(111.18,67.38) 110.16,67.38 110.07,67.28 110.07,67.27
  BOTTOM w0.102: 110.07,67.27 v1(109.75,66.96)
XDP_BPM1#: length 54.1
  TOP w0.076: v2(115.96,67.09) 115.27,67.09 114.64,67.72 v1(114.63,67.72)
  GND1 w0.102: v4(69.8,76.69) 69.91,76.58 v3(69.91,76.22)
  IN4 w0.071: v1(114.63,67.72) 114.28,67.37 113.18,67.37 112.52,68.03 109.51,68.03 109.38,68.15 108.51,68.15 108.14,68.53 108.14,69.51 105.78,71.87 103.19,71.87 101.38,73.67 101.38,73.86 99.74,75.5 96.52,75.5 96.34,75.68 89.61,75.68 88.28,74.34 80.37,74.34 77.74,76.97 74.77,76.97 74.14,76.34 71.35,76.34 70.64,77.05 70.16,77.05 v4(69.8,76.69)
  BOTTOM w0.076: v1(114.63,67.72) 114.93,68.02 UCPU1.H60
XDP_PIN60: length 43.2
  TOP w0.102: R1198.1 70.18,79.59 v2(70.1,79.51) 70.1,79.03 v1(68.81,77.75) ; JXDP.60 60.91,70.39 60.91,69.46 59.85,68.4 v1(59.25,68.4)
  IN4 w0.071: v1(68.81,77.75) 68.81,77.68 66.87,75.74 61.7,75.74 60.8,76.64 58.64,76.64 v1(58.25,76.25)
  BOTTOM w0.102: v1(58.25,76.25) 58.25,78.51 57.75,79 54.59,79 54.22,78.63 54.22,73.5 52.76,72.04 52.76,70.61 53.33,70.04 53.33,67.81 53.61,67.53 54.07,67.53 54.3,67.76 58.86,67.76 59.25,68.16 v1(59.25,68.4)
XDP_PRDY#: length 45.7
  GND1 w0.102: v4(75.14,76.34) 75.02,76.22 v3(74.41,76.22)
  IN4 w0.071: v4(75.14,76.34) 75.16,76.34 75.25,76.42 77.51,76.42 80.14,73.8 88.51,73.8 89.35,74.63 95.81,74.63 96.12,74.95 99.51,74.95 100.84,73.63 100.84,73.44 102.96,71.32 105.55,71.32 107.59,69.28 107.59,68.3 108.56,67.33 108.67,67.33 v1(109.12,66.88)
  BOTTOM w0.076: UCPU1.J62 113.39,67.34 113.1,67.05 112.59,67.05 112.59,67.05 112.25,67.05 111.64,67.66 110.86,67.66
  BOTTOM w0.109: 110.86,67.66 110.81,67.71 109.89,67.71 T263.1 109.47,67.29 109.47,67.23 v1(109.12,66.88)
XDP_PREQ#: length 47.2
  TOP w0.076: 110.36,67.81 110.09,67.54 110.07,67.54
  TOP w0.089: v1(113.95,66.21) 113.95,66.56 112.7,67.81 110.36,67.81
  TOP w0.102: 110.07,67.54 108.6,67.54 107.99,66.94 v1(107.99,66.93)
  GND1 w0.102: v4(75.37,75.79) 75.21,75.94 v3(74.92,75.94)
  IN4 w0.071: v4(75.37,75.79) 75.47,75.89 77.8,75.89 80.07,73.62 88.57,73.62 89.42,74.46 95.88,74.46 96.2,74.78 99.44,74.78 100.66,73.56 100.66,73.37 102.89,71.15 105.48,71.15 107.42,69.21 107.42,68.23 107.99,67.65 v1(107.99,66.93)
  BOTTOM w0.076: UCPU1.K62 113.63,66.53 v1(113.95,66.21)
  BOTTOM w0.102: T264.1 107.84,66.78 v1(107.99,66.93)
XDP_PWRGD: length 55.8
  TOP w0.102: JXDP.39 65.91,75.16 v1(65.53,74.77)
  IN3 w0.086: v1(65.53,74.77) 66.04,74.26 72.72,74.26 72.99,74.53 72.99,74.93 73.26,75.2 74.38,75.2 75.04,74.54 79.73,74.54 81.07,73.19 99.71,73.19 v1(99.92,73.39)
  BOTTOM w0.102: R1180.1 112.27,78.34 v2(111.58,79.02) 102.46,79.02 99.32,75.88 99.32,73.99 v1(99.92,73.39)
XDP_TCK0: length 5.4
  TOP w0.102: JXDP.57 61.41,78.19 RH411.1 RH374.1 RH446.1 v2(58.21,78.68)
XDP_TCK1: length 2.5
  TOP w0.102: JXDP.55 61.91,77.61 61.82,77.71 RH373.1
XDP_TDI: length 9.7
  TOP w0.102: RH414.1 RH371.1 56.8,72.23 61.31,72.23 61.91,71.62 JXDP.56 v2(61.91,68.69)
XDP_TDI_SWITCH: length 59.9
  TOP w0.102: RH413.1 75.62,79.57 76.13,79.57 v1(76.43,79.88)
  GND1 w0.102: v3(55.52,73.48) v4(55.11,73.48)
  IN2 w0.086: v4(55.11,73.48) 54.2,74.39 52.17,74.39 50.08,76.48 50.08,78.04 v1(50.6,78.56)
  IN4 w0.071: v1(91.56,79.78) 90.84,80.5 86.91,80.5 83.54,77.14 81.39,77.14 78.64,79.88 v1(76.43,79.88) 76.07,80.25 73.34,80.25 72.6,79.51 72.23,79.51 71.42,80.32 68.01,80.32 67.2,79.51 51.55,79.51 v1(50.6,78.56)
  BOTTOM w0.102: v1(91.56,79.78) 91.56,78.94 92.38,78.12 U663.10 v2(95.06,78.12)
XDP_TDO: length 60.2
  TOP w0.102: v3(73.04,78.81) 73.04,78.81 73.75,79.52 RH412.1 RH369.1 ; JXDP.52 62.92,70.49 62.92,71.93 61.57,73.28 57.59,73.28 v1(57.4,73.47)
  GND1 w0.102: v4(73.04,79.16) 73.04,78.81 v3(73.04,78.81)
  IN4 w0.071: v1(56.72,78.56) 56.72,78.57 57.31,79.16 67.34,79.16 68.16,79.98 71.28,79.98 72.09,79.16 v4(73.04,79.16) 73.76,79.88 75.66,79.88 76.2,79.33 78.7,79.33 81.24,76.79 83.69,76.79 87.05,80.15 87.86,80.15 88.57,79.43 90.62,79.43 v1(90.96,79.78)
  BOTTOM w0.102: v1(57.4,73.47) 56.86,73.47 56.48,73.85 56.48,78.32 v1(56.72,78.56) ; v2(90.96,80.36) v1(90.96,79.78) 90.96,77.38 92.13,76.21 U663.13
XDP_TMS: length 67.7
  TOP w0.102: v1(54.51,68.53) 54.75,68.29 56.72,68.29 v2(57.09,68.66) 57.28,68.85 57.28,70.85 RH372.1 56.75,72.02 61.19,72.02 61.41,71.8 JXDP.58
  IN4 w0.071: v1(90.09,79.84) 89.6,80.32 86.97,80.32 83.61,76.96 81.31,76.96 78.77,79.51 76.27,79.51 75.73,80.05 73.39,80.05 72.67,79.33 72.16,79.33 71.35,80.15 68.09,80.15 67.27,79.33 55.53,79.33 v1(54.63,78.43)
  BOTTOM w0.102: U663.7 89.19,78.12 90.09,79.02 v1(90.09,79.84) ; v1(54.51,68.53) 54.5,68.53 54,69.03 53.69,69.03 53.6,69.12 53.6,70.06 52.98,70.68 52.98,71.94 55.22,74.19 55.22,77.26 54.63,77.86 v1(54.63,78.43)
XDP_TRST#: length 51.1
  TOP w0.102: JXDP.54 62.41,71.99 61.56,72.85 57.35,72.85 57,73.2 v1(57,73.87)
  IN4 w0.071: v1(57.33,78.55) 57.77,78.99 67.41,78.99 68.23,79.8 71.2,79.8 72.2,78.81 73.49,78.81 74.09,79.41 75.45,79.41 75.71,79.16 78.63,79.16 81.17,76.62 83.76,76.62 86.57,79.43 v1(87.1,79.43)
  BOTTOM w0.102: v1(57.33,78.55) 56.71,77.93 56.71,74.16 v1(57,73.87) ; U663.4 86.92,76.21 86.66,76.48 86.66,77.94 v2(86.45,78.14) 86.45,78.79 v1(87.1,79.43)
XTAL24_IN: length 12.7
  TOP w0.102: v1(137.4,73.57) 136.68,74.29 136.68,74.56 v2(136.89,74.77) 137.13,75.01 137.13,76.69 136.66,77.15 RH117.2 134.4,77.15 134.37,77.18 CH23.1 133.58,77.55 130.97,77.55 YH2.3
  BOTTOM w0.076: UCPU1.A25 136.89,72.61 137.4,73.12 v1(137.4,73.57)
XTAL24_OUT: length 11.9
  TOP w0.102: YH2.1 133.53,78.46 CH24.1 133.98,78.07 RH117.1 135.23,77.74 136.87,77.74 137.76,76.85 v2(137.76,76.56) 137.76,74.52 v1(137.4,74.16)
  BOTTOM w0.076: UCPU1.B25 136.61,71.9 136.61,72.57 137.04,73 137.04,73.81 v1(137.4,74.16)
N15438178: length 7.2
  TOP w0.102: v2(47.43,37.79) 47.27,37.64 PR207.1
  TOP w0.508: v1(45.88,35.61) 45.88,36.03 46.31,36.46 PR207.1
  BOTTOM w0.508: PD200.1 46.17,36.38 45.88,36.09 v1(45.88,35.61) 45.88,34.38 46.21,34.04 PD201.1
N15438615: length 1.6
  TOP w0.203: PR208.2 46.8,30.08 PU200.3
N15438635: length 18.3
  TOP w0.203: v1(47.15,28.65) 47.4,28.65 47.62,28.88 PU200.6
  TOP w0.254: PQ206.1 44.57,36.92 44.57,36.3 44.23,35.96 43.74,35.96 42.86,35.08 42.86,28.54 44.25,27.15 v2(44.25,27.14) 45.22,27.14 45.3,27.22 45.91,27.22 46.65,27.96 46.65,28.16 v1(47.15,28.65)
  BOTTOM w0.203: PR209.1 46.89,28.91 v1(47.15,28.65) 47.4,28.91 PC207.2 PR210.1
N15438982: length 14.8
  TOP w0.102: v2(45.51,27.66) 45.84,27.99 v1(45.84,28.09)
  TOP w0.203: PR213.2 46.71,29.1 47.34,29.1 47.52,29.28 48.04,29.28 PU200.5 ; PR212.2 52.67,31.95 v1(52.48,31.76)
  TOP w0.254: PR213.2 46.52,28.68 45.94,28.09 v1(45.84,28.09)
  IN1 w0.254: v1(52.48,31.76) 52.48,29.63 51.02,28.17 45.91,28.17 v1(45.84,28.09)
  BOTTOM w0.203: v1(52.48,31.76) PR215.1
N15439291: length 5
  TOP w0.102: PR214.2 46.73,26.94 v2(45.78,25.99)
  TOP w0.203: v1(47.15,27.66) 47.16,27.66 47.46,27.97 47.46,28.27 47.67,28.47 48.04,28.47 PU200.7
  TOP w0.254: PR214.2 46.73,27.24 v1(47.15,27.66)
  BOTTOM w0.203: v1(47.15,27.66) 47.15,27.19 47.35,26.99 PC216.2
N15439295: length 4.3
  TOP w0.102: PR217.2 47.84,25.63 47.66,25.82 v2(47.66,26.56)
  TOP w0.203: PU200.8 48.89,27.63 48.89,26.58 v1(48.67,26.37) 48.16,25.86 PR217.2
  BOTTOM w0.203: PC217.2 48.8,26.49 v1(48.67,26.37)
N15439512: length 6.7
  TOP w0.102: PR229.1 49.53,23.82 50.22,23.13 v2(50.22,22.95)
  TOP w0.203: PU200.9 49.29,27.62 49.29,26.51 v1(49.43,26.37) 49.31,26.24 PR218.2
  TOP w0.254: PR229.1 48.76,24.35 48.76,25.38 49.01,25.63 PR218.2
  BOTTOM w0.203: v1(49.43,26.37) 49.69,26.62 PC218.2
N15440461: length 2.2
  TOP w0.203: PU200.10 49.69,27.63 49.69,26.81 v2(49.98,26.52) 50.19,26.3 PR216.2
N15440728: length 11.9
  TOP w0.203: PU200.16 52.64,28.88 v1(53.24,28.27)
  TOP w0.254: v1(53.88,34.01) v2(53.88,34.94) 53.04,35.78 PR223.2
  BOTTOM w0.254: v1(53.88,34.01) 54.49,33.4 54.49,28.73 54.03,28.27 v1(53.24,28.27) 52.8,27.83 PR225.1
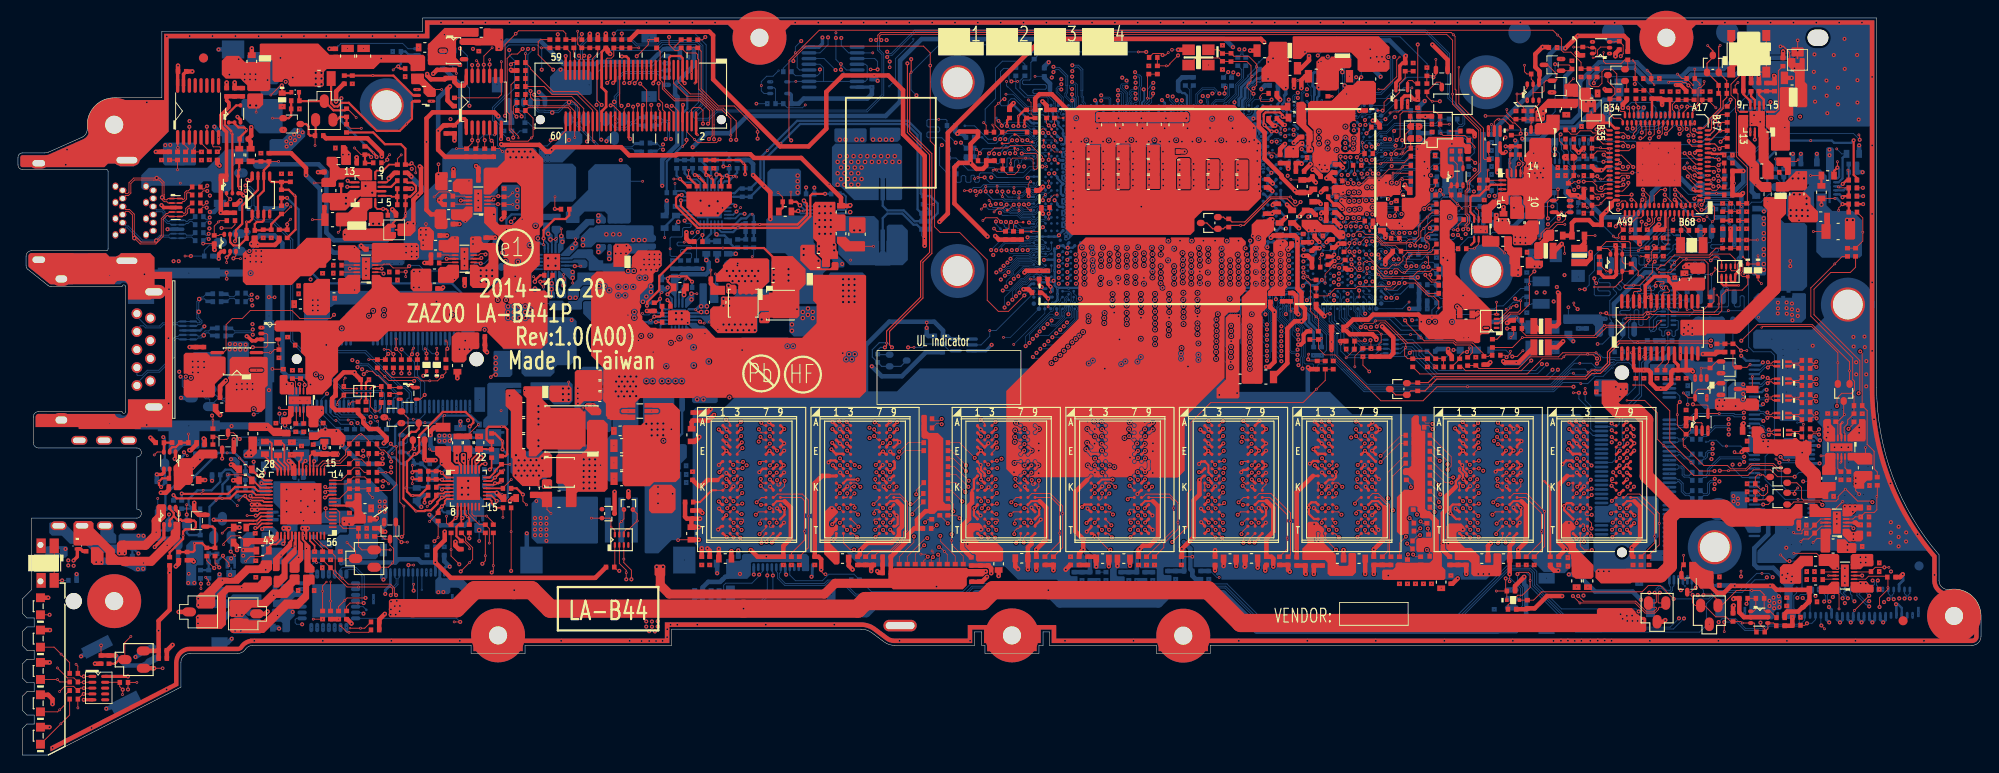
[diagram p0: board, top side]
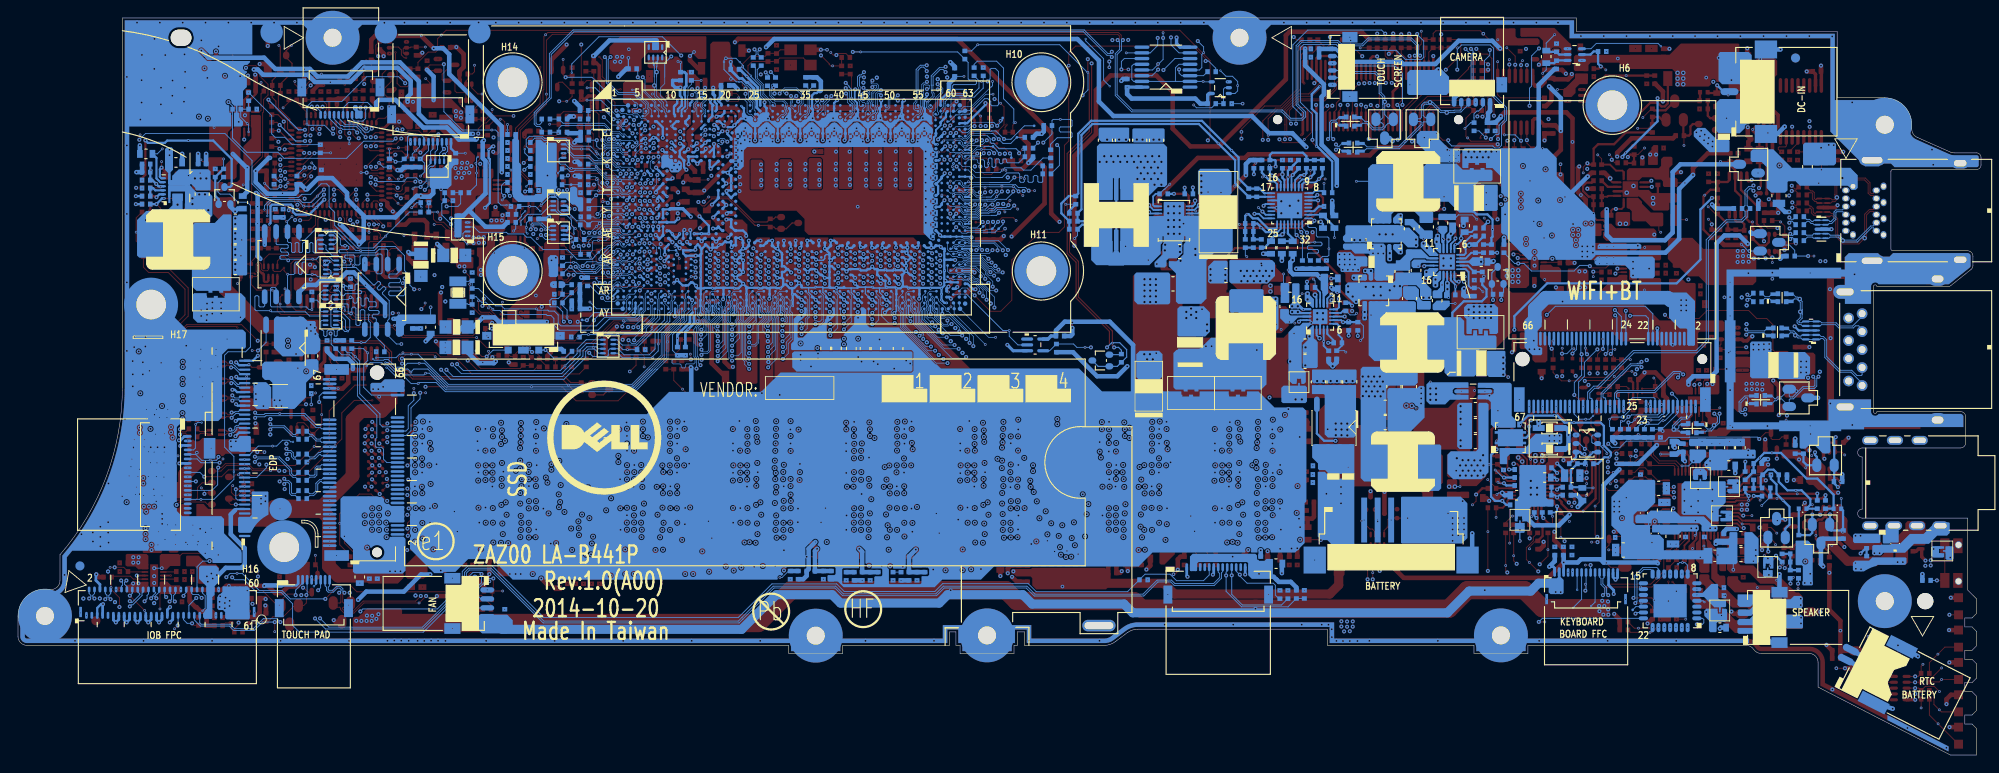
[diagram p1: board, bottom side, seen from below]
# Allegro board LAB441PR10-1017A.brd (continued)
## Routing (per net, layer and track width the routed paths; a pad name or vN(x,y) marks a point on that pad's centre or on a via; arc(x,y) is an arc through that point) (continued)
N15440949: length 3.4
  TOP w0.102: v2(53.93,26.44) PR224.2
  TOP w0.203: PR224.2 53.18,27.51 52.67,28.02 52.67,28.27 52.47,28.47 52.14,28.47 PU200.15
N15441413: length 3.2
  TOP w0.102: v2(54.86,30.64) 53.93,29.71 PR220.1
  TOP w0.203: PU200.18 53.92,29.68 PR220.1
N15442134: length 33.5
  TOP w0.203: v1(53.05,30.88) 52.65,30.47 52.27,30.47 52.26,30.48 PU200.20
  TOP w0.254: PC226.1 53.67,31.5 v1(53.05,30.88)
  GND1 w0.254: v3(67.85,38.27) v4(68.21,38.27)
  IN4 w0.254: v1(53.05,30.88) 53.17,30.76 53.93,30.76 54.58,30.11 54.58,29.61 56.23,27.95 68.74,27.95 69.37,28.59 69.37,34.85 68.94,35.29 68.94,38.04 68.72,38.27 v4(68.21,38.27)
  BOTTOM w0.102: v1(53.05,30.88) 53.17,30.88 54.01,31.71 v2(54.03,31.71)
  BOTTOM w0.254: v1(53.05,30.88) PC225.2
N15442185: length 33.5
  TOP w0.203: v1(53.05,30.24) 52.89,30.08 PU200.19
  TOP w0.254: v1(53.05,30.24) 53.42,30.24 PC226.2
  GND1 w0.254: v3(70.47,38.27) v4(70.11,38.27)
  IN4 w0.254: v1(53.05,30.24) 53.19,30.37 53.78,30.37 54.2,29.96 54.2,29.45 56.07,27.57 68.89,27.57 69.75,28.43 69.75,35 69.32,35.43 69.32,38.04 69.54,38.27 v4(70.11,38.27)
  BOTTOM w0.102: v2(53.73,30.35) 53.62,30.24 v1(53.05,30.24)
  BOTTOM w0.254: PC227.1 52.8,29.99 v1(53.05,30.24)
N17209367: length 1.7
  TOP w0.203: PU200.4 47.28,29.68 v1(47.15,29.54)
  BOTTOM w0.203: v1(47.15,29.54) 46.89,29.8 PR204.2
N17617073: length 24
  TOP w0.254: PR208.1 45.6,29.8 44.68,28.88 v2(43.91,28.88) 43.71,28.88 43.26,29.32 43.26,32.64 v1(44.1,33.48) 44.34,33.48 44.63,33.77 44.63,35.55 47.25,38.17 49.78,38.17 50.64,37.31 50.64,36.97 v1(50.23,36.56)
  BOTTOM w0.254: PC201.1 45.03,33.17 PQ202.4 44.58,33.7 44.36,33.48 v1(44.1,33.48) ; PQ201.4 50.59,35.3 50.23,35.66 v1(50.23,36.56)
N17617210: length 16.2
  BOTTOM w0.254: PQ201.2 50.38,37.77 47.11,37.77 46.32,36.98 v2(45.27,36.98) 42.31,36.98 41.94,36.61 41.94,34.44 41.17,33.66 41.17,33.32 41.37,33.12 41.89,33.12 42.6,32.41 PR203.1
N17617229: length 8.5
  BOTTOM w0.102: v2(43.13,29.71) PC200.2
  BOTTOM w0.254: PC200.2 44.42,29.8 PR204.1 45.61,31.7 44.9,32.41 PC201.2 PR203.2 44.02,32.83 43.14,33.7 PQ202.3
N17617792: length 3.7
  BOTTOM w0.102: PQ202.1 43.16,35.6 43.29,35.48 43.29,34.8 43.14,34.65 PQ202.2 42.59,34.65 41.61,33.68 v2(41.61,33.54)
N18244124: length 1.8
  TOP w0.102: PR221.2 58.83,27.33 v2(59.28,26.88)
N18292747: length 5.5
  TOP w0.102: v2(33.04,67.81) PR105.1
  TOP w0.254: PQ100.2 33.1,68.98 PR105.1 32.48,68.91 32.31,69.08 32.31,69.93 32.05,70.2 PQ101.1
N20931556: length 3.8
  TOP w0.203: v7(53.24,29.16) 53.13,29.28 52.14,29.28 PU200.17
  TOP w0.508: PR222.1 53.81,28.59 v7(53.24,29.16)
  BOTTOM w0.102: v7(53.24,29.16) 53.66,29.16 v2(53.84,28.98)
  BOTTOM w0.508: PC223.1 52.99,28.91 v7(53.24,29.16)
N22878624: length 8.2
  TOP w0.102: v2(37.61,70.93) 36.63,71.91 PR101.1
  TOP w0.254: PL102.1 31.25,72.84 PR104.2 31.35,72.75 PQ100.1 35.09,71.73 36.36,71.73 PR101.1
N22878630: length 4.3
  TOP w0.102: PR103.1 36.99,69.72 v2(38.18,69.72)
  TOP w0.254: PR103.1 36.54,70.99 PR101.2 35.81,70.99 35.48,70.66 PQ100.3
N22878645: length 3.9
  TOP w0.102: v2(28.3,70.85) PQ101.2
  TOP w0.254: PR104.1 PR106.2 30.39,71.12 30.11,70.85 PQ101.2
N35032609: length 2.8
  TOP w0.089: CH1206.1 149.72,59.36 148.89,59.36 v2(148.86,59.33) 148.22,59.33 v1(147.68,58.79)
  BOTTOM w0.254: v1(147.68,58.79) 147.67,58.78 UCPU1.AE7
N36180324: length 2
  TOP w0.076: CH1218.1 141.51,49.45 v2(141.57,49.39)
  TOP w0.508: RH346.2 CH1218.1
N40621945: length 3.7
  TOP w0.102: v2(192.63,43.47) 192.29,43.13 Q71.1 190.89,43.13 190.72,43.3 R536.2
N41482702: length 9.2
  TOP w0.102: 53.75,75.4 53.75,73.46 53.41,73.12 R1188.1 ; 53.75,75.4 53.75,75.4 v2(53.75,77.14) ; 53.75,75.4 U671.8
N42993790: length 2.2
  TOP w0.102: U679.C2 38.19,39.67 R1131.1 37.11,39.29 v2(36.86,39.05)
N45882743: length 0.9
  BOTTOM w0.102: RD120.1 CD76.2
N45903736: length 2.3
  BOTTOM w0.102: v2(133.58,19.76) 133.33,19.76 132.61,20.47 RD39.1
  BOTTOM w0.508: CD39.2 RD39.1
N45904045: length 0.9
  BOTTOM w0.508: RD40.1 CD43.2
N45914047: length 11.1
  TOP w0.102: RD29.1 87.89,23.05 v2(87.89,26.59) 87.89,28.38 87.24,29.03 84.45,29.03 84.07,28.65 UD28.L8
N45914636: length 9.7
  TOP w0.102: RD31.1 86.01,22.45 87.46,23.9 v2(87.46,24.89) 87.46,28.3 87.11,28.65 UD28.L9
N45918085: length 11.3
  TOP w0.102: RD30.1 95.69,22.59 97.09,22.59 98.66,24.16 98.66,24.73 98.9,24.98 98.9,28.19 98.05,29.03 97.06,29.03 96.68,28.65 UD29.L8
N45918691: length 10.6
  TOP w0.102: RD32.1 94.97,22.77 97.02,22.77 98.48,24.24 98.48,24.81 98.7,25.02 98.7,28.1 98.14,28.65 97.4,28.65 UD29.L9
N45921974: length 10.7
  TOP w0.102: UD31.L8 112.75,29.1 114.79,29.1 116.18,27.7 v2(116.18,26.87) 116.18,23.09 RD51.1
N45922752: length 9.5
  TOP w0.102: RD53.1 115.85,23.71 v2(115.85,24.68) 115.85,27.69 114.89,28.65 113.11,28.65 UD31.L9
N45924822: length 11.7
  TOP w0.102: UD32.L8 124.95,28.65 125.06,28.65 125.44,29.03 128.03,29.03 129,28.06 v2(129,25.88) 129,25.1 127.42,23.53 127.42,23.09 RD52.1
N45925462: length 10.4
  TOP w0.102: RD55.1 128.5,25.06 v2(128.5,27.47) 128.5,28.27 128.12,28.65 125.91,28.65 125.91,28.65 UD32.L9
N45927684: length 10.4
  TOP w0.102: RD11.1 169.78,23.22 v2(169.78,27.09) 167.77,29.1 166.35,29.1 165.9,28.65 UD1.L8
N45928611: length 9
  TOP w0.102: RD17.1 169.45,23.78 v2(169.45,24.86) 169.45,26.89 167.68,28.65 166.7,28.65 UD1.L9
N45930311: length 10
  TOP w0.102: RD12.1 141.52,22.33 v2(141.52,26.01) 141.52,26.93 139.35,29.1 138.03,29.1 137.58,28.65 UD7.L8
N45931155: length 8.6
  TOP w0.102: UD7.L9 138.38,28.65 139.22,28.65 141.15,26.72 v2(141.15,24.13) 141.15,22.91 RD19.1
N45933314: length 8.9
  TOP w0.102: RD41.1 152.53,22.21 152.53,27.83 151.26,29.1 150.64,29.1 UD3.L8
N45934478: length 7.7
  TOP w0.102: RD42.1 152.35,22.68 152.35,27.75 151.45,28.65 150.99,28.65 UD3.L9
N45936647: length 10.3
  TOP w0.102: RD54.1 181.39,22.25 182.53,23.39 v2(182.53,25.78) 182.53,26.85 180.34,29.03 179.04,29.03 178.66,28.65 UD4.L8
N45937458: length 8.7
  TOP w0.102: UD4.L9 179.34,28.65 180.05,28.65 182.01,26.7 v2(182.01,24.33) 182.01,23.59 180.5,22.08 RD56.1
N48029100: length 2.6
  TOP w0.102: v2(77.06,53.96) PC612.1
  TOP w0.508: PC612.1 77.06,52.47 PR602.2
N48038074: length 1.6
  TOP w0.102: PC409.1 v2(32.94,63.65)
N48057312: length 17.6
  TOP w0.254: v7(77.69,64.59) 78.07,64.59 78.38,64.28 v2(78.38,64.27) 78.2,64.09 PR705.1
  IN1 w0.254: v1(87.65,63.15) 87.85,63.35 87.85,65.07 87.31,65.61 82.55,65.61 82.05,65.1 78.71,65.1 78.2,64.59 v7(77.69,64.59)
  BOTTOM w0.203: 77.47,63.99 77.48,63.98 PU700.14
  BOTTOM w0.254: 77.47,63.99 77.69,64.21 v7(77.69,64.59) PC701.1 ; PH700.2 v1(87.65,63.15)
N48058030: length 6.8
  BOTTOM w0.203: 78.28,58.18 78.23,58.18 77.88,58.53 PU700.26
  BOTTOM w0.254: 78.28,58.18 79.53,58.18 v2(80.01,58.65) 80.48,59.13 PC709.2 PR719.2 80.93,58.23 PC712.2 PR718.1
N48058050: length 1.8
  TOP w0.102: PR717.2 v2(95.14,56.59)
N48058064: length 2.5
  TOP w0.102: PC707.1 85.04,62.06 v2(84.52,62.58)
  TOP w0.254: PC707.1 85.04,60.9 PR714.1
N48058078: length 7.3
  BOTTOM w0.203: PU700.25 78.28,58.69 78.41,58.56
  BOTTOM w0.254: 78.41,58.56 79.28,58.56 80.42,59.7 80.99,59.7 81.45,60.17 v2(81.64,60.17) 81.83,59.98 PC709.1 PR719.1 81.83,57.38 PR720.1
N48058128: length 4.7
  BOTTOM w0.102: PR715.1 v2(71.91,57.56)
  BOTTOM w0.203: 73.26,60.1 73.27,60.11 74.83,60.11 PU700.2
  BOTTOM w0.254: PR715.1 71.91,58.75 PC708.1 73.26,60.1
N48058201: length 2.7
  TOP w0.102: v7(86.77,60.53) v2(87.34,60.53)
  TOP w0.254: PR714.2 86.71,60.47 v7(86.77,60.53)
  BOTTOM w0.203: v7(86.77,60.53) 87.05,60.25 PU701.6
N48058203: length 3.5
  TOP w0.102: PC707.2 v2(85.96,62.63)
  TOP w0.254: PC707.2 86.58,61.55 v7(86.96,61.16)
  BOTTOM w0.203: v7(86.96,61.16) 87.48,60.65 PU701.7
N48058249: length 3.3
  BOTTOM w0.203: 77.08,58.37 PU700.28
  BOTTOM w0.254: PC714.1 PR721.2 76.55,57.48 77.08,58.02 77.08,58.37
N48058265: length 2.4
  BOTTOM w0.102: v2(101.79,61.28) PH701.2
  BOTTOM w0.254: PH701.2 101.39,60.57 PR725.1
N48058354: length 3.1
  BOTTOM w0.203: 78.6,63.83 78.28,63.51 PU700.16
  BOTTOM w0.254: PR711.2 79.98,64.78 v2(79.57,64.38) 79.02,63.83 78.6,63.83
N48095930: length 2.7
  BOTTOM w0.102: PL301.1 v2(69.47,63.83)
N48096052: length 2.4
  BOTTOM w0.203: PU300.19 58.97,53.36 58.97,52.82 58.46,52.32 v2(58.46,52.18) PR306.1
N48096170:
  vias: v2(67.84,48.94)
N48096331: length 2.9
  BOTTOM w0.102: PC305.2 58.37,59.84 58.12,60.09 56.56,60.09 v2(56.08,59.61)
N48096452: length 0.9
  BOTTOM w0.102: PC306.1 v2(58.48,50.23)
N48756972: length 4.8
  TOP w0.102: v2(12.55,13.19) 11.88,12.52 D122.1
  TOP w0.254: RTCR1.1 10.81,10.16 11.26,10.62 D122.1
N49522242: length 3.6
  TOP w0.203: PR206.1 46.5,31.57 PC203.2 46.94,31.59 v1(47.15,31.38) 47.65,30.88 PU200.1
  BOTTOM w0.254: PC204.1 47.72,31.95 v1(47.15,31.38)
N49522275: length 3.3
  TOP w0.203: PR205.1 46.5,30.68 PC203.1 47.1,30.67 v1(47.15,30.62) 47.29,30.47 48.04,30.47 PU200.2
  BOTTOM w0.254: PC202.2 47.4,30.88 v1(47.15,30.62)
N49570867: length 4.2
  TOP w0.102: v2(202.48,60.6) 202.48,60.87 202.91,61.29 v1(202.91,61.29)
  TOP w0.254: v1(202.91,61.29) PC500.1 PR500.1
  BOTTOM w0.254: PU500.1 202.28,61.93 v1(202.91,61.29) PC500.1
N49570895: length 5.5
  TOP w0.102: v2(203.51,65.07) 203.6,64.98 PR509.1
  TOP w0.254: PR509.1 203.37,63.97 v1(202.94,63.53)
  BOTTOM w0.254: PC515.2 PR505.2 PR508.1 203.36,63.96 v1(202.94,63.53) 202.68,63.28 202.15,63.28 PU500.4
N49571010: length 5.2
  BOTTOM w0.102: PC513.1 202.82,66.88 v2(202.27,67.43)
  BOTTOM w0.254: PC513.1 202.91,66.44 202.91,64.16 202.48,63.73 202.15,63.73 PU500.5
N49571039: length 2.4
  TOP w0.102: PR503.2 v2(199.35,64.47)
  TOP w0.254: PC505.1 PR503.2
N49753304: length 10.7
  TOP w0.254: RA16.2 16.87,22.54 18.36,24.04 v2(18.36,24.43) 18.36,24.86 18.62,25.12 19.57,25.12 19.78,25.32 19.78,25.88 19.59,26.07 QA9.1 18.23,26.07 18.23,26.07 18.13,26.16 18.12,26.16 18.09,26.2 17.7,26.2 17.32,26.58 ; 17.32,26.58 17.32,26.94 16.88,27.38 QA1.5 ; 17.32,26.58 16.88,26.13 QA1.2
N49753333: length 8.4
  TOP w0.254: QA9.2 21.65,25.42 21.91,25.16 RA32.2 RA57.2 20.48,23.57 v2(19.63,23.57) 19.63,22.75 19.47,22.59 RA18.2 18.8,22.58 RA41.1
N49753452: length 3.2
  TOP w0.102: v2(15.16,33.38) 15.48,33.71 QA3.3
  TOP w0.254: RA39.1 17.14,34.75 RA37.2 16.22,34.74 QA3.3
N49753456: length 3.6
  TOP w0.102: v2(18.96,35.71) CA40.1
  TOP w0.254: QA3.2 16.87,33.98 17.14,34.24 17.54,34.24 RA39.2 18.95,34.75 CA40.1
N49755927: length 3.6
  BOTTOM w0.254: CA34.1 CA33.1 21.21,21.48 R7.1 21.21,20.58 RA25.2 RA24.2
N49756069: length 2.9
  TOP w0.203: UA2.21 31.66,32.41 v1(31.97,32.72)
  BOTTOM w0.102: v1(31.97,32.72) 31.97,32.71 32.52,32.17 v2(33.25,32.17)
N49756116: length 5.6
  TOP w0.102: CA93.1 27.91,22.74 27.26,22.09 25.85,22.09 v2(25.32,21.56)
  TOP w0.203: CA93.1 27.91,23.13 28.22,23.45 28.73,23.45 29.26,23.98 29.26,24.4 UA2.44
N49756130: length 2.9
  TOP w0.203: UA2.40 27.07,26.15 26.62,25.7 v2(26.56,25.7) 25.78,25.7 CA94.1
N49756142: length 4
  TOP w0.203: UA2.25 30.06,32.15 29.62,32.59 29.62,34.49 29.36,34.75 CA95.1
N49756144: length 2.2
  TOP w0.203: UA2.26 29.66,32.04 28.92,32.78 CA95.2
N49756158: length 2.6
  TOP w0.203: UA2.28 28.86,31.82 27.46,33.22 CA96.2
N49756160: length 4.5
  TOP w0.203: CA96.1 28.03,34.88 28.22,34.69 28.22,32.94 29.26,31.9 UA2.27
N49756189: length 2.2
  TOP w0.102: UA2.53 32.86,23.96 33.88,22.95 RA45.1
N49756342: length 5.6
  TOP w0.102: v2(39.45,28.63) 39.01,29.08 RA75.2 38.93,29.62 RA76.2 CA106.1 35.8,28.55 UA2.9
N49757206: length 5
  TOP w0.203: v1(32.94,32.69) 32.86,32.62 UA2.18
  BOTTOM w0.102: v2(35.66,33.48) CA48.1
  BOTTOM w0.508: v1(32.94,32.69) 33.11,32.87 CA49.1 33.59,33.72 33.83,33.48 CA48.1
N49757319: length 4.3
  TOP w0.102: CA84.1 25.88,31.78 v2(24.62,33.04)
  TOP w0.203: 26.98,30.95 27.38,30.55 UA2.29
  TOP w0.254: CA84.1 26,31.76 26.81,30.95 26.98,30.95
N49757329: length 5.2
  TOP w0.102: v2(23.32,31.17) 25.38,31.17 26,30.56 CA85.1
  TOP w0.203: UA2.31 27.91,29.75 26.95,29.75 26.15,30.56 CA85.1
N49981925: length 8
  BOTTOM w0.254: RA48.1 23.37,30.72 22.74,30.1 22.74,29.06 v2(22.03,28.34) 21.3,27.62 21.3,25.64 21.77,25.18 DA6.3
N49981929: length 14.4
  TOP w0.102: v1(23.66,22.64) v2(24.11,22.18)
  IN3 w0.254: v1(23.66,22.64) 23.66,28.62 26.21,31.18 v1(26.21,32.63)
  BOTTOM w0.254: RA49.1 26.23,32.61 v1(26.21,32.63) ; DA6.2 23.7,22.68 v1(23.66,22.64)
N49981946: length 13.3
  TOP w0.102: v2(18.83,33.31) 18.46,33.67 v1(18.46,33.68)
  IN2 w0.254: JHP1.5 12.32,35.64 12.56,35.88 15,35.88 17.19,33.68 v1(18.46,33.68)
  BOTTOM w0.254: v1(18.46,33.68) 18.46,33.38 18.26,33.17 DA1.2 19.37,32.24 19.75,32.62 RA30.1 20.66,33.53 RA19.2
N50106861: length 13.5
  TOP w0.102: v2(58.45,56.78) v1(58.45,57.48)
  TOP w0.254: PR312.2 61.31,60.06 60.89,59.64 59.68,59.64 58.45,58.4 v1(58.45,57.48)
  IN4 w0.254: v1(58.45,57.48) 58.45,56.81 57.52,55.88 v1(53.81,55.88)
  BOTTOM w0.203: v1(58.45,57.48) 58.45,57.35 58.97,56.84 58.97,56.34 PU300.7
  BOTTOM w0.254: PR311.2 v1(53.81,55.88)
N50165058: length 19.2
  TOP w0.102: v1(29.94,59.04) 29.94,59.23 v2(30.32,59.61)
  TOP w0.254: PR448.2 PR447.2 v1(29.94,59.04) ; PU404.7 26.69,62.87 24.94,61.11 24.94,59.1 24.24,58.4 PQ409.4 24.24,57.27 v1(24.13,57.16)
  IN3 w0.254: v1(24.13,57.16) 24.13,59.23 25.05,60.15 28.83,60.15 v1(29.94,59.04)
N50165456: length 8
  TOP w0.102: v2(30.35,60.99) 30.33,60.99 29.54,60.2 PR457.2
  TOP w0.254: PU404.3 27.34,59.49 27.17,59.32 26.58,59.32 26.33,59.07 PR449.1 27.2,58.37 PR456.1 PC323.1 28.16,59.06 PR457.2
N50165462: length 6.3
  TOP w0.254: PU404.1 26.04,59.61 25.74,59.31 v2(25.42,59.31) PR449.2 PR455.2 24.63,56.69 23.96,56.69 23.59,57.06 PQ409.5
N50170477: length 12.8
  TOP w0.102: v1(23.21,55.36) v2(23.21,54.8)
  TOP w0.254: v1(24.69,63.08) 24.49,63.28 PU405.4 24.49,64.99 24.6,65.1 v3(24.6,65.23) PC51.1 ; v1(23.21,55.36) 23.59,55.74 PQ409.2
  IN3 w0.254: v1(24.69,63.08) 24.12,62.51 24.12,61.5 23.21,60.59 v1(23.21,55.36)
N50170488: length 4.8
  TOP w0.254: PC51.2 24.66,67.5 PR452.1 24.66,68.69 25.39,69.43 v2(25.39,69.59) 25.16,69.82 24.53,69.82 24.1,70.25 PU406.2 PU406.1
N50183034: length 4.7
  BOTTOM w0.102: v2(47.41,80.15) 48.35,79.21 PC109.2
  BOTTOM w0.254: PQ102.5 46.91,77.93 PR113.1 48.21,78.23 PC109.2
N50183040: length 3.8
  BOTTOM w0.102: PC109.1 48.35,76.24 v2(48.75,75.84)
  BOTTOM w0.254: PQ102.6 47.17,77.28 PR111.2 47.48,76.98 PC109.1
N50183045: length 5.3
  TOP w0.102: v1(42.28,76.6) 42.11,76.6 v2(41.72,76.22)
  TOP w0.254: v1(42.28,76.6) 42.52,76.36 PR110.2
  BOTTOM w0.254: PQ102.2 43.43,77.93 43.08,78.27 PR112.1 42.59,76.91 v1(42.28,76.6)
N50183053: length 16.3
  TOP w0.254: PR109.2 34.83,72.5 35.17,72.16 35.55,72.16 35.96,72.56 36.79,72.56 39.91,69.44 42.45,69.44 v2(43.21,70.2) 43.81,70.8 43.81,72.6 43.94,72.74 PQ103.6
N50183055: length 1.1
  TOP w0.102: PQ103.3 v2(47.11,74.04)
N50183068: length 9
  TOP w0.254: PQ103.5 43.95,73.39 41.74,75.59 v2(39.46,75.59) PC110.1 PR114.2
N50196545: length 11.1
  TOP w0.254: PU405.2 23.84,69.07 v2(23.7,69.21) 23.7,69.43 23,70.13 23,71.01 24.27,72.27 PU406.4
N50196918: length 10
  TOP w0.102: PR450.2 23.21,61.44 v1(23.6,61.84) 23.19,62.25 PU405.1 ; v2(24.74,55.22) 24.73,55.23 23.98,55.23 v1(23.96,55.25) 24.24,55.54 PQ409.3
  IN1 w0.071: v1(23.96,55.25) 23.6,55.61 v1(23.6,61.84)
N50197891: length 10.6
  TOP w0.254: PC302.1 28.2,63.76 27.99,63.96 PU404.5 ; PC302.1 PR445.2 30.1,62.89 30.71,62.29 v2(30.73,62.29) 30.87,62.15 30.87,58.46 PR447.1 ; PC302.1 30.29,63.76 PR451.1
N50203343: length 3.9
  TOP w0.102: PQ409.6 22.46,57.92 22.34,57.81 PR319.1 21.82,58.84 22.28,59.3 v2(22.28,59.31) 22.29,59.31 22.43,59.45 23.21,59.45 PR461.1
N50357872: length 3
  BOTTOM w0.102: PR716.1 v2(73.07,63.6)
  BOTTOM w0.203: PR716.1 73.26,62.75 74.08,62.75 74.33,62.5 PU700.8
N51562919: length 7
  TOP w0.102: QA7.2 41.2,20.89 v2(41.67,21.37) 41.78,21.47 41.78,22.96 41.37,23.36 QA8.1 40.79,24.02 40.48,24.32 RA81.2
N51667837: length 11
  BOTTOM w0.076: 112.82,51.27 113.47,51.27 113.49,51.29 113.76,51.29 113.83,51.23 UCPU1.AV61
  BOTTOM w0.102: 112.82,51.27 108.77,47.22 v2(108.07,47.22) 108.07,46.6 107.1,45.63 UC1.2
N51667853: length 4.5
  TOP w0.089: T226.1 111.07,69.04 111.7,68.41 v1(111.7,68.38)
  BOTTOM w0.076: UCPU1.H61 114.02,68.39 113.5,68.39 113.27,68.15 113.27,67.97 113.1,67.8 112.85,67.8 112.65,68 112.01,68 111.7,68.31 v1(111.7,68.38)
N51667855: length 4.8
  TOP w0.076: 110.07,68.04 110.21,68.04 v1(110.56,68.4)
  TOP w0.102: T227.1 110.07,68.04
  BOTTOM w0.076: UCPU1.H62 113.18,67.65 113.17,67.65 113.17,67.64 112.79,67.64 112.59,67.83 111.26,67.83 111.19,67.9 111.06,67.9 v1(110.56,68.4)
N51667857: length 1.1
  TOP w0.076: v1(115.28,66.24) 115.69,65.83 T228.1
  BOTTOM w0.076: v1(115.28,66.24) 115.28,66.34 UCPU1.K59
N51667859: length 1.5
  TOP w0.076: T229.1 112.45,68.21 v1(112.25,68.42)
  BOTTOM w0.076: UCPU1.H63 112.88,68.19 112.47,68.19 v1(112.25,68.42)
N51667861: length 1.2
  TOP w0.076: T231.1 114.06,67.74 v1(114.04,67.72)
  BOTTOM w0.076: UCPU1.J61 114.28,67.48 v1(114.04,67.72)
N51667863: length 1.2
  TOP w0.089: v1(114.63,66.22) 114.65,66.24 T230.1
  BOTTOM w0.076: UCPU1.K60 114.93,66.52 v1(114.63,66.22)
N51669561: length 1.1
  TOP w0.089: T123.1 150.33,58.4 v1(149.97,58.76)
  BOTTOM w0.076: v1(149.97,58.76) 149.65,59.07 UCPU1.AD4
N51988520: length 5.9
  BOTTOM w0.102: v2(87.56,72.32) 87.25,72.01 85.55,72.01 85.11,72.46 R1324.2 R1325.1 84.24,74.09 84.09,74.25 U697.2
N52012553: length 7.5
  TOP w0.102: v2(181.02,54.44) 181.64,55.06 181.64,55.99 182.06,56.41 RE57.1 RE63.1 183.51,56.95 183.51,59.74 183.71,59.95 183.71,60.29 UE5.A59
N52091760: length 1.1
  TOP w0.102: QE9.2 178.91,74.8 RE70.2
N52092863: length 0.9
  TOP w0.102: RE80.2 CE52.1
N52116668: length 8.5
  TOP w0.102: UE5.B61 182.97,61.14 182.97,61.55 v1(183.15,61.74) ; v3(181.2,56.41) 180.5,56.41 v2(180.19,56.1)
  GND1 w0.102: v4(181.67,56.82) 181.26,56.41 v3(181.2,56.41)
  IN3 w0.086: v1(183.15,61.74) 183.15,60.48 182.78,60.11 182.29,60.11 182.1,59.93 182.1,58.77 182.36,58.52 182.36,57.51 v4(181.67,56.82)
N52142235: length 2.8
  TOP w0.102: v2(163.49,65.08) 163.43,65.02 C1242.1 163.44,63.95 U673.1
N52142257: length 8.9
  TOP w0.254: v1(165.44,67.72) C1244.2 R1190.2
  BOTTOM w0.254: v1(165.44,67.72) 165.58,67.72 v2(165.94,67.36) 165.97,67.33 165.97,66.43 165.84,66.3 165.84,61.41 v1(166.38,60.88)
N52142406: length 2.2
  TOP w0.102: U673.17 166.09,64.72 166.09,65.21 165.92,65.38 v2(165.92,65.87) 165.92,66.64 C1244.1
N52362332: length 1.3
  GND1 w0.102: v3(177.02,64.99) 176.98,64.99 176.54,64.54 v4(176.54,64.52)
  GND3 w0.102: v4(176.54,64.52) 176.9,64.16 v5(177.02,64.16)
N52475187: length 4.4
  TOP w0.102: v1(41.18,44.63) 40.86,44.31 R1208.1 R1200.1 v2(39,43.99)
  BOTTOM w0.102: v1(41.18,44.63) 41,44.81 JNGFF1.30
N52475198: length 3.7
  TOP w0.102: R1210.1 v1(41.75,44.62) 41.23,45.13 v2(40.72,45.13)
  BOTTOM w0.102: v1(41.75,44.62) 41.5,44.86 JNGFF1.32
N52475202: length 3.7
  TOP w0.102: v2(42.05,46.29) v1(42.05,45.17) 42.64,44.59 R1212.1
  BOTTOM w0.102: JNGFF1.34 42,46.32 42,45.23 v1(42.05,45.17)
N52475209: length 3.4
  TOP w0.102: R1209.1 47.59,45.05 v1(47.74,45.2) 47.74,45.93 v2(47.6,46.07)
  BOTTOM w0.102: v1(47.74,45.2) 48,45.46 48,46.14 JNGFF1.58
N52475257: length 3.3
  TOP w0.102: v2(44,45.27) 43.82,45.09 v1(43.82,44.59) 43.53,44.3 R1255.1
  BOTTOM w0.102: JNGFF1.42 44,44.77 v1(43.82,44.59)
N52558730: length 10.1
  TOP w0.102: v1(38.65,17.48) 36.61,17.48 v2(36.35,17.22) 35.65,16.52 RE22.2
  BOTTOM w0.102: UE4.13 35.87,20.68 36.05,20.85 37.61,20.85 38.51,19.95 38.51,17.62 v1(38.65,17.48)
N52558748: length 4.3
  TOP w0.102: v3(34.76,19.28) v2(34.76,17.13) RE23.2
  GND1 w0.102: v3(34.76,19.28) 35.15,19.66 v4(35.22,19.66)
  GND3 w0.102: v4(35.22,19.66) v5(35.22,20.13)
N52558768: length 4.4
  TOP w0.102: RE27.2 v2(33.88,18.22) 33.88,18.82 v3(34.31,19.25)
  GND1 w0.102: v3(34.31,19.25) 34.31,19.64 v4(34.32,19.65)
  GND3 w0.102: v4(34.32,19.65) 34.57,19.9 v5(34.57,20.13)
N52571191: length 8.1
  TOP w0.102: v1(38.45,16.91) v2(37.8,16.91) 36.92,16.91 36.54,16.52 RE24.2
  BOTTOM w0.102: UE4.14 36.52,20.44 36.73,20.65 37.49,20.65 38.26,19.89 38.26,17.1 v1(38.45,16.91)
N52708219: length 7.7
  TOP w0.102: R886.1 v2(164.41,18.25) ; R886.1 D81.1 ; R886.1 165.45,18.37 v1(165.45,19.64)
  BOTTOM w0.102: v1(165.45,19.64) 165.99,19.64 167.11,18.53 167.11,17.66 166.82,17.37 JFAN1.2
N52717341: length 3.3
  GND1 w0.102: v4(172.94,60.74) 172.64,61.04 v3(172.62,61.04)
  GND3 w0.102: v5(172.61,61.45) 172.61,61.07 v4(172.94,60.74)
  BOTTOM w0.102: v2(171.63,60.41) RH135.1 172.64,61.43 v5(172.61,61.45)
N52717591: length 5.6
  BOTTOM w0.076: UCPU1.AG2 151.19,57.56 151.48,57.86 151.79,57.86 151.92,57.98 152.17,57.98 152.91,57.25 v2(153.75,57.25) 154.26,57.25 154.44,57.08 154.44,56.1 RH455.1
N52759096: length 3.9
  TOP w0.102: RA87.2 36.4,21.72 36.54,21.86 QA7.1 37.53,22.7 v2(36.59,23.64)
N52893126: length 1.3
  BOTTOM w0.102: UE4.19 37.66,16.51 38.38,16.51 T125.1
N52893865: length 3.7
  TOP w0.102: v2(197.49,22.44) 200.02,22.44 200.63,21.83 R1343.1
N52893895: length 2
  TOP w0.102: v2(202.52,16.25) 202.52,17.9 202.28,18.14 202.28,18.17
N52893916: length 1.5
  TOP w0.102: U716.10 200.75,20.37 C1258.1
N52894141: length 1.5
  TOP w0.102: U716.12 200.75,19.57 C1257.1
N52895521: length 1.8
  TOP w0.102: U718.12 48.43,61.29 C1202.1
N52895617:
  vias: v2(50.16,63.88)
N52895619: length 4.4
  TOP w0.102: U718.10 49.78,62.09 49.69,62.18 C1281.1 48.37,62.21 47.93,62.65 46.83,62.65 v2(46.27,62.09)
N52895657:
  vias: v2(49.74,59.37)
N52922903: length 2
  TOP w0.102: v2(202.94,28.22) 202.06,27.34 201.27,27.34
N52922958: length 1.2
  TOP w0.102: 200.68,24.1 200.08,24.1 v2(199.64,23.66)
N52922960: length 4.7
  TOP w0.102: U717.10 200.48,26.26 C1292.1 199.8,25.57 199.37,25.14 198.58,25.14 198.4,24.96 198.4,24.7 198.32,24.61 197.62,24.61 v2(197.45,24.77)
N52923110: length 3.7
  TOP w0.102: v2(198.28,23.76) 198.56,24.04 199.14,24.04 199.79,24.69 C1163.1 200.57,25.46 U717.12
N52925836:
  vias: v2(48.6,57.53)
N52925896:
  vias: v2(48.53,52.9)
N52925901: length 1.8
  TOP w0.102: C1278.1 47.85,55.64 47.87,55.61 U719.10
N52926051: length 1.8
  TOP w0.102: C355.1 46.91,54.81 U719.12
N52930519:
  vias: v2(37.41,56.46)
N52930575:
  vias: v2(37.43,51.74)
N52930580: length 1.7
  TOP w0.102: U720.10 36,54.52 C1293.1
N52930730: length 1.7
  TOP w0.102: U720.12 36.09,53.72 C1167.1
N52934489: length 1.2
  TOP w0.102: v2(29.05,38.62) 29.23,38.44 U664.8
N52934545:
  vias: v2(33.79,38.35)
N52934547: length 1.6
  TOP w0.102: C1214.1 30.95,36.94 U664.10
N52934693: length 1.6
  TOP w0.102: U664.12 31.75,36.91 C1212.1
N52950077: length 4.6
  TOP w0.102: v2(165.57,71.81) 165.57,71.46 166.29,70.74 C1227.1 R1380.2 R1379.2 168.37,70.38 168.27,70.28 168.27,69.59 Q360.4
N52950154: length 4
  TOP w0.102: Q361.6 167.84,74.22 167.16,73.54 v2(166.71,73.54) 166.71,72.75 167.48,71.97 R1380.1
N52950156: length 1.5
  TOP w0.102: R1379.1 169.14,72.43 Q361.3
N52950610: length 2.4
  TOP w0.102: R1190.1 166.97,66.25 v2(167.39,65.83) 167.39,65.64 167.09,65.34 167.09,64.72 U673.15
N53211236: length 6.3
  TOP w0.254: v1(80.87,64.62) 80.87,65.64 v2(80.65,65.85) 80.31,66.19 PR731.1 PR730.1
  BOTTOM w0.254: PR729.2 v1(80.87,64.62)
N53261040: length 2
  TOP w0.102: U652.9 183.57,43.68 183.16,43.28 R8.2
N53261043: length 2.1
  TOP w0.102: U652.8 182.92,43.77 182.27,43.12 R9.2
N53262018: length 2
  BOTTOM w0.102: v2(81.65,55.44) 81.82,55.61 PR720.2
  BOTTOM w0.254: PC712.1 PR720.2
N53314393: length 5.4
  TOP w0.102: v2(52.42,23.58) 52.42,25.18 PR226.2 51.31,25.63 50.09,26.85 PU200.11
N53314401: length 3.8
  TOP w0.102: PU200.12 50.49,27.63 50.49,26.82 50.72,26.59 v2(52.11,26.59) 52.13,26.59 52.86,25.85 PR227.2
N53579675: length 0.6
  TOP w0.102: 201.12,33.28 v2(200.51,33.28)
N53579693: length 0.7
  TOP w0.102: 205.47,33.54 v2(205.47,34.2)
N53579718: length 1.8
  TOP w0.102: U715.10 202.38,31.86 C1247.1
N53579746: length 1.9
  TOP w0.102: C1230.1 203.18,31.95 U715.12
N54037762: length 3.3
  TOP w0.102: PR228.1 v2(54.7,32.34)
  TOP w0.203: PR228.1 53.05,31.63 53.05,31.49 52.44,30.88 PU200.21
N54049002: length 5.6
  BOTTOM w0.102: PR511.2 v2(195.45,66.32)
  BOTTOM w0.254: PR511.2 195.46,65.21 PR510.2 196.37,62.21 195.99,61.83 PQ500.2
N54049152: length 19.1
  TOP w0.254: v1(204.14,68.39) 204.14,64.55 204.51,64.18 PR509.2
  BOTTOM w0.254: PQ500.1 194.72,63.19 194.54,63.37 194.54,66.3 196.6,68.36 v2(199.37,68.36) 201.72,68.36 201.97,68.11 203.87,68.11 v1(204.14,68.39)
N54084321: length 3.5
  TOP w0.102: v2(58.44,52.05) 58.08,52.41 v1(58.08,52.66)
  TOP w0.254: v1(58.08,52.66) 58.84,52.66 59.45,53.27 PR315.1
  BOTTOM w0.203: PU300.20 58.57,53.36 58.57,52.88 58.35,52.66 v1(58.08,52.66)
N54220793: length 36
  TOP w0.076: R253.1 150.67,67.08 150.94,67.36 v3(150.94,67.38) 150.94,67.57 v2(151.29,67.92)
  TOP w0.102: v1(179.09,63.66) 179.09,63.37 178.46,62.74 177.87,62.74 UE5.B49
  GND1 w0.076: v4(151.12,67.75) 151.12,67.56 v3(150.94,67.38)
  IN1 w0.071: 154.53,67.32 158.17,67.32 159.21,66.27 164.14,66.27 167.99,62.42 171.09,62.42 173.31,64.64 174.66,64.64 175.37,63.93 175.77,63.93 176.04,64.19 176.33,64.19 177.61,62.91 178.61,62.91 179.09,63.39 v1(179.09,63.66)
  IN1 w0.076: 154.53,67.32 151.58,67.32 151.15,67.75 v4(151.12,67.75)
N54285564: length 2.1
  TOP w0.102: U34.6 162.44,56.85 v2(161.99,56.39) 161.93,56.33 C218.1
N54285570: length 1.2
  TOP w0.102: 164.44,56.57 164.61,56.57 v2(165.33,55.85)
N54529025: length 10.1
  BOTTOM w0.102: JNGFF3.60 179,40.04 179.86,40.91 179.86,43.44 179.42,43.89 179.42,44.74 v2(179.43,44.75) 179.89,45.21 R2662.1
N55276904: length 4.4
  BOTTOM w0.102: RC9.2 157.45,44.17 158.74,44.17 v1(159.64,45.07) 159.92,45.07 159.95,45.04 SW4.1
N55667469: length 2
  TOP w0.254: PU401.7 41.5,63.21 PR413.1
N55667799: length 1.7
  TOP w0.254: PU400.7 193.15,72.87 192.74,73.29 PR412.1
N93297419: length 5.5
  TOP w0.102: U708.4 185.74,39.74 v2(185.21,40.28) ; U708.4 186.51,39.75 ; U708.4 186.51,39.75 ; Q305.2 188.93,41.37 188.26,40.7 186.83,40.7 186.51,40.39 186.51,39.75
N93297423: length 3
  TOP w0.102: v2(192.88,42.1) R541.2
  TOP w0.254: R541.2 192.11,40.68 192.07,40.72 Q305.1

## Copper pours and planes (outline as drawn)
1.35V_B+ on TOP (solid shape): 87.6,54.05 87.6,52.4 86.9,51.7 86.9,48.85 86.64,48.59 83.98,48.59 83.91,48.66 83.91,51.7 83.79,51.83 83.79,55.45 83.85,55.51 86.14,55.51
1.35V_B+ on BOTTOM (solid shape): 85.95,54.37 85.95,52.66 85.75,52.47 83.98,52.47 83.79,52.66 83.79,54.88 83.91,55.01 85.31,55.01
3.3V_MSATA_EN on IN2 (solid shape): outline of 211 points within 144.89,66.6 147.85,70.66
3/5V_B+ on TOP (solid shape): 68.24,56.53 68.24,56.08 67.74,55.58 67.74,54.48 67.57,54.31 66.24,54.31 66.21,54.34 66.21,56.64 66.45,56.88 67.89,56.88
3/5V_B+ on BOTTOM (solid shape): 70.96,56.78 70.96,56.4 70.77,56.21 70.04,56.21 69.61,55.77 68.1,55.77 67.98,55.65 67.98,54.63 67.47,54.12 67.47,52.97 67.28,52.78 65.55,52.78 65.31,53.02 65.31,53.58 65,53.88 63.57,53.88 63.47,53.98 63.47,54.94 63.15,55.26 61.75,55.26 61.62,55.13 60.42,55.13 60.35,55.2 60.35,55.32 60.42,55.39 61.37,55.39 62.26,56.28 63.85,56.28 63.97,56.15 63.97,55.7 64.99,54.69 66.01,54.69 66.23,54.91 66.23,56.69 66.45,56.91 70.83,56.91
+0.675VS on TOP (solid shape): 71.99,21.05 71.99,19.99 71.86,19.86 70.97,19.86 70.78,20.05 70.78,21.06 70.91,21.19 71.85,21.19
+0.675VS on TOP (solid shape): 105.66,20.7 107.73,20.7 107.88,20.55 107.88,20.27 107.78,20.18 107.76,20.18 107.63,20.15 107.51,20.07 107.3,19.86 105.69,19.86 105.52,19.69 105.52,18.87 105.07,18.43 97.31,18.43 96.79,18.95 96.79,20.19 97.43,20.83 105.53,20.83
+0.675VS on TOP (solid shape): 101.08,37.75 101.08,36.08 101.33,35.83 102.31,35.83 102.91,35.23 102.91,28.19 103.14,27.95 103.6,27.95 103.72,27.84 103.72,27.31 103.6,27.2 102.29,27.2 101.92,26.83 101.38,26.83 101.22,26.99 101.22,35.05 101.09,35.18 100.68,35.18 100.46,35.4 100.46,37.74 100.57,37.84 100.99,37.84
+0.675VS on TOP (solid shape): outline of 98 points within 151.71,19.48 158.74,37.8
+0.675VS on BOTTOM (solid shape): 77.82,40.84 77.82,39.32 77.65,39.15 75.13,39.15 74.96,39.32 74.96,40.91 75.15,41.1 77.56,41.1
+0.675VS on IN4 (solid shape): 71.99,21.9 71.99,20.82 71.85,20.68 70.92,20.68 70.77,20.83 70.77,21.92 71.04,22.19 71.7,22.19
+0.675VS on IN4 (solid shape): 76.5,39.69 76.5,38.62 76.37,38.5 75.47,38.5 75.26,38.7 75.26,39.73 75.35,39.82 76.37,39.82
+0.675VSP on BOTTOM (solid shape): 75.76,47.77 76.29,47.77 77.02,47.04 77.02,41.71 76.6,41.29 76.17,41.29 76.1,41.35 76.1,41.86 75.59,41.86 75.59,41.29 75.28,41.29 75.09,41.48 75.09,42.64 75.54,43.1 75.54,45.87 75.09,46.33 75.09,47.33 74.48,47.94 74.48,48.02 74.54,48.08 75.44,48.08
+1.5V_B+ on TOP (solid shape): 192.42,71.19 192.42,69.85 192.38,69.82 192.35,69.78 192.35,68.62 193.24,67.73 193.24,66.13 193.65,65.71 193.65,64.04 193.95,63.75 194.87,63.75 195,63.62 195,62.65 193.85,62.65 192.55,63.94 192.55,65.46 191.29,66.72 191.29,71.1 191.41,71.22 192.39,71.22
+1.05V_M on TOP (solid shape): 145.05,59 146.3,59 146.91,58.4 147.39,58.4 147.6,58.18 147.6,57.55 147.44,57.38 146.91,57.38 146.54,57.75 146.5,57.75 146.09,58.16 143.41,58.16 142.77,58.81 142.77,59.5 142.83,59.56 144.49,59.56
+1.05V_M on TOP (solid shape): 166.14,57.64 166.14,56.68 166.35,56.47 167.21,56.47 167.28,56.41 167.28,55.55 167.06,55.33 167.06,54.44 167.28,54.22 167.28,53.4 167.09,53.21 166.12,53.21 165.97,53.36 165.97,54.56 165.85,54.67 165.85,55.52 165.58,55.79 165.59,55.82 165.52,56.02 165.32,56.1 165.3,56.1 165.26,56.14 165.26,57.64 165.35,57.73 166.04,57.73
+1.05V_M on VCC: 144.24,53.14 144.24,55.3 143.1,56.44 143.1,59.41 143.33,59.64 145.28,59.64 146.93,57.99 164.37,57.99 167.23,55.13 167.23,49.5 166.17,48.44 153.54,48.44 152.46,49.52 147.86,49.52
+1.05V_PCH on TOP (solid shape): 168.67,55.03 169.54,55.03 169.6,54.96 169.6,54.35 169.38,54.14 167.73,54.14 167.67,54.2 167.67,55.34 167.72,55.39 168.31,55.39
+1.05V_PCH on TOP (solid shape): 170.53,68.53 170.53,66.52 170.62,66.44 170.62,64.21 170.61,64.21 170.61,62.21 169.77,61.36 169.77,59.81 169.55,59.6 167.71,59.6 167.62,59.69 167.62,61.08 167.42,61.29 167.42,62.12 167.26,62.27 165.79,62.27 165.76,62.24 165.76,61.3 165.71,61.25 165.47,61.25 165.38,61.34 164.71,61.34 163.92,60.55 163.92,59.25 163.82,59.15 162.88,59.15 162.77,59.27 162.77,61.07 162.95,61.25 163.4,61.25 163.95,61.81 164.43,61.81 164.56,61.93 164.56,62.5 164.69,62.63 165.51,62.63 165.64,62.75 165.64,64.09 165.45,64.28 165.45,65.17 165.51,65.23 165.7,65.23 165.76,65.17 165.76,64.34 165.96,64.15 167.29,64.15 167.45,64.31 167.45,65.42 167.67,65.64 167.67,65.93 167.48,66.13 167.48,66.7 168.07,67.29 168.07,68.42 168.3,68.66 170.4,68.66
+1.05V_PCH on BOTTOM (solid shape): 195.29,50.88 197.32,50.88 197.32,51.39 198.72,51.39 198.85,51.26 198.85,48.59 198.34,48.08 193.64,48.08 193.01,48.72 193.01,50.88 193.51,51.39 195.29,51.39
+1.05V_PCH on VCC: 189.56,48.08 188.03,49.61 167.73,49.61 167.73,55.11 168.62,56 168.62,63.79 167.73,64.68 167.73,66.02 168.22,66.51 172.58,66.51 177.66,61.43 194.8,61.43 198.21,58.01 198.21,48.57 197.73,48.08
+1.05VDX_MODPHY on TOP (solid shape): 173.52,72.96 173.52,72.2 173.28,71.96 171.8,71.96 171.79,71.98 170.02,71.98 170.02,71.41 169.97,71.41 169.82,71.26 169.82,70.66 169.63,70.47 168.75,70.47 168.75,71.62 170.16,73.03 173.46,73.03
+1.05VDX_MODPHY on TOP (solid shape): 152.54,78.76 152.54,78.09 152.5,78.01 152.43,77.99 152.08,77.66 152.43,77.32 152.5,77.3 152.54,77.22 152.54,76.35 152.2,76.01 149.19,76.01 148.96,76.24 148.96,77.43 148.25,78.14 144.65,78.14 144.56,78.16 144.46,78.14 143.37,78.14 142.68,77.45 141.84,77.45 141.75,77.54 141.75,79.88 141.84,79.97 151.33,79.97
+1.05VDX_MODPHY on IN2 (solid shape): outline of 272 points within 150.82,69.76 169.95,77.97
+1.05VDX_MODPHY_D on TOP (solid shape): 173.52,74.51 173.52,73.26 173.5,73.24 172.11,73.24 171.97,73.37 171.97,74.59 172.08,74.7 173.33,74.7
+1.5VS on TOP (solid shape): 198.59,78.62 198.59,77.77 198.53,77.71 197.31,77.71 197.22,77.8 197.22,78.66 197.3,78.74 198.48,78.74
+1.05VS on TOP (solid shape): 164.65,60.27 164.65,59.83 164.74,59.74 165.77,59.74 165.91,59.59 165.91,59 165.99,58.91 167.39,58.91 167.98,59.5 168.97,59.5 169.13,59.33 169.13,58.01 168.96,57.84 168.96,57.45 168.24,56.73 167.85,56.73 167.84,56.71 166.41,56.71 166.25,56.88 166.25,57.83 166.15,57.93 164.61,57.93 164.12,58.43 164.12,60.22 164.21,60.32 164.61,60.32
+1.05VS on TOP (solid shape): 143.03,68.2 143.03,67.74 142.97,67.67 142.55,67.65 142.48,67.24 142.5,67.21 142.46,67.17 142.46,66.54 142.37,66.45 140.95,66.45 140.88,66.52 140.88,67.44 141.22,67.78 141.82,67.78 141.88,67.77 142.06,67.78 142.6,68.32 142.91,68.32
+1.05VS on VCC: 142.13,56.85 141.7,57.29 139.19,57.29 139.09,57.39 139.09,72.11 140.03,73.04 166.68,73.04 167.23,72.5 167.23,64.41 168.09,63.55 168.09,56.22 167.59,55.72 167.37,55.72 164.59,58.5 147.14,58.5 145.49,60.15 143.12,60.15 142.59,59.62 142.59,57.08 142.36,56.85
+1.05VS_VCCST on TOP (solid shape): outline of 989 points within 136.07,41.3 139.7,59.85
+1.5VSP on TOP (solid shape): 197.66,77 198.15,77 198.15,77.54 198.63,77.54 198.71,77.47 198.71,74.89 198.99,74.61 198.99,72.21 198.85,72.07 197.83,72.07 197.63,72.27 197.63,75.85 196.79,76.69 196.79,77.48 196.86,77.54 197.66,77.54
+1.05VSP on BOTTOM (solid shape): 196.44,59.2 198.66,59.2 198.98,58.88 198.98,52.15 198.47,51.64 194.72,51.64 194.59,51.77 194.59,60.09 194.66,60.15 195.48,60.15
+1.8VS on TOP (solid shape): 29.98,42.19 29.98,41.65 30.13,41.5 30.55,41.5 30.7,41.35 30.7,40.18 30.64,40.12 29.24,40.12 29.1,40.26 29.1,42.17 29.22,42.29 29.89,42.29
+1.8VS on TOP (solid shape): 44.22,59.29 44.22,58.3 43.65,57.74 42.32,57.74 42.19,57.86 42.19,59.01 42.32,59.13 43.02,59.13 43.02,59.13 43.29,59.4 44.11,59.4
+1.8VS on IN1 (solid shape): 44.21,60.11 44.21,59.05 44.07,58.91 43.24,58.91 43.1,59.05 43.1,60.08 43.22,60.21 44.11,60.21
+1.8VS on IN1 (solid shape): 19.02,54.81 19.02,54.24 18.83,54.05 18.32,54.05 18,54.37 17.24,54.37 17.05,54.56 17.05,55.13 17.17,55.26 18.57,55.26
+1.8VS on IN1 (solid shape): 29.71,42 30.8,42 30.9,41.9 30.9,41.41 30.46,40.97 29.25,40.97 28.66,41.56 28.66,41.88 28.92,42.15 29.57,42.15
+1.8VS on IN1 (solid shape): outline of 269 points within 44.25,65.22 53.26,70.91
+1.8VS on IN3 (solid shape): 18.35,55.82 18.35,54.82 18.19,54.66 16.96,54.66 16.82,54.8 16.82,55.79 16.98,55.96 18.21,55.96
+1.8VS on IN3 (solid shape): 44.35,59.96 44.35,58.96 44.2,58.8 42.96,58.8 42.83,58.94 42.83,59.93 42.99,60.1 44.22,60.1
+1.8VS_AUDIO on TOP (solid shape): 28.41,36.42 29.16,36.42 29.38,36.21 30.2,36.21 30.32,36.08 30.32,35.48 28.36,35.48 27.81,36.04 25.73,36.04 25.62,36.15 25.62,36.91 25.67,36.97 27.87,36.97
+1.8VSP on TOP (solid shape): 42.04,58.94 42.04,58.69 41.47,58.69 41.47,58.18 42.03,58.18 42.04,58.17 42.04,57.57 41.67,57.2 36.28,57.2 36.1,57.38 36.1,58.31 36.38,58.59 40.59,58.59 41.12,59.12 41.86,59.12
+1.35V_DDR on TOP (solid shape): 107.25,25.47 107.25,25.45 107.28,25.33 107.38,25.23 107.38,25 107.22,24.85 106.95,24.85 106.83,24.97 106.5,24.97 106.25,24.72 106.25,24.36 106.97,23.64 108.87,23.64 109.57,22.94 109.57,21.73 109.35,21.52 106.68,21.52 106.53,21.67 106.53,22.23 106.38,22.38 106.14,22.38 105.35,23.17 105.35,23.58 105.38,23.67 105.4,23.76 105.4,25.41 105.79,25.81 106.92,25.81
+1.35V_DDR on TOP (solid shape): 91.18,27.15 91.18,26.94 90.2,25.95 90.2,25.52 90.37,25.34 90.64,25.34 90.67,25.37 90.68,25.38 90.78,25.44 90.85,25.55 90.86,25.56 90.93,25.63 91.08,25.63 91.18,25.53 91.18,25.04 91.06,24.92 91.04,24.93 90.81,24.85 90.73,24.62 90.73,24.59 90.35,24.21 90.35,23.53 91.37,22.51 91.37,21.35 91.2,21.19 90.81,21.19 89.65,22.34 89.65,27.03 90.3,27.68 90.64,27.68
+1.35V_DDR on TOP (solid shape): 160.84,25.42 160.85,25.4 160.89,25.3 160.98,25.22 160.98,24.96 160.83,24.81 160.56,24.81 160.54,24.83 160.5,24.83 160.49,24.84 160.44,24.87 160.39,24.9 160.33,24.95 160.3,24.92 160.28,24.91 160.19,24.89 160.12,24.84 160.11,24.83 160.09,24.83 159.96,24.7 159.96,24 160.92,23.04 161.62,23.04 162.54,22.12 162.54,21.31 162.72,21.13 163.99,21.13 164.09,21.23 164.09,22.36 164.18,22.46 164.84,22.46 164.98,22.31 164.98,20.12 164.75,19.89 161.86,19.89 161.62,20.13 161.62,21.35 161.29,21.69 159.85,21.69 159.79,21.76 159.79,22.48 159.65,22.61 159.2,22.61 158.84,22.96 158.84,25.47 159.15,25.77 160.49,25.77
+1.35V_DDR on TOP (solid shape): 173.02,25.75 173.02,25.73 173.09,25.6 173.2,25.51 173.23,25.5 173.23,25.24 172.99,25 172.84,25 172.7,24.86 172.7,24.77 172.7,24.76 172.68,24.65 172.7,24.55 172.7,24.54 172.7,24.15 173.27,23.58 173.27,23.07 175.22,21.12 175.22,19.83 175,19.61 173.22,19.61 172.8,20.03 172.8,20.05 172.8,20.14 172.77,20.23 172.76,20.24 172.76,21.79 172.71,21.79 172.71,22.32 172.41,22.32 172.41,22.71 172.41,22.73 172.45,22.89 172.41,23.05 172.41,23.06 172.41,23.13 171.73,23.81 171.73,25.66 172.12,26.05 172.71,26.05
+1.35V_DDR on TOP (solid shape): outline of 107 points within 142.82,19.92 148.81,25.95
+1.35V_DDR on TOP (solid shape): outline of 8923 points within 109.91,30.86 136.54,57.59
+1.35V_DDR on BOTTOM (solid shape): outline of 25098 points within 75.02,18.67 174.72,49.8
+1.35V_DDR on IN4 (solid shape): outline of 2134 points within 172.11,23.6 179.99,34.99
+1.35VP on BOTTOM (solid shape): 86.96,45.1 89.44,45.1 89.82,44.72 89.82,40.91 89.56,40.65 80.04,40.65 79.47,41.23 79.47,45.42 80.48,46.43 85.63,46.43
+3.3V_M on TOP (solid shape): 206.24,31.48 206.24,30.67 206.1,30.53 205.63,30.53 205.33,30.23 205.33,29.66 205.29,29.62 204.35,29.62 204.13,29.83 204.13,31.4 204.33,31.6 206.13,31.6
+3.3V_M on TOP (solid shape): 187.7,54.55 187.7,53.7 187.53,53.53 186.15,53.53 185.98,53.7 185.98,53.93 185.86,54.05 185.18,54.05 185.07,54.17 185.07,54.43 185.44,54.79 187.45,54.79
+3.3V_M on IN2 (solid shape): 204.92,30.93 204.92,30 204.82,29.9 203.55,29.9 203.31,30.14 203.31,30.95 203.47,31.12 204.73,31.12
+3.3V_M on IN2 (solid shape): 187.79,54.54 187.79,53.49 187.61,53.32 185.3,53.32 185.06,53.56 185.06,54.69 185.23,54.87 187.46,54.87
+3.3V_M on IN3 (solid shape): outline of 280 points within 146.46,59.06 150.6,60.97
+3.3VDX_SSD on TOP (solid shape): 179.6,20.57 179.6,19.36 179.32,19.08 176.05,19.08 175.43,19.7 175.43,20.47 175.68,20.73 179.44,20.73
+3.3VDX_SSD on TOP (solid shape): 177.96,41.42 178.91,41.42 179.03,41.3 179.03,40.22 177.64,38.83 176.38,38.83 176.12,39.09 176.12,41.61 176.18,41.67 177.72,41.67
+3.3VDX_SSD on TOP (solid shape): 198.47,27.87 198.47,26.46 198.31,26.3 197.74,26.3 197.53,26.09 197.53,25.69 197.34,25.5 193.1,25.5 192.83,25.77 192.83,27.15 193.06,27.38 197.15,27.38 197.71,27.94 198.4,27.94
+3.3VDX_SSD on BOTTOM (solid shape): 177.94,41.41 178.97,41.41 179.12,41.25 179.12,40.54 178.99,40.4 175.39,40.4 175.32,40.48 175.32,41.63 175.49,41.81 177.54,41.81
+3.3VDX_SSD on BOTTOM (solid shape): outline of 758 points within 175.2,20.19 182.45,28.79
+3V_NFC on BOTTOM (solid shape): 87.98,22.09 87.98,20.54 87.9,20.46 87.25,20.46 87.18,20.54 87.18,21.31 87.02,21.46 81.63,21.46 81.5,21.34 81.5,20 81.09,19.6 79,19.6 78.75,19.85 78.75,21.79 78.78,21.82 79.46,21.82 79.67,21.61 80.27,21.61 80.38,21.73 80.49,21.73 80.49,21.83 80.51,21.85 80.51,22.2 80.7,22.39 87.67,22.39
+3V_PCH on TOP (solid shape): 203.6,23.58 204.31,23.58 204.44,23.45 204.44,22.56 204.35,22.48 202.42,22.48 202.28,22.61 202.28,23.97 202.3,24 203.18,24
+3V_PCH on TOP (solid shape): outline of 285 points within 155.77,45.82 163.89,61.76
+3V_PCH on BOTTOM (solid shape): 169.78,60.15 169.78,57.68 169.66,57.57 169.09,57.57 168.98,57.68 168.98,58.09 168.97,58.1 168.97,60.09 169.14,60.26 169.67,60.26
+3V_PCH on BOTTOM (solid shape): 159.4,55.32 159.4,54.81 159.4,54.8 159.29,54.08 159.31,53.36 159.31,53.33 159.16,53.18 158.41,53.18 158.23,53.36 158.23,55.36 158.49,55.61 159.1,55.61
+3V_PCH on GND1 (solid shape): 162.03,46.66 162.03,45.86 161.85,45.69 160.59,45.69 160.51,45.77 160.51,46.63 160.64,46.76 161.92,46.76
+3V_PCH on IN1 (solid shape): 195.86,23.29 195.86,22.69 195.65,22.47 194.62,22.47 194.56,22.54 194.56,23.39 194.68,23.52 195.64,23.52
+3V_PCH on IN1 (solid shape): 164.85,43.41 164.85,43.02 164.16,42.33 163.71,42.33 162.84,43.19 162.67,43.19 161.39,44.47 161.36,44.54 161.38,44.61 161.38,45.07 160.92,45.08 160.85,45.05 160.78,45.08 160.27,45.59 160.27,46.15 160.47,46.35 161.91,46.35
+3V_PCH on IN3 (solid shape): 197.73,25.09 197.74,25.04 197.77,24.99 197.8,24.95 197.84,24.91 197.88,24.88 197.92,24.86 197.97,24.85 198.02,24.84 198.07,24.84 198.13,24.85 198.17,24.86 198.22,24.88 198.26,24.91 198.3,24.95 198.33,24.99 198.35,25.04 198.37,25.09 198.38,25.15 200.35,25.15 201,24.51 203.27,24.51 203.7,24.08 203.7,22.61 203.52,22.43 200.61,22.43 200.6,22.42 197.63,22.42 197.27,22.07 195.23,22.07 194.9,22.4 194.9,23.09 196.32,23.09 196.32,23.03 196.33,22.98 196.35,22.93 196.37,22.89 196.4,22.84 196.44,22.81 196.48,22.78 196.53,22.75 196.57,22.74 196.63,22.73 196.68,22.73 196.73,22.74 196.78,22.75 196.82,22.78 196.87,22.81 196.9,22.84 196.93,22.89 196.96,22.93 196.97,22.98 196.98,23.03 196.98,23.09 196.97,23.14 196.96,23.19 196.93,23.23 196.9,23.27 196.87,23.31 196.82,23.34 196.78,23.37 196.73,23.38 196.68,23.39 196.63,23.39 196.57,23.38 196.53,23.37 196.48,23.34 196.44,23.31 196.4,23.27 196.37,23.23 196.35,23.19 196.33,23.14 196.32,23.09 194.9,23.09 194.9,23.69 196.36,25.15 197.72,25.15
+3V_PCH on IN3 (solid shape): outline of 172 points within 155.32,52.48 159.22,59.03
+3V_ROM on BOTTOM (solid shape): 176.27,48.74 176.27,46.79 176.07,46.59 175.6,46.59 175.38,46.81 175.38,47.71 175.13,47.97 171.94,47.97 171.83,48.07 171.83,48.96 171.89,49.02 175.99,49.02
+3VALW on TOP (solid shape): 23.4,64.65 23.4,63.87 23.26,63.73 22.43,63.73 22.31,63.85 22.31,64.56 22.45,64.7 23.35,64.7
+3VALW on TOP (solid shape): 205.2,27.83 205.2,27.26 205.13,27.19 204.5,27.19 203.86,26.56 202.98,26.56 202.91,26.62 202.91,27.76 203.04,27.89 205.13,27.89
+3VALW on TOP (solid shape): 26.66,57.75 26.66,57.2 26.84,57.03 26.84,56.51 26.77,56.44 25.95,56.44 25.69,56.7 25.69,56.98 25.96,57.25 25.96,57.74 26.03,57.81 26.6,57.81
+3VALW on TOP (solid shape): 203.93,24.84 204.37,24.84 204.5,24.97 205.11,24.97 205.2,24.88 205.2,24.02 204.94,23.76 203.61,23.76 202.91,24.46 202.91,25.1 202.98,25.16 203.61,25.16
+3VALW on TOP (solid shape): 205.48,37.25 205.48,35.05 205.33,34.89 203.53,34.89 203.47,34.95 203.47,35.62 204.74,36.89 204.74,37.33 204.79,37.38 205.36,37.38
+3VALW on TOP (solid shape): 44.61,56.72 44.61,55.39 44.29,55.07 40.54,55.07 40.29,54.81 39.4,54.81 39.34,54.88 39.34,56.85 39.46,56.97 44.35,56.97
+3VALW on TOP (solid shape): 206.33,22.26 206.33,21.12 206.19,20.98 205.26,20.98 204.95,20.66 203.87,20.66 203.8,20.73 203.8,22.16 204.02,22.37 206.21,22.37
+3VALW on TOP (solid shape): 205.94,18.94 206.28,18.94 206.34,18.88 206.34,18.16 206.25,18.06 204.06,18.06 203.8,18.32 203.8,19.2 203.87,19.27 204.72,19.27 204.79,19.34 205.54,19.34
+3VALW on TOP (solid shape): 174.94,74.1 174.94,73.31 175.51,72.74 175.51,71.53 175.48,71.5 175.23,71.5 175.22,71.52 175.22,72.05 175.2,72.06 174.73,72.06 174.73,72.05 174.73,71.5 174.72,71.5 174.11,71.5 173.62,71.99 173.62,72.22 173.63,72.22 173.63,72.93 173.62,72.93 173.62,73.13 173.63,73.13 173.63,73.85 173.62,73.85 173.62,74 173.88,74.25 174.78,74.25
+3VALW on TOP (solid shape): 201.62,37.3 201.62,36.81 202.09,36.34 202.09,34.94 202.02,34.88 201.07,34.88 200.75,35.19 200.75,35.44 200.76,35.45 200.8,35.65 200.76,35.86 200.75,35.87 200.75,36.02 200.76,36.03 200.8,36.24 200.76,36.45 200.75,36.46 200.75,37.19 200.96,37.39 201.53,37.39
+3VALW on TOP (solid shape): outline of 990 points within 28.52,40.1 58.89,67.51
+3VALW on BOTTOM (solid shape): 201.96,67.42 201.96,65.1 201.6,64.75 201.6,63.53 201.34,63.53 201.34,64.84 201.07,65.1 201.07,67.48 201.22,67.62 201.75,67.62
+3VALW on BOTTOM (solid shape): 28.81,15.72 29.29,15.72 29.29,16.28 30.56,16.28 30.78,16.07 30.78,15.48 30.26,14.96 30.26,13.81 30.12,13.67 29.49,13.67 29.43,13.73 29.43,14.64 29.25,14.82 28.43,14.82 28.24,15.01 28.24,16.17 28.35,16.28 28.81,16.28
+3VALW on BOTTOM (solid shape): outline of 859 points within 42.89,55.09 57.69,67.51
+3VALW on IN1 (solid shape): 71.47,15.32 71.47,13.75 71.16,13.44 69.54,13.44 69.27,13.72 69.27,15.17 69.5,15.41 71.38,15.41
+3VALW on IN1 (solid shape): 177.62,14.59 177.62,13.65 177.61,13.64 177.61,13.21 177.53,13.12 175.03,13.12 174.92,13.23 174.92,13.84 175.8,14.72 177.49,14.72
+3VALW on IN2 (solid shape): 71.6,15.14 71.6,13.89 71.14,13.44 69.64,13.44 69.3,13.78 69.3,15.21 69.52,15.44 71.29,15.44
+3VALW on IN2 (solid shape): 177.43,13.98 177.43,13.48 177.3,13.34 174.78,13.34 174.66,13.47 174.66,14.54 174.82,14.7 176.72,14.7
+3VALW on IN3 (solid shape): 201.82,68.38 201.82,66.58 201.63,66.39 200.74,66.39 200.59,66.54 200.59,68.52 200.81,68.74 201.46,68.74
+3VALW on IN3 (solid shape): 201.59,37.91 201.59,35.81 201.43,35.65 200.68,35.65 200.62,35.7 200.62,35.72 200.59,35.8 200.55,35.86 200.55,36.03 200.62,36.24 200.55,36.45 200.55,37.94 200.7,38.09 201.41,38.09
+3VALW on IN4 (solid shape): 71.49,15.35 71.49,13.78 71.05,13.35 69.66,13.35 69.27,13.74 69.27,15.33 69.42,15.49 71.35,15.49
+3VALW on IN4 (solid shape): 177.44,14.32 177.44,13.46 177.34,13.36 174.74,13.36 174.69,13.41 174.69,14.4 174.81,14.52 177.24,14.52
+3VALW on VCC: outline of 81 points within 41.17,12.57 209.01,56.98
+3VALW_5085 on TOP (solid shape): 176.52,71.1 176.52,70.19 176.46,70.14 175.59,70.14 175.06,69.61 174.53,69.61 174.4,69.74 174.4,71.29 174.47,71.36 176.26,71.36
+3VALW_5085 on BOTTOM (solid shape): 171.1,65.29 172.42,65.29 172.55,65.17 172.55,63.21 172.32,62.98 170.53,62.98 170.1,63.41 170.1,65.24 169.97,65.36 169.97,65.38 169.88,65.53 169.73,65.61 169.72,65.62 169.69,65.65 169.42,65.65 169.33,65.74 169.33,66.28 169.41,66.36 170.03,66.36
+3VALW_5085 on VCC: 177.87,61.93 174.34,65.47 174.34,69.83 175.84,71.33 181.56,71.33 183.26,73.04 191.19,73.04 194.65,69.58 194.65,62.41 194.17,61.93
+3VALW_23017 on BOTTOM (solid shape): 30.98,18.04 31.98,18.04 32.12,17.9 32.12,17.71 32,17.58 30.8,17.58 29.65,16.42 29.14,16.42 29.14,15.88 28.96,15.88 28.96,16.44 28.45,16.44 28.35,16.54 28.35,17.17 28.47,17.29 29.07,17.29 29.23,17.44 29.23,18.95 29.32,19.04 29.98,19.04
+3VALWP on BOTTOM (solid shape): 62.07,65.39 62.07,61.93 61.69,61.55 59.21,61.55 58.01,60.34 56.48,60.34 56.29,60.53 56.29,63.39 55.85,63.83 54.48,63.83 54.33,63.99 54.33,64.97 54.48,65.13 57.65,65.13 58.32,65.8 61.66,65.8
+3VLP on BOTTOM (solid shape): 56.93,55.01 58.32,55.01 58.39,54.94 58.39,54.81 58.32,54.75 56.93,54.75 56.61,54.43 55.47,54.43 55.34,54.56 55.34,55.26 55.47,55.39 56.54,55.39
+3VS on TOP (solid shape): outline of 91 points within 25,52.28 34.83,57.55
+3VS on TOP (solid shape): outline of 507 points within 146.95,58.43 161.61,68.78
+3VS on BOTTOM (solid shape): 147.79,79.64 147.79,78.5 147.72,78.42 147.12,78.42 147.03,78.51 147.03,79.59 147.2,79.76 147.68,79.76
+3VS on BOTTOM (solid shape): 181.06,72.18 181.06,71.85 180.8,71.6 180.8,70.89 180.71,70.8 180.09,70.8 179.99,70.91 179.99,71.62 180.08,71.71 180.42,71.71 180.54,71.82 180.54,71.95 180.55,72.04 180.54,72.13 180.54,72.2 180.64,72.3 180.93,72.3
+3VS on BOTTOM (solid shape): 163.35,68.47 163.35,62.42 163.28,62.28 163.28,62.13 163.29,62.11 162.7,61.52 160.01,61.52 159.24,62.28 159.21,62.28 159.17,62.32 159.06,62.32 159.02,62.33 158.99,62.33 158.58,62.33 158.47,62.31 158.39,62.24 158.39,62.23 158.09,61.93 157.96,61.93 157.95,61.93 157.38,61.93 156.68,61.23 156.37,61.23 156,60.86 156,60.56 155.92,60.48 155.55,60.48 155.45,60.58 155.45,61.96 155.55,62.07 156,62.07 156.1,62.17 156.1,62.94 156.1,63.02 156.15,63.07 156.16,63.07 156.16,63.08 156.33,63.25 156.66,63.25 156.72,63.22 156.77,63.2 156.79,63.2 156.95,63.04 156.94,63.01 157.17,62.56 157.57,62.86 157.6,62.93 157.67,62.96 157.74,62.96 157.81,62.92 157.84,62.85 158.32,62.54 158.36,63.11 158.31,63.19 158.34,63.27 158.4,63.32 158.4,64.56 158.48,64.73 158.4,64.9 158.4,68.02 158.51,68.14 159.82,68.14 160.15,68.47 160.68,68.47 160.75,68.4 160.75,63.2 160.06,63.2 160.06,62.43 160.75,62.43 160.91,62.27 162.04,62.27 162.35,62.57 162.35,65.7 162.58,65.93 162.58,68.37 162.75,68.54 163.28,68.54
+3VS on IN2 (solid shape): outline of 250 points within 153.39,67.62 159.76,75.09
+3VS on VCC: 36.48,68.03 28.31,59.86 28.31,54.58 28.3,54.57 21.41,54.57 20.16,55.82 20.16,79.23 46.27,79.23 46.27,80.73 205.43,80.73 205.43,40.92 205.45,39.93 205.49,38.94 196.38,38.94 195.88,38.44 195.88,36.53 195.77,36.42 184.92,36.42 184.75,36.59 184.75,48.61 185.24,49.1 187.82,49.1 189.35,47.58 197.94,47.58 198.72,48.36 198.72,58.22 195.16,61.79 195.16,62.2 195.17,62.21 195.17,62.42 195.16,62.43 195.16,69.79 191.41,73.55 183.05,73.55 181.34,71.84 175.63,71.84 173.83,70.04 173.83,66.87 173.47,66.51 173.3,66.51 172.79,67.01 168.22,67.01 167.73,67.5 167.73,72.71 166.89,73.55 139.82,73.55 138.74,72.47 138.38,72.47 138.38,72.48 138.16,72.48 138.16,72.47 90.16,72.47 87.85,70.16 87.85,58.01 89.02,56.85 106.54,56.85 107.03,56.36 107.03,52.25 93.46,38.69 77.55,38.69 76.81,39.42 76.81,47.61 75.72,48.7 67.89,48.7 67.78,48.8 67.78,67.25 67,68.03 ; 2 cut-outs
+3VS_AUDIO on TOP (solid shape): 36.43,35.5 36.43,34.92 36.34,34.83 36.34,34.56 36.02,34.24 35.89,34.24 35.77,34.36 35.77,34.46 35.76,34.47 34.9,34.47 34.78,34.59 34.78,35.26 34.66,35.38 33.65,35.38 33.32,35.05 32.44,35.05 32.35,35.14 32.35,35.85 32.42,35.92 33.3,35.92 33.68,36.29 35.64,36.29
+3VS_AUDIO on IN1 (solid shape): 158.58,46.4 158.84,46.4 159.28,45.96 159.28,45.07 159.16,44.95 158.99,44.95 158.11,45.83 158.11,46.29 158.22,46.4 158.58,46.4
+3VS_CAM on TOP (solid shape): 47.63,60.61 47.63,59.71 47.78,59.56 47.78,58.69 47.59,58.5 46.58,58.5 46.32,58.75 46.32,60.53 46.51,60.72 47.51,60.72
+3VS_CR on TOP (solid shape): 199.61,22.12 199.61,21.05 199.56,20.99 198.66,20.99 198.31,20.64 198.31,19.15 198.21,19.05 196.12,19.05 195.94,19.22 195.94,20.86 196.31,21.24 197.27,21.24 198.22,22.18 199.55,22.18
+3VS_CR on BOTTOM (solid shape): 198.18,20.89 198.18,19.6 197.37,18.8 197.37,17.82 197.34,17.79 197.34,16.28 197.57,16.05 197.57,16.03 197.6,15.91 197.7,15.83 197.73,15.82 197.73,15.34 197.53,15.15 196.77,15.15 196.69,15.23 196.69,17.57 196.44,17.82 196.44,18.78 195.94,19.27 195.94,20.3 195.98,20.34 195.98,20.77 196.28,21.07 197.99,21.07
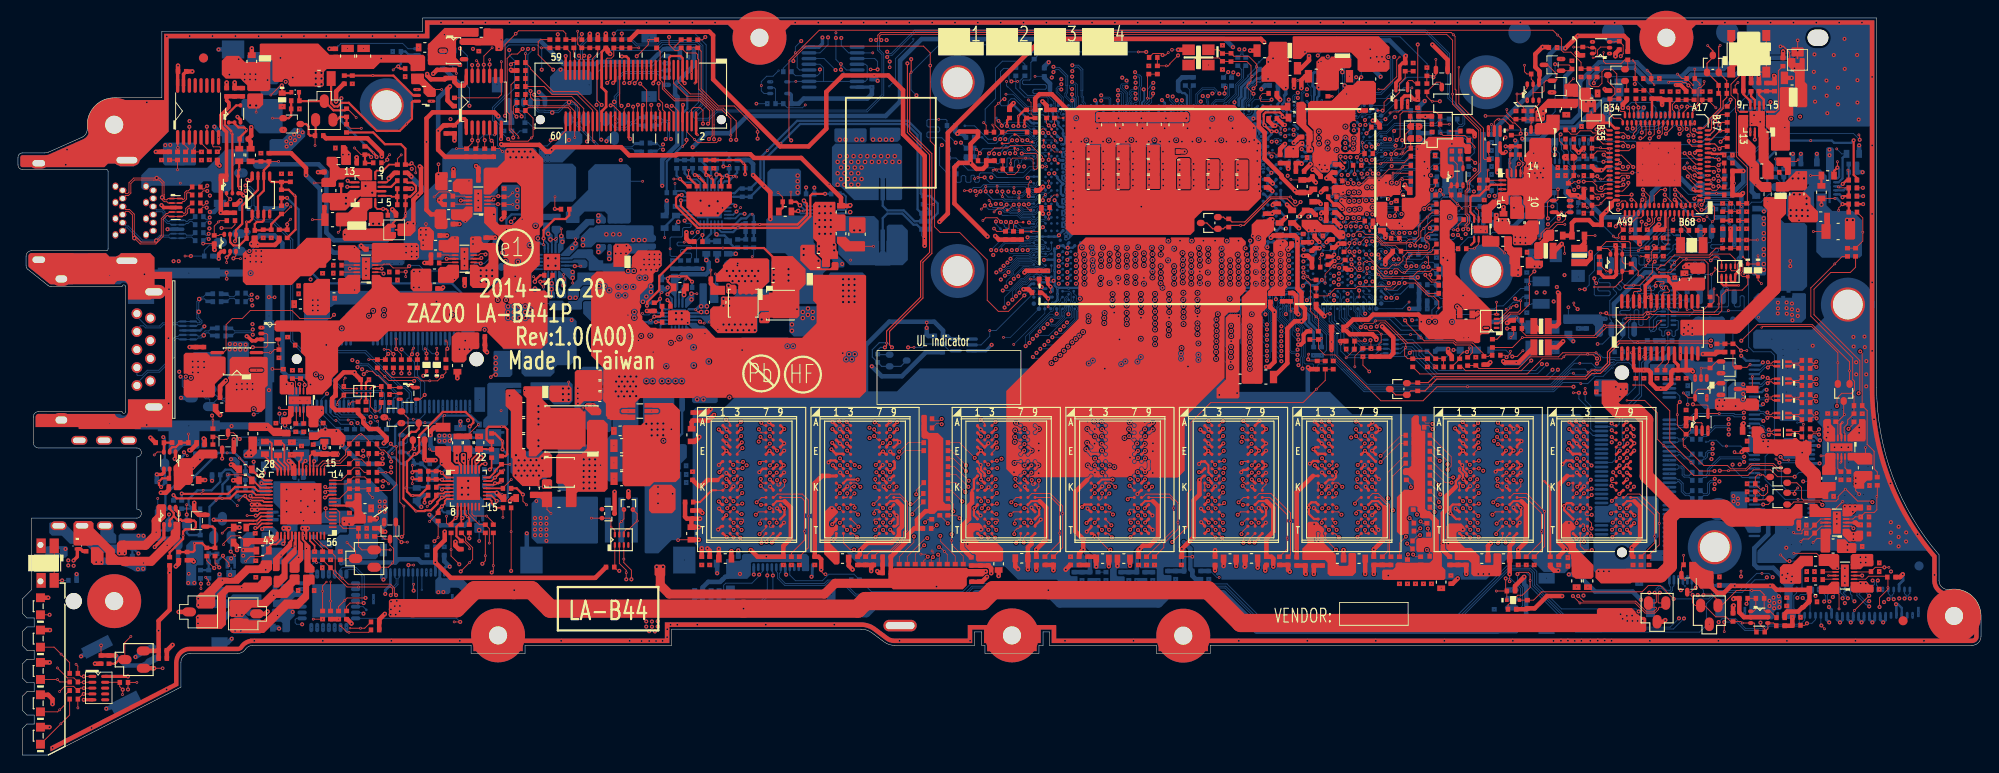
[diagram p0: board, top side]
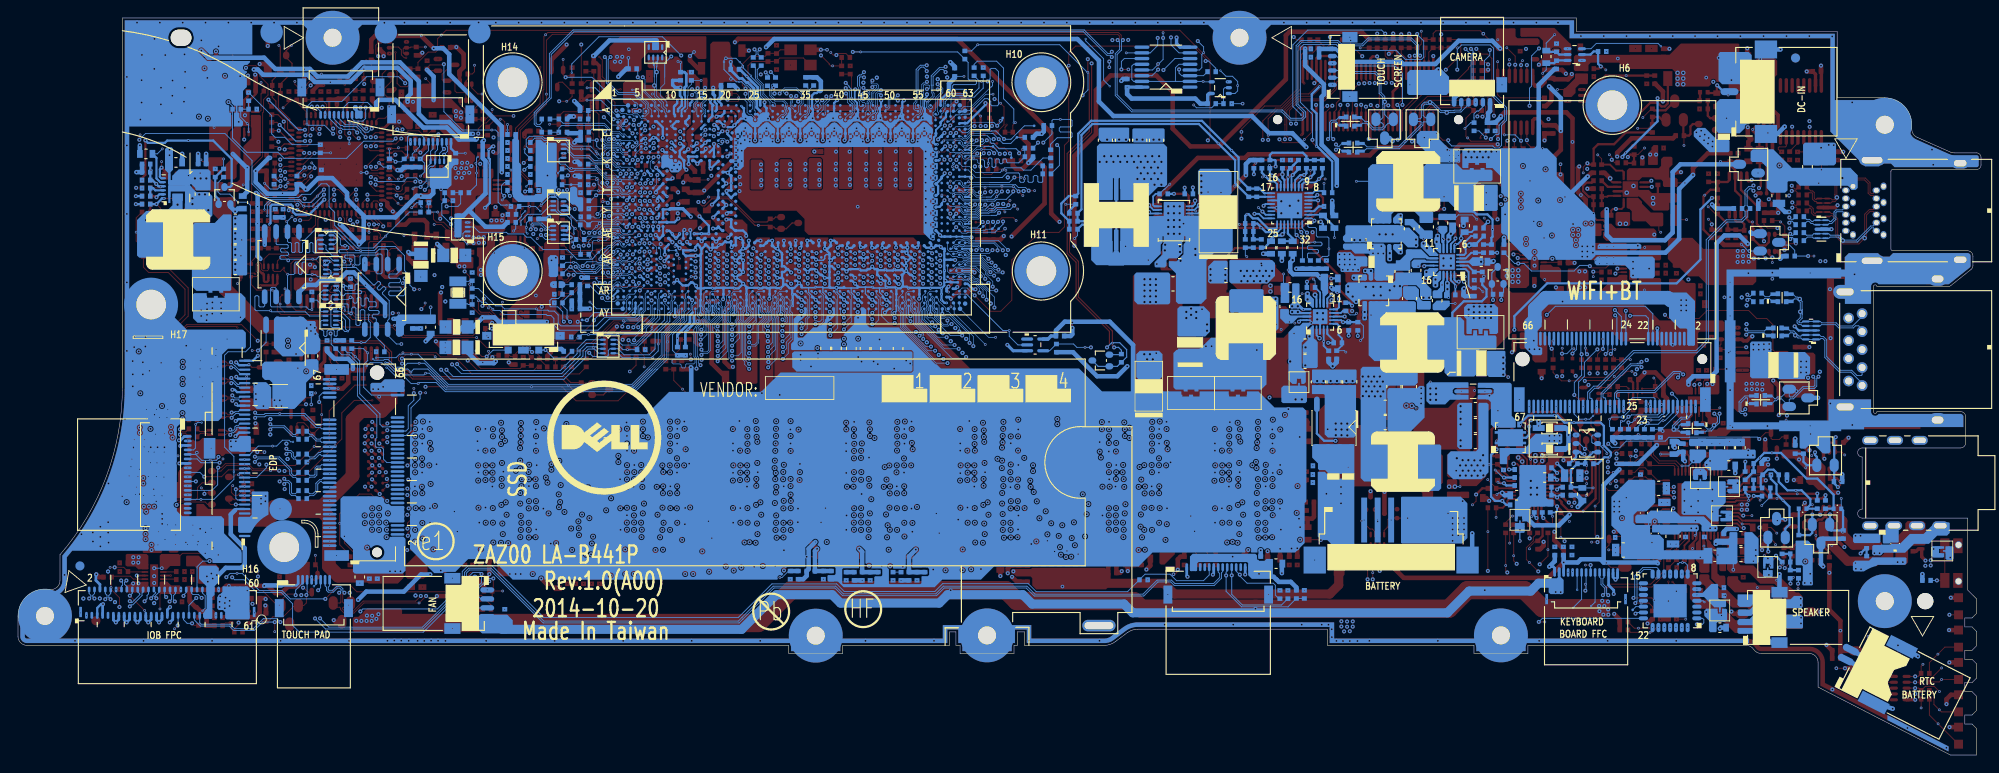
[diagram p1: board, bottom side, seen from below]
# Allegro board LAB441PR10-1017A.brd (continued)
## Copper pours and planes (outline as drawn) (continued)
+3VS_NGFF on TOP (solid shape): 34.7,52.91 34.7,49.35 34.27,48.92 32.12,48.92 31.73,49.31 31.73,52.4 31.85,52.52 32.79,52.52 33.24,52.97 34.64,52.97
+3VS_NGFF on TOP (solid shape): 51.3,46.91 51.3,45.3 51.16,45.16 50.57,45.16 49.89,44.48 49.89,43.97 49.6,43.68 48.45,43.68 48.22,43.91 48.22,46.55 48.71,47.03 51.18,47.03
+3VS_NGFF on BOTTOM (solid shape): 34.7,51.23 34.7,48.69 34.72,48.67 33.51,47.46 32.78,47.46 32.67,47.34 32.67,45.68 32.53,45.54 31.91,45.54 31.81,45.64 31.81,50.51 32.76,51.46 34.47,51.46
+3VS_NGFF on BOTTOM (solid shape): 50.77,48.37 50.77,45.35 49.89,44.48 48.94,44.48 48.8,44.62 48.8,45.25 48.92,45.38 49.17,45.38 49.31,45.52 49.31,47.22 48.85,47.68 48.85,48.79 48.99,48.93 50.2,48.93
+3VS_TP on TOP (solid shape): 186.58,21.5 187.41,20.79 188.45,20.47 188.47,20.46 188.57,20.37 188.57,18.67 188.39,18.5 187.1,18.5 186.93,18.67 186.93,18.68 186.84,18.85 186.67,18.94 186.66,18.94 185.86,19.74 185.86,21.45 185.91,21.5
+3VS_TPM on TOP (solid shape): 187.63,52.97 187.63,51.84 187.45,51.66 184.09,51.66 184,51.75 184,51.86 183.96,51.9 183.96,52.49 184.12,52.64 184.56,52.64 185.04,53.12 187.48,53.12
+3VS_TS on TOP (solid shape): 47.78,64.78 47.78,62.94 47.65,62.82 46.58,62.82 46.38,63.01 46.38,64.66 46.58,64.85 47.72,64.85
+3VS_TS on TOP (solid shape): 51.24,80.83 51.24,80.02 51.12,79.9 49.14,79.9 48.72,79.49 48.72,77.56 49.4,76.88 49.4,76.62 49.34,76.56 48.96,76.56 48.79,76.74 45.71,76.74 45.58,76.88 45.58,77.28 45.57,77.29 45.57,78.36 46.67,78.36 46.67,78.3 46.69,78.25 46.71,78.2 46.73,78.15 46.77,78.11 46.8,78.08 46.85,78.05 46.9,78.02 46.95,78.01 47,78 47.03,78 47.48,78 47.51,78 47.56,78.01 47.61,78.02 47.66,78.05 47.71,78.08 47.75,78.11 47.78,78.15 47.81,78.2 47.82,78.25 47.84,78.3 47.84,78.36 47.84,78.41 47.82,78.46 47.81,78.51 47.78,78.56 47.75,78.6 47.71,78.63 47.66,78.66 47.61,78.69 47.56,78.7 47.51,78.71 47.48,78.71 47.03,78.71 47,78.71 46.95,78.7 46.9,78.69 46.85,78.66 46.8,78.63 46.77,78.6 46.73,78.56 46.71,78.51 46.69,78.46 46.67,78.41 46.67,78.36 45.57,78.36 45.57,79.03 47.44,80.9 51.17,80.9
+3VS_TSLDO on TOP (solid shape): 53.97,80.7 53.97,78.53 53.75,78.32 53.15,78.32 53.08,78.39 53.08,78.81 52.95,78.94 50.82,78.94 50.77,78.99 49.28,78.99 49.1,79.17 49.1,79.55 49.31,79.75 51.3,79.75 51.57,79.75 51.76,79.94 51.76,80.74 51.85,80.83 53.84,80.83
+5V_USB_P1 on TOP (solid shape): 21.43,44.33 22.95,44.33 23.11,44.18 23.11,42.48 21.9,41.27 21.9,39.98 21.7,39.77 18.72,39.77 18.42,40.08 18.42,41.69 18.46,41.77 18.56,41.78 18.7,41.77 18.83,41.81 18.9,41.82 18.96,41.78 19.56,41.9 19.07,42.26 19,42.24 18.93,42.29 18.76,42.41 18.56,42.41 18.46,42.42 18.42,42.5 18.42,44.54 18.65,44.76 21,44.76
+5V_USB_P1 on BOTTOM (solid shape): 22.64,44.71 22.64,41.92 22.53,41.82 19.66,41.82 19.59,41.85 19.56,41.93 19.44,42.22 19.14,42.29 19.08,42.39 19,42.47 19,44.27 19.58,44.84 22.51,44.84
+5V_USB_P1 on IN4 (solid shape): outline of 237 points within 13.96,41.03 22.8,51.54
+5VALW on TOP (solid shape): 44.17,17.1 44.17,15.77 43.72,15.32 41.38,15.32 41.24,15.46 41.24,17.1 41.5,17.36 43.91,17.36
+5VALW on TOP (solid shape): 179.9,15.94 179.9,15.92 180,15.74 180.18,15.65 180.2,15.64 180.47,15.37 180.9,15.37 181.08,15.19 181.08,13.85 180.92,13.69 175.77,13.69 175.59,13.87 175.59,16.17 175.77,16.35 179.5,16.35
+5VALW on TOP (solid shape): 51.55,57.58 51.55,57.17 51.75,56.97 53.05,56.97 53.43,56.59 53.43,53.05 52.34,51.96 50.58,51.96 50.26,52.27 50.26,54.5 50.32,54.56 51.08,54.56 51.33,54.31 51.85,54.31 52.33,54.79 52.33,55.92 52.1,56.15 51.53,56.15 51.27,55.89 50.32,55.89 50.26,55.96 50.26,57.54 50.44,57.72 51.41,57.72
+5VALW on TOP (solid shape): outline of 115 points within 23.06,38.15 27.78,44.29
+5VALW on BOTTOM (solid shape): 73.44,53.48 73.44,51.77 73.25,51.58 73.25,49.86 73.14,49.76 73.02,49.76 72.97,49.8 72.97,51 72.61,51.37 72.61,53.48 72.67,53.54 73.37,53.54
+5VALW on BOTTOM (solid shape): 195.56,18.7 195.56,18.17 196.16,17.57 196.16,16.3 195.98,16.13 195.51,16.13 195.25,15.87 195.25,15.24 195.1,15.08 192.64,15.08 192.55,15.17 192.55,16.73 192.56,16.82 192.55,16.92 192.55,18.54 192.78,18.77 195.5,18.77
+5VALW on BOTTOM (solid shape): 57.49,49.81 57.49,48.76 57.23,48.5 57.23,46.9 57.17,46.84 56.63,46.84 56.63,47.37 56.61,47.4 55.87,47.4 55.87,47.39 55.87,46.84 55.44,46.84 55.44,47.39 55.43,47.41 54.68,47.41 54.66,47.38 54.66,46.84 53.88,46.84 53.7,47.02 53.7,49.76 54.12,50.18 57.12,50.18
+5VALW on IN1 (solid shape): outline of 317 points within 177.83,13.64 196.39,17.92
+5VALW on IN2 (solid shape): outline of 3163 points within 36.68,15.43 62.07,44.37
+5VALW on IN3 (solid shape): outline of 460 points within 177.75,13.47 196.14,17.88
+5VALW on GND1: 51.66,12.57 51.66,13.47 41.1,13.47 41.1,17.09 43.03,19.02 151.86,19.02 153.1,17.78 171.98,17.78 172.08,17.68 172.08,17.24 172.96,16.35 179.5,16.35 180.83,15.03 180.83,13.47 131.32,13.47 131.32,12.57 127.86,12.57 127.86,13.47 115.97,13.47 115.97,14.97 112.73,14.97 112.73,13.47 112.27,13.47 112.27,12.57 108.81,12.57 108.81,13.47 108.45,13.47 108.45,14.98 105.08,14.98 105.08,13.47 97.49,13.47 97.26,13.51 97.05,13.62 95.72,14.62 94.79,15.1 93.76,15.27 71.43,15.27 71.43,13.47 55.12,13.47 55.12,12.57
+5VALW on VCC: 177.98,13.51 177.98,15.62 178.17,15.81 193.71,15.81 194.35,16.46 194.35,17.68 194.67,18 196.11,18 196.56,17.55 196.56,13.6 196.44,13.47 178.01,13.47
+5VALW on VCC: 1.77,1.27 1.77,2.18 3.07,2.18 3.07,5.72 1.77,5.72 1.77,5.78 3.07,5.78 3.07,9.32 1.77,9.32 1.77,9.38 3.07,9.38 3.07,12.92 1.77,12.92 1.77,12.98 3.07,12.98 3.07,16.52 1.77,16.52 1.77,16.85 2.77,17.85 2.77,23.95 2.94,23.95 4.67,22.22 4.67,8.11 6.08,6.69 9.09,6.69 17.98,15.58 35.32,15.58 36.08,16.33 36.08,34.06 34.66,35.48 28.37,35.48 27.83,36.02 24.6,36.02 24.11,36.51 24.11,41.64 24.47,42 27.79,42 28.82,43.02 28.82,59.64 36.71,67.52 66.79,67.52 67.28,67.04 67.28,48.81 67.18,48.72 64.56,48.72 64.26,48.42 54.31,48.42 51.19,51.54 51.19,56.61 50.31,57.49 41.21,57.49 40.66,56.94 40.66,44.14 40.88,43.92 42.31,43.92 42.38,43.85 42.38,41.33 50.81,32.91 50.81,13.53 50.76,13.48 45.64,13.48 45.63,13.47 27.39,13.47 27.39,13.47 26.12,13.47 25.1,13.23 24.31,12.57 19.12,12.57 17.51,11.91 16.85,10.3 16.85,8.33 15.8,7.8 3.09,1.27
+5VALWP on BOTTOM (solid shape): 62.13,48.27 62.13,44.08 61.42,43.37 59.99,43.37 59.67,43.05 59.67,42.55 59.23,42.1 56.36,42.1 55.99,42.48 55.99,44.9 55.75,45.14 53.98,45.14 53.88,45.23 53.88,46.54 54.03,46.69 54.81,46.69 54.84,46.69 54.84,47.23 55.25,47.23 55.28,47.22 55.28,46.69 56.05,46.69 56.05,47.25 56.07,47.26 56.44,47.26 56.47,47.23 56.47,46.72 56.5,46.69 57.36,46.69 57.48,46.81 57.48,48.3 57.89,48.72 61.69,48.72
+5VS on TOP (solid shape): 45.97,54 45.97,52.56 46.07,52.46 46.07,51.7 45.94,51.58 43.97,51.58 43.65,51.89 43.65,53.86 43.91,54.12 45.86,54.12
+5VS on BOTTOM (solid shape): 167.06,15.49 167.06,13.88 166.7,13.53 163.95,13.53 163.28,14.19 163.28,15 163.91,15.63 165.38,15.63 165.45,15.7 166.85,15.7
+5VS on BOTTOM (solid shape): 47.06,20.81 47.06,19.78 47.17,19.67 47.93,19.67 48.09,19.52 48.09,18.11 47.88,17.9 46.54,17.9 46.41,18.03 46.41,19.48 46.75,19.82 46.75,20.79 46.86,20.89 46.98,20.89
+5VS on IN3 (solid shape): 47.52,19.19 47.52,18 47.43,17.91 45.88,17.91 45.81,17.99 45.81,19.2 45.9,19.3 47.41,19.3
+5VS on IN3 (solid shape): outline of 648 points within 24.83,47.83 46.09,54.88
+5VS_AUDIO on TOP (solid shape): 46.26,58.24 46.26,57.28 46.17,57.19 46.17,56.25 46.07,56.15 44.92,56.15 44.73,56.34 44.73,57.1 44.48,57.35 44.48,58.5 44.73,58.75 45.75,58.75
+5VS_AUDIO on BOTTOM (solid shape): 41.11,28.72 41.11,25.54 40.73,25.16 40.69,25.14 40.64,25.11 40.6,25.08 40.56,25.03 40.54,24.98 40.52,24.95 40.03,24.46 40.03,22.05 39.76,21.78 35.9,21.78 35.85,21.73 35.53,21.73 35.27,21.99 35.27,24.02 35.76,24.51 36.67,24.51 36.8,24.63 36.8,25.5 36.9,25.6 38.38,25.6 38.64,25.86 38.64,26.38 39.59,26.38 39.59,26.33 39.6,26.28 39.61,26.23 39.64,26.19 39.67,26.14 39.71,26.11 39.75,26.08 39.79,26.05 39.84,26.04 39.89,26.03 39.95,26.03 40,26.04 40.05,26.05 40.09,26.08 40.14,26.11 40.17,26.14 40.2,26.19 40.23,26.23 40.24,26.28 40.25,26.33 40.25,26.38 40.24,26.44 40.23,26.48 40.2,26.53 40.17,26.57 40.14,26.61 40.09,26.64 40.05,26.66 40,26.68 39.95,26.69 39.89,26.69 39.84,26.68 39.79,26.66 39.75,26.64 39.71,26.61 39.67,26.57 39.64,26.53 39.61,26.48 39.6,26.44 39.59,26.38 38.64,26.38 38.64,26.7 38.23,27.11 37.2,27.11 36.22,28.09 36.22,30.49 36.35,30.62 39.21,30.62
+5VS_AUDIO on IN1 (solid shape): outline of 2803 points within 34.06,26.81 48,58.81
+AVDD1 on BOTTOM (solid shape): 27.97,24.72 27.97,24.21 28.1,24.08 29.49,24.08 29.75,23.83 29.75,23.38 29.62,23.26 29.37,23.26 29.24,23.38 28.1,23.38 28.03,23.32 28.03,23.13 28.1,23.06 29.37,23.06 29.43,23 29.43,21.29 29.37,21.22 27.27,21.22 27.08,21.41 27.08,24.72 27.14,24.78 27.91,24.78
+AVDD2 on TOP (solid shape): 26.57,35.38 26.57,33.61 26.06,33.1 25.24,33.1 25.11,33.22 25.11,33.48 25.62,33.99 25.62,35.38 25.68,35.45 26.51,35.45
+AVDD2 on TOP (solid shape): 30.97,32.27 30.97,31.12 30.92,31.07 30.38,31.07 30.32,31.13 30.32,32.21 29.87,32.65 29.87,32.84 30,32.97 30.27,32.97
+AVDD2 on BOTTOM (solid shape): 30.26,33.92 30.26,33.1 30.76,32.59 30.76,32.15 30.29,31.68 28.33,31.68 28.17,31.83 28.17,32.69 27.89,32.97 25.18,32.97 25.05,33.1 25.05,33.86 25.18,33.99 30.19,33.99
+DVDD on TOP (solid shape): 38.22,28.98 38.22,27.16 38.69,26.69 38.69,25.86 38.56,25.73 37.5,25.73 37.26,25.5 36.16,25.5 35.97,25.69 35.97,26.37 36.12,26.52 37.32,26.52 37.39,26.6 37.39,27.32 37.15,27.56 36.49,27.56 36.41,27.65 36.41,28.13 36.5,28.23 37.22,28.23 37.42,28.42 37.42,29.08 37.48,29.14 38.05,29.14
+PVDD1 on TOP (solid shape): 30.38,25.35 30.38,25.1 30.19,24.91 30.19,24.02 30.13,23.95 30,23.95 29.94,24.02 29.94,24.84 29.81,24.97 29.43,24.97 29.3,25.1 29.3,25.35 29.43,25.48 30.26,25.48
+PVDD1 on BOTTOM (solid shape): 37.18,26.75 38.25,26.75 38.45,26.55 38.45,25.92 38.32,25.8 36.71,25.8 36.63,25.83 36.61,25.92 36.29,26.32 35.96,25.92 35.94,25.83 35.87,25.8 31.34,25.8 31.08,25.54 31.08,24.95 31,24.86 29.45,24.86 29.3,25.01 29.3,25.09 29.3,25.1 29.3,25.41 29.49,25.6 29.87,25.6 30.83,26.56 33.43,26.56 34.04,27.16 34.07,27.15 34.26,27.11 34.44,27.19 36.74,27.19
+PVDD2 on TOP (solid shape): 32.48,25.35 32.48,25.16 32.17,24.86 32.17,24.03 32.1,23.95 32.03,23.95 31.96,24.03 31.96,24.79 31.78,24.97 31.53,24.97 31.4,25.1 31.4,25.35 31.53,25.48 32.35,25.48
+PVDD2 on BOTTOM (solid shape): 36.58,25.52 36.58,24.81 36.53,24.76 35.83,24.76 35.6,24.53 33.65,24.53 33.32,24.86 31.58,24.86 31.4,25.03 31.4,25.48 31.55,25.63 36.47,25.63
+V1.05A_DCPSUS3 on TOP (solid shape): 143.27,72.39 143.27,70.76 143.28,70.75 143.28,70.12 143.98,69.41 143.98,68.32 143.84,68.17 143.84,67.73 144.04,67.54 144.04,67.17 143.88,67.01 143.39,67.01 143.27,67.13 143.27,69.19 142.17,70.29 142.17,72.52 142.2,72.6 142.28,72.62 142.44,72.63 142.59,72.69 142.97,72.69
+V1.05S_ASATA3PLL on TOP (solid shape): 145.33,77.67 145.66,77.38 145.99,77.67 145.99,77.71 148.02,77.71 148.29,77.45 148.29,76.6 148.1,76.4 147.25,76.4 146.91,76.06 146.91,74.84 146.9,74.84 146.9,74.2 146.62,73.93 144.59,73.93 144.39,74.13 144.39,77.14 144.96,77.71 145.33,77.71
+V1.05S_AUSB3PLL on TOP (solid shape): 141.33,79.09 141.33,74.17 141.1,73.94 140.71,73.94 139.75,74.9 138.36,74.9 138.28,74.98 138.28,76.34 138.8,76.86 138.8,77.52 139.08,77.8 139.08,78.97 139.12,79.09 139.14,79.22 139.14,79.24 139.27,79.36 141.06,79.36
+V1.05S_AXCK_DCB on IN4 (solid shape): outline of 486 points within 144.08,63.55 152.27,66.28
+V1.05S_AXCK_LCPLL_L on TOP (solid shape): 170.84,58.39 170.84,57.34 170.69,57.18 170.3,57.18 169.73,56.61 169.73,55.42 169.5,55.19 168.72,55.19 168.61,55.3 168.61,56.89 168.79,57.07 169.17,57.07 169.28,57.19 169.3,57.19 169.38,57.24 169.44,57.33 169.44,57.34 169.6,57.51 169.6,58.04 170.03,58.46 170.37,58.46 170.38,58.47 170.76,58.47
+V1.05VS_VCCHSIO on TOP (solid shape): outline of 627 points within 143.45,64.8 151.02,75
+V1.05VS_VCCHSIO on BOTTOM (solid shape): 146.75,66.58 146.76,66.52 146.77,66.48 146.77,65.36 146.65,65.24 146.49,65.24 146.38,65.36 146.01,65.36 145.82,65.16 145.82,65.02 145.63,64.82 144.85,64.82 144.48,65.19 144.48,65.87 144.75,66.14 144.85,66.16 144.92,66.08 145.25,65.86 145.47,66.19 145.5,66.28 145.59,66.31 145.87,66.39 145.93,66.67 145.95,66.76 146.03,66.8 146.53,66.8
+VCC_CORE on TOP (solid shape): outline of 609 points within 116.51,57.86 138.24,72.34
+VCC_CORE on BOTTOM (solid shape): 98.33,67.71 98.33,61.86 98.2,61.74 96.61,61.74 96.55,61.8 96.55,64.21 95.72,64.21 95.72,61.74 92.99,61.74 91.53,63.2 90.77,63.2 90.52,63.45 90.52,67.64 90.9,68.02 98.01,68.02
+VCC_CORE on BOTTOM (solid shape): outline of 2003 points within 116.01,57.23 139.21,70.44
+VCC_CORE on IN1 (solid shape): outline of 2921 points within 90.52,57.46 138.37,67.61
+VCC_CORE on IN2 (solid shape): outline of 3897 points within 90.52,57.34 138.69,69.51
+VCC_CORE on IN3 (solid shape): outline of 3261 points within 90.52,57.67 138.32,67.65
+VCC_CORE on VCC: 89.23,57.35 88.36,58.22 88.36,69.95 90.37,71.96 138.17,71.96 138.59,71.55 138.59,57.91 138.03,57.35
AGND on BOTTOM (solid shape): 26.32,24.72 26.32,21.41 26.19,21.29 24.92,21.29 24.73,21.48 24.73,24.08 25.43,24.78 26.26,24.78
AGND on BOTTOM (solid shape): 28.99,27.13 28.99,26.87 28.41,26.87 28.41,26.37 28.99,26.37 28.99,26.05 28.92,25.99 27.78,25.99 27.65,26.11 27.65,27.07 27.78,27.19 28.92,27.19
AGND on BOTTOM (solid shape): 32.48,35.07 32.48,34.49 32.34,34.36 26.33,34.36 26.26,34.43 26.26,35.15 26.32,35.21 32.33,35.21
AGND on BOTTOM (solid shape): 32.05,31.65 32.05,30.72 31.93,30.61 31.46,30.61 31.46,31.17 30.98,31.17 30.97,31.15 30.97,30.62 30.95,30.61 30.61,30.61 30.47,30.75 30.47,31.54 30.83,31.89 31.8,31.89
AGND on BOTTOM (solid shape): 5.53,23.09 5.53,22.18 5.3,21.95 4.21,21.95 4.1,22.07 4.1,22.44 4.11,22.46 4.65,22.46 4.66,22.47 4.66,22.93 4.65,22.95 4.11,22.95 4.1,22.96 4.1,23.22 4.12,23.23 5.39,23.23
AGND on BOTTOM (solid shape): 24.23,21.94 24.23,20.74 24.22,20.73 23.99,20.73 23.96,20.76 23.96,21.27 23.94,21.29 23.51,21.29 23.47,21.25 23.47,20.77 23.43,20.73 23.14,20.73 23.08,20.79 23.08,21.97 23.25,22.14 24.03,22.14
AGND on BOTTOM (solid shape): 28.22,30.56 28.22,30.11 27.65,30.11 27.65,29.61 28.22,29.61 28.22,29.29 28.03,29.1 26.95,29.1 26.76,29.29 26.76,30.43 27.02,30.68 28.1,30.68
AGND on GND1: 10.38,20.37 9.27,21.48 7.25,21.48 6.16,22.58 5.03,22.58 3.15,24.46 1.75,24.46 1.75,26.11 13.22,26.11 13.27,26.11 13.97,26.76 13.47,27.57 13.47,32.95 13.97,33.76 13.27,34.41 13.22,34.42 2.64,34.42 2.64,34.41 2.3,34.41 2.06,34.52 1.95,34.76 1.95,35.32 1.96,35.32 1.96,35.92 2.06,36.02 19.8,36.02 20.31,35.51 27.6,35.51 28.12,34.98 31.59,34.98 32.22,34.35 32.22,31.55 31.87,31.19 29.07,31.19 28.16,30.28 28.16,25.37 28.69,24.84 29.45,24.84 29.56,24.74 29.56,23.84 28.12,22.4 25.9,22.4 25.13,21.63 20.75,21.63 19.96,22.41 17.64,22.41 17,21.77 16.3,21.77 14.91,20.37
AGND on GND2: 10.38,20.37 9.26,21.48 7.25,21.48 6.16,22.58 5.03,22.58 3.15,24.45 1.75,24.45 1.75,26.11 13.22,26.11 13.27,26.11 13.97,26.76 13.47,27.57 13.47,32.95 13.97,33.76 13.27,34.41 13.22,34.42 2.74,34.42 2.74,34.41 2.3,34.41 2.06,34.52 1.95,34.76 1.95,35.47 1.96,35.47 1.96,35.86 2.07,35.98 2.07,35.98 2.12,36.02 19.8,36.02 20.31,35.51 27.6,35.51 28.12,34.98 31.6,34.98 32.22,34.36 32.22,31.55 31.87,31.19 29.07,31.19 28.16,30.28 28.16,25.37 28.69,24.84 29.45,24.84 29.56,24.74 29.56,23.84 28.12,22.4 25.91,22.4 25.13,21.62 20.74,21.62 19.96,22.41 17.64,22.41 17,21.77 16.31,21.77 14.92,20.37
AGND on VCC: 10.4,20.36 9.28,21.48 7.25,21.48 6.15,22.58 5.03,22.58 3.15,24.46 2.77,24.46 2.77,25.09 13.22,25.09 14.85,26.17 14.49,28.09 14.49,32.43 14.97,33.9 14.11,35.19 14.11,36.02 19.8,36.02 20.31,35.51 27.57,35.51 28.11,34.97 31.6,34.97 32.22,34.35 32.22,31.55 31.87,31.19 29.07,31.19 28.16,30.28 28.16,25.37 28.69,24.84 29.45,24.84 29.56,24.74 29.56,23.84 28.12,22.4 25.91,22.4 25.13,21.62 20.76,21.62 19.97,22.41 17.64,22.41 17,21.77 16.32,21.77 14.91,20.36
AGND on GND3: 10.39,20.36 9.26,21.48 7.25,21.48 6.16,22.58 5.01,22.58 3.13,24.46 1.88,24.46 1.75,24.58 1.75,26.11 13.22,26.11 13.27,26.11 13.97,26.76 13.47,27.57 13.47,32.95 13.97,33.76 13.27,34.41 13.22,34.42 2.27,34.42 2.21,34.43 2.17,34.44 2.11,34.47 2.06,34.52 2.02,34.56 1.99,34.62 1.96,34.69 1.96,34.76 1.96,34.89 1.96,35.25 1.96,36.02 19.8,36.02 20.31,35.51 27.58,35.51 28.12,34.97 31.6,34.97 32.22,34.35 32.22,31.55 31.87,31.19 29.07,31.19 28.16,30.28 28.16,25.37 28.69,24.84 29.45,24.84 29.56,24.74 29.56,23.84 28.12,22.4 25.91,22.4 25.13,21.62 20.74,21.62 20.74,21.64 19.97,22.41 17.64,22.41 17,21.77 16.31,21.77 14.9,20.36
GND on TOP (solid shape): 17.15,36.46 6.65,36.46 6.65,37.26 16.35,37.26 16.35,52.96 6.65,52.96 6.65,53.76 17.15,53.76
GND on TOP (solid shape): 79.4,62.63 79.4,61.42 77.88,59.89 75.34,59.89 74.32,60.91 74.32,62.63 74.39,62.69 79.34,62.69
GND on TOP (solid shape): 130.26,71.33 130.26,70.6 130.05,70.39 119.97,70.39 119.88,70.48 119.88,71.39 120.05,71.55 130.03,71.55
GND on TOP (solid shape): 130.4,66.27 130.4,62.98 130.35,62.93 129.02,62.93 128.9,63.06 128.9,66.24 129.08,66.43 130.24,66.43
GND on TOP (solid shape): 120.36,67.86 120.36,62.97 120.29,62.9 118.91,62.9 118.82,62.99 118.82,67.72 118.99,67.89 120.33,67.89
GND on TOP (solid shape): 123.62,67.88 123.62,63.03 123.53,62.94 122.25,62.94 122.17,63.02 122.17,67.76 122.33,67.92 123.57,67.92
GND on TOP (solid shape): 133.61,66.18 133.61,63.04 133.52,62.95 132.35,62.95 132.19,63.11 132.19,66.09 132.4,66.3 133.5,66.3
GND on TOP (solid shape): 136.84,66.14 136.84,63 136.74,62.91 135.57,62.91 135.42,63.06 135.42,66.05 135.63,66.26 136.72,66.26
GND on TOP (solid shape): 125.68,67.91 126.92,67.91 126.99,67.84 126.99,63.01 126.94,62.97 125.62,62.97 125.53,63.05 125.53,67.78 125.67,67.92
GND on TOP (solid shape): 60.29,55.71 60.29,54 60.23,53.93 58.51,53.93 58.45,54 58.45,55.71 58.51,55.77 60.23,55.77
GND on TOP (solid shape): 74.75,49.2 74.75,47.97 74.65,47.87 72.3,47.87 72.29,47.88 72.29,49.42 72.36,49.48 74.47,49.48
GND on TOP (solid shape): 40.64,60.27 40.64,60.27 40.64,59.1 40.64,59.1 40.64,58.99 40.5,58.85 39.16,58.85 39.02,58.99 39.02,60.32 39.1,60.41 40.5,60.41
GND on TOP (solid shape): 199.36,61.99 199.36,61.29 200.18,60.47 200.18,59.45 199.99,59.26 197.26,59.26 196.88,59.64 196.88,62.12 197.39,62.63 198.72,62.63
GND on TOP (solid shape): 64.99,42.7 64.99,39.62 64.74,39.36 64.38,39.36 64.38,39.37 62.95,39.37 62.49,38.91 62.02,38.91 61.92,39.01 61.92,42.6 62.14,42.83 64.86,42.83
GND on TOP (solid shape): 83.53,55.07 83.53,52.66 82.2,51.32 80.23,51.32 80.1,51.45 80.1,52.27 79.91,52.47 79.34,52.47 79.15,52.66 77.69,52.66 77.63,52.72 77.63,53.46 78.39,54.22 78.39,54.5 79.15,55.26 83.34,55.26
GND on TOP (solid shape): 56.1,39.81 56.1,34.24 56.48,33.86 56.48,33.29 56.67,33.1 57.88,33.1 58.54,33.76 58.99,33.76 59.4,33.35 59.4,31.07 59.21,30.88 58.32,30.88 58.01,30.56 58.01,30.05 57.88,29.92 56.1,29.92 55,31.02 55,32.96 54.83,33.13 54.83,38.22 54.22,38.83 54.22,40.55 54.36,40.69 55.22,40.69
GND on TOP (solid shape): 193.79,72.66 193.79,71.71 193.86,71.64 194.25,71.64 194.25,69.79 194.7,69.34 194.7,66.2 195.25,65.65 195.25,64.11 195.19,64.04 194.24,64.04 193.99,64.3 193.99,65.65 193.57,66.07 193.57,68.7 193.53,68.74 193.53,69.84 193.42,69.95 193.42,69.96 193.4,69.98 192.6,69.98 192.6,71.64 193.46,71.64 193.53,71.71 193.53,72.67 193.62,72.76 193.7,72.76
GND on TOP (solid shape): 90.9,61.48 90.9,60.4 91.15,60.15 91.91,60.15 92.04,60.02 92.04,58.37 91.98,58.31 91.09,58.31 90.9,58.12 90.9,56.96 91.02,56.84 91.02,56.19 91.2,56 91.2,55.25 91.14,55.19 90.4,55.19 90.31,55.1 90.31,54.39 90.24,54.31 89.46,54.31 89.41,54.36 89.41,55.24 88.84,55.81 88.84,57.06 88.42,57.48 88.42,61.29 88.68,61.55 90.83,61.55
GND on TOP (solid shape): 39.84,62.93 39.91,62.86 40.87,62.86 40.96,62.77 40.96,62.7 40.87,62.6 39.91,62.6 39.84,62.53 39.84,62.14 38,62.14 37.35,61.5 36.43,60.58 34.8,60.58 34.67,60.71 34.67,61.38 34.58,61.47 33.9,61.47 33.8,61.57 33.8,61.66 33.8,61.67 33.78,61.67 33.78,62.34 33.96,62.52 36.59,62.52 36.94,62.87 38.05,62.87 38.14,62.96 38.14,63.81 39.84,63.81
GND on TOP (solid shape): 16.97,36.49 2.51,36.49 2.51,36.49 1.95,36.49 1.95,37.61 2.06,37.85 2.3,37.96 3.21,37.96 3.21,37.95 10.76,37.95 11.47,37.46 12.18,37.95 12.22,38.06 12.23,38.17 12.23,39.57 16.97,39.57
GND on TOP (solid shape): 6.16,55.83 7.85,55.83 7.85,55.84 9.79,55.84 10.17,55.45 11.07,55.45 11.46,55.84 14.71,55.84 15.19,55.35 15.19,51.13 14.72,50.66 12.23,50.66 12.23,52.18 12.21,52.28 12.18,52.38 11.47,52.87 10.76,52.38 6.16,52.38 6.16,52.36 3.68,52.36 3.59,52.38 3.52,52.42 1.25,54.24 1.18,54.32 1.15,54.43 1.15,55.5 1.26,55.75 1.5,55.85 6.16,55.85
GND on TOP (solid shape): 93.76,14.76 94.63,14.62 95.42,14.21 96.75,13.21 97.1,13.03 97.49,12.96 105.62,12.96 105.62,14.46 107.94,14.46 107.94,12.96 108.3,12.96 108.3,12.06 108.5,12.06 108.5,11.55 107.79,11.55 107.79,12.45 107.43,12.45 107.43,13.95 106.13,13.95 106.13,12.96 106.13,12.45 97.49,12.45 96.94,12.54 96.44,12.8 95.11,13.8 94.47,14.14 93.76,14.25 72.45,14.25 72.45,12.45 56.14,12.45 56.14,11.55 50.64,11.55 50.64,12.45 26.12,12.45 25.52,12.3 24.8,11.64 24.44,11.55 19.12,11.55 18.23,11.19 17.87,10.3 17.87,7.71 3.61,0.39 3.61,0.96 17.3,7.99 17.36,8.02 17.36,10.3 17.87,11.55 19.12,12.06 24.44,12.06 24.56,12.09 24.64,12.17 25.14,12.67 25.8,12.93 25.8,12.96 51.08,12.96 52.8,14.68 54.13,14.68 55.85,12.96 71.94,12.96 71.94,14.76
GND on TOP (solid shape): outline of 252 points within 133.29,39.67 135.96,49.06
GND on TOP (solid shape): outline of 90 points within 0.25,11.55 218.06,81.75
GND on BOTTOM (solid shape): 10.42,3.89 3.61,0.39 3.61,0.96 10.42,4.46
GND on BOTTOM (solid shape): 3.96,23.21 3.96,21.85 3.81,21.7 3.2,21.7 3.05,21.85 3.05,23.09 3.19,23.22 3.94,23.22
GND on BOTTOM (solid shape): 25.68,45.83 25.68,42.11 25.47,41.9 23.43,41.9 23.3,42.03 23.3,45.89 23.42,46.01 25.5,46.01
GND on BOTTOM (solid shape): 42.64,56.69 42.64,56.35 42.6,56.31 37.85,56.31 37.77,56.38 37.77,56.73 37.93,56.88 42.45,56.88
GND on BOTTOM (solid shape): 55.85,63.2 55.85,60.78 55.59,60.53 53.88,60.53 53.75,60.66 53.75,63.39 53.81,63.45 55.59,63.45
GND on BOTTOM (solid shape): 64.5,28.66 64.5,23.63 64.4,23.53 57.73,23.53 57.12,24.14 57.12,28.01 57.85,28.75 64.41,28.75
GND on BOTTOM (solid shape): 74.4,42.82 74.4,41.55 74.21,41.36 69.64,41.36 69.45,41.55 69.45,42.82 69.51,42.88 74.34,42.88
GND on BOTTOM (solid shape): 93.95,44.59 93.95,42.05 93.69,41.8 91.34,41.8 91.03,42.11 91.03,44.59 91.41,44.97 93.57,44.97
GND on BOTTOM (solid shape): 87.09,64.97 87.09,62.43 86.83,62.18 83.66,62.18 83.34,62.5 83.34,64.85 83.72,65.23 86.83,65.23
GND on BOTTOM (solid shape): 98.14,69.67 98.14,68.53 97.82,68.21 94.97,68.21 94.73,68.46 94.73,69.72 94.81,69.8 98.01,69.8
GND on BOTTOM (solid shape): 132.2,44.71 132.2,44.71 132.2,43.14 131.71,42.65 118.98,42.65 118.83,42.8 118.83,44.77 118.97,44.91 132,44.91
GND on BOTTOM (solid shape): 31.95,69.36 31.95,68.83 30.19,67.07 28.1,67.07 27.97,67.2 27.97,68.34 28.16,68.53 29.43,68.53 30.68,69.78 31.53,69.78
GND on BOTTOM (solid shape): 54.98,44.87 54.98,42.31 54.72,42.06 53.01,42.06 52.88,42.19 52.88,44.87 52.99,44.97 54.87,44.97
GND on BOTTOM (solid shape): 83.6,55.01 83.6,52.66 83.41,52.47 79.34,52.47 78.52,53.29 78.52,54.75 78.83,55.07 83.53,55.07
GND on BOTTOM (solid shape): 192.12,41.32 192.12,38.86 191.75,38.49 190.49,38.49 190.15,38.83 190.15,40.92 190.71,41.48 191.95,41.48
GND on BOTTOM (solid shape): 193.91,60.02 194.29,60.02 194.4,59.9 194.4,53.48 194.28,53.35 192.94,53.35 192.82,53.48 192.82,60.09 192.88,60.15 193.78,60.15
GND on BOTTOM (solid shape): 10.63,25.6 10.63,24.78 10.93,24.48 10.93,23.62 10.85,23.53 10.16,23.53 10.05,23.64 9.22,23.64 9.15,23.71 9.15,25.52 9.35,25.72 10.52,25.72
GND on BOTTOM (solid shape): 55.91,39.07 55.91,34.05 56.16,33.8 58.96,33.8 59.34,33.42 59.34,31.32 58.7,30.68 55.53,30.68 54.77,31.45 54.77,39 54.96,39.19 55.78,39.19
GND on BOTTOM (solid shape): 89.38,49.63 89.38,46.71 89.22,46.56 86.52,46.56 86.51,46.56 86.27,46.56 85.76,47.08 85.76,49.23 86.45,49.93 89.08,49.93
GND on BOTTOM (solid shape): 19.79,67.92 19.79,65.72 19.66,65.59 16.35,65.59 16.12,65.82 16.12,67.97 16.29,68.13 19.58,68.13
GND on BOTTOM (solid shape): 51.85,25.77 51.85,24.78 51.78,24.72 50.83,24.72 50.74,24.8 50.74,25.8 50.76,25.82 51.8,25.82
GND on BOTTOM (solid shape): 94.38,69.6 94.38,68.3 94.21,68.14 90.97,68.14 90.78,68.32 90.78,69.6 90.91,69.72 94.25,69.72
GND on BOTTOM (solid shape): 74.9,47.25 74.9,46.16 75.44,45.61 75.44,43.2 75.29,43.05 73.91,43.05 73.76,43.2 73.76,45.93 74.2,46.37 74.2,47.74 74.26,47.8 74.34,47.8
GND on BOTTOM (solid shape): 62.77,69.01 62.77,68.13 60.57,65.93 57.99,65.93 57.92,66 57.92,67.4 57.99,67.47 59.19,67.47 60.24,68.53 60.24,69.15 60.53,69.44 62.34,69.44
GND on BOTTOM (solid shape): 42.98,55.15 42.98,54.71 42.75,54.48 39.59,54.48 39.02,53.91 39.02,53.21 38.84,53.03 36.48,53.03 36.28,53.23 36.28,55.2 36.53,55.46 42.68,55.46
GND on BOTTOM (solid shape): 60.8,76.22 63.49,76.22 63.82,75.89 63.82,73.62 63.63,73.43 59.44,73.43 59.16,73.71 59.16,75.46 59.64,75.94 59.75,76.01 59.82,76.12 60.19,76.49 60.53,76.49
GND on BOTTOM (solid shape): 28.3,36.22 13,36.22 13,37.02 27.5,37.02 27.5,53.22 13,53.22 13,54.02 28.3,54.02
GND on BOTTOM (solid shape): 33.3,30.11 33.3,26.87 33.14,26.72 30.64,26.72 29.91,25.99 29.24,25.99 29.18,26.05 29.18,27.32 28.39,28.11 28.39,30.37 28.48,30.46 32.95,30.46
GND on BOTTOM (solid shape): 74.3,47.98 73.7,47.98 73.6,47.88 73.6,46.84 73.54,46.78 73.46,46.78 73.4,46.84 73.4,47.88 73.3,47.98 72.7,47.98 72.7,49.58 74.3,49.58
GND on BOTTOM (solid shape): 90.9,61.48 90.9,56.87 91.04,56.73 91.04,55.69 91.91,54.81 91.91,54.37 91.79,54.24 90.77,54.24 90.58,54.43 90.58,55.01 90.33,55.26 89.4,55.26 88.83,55.83 88.83,57.07 88.61,57.29 88.61,61.48 88.68,61.55 90.83,61.55
GND on BOTTOM (solid shape): 70.7,58.78 70.7,57.95 70.96,57.68 70.96,57.29 70.71,57.04 64.31,57.04 63.74,56.47 62.7,56.47 62.58,56.59 62.58,57.67 63.59,58.69 64.04,58.69 64.29,58.94 70.54,58.94
GND on BOTTOM (solid shape): 201.6,61.41 201.35,61.41 201.35,62.69 199.74,62.69 199.74,61.38 199.76,61.36 199.76,61.35 199.76,59.99 199.47,59.7 197.01,59.7 196.69,60.02 196.69,62.18 197.13,62.63 198.47,62.63 198.98,63.13 198.98,63.2 199.1,63.32 201.6,63.32
GND on BOTTOM (solid shape): 65.14,53.55 65.14,52.82 65.37,52.59 70.39,52.59 70.71,52.27 70.71,51.26 69.63,50.18 69.37,50.18 68.86,50.69 64.76,50.69 64.38,51.07 64.38,52.12 64.23,52.27 62.81,52.27 62.39,51.85 62.39,51 62.02,50.63 61.24,50.63 61.12,50.75 61.12,51.83 62.2,52.91 62.2,53.63 62.26,53.69 65,53.69
GND on BOTTOM (solid shape): 16.97,37.02 19.97,37.02 20.19,36.81 20.19,34.23 20.05,34.09 19.52,34.09 19.21,34.39 18.43,34.39 17.6,33.56 16.92,33.56 16.76,33.72 16.76,36.49 12.35,36.49 12.35,36.48 1.95,36.48 1.95,37.61 2.06,37.85 2.3,37.96 11.39,37.96 11.9,37.78 12.22,38.21 12.22,39.57 16.97,39.57
GND on BOTTOM (solid shape): 10.17,55.45 11.07,55.45 11.46,55.84 14.71,55.84 15.14,55.4 15.14,50.19 12.22,50.19 12.22,52.11 11.9,52.54 11.39,52.36 3.68,52.36 3.59,52.38 3.52,52.42 1.25,54.24 1.18,54.32 1.15,54.43 1.15,55.5 1.26,55.75 1.5,55.85 9.78,55.85
GND on BOTTOM (solid shape): 20.62,23.8 20.62,21.19 20.54,21.11 19.92,21.11 19.82,21.01 19.82,19.34 19.88,19.29 19.88,18.96 19.77,18.86 18.8,18.86 18.71,18.95 18.71,21.56 19.2,21.56 19.2,21.51 19.21,21.46 19.23,21.41 19.25,21.36 19.28,21.32 19.32,21.28 19.36,21.25 19.41,21.23 19.46,21.21 19.51,21.2 19.56,21.2 19.61,21.21 19.66,21.23 19.71,21.25 19.75,21.28 19.79,21.32 19.82,21.36 19.84,21.41 19.86,21.46 19.87,21.51 19.87,21.56 19.86,21.61 19.84,21.66 19.82,21.71 19.79,21.75 19.75,21.78 19.71,21.82 19.66,21.84 19.61,21.85 19.56,21.86 19.51,21.86 19.46,21.85 19.41,21.84 19.36,21.82 19.32,21.78 19.28,21.75 19.25,21.71 19.23,21.66 19.21,21.61 19.2,21.56 18.71,21.56 18.71,23.34 19.23,23.86 20.56,23.86
GND on BOTTOM (solid shape): outline of 107 points within 61.88,35.92 66.01,41.07
GND on BOTTOM (solid shape): outline of 393 points within 116.56,69.73 137.81,71.63
GND on BOTTOM (solid shape): outline of 1954 points within 0.25,11.55 218.06,81.75
GND on IN1 (solid shape): 10.63,25.74 10.63,23.96 7.52,20.85 5.38,20.85 5.27,20.96 5.27,22.16 8.6,25.49 8.6,25.61 8.98,25.99 10.38,25.99
GND on IN1 (solid shape): 91.02,61.36 91.02,55.71 91.91,54.81 91.91,54.48 91.78,54.35 90.47,54.35 89.35,55.47 88.85,55.47 88.61,55.7 88.61,61.41 88.75,61.55 90.83,61.55
GND on IN1 (solid shape): 16.97,36.49 4.26,36.49 4.26,36.48 1.95,36.48 1.95,37.61 2.06,37.85 2.3,37.96 4.26,37.96 4.26,37.95 10.38,37.95 10.38,37.96 11.39,37.96 11.9,37.78 12.22,38.21 12.22,38.84 12.23,38.84 12.23,39.57 16.97,39.57
GND on IN1 (solid shape): 8.48,55.84 9.79,55.84 10.17,55.45 11.07,55.45 11.46,55.84 14.71,55.84 15.19,55.35 15.19,51.13 14.72,50.66 12.23,50.66 12.23,50.98 12.22,50.98 12.22,52.11 11.9,52.54 11.39,52.36 9.58,52.36 9.58,52.38 8.48,52.38 8.48,52.36 3.68,52.36 3.59,52.38 3.52,52.42 1.25,54.24 1.18,54.32 1.15,54.43 1.15,55.5 1.26,55.75 1.5,55.85 8.48,55.85
GND on IN1 (solid shape): outline of 140 points within 0.25,0.39 218.06,81.75
GND on IN2 (solid shape): 10.63,25.74 10.63,23.96 7.52,20.85 5.42,20.85 5.33,20.95 5.33,22.2 6.02,22.9 6.02,22.91 8.6,25.49 8.6,25.61 8.98,25.99 10.38,25.99
GND on IN2 (solid shape): 91.06,61.32 91.06,55.67 91.91,54.81 91.91,54.37 91.79,54.24 90.58,54.24 89.34,55.48 88.83,55.48 88.61,55.7 88.61,61.36 88.8,61.55 90.83,61.55
GND on IN2 (solid shape): 16.97,36.49 3.46,36.49 3.46,36.48 1.95,36.48 1.95,37.61 2.06,37.85 2.3,37.96 3.46,37.96 3.46,37.95 9.73,37.95 9.73,37.96 11.39,37.96 11.9,37.78 12.22,38.21 12.22,39.17 12.23,39.17 12.23,39.57 16.97,39.57
GND on IN2 (solid shape): 6.79,55.83 7.85,55.83 7.85,55.84 9.79,55.84 10.17,55.45 11.07,55.45 11.46,55.84 14.71,55.84 15.19,55.35 15.19,51.13 14.72,50.66 12.23,50.66 12.22,50.66 12.22,52.11 11.9,52.54 11.39,52.36 9.71,52.36 9.71,52.38 6.79,52.38 6.79,52.36 3.68,52.36 3.59,52.38 3.52,52.42 1.25,54.24 1.18,54.32 1.15,54.43 1.15,55.5 1.26,55.75 1.5,55.85 6.79,55.85
GND on IN2 (solid shape): outline of 140 points within 0.25,0.39 218.06,81.75
GND on IN3 (solid shape): 10.63,25.74 10.63,23.96 7.52,20.85 5.38,20.85 5.27,20.96 5.27,22.16 8.6,25.49 8.6,25.61 8.98,25.99 10.38,25.99
GND on IN3 (solid shape): 91.06,61.32 91.06,55.67 91.91,54.81 91.91,54.37 91.79,54.24 90.58,54.24 89.44,55.38 88.93,55.38 88.61,55.7 88.61,61.36 88.8,61.55 90.83,61.55
GND on IN3 (solid shape): 16.97,36.49 1.95,36.49 1.95,37.61 2.06,37.85 2.3,37.96 3.4,37.96 3.4,37.95 9.59,37.95 9.59,37.96 11.39,37.96 11.9,37.78 12.22,38.21 12.22,39.23 12.23,39.23 12.23,39.57 16.97,39.57
GND on IN3 (solid shape): 7.18,55.83 7.85,55.83 7.85,55.84 9.79,55.84 10.17,55.45 11.07,55.45 11.46,55.84 14.71,55.84 15.41,55.13 15.41,54.25 16.31,53.35 16.31,50.95 16.02,50.66 12.23,50.66 12.23,51 12.22,51 12.22,52.11 11.9,52.54 11.39,52.36 9.8,52.36 9.8,52.38 7.18,52.38 7.18,52.36 3.68,52.36 3.59,52.38 3.52,52.42 1.25,54.24 1.18,54.32 1.15,54.43 1.15,55.5 1.26,55.75 1.5,55.85 7.18,55.85
GND on IN3 (solid shape): outline of 141 points within 0.25,0.39 218.06,81.75
GND on IN4 (solid shape): 10.63,25.74 10.63,23.96 8.67,21.99 8.67,21.98 7.54,20.85 5.39,20.85 5.22,21.02 5.22,22.1 8.6,25.49 8.6,25.61 8.98,25.99 10.38,25.99
GND on IN4 (solid shape): 91.02,61.36 91.02,55.71 91.91,54.81 91.91,54.37 91.79,54.24 90.58,54.24 89.43,55.39 88.92,55.39 88.61,55.7 88.61,61.48 88.68,61.55 90.83,61.55
GND on IN4 (solid shape): 16.97,36.49 2.86,36.49 2.86,36.49 1.95,36.49 1.95,37.61 2.06,37.85 2.3,37.96 3.41,37.96 3.41,37.95 10.5,37.95 10.5,37.96 11.39,37.96 11.9,37.78 12.22,38.21 12.22,38.56 12.23,38.56 12.23,39.57 16.97,39.57
GND on IN4 (solid shape): 6.34,55.83 7.85,55.83 7.85,55.84 9.79,55.84 10.17,55.45 11.07,55.45 11.46,55.84 14.71,55.84 15.19,55.35 15.19,51.13 14.72,50.66 12.22,50.66 12.22,52.11 11.9,52.54 11.39,52.36 8.59,52.36 8.59,52.38 6.34,52.38 6.34,52.36 3.68,52.36 3.59,52.38 3.52,52.42 1.25,54.24 1.18,54.32 1.15,54.43 1.15,55.5 1.26,55.75 1.5,55.85 6.34,55.85
GND on IN4 (solid shape): outline of 139 points within 0.25,0.39 218.06,81.75
GND on BOTTOM: 189.13,26.96 189.31,26.78 189.31,22.42 188.43,21.55 181.49,21.55 181.34,21.7 181.34,22.68 182.61,23.95 184.42,23.95 184.62,24.15 184.62,25.03 184.51,25.14 182.92,25.14 182.86,25.21 182.86,25.37 182.94,25.45 184.49,25.45 184.66,25.62 184.66,26.39 184.41,26.64 182.94,26.64 182.87,26.7 182.87,26.91 182.92,26.96
GND on GND1: outline of 154 points within 0.25,0.26 218.06,81.75
GND on GND2: outline of 169 points within 0.25,0.26 218.06,81.75
GND on VCC: 20.52,36.02 20.01,36.53 13.98,36.53 13.96,36.55 13.75,36.55 13.73,36.53 12.01,36.53 12.9,37.17 13.24,38.21 13.24,50.32 13.24,50.32 13.24,52.11 12.5,53.38 11.03,53.38 3.95,53.38 2.17,54.8 2.17,54.83 9.82,54.83 10.86,55.26 11.29,56.3 11.29,64.94 10.86,65.98 9.82,66.41 5.03,66.41 7.62,67.56 8.6,68.4 8.97,69.64 8.97,70.12 9.48,71.34 10.7,71.85 13.34,71.85 13.34,71.85 17.27,71.85 17.27,79.23 19.65,79.23 19.65,55.61 21.2,54.06 28.31,54.06 28.31,43.24 27.58,42.5 24.25,42.5 23.6,41.86 23.6,36.51 23.11,36.02
GND on VCC: 142.22,56.6 142.74,56.08 143.73,55.09 143.73,52.93 147.67,49 152.25,49 153.33,47.92 166.38,47.92 167.56,49.1 183.76,49.1 184.24,48.61 184.24,36.41 180.35,36.41 180.05,36.11 180.05,30.01 179.94,29.89 175.85,29.89 175.23,29.27 175.23,25.36 170.65,20.78 77.29,20.78 76.8,21.26 76.8,37.06 77.92,38.18 93.67,38.18 107.54,52.04 107.54,56.36 108.02,56.85 138.88,56.85 139.07,57.04 141.59,57.04 142.03,56.6
GND on VCC: 6.3,7.2 5.17,8.32 5.17,21.7 5.55,22.07 5.94,22.07 7.04,20.98 9.07,20.98 10.19,19.85 15.12,19.85 16.53,21.26 17.21,21.26 17.85,21.9 19.76,21.9 20.55,21.11 25.35,21.11 26.12,21.89 28.33,21.89 30.07,23.62 30.07,24.95 29.66,25.35 28.9,25.35 28.67,25.58 28.67,30.07 29.28,30.68 32.08,30.68 32.73,31.34 32.73,34.97 34.43,34.97 35.58,33.83 35.58,16.57 35.1,16.09 17.77,16.09 8.88,7.2
GND on VCC: 209.52,13.47 209.52,25.86 210.91,23.7 212.49,21.66 212.49,18.48 213.66,17.32 214.56,17.32 215.54,17.33 215.69,17.32 215.87,17.32 216.13,17.22 216.55,16.94 216.74,16.76 216.97,16.44 217.16,16.05 217.24,15.76 217.24,13.47
GND on GND3: outline of 169 points within 0.25,0.26 218.06,81.75
GNDA_CHG on BOTTOM (solid shape): 51.34,32.15 51.34,28.84 51.85,28.34 51.85,26.05 51.78,25.99 51.53,25.99 51.53,26.56 51.02,26.56 51.02,25.99 50.32,25.99 50.19,26.11 50.19,27.45 50,27.64 47.59,27.64 47.53,27.7 47.53,28.34 47.65,28.46 48.16,28.46 48.35,28.65 48.35,32.21 48.42,32.27 51.21,32.27
+DC_IN on TOP (solid shape): 34.64,77.91 39.07,77.91 39.08,77.9 45.07,77.9 45.28,77.69 45.28,76.23 45.14,76.09 43.72,76.09 43.65,76.16 43.65,76.77 43.4,77.03 40.27,77.03 39.57,76.32 34.35,76.32 34,75.98 34,74.5 33.88,74.37 30.28,74.37 29.99,74.65 29.9,75.21 29.44,74.89 28.5,74.89 28.3,75.09 28.3,77.25 28.22,77.33 27.07,77.33 26.88,77.52 26.88,79.05 26.98,79.16 33.39,79.16
+DC_IN on BOTTOM (solid shape): 50.32,34.96 50.32,34.53 50.69,34.16 53.5,34.16 53.52,34.13 53.52,32.44 53.43,32.36 52.74,32.36 52.68,32.41 52.68,33.17 52.35,33.5 50.12,33.5 49.9,33.71 48.33,33.71 47.45,34.59 46.73,34.59 46.56,34.76 46.56,35.67 46.64,35.75 49.54,35.75
+DC_IN on IN2 (solid shape): 35.62,74.47 35.62,72.55 34.83,71.77 32.16,71.77 30.57,73.36 30.57,74.25 32.54,76.21 33.88,76.21
+DC_IN on IN2 (solid shape): outline of 2308 points within 21.13,28.72 48.24,57.43
+DCIN on TOP (solid shape): 48.16,34.3 48.16,32.65 48.65,32.17 48.94,32.17 48.99,32.12 48.99,31.32 48.92,31.26 48.07,31.26 46.89,32.43 46.89,32.95 46.38,33.46 46.38,34.3 46.45,34.37 48.1,34.37
+DCIN_JACK on TOP (solid shape): 25.24,77.11 28.01,77.11 28.07,77.05 28.07,74.09 27.84,73.86 25.62,73.86 25.49,73.99 25.49,74.5 24.74,75.25 23.11,75.25 22.67,75.69 22.67,77.25 23.2,77.79 24.56,77.79
+DCIN_JACK on BOTTOM (solid shape): 29.19,78.04 29.19,75.02 28.8,74.63 25.34,74.63 24.94,75.03 24.94,76.79 25.49,77.35 25.49,77.87 25.84,78.22 29.01,78.22
+DP_PWR on BOTTOM (solid shape): 25.63,67.14 25.63,66.15 25.45,65.97 24.4,65.97 23.84,65.41 23.84,63.08 23.32,62.56 21.79,62.56 21.52,62.82 21.52,63.74 21.42,63.83 20.63,63.83 20.13,63.33 14.81,63.33 14.37,62.89 13.91,62.89 13.71,63.09 13.71,64.51 14.53,65.33 21.04,65.33 21.32,65.62 22.08,65.62 22.08,65.57 22.09,65.51 22.1,65.47 22.13,65.42 22.16,65.38 22.19,65.34 22.24,65.31 22.28,65.29 22.33,65.27 22.38,65.26 22.43,65.26 22.49,65.27 22.53,65.29 22.58,65.31 22.62,65.34 22.66,65.38 22.69,65.42 22.71,65.47 22.73,65.51 22.74,65.57 22.74,65.62 22.73,65.67 22.71,65.72 22.69,65.76 22.66,65.81 22.62,65.84 22.58,65.87 22.53,65.9 22.49,65.91 22.43,65.92 22.38,65.92 22.33,65.91 22.28,65.9 22.24,65.87 22.19,65.84 22.16,65.81 22.13,65.76 22.1,65.72 22.09,65.67 22.08,65.62 21.32,65.62 23.1,67.39 25.38,67.39
+INV_PWR_SRC on TOP (solid shape): 191.41,39.68 191.48,39.65 191.51,39.58 191.84,39.24 192.17,39.58 192.2,39.65 192.27,39.68 193.35,39.68 193.62,39.42 193.62,38.5 193.43,38.31 192.19,38.31 191.94,38.43 191.69,38.31 188.96,38.31 188.71,38.55 188.71,39.49 188.9,39.68
+INV_PWR_SRC on BOTTOM (solid shape): 192.32,29.26 192.32,26.72 192.54,26.5 193.53,26.5 193.53,26.49 193.74,26.49 193.83,26.4 193.83,24.84 193.73,24.74 192.37,24.74 191.59,25.91 190.45,26.73 190.45,29.23 190.56,29.33 192.24,29.33
+INV_PWR_SRC on BOTTOM (solid shape): 186.5,43.78 190.88,43.78 191.16,43.49 191.16,42.05 190.91,41.8 190.85,41.73 190.34,41.73 190.02,41.42 190.02,38.83 189.7,38.5 187.58,38.5 186.27,39.81 186.27,41.42 184.98,42.71 185.93,42.71 185.93,42.66 185.94,42.61 185.95,42.56 185.98,42.52 186.01,42.47 186.04,42.44 186.09,42.41 186.13,42.38 186.18,42.37 186.23,42.36 186.29,42.36 186.34,42.37 186.39,42.38 186.43,42.41 186.48,42.44 186.51,42.47 186.54,42.52 186.57,42.56 186.58,42.61 186.59,42.66 186.59,42.71 186.58,42.77 186.57,42.82 186.54,42.86 186.51,42.9 186.48,42.94 186.43,42.97 186.39,42.99 186.34,43.01 186.29,43.02 186.23,43.02 186.18,43.01 186.13,42.99 186.09,42.97 186.04,42.94 186.01,42.9 185.98,42.86 185.95,42.82 185.94,42.77 185.93,42.71 184.98,42.71 184.88,42.81 184.88,43.83 185.07,44.02 186.26,44.02
+INV_PWR_SRC on IN2 (solid shape): outline of 454 points within 188.71,27.54 192.94,40.11
+INV_PWR_SRC on IN3 (solid shape): outline of 877 points within 187.7,27.17 192.6,39.82
+LCDVDD on TOP (solid shape): 202.15,30.3 202.15,29.48 202.02,29.35 201.52,29.35 201.32,29.16 201.32,28.53 201.26,28.46 200.86,28.46 200.76,28.56 199.06,28.56 198.96,28.66 198.96,30.11 199.22,30.37 202.09,30.37
+LCDVDD on TOP (solid shape): 194.19,36.2 194.19,36.18 194.22,36.04 194.28,35.91 194.25,35.85 194.22,35.79 193.8,35.39 194.36,35.24 194.65,35.11 194.96,35.18 195,35.13 197.36,35.13 197.51,35.28 197.79,35.28 198.03,35.04 198.37,34.89 198.71,35.01 198.73,35.02 198.75,35.02 198.75,35.04 198.77,35.06 198.85,35.1 198.92,35.06 198.95,35.04 198.95,35.02 198.97,35.02 198.98,35.01 199.16,34.91 199.36,34.89 199.44,34.87 199.47,34.79 199.47,33.6 199.13,33.26 196.34,33.26 196.33,33.29 196.02,33.5 195.71,33.29 195.7,33.26 195.49,33.26 195.23,33.52 193.07,33.52 192.96,33.63 192.96,35.26 192.79,35.42 192.79,36.46 192.9,36.58 193.82,36.58
+LCDVDD on BOTTOM (solid shape): 193.88,35.2 193.94,35.2 193.95,35.19 194.12,35.14 194.3,35.19 194.31,35.2 194.41,35.2 194.43,35.19 194.55,35.13 194.68,35.11 194.69,35.11 194.86,34.94 194.86,33.99 194.62,33.75 192.52,33.75 192.41,33.86 192.41,35.39 192.52,35.5 193.58,35.5
+PBATT on BOTTOM (solid shape): 74.39,34.41 74.39,33.09 73.74,32.45 73.74,31.84 73.6,31.7 72.94,31.7 72.52,31.27 69.69,31.27 69.69,34.56 69.71,34.58 74.22,34.58
+PCH_VCCDSW on TOP (solid shape): outline of 435 points within 139.01,51.07 141.25,57.37
+PWR_SRC_AC on TOP (solid shape): 61.56,40.84 61.56,39.45 61.37,39.26 59.4,39.26 59.08,39.57 59.08,40.97 59.21,41.1 61.31,41.1
+PWR_SRC_AC on BOTTOM (solid shape): 61.69,41.23 61.69,39.38 61.31,39 59.59,39 59.05,39.54 57.02,39.54 56.99,39.57 56.99,40.08 58.51,40.08 58.77,40.34 58.77,40.59 58.51,40.84 56.99,40.84 56.99,41.42 57.05,41.48 61.43,41.48
+SDC_IN on BOTTOM (solid shape): 55.97,41.35 55.97,40.84 54.39,40.84 54.2,40.65 54.2,40.27 54.39,40.08 55.97,40.08 55.97,39.57 54.83,39.57 54.51,39.26 54.51,36.77 54.17,36.43 51.78,36.43 51.74,36.47 51.74,37.3 52.19,37.74 52.19,41.25 52.36,41.42 55.91,41.42
+VCHGR on TOP (solid shape): 73.62,38.37 73.62,30.84 73.14,30.36 70.73,30.36 70.26,29.89 67.49,29.89 67.23,30.16 67.23,34.99 71.46,34.99 71.46,34.93 71.46,34.88 71.48,34.83 71.5,34.79 71.53,34.74 71.57,34.71 71.61,34.68 71.66,34.65 71.71,34.64 71.76,34.63 71.81,34.63 71.86,34.64 71.91,34.65 71.96,34.68 72,34.71 72.04,34.74 72.07,34.79 72.09,34.83 72.11,34.88 72.12,34.93 72.12,34.99 72.11,35.04 72.09,35.09 72.07,35.13 72.04,35.17 72,35.21 71.96,35.24 71.91,35.27 71.86,35.28 71.81,35.29 71.76,35.29 71.71,35.28 71.66,35.27 71.61,35.24 71.57,35.21 71.53,35.17 71.5,35.13 71.48,35.09 71.46,35.04 71.46,34.99 67.23,34.99 67.23,36.56 67.37,36.7 69.28,36.7 69.67,37.08 69.67,37.88 71.19,37.88 71.45,38.14 71.45,38.39 71.19,38.65 69.67,38.65 69.67,39.17 72.82,39.17
+VCHGR on BOTTOM (solid shape): 74.41,41.15 74.41,40.21 74.35,40.15 73.09,40.15 72.99,40.05 72.99,39.73 72.99,39.32 72.99,35.67 72.64,35.31 69.77,35.31 69.5,35.58 69.5,41.14 69.52,41.16 74.4,41.16
+VS_LPSS_SDIO on TOP (solid shape): outline of 299 points within 146.11,62.04 153.8,64.61
-DCIN_JACK on TOP (solid shape): 27.27,73.48 27.27,72.38 26.82,71.92 25.68,71.92 25.49,72.11 25.49,73.48 25.62,73.61 27.14,73.61
-DCIN_JACK on BOTTOM (solid shape): 29.43,72.59 29.43,69.42 29.18,69.17 26.83,69.17 26.25,69.75 26.17,70.08 25.84,70.16 24.85,71.14 24.85,72.79 25.04,72.98 29.05,72.98
AUDIO_VREF on TOP (solid shape): 28.99,24.78 28.99,24.02 28.7,23.73 28.06,23.73 27.78,23.45 25.94,23.45 25.68,23.19 25.05,23.19 25.05,24.08 25.11,24.14 27.33,24.14 27.53,24.33 28.48,24.33 28.67,24.53 28.67,24.78 28.73,24.84 28.92,24.84
B+ on TOP (solid shape): 187.75,48.18 187.75,46.76 187.67,46.68 185.03,46.68 184.87,46.85 184.87,48.32 184.97,48.43 187.51,48.43
B+ on TOP (solid shape): 196.63,61.85 196.63,60.21 195.93,59.51 195.1,59.51 194.54,60.08 194.54,60.64 194.1,61.08 194.1,61.93 194.23,62.06 196.41,62.06
B+ on TOP (solid shape): 71.01,55.87 71.01,54.45 70.87,54.32 68.32,54.32 68.28,54.35 68.28,55.4 68.85,55.97 70.91,55.97
B+ on TOP (solid shape): 36.65,67.6 36.65,67.35 37.03,66.98 37.03,65.71 36.97,65.65 36.02,65.65 35.95,65.72 35.95,66.58 35.91,66.62 35.91,67.8 35.96,67.85 36.4,67.85
B+ on TOP (solid shape): outline of 1476 points within 63.73,37.27 94.33,56.16
B+ on BOTTOM (solid shape): 94.17,53.44 94.17,50.52 93.79,50.14 90.35,50.14 90.18,50.31 90.18,53.12 90.17,53.12 90.17,53.5 90.37,53.7 93.92,53.7
B+ on BOTTOM (solid shape): 68.99,42.95 68.99,30.81 68.61,30.43 65.69,30.43 65.31,30.81 65.31,35 66.13,35.83 66.13,40.81 65.85,41.09 62.96,41.09 62.64,41.41 62.64,43.02 62.82,43.2 68.74,43.2
B+ on BOTTOM (solid shape): 71.63,55.77 71.63,54.53 71.35,54.26 71.35,54.24 71.23,54.12 71.23,53.84 71.14,53.75 69.18,53.75 69.05,53.87 69.05,54.24 68.93,54.37 68.29,54.37 68.23,54.43 68.23,55.32 68.4,55.49 69.66,55.49 70.11,55.95 71.45,55.95
B+ on BOTTOM (solid shape): outline of 106 points within 184.68,44.35 189.85,48.75
B+ on IN1 (solid shape): 53.54,70.39 53.54,69.69 53.33,69.48 52.89,69.48 51.87,70.49 51.87,70.62 52,70.75 53.18,70.75
B+ on IN1 (solid shape): outline of 152 points within 169.12,14.26 176.52,19.38
B+ on IN1 (solid shape): outline of 3042 points within 63.97,36.72 93.55,56.87
B+ on IN2 (solid shape): 53.31,70.46 53.31,70.02 52.73,69.44 51.32,69.44 51.32,70.28 51.67,70.63 53.14,70.63
B+ on IN2 (solid shape): 37.57,67.88 37.57,67.08 36.98,66.5 36.01,66.5 35.84,66.66 35.84,66.84 37,68 37.44,68
B+ on IN1: 181.08,40.34 181.08,42.46 183.66,45.04 183.66,46.52 183.96,46.81 183.96,47.54 184.29,47.88 184.74,47.88 184.99,48.13 186.12,48.13 186.45,47.8 186.45,42.48 185.2,41.22 185.2,40.63 185.14,40.54 185.03,40.55 184.62,40.54 184.59,40.13 184.61,40.07 184.59,40.01 184.52,39.82 184.59,39.62 184.61,39.56 184.58,39.51 184.57,39.04 185.04,39.02 185.14,39.03 185.2,38.94 185.2,37.46 184.93,37.19 180.36,37.19 180.08,37.47 180.08,39.34
B+_1.05V on TOP (solid shape): 198.98,64.92 198.98,63.07 198.72,62.82 197.05,62.82 196.92,62.68 195.6,62.68 195.48,62.8 195.48,63.69 195.53,63.75 196.53,63.75 197.74,64.97 198.93,64.97
B+_1.05V on BOTTOM (solid shape): 201.13,64.47 201.13,63.51 199.04,63.51 198.59,63.07 198.59,62.94 198.47,62.82 196.94,62.82 196.88,62.88 196.88,64.91 197.13,65.17 200.44,65.17
BOOT_1.35V on BOTTOM (solid shape): 77.94,49.54 77.94,48.59 77.35,48 76.62,48 75.96,48.66 74.54,48.66 74.48,48.72 74.48,48.86 74.53,48.91 76.8,48.91 76.99,49.1 76.99,49.54 77.06,49.61 77.88,49.61
BST_1.35V on BOTTOM (solid shape): 77.88,52.47 77.88,50.31 76.99,50.31 76.93,50.37 76.93,52.4 77.06,52.53 77.82,52.53
BST_3V on BOTTOM (solid shape): 60.35,58.82 60.35,58.24 60.04,57.93 60.04,57.04 59.91,56.91 59.91,55.89 59.85,55.83 59.72,55.83 59.66,55.89 59.66,57.93 59.34,58.24 59.34,58.75 59.47,58.88 60.29,58.88
BST_5V on BOTTOM (solid shape): 59.91,53.8 59.91,52.85 60.16,52.59 60.16,52.02 60.48,51.7 60.86,51.7 60.99,51.58 60.99,50.94 60.86,50.81 59.97,50.81 59.91,50.88 59.91,51.45 59.72,51.64 59.72,52.72 59.66,52.78 59.66,53.8 59.72,53.86 59.85,53.86
CHAGER_SRC on TOP (solid shape): 58.32,40.91 58.32,39.57 59.28,38.62 62.52,38.62 62.83,38.3 62.83,34.3 62.51,33.99 58.39,33.99 57.62,33.22 56.86,33.22 56.8,33.29 56.8,33.99 56.54,34.24 56.54,39.7 56.19,40.05 56.19,40.92 56.31,41.04 58.2,41.04
CHAGER_SRC on BOTTOM (solid shape): 58.26,38.94 58.26,34.3 58.01,34.05 56.67,34.05 56.61,34.11 56.61,39.13 56.67,39.19 58.01,39.19
CHG_BTS on TOP (solid shape): 50.51,34.37 50.51,33.22 50.19,32.91 50.19,31.32 50.13,31.26 50,31.26 49.94,31.32 49.94,33.61 49.81,33.73 49.62,33.73 49.56,33.8 49.56,34.37 49.62,34.43 50.45,34.43
CHG_LGATE on TOP (solid shape): 59.4,30.56 59.4,29.73 59.28,29.61 58.39,29.61 58.26,29.73 58.26,30.56 58.39,30.68 59.28,30.68
CHG_LGATE on TOP (solid shape): 51.78,33.22 51.78,33.03 51.02,32.27 51.02,31.32 50.96,31.26 50.83,31.26 50.77,31.32 50.77,32.84 51.34,33.42 51.59,33.42
CHG_LGATE on IN1 (solid shape): 52.8,33.67 52.8,32.91 52.67,32.78 51.59,32.78 51.21,32.4 50.89,32.4 50.77,32.53 50.77,32.84 51.72,33.8 52.67,33.8
CHG_LGATE on IN1 (solid shape): 58.2,30.3 59.21,30.3 59.4,30.11 59.4,29.73 59.28,29.61 57.5,29.61 57.37,29.73 57.37,30.49 57.5,30.62 57.88,30.62
CHG_SW on TOP (solid shape): 49.31,34.37 49.31,33.73 49.05,33.48 49.05,32.68 49.39,32.34 49.39,31.35 49.33,31.28 49.22,31.28 49.18,31.32 49.18,32.15 48.92,32.4 48.67,32.4 48.42,32.65 48.42,34.37 48.48,34.43 49.24,34.43
CHG_SW on TOP (solid shape): 65.58,36.82 65.58,29.62 65.26,29.29 62.29,29.29 62.13,29.14 62.13,27.7 62.01,27.57 60.99,27.57 60.93,27.64 60.93,29.86 60.61,30.18 59.97,30.18 59.85,30.3 59.85,33.29 60.1,33.54 62.71,33.54 63.28,34.11 63.28,37.03 63.53,37.29 65.12,37.29
CHG_SW on BOTTOM (solid shape): 64.46,34.46 64.46,29.53 64.31,29.38 60.31,29.38 60.03,29.66 60.03,34.39 60.19,34.55 64.37,34.55
CHG_SW on IN1 (solid shape): 49.05,34.56 49.05,32.59 48.92,32.46 48.61,32.46 48.48,32.59 48.48,33.48 48.04,33.92 48.04,34.41 48.32,34.69 48.92,34.69
CHG_SW on IN1 (solid shape): 62.47,33.15 63.05,33.15 63.18,33.02 63.18,32.14 63.02,31.97 62.21,31.97 61.38,32.8 61.38,33.23 61.69,33.54 62.08,33.54
CHG_UGATE on TOP (solid shape): 49.81,33.48 49.81,31.32 49.75,31.26 49.62,31.26 49.56,31.32 49.56,32.34 49.24,32.65 49.24,33.48 49.37,33.61 49.69,33.61
CHG_UGATE on TOP (solid shape): 64.86,38.41 64.86,37.99 64.67,37.8 63.78,37.8 63.03,38.55 63.03,38.95 63.24,39.15 64.11,39.15
CHG_UGATE on IN4 (solid shape): 50.32,34.37 50.32,33.99 50,33.67 50,32.65 49.81,32.46 49.43,32.46 49.31,32.59 49.31,34.37 49.43,34.49 50.19,34.49
CHG_UGATE on IN4 (solid shape): 64.25,39.02 64.25,38.15 63.54,37.45 63.06,37.45 62.83,37.68 62.83,39 62.96,39.13 64.14,39.13
CPU_B+ on TOP (solid shape): 88.61,56.73 88.61,55.76 89.27,55.1 89.27,54.26 89.39,54.15 90.31,54.15 90.47,54.3 90.47,54.73 90.58,54.85 91.13,54.85 91.25,54.72 91.25,54.03 91.15,53.93 88.1,53.93 87,55.03 87,56.6 87.18,56.78 88.56,56.78
CPU_B+ on BOTTOM (solid shape): 88.49,57.04 88.68,56.85 88.68,55.77 88.68,55.76 88.68,55.71 89.45,54.94 90.26,54.94 90.33,54.88 90.33,54.37 89.64,53.68 89.54,53.58 89.54,50.46 89.27,50.19 86.71,50.19 86.14,50.76 86.14,55.01 85.31,55.83 83.53,55.83 83.21,56.15 83.21,59.58 83.66,60.02 88.49,60.02
DH_1.35V on TOP (solid shape): 83.63,49.21 83.63,48.21 83.45,48.04 82.55,48.04 82.42,48.17 82.42,49.02 82.67,49.27 83.56,49.27
DH_1.35V on BOTTOM (solid shape): 76.86,49.42 76.86,49.16 76.74,49.04 74.59,49.04 74.48,49.14 74.48,49.24 74.53,49.29 75.59,49.29 75.85,49.54 76.74,49.54
DH_1.35V on IN2 (solid shape): 77.82,48.91 77.69,48.78 75.91,48.78 75.72,48.97 75.72,49.42 75.85,49.54 77.82,49.54
DH_1.35V on IN2 (solid shape): 83.6,48.91 83.6,48.21 83.47,48.08 82.52,48.08 82.14,48.46 81.88,48.46 81.82,48.53 81.82,49.16 81.88,49.23 83.28,49.23
DL_1.35V on TOP (solid shape): 79.28,52.34 79.72,52.34 79.91,52.15 79.91,51.45 79.79,51.32 78.9,51.32 78.77,51.45 78.77,52.4 78.83,52.47 79.15,52.47
DL_1.35V on BOTTOM (solid shape): 75.21,51.39 75.21,50.61 74.36,49.76 74.24,49.76 74.2,49.8 74.2,50.73 74.64,51.17 74.64,51.45 74.77,51.58 75.02,51.58
DL_1.35V on IN2 (solid shape): 79.28,52.27 79.28,51.45 79.15,51.32 78.83,51.32 78.45,51.7 75.79,51.7 75.15,51.07 75.15,50.56 75.02,50.43 74.77,50.43 74.64,50.56 74.64,51.64 75.47,52.47 79.09,52.47
JACK_PLUG_DL on TOP (solid shape): 22.19,33.83 22.19,33.12 22.05,32.98 20.76,32.98 19.45,31.68 19.45,30.37 19.13,30.05 18.66,30.05 18.07,29.46 17.42,29.46 17.31,29.57 17.31,30.51 17.32,30.51 17.32,31.07 17.3,31.08 17.3,32.12 18.21,33.03 19.21,33.03 20.17,33.99 22.03,33.99
LG_3V on BOTTOM (solid shape): 65.37,59.77 65.37,59.26 65.24,59.13 64.42,59.13 64.29,59.26 64.29,60.15 64.42,60.28 64.86,60.28
LG_3V on BOTTOM (solid shape): 62.32,56.97 62.32,56.53 61.31,55.51 60.42,55.51 60.35,55.58 60.35,55.7 61.82,57.16 62.13,57.16
LG_3V on IN3 (solid shape): 62.32,58.12 62.32,56.72 61.69,56.08 61.43,56.08 61.18,56.34 61.18,57.99 61.69,58.5 61.94,58.5
LG_3V on IN3 (solid shape): 64.86,60.15 64.86,59.26 64.74,59.13 63.47,59.13 63.09,59.51 63.09,59.89 63.47,60.28 64.74,60.28
LG_5V on BOTTOM (solid shape): 68.8,50.43 68.8,48.43 68.71,48.34 68.39,48.34 68.29,48.44 68.29,50.43 68.36,50.5 68.74,50.5
